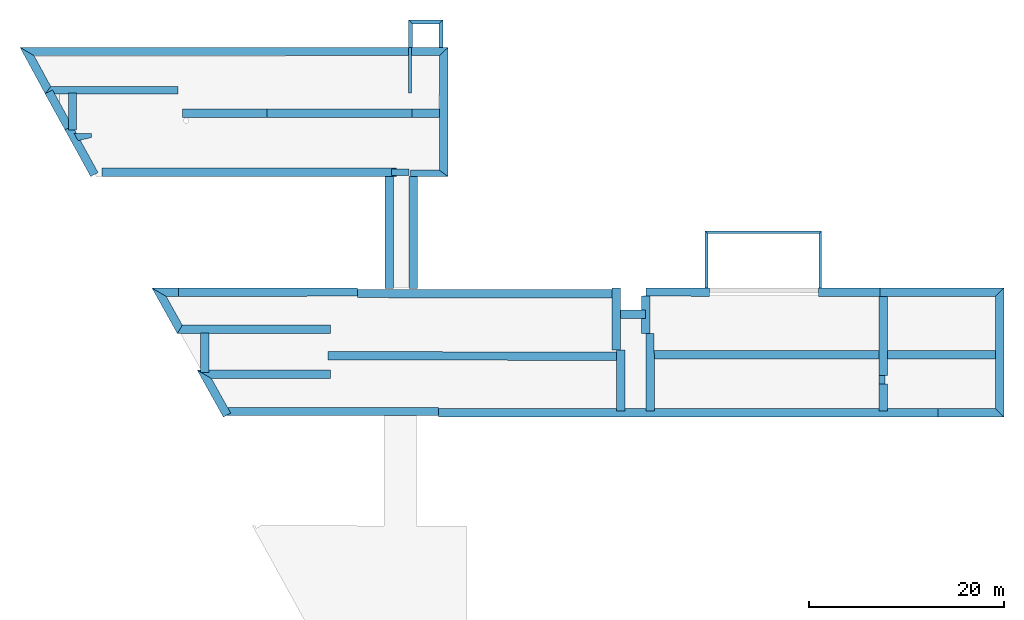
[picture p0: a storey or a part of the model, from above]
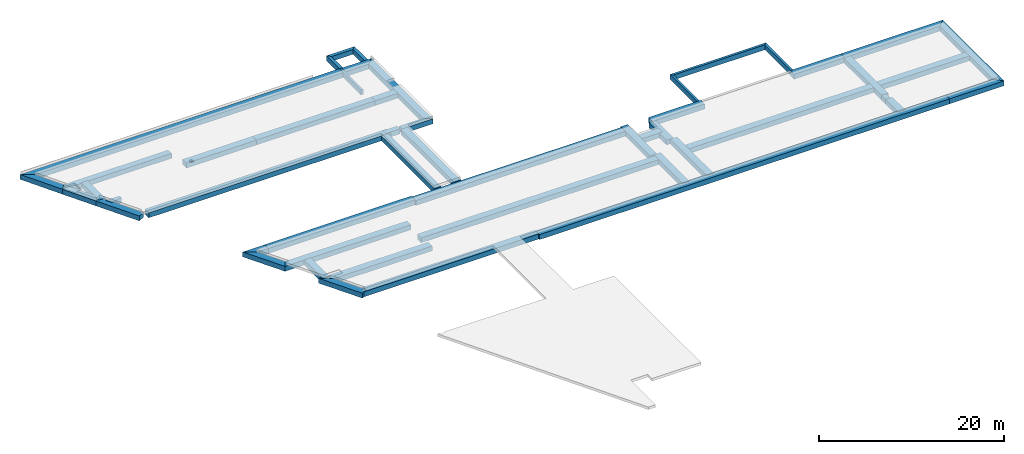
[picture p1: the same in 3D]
Properties of the parts of a building model (IFC2X3), part 1 of 14

# File
Description: ViewDefinition [CoordinationView_V2.0], Option [Drawing Scale: 100.000000], Option [Global Unique Identifiers (GUID): Keep existing], Option [Elements to export: Visible elements (on all stories)], Option [Partial Structure Display: Entire Model], Option [IFC Domain: All], Option [Structural Function: All Elements], Option [Convert Grid elements: On], Option [Convert IFC Annotations and ARCHICAD 2D elements: Off], Option [Convert 2D symbols of Doors and Windows: Off], Option [Explode Composite and Complex Profile elements into parts: On], Option [Export geometries that Participates in Collision Detection only: Off], Option [Elements in Solid Element Operations: Extruded/revolved], Option [Elements with junctions: Extruded/revolved without junctions], Option [Slabs with slanted edge(s): Extruded], Option [Use legacy geometric methods as in Coordination View 1.0: Off], Option [IFC Site Geometry: As boundary representation (BRep)], Option [IFC Site Location: At Project Origin], Option [Curtain Wall export mode: Container Element], Option [Railing export mode: Single Element], Option [Stair export mode: Container Element], Option [Properties To Export: All properties], Option [Space containment: Off], Option [Bounding Box: Off], Option [Geometry to type objects: Off], Option [Element Properties: Off], Option [Building Material Properties: Off], Option [Element Parameters: Off], Option [Component Parameters: Off], Option [IFC Base Quantities: Off], Option [Door Window Parameters: On], Option [IFC Space boundaries: Off], Option [ARCHICAD Zone Categories as IFC Space classification data: Off], Option [Element Classifications: Off]
File name: G:\Shared drives\Projektibüroo\Irina\Teaduse 2\Teaduse 2 Alice, Jane, Irina\EMAFAIL\ifc\AR_Teaduse2_PP_2020-01-23_AP.ifc
Time: 2020-01-24T13:08:55
Author: Architect
Organization: Building Designer Office
Written by: The EXPRESS Data Manager Version 5.02.0100.09 : 26 Sep 2013
Made in: IFC file generated by GRAPHISOFT ARCHICAD-64 22.0.0 INT FULL Windows version (IFC add-on version: 6021 INT FULL).
Authorization: The authorising person

# IfcSite, Site
RefLatitude: 47, 33, 34, 948800; RefLongitude: 19, 3, 17, 204400; RefElevation: 0 mm

# IfcBuildingStorey (4)
In: Building
Name | Elevation (mm)
VUNDAMENT | -1000
1 KORRUS | 0
2 KORRUS | 3000
KATUSEPLAAN | 6000 | Description: talveaia rõdu

# IfcSpace: TEHNOPIND (10)
Type - ElementType: Element type TEHNILINE RUUM
InteriorOrExteriorSpace: INTERNAL; Classification: 1.15 IfcSpace (ruum) (_RKAS BIM + ARCHICAD Classification)
Pset_SpaceCommon - Category: TEHNOPIND
RUUMID - 3 Kategooria: TEHNOPIND
AC_Pset_RenovationAndPhasing - Renovation Status: Existing
Name | In | LongName = 1 Nimetus | 2 Number | 4 Ruumi pindala | 5 Ruumi kõrgus
B 109 | 1 KORRUS | SOOJASÕLM | B 109 | 33,69 Kasulik pindala: 33,69 | 2 600
B 124 | 1 KORRUS | TEHNILINE RUUM | B 124 | 21,63 Kasulik pindala: 21,63 | 2 600
A 103 | 1 KORRUS | SERVERIRUUM | A 103 | 9,76 Kasulik pindala: 9,76 | 2 600
A 115 | 1 KORRUS | TEHNILINE RUUM | A 115 | 17,16 Kasulik pindala: 17,16 | 2 600
A 112 | 1 KORRUS | ELEKTRIKILBIRUUM | A 112 | 10,49 Kasulik pindala: 10,49 | 2 600
B 114 | 1 KORRUS | ELEKTRIKILBI RUUM | B 114 | 15,64 Kasulik pindala: 15,64 | 2 600
B 115 | 1 KORRUS | TEHNILINE RUUM | B 115 | 20,53 Kasulik pindala: 20,53 | 2 600
B 220B | 2 KORRUS | SERVERIRUUM | B 220B | 8,12 Kasulik pindala: 8,12 | 2 480
C 210 | 2 KORRUS | TEHNILINE RUUM | C 210 | 16,56 Kasulik pindala: 16,56 | 3 250
B 220A | 2 KORRUS | TEHNILINE RUUM | B 220A | 7,12 Kasulik pindala: 7,12 | 2 480

# IfcSpace: ÜLDKASUT.P, B 127
In: 1 KORRUS
Type - ElementType: Element type TEHNILINE RUUM
LongName: ABIRUUM; InteriorOrExteriorSpace: INTERNAL; Classification: 1.15 IfcSpace (ruum) (_RKAS BIM + ARCHICAD Classification)
Pset_SpaceCommon - Category: ÜLDKASUT.P
RUUMID - 1 Nimetus: ABIRUUM; 2 Number: B 127; 3 Kategooria: ÜLDKASUT.P; 4 Ruumi pindala: 7,08 Kasulik pindala: 7,08; 5 Ruumi kõrgus: 2 600
AC_Pset_RenovationAndPhasing - Renovation Status: Existing

# IfcSpace: ÜLDKASUT.P (17)
In: 1 KORRUS
Type - ElementType: Element type ÜLDKASUTATAV PIND
InteriorOrExteriorSpace: INTERNAL; Classification: 1.15 IfcSpace (ruum) (_RKAS BIM + ARCHICAD Classification)
Pset_SpaceCommon - Category: ÜLDKASUT.P
RUUMID - 3 Kategooria: ÜLDKASUT.P; 5 Ruumi kõrgus: 2 600
AC_Pset_RenovationAndPhasing - Renovation Status: Existing
Name | LongName = 1 Nimetus | 2 Number | 4 Ruumi pindala
B 134 | KONTOR | B 134 | 10,28 Kasulik pindala: 10,28
B 131 B | ABIRUUM | B 131 B | 8,30 Kasulik pindala: 8,30
B 130 | DOKUMENDI HOIDLA | B 130 | 20,70 Kasulik pindala: 20,70
B 131 | ABIRUUM | B 131 | 81,94 Kasulik pindala: 81,94
B 137 | KORIDOR | B 137 | 51,83 Kasulik pindala: 51,83
B 136 | KONTOR | B 136 | 31,18 Kasulik pindala: 31,16
B 125 A | HOIURUUM | B 125 A | 2,96 Kasulik pindala: 2,96
B 125 | ABIRUUM | B 125 | 17,33 Kasulik pindala: 17,33
B 128 | ABIRUUM | B 128 | 13,31 Kasulik pindala: 13,31
B 135 | TUULEKODA | B 135 | 17,22 Kasulik pindala: 17,22
B 129 | KORIDOR | B 129 | 7,62 Kasulik pindala: 7,62
B 132 | KONTOR | B 132 | 21,03 Kasulik pindala: 21,03
B 131 A | ABIRUUM | B 131 A | 7,00 Kasulik pindala: 7,00
B 126 A | WC | B 126 A | 2,78 Kasulik pindala: 2,05
B 126 B | PESURUUM | B 126 B | 1,95 Kasulik pindala: 1,54
B 126 | EESRUUM | B 126 | 5,29 Kasulik pindala: 5,29
B 133 | DOKUMENDI HOIDLA | B 133 | 16,16 Kasulik pindala: 16,16

# IfcSpace: ÜLDKASUT.P. PÕLLUMANDUSAMET (97)
Type - ElementType: Element type ÜLDKASUTATAV PIND
InteriorOrExteriorSpace: INTERNAL; Classification: 1.15 IfcSpace (ruum) (_RKAS BIM + ARCHICAD Classification)
Pset_SpaceCommon - Category: ÜLDKASUT.P. PÕLLUMANDUSAMET
RUUMID - 3 Kategooria: ÜLDKASUT.P. PÕLLUMANDUSAMET
AC_Pset_RenovationAndPhasing - Renovation Status: Existing
Name | In | LongName = 1 Nimetus | 2 Number | 4 Ruumi pindala | 5 Ruumi kõrgus
B 122 | 1 KORRUS | TREPIKODA | B 122 | 9,22 Kasulik pindala: 9,22 | 2 600
B 121 | 1 KORRUS | SÖÖGITUBA | B 121 | 30,12 Kasulik pindala: 30,12 | 2 600
A 111 | 1 KORRUS | DOKUMENDI HOIDLA | A 111 | 42,20 Kasulik pindala: 42,20 | 2 150
A 117 | 1 KORRUS | KORIDOR | A 117 | 10,09 Kasulik pindala: 10,09 | 2 150
A 116 | 1 KORRUS | DOKUMENDI HOIDLA | A 116 | 21,51 Kasulik pindala: 21,51 | 2 150
B 120 B | 1 KORRUS | ABIRUUM | B 120 B | 3,78 Kasulik pindala: 3,78 | 2 600
B 104 A | 1 KORRUS | WC | B 104 A | 1,36 Kasulik pindala: 1,36 | 2 600
B 106 | 1 KORRUS | DOKUMENDI HOIDLA | B 106 | 9,84 Kasulik pindala: 9,84 | 2 600
B 108 | 1 KORRUS | KABINET | B 108 | 21,66 Kasulik pindala: 21,66 | 2 600
B 103 | 1 KORRUS | ABIRUUM | B 103 | 15,57 Kasulik pindala: 15,57 | 2 600
B 107 A | 1 KORRUS | TUULEKODA | B 107 A | 5,19 Kasulik pindala: 5,19 | 2 600
B 105 | 1 KORRUS | WC | B 105 | 5,30 Kasulik pindala: 5,30 | 2 600
B 102 | 1 KORRUS | KABINET | B 102 | 9,67 Kasulik pindala: 9,67 | 2 600
B 113 | 1 KORRUS | DOKUMENDIHOIDLA | B 113 | 15,71 Kasulik pindala: 15,71 | 2 600
B 112 | 1 KORRUS | ABIRUUM | B 112 | 16,44 Kasulik pindala: 16,44 | 2 600
B 117 | 1 KORRUS | ABIRUUM | B 117 | 15,69 Kasulik pindala: 15,69 | 2 600
B 118 | 1 KORRUS | ABIRUUM | B 118 | 15,68 Kasulik pindala: 15,68 | 2 600
B 120 A | 1 KORRUS | DOKUMENDI HOIDLA | B 120 A | 9,08 Kasulik pindala: 9,08 | 2 600
B 120 C | 1 KORRUS | ABIRUUM | B 120 C | 4,97 Kasulik pindala: 4,97 | 2 600
B 116 | 1 KORRUS | DOKUMENDI HOIDLA | B 116 | 10,21 Kasulik pindala: 10,21 | 2 600
B 119 | 1 KORRUS | DOKUMENDI HOIDLA | B 119 | 10,04 Kasulik pindala: 10,04 | 2 600
B 123 | 1 KORRUS | DOKUMENDI HOIDLA | B 123 | 26,10 Kasulik pindala: 26,10 | 2 600
B 104 | 1 KORRUS | WC | B 104 | 4,18 Kasulik pindala: 3,46 | 2 600
B 120 | 1 KORRUS | DOKUMENDI HOIDLA | B 120 | 10,02 Kasulik pindala: 10,02 | 2 600
B 138 | 1 KORRUS | KORIDOR | B 138 | 18,87 Kasulik pindala: 18,87 | 2 150
B 108 | 1 KORRUS | KORIDOR | B 108 | 70,52 Kasulik pindala: 70,52 | 2 600
B 108 A | 1 KORRUS | DOKUMENDI HOIDLA | B 108 A | 19,27 Kasulik pindala: 19,27 | 2 600
B 202 | 2 KORRUS | KABINET | B 202 | 10,94 Kasulik pindala: 10,94 | 2 480
B 219 | 2 KORRUS | KABINET | B 219 | 10,00 Kasulik pindala: 10,00 | 2 480
B 216 | 2 KORRUS | KABINET | B 216 | 18,40 Kasulik pindala: 17,33 | 2 480
B 245 | 2 KORRUS | GARAAZ | B 245 | 67,66 Kasulik pindala: 67,66 | 3 250
B 240 | 2 KORRUS | KABINET | B 240 | 11,86 Kasulik pindala: 11,86 | 2 480
B 241 | 2 KORRUS | KABINET | B 241 | 10,72 Kasulik pindala: 10,72 | 2 480
B 235 | 2 KORRUS | KABINET | B 235 | 15,40 Kasulik pindala: 15,40 | 2 480
A 222 | 2 KORRUS | KABINET | A 222 | 18,00 Kasulik pindala: 18,00 | 2 500
C 206 | 2 KORRUS | SAAL | C 206 | 82,63 Kasulik pindala: 82,63 | 3 250
C 201 | 2 KORRUS | KABINET | C 201 | 10,82 Kasulik pindala: 10,82 | 3 250
C 202 | 2 KORRUS | KABINET | C 202 | 12,87 Kasulik pindala: 12,87 | 3 250
B 231 A | 2 KORRUS | EESRUUM | B 231 A | 5,70 Kasulik pindala: 5,70 | 2 200
B 231 C | 2 KORRUS | WC | B 231 C | 1,20 Kasulik pindala: 1,20 | 2 200
B 223 | 2 KORRUS | KABINET | B 223 | 14,83 Kasulik pindala: 14,83 | 2 480
B 222 | 2 KORRUS | KABINET | B 222 | 15,67 Kasulik pindala: 15,67 | 2 480
B 206 | 2 KORRUS | KABINET | B 206 | 22,80 Kasulik pindala: 22,80 | 2 480
B 207 | 2 KORRUS | KABINET | B 207 | 9,95 Kasulik pindala: 9,95 | 2 480
B 221 | 2 KORRUS | KABINET | B 221 | 20,30 Kasulik pindala: 20,30 | 2 480
B 201 | 2 KORRUS | KABINET | B 201 | 8,94 Kasulik pindala: 8,94 | 2 480
B 203 | 2 KORRUS | KABINET | B 203 | 9,68 Kasulik pindala: 9,68 | 2 480
B 208 | 2 KORRUS | KABINET | B 208 | 9,95 Kasulik pindala: 9,95 | 2 480
B 217 | 2 KORRUS | KABINET | B 217 | 17,99 Kasulik pindala: 17,99 | 2 480
B 211 | 2 KORRUS | KABINET | B 211 | 19,43 Kasulik pindala: 19,43 | 2 480
B 224 | 2 KORRUS | KABINET | B 224 | 14,60 Kasulik pindala: 14,60 | 2 480
B 215 | 2 KORRUS | KABINET | B 215 | 11,14 Kasulik pindala: 11,14 | 2 480
B 236 | 2 KORRUS | KABINET | B 236 | 15,41 Kasulik pindala: 15,41 | 2 480
A 207 | 2 KORRUS | KORIDOR | A 207 | 50,99 Kasulik pindala: 50,99 | 2 300
B 205 | 2 KORRUS | KABINET | B 205 | 9,96 Kasulik pindala: 9,96 | 2 480
A 211 | 2 KORRUS | KABINET | A 211 | 15,58 Kasulik pindala: 15,58 | 2 500
A 217 | 2 KORRUS | KABINET | A 217 | 15,59 Kasulik pindala: 15,59 | 2 500
A 215 | 2 KORRUS | KABINET | A 215 | 15,60 Kasulik pindala: 15,60 | 2 500
A 218 | 2 KORRUS | KABINET | A 218 | 10,34 Kasulik pindala: 10,34 | 2 480
C 208 | 2 KORRUS | INVA WC | C 208 | 7,31 Kasulik pindala: 7,31 | 2 400
A 221 | 2 KORRUS | KABINET | A 221 | 20,25 Kasulik pindala: 20,25 | 3 250
A 209 C | 2 KORRUS | KABINET | A 209 C | 16,92 Kasulik pindala: 16,92 | 2 500
A 209 A | 2 KORRUS | EESRUUM | A 209 A | 2,23 Kasulik pindala: 2,23 | 2 500
A 202 | 2 KORRUS | KABINET | A 202 | 9,72 Kasulik pindala: 9,72 | 2 480
A 209 B | 2 KORRUS | KABINET | A 209 B | 9,55 Kasulik pindala: 9,55 | 2 500
A 201 | 2 KORRUS | KABINET | A 201 | 8,98 Kasulik pindala: 8,98 | 2 480
B 212 | 2 KORRUS | KABINET | B 212 | 31,14 Kasulik pindala: 31,14 | 2 480
B 225 | 2 KORRUS | KABINET | B 225 | 10,45 Kasulik pindala: 10,45 | 2 480
B 231 B | 2 KORRUS | WC | B 231 B | 1,21 Kasulik pindala: 1,21 | 2 200
B 232 | 2 KORRUS | PESURUUM | B 232 | 6,54 Kasulik pindala: 6,54 | 2 200
B 204 | 2 KORRUS | KABINET | B 204 | 17,58 Kasulik pindala: 17,58 | 2 480
A 204 | 2 KORRUS | KABINET | A 204 | 27,06 Kasulik pindala: 27,06 | 2 480
A 219 | 2 KORRUS | KABINET | A 219 | 19,11 Kasulik pindala: 19,11 | 2 480
A 203 | 2 KORRUS | KABINET | A 203 | 23,26 Kasulik pindala: 23,26 | 2 480
A 223 | 2 KORRUS | TUULEKODA | A 223 | 3,76 Kasulik pindala: 3,76 | 3 250
A 213 | 2 KORRUS | KABINET | A 213 | 15,59 Kasulik pindala: 15,59 | 2 500
A 216 | 2 KORRUS | KABINET | A 216 | 10,35 Kasulik pindala: 10,35 | 2 480
A 214 | 2 KORRUS | KABINET | A 214 | 10,32 Kasulik pindala: 10,32 | 2 480
A 212 | 2 KORRUS | KABINET | A 212 | 10,33 Kasulik pindala: 10,33 | 2 480
A 210 | 2 KORRUS | KABINET | A 210 | 10,33 Kasulik pindala: 10,33 | 2 480
A 208 | 2 KORRUS | KABINET | A 208 | 10,34 Kasulik pindala: 10,34 | 2 480
A 206 | 2 KORRUS | KABINET | A 206 | 8,97 Kasulik pindala: 8,97 | 2 480
A 205 | 2 KORRUS | KABINET | A 205 | 27,67 Kasulik pindala: 19,98 | 2 480
C 203 | 2 KORRUS | KABINET | C 203 | 12,91 Kasulik pindala: 12,91 | 3 250
B 243 | 2 KORRUS | KABINET | B 243 | 11,86 Kasulik pindala: 11,86 | 2 480
C 204 | 2 KORRUS | KABINET | C 204 | 27,10 Kasulik pindala: 27,10 | 3 250
C 209 | 2 KORRUS | WC | C 209 | 4,99 Kasulik pindala: 4,99 | 2 400
B 218 | 2 KORRUS | NÕUPIDAMISTE RUUM | B 218 | 32,18 Kasulik pindala: 32,18 | 2 480
B 210 | 2 KORRUS | KABINET | B 210 | 15,46 Kasulik pindala: 15,46 | 2 480
A 220 | 2 KORRUS | KABINET | A 220 | 10,52 Kasulik pindala: 10,52 | 2 480
C 207 | 2 KORRUS | EESRUUM | C 207 | 12,78 Kasulik pindala: 12,78 | 2 600
B 246 | 2 KORRUS | ABIRUUM | B 246 | 32,62 Kasulik pindala: 32,62 | 3 250
B 230 | 2 KORRUS | KABINET | B 230 | 31,59 Kasulik pindala: 31,59 | 2 480
C 205 | 2 KORRUS | KABINET | C 205 | 12,18 Kasulik pindala: 12,18 | 3 250
C 200 | 2 KORRUS | KORIDOR | C 200 | 38,18 Kasulik pindala: 38,18 | 3 250
A 200 | 2 KORRUS | FUAJEE/ TREPIKODA | A 200 | 50,56 Kasulik pindala: 50,56 | 3 250
B 229 | 2 KORRUS | SUITSETAMISERUUM | B 229 | 17,80 Kasulik pindala: 17,70 | 4 300

# IfcSpace: ÜLDKASUT.P. PÕLLUMANDUSAMET JA PRIA (2)
In: 1 KORRUS
Type - ElementType: Element type TEHNILINE RUUM
InteriorOrExteriorSpace: INTERNAL; Classification: 1.15 IfcSpace (ruum) (_RKAS BIM + ARCHICAD Classification)
Pset_SpaceCommon - Category: ÜLDKASUT.P. PÕLLUMANDUSAMET JA PRIA
RUUMID - 3 Kategooria: ÜLDKASUT.P. PÕLLUMANDUSAMET JA PRIA; 5 Ruumi kõrgus: 2 600
AC_Pset_RenovationAndPhasing - Renovation Status: Existing
Name | LongName = 1 Nimetus | 2 Number | 4 Ruumi pindala
B 110 | KORISTAJARUUM | B 110 | 10,70 Kasulik pindala: 10,70
B 111 | ABIRUUM | B 111 | 5,56 Kasulik pindala: 5,56

# IfcSpace: ÜLDKASUT.P. PÕLLUMANDUSAMET JA PRIA (10)
In: 1 KORRUS
Type - ElementType: Element type ÜLDKASUTATAV PIND
InteriorOrExteriorSpace: INTERNAL; Classification: 1.15 IfcSpace (ruum) (_RKAS BIM + ARCHICAD Classification)
Pset_SpaceCommon - Category: ÜLDKASUT.P. PÕLLUMANDUSAMET JA PRIA
RUUMID - 3 Kategooria: ÜLDKASUT.P. PÕLLUMANDUSAMET JA PRIA
AC_Pset_RenovationAndPhasing - Renovation Status: Existing
Name | LongName = 1 Nimetus | 2 Number | 4 Ruumi pindala | 5 Ruumi kõrgus
A 104 | WC | A 104 | 5,45 Kasulik pindala: 5,45 | 2 300
A 118 | KORIDOR | A 118 | 38,91 Kasulik pindala: 38,91 | 2 550
A100 | TUULEKODA | A100 | 5,50 Kasulik pindala: 5,50 | 2 200
A 114 | KORIDOR | A 114 | 17,73 Kasulik pindala: 17,73 | 2 600
A 108 A | PESURUUM | A 108 A | 8,91 Kasulik pindala: 8,91 | 2 150
A 108 | PUHKERUUM | A 108 | 42,24 Kasulik pindala: 42,24 | 2 150
A 105 | WC | A 105 | 4,79 Kasulik pindala: 4,79 | 2 300
A 108 C | PESURUUM | A 108 C | 5,65 Kasulik pindala: 5,65 | 2 150
A 108 B | LEILIRUUM | A 108 B | 5,45 Kasulik pindala: 5,45 | 2 300
A 101 | AATRIUM/FUAJEE | A 101 | 40,64 Kasulik pindala: 40,64 | 2 550

# IfcSpace: ÜLDKASUT.P.PRIA (6)
In: 1 KORRUS
Type - ElementType: Element type ÜLDKASUTATAV PIND
InteriorOrExteriorSpace: INTERNAL; Classification: 1.15 IfcSpace (ruum) (_RKAS BIM + ARCHICAD Classification)
Pset_SpaceCommon - Category: ÜLDKASUT.P.PRIA
RUUMID - 3 Kategooria: ÜLDKASUT.P.PRIA
AC_Pset_RenovationAndPhasing - Renovation Status: Existing
Name | LongName = 1 Nimetus | 2 Number | 4 Ruumi pindala | 5 Ruumi kõrgus
A 110 | KABINET | A 110 | 10,36 Kasulik pindala: 10,36 | 2 150
A 109 | KABINET | A 109 | 21,30 Kasulik pindala: 21,30 | 2 150
A 113 | KABINET | A 113 | 14,13 Kasulik pindala: 14,13 | 2 150
A 106 | KABINET | A 106 | 9,29 Kasulik pindala: 9,29 | 2 300
A 102 | OOTERUUM | A 102 | 34,41 Kasulik pindala: 34,41 | 2 150
A 107 | PUHKERUUM | A 107 | 10,37 Kasulik pindala: 10,37 | 2 150

# IfcSpace: ÜLDKASUTATAV PIND (17)
Type - ElementType: Element type ÜLDKASUTATAV PIND
InteriorOrExteriorSpace: INTERNAL; Classification: 1.15 IfcSpace (ruum) (_RKAS BIM + ARCHICAD Classification)
Pset_SpaceCommon - Category: ÜLDKASUTATAV PIND
RUUMID - 3 Kategooria: ÜLDKASUTATAV PIND
AC_Pset_RenovationAndPhasing - Renovation Status: Existing
Name | In | LongName = 1 Nimetus | 2 Number | 4 Ruumi pindala | 5 Ruumi kõrgus
B 101 | 1 KORRUS | AATRIUM/FUAJEE | B 101 | 57,46 Kasulik pindala: 57,46 | 2 600
B 100 | 1 KORRUS | TUULEKODA | B 100 | 5,80 Kasulik pindala: 5,80 | 2 600
B 233 B | 2 KORRUS | WC | B 233 B | 1,38 Kasulik pindala: 1,38 | 2 200
B 244 | 2 KORRUS | KABINET | B 244 | 15,41 Kasulik pindala: 15,41 | 2 480
B 238 | 2 KORRUS | TREPIKODA | B 238 | 5,77 Kasulik pindala: 5,77 | 2 240
B 242 | 2 KORRUS | KORIDOR | B 242 | 3,10 Kasulik pindala: 3,10 | 2 600
B 234 | 2 KORRUS | PESURUUM | B 234 | 6,58 Kasulik pindala: 6,58 | 2 200
B 237 | 2 KORRUS | TALVEAED | B 237 | 67,64 Kasulik pindala: 67,64 | 4 300
B 209 | 2 KORRUS | KORIDOR | B 209 | 11,18 Kasulik pindala: 11,18 | 2 300
B 227 | 2 KORRUS | KORIDOR | B 227 | 13,24 Kasulik pindala: 13,24 | 3 250
B 200 | 2 KORRUS | FUAJEE/ TREPIKODA | B 200 | 54,93 Kasulik pindala: 54,93 | 3 250
B 214 | 2 KORRUS | KORIDOR | B 214 | 36,21 Kasulik pindala: 36,21 | 2 300
B 239 | 2 KORRUS | KORIDOR | B 239 | 6,10 Kasulik pindala: 6,10 | 2 600
B 213 | 2 KORRUS | KORIDOR | B 213 | 72,33 Kasulik pindala: 72,33 | 2 600
B 228 | 2 KORRUS | KORIDOR | B 228 | 34,03 Kasulik pindala: 34,03 | 2 300
B 226 | 2 KORRUS | TUULEKODA | B 226 | 3,29 Kasulik pindala: 3,29 | 3 250
B 233 A | 2 KORRUS | WC | B 233 A | 6,80 Kasulik pindala: 6,80 | 2 200

# IfcBeam: Betoon olemas olev tala (4)
In: 2 KORRUS
Type - ElementType: Element type Betoon olemas olev tala
Description: betoon tala; Classification: 1.1 IfcBeam (tala) (_RKAS BIM + ARCHICAD Classification); Material: Betoon (1)
Ehituskonstruktsioonid - 01 Nimetus: Betoon (1); 02 Materjal: Betoon (1); 03 Tähistus või ristlõige: Betoon olemas olev tala; 11 Ülemine kõrgusmärk: 6 250; 12 Alumine kõrgusmärk: 6 250 - Tala paksus 412
AC_Pset_RenovationAndPhasing - Renovation Status: Existing
Pset_BeamCommon - LoadBearing: yes; IsExternal: no; Reference: Betoon (1) 420 x 412
Name | 06 Maht (kubatuur)
2 x Betoon (1) | 1,39
Betoon (1) | 0,97
Betoon (1) | 0,93

# IfcBeam: IPE 120 (25)
In: KATUSEPLAAN
Type - ElementType: Element type IPE 120
Description: terastala; Classification: 41 Klaasfassaadid, vitriinid ja eriaknad (EHITUSKULUDE LIIGITAMINE EVS 885:2005); 1.1 IfcBeam (tala) (_RKAS BIM + ARCHICAD Classification); Material: Teras (1)
Ehituskonstruktsioonid - 01 Nimetus: I Joist - Steel; 02 Materjal: Teras (1); 03 Tähistus või ristlõige: IPE 120; 06 Maht (kubatuur): 0,01
Pset_BeamCommon - LoadBearing: yes; IsExternal: no; Reference: I Joist - Steel 64 x 120
Name | 11 Ülemine kõrgusmärk | 12 Alumine kõrgusmärk | Renovation Status
8 x I Joist - Steel | 6 712 | 6 712 - Tala paksus 120 | Existing
10 x I Joist - Steel | 6 712 | 6 712 - Tala paksus 120 | New
I Joist - Steel | 6 700 | 6 700 - Tala paksus 120 | Existing
4 x I Joist - Steel | 6 700 | 6 700 - Tala paksus 120 | New
2 x I Joist - Steel | 6 708 | 6 708 - Tala paksus 120 | New

# IfcBuildingElementPart (311)
Name | In | Material
9 x Alumiinium (1) | 1 KORRUS | Alumiinium (1)
9 x Klaas (1) | 1 KORRUS | Klaas (1)
9 x Teras - Roostevaba (1) | 1 KORRUS | Teras - Roostevaba (1)
19 x Kivi - Ol.Olev Konstruktsioon | 1 KORRUS | Kivi - Ol.Olev Konstruktsioon
19 x Soojustus - Plastik Kõva | 1 KORRUS | Soojustus - Plastik Kõva
6 x Kivi - Viimistlus | 1 KORRUS | Kivi - Viimistlus
13 x Krohv - Õhekrohv | 1 KORRUS | Krohv - Õhekrohv
TELLIS SOOJUSTUSEGA | 1 KORRUS | TELLIS SOOJUSTUSEGA
Betoon (1) | 1 KORRUS | Betoon (1)
TERAS, valge copy | 1 KORRUS | TERAS, valge copy
6 x Air Space | 1 KORRUS | Air Space
10 x Puitplaat | 1 KORRUS | Puitplaat
27 x Tellis - Konstuktsioon | 2 KORRUS | Tellis - Konstuktsioon
27 x Soojustus - Plastik Kõva | 2 KORRUS | Soojustus - Plastik Kõva
27 x Tellis - Viimistlus | 2 KORRUS | Tellis - Viimistlus
20 x Titaan - Tsink (1) | 2 KORRUS | Titaan - Tsink (1)
Alumiinium (1) | 2 KORRUS | Alumiinium (1)
Klaas (1) | 2 KORRUS | Klaas (1)
Teras - Roostevaba (1) | 2 KORRUS | Teras - Roostevaba (1)
3 x  | 2 KORRUS
45 x Soojustus - Plastik Kõva | KATUSEPLAAN | Soojustus - Plastik Kõva
2 x Soojustus - Mineraal Pehme | KATUSEPLAAN | Soojustus - Mineraal Pehme
20 x Kivi - Ol.Olev Konstruktsioon | KATUSEPLAAN | Kivi - Ol.Olev Konstruktsioon
23 x Tellis - Viimistlus | KATUSEPLAAN | Tellis - Viimistlus
3 x Tellis - Konstuktsioon | KATUSEPLAAN | Tellis - Konstuktsioon
4 x Alumiinium (1) | KATUSEPLAAN | Alumiinium (1)
4 x Klaas (1) | KATUSEPLAAN | Klaas (1)

# IfcBuildingElementProxy: BET.PORAND (2)
In: 1 KORRUS
Type - ElementType: Element type BET.PORAND
Classification: 1.2 IfcBuildingElementProxy (objekt) (_RKAS BIM + ARCHICAD Classification); Material: Betoon - Ol.Olev konstruktsioon
SEADMED - 02 Tähis: BET.PORAND
AC_Pset_RenovationAndPhasing - Renovation Status: Existing

# IfcBuildingElementProxy: BETOON TREPP (7)
Type - ElementType: Element type BETOON TREPP
Material: Betoon - Ol.Olev konstruktsioon
SEADMED - 02 Tähis: BETOON TREPP
Name (Betoon - Ol.Olev konstruktsioon; Objekti nimi:...) | In | Renovation Status
 | 1 KORRUS | New
4 x  | 1 KORRUS | Existing
2 x  | 2 KORRUS | Existing

# IfcBuildingElementProxy: CRE - 012, Betoon (1); Objekti nimi:
In: 1 KORRUS
Type - ElementType: Element type CRE - 012
SEADMED - 02 Tähis: CRE - 012
AC_Pset_RenovationAndPhasing - Renovation Status: Existing

# IfcBuildingElementProxy: FU - 005 (3)
In: 2 KORRUS
Type - ElementType: Element type FU - 005
Classification: 1.2 IfcBuildingElementProxy (objekt) (_RKAS BIM + ARCHICAD Classification)
SEADMED - 02 Tähis: FU - 005
AC_Pset_RenovationAndPhasing - Renovation Status: Existing

# IfcBuildingElementProxy: Frame-Bnd-111, Alumiinium (1); Objekti nimi: Built-in Frame
In: 1 KORRUS
Type - ElementType: Element type Frame-Bnd-111
Material: Alumiinium (1)
SEADMED - 02 Tähis: Frame-Bnd-111
AC_Pset_RenovationAndPhasing - Renovation Status: New

# IfcBuildingElementProxy: Frame-Bnd-112, Alumiinium (1); Objekti nimi: Built-in Frame
In: 1 KORRUS
Type - ElementType: Element type Frame-Bnd-112
Material: Alumiinium (1)
SEADMED - 02 Tähis: Frame-Bnd-112
AC_Pset_RenovationAndPhasing - Renovation Status: New

# IfcBuildingElementProxy: Frame-Bnd-113, Alumiinium (1); Objekti nimi: Built-in Frame
In: 1 KORRUS
Type - ElementType: Element type Frame-Bnd-113
Material: Alumiinium (1)
SEADMED - 02 Tähis: Frame-Bnd-113
AC_Pset_RenovationAndPhasing - Renovation Status: New

# IfcBuildingElementProxy: Frame-Bnd-115, Alumiinium (1); Objekti nimi: Built-in Frame
In: 1 KORRUS
Type - ElementType: Element type Frame-Bnd-115
Material: Alumiinium (1)
SEADMED - 02 Tähis: Frame-Bnd-115
AC_Pset_RenovationAndPhasing - Renovation Status: New

# IfcBuildingElementProxy: Frame-Bnd-116, Alumiinium (1); Objekti nimi: Built-in Frame
In: 1 KORRUS
Type - ElementType: Element type Frame-Bnd-116
Material: Alumiinium (1)
SEADMED - 02 Tähis: Frame-Bnd-116
AC_Pset_RenovationAndPhasing - Renovation Status: New

# IfcBuildingElementProxy: Frame-Bnd-117, Alumiinium (1); Objekti nimi: Built-in Frame
In: 1 KORRUS
Type - ElementType: Element type Frame-Bnd-117
Material: Alumiinium (1)
SEADMED - 02 Tähis: Frame-Bnd-117
AC_Pset_RenovationAndPhasing - Renovation Status: New

# IfcBuildingElementProxy: Frame-Bnd-126 (6)
In: 1 KORRUS
Type - ElementType: Element type Frame-Bnd-126
Material: Alumiinium (1)
SEADMED - 02 Tähis: Frame-Bnd-126
AC_Pset_RenovationAndPhasing - Renovation Status: New

# IfcBuildingElementProxy: Frame-Bnd-134 (6)
In: 1 KORRUS
Type - ElementType: Element type Frame-Bnd-134
Material: Alumiinium (1)
SEADMED - 02 Tähis: Frame-Bnd-134
AC_Pset_RenovationAndPhasing - Renovation Status: New

# IfcBuildingElementProxy: Frame-Bnd-142 (6)
In: 1 KORRUS
Type - ElementType: Element type Frame-Bnd-142
Material: Alumiinium (1)
SEADMED - 02 Tähis: Frame-Bnd-142
AC_Pset_RenovationAndPhasing - Renovation Status: New

# IfcBuildingElementProxy: Frame-Bnd-278, Alumiinium (1); Objekti nimi: Built-in Frame
In: 2 KORRUS
Type - ElementType: Element type Frame-Bnd-278
Material: Alumiinium (1)
SEADMED - 02 Tähis: Frame-Bnd-278
AC_Pset_RenovationAndPhasing - Renovation Status: New

# IfcBuildingElementProxy: Frame-Bnd-279, Alumiinium (1); Objekti nimi: Built-in Frame
In: 2 KORRUS
Type - ElementType: Element type Frame-Bnd-279
Material: Alumiinium (1)
SEADMED - 02 Tähis: Frame-Bnd-279
AC_Pset_RenovationAndPhasing - Renovation Status: New

# IfcBuildingElementProxy: Frame-Bnd-280, Alumiinium (1); Objekti nimi: Built-in Frame
In: 2 KORRUS
Type - ElementType: Element type Frame-Bnd-280
Material: Alumiinium (1)
SEADMED - 02 Tähis: Frame-Bnd-280
AC_Pset_RenovationAndPhasing - Renovation Status: New

# IfcBuildingElementProxy: Frame-Bnd-281, Alumiinium (1); Objekti nimi: Built-in Frame
In: 2 KORRUS
Type - ElementType: Element type Frame-Bnd-281
Material: Alumiinium (1)
SEADMED - 02 Tähis: Frame-Bnd-281
AC_Pset_RenovationAndPhasing - Renovation Status: New

# IfcBuildingElementProxy: Frame-Bnd-282, Alumiinium (1); Objekti nimi: Built-in Frame
In: 2 KORRUS
Type - ElementType: Element type Frame-Bnd-282
Material: Alumiinium (1)
SEADMED - 02 Tähis: Frame-Bnd-282
AC_Pset_RenovationAndPhasing - Renovation Status: New

# IfcBuildingElementProxy: Frame-Bnd-283, Alumiinium (1); Objekti nimi: Built-in Frame
In: 2 KORRUS
Type - ElementType: Element type Frame-Bnd-283
Material: Alumiinium (1)
SEADMED - 02 Tähis: Frame-Bnd-283
AC_Pset_RenovationAndPhasing - Renovation Status: New

# IfcBuildingElementProxy: Frame-Bnd-284, Alumiinium (1); Objekti nimi: Built-in Frame
In: 2 KORRUS
Type - ElementType: Element type Frame-Bnd-284
Material: Alumiinium (1)
SEADMED - 02 Tähis: Frame-Bnd-284
AC_Pset_RenovationAndPhasing - Renovation Status: New

# IfcBuildingElementProxy: Frame-Bnd-285, Alumiinium (1); Objekti nimi: Built-in Frame
In: 2 KORRUS
Type - ElementType: Element type Frame-Bnd-285
Material: Alumiinium (1)
SEADMED - 02 Tähis: Frame-Bnd-285
AC_Pset_RenovationAndPhasing - Renovation Status: New

# IfcBuildingElementProxy: Frame-Bnd-286, Alumiinium (1); Objekti nimi: Built-in Frame
In: 2 KORRUS
Type - ElementType: Element type Frame-Bnd-286
Material: Alumiinium (1)
SEADMED - 02 Tähis: Frame-Bnd-286
AC_Pset_RenovationAndPhasing - Renovation Status: New

# IfcBuildingElementProxy: Frame-Bnd-287, Alumiinium (1); Objekti nimi: Built-in Frame
In: 2 KORRUS
Type - ElementType: Element type Frame-Bnd-287
Material: Alumiinium (1)
SEADMED - 02 Tähis: Frame-Bnd-287
AC_Pset_RenovationAndPhasing - Renovation Status: New

# IfcBuildingElementProxy: Frame-Bnd-288, Alumiinium (1); Objekti nimi: Built-in Frame
In: 2 KORRUS
Type - ElementType: Element type Frame-Bnd-288
Material: Alumiinium (1)
SEADMED - 02 Tähis: Frame-Bnd-288
AC_Pset_RenovationAndPhasing - Renovation Status: New

# IfcBuildingElementProxy: Frame-Bnd-289, Alumiinium (1); Objekti nimi: Built-in Frame
In: 2 KORRUS
Type - ElementType: Element type Frame-Bnd-289
Material: Alumiinium (1)
SEADMED - 02 Tähis: Frame-Bnd-289
AC_Pset_RenovationAndPhasing - Renovation Status: New

# IfcBuildingElementProxy: Frame-Bnd-290, Alumiinium (1); Objekti nimi: Built-in Frame
In: 2 KORRUS
Type - ElementType: Element type Frame-Bnd-290
Material: Alumiinium (1)
SEADMED - 02 Tähis: Frame-Bnd-290
AC_Pset_RenovationAndPhasing - Renovation Status: New

# IfcBuildingElementProxy: Frame-Bnd-291, Alumiinium (1); Objekti nimi: Built-in Frame
In: 2 KORRUS
Type - ElementType: Element type Frame-Bnd-291
Material: Alumiinium (1)
SEADMED - 02 Tähis: Frame-Bnd-291
AC_Pset_RenovationAndPhasing - Renovation Status: New

# IfcBuildingElementProxy: Frame-Bnd-292, Alumiinium (1); Objekti nimi: Built-in Frame
In: 2 KORRUS
Type - ElementType: Element type Frame-Bnd-292
Material: Alumiinium (1)
SEADMED - 02 Tähis: Frame-Bnd-292
AC_Pset_RenovationAndPhasing - Renovation Status: New

# IfcBuildingElementProxy: Frame-Bnd-293, Alumiinium (1); Objekti nimi: Built-in Frame
In: 2 KORRUS
Type - ElementType: Element type Frame-Bnd-293
Material: Alumiinium (1)
SEADMED - 02 Tähis: Frame-Bnd-293
AC_Pset_RenovationAndPhasing - Renovation Status: New

# IfcBuildingElementProxy: Frame-Bnd-294, Alumiinium (1); Objekti nimi: Built-in Frame
In: 2 KORRUS
Type - ElementType: Element type Frame-Bnd-294
Material: Alumiinium (1)
SEADMED - 02 Tähis: Frame-Bnd-294
AC_Pset_RenovationAndPhasing - Renovation Status: New

# IfcBuildingElementProxy: Frame-Bnd-295, Alumiinium (1); Objekti nimi: Built-in Frame
In: 2 KORRUS
Type - ElementType: Element type Frame-Bnd-295
Material: Alumiinium (1)
SEADMED - 02 Tähis: Frame-Bnd-295
AC_Pset_RenovationAndPhasing - Renovation Status: New

# IfcBuildingElementProxy: Frame-Bnd-296, Alumiinium (1); Objekti nimi: Built-in Frame
In: 2 KORRUS
Type - ElementType: Element type Frame-Bnd-296
Material: Alumiinium (1)
SEADMED - 02 Tähis: Frame-Bnd-296
AC_Pset_RenovationAndPhasing - Renovation Status: New

# IfcBuildingElementProxy: Frame-Bnd-297, Alumiinium (1); Objekti nimi: Built-in Frame
In: 2 KORRUS
Type - ElementType: Element type Frame-Bnd-297
Material: Alumiinium (1)
SEADMED - 02 Tähis: Frame-Bnd-297
AC_Pset_RenovationAndPhasing - Renovation Status: New

# IfcBuildingElementProxy: Frame-Bnd-298, Alumiinium (1); Objekti nimi: Built-in Frame
In: 2 KORRUS
Type - ElementType: Element type Frame-Bnd-298
Material: Alumiinium (1)
SEADMED - 02 Tähis: Frame-Bnd-298
AC_Pset_RenovationAndPhasing - Renovation Status: New

# IfcBuildingElementProxy: Frame-Bnd-299, Alumiinium (1); Objekti nimi: Built-in Frame
In: 2 KORRUS
Type - ElementType: Element type Frame-Bnd-299
Material: Alumiinium (1)
SEADMED - 02 Tähis: Frame-Bnd-299
AC_Pset_RenovationAndPhasing - Renovation Status: New

# IfcBuildingElementProxy: Frame-Bnd-300, Alumiinium (1); Objekti nimi: Built-in Frame
In: 2 KORRUS
Type - ElementType: Element type Frame-Bnd-300
Material: Alumiinium (1)
SEADMED - 02 Tähis: Frame-Bnd-300
AC_Pset_RenovationAndPhasing - Renovation Status: New

# IfcBuildingElementProxy: Frame-Bnd-301, Alumiinium (1); Objekti nimi: Built-in Frame
In: 2 KORRUS
Type - ElementType: Element type Frame-Bnd-301
Material: Alumiinium (1)
SEADMED - 02 Tähis: Frame-Bnd-301
AC_Pset_RenovationAndPhasing - Renovation Status: New

# IfcBuildingElementProxy: Frame-Bnd-302, Alumiinium (1); Objekti nimi: Built-in Frame
In: 2 KORRUS
Type - ElementType: Element type Frame-Bnd-302
Material: Alumiinium (1)
SEADMED - 02 Tähis: Frame-Bnd-302
AC_Pset_RenovationAndPhasing - Renovation Status: New

# IfcBuildingElementProxy: Frame-Bnd-303, Alumiinium (1); Objekti nimi: Built-in Frame
In: 2 KORRUS
Type - ElementType: Element type Frame-Bnd-303
Material: Alumiinium (1)
SEADMED - 02 Tähis: Frame-Bnd-303
AC_Pset_RenovationAndPhasing - Renovation Status: New

# IfcBuildingElementProxy: Frame-Bnd-306, Alumiinium (1); Objekti nimi: Built-in Frame
In: 2 KORRUS
Type - ElementType: Element type Frame-Bnd-306
Material: Alumiinium (1)
SEADMED - 02 Tähis: Frame-Bnd-306
AC_Pset_RenovationAndPhasing - Renovation Status: New

# IfcBuildingElementProxy: Frame-Bnd-307, Alumiinium (1); Objekti nimi: Built-in Frame
In: 2 KORRUS
Type - ElementType: Element type Frame-Bnd-307
Material: Alumiinium (1)
SEADMED - 02 Tähis: Frame-Bnd-307
AC_Pset_RenovationAndPhasing - Renovation Status: New

# IfcBuildingElementProxy: Frame-Bnd-308, Alumiinium (1); Objekti nimi: Built-in Frame
In: 2 KORRUS
Type - ElementType: Element type Frame-Bnd-308
Material: Alumiinium (1)
SEADMED - 02 Tähis: Frame-Bnd-308
AC_Pset_RenovationAndPhasing - Renovation Status: New

# IfcBuildingElementProxy: Frame-Bnd-309, Alumiinium (1); Objekti nimi: Built-in Frame
In: 2 KORRUS
Type - ElementType: Element type Frame-Bnd-309
Material: Alumiinium (1)
SEADMED - 02 Tähis: Frame-Bnd-309
AC_Pset_RenovationAndPhasing - Renovation Status: New

# IfcBuildingElementProxy: Frame-Bnd-310, Alumiinium (1); Objekti nimi: Built-in Frame
In: 2 KORRUS
Type - ElementType: Element type Frame-Bnd-310
Material: Alumiinium (1)
SEADMED - 02 Tähis: Frame-Bnd-310
AC_Pset_RenovationAndPhasing - Renovation Status: New

# IfcBuildingElementProxy: Frame-Bnd-311, Alumiinium (1); Objekti nimi: Built-in Frame
In: 2 KORRUS
Type - ElementType: Element type Frame-Bnd-311
Material: Alumiinium (1)
SEADMED - 02 Tähis: Frame-Bnd-311
AC_Pset_RenovationAndPhasing - Renovation Status: New

# IfcBuildingElementProxy: Frame-Bnd-312, Alumiinium (1); Objekti nimi: Built-in Frame
In: 2 KORRUS
Type - ElementType: Element type Frame-Bnd-312
Material: Alumiinium (1)
SEADMED - 02 Tähis: Frame-Bnd-312
AC_Pset_RenovationAndPhasing - Renovation Status: New

# IfcBuildingElementProxy: Frame-Bnd-313, Alumiinium (1); Objekti nimi: Built-in Frame
In: 2 KORRUS
Type - ElementType: Element type Frame-Bnd-313
Material: Alumiinium (1)
SEADMED - 02 Tähis: Frame-Bnd-313
AC_Pset_RenovationAndPhasing - Renovation Status: New

# IfcBuildingElementProxy: Frame-Bnd-314, Alumiinium (1); Objekti nimi: Built-in Frame
In: 2 KORRUS
Type - ElementType: Element type Frame-Bnd-314
Material: Alumiinium (1)
SEADMED - 02 Tähis: Frame-Bnd-314
AC_Pset_RenovationAndPhasing - Renovation Status: New

# IfcBuildingElementProxy: Frame-Bnd-315, Alumiinium (1); Objekti nimi: Built-in Frame
In: 2 KORRUS
Type - ElementType: Element type Frame-Bnd-315
Material: Alumiinium (1)
SEADMED - 02 Tähis: Frame-Bnd-315
AC_Pset_RenovationAndPhasing - Renovation Status: New

# IfcBuildingElementProxy: Frame-Bnd-316, Alumiinium (1); Objekti nimi: Built-in Frame
In: 2 KORRUS
Type - ElementType: Element type Frame-Bnd-316
Material: Alumiinium (1)
SEADMED - 02 Tähis: Frame-Bnd-316
AC_Pset_RenovationAndPhasing - Renovation Status: New

# IfcBuildingElementProxy: Frame-Bnd-317, Alumiinium (1); Objekti nimi: Built-in Frame
In: 2 KORRUS
Type - ElementType: Element type Frame-Bnd-317
Material: Alumiinium (1)
SEADMED - 02 Tähis: Frame-Bnd-317
AC_Pset_RenovationAndPhasing - Renovation Status: New

# IfcBuildingElementProxy: Frame-Bnd-318, Alumiinium (1); Objekti nimi: Built-in Frame
In: 2 KORRUS
Type - ElementType: Element type Frame-Bnd-318
Material: Alumiinium (1)
SEADMED - 02 Tähis: Frame-Bnd-318
AC_Pset_RenovationAndPhasing - Renovation Status: New

# IfcBuildingElementProxy: Frame-Bnd-319, Alumiinium (1); Objekti nimi: Built-in Frame
In: 2 KORRUS
Type - ElementType: Element type Frame-Bnd-319
Material: Alumiinium (1)
SEADMED - 02 Tähis: Frame-Bnd-319
AC_Pset_RenovationAndPhasing - Renovation Status: New

# IfcBuildingElementProxy: Frame-Bnd-320, Alumiinium (1); Objekti nimi: Built-in Frame
In: 2 KORRUS
Type - ElementType: Element type Frame-Bnd-320
Material: Alumiinium (1)
SEADMED - 02 Tähis: Frame-Bnd-320
AC_Pset_RenovationAndPhasing - Renovation Status: New

# IfcBuildingElementProxy: Frame-Bnd-321, Alumiinium (1); Objekti nimi: Built-in Frame
In: 2 KORRUS
Type - ElementType: Element type Frame-Bnd-321
Material: Alumiinium (1)
SEADMED - 02 Tähis: Frame-Bnd-321
AC_Pset_RenovationAndPhasing - Renovation Status: New

# IfcBuildingElementProxy: Frame-Bnd-322, Alumiinium (1); Objekti nimi: Built-in Frame
In: 2 KORRUS
Type - ElementType: Element type Frame-Bnd-322
Material: Alumiinium (1)
SEADMED - 02 Tähis: Frame-Bnd-322
AC_Pset_RenovationAndPhasing - Renovation Status: New

# IfcBuildingElementProxy: Frame-Bnd-323, Alumiinium (1); Objekti nimi: Built-in Frame
In: 2 KORRUS
Type - ElementType: Element type Frame-Bnd-323
Material: Alumiinium (1)
SEADMED - 02 Tähis: Frame-Bnd-323
AC_Pset_RenovationAndPhasing - Renovation Status: New

# IfcBuildingElementProxy: Frame-Bnd-324, Alumiinium (1); Objekti nimi: Built-in Frame
In: 2 KORRUS
Type - ElementType: Element type Frame-Bnd-324
Material: Alumiinium (1)
SEADMED - 02 Tähis: Frame-Bnd-324
AC_Pset_RenovationAndPhasing - Renovation Status: New

# IfcBuildingElementProxy: Frame-Bnd-325, Alumiinium (1); Objekti nimi: Built-in Frame
In: 2 KORRUS
Type - ElementType: Element type Frame-Bnd-325
Material: Alumiinium (1)
SEADMED - 02 Tähis: Frame-Bnd-325
AC_Pset_RenovationAndPhasing - Renovation Status: New

# IfcBuildingElementProxy: Frame-Bnd-326, Alumiinium (1); Objekti nimi: Built-in Frame
In: 2 KORRUS
Type - ElementType: Element type Frame-Bnd-326
Material: Alumiinium (1)
SEADMED - 02 Tähis: Frame-Bnd-326
AC_Pset_RenovationAndPhasing - Renovation Status: New

# IfcBuildingElementProxy: Frame-Bnd-327, Alumiinium (1); Objekti nimi: Built-in Frame
In: 2 KORRUS
Type - ElementType: Element type Frame-Bnd-327
Material: Alumiinium (1)
SEADMED - 02 Tähis: Frame-Bnd-327
AC_Pset_RenovationAndPhasing - Renovation Status: New

# IfcBuildingElementProxy: Frame-Bnd-328, Alumiinium (1); Objekti nimi: Built-in Frame
In: 2 KORRUS
Type - ElementType: Element type Frame-Bnd-328
Material: Alumiinium (1)
SEADMED - 02 Tähis: Frame-Bnd-328
AC_Pset_RenovationAndPhasing - Renovation Status: New

# IfcBuildingElementProxy: Frame-Bnd-329, Alumiinium (1); Objekti nimi: Built-in Frame
In: 2 KORRUS
Type - ElementType: Element type Frame-Bnd-329
Material: Alumiinium (1)
SEADMED - 02 Tähis: Frame-Bnd-329
AC_Pset_RenovationAndPhasing - Renovation Status: New

# IfcBuildingElementProxy: Frame-Bnd-330, Alumiinium (1); Objekti nimi: Built-in Frame
In: 2 KORRUS
Type - ElementType: Element type Frame-Bnd-330
Material: Alumiinium (1)
SEADMED - 02 Tähis: Frame-Bnd-330
AC_Pset_RenovationAndPhasing - Renovation Status: New

# IfcBuildingElementProxy: Frame-Bnd-331, Alumiinium (1); Objekti nimi: Built-in Frame
In: 2 KORRUS
Type - ElementType: Element type Frame-Bnd-331
Material: Alumiinium (1)
SEADMED - 02 Tähis: Frame-Bnd-331
AC_Pset_RenovationAndPhasing - Renovation Status: New

# IfcBuildingElementProxy: Frame-Bnd-454, Alumiinium (1); Objekti nimi: Built-in Frame
In: 1 KORRUS
Type - ElementType: Element type Frame-Bnd-454
Material: Alumiinium (1)
SEADMED - 02 Tähis: Frame-Bnd-454
AC_Pset_RenovationAndPhasing - Renovation Status: New

# IfcBuildingElementProxy: Frame-Bnd-455, Alumiinium (1); Objekti nimi: Built-in Frame
In: 1 KORRUS
Type - ElementType: Element type Frame-Bnd-455
Material: Alumiinium (1)
SEADMED - 02 Tähis: Frame-Bnd-455
AC_Pset_RenovationAndPhasing - Renovation Status: New

# IfcBuildingElementProxy: Frame-Bnd-456, Alumiinium (1); Objekti nimi: Built-in Frame
In: 1 KORRUS
Type - ElementType: Element type Frame-Bnd-456
Material: Alumiinium (1)
SEADMED - 02 Tähis: Frame-Bnd-456
AC_Pset_RenovationAndPhasing - Renovation Status: New

# IfcBuildingElementProxy: Frame-Bnd-457, Alumiinium (1); Objekti nimi: Built-in Frame
In: 1 KORRUS
Type - ElementType: Element type Frame-Bnd-457
Material: Alumiinium (1)
SEADMED - 02 Tähis: Frame-Bnd-457
AC_Pset_RenovationAndPhasing - Renovation Status: New

# IfcBuildingElementProxy: Frame-Bnd-458, Alumiinium (1); Objekti nimi: Built-in Frame
In: 1 KORRUS
Type - ElementType: Element type Frame-Bnd-458
Material: Alumiinium (1)
SEADMED - 02 Tähis: Frame-Bnd-458
AC_Pset_RenovationAndPhasing - Renovation Status: New

# IfcBuildingElementProxy: Frame-Bnd-459, Alumiinium (1); Objekti nimi: Built-in Frame
In: 1 KORRUS
Type - ElementType: Element type Frame-Bnd-459
Material: Alumiinium (1)
SEADMED - 02 Tähis: Frame-Bnd-459
AC_Pset_RenovationAndPhasing - Renovation Status: New

# IfcBuildingElementProxy: Frame-Bnd-460, Alumiinium (1); Objekti nimi: Built-in Frame
In: 1 KORRUS
Type - ElementType: Element type Frame-Bnd-460
Material: Alumiinium (1)
SEADMED - 02 Tähis: Frame-Bnd-460
AC_Pset_RenovationAndPhasing - Renovation Status: New

# IfcBuildingElementProxy: Frame-Bnd-461, Alumiinium (1); Objekti nimi: Built-in Frame
In: 1 KORRUS
Type - ElementType: Element type Frame-Bnd-461
Material: Alumiinium (1)
SEADMED - 02 Tähis: Frame-Bnd-461
AC_Pset_RenovationAndPhasing - Renovation Status: New

# IfcBuildingElementProxy: Frame-Bnd-465, Alumiinium (1); Objekti nimi: Built-in Frame
In: 1 KORRUS
Type - ElementType: Element type Frame-Bnd-465
Material: Alumiinium (1)
SEADMED - 02 Tähis: Frame-Bnd-465
AC_Pset_RenovationAndPhasing - Renovation Status: New

# IfcBuildingElementProxy: Frame-Bnd-608, Alumiinium (1); Objekti nimi: Built-in Frame
In: KATUSEPLAAN
Type - ElementType: Element type Frame-Bnd-608
Material: Alumiinium (1)
SEADMED - 02 Tähis: Frame-Bnd-608
AC_Pset_RenovationAndPhasing - Renovation Status: New

# IfcBuildingElementProxy: Frame-Bnd-609, Alumiinium (1); Objekti nimi: Built-in Frame
In: KATUSEPLAAN
Type - ElementType: Element type Frame-Bnd-609
Material: Alumiinium (1)
SEADMED - 02 Tähis: Frame-Bnd-609
AC_Pset_RenovationAndPhasing - Renovation Status: New

# IfcBuildingElementProxy: Frame-Bnd-610, Alumiinium (1); Objekti nimi: Built-in Frame
In: KATUSEPLAAN
Type - ElementType: Element type Frame-Bnd-610
Material: Alumiinium (1)
SEADMED - 02 Tähis: Frame-Bnd-610
AC_Pset_RenovationAndPhasing - Renovation Status: New

# IfcBuildingElementProxy: Frame-Bnd-611, Alumiinium (1); Objekti nimi: Built-in Frame
In: KATUSEPLAAN
Type - ElementType: Element type Frame-Bnd-611
Material: Alumiinium (1)
SEADMED - 02 Tähis: Frame-Bnd-611
AC_Pset_RenovationAndPhasing - Renovation Status: New

# IfcBuildingElementProxy: Frame-Bnd-612, Alumiinium (1); Objekti nimi: Built-in Frame
In: KATUSEPLAAN
Type - ElementType: Element type Frame-Bnd-612
Material: Alumiinium (1)
SEADMED - 02 Tähis: Frame-Bnd-612
AC_Pset_RenovationAndPhasing - Renovation Status: New

# IfcBuildingElementProxy: Frame-Bnd-613, Alumiinium (1); Objekti nimi: Built-in Frame
In: KATUSEPLAAN
Type - ElementType: Element type Frame-Bnd-613
Material: Alumiinium (1)
SEADMED - 02 Tähis: Frame-Bnd-613
AC_Pset_RenovationAndPhasing - Renovation Status: New

# IfcBuildingElementProxy: Frame-Bnd-614, Alumiinium (1); Objekti nimi: Built-in Frame
In: KATUSEPLAAN
Type - ElementType: Element type Frame-Bnd-614
Material: Alumiinium (1)
SEADMED - 02 Tähis: Frame-Bnd-614
AC_Pset_RenovationAndPhasing - Renovation Status: New

# IfcBuildingElementProxy: Frame-Bnd-615, Alumiinium (1); Objekti nimi: Built-in Frame
In: KATUSEPLAAN
Type - ElementType: Element type Frame-Bnd-615
Material: Alumiinium (1)
SEADMED - 02 Tähis: Frame-Bnd-615
AC_Pset_RenovationAndPhasing - Renovation Status: New

# IfcBuildingElementProxy: Frame-Bnd-616, Alumiinium (1); Objekti nimi: Built-in Frame
In: KATUSEPLAAN
Type - ElementType: Element type Frame-Bnd-616
Material: Alumiinium (1)
SEADMED - 02 Tähis: Frame-Bnd-616
AC_Pset_RenovationAndPhasing - Renovation Status: New

# IfcBuildingElementProxy: Frame-Bnd-617, Alumiinium (1); Objekti nimi: Built-in Frame
In: KATUSEPLAAN
Type - ElementType: Element type Frame-Bnd-617
Material: Alumiinium (1)
SEADMED - 02 Tähis: Frame-Bnd-617
AC_Pset_RenovationAndPhasing - Renovation Status: New

# IfcBuildingElementProxy: Frame-Bnd-618, Alumiinium (1); Objekti nimi: Built-in Frame
In: KATUSEPLAAN
Type - ElementType: Element type Frame-Bnd-618
Material: Alumiinium (1)
SEADMED - 02 Tähis: Frame-Bnd-618
AC_Pset_RenovationAndPhasing - Renovation Status: New

# IfcBuildingElementProxy: Frame-Bnd-619, Alumiinium (1); Objekti nimi: Built-in Frame
In: KATUSEPLAAN
Type - ElementType: Element type Frame-Bnd-619
Material: Alumiinium (1)
SEADMED - 02 Tähis: Frame-Bnd-619
AC_Pset_RenovationAndPhasing - Renovation Status: New

# IfcBuildingElementProxy: Frame-Bnd-620, Alumiinium (1); Objekti nimi: Built-in Frame
In: KATUSEPLAAN
Type - ElementType: Element type Frame-Bnd-620
Material: Alumiinium (1)
SEADMED - 02 Tähis: Frame-Bnd-620
AC_Pset_RenovationAndPhasing - Renovation Status: New

# IfcBuildingElementProxy: Frame-Bnd-621, Alumiinium (1); Objekti nimi: Built-in Frame
In: KATUSEPLAAN
Type - ElementType: Element type Frame-Bnd-621
Material: Alumiinium (1)
SEADMED - 02 Tähis: Frame-Bnd-621
AC_Pset_RenovationAndPhasing - Renovation Status: New

# IfcBuildingElementProxy: Frame-Bnd-622, Alumiinium (1); Objekti nimi: Built-in Frame
In: KATUSEPLAAN
Type - ElementType: Element type Frame-Bnd-622
Material: Alumiinium (1)
SEADMED - 02 Tähis: Frame-Bnd-622
AC_Pset_RenovationAndPhasing - Renovation Status: New

# IfcBuildingElementProxy: Frame-Bnd-623, Alumiinium (1); Objekti nimi: Built-in Frame
In: KATUSEPLAAN
Type - ElementType: Element type Frame-Bnd-623
Material: Alumiinium (1)
SEADMED - 02 Tähis: Frame-Bnd-623
AC_Pset_RenovationAndPhasing - Renovation Status: New

# IfcBuildingElementProxy: Frame-Bnd-624, Alumiinium (1); Objekti nimi: Built-in Frame
In: KATUSEPLAAN
Type - ElementType: Element type Frame-Bnd-624
Material: Alumiinium (1)
SEADMED - 02 Tähis: Frame-Bnd-624
AC_Pset_RenovationAndPhasing - Renovation Status: New

# IfcBuildingElementProxy: Frame-Bnd-625, Alumiinium (1); Objekti nimi: Built-in Frame
In: KATUSEPLAAN
Type - ElementType: Element type Frame-Bnd-625
Material: Alumiinium (1)
SEADMED - 02 Tähis: Frame-Bnd-625
AC_Pset_RenovationAndPhasing - Renovation Status: New

# IfcBuildingElementProxy: Frame-Bnd-626, Alumiinium (1); Objekti nimi: Built-in Frame
In: KATUSEPLAAN
Type - ElementType: Element type Frame-Bnd-626
Material: Alumiinium (1)
SEADMED - 02 Tähis: Frame-Bnd-626
AC_Pset_RenovationAndPhasing - Renovation Status: New

# IfcBuildingElementProxy: Frame-Bnd-627, Alumiinium (1); Objekti nimi: Built-in Frame
In: KATUSEPLAAN
Type - ElementType: Element type Frame-Bnd-627
Material: Alumiinium (1)
SEADMED - 02 Tähis: Frame-Bnd-627
AC_Pset_RenovationAndPhasing - Renovation Status: New

# IfcBuildingElementProxy: Frame-Bnd-628, Alumiinium (1); Objekti nimi: Built-in Frame
In: KATUSEPLAAN
Type - ElementType: Element type Frame-Bnd-628
Material: Alumiinium (1)
SEADMED - 02 Tähis: Frame-Bnd-628
AC_Pset_RenovationAndPhasing - Renovation Status: New

# IfcBuildingElementProxy: Frame-Bnd-629, Alumiinium (1); Objekti nimi: Built-in Frame
In: KATUSEPLAAN
Type - ElementType: Element type Frame-Bnd-629
Material: Alumiinium (1)
SEADMED - 02 Tähis: Frame-Bnd-629
AC_Pset_RenovationAndPhasing - Renovation Status: New

# IfcBuildingElementProxy: Frame-Bnd-630, Alumiinium (1); Objekti nimi: Built-in Frame
In: KATUSEPLAAN
Type - ElementType: Element type Frame-Bnd-630
Material: Alumiinium (1)
SEADMED - 02 Tähis: Frame-Bnd-630
AC_Pset_RenovationAndPhasing - Renovation Status: New

# IfcBuildingElementProxy: Frame-Bnd-631, Alumiinium (1); Objekti nimi: Built-in Frame
In: KATUSEPLAAN
Type - ElementType: Element type Frame-Bnd-631
Material: Alumiinium (1)
SEADMED - 02 Tähis: Frame-Bnd-631
AC_Pset_RenovationAndPhasing - Renovation Status: New

# IfcBuildingElementProxy: Frame-Bnd-632, Alumiinium (1); Objekti nimi: Built-in Frame
In: KATUSEPLAAN
Type - ElementType: Element type Frame-Bnd-632
Material: Alumiinium (1)
SEADMED - 02 Tähis: Frame-Bnd-632
AC_Pset_RenovationAndPhasing - Renovation Status: New

# IfcBuildingElementProxy: Frame-Bnd-633, Alumiinium (1); Objekti nimi: Built-in Frame
In: KATUSEPLAAN
Type - ElementType: Element type Frame-Bnd-633
Material: Alumiinium (1)
SEADMED - 02 Tähis: Frame-Bnd-633
AC_Pset_RenovationAndPhasing - Renovation Status: New

# IfcBuildingElementProxy: Frame-Bnd-634, Alumiinium (1); Objekti nimi: Built-in Frame
In: KATUSEPLAAN
Type - ElementType: Element type Frame-Bnd-634
Material: Alumiinium (1)
SEADMED - 02 Tähis: Frame-Bnd-634
AC_Pset_RenovationAndPhasing - Renovation Status: New

# IfcBuildingElementProxy: Frame-Bnd-635, Alumiinium (1); Objekti nimi: Built-in Frame
In: KATUSEPLAAN
Type - ElementType: Element type Frame-Bnd-635
Material: Alumiinium (1)
SEADMED - 02 Tähis: Frame-Bnd-635
AC_Pset_RenovationAndPhasing - Renovation Status: New

# IfcBuildingElementProxy: Frame-Bnd-636, Alumiinium (1); Objekti nimi: Built-in Frame
In: KATUSEPLAAN
Type - ElementType: Element type Frame-Bnd-636
Material: Alumiinium (1)
SEADMED - 02 Tähis: Frame-Bnd-636
AC_Pset_RenovationAndPhasing - Renovation Status: New

# IfcBuildingElementProxy: Frame-Bnd-637, Alumiinium (1); Objekti nimi: Built-in Frame
In: KATUSEPLAAN
Type - ElementType: Element type Frame-Bnd-637
Material: Alumiinium (1)
SEADMED - 02 Tähis: Frame-Bnd-637
AC_Pset_RenovationAndPhasing - Renovation Status: New

# IfcBuildingElementProxy: Frame-Bnd-638, Alumiinium (1); Objekti nimi: Built-in Frame
In: KATUSEPLAAN
Type - ElementType: Element type Frame-Bnd-638
Material: Alumiinium (1)
SEADMED - 02 Tähis: Frame-Bnd-638
AC_Pset_RenovationAndPhasing - Renovation Status: New

# IfcBuildingElementProxy: Frame-Bnd-639, Alumiinium (1); Objekti nimi: Built-in Frame
In: KATUSEPLAAN
Type - ElementType: Element type Frame-Bnd-639
Material: Alumiinium (1)
SEADMED - 02 Tähis: Frame-Bnd-639
AC_Pset_RenovationAndPhasing - Renovation Status: New

# IfcBuildingElementProxy: Frame-Bnd-640, Alumiinium (1); Objekti nimi: Built-in Frame
In: KATUSEPLAAN
Type - ElementType: Element type Frame-Bnd-640
Material: Alumiinium (1)
SEADMED - 02 Tähis: Frame-Bnd-640
AC_Pset_RenovationAndPhasing - Renovation Status: New

# IfcBuildingElementProxy: Frame-Bnd-641, Alumiinium (1); Objekti nimi: Built-in Frame
In: KATUSEPLAAN
Type - ElementType: Element type Frame-Bnd-641
Material: Alumiinium (1)
SEADMED - 02 Tähis: Frame-Bnd-641
AC_Pset_RenovationAndPhasing - Renovation Status: New

# IfcBuildingElementProxy: Frame-Bnd-642, Alumiinium (1); Objekti nimi: Built-in Frame
In: KATUSEPLAAN
Type - ElementType: Element type Frame-Bnd-642
Material: Alumiinium (1)
SEADMED - 02 Tähis: Frame-Bnd-642
AC_Pset_RenovationAndPhasing - Renovation Status: New

# IfcBuildingElementProxy: Frame-Bnd-643, Alumiinium (1); Objekti nimi: Built-in Frame
In: KATUSEPLAAN
Type - ElementType: Element type Frame-Bnd-643
Material: Alumiinium (1)
SEADMED - 02 Tähis: Frame-Bnd-643
AC_Pset_RenovationAndPhasing - Renovation Status: New

# IfcBuildingElementProxy: Frame-Bnd-644, Alumiinium (1); Objekti nimi: Built-in Frame
In: KATUSEPLAAN
Type - ElementType: Element type Frame-Bnd-644
Material: Alumiinium (1)
SEADMED - 02 Tähis: Frame-Bnd-644
AC_Pset_RenovationAndPhasing - Renovation Status: New

# IfcBuildingElementProxy: Frame-Bnd-645, Alumiinium (1); Objekti nimi: Built-in Frame
In: KATUSEPLAAN
Type - ElementType: Element type Frame-Bnd-645
Material: Alumiinium (1)
SEADMED - 02 Tähis: Frame-Bnd-645
AC_Pset_RenovationAndPhasing - Renovation Status: New

# IfcBuildingElementProxy: Frame-Bnd-646, Alumiinium (1); Objekti nimi: Built-in Frame
In: KATUSEPLAAN
Type - ElementType: Element type Frame-Bnd-646
Material: Alumiinium (1)
SEADMED - 02 Tähis: Frame-Bnd-646
AC_Pset_RenovationAndPhasing - Renovation Status: New

# IfcBuildingElementProxy: Frame-Bnd-647, Alumiinium (1); Objekti nimi: Built-in Frame
In: KATUSEPLAAN
Type - ElementType: Element type Frame-Bnd-647
Material: Alumiinium (1)
SEADMED - 02 Tähis: Frame-Bnd-647
AC_Pset_RenovationAndPhasing - Renovation Status: New

# IfcBuildingElementProxy: Frame-Bnd-648, Alumiinium (1); Objekti nimi: Built-in Frame
In: KATUSEPLAAN
Type - ElementType: Element type Frame-Bnd-648
Material: Alumiinium (1)
SEADMED - 02 Tähis: Frame-Bnd-648
AC_Pset_RenovationAndPhasing - Renovation Status: New

# IfcBuildingElementProxy: Frame-Bnd-649, Alumiinium (1); Objekti nimi: Built-in Frame
In: KATUSEPLAAN
Type - ElementType: Element type Frame-Bnd-649
Material: Alumiinium (1)
SEADMED - 02 Tähis: Frame-Bnd-649
AC_Pset_RenovationAndPhasing - Renovation Status: New

# IfcBuildingElementProxy: Frame-Bnd-650, Alumiinium (1); Objekti nimi: Built-in Frame
In: KATUSEPLAAN
Type - ElementType: Element type Frame-Bnd-650
Material: Alumiinium (1)
SEADMED - 02 Tähis: Frame-Bnd-650
AC_Pset_RenovationAndPhasing - Renovation Status: New

# IfcBuildingElementProxy: Frame-Bnd-651, Alumiinium (1); Objekti nimi: Built-in Frame
In: KATUSEPLAAN
Type - ElementType: Element type Frame-Bnd-651
Material: Alumiinium (1)
SEADMED - 02 Tähis: Frame-Bnd-651
AC_Pset_RenovationAndPhasing - Renovation Status: New

# IfcBuildingElementProxy: Frame-Bnd-652, Alumiinium (1); Objekti nimi: Built-in Frame
In: KATUSEPLAAN
Type - ElementType: Element type Frame-Bnd-652
Material: Alumiinium (1)
SEADMED - 02 Tähis: Frame-Bnd-652
AC_Pset_RenovationAndPhasing - Renovation Status: New

# IfcBuildingElementProxy: Frame-Bnd-653, Alumiinium (1); Objekti nimi: Built-in Frame
In: KATUSEPLAAN
Type - ElementType: Element type Frame-Bnd-653
Material: Alumiinium (1)
SEADMED - 02 Tähis: Frame-Bnd-653
AC_Pset_RenovationAndPhasing - Renovation Status: New

# IfcBuildingElementProxy: Frame-Bnd-654, Alumiinium (1); Objekti nimi: Built-in Frame
In: KATUSEPLAAN
Type - ElementType: Element type Frame-Bnd-654
Material: Alumiinium (1)
SEADMED - 02 Tähis: Frame-Bnd-654
AC_Pset_RenovationAndPhasing - Renovation Status: New

# IfcBuildingElementProxy: Frame-Bnd-655, Alumiinium (1); Objekti nimi: Built-in Frame
In: KATUSEPLAAN
Type - ElementType: Element type Frame-Bnd-655
Material: Alumiinium (1)
SEADMED - 02 Tähis: Frame-Bnd-655
AC_Pset_RenovationAndPhasing - Renovation Status: New

# IfcBuildingElementProxy: Frame-Bnd-656, Alumiinium (1); Objekti nimi: Built-in Frame
In: KATUSEPLAAN
Type - ElementType: Element type Frame-Bnd-656
Material: Alumiinium (1)
SEADMED - 02 Tähis: Frame-Bnd-656
AC_Pset_RenovationAndPhasing - Renovation Status: New

# IfcBuildingElementProxy: Frame-Bnd-657, Alumiinium (1); Objekti nimi: Built-in Frame
In: KATUSEPLAAN
Type - ElementType: Element type Frame-Bnd-657
Material: Alumiinium (1)
SEADMED - 02 Tähis: Frame-Bnd-657
AC_Pset_RenovationAndPhasing - Renovation Status: New

# IfcBuildingElementProxy: Frame-Bnd-658, Alumiinium (1); Objekti nimi: Built-in Frame
In: KATUSEPLAAN
Type - ElementType: Element type Frame-Bnd-658
Material: Alumiinium (1)
SEADMED - 02 Tähis: Frame-Bnd-658
AC_Pset_RenovationAndPhasing - Renovation Status: New

# IfcBuildingElementProxy: Frame-Bnd-659, Alumiinium (1); Objekti nimi: Built-in Frame
In: KATUSEPLAAN
Type - ElementType: Element type Frame-Bnd-659
Material: Alumiinium (1)
SEADMED - 02 Tähis: Frame-Bnd-659
AC_Pset_RenovationAndPhasing - Renovation Status: New

# IfcBuildingElementProxy: Frame-Bnd-660, Alumiinium (1); Objekti nimi: Built-in Frame
In: KATUSEPLAAN
Type - ElementType: Element type Frame-Bnd-660
Material: Alumiinium (1)
SEADMED - 02 Tähis: Frame-Bnd-660
AC_Pset_RenovationAndPhasing - Renovation Status: New

# IfcBuildingElementProxy: Frame-Bnd-661, Alumiinium (1); Objekti nimi: Built-in Frame
In: KATUSEPLAAN
Type - ElementType: Element type Frame-Bnd-661
Material: Alumiinium (1)
SEADMED - 02 Tähis: Frame-Bnd-661
AC_Pset_RenovationAndPhasing - Renovation Status: New

# IfcBuildingElementProxy: Frame-Bnd-662, Alumiinium (1); Objekti nimi: Built-in Frame
In: KATUSEPLAAN
Type - ElementType: Element type Frame-Bnd-662
Material: Alumiinium (1)
SEADMED - 02 Tähis: Frame-Bnd-662
AC_Pset_RenovationAndPhasing - Renovation Status: New

# IfcBuildingElementProxy: Frame-Bnd-663, Alumiinium (1); Objekti nimi: Built-in Frame
In: KATUSEPLAAN
Type - ElementType: Element type Frame-Bnd-663
Material: Alumiinium (1)
SEADMED - 02 Tähis: Frame-Bnd-663
AC_Pset_RenovationAndPhasing - Renovation Status: New

# IfcBuildingElementProxy: Frame-Bnd-664, Alumiinium (1); Objekti nimi: Built-in Frame
In: KATUSEPLAAN
Type - ElementType: Element type Frame-Bnd-664
Material: Alumiinium (1)
SEADMED - 02 Tähis: Frame-Bnd-664
AC_Pset_RenovationAndPhasing - Renovation Status: New

# IfcBuildingElementProxy: Frame-Bnd-665, Alumiinium (1); Objekti nimi: Built-in Frame
In: KATUSEPLAAN
Type - ElementType: Element type Frame-Bnd-665
Material: Alumiinium (1)
SEADMED - 02 Tähis: Frame-Bnd-665
AC_Pset_RenovationAndPhasing - Renovation Status: New

# IfcBuildingElementProxy: Frame-Bnd-666, Alumiinium (1); Objekti nimi: Built-in Frame
In: KATUSEPLAAN
Type - ElementType: Element type Frame-Bnd-666
Material: Alumiinium (1)
SEADMED - 02 Tähis: Frame-Bnd-666
AC_Pset_RenovationAndPhasing - Renovation Status: New

# IfcBuildingElementProxy: Frame-Bnd-667, Alumiinium (1); Objekti nimi: Built-in Frame
In: KATUSEPLAAN
Type - ElementType: Element type Frame-Bnd-667
Material: Alumiinium (1)
SEADMED - 02 Tähis: Frame-Bnd-667
AC_Pset_RenovationAndPhasing - Renovation Status: New

# IfcBuildingElementProxy: Frame-Bnd-668, Alumiinium (1); Objekti nimi: Built-in Frame
In: KATUSEPLAAN
Type - ElementType: Element type Frame-Bnd-668
Material: Alumiinium (1)
SEADMED - 02 Tähis: Frame-Bnd-668
AC_Pset_RenovationAndPhasing - Renovation Status: New

# IfcBuildingElementProxy: Frame-Bnd-669, Alumiinium (1); Objekti nimi: Built-in Frame
In: KATUSEPLAAN
Type - ElementType: Element type Frame-Bnd-669
Material: Alumiinium (1)
SEADMED - 02 Tähis: Frame-Bnd-669
AC_Pset_RenovationAndPhasing - Renovation Status: New

# IfcBuildingElementProxy: Frame-Mll-000, Alumiinium (1); Objekti nimi: Frame 22
In: KATUSEPLAAN
Type - ElementType: Element type Frame-Mll-000
Material: Alumiinium (1) (2)
SEADMED - 02 Tähis: Frame-Mll-000
AC_Pset_RenovationAndPhasing - Renovation Status: New

# IfcBuildingElementProxy: Frame-Mll-001, Alumiinium (1); Objekti nimi: Frame 22
In: KATUSEPLAAN
Type - ElementType: Element type Frame-Mll-001
Material: Alumiinium (1) (2)
SEADMED - 02 Tähis: Frame-Mll-001
AC_Pset_RenovationAndPhasing - Renovation Status: New

# IfcBuildingElementProxy: Frame-Mll-002, Alumiinium (1); Objekti nimi: Frame 22
In: KATUSEPLAAN
Type - ElementType: Element type Frame-Mll-002
Material: Alumiinium (1) (2)
SEADMED - 02 Tähis: Frame-Mll-002
AC_Pset_RenovationAndPhasing - Renovation Status: New

# IfcBuildingElementProxy: Frame-Mll-003, Alumiinium (1); Objekti nimi: Frame 22
In: KATUSEPLAAN
Type - ElementType: Element type Frame-Mll-003
Material: Alumiinium (1) (2)
SEADMED - 02 Tähis: Frame-Mll-003
AC_Pset_RenovationAndPhasing - Renovation Status: New

# IfcBuildingElementProxy: Frame-Mll-004, Alumiinium (1); Objekti nimi: Frame 22
In: KATUSEPLAAN
Type - ElementType: Element type Frame-Mll-004
Material: Alumiinium (1) (2)
SEADMED - 02 Tähis: Frame-Mll-004
AC_Pset_RenovationAndPhasing - Renovation Status: New

# IfcBuildingElementProxy: Frame-Mll-005, Alumiinium (1); Objekti nimi: Frame 22
In: KATUSEPLAAN
Type - ElementType: Element type Frame-Mll-005
Material: Alumiinium (1) (2)
SEADMED - 02 Tähis: Frame-Mll-005
AC_Pset_RenovationAndPhasing - Renovation Status: New

# IfcBuildingElementProxy: Frame-Mll-006, Alumiinium (1); Objekti nimi: Frame 22
In: KATUSEPLAAN
Type - ElementType: Element type Frame-Mll-006
Material: Alumiinium (1) (2)
SEADMED - 02 Tähis: Frame-Mll-006
AC_Pset_RenovationAndPhasing - Renovation Status: New

# IfcBuildingElementProxy: Frame-Mll-007, Alumiinium (1); Objekti nimi: Frame 22
In: KATUSEPLAAN
Type - ElementType: Element type Frame-Mll-007
Material: Alumiinium (1) (2)
SEADMED - 02 Tähis: Frame-Mll-007
AC_Pset_RenovationAndPhasing - Renovation Status: New

# IfcBuildingElementProxy: Frame-Mll-008, Alumiinium (1); Objekti nimi: Frame 22
In: KATUSEPLAAN
Type - ElementType: Element type Frame-Mll-008
Material: Alumiinium (1) (2)
SEADMED - 02 Tähis: Frame-Mll-008
AC_Pset_RenovationAndPhasing - Renovation Status: New

# IfcBuildingElementProxy: Frame-Mll-009, Alumiinium (1); Objekti nimi: Frame 22
In: KATUSEPLAAN
Type - ElementType: Element type Frame-Mll-009
Material: Alumiinium (1) (2)
SEADMED - 02 Tähis: Frame-Mll-009
AC_Pset_RenovationAndPhasing - Renovation Status: New

# IfcBuildingElementProxy: Frame-Mll-010, Alumiinium (1); Objekti nimi: Frame 22
In: KATUSEPLAAN
Type - ElementType: Element type Frame-Mll-010
Material: Alumiinium (1) (2)
SEADMED - 02 Tähis: Frame-Mll-010
AC_Pset_RenovationAndPhasing - Renovation Status: New

# IfcBuildingElementProxy: Frame-Mll-014, Alumiinium (1); Objekti nimi: Frame 22
In: KATUSEPLAAN
Type - ElementType: Element type Frame-Mll-014
Material: Alumiinium (1) (2)
SEADMED - 02 Tähis: Frame-Mll-014
AC_Pset_RenovationAndPhasing - Renovation Status: New

# IfcBuildingElementProxy: Frame-Mll-015, Alumiinium (1); Objekti nimi: Frame 22
In: KATUSEPLAAN
Type - ElementType: Element type Frame-Mll-015
Material: Alumiinium (1) (2)
SEADMED - 02 Tähis: Frame-Mll-015
AC_Pset_RenovationAndPhasing - Renovation Status: New

# IfcBuildingElementProxy: Frame-Mll-040 (8)
In: 1 KORRUS
Type - ElementType: Element type Frame-Mll-040
Material: Alumiinium (1) (2)
SEADMED - 02 Tähis: Frame-Mll-040
AC_Pset_RenovationAndPhasing - Renovation Status: New

# IfcBuildingElementProxy: Frame-Mll-052, Alumiinium (1); Objekti nimi: Frame 22
In: KATUSEPLAAN
Type - ElementType: Element type Frame-Mll-052
Material: Alumiinium (1) (2)
SEADMED - 02 Tähis: Frame-Mll-052
AC_Pset_RenovationAndPhasing - Renovation Status: New

# IfcBuildingElementProxy: Frame-Mll-053, Alumiinium (1); Objekti nimi: Frame 22
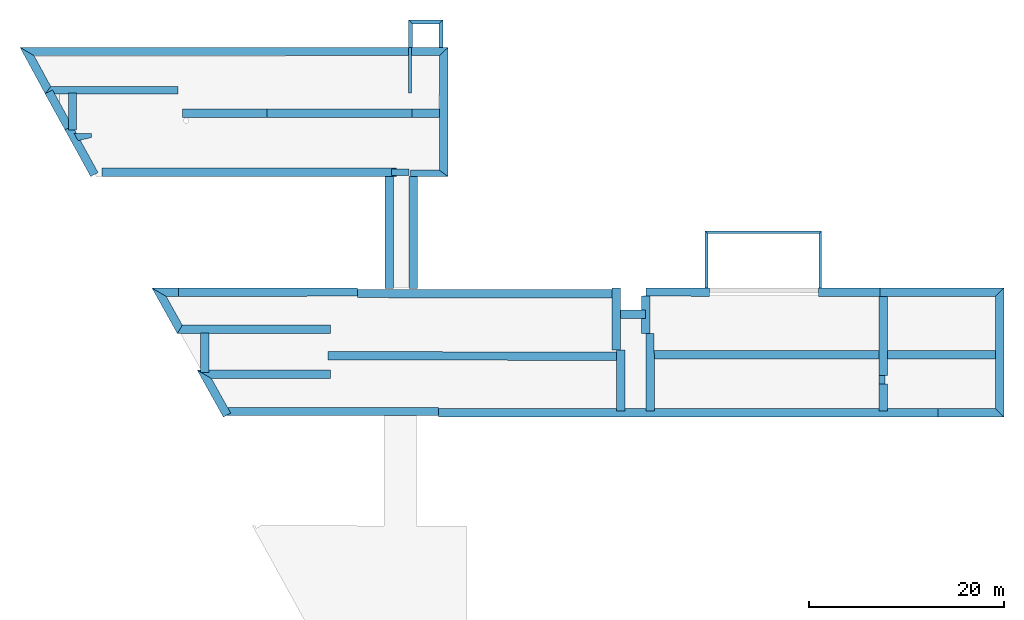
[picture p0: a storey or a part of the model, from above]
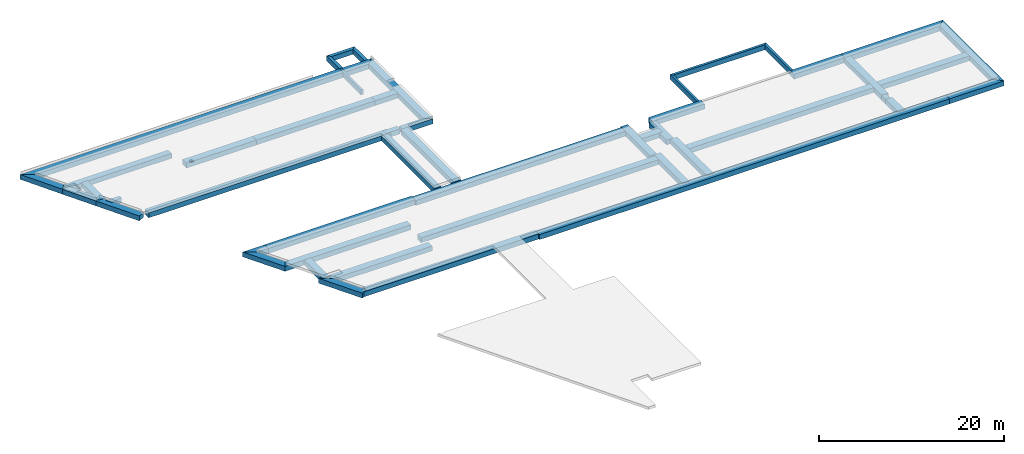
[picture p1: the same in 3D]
Properties of the parts of a building model (IFC2X3), part 2 of 14

# IfcBuildingElementProxy: Frame-Mll-053, Alumiinium (1); Objekti nimi: Frame 22
In: KATUSEPLAAN
Type - ElementType: Element type Frame-Mll-053
Material: Alumiinium (1) (2)
SEADMED - 02 Tähis: Frame-Mll-053
AC_Pset_RenovationAndPhasing - Renovation Status: New

# IfcBuildingElementProxy: Frame-Mll-054, Alumiinium (1); Objekti nimi: Frame 22
In: KATUSEPLAAN
Type - ElementType: Element type Frame-Mll-054
Material: Alumiinium (1) (2)
SEADMED - 02 Tähis: Frame-Mll-054
AC_Pset_RenovationAndPhasing - Renovation Status: New

# IfcBuildingElementProxy: Frame-Mll-055, Alumiinium (1); Objekti nimi: Frame 22
In: KATUSEPLAAN
Type - ElementType: Element type Frame-Mll-055
Material: Alumiinium (1) (2)
SEADMED - 02 Tähis: Frame-Mll-055
AC_Pset_RenovationAndPhasing - Renovation Status: New

# IfcBuildingElementProxy: Frame-Mll-056, Alumiinium (1); Objekti nimi: Frame 22
In: KATUSEPLAAN
Type - ElementType: Element type Frame-Mll-056
Material: Alumiinium (1) (2)
SEADMED - 02 Tähis: Frame-Mll-056
AC_Pset_RenovationAndPhasing - Renovation Status: New

# IfcBuildingElementProxy: Frame-Mll-057, Alumiinium (1); Objekti nimi: Frame 22
In: KATUSEPLAAN
Type - ElementType: Element type Frame-Mll-057
Material: Alumiinium (1) (2)
SEADMED - 02 Tähis: Frame-Mll-057
AC_Pset_RenovationAndPhasing - Renovation Status: New

# IfcBuildingElementProxy: Frame-Mll-058, Alumiinium (1); Objekti nimi: Frame 22
In: KATUSEPLAAN
Type - ElementType: Element type Frame-Mll-058
Material: Alumiinium (1) (2)
SEADMED - 02 Tähis: Frame-Mll-058
AC_Pset_RenovationAndPhasing - Renovation Status: New

# IfcBuildingElementProxy: Frame-Mll-059, Alumiinium (1); Objekti nimi: Frame 22
In: KATUSEPLAAN
Type - ElementType: Element type Frame-Mll-059
Material: Alumiinium (1) (2)
SEADMED - 02 Tähis: Frame-Mll-059
AC_Pset_RenovationAndPhasing - Renovation Status: New

# IfcBuildingElementProxy: Frame-Mll-060, Alumiinium (1); Objekti nimi: Frame 22
In: KATUSEPLAAN
Type - ElementType: Element type Frame-Mll-060
Material: Alumiinium (1) (2)
SEADMED - 02 Tähis: Frame-Mll-060
AC_Pset_RenovationAndPhasing - Renovation Status: New

# IfcBuildingElementProxy: Frame-Mll-061, Alumiinium (1); Objekti nimi: Frame 22
In: KATUSEPLAAN
Type - ElementType: Element type Frame-Mll-061
Material: Alumiinium (1) (2)
SEADMED - 02 Tähis: Frame-Mll-061
AC_Pset_RenovationAndPhasing - Renovation Status: New

# IfcBuildingElementProxy: Frame-Mll-062, Alumiinium (1); Objekti nimi: Frame 22
In: KATUSEPLAAN
Type - ElementType: Element type Frame-Mll-062
Material: Alumiinium (1) (2)
SEADMED - 02 Tähis: Frame-Mll-062
AC_Pset_RenovationAndPhasing - Renovation Status: New

# IfcBuildingElementProxy: Frame-Mll-063, Alumiinium (1); Objekti nimi: Frame 22
In: KATUSEPLAAN
Type - ElementType: Element type Frame-Mll-063
Material: Alumiinium (1) (2)
SEADMED - 02 Tähis: Frame-Mll-063
AC_Pset_RenovationAndPhasing - Renovation Status: New

# IfcBuildingElementProxy: Frame-Mll-064, Alumiinium (1); Objekti nimi: Frame 22
In: KATUSEPLAAN
Type - ElementType: Element type Frame-Mll-064
Material: Alumiinium (1) (2)
SEADMED - 02 Tähis: Frame-Mll-064
AC_Pset_RenovationAndPhasing - Renovation Status: New

# IfcBuildingElementProxy: Frame-Mll-065, Alumiinium (1); Objekti nimi: Frame 22
In: KATUSEPLAAN
Type - ElementType: Element type Frame-Mll-065
Material: Alumiinium (1) (2)
SEADMED - 02 Tähis: Frame-Mll-065
AC_Pset_RenovationAndPhasing - Renovation Status: New

# IfcBuildingElementProxy: Frame-Mll-066, Alumiinium (1); Objekti nimi: Frame 22
In: KATUSEPLAAN
Type - ElementType: Element type Frame-Mll-066
Material: Alumiinium (1) (2)
SEADMED - 02 Tähis: Frame-Mll-066
AC_Pset_RenovationAndPhasing - Renovation Status: New

# IfcBuildingElementProxy: Frame-Mll-067, Alumiinium (1); Objekti nimi: Frame 22
In: KATUSEPLAAN
Type - ElementType: Element type Frame-Mll-067
Material: Alumiinium (1) (2)
SEADMED - 02 Tähis: Frame-Mll-067
AC_Pset_RenovationAndPhasing - Renovation Status: New

# IfcBuildingElementProxy: Frame-Mll-068, Alumiinium (1); Objekti nimi: Frame 22
In: KATUSEPLAAN
Type - ElementType: Element type Frame-Mll-068
Material: Alumiinium (1) (2)
SEADMED - 02 Tähis: Frame-Mll-068
AC_Pset_RenovationAndPhasing - Renovation Status: New

# IfcBuildingElementProxy: Frame-Mll-069, Alumiinium (1); Objekti nimi: Frame 22
In: KATUSEPLAAN
Type - ElementType: Element type Frame-Mll-069
Material: Alumiinium (1) (2)
SEADMED - 02 Tähis: Frame-Mll-069
AC_Pset_RenovationAndPhasing - Renovation Status: New

# IfcBuildingElementProxy: Frame-Mll-070, Alumiinium (1); Objekti nimi: Frame 22
In: KATUSEPLAAN
Type - ElementType: Element type Frame-Mll-070
Material: Alumiinium (1) (2)
SEADMED - 02 Tähis: Frame-Mll-070
AC_Pset_RenovationAndPhasing - Renovation Status: New

# IfcBuildingElementProxy: Frame-Mll-071, Alumiinium (1); Objekti nimi: Frame 22
In: KATUSEPLAAN
Type - ElementType: Element type Frame-Mll-071
Material: Alumiinium (1) (2)
SEADMED - 02 Tähis: Frame-Mll-071
AC_Pset_RenovationAndPhasing - Renovation Status: New

# IfcBuildingElementProxy: Frame-Mll-072, Alumiinium (1); Objekti nimi: Frame 22
In: KATUSEPLAAN
Type - ElementType: Element type Frame-Mll-072
Material: Alumiinium (1) (2)
SEADMED - 02 Tähis: Frame-Mll-072
AC_Pset_RenovationAndPhasing - Renovation Status: New

# IfcBuildingElementProxy: Frame-Mll-073, Alumiinium (1); Objekti nimi: Frame 22
In: KATUSEPLAAN
Type - ElementType: Element type Frame-Mll-073
Material: Alumiinium (1) (2)
SEADMED - 02 Tähis: Frame-Mll-073
AC_Pset_RenovationAndPhasing - Renovation Status: New

# IfcBuildingElementProxy: Frame-Mll-074, Alumiinium (1); Objekti nimi: Frame 22
In: KATUSEPLAAN
Type - ElementType: Element type Frame-Mll-074
Material: Alumiinium (1) (2)
SEADMED - 02 Tähis: Frame-Mll-074
AC_Pset_RenovationAndPhasing - Renovation Status: New

# IfcBuildingElementProxy: Frame-Mll-110, Alumiinium (1); Objekti nimi: Frame 22
In: KATUSEPLAAN
Type - ElementType: Element type Frame-Mll-110
Material: Alumiinium (1) (2)
SEADMED - 02 Tähis: Frame-Mll-110
AC_Pset_RenovationAndPhasing - Renovation Status: New

# IfcBuildingElementProxy: Frame-Mll-111, Alumiinium (1); Objekti nimi: Frame 22
In: KATUSEPLAAN
Type - ElementType: Element type Frame-Mll-111
Material: Alumiinium (1) (2)
SEADMED - 02 Tähis: Frame-Mll-111
AC_Pset_RenovationAndPhasing - Renovation Status: New

# IfcBuildingElementProxy: Frame-Mll-112, Alumiinium (1); Objekti nimi: Frame 22
In: KATUSEPLAAN
Type - ElementType: Element type Frame-Mll-112
Material: Alumiinium (1) (2)
SEADMED - 02 Tähis: Frame-Mll-112
AC_Pset_RenovationAndPhasing - Renovation Status: New

# IfcBuildingElementProxy: Frame-Mll-194, Alumiinium (1); Objekti nimi: Frame 22
In: KATUSEPLAAN
Type - ElementType: Element type Frame-Mll-194
Material: Alumiinium (1) (2)
SEADMED - 02 Tähis: Frame-Mll-194
AC_Pset_RenovationAndPhasing - Renovation Status: New

# IfcBuildingElementProxy: Frame-Mll-195, Alumiinium (1); Objekti nimi: Frame 22
In: KATUSEPLAAN
Type - ElementType: Element type Frame-Mll-195
Material: Alumiinium (1) (2)
SEADMED - 02 Tähis: Frame-Mll-195
AC_Pset_RenovationAndPhasing - Renovation Status: New

# IfcBuildingElementProxy: Frame-Mll-196, Alumiinium (1); Objekti nimi: Frame 22
In: KATUSEPLAAN
Type - ElementType: Element type Frame-Mll-196
Material: Alumiinium (1) (2)
SEADMED - 02 Tähis: Frame-Mll-196
AC_Pset_RenovationAndPhasing - Renovation Status: New

# IfcBuildingElementProxy: Frame-Mll-197, Alumiinium (1); Objekti nimi: Frame 22
In: KATUSEPLAAN
Type - ElementType: Element type Frame-Mll-197
Material: Alumiinium (1) (2)
SEADMED - 02 Tähis: Frame-Mll-197
AC_Pset_RenovationAndPhasing - Renovation Status: New

# IfcBuildingElementProxy: Frame-Mll-198, Alumiinium (1); Objekti nimi: Frame 22
In: KATUSEPLAAN
Type - ElementType: Element type Frame-Mll-198
Material: Alumiinium (1) (2)
SEADMED - 02 Tähis: Frame-Mll-198
AC_Pset_RenovationAndPhasing - Renovation Status: New

# IfcBuildingElementProxy: Frame-Mll-199, Alumiinium (1); Objekti nimi: Frame 22
In: KATUSEPLAAN
Type - ElementType: Element type Frame-Mll-199
Material: Alumiinium (1) (2)
SEADMED - 02 Tähis: Frame-Mll-199
AC_Pset_RenovationAndPhasing - Renovation Status: New

# IfcBuildingElementProxy: Frame-Mll-200, Alumiinium (1); Objekti nimi: Frame 22
In: KATUSEPLAAN
Type - ElementType: Element type Frame-Mll-200
Material: Alumiinium (1) (2)
SEADMED - 02 Tähis: Frame-Mll-200
AC_Pset_RenovationAndPhasing - Renovation Status: New

# IfcBuildingElementProxy: Frame-Mll-201, Alumiinium (1); Objekti nimi: Frame 22
In: KATUSEPLAAN
Type - ElementType: Element type Frame-Mll-201
Material: Alumiinium (1) (2)
SEADMED - 02 Tähis: Frame-Mll-201
AC_Pset_RenovationAndPhasing - Renovation Status: New

# IfcBuildingElementProxy: Frame-Mll-202, Alumiinium (1); Objekti nimi: Frame 22
In: KATUSEPLAAN
Type - ElementType: Element type Frame-Mll-202
Material: Alumiinium (1) (2)
SEADMED - 02 Tähis: Frame-Mll-202
AC_Pset_RenovationAndPhasing - Renovation Status: New

# IfcBuildingElementProxy: Frame-Mll-203, Alumiinium (1); Objekti nimi: Frame 22
In: KATUSEPLAAN
Type - ElementType: Element type Frame-Mll-203
Material: Alumiinium (1) (2)
SEADMED - 02 Tähis: Frame-Mll-203
AC_Pset_RenovationAndPhasing - Renovation Status: New

# IfcBuildingElementProxy: Frame-Mll-204, Alumiinium (1); Objekti nimi: Frame 22
In: KATUSEPLAAN
Type - ElementType: Element type Frame-Mll-204
Material: Alumiinium (1) (2)
SEADMED - 02 Tähis: Frame-Mll-204
AC_Pset_RenovationAndPhasing - Renovation Status: New

# IfcBuildingElementProxy: Frame-Mll-205, Alumiinium (1); Objekti nimi: Frame 22
In: KATUSEPLAAN
Type - ElementType: Element type Frame-Mll-205
Material: Alumiinium (1) (2)
SEADMED - 02 Tähis: Frame-Mll-205
AC_Pset_RenovationAndPhasing - Renovation Status: New

# IfcBuildingElementProxy: Frame-Mll-207, Alumiinium (1); Objekti nimi: Frame 22
In: KATUSEPLAAN
Type - ElementType: Element type Frame-Mll-207
Material: Alumiinium (1) (2)
SEADMED - 02 Tähis: Frame-Mll-207
AC_Pset_RenovationAndPhasing - Renovation Status: New

# IfcBuildingElementProxy: Frame-Mll-209, Alumiinium (1); Objekti nimi: Frame 22
In: KATUSEPLAAN
Type - ElementType: Element type Frame-Mll-209
Material: Alumiinium (1) (2)
SEADMED - 02 Tähis: Frame-Mll-209
AC_Pset_RenovationAndPhasing - Renovation Status: New

# IfcBuildingElementProxy: Frame-Mll-211, Alumiinium (1); Objekti nimi: Frame 22
In: KATUSEPLAAN
Type - ElementType: Element type Frame-Mll-211
Material: Alumiinium (1) (2)
SEADMED - 02 Tähis: Frame-Mll-211
AC_Pset_RenovationAndPhasing - Renovation Status: New

# IfcBuildingElementProxy: Frame-Mll-213, Alumiinium (1); Objekti nimi: Frame 22
In: KATUSEPLAAN
Type - ElementType: Element type Frame-Mll-213
Material: Alumiinium (1) (2)
SEADMED - 02 Tähis: Frame-Mll-213
AC_Pset_RenovationAndPhasing - Renovation Status: New

# IfcBuildingElementProxy: Frame-Mll-217, Alumiinium (1); Objekti nimi: Frame 22
In: KATUSEPLAAN
Type - ElementType: Element type Frame-Mll-217
Material: Alumiinium (1) (2)
SEADMED - 02 Tähis: Frame-Mll-217
AC_Pset_RenovationAndPhasing - Renovation Status: New

# IfcBuildingElementProxy: Frame-Mll-218, Alumiinium (1); Objekti nimi: Frame 22
In: KATUSEPLAAN
Type - ElementType: Element type Frame-Mll-218
Material: Alumiinium (1) (2)
SEADMED - 02 Tähis: Frame-Mll-218
AC_Pset_RenovationAndPhasing - Renovation Status: New

# IfcBuildingElementProxy: Frame-Mll-219, Alumiinium (1); Objekti nimi: Frame 22
In: KATUSEPLAAN
Type - ElementType: Element type Frame-Mll-219
Material: Alumiinium (1) (2)
SEADMED - 02 Tähis: Frame-Mll-219
AC_Pset_RenovationAndPhasing - Renovation Status: New

# IfcBuildingElementProxy: Frame-Mll-220, Alumiinium (1); Objekti nimi: Frame 22
In: KATUSEPLAAN
Type - ElementType: Element type Frame-Mll-220
Material: Alumiinium (1) (2)
SEADMED - 02 Tähis: Frame-Mll-220
AC_Pset_RenovationAndPhasing - Renovation Status: New

# IfcBuildingElementProxy: Frame-Mll-221, Alumiinium (1); Objekti nimi: Frame 22
In: KATUSEPLAAN
Type - ElementType: Element type Frame-Mll-221
Material: Alumiinium (1) (2)
SEADMED - 02 Tähis: Frame-Mll-221
AC_Pset_RenovationAndPhasing - Renovation Status: New

# IfcBuildingElementProxy: Frame-Mll-222, Alumiinium (1); Objekti nimi: Frame 22
In: KATUSEPLAAN
Type - ElementType: Element type Frame-Mll-222
Material: Alumiinium (1) (2)
SEADMED - 02 Tähis: Frame-Mll-222
AC_Pset_RenovationAndPhasing - Renovation Status: New

# IfcBuildingElementProxy: Frame-Mll-223, Alumiinium (1); Objekti nimi: Frame 22
In: KATUSEPLAAN
Type - ElementType: Element type Frame-Mll-223
Material: Alumiinium (1) (2)
SEADMED - 02 Tähis: Frame-Mll-223
AC_Pset_RenovationAndPhasing - Renovation Status: New

# IfcBuildingElementProxy: Frame-Mll-224, Alumiinium (1); Objekti nimi: Frame 22
In: KATUSEPLAAN
Type - ElementType: Element type Frame-Mll-224
Material: Alumiinium (1) (2)
SEADMED - 02 Tähis: Frame-Mll-224
AC_Pset_RenovationAndPhasing - Renovation Status: New

# IfcBuildingElementProxy: Frame-Mll-225, Alumiinium (1); Objekti nimi: Frame 22
In: KATUSEPLAAN
Type - ElementType: Element type Frame-Mll-225
Material: Alumiinium (1) (2)
SEADMED - 02 Tähis: Frame-Mll-225
AC_Pset_RenovationAndPhasing - Renovation Status: New

# IfcBuildingElementProxy: Frame-Mll-226, Alumiinium (1); Objekti nimi: Frame 22
In: KATUSEPLAAN
Type - ElementType: Element type Frame-Mll-226
Material: Alumiinium (1) (2)
SEADMED - 02 Tähis: Frame-Mll-226
AC_Pset_RenovationAndPhasing - Renovation Status: New

# IfcBuildingElementProxy: Frame-Mll-227, Alumiinium (1); Objekti nimi: Frame 22
In: KATUSEPLAAN
Type - ElementType: Element type Frame-Mll-227
Material: Alumiinium (1) (2)
SEADMED - 02 Tähis: Frame-Mll-227
AC_Pset_RenovationAndPhasing - Renovation Status: New

# IfcBuildingElementProxy: Frame-Mll-228, Alumiinium (1); Objekti nimi: Frame 22
In: KATUSEPLAAN
Type - ElementType: Element type Frame-Mll-228
Material: Alumiinium (1) (2)
SEADMED - 02 Tähis: Frame-Mll-228
AC_Pset_RenovationAndPhasing - Renovation Status: New

# IfcBuildingElementProxy: Frame-Mll-229, Alumiinium (1); Objekti nimi: Frame 22
In: KATUSEPLAAN
Type - ElementType: Element type Frame-Mll-229
Material: Alumiinium (1) (2)
SEADMED - 02 Tähis: Frame-Mll-229
AC_Pset_RenovationAndPhasing - Renovation Status: New

# IfcBuildingElementProxy: Frame-Mll-230, Alumiinium (1); Objekti nimi: Frame 22
In: KATUSEPLAAN
Type - ElementType: Element type Frame-Mll-230
Material: Alumiinium (1) (2)
SEADMED - 02 Tähis: Frame-Mll-230
AC_Pset_RenovationAndPhasing - Renovation Status: New

# IfcBuildingElementProxy: Frame-Mll-231, Alumiinium (1); Objekti nimi: Frame 22
In: KATUSEPLAAN
Type - ElementType: Element type Frame-Mll-231
Material: Alumiinium (1) (2)
SEADMED - 02 Tähis: Frame-Mll-231
AC_Pset_RenovationAndPhasing - Renovation Status: New

# IfcBuildingElementProxy: Frame-Mll-232, Alumiinium (1); Objekti nimi: Frame 22
In: KATUSEPLAAN
Type - ElementType: Element type Frame-Mll-232
Material: Alumiinium (1) (2)
SEADMED - 02 Tähis: Frame-Mll-232
AC_Pset_RenovationAndPhasing - Renovation Status: New

# IfcBuildingElementProxy: Frame-Mll-233, Alumiinium (1); Objekti nimi: Frame 22
In: KATUSEPLAAN
Type - ElementType: Element type Frame-Mll-233
Material: Alumiinium (1) (2)
SEADMED - 02 Tähis: Frame-Mll-233
AC_Pset_RenovationAndPhasing - Renovation Status: New

# IfcBuildingElementProxy: Frame-Mll-234, Alumiinium (1); Objekti nimi: Frame 22
In: KATUSEPLAAN
Type - ElementType: Element type Frame-Mll-234
Material: Alumiinium (1) (2)
SEADMED - 02 Tähis: Frame-Mll-234
AC_Pset_RenovationAndPhasing - Renovation Status: New

# IfcBuildingElementProxy: Frame-Mll-235, Alumiinium (1); Objekti nimi: Frame 22
In: KATUSEPLAAN
Type - ElementType: Element type Frame-Mll-235
Material: Alumiinium (1) (2)
SEADMED - 02 Tähis: Frame-Mll-235
AC_Pset_RenovationAndPhasing - Renovation Status: New

# IfcBuildingElementProxy: Frame-Mll-236, Alumiinium (1); Objekti nimi: Frame 22
In: KATUSEPLAAN
Type - ElementType: Element type Frame-Mll-236
Material: Alumiinium (1) (2)
SEADMED - 02 Tähis: Frame-Mll-236
AC_Pset_RenovationAndPhasing - Renovation Status: New

# IfcBuildingElementProxy: Frame-Mll-237, Alumiinium (1); Objekti nimi: Frame 22
In: KATUSEPLAAN
Type - ElementType: Element type Frame-Mll-237
Material: Alumiinium (1) (2)
SEADMED - 02 Tähis: Frame-Mll-237
AC_Pset_RenovationAndPhasing - Renovation Status: New

# IfcBuildingElementProxy: Frame-Mll-238, Alumiinium (1); Objekti nimi: Frame 22
In: KATUSEPLAAN
Type - ElementType: Element type Frame-Mll-238
Material: Alumiinium (1) (2)
SEADMED - 02 Tähis: Frame-Mll-238
AC_Pset_RenovationAndPhasing - Renovation Status: New

# IfcBuildingElementProxy: Frame-Mll-239, Alumiinium (1); Objekti nimi: Frame 22
In: KATUSEPLAAN
Type - ElementType: Element type Frame-Mll-239
Material: Alumiinium (1) (2)
SEADMED - 02 Tähis: Frame-Mll-239
AC_Pset_RenovationAndPhasing - Renovation Status: New

# IfcBuildingElementProxy: Frame-Mll-240, Alumiinium (1); Objekti nimi: Frame 22
In: KATUSEPLAAN
Type - ElementType: Element type Frame-Mll-240
Material: Alumiinium (1) (2)
SEADMED - 02 Tähis: Frame-Mll-240
AC_Pset_RenovationAndPhasing - Renovation Status: New

# IfcBuildingElementProxy: Frame-Mll-241, Alumiinium (1); Objekti nimi: Frame 22
In: KATUSEPLAAN
Type - ElementType: Element type Frame-Mll-241
Material: Alumiinium (1) (2)
SEADMED - 02 Tähis: Frame-Mll-241
AC_Pset_RenovationAndPhasing - Renovation Status: New

# IfcBuildingElementProxy: Frame-Mll-242, Alumiinium (1); Objekti nimi: Frame 22
In: KATUSEPLAAN
Type - ElementType: Element type Frame-Mll-242
Material: Alumiinium (1) (2)
SEADMED - 02 Tähis: Frame-Mll-242
AC_Pset_RenovationAndPhasing - Renovation Status: New

# IfcBuildingElementProxy: Frame-Mll-243, Alumiinium (1); Objekti nimi: Frame 22
In: KATUSEPLAAN
Type - ElementType: Element type Frame-Mll-243
Material: Alumiinium (1) (2)
SEADMED - 02 Tähis: Frame-Mll-243
AC_Pset_RenovationAndPhasing - Renovation Status: New

# IfcBuildingElementProxy: Frame-Mll-244, Alumiinium (1); Objekti nimi: Frame 22
In: KATUSEPLAAN
Type - ElementType: Element type Frame-Mll-244
Material: Alumiinium (1) (2)
SEADMED - 02 Tähis: Frame-Mll-244
AC_Pset_RenovationAndPhasing - Renovation Status: New

# IfcBuildingElementProxy: Frame-Mll-245, Alumiinium (1); Objekti nimi: Frame 22
In: KATUSEPLAAN
Type - ElementType: Element type Frame-Mll-245
Material: Alumiinium (1) (2)
SEADMED - 02 Tähis: Frame-Mll-245
AC_Pset_RenovationAndPhasing - Renovation Status: New

# IfcBuildingElementProxy: Frame-Mll-246, Alumiinium (1); Objekti nimi: Frame 22
In: KATUSEPLAAN
Type - ElementType: Element type Frame-Mll-246
Material: Alumiinium (1) (2)
SEADMED - 02 Tähis: Frame-Mll-246
AC_Pset_RenovationAndPhasing - Renovation Status: New

# IfcBuildingElementProxy: Frame-Mll-247, Alumiinium (1); Objekti nimi: Frame 22
In: KATUSEPLAAN
Type - ElementType: Element type Frame-Mll-247
Material: Alumiinium (1) (2)
SEADMED - 02 Tähis: Frame-Mll-247
AC_Pset_RenovationAndPhasing - Renovation Status: New

# IfcBuildingElementProxy: Frame-Mll-248, Alumiinium (1); Objekti nimi: Frame 22
In: KATUSEPLAAN
Type - ElementType: Element type Frame-Mll-248
Material: Alumiinium (1) (2)
SEADMED - 02 Tähis: Frame-Mll-248
AC_Pset_RenovationAndPhasing - Renovation Status: New

# IfcBuildingElementProxy: Frame-Mll-249, Alumiinium (1); Objekti nimi: Frame 22
In: KATUSEPLAAN
Type - ElementType: Element type Frame-Mll-249
Material: Alumiinium (1) (2)
SEADMED - 02 Tähis: Frame-Mll-249
AC_Pset_RenovationAndPhasing - Renovation Status: New

# IfcBuildingElementProxy: Frame-Mll-250, Alumiinium (1); Objekti nimi: Frame 22
In: KATUSEPLAAN
Type - ElementType: Element type Frame-Mll-250
Material: Alumiinium (1) (2)
SEADMED - 02 Tähis: Frame-Mll-250
AC_Pset_RenovationAndPhasing - Renovation Status: New

# IfcBuildingElementProxy: Frame-Mll-251, Alumiinium (1); Objekti nimi: Frame 22
In: KATUSEPLAAN
Type - ElementType: Element type Frame-Mll-251
Material: Alumiinium (1) (2)
SEADMED - 02 Tähis: Frame-Mll-251
AC_Pset_RenovationAndPhasing - Renovation Status: New

# IfcBuildingElementProxy: Frame-Mll-252, Alumiinium (1); Objekti nimi: Frame 22
In: KATUSEPLAAN
Type - ElementType: Element type Frame-Mll-252
Material: Alumiinium (1) (2)
SEADMED - 02 Tähis: Frame-Mll-252
AC_Pset_RenovationAndPhasing - Renovation Status: New

# IfcBuildingElementProxy: Frame-Mll-253, Alumiinium (1); Objekti nimi: Frame 22
In: KATUSEPLAAN
Type - ElementType: Element type Frame-Mll-253
Material: Alumiinium (1) (2)
SEADMED - 02 Tähis: Frame-Mll-253
AC_Pset_RenovationAndPhasing - Renovation Status: New

# IfcBuildingElementProxy: Frame-Mll-254, Alumiinium (1); Objekti nimi: Frame 22
In: KATUSEPLAAN
Type - ElementType: Element type Frame-Mll-254
Material: Alumiinium (1) (2)
SEADMED - 02 Tähis: Frame-Mll-254
AC_Pset_RenovationAndPhasing - Renovation Status: New

# IfcBuildingElementProxy: Frame-Mll-255, Alumiinium (1); Objekti nimi: Frame 22
In: KATUSEPLAAN
Type - ElementType: Element type Frame-Mll-255
Material: Alumiinium (1) (2)
SEADMED - 02 Tähis: Frame-Mll-255
AC_Pset_RenovationAndPhasing - Renovation Status: New

# IfcBuildingElementProxy: Frame-Mll-256, Alumiinium (1); Objekti nimi: Frame 22
In: KATUSEPLAAN
Type - ElementType: Element type Frame-Mll-256
Material: Alumiinium (1) (2)
SEADMED - 02 Tähis: Frame-Mll-256
AC_Pset_RenovationAndPhasing - Renovation Status: New

# IfcBuildingElementProxy: Frame-Mll-257, Alumiinium (1); Objekti nimi: Frame 22
In: KATUSEPLAAN
Type - ElementType: Element type Frame-Mll-257
Material: Alumiinium (1) (2)
SEADMED - 02 Tähis: Frame-Mll-257
AC_Pset_RenovationAndPhasing - Renovation Status: New

# IfcBuildingElementProxy: Frame-Mll-258, Alumiinium (1); Objekti nimi: Frame 22
In: KATUSEPLAAN
Type - ElementType: Element type Frame-Mll-258
Material: Alumiinium (1) (2)
SEADMED - 02 Tähis: Frame-Mll-258
AC_Pset_RenovationAndPhasing - Renovation Status: New

# IfcBuildingElementProxy: Frame-Mll-259, Alumiinium (1); Objekti nimi: Frame 22
In: KATUSEPLAAN
Type - ElementType: Element type Frame-Mll-259
Material: Alumiinium (1) (2)
SEADMED - 02 Tähis: Frame-Mll-259
AC_Pset_RenovationAndPhasing - Renovation Status: New

# IfcBuildingElementProxy: Frame-Mll-260, Alumiinium (1); Objekti nimi: Frame 22
In: KATUSEPLAAN
Type - ElementType: Element type Frame-Mll-260
Material: Alumiinium (1) (2)
SEADMED - 02 Tähis: Frame-Mll-260
AC_Pset_RenovationAndPhasing - Renovation Status: New

# IfcBuildingElementProxy: Frame-Mll-261, Alumiinium (1); Objekti nimi: Frame 22
In: KATUSEPLAAN
Type - ElementType: Element type Frame-Mll-261
Material: Alumiinium (1) (2)
SEADMED - 02 Tähis: Frame-Mll-261
AC_Pset_RenovationAndPhasing - Renovation Status: New

# IfcBuildingElementProxy: Frame-Mll-262, Alumiinium (1); Objekti nimi: Frame 22
In: KATUSEPLAAN
Type - ElementType: Element type Frame-Mll-262
Material: Alumiinium (1) (2)
SEADMED - 02 Tähis: Frame-Mll-262
AC_Pset_RenovationAndPhasing - Renovation Status: New

# IfcBuildingElementProxy: Frame-Mll-552, Alumiinium (1); Objekti nimi: Frame 22
In: 2 KORRUS
Type - ElementType: Element type Frame-Mll-552
Material: Alumiinium (1) (2)
SEADMED - 02 Tähis: Frame-Mll-552
AC_Pset_RenovationAndPhasing - Renovation Status: New

# IfcBuildingElementProxy: Frame-Mll-553, Alumiinium (1); Objekti nimi: Frame 22
In: 2 KORRUS
Type - ElementType: Element type Frame-Mll-553
Material: Alumiinium (1) (2)
SEADMED - 02 Tähis: Frame-Mll-553
AC_Pset_RenovationAndPhasing - Renovation Status: New

# IfcBuildingElementProxy: Frame-Mll-554, Alumiinium (1); Objekti nimi: Frame 22
In: 2 KORRUS
Type - ElementType: Element type Frame-Mll-554
Material: Alumiinium (1) (2)
SEADMED - 02 Tähis: Frame-Mll-554
AC_Pset_RenovationAndPhasing - Renovation Status: New

# IfcBuildingElementProxy: Frame-Mll-555, Alumiinium (1); Objekti nimi: Frame 22
In: 2 KORRUS
Type - ElementType: Element type Frame-Mll-555
Material: Alumiinium (1) (2)
SEADMED - 02 Tähis: Frame-Mll-555
AC_Pset_RenovationAndPhasing - Renovation Status: New

# IfcBuildingElementProxy: Frame-Mll-556, Alumiinium (1); Objekti nimi: Frame 22
In: 2 KORRUS
Type - ElementType: Element type Frame-Mll-556
Material: Alumiinium (1) (2)
SEADMED - 02 Tähis: Frame-Mll-556
AC_Pset_RenovationAndPhasing - Renovation Status: New

# IfcBuildingElementProxy: Frame-Mll-557, Alumiinium (1); Objekti nimi: Frame 22
In: 2 KORRUS
Type - ElementType: Element type Frame-Mll-557
Material: Alumiinium (1) (2)
SEADMED - 02 Tähis: Frame-Mll-557
AC_Pset_RenovationAndPhasing - Renovation Status: New

# IfcBuildingElementProxy: Frame-Mll-558, Alumiinium (1); Objekti nimi: Frame 22
In: 2 KORRUS
Type - ElementType: Element type Frame-Mll-558
Material: Alumiinium (1) (2)
SEADMED - 02 Tähis: Frame-Mll-558
AC_Pset_RenovationAndPhasing - Renovation Status: New

# IfcBuildingElementProxy: Frame-Mll-559, Alumiinium (1); Objekti nimi: Frame 22
In: 2 KORRUS
Type - ElementType: Element type Frame-Mll-559
Material: Alumiinium (1) (2)
SEADMED - 02 Tähis: Frame-Mll-559
AC_Pset_RenovationAndPhasing - Renovation Status: New

# IfcBuildingElementProxy: Frame-Mll-560, Alumiinium (1); Objekti nimi: Frame 22
In: 2 KORRUS
Type - ElementType: Element type Frame-Mll-560
Material: Alumiinium (1) (2)
SEADMED - 02 Tähis: Frame-Mll-560
AC_Pset_RenovationAndPhasing - Renovation Status: New

# IfcBuildingElementProxy: Frame-Mll-561 (2)
Type - ElementType: Element type Frame-Mll-561
Material: Alumiinium (1) (2)
SEADMED - 02 Tähis: Frame-Mll-561
AC_Pset_RenovationAndPhasing - Renovation Status: New
Name (Alumiinium (1); Objekti nimi:...) | In
 Frame 22 | 2 KORRUS
 Frame 22 | KATUSEPLAAN

# IfcBuildingElementProxy: Frame-Mll-565, Alumiinium (1); Objekti nimi: Frame 22
In: KATUSEPLAAN
Type - ElementType: Element type Frame-Mll-565
Material: Alumiinium (1) (2)
SEADMED - 02 Tähis: Frame-Mll-565
AC_Pset_RenovationAndPhasing - Renovation Status: New

# IfcBuildingElementProxy: Frame-Mll-569, Alumiinium (1); Objekti nimi: Frame 22
In: KATUSEPLAAN
Type - ElementType: Element type Frame-Mll-569
Material: Alumiinium (1) (2)
SEADMED - 02 Tähis: Frame-Mll-569
AC_Pset_RenovationAndPhasing - Renovation Status: New

# IfcBuildingElementProxy: Frame-Mll-573, Alumiinium (1); Objekti nimi: Frame 22
In: KATUSEPLAAN
Type - ElementType: Element type Frame-Mll-573
Material: Alumiinium (1) (2)
SEADMED - 02 Tähis: Frame-Mll-573
AC_Pset_RenovationAndPhasing - Renovation Status: New

# IfcBuildingElementProxy: Frame-Mll-577, Alumiinium (1); Objekti nimi: Frame 22
In: KATUSEPLAAN
Type - ElementType: Element type Frame-Mll-577
Material: Alumiinium (1) (2)
SEADMED - 02 Tähis: Frame-Mll-577
AC_Pset_RenovationAndPhasing - Renovation Status: New

# IfcBuildingElementProxy: Frame-Mll-578, Alumiinium (1); Objekti nimi: Frame 22
In: 2 KORRUS
Type - ElementType: Element type Frame-Mll-578
Material: Alumiinium (1) (2)
SEADMED - 02 Tähis: Frame-Mll-578
AC_Pset_RenovationAndPhasing - Renovation Status: New

# IfcBuildingElementProxy: Frame-Mll-579, Alumiinium (1); Objekti nimi: Frame 22
In: KATUSEPLAAN
Type - ElementType: Element type Frame-Mll-579
Material: Alumiinium (1) (2)
SEADMED - 02 Tähis: Frame-Mll-579
AC_Pset_RenovationAndPhasing - Renovation Status: New

# IfcBuildingElementProxy: Frame-Mll-581, Alumiinium (1); Objekti nimi: Frame 22
In: KATUSEPLAAN
Type - ElementType: Element type Frame-Mll-581
Material: Alumiinium (1) (2)
SEADMED - 02 Tähis: Frame-Mll-581
AC_Pset_RenovationAndPhasing - Renovation Status: New

# IfcBuildingElementProxy: Frame-Mll-585, Alumiinium (1); Objekti nimi: Frame 22
In: KATUSEPLAAN
Type - ElementType: Element type Frame-Mll-585
Material: Alumiinium (1) (2)
SEADMED - 02 Tähis: Frame-Mll-585
AC_Pset_RenovationAndPhasing - Renovation Status: New

# IfcBuildingElementProxy: Frame-Mll-586, Alumiinium (1); Objekti nimi: Frame 22
In: KATUSEPLAAN
Type - ElementType: Element type Frame-Mll-586
Material: Alumiinium (1) (2)
SEADMED - 02 Tähis: Frame-Mll-586
AC_Pset_RenovationAndPhasing - Renovation Status: New

# IfcBuildingElementProxy: Frame-Mll-587, Alumiinium (1); Objekti nimi: Frame 22
In: KATUSEPLAAN
Type - ElementType: Element type Frame-Mll-587
Material: Alumiinium (1) (2)
SEADMED - 02 Tähis: Frame-Mll-587
AC_Pset_RenovationAndPhasing - Renovation Status: New

# IfcBuildingElementProxy: Frame-Mll-588 (12)
Type - ElementType: Element type Frame-Mll-588
Material: Alumiinium (1) (2)
SEADMED - 02 Tähis: Frame-Mll-588
AC_Pset_RenovationAndPhasing - Renovation Status: New
Name (Alumiinium (1); Objekti nimi:...) | In
11 x  Frame 22 | 2 KORRUS
 Frame 22 | KATUSEPLAAN

# IfcBuildingElementProxy: Frame-Mll-589, Alumiinium (1); Objekti nimi: Frame 22
In: KATUSEPLAAN
Type - ElementType: Element type Frame-Mll-589
Material: Alumiinium (1) (2)
SEADMED - 02 Tähis: Frame-Mll-589
AC_Pset_RenovationAndPhasing - Renovation Status: New

# IfcBuildingElementProxy: Frame-Mll-590, Alumiinium (1); Objekti nimi: Frame 22
In: KATUSEPLAAN
Type - ElementType: Element type Frame-Mll-590
Material: Alumiinium (1) (2)
SEADMED - 02 Tähis: Frame-Mll-590
AC_Pset_RenovationAndPhasing - Renovation Status: New

# IfcBuildingElementProxy: Frame-Mll-591, Alumiinium (1); Objekti nimi: Frame 22
In: KATUSEPLAAN
Type - ElementType: Element type Frame-Mll-591
Material: Alumiinium (1) (2)
SEADMED - 02 Tähis: Frame-Mll-591
AC_Pset_RenovationAndPhasing - Renovation Status: New

# IfcBuildingElementProxy: Frame-Mll-592, Alumiinium (1); Objekti nimi: Frame 22
In: KATUSEPLAAN
Type - ElementType: Element type Frame-Mll-592
Material: Alumiinium (1) (2)
SEADMED - 02 Tähis: Frame-Mll-592
AC_Pset_RenovationAndPhasing - Renovation Status: New

# IfcBuildingElementProxy: Frame-Mll-593, Alumiinium (1); Objekti nimi: Frame 22
In: KATUSEPLAAN
Type - ElementType: Element type Frame-Mll-593
Material: Alumiinium (1) (2)
SEADMED - 02 Tähis: Frame-Mll-593
AC_Pset_RenovationAndPhasing - Renovation Status: New

# IfcBuildingElementProxy: Frame-Mll-594, Alumiinium (1); Objekti nimi: Frame 22
In: KATUSEPLAAN
Type - ElementType: Element type Frame-Mll-594
Material: Alumiinium (1) (2)
SEADMED - 02 Tähis: Frame-Mll-594
AC_Pset_RenovationAndPhasing - Renovation Status: New

# IfcBuildingElementProxy: Frame-Mll-595 (2)
Type - ElementType: Element type Frame-Mll-595
SEADMED - 02 Tähis: Frame-Mll-595
AC_Pset_RenovationAndPhasing - Renovation Status: New
Name (Alumiinium (1); Objekti nimi:...) | In | Material
 Frame 22 | 1 KORRUS | Alumiinium (1)
 Frame 22 | KATUSEPLAAN | Alumiinium (1) (2)

# IfcBuildingElementProxy: Frame-Mll-596 (2)
Type - ElementType: Element type Frame-Mll-596
SEADMED - 02 Tähis: Frame-Mll-596
AC_Pset_RenovationAndPhasing - Renovation Status: New
Name (Alumiinium (1); Objekti nimi:...) | In | Material
 Frame 22 | 1 KORRUS | Alumiinium (1)
 Frame 22 | KATUSEPLAAN | Alumiinium (1) (2)

# IfcBuildingElementProxy: Frame-Mll-597, Alumiinium (1); Objekti nimi: Frame 22
In: KATUSEPLAAN
Type - ElementType: Element type Frame-Mll-597
Material: Alumiinium (1) (2)
SEADMED - 02 Tähis: Frame-Mll-597
AC_Pset_RenovationAndPhasing - Renovation Status: New

# IfcBuildingElementProxy: Frame-Mll-598, Alumiinium (1); Objekti nimi: Frame 22
In: KATUSEPLAAN
Type - ElementType: Element type Frame-Mll-598
Material: Alumiinium (1) (2)
SEADMED - 02 Tähis: Frame-Mll-598
AC_Pset_RenovationAndPhasing - Renovation Status: New

# IfcBuildingElementProxy: Frame-Mll-599, Alumiinium (1); Objekti nimi: Frame 22
In: KATUSEPLAAN
Type - ElementType: Element type Frame-Mll-599
Material: Alumiinium (1) (2)
SEADMED - 02 Tähis: Frame-Mll-599
AC_Pset_RenovationAndPhasing - Renovation Status: New

# IfcBuildingElementProxy: Frame-Mll-600, Alumiinium (1); Objekti nimi: Frame 22
In: KATUSEPLAAN
Type - ElementType: Element type Frame-Mll-600
Material: Alumiinium (1) (2)
SEADMED - 02 Tähis: Frame-Mll-600
AC_Pset_RenovationAndPhasing - Renovation Status: New

# IfcBuildingElementProxy: Frame-Mll-601, Alumiinium (1); Objekti nimi: Frame 22
In: KATUSEPLAAN
Type - ElementType: Element type Frame-Mll-601
Material: Alumiinium (1) (2)
SEADMED - 02 Tähis: Frame-Mll-601
AC_Pset_RenovationAndPhasing - Renovation Status: New

# IfcBuildingElementProxy: Frame-Mll-602, Alumiinium (1); Objekti nimi: Frame 22
In: KATUSEPLAAN
Type - ElementType: Element type Frame-Mll-602
Material: Alumiinium (1) (2)
SEADMED - 02 Tähis: Frame-Mll-602
AC_Pset_RenovationAndPhasing - Renovation Status: New

# IfcBuildingElementProxy: Frame-Mll-603 (2)
Type - ElementType: Element type Frame-Mll-603
SEADMED - 02 Tähis: Frame-Mll-603
AC_Pset_RenovationAndPhasing - Renovation Status: New
Name (Alumiinium (1); Objekti nimi:...) | In | Material
 Frame 22 | 1 KORRUS | Alumiinium (1)
 Frame 22 | KATUSEPLAAN | Alumiinium (1) (2)

# IfcBuildingElementProxy: Frame-Mll-604, Alumiinium (1); Objekti nimi: Frame 22
In: KATUSEPLAAN
Type - ElementType: Element type Frame-Mll-604
Material: Alumiinium (1) (2)
SEADMED - 02 Tähis: Frame-Mll-604
AC_Pset_RenovationAndPhasing - Renovation Status: New

# IfcBuildingElementProxy: Frame-Mll-605, Alumiinium (1); Objekti nimi: Frame 22
In: KATUSEPLAAN
Type - ElementType: Element type Frame-Mll-605
Material: Alumiinium (1) (2)
SEADMED - 02 Tähis: Frame-Mll-605
AC_Pset_RenovationAndPhasing - Renovation Status: New

# IfcBuildingElementProxy: Frame-Mll-606, Alumiinium (1); Objekti nimi: Frame 22
In: KATUSEPLAAN
Type - ElementType: Element type Frame-Mll-606
Material: Alumiinium (1) (2)
SEADMED - 02 Tähis: Frame-Mll-606
AC_Pset_RenovationAndPhasing - Renovation Status: New

# IfcBuildingElementProxy: Frame-Mll-607, Alumiinium (1); Objekti nimi: Frame 22
In: KATUSEPLAAN
Type - ElementType: Element type Frame-Mll-607
Material: Alumiinium (1) (2)
SEADMED - 02 Tähis: Frame-Mll-607
AC_Pset_RenovationAndPhasing - Renovation Status: New

# IfcBuildingElementProxy: Frame-Mll-631, Alumiinium (1); Objekti nimi: Frame 22
In: 1 KORRUS
Type - ElementType: Element type Frame-Mll-631
Material: Alumiinium (1)
SEADMED - 02 Tähis: Frame-Mll-631
AC_Pset_RenovationAndPhasing - Renovation Status: New

# IfcBuildingElementProxy: Frame-Mll-632, Alumiinium (1); Objekti nimi: Frame 22
In: 1 KORRUS
Type - ElementType: Element type Frame-Mll-632
Material: Alumiinium (1)
SEADMED - 02 Tähis: Frame-Mll-632
AC_Pset_RenovationAndPhasing - Renovation Status: New

# IfcBuildingElementProxy: Frame-Mll-633, Alumiinium (1); Objekti nimi: Frame 22
In: 1 KORRUS
Type - ElementType: Element type Frame-Mll-633
Material: Alumiinium (1)
SEADMED - 02 Tähis: Frame-Mll-633
AC_Pset_RenovationAndPhasing - Renovation Status: New

# IfcBuildingElementProxy: Frame-Mll-658, Alumiinium (1); Objekti nimi: Frame 22
In: 1 KORRUS
Type - ElementType: Element type Frame-Mll-658
Material: Alumiinium (1)
SEADMED - 02 Tähis: Frame-Mll-658
AC_Pset_RenovationAndPhasing - Renovation Status: New

# IfcBuildingElementProxy: Frame-Mll-659, Alumiinium (1); Objekti nimi: Frame 22
In: 1 KORRUS
Type - ElementType: Element type Frame-Mll-659
Material: Alumiinium (1)
SEADMED - 02 Tähis: Frame-Mll-659
AC_Pset_RenovationAndPhasing - Renovation Status: New

# IfcBuildingElementProxy: Frame-Mll-869, Alumiinium (1); Objekti nimi: Frame 22
In: KATUSEPLAAN
Type - ElementType: Element type Frame-Mll-869
Material: Alumiinium (1) (2)
SEADMED - 02 Tähis: Frame-Mll-869
AC_Pset_RenovationAndPhasing - Renovation Status: New

# IfcBuildingElementProxy: Frame-Mll-870, Alumiinium (1); Objekti nimi: Frame 22
In: KATUSEPLAAN
Type - ElementType: Element type Frame-Mll-870
Material: Alumiinium (1) (2)
SEADMED - 02 Tähis: Frame-Mll-870
AC_Pset_RenovationAndPhasing - Renovation Status: New

# IfcBuildingElementProxy: Frame-Mll-871, Alumiinium (1); Objekti nimi: Frame 22
In: KATUSEPLAAN
Type - ElementType: Element type Frame-Mll-871
Material: Alumiinium (1) (2)
SEADMED - 02 Tähis: Frame-Mll-871
AC_Pset_RenovationAndPhasing - Renovation Status: New

# IfcBuildingElementProxy: Frame-Mll-872, Alumiinium (1); Objekti nimi: Frame 22
In: KATUSEPLAAN
Type - ElementType: Element type Frame-Mll-872
Material: Alumiinium (1) (2)
SEADMED - 02 Tähis: Frame-Mll-872
AC_Pset_RenovationAndPhasing - Renovation Status: New

# IfcBuildingElementProxy: Frame-Mll-873, Alumiinium (1); Objekti nimi: Frame 22
In: KATUSEPLAAN
Type - ElementType: Element type Frame-Mll-873
Material: Alumiinium (1) (2)
SEADMED - 02 Tähis: Frame-Mll-873
AC_Pset_RenovationAndPhasing - Renovation Status: New

# IfcBuildingElementProxy: Frame-Mll-874, Alumiinium (1); Objekti nimi: Frame 22
In: KATUSEPLAAN
Type - ElementType: Element type Frame-Mll-874
Material: Alumiinium (1) (2)
SEADMED - 02 Tähis: Frame-Mll-874
AC_Pset_RenovationAndPhasing - Renovation Status: New

# IfcBuildingElementProxy: Frame-Mll-875, Alumiinium (1); Objekti nimi: Frame 22
In: KATUSEPLAAN
Type - ElementType: Element type Frame-Mll-875
Material: Alumiinium (1) (2)
SEADMED - 02 Tähis: Frame-Mll-875
AC_Pset_RenovationAndPhasing - Renovation Status: New

# IfcBuildingElementProxy: Frame-Mll-876, Alumiinium (1); Objekti nimi: Frame 22
In: KATUSEPLAAN
Type - ElementType: Element type Frame-Mll-876
Material: Alumiinium (1) (2)
SEADMED - 02 Tähis: Frame-Mll-876
AC_Pset_RenovationAndPhasing - Renovation Status: New

# IfcBuildingElementProxy: Frame-Mll-877, Alumiinium (1); Objekti nimi: Frame 22
In: KATUSEPLAAN
Type - ElementType: Element type Frame-Mll-877
Material: Alumiinium (1) (2)
SEADMED - 02 Tähis: Frame-Mll-877
AC_Pset_RenovationAndPhasing - Renovation Status: New

# IfcBuildingElementProxy: Frame-Mll-878, Alumiinium (1); Objekti nimi: Frame 22
In: KATUSEPLAAN
Type - ElementType: Element type Frame-Mll-878
Material: Alumiinium (1) (2)
SEADMED - 02 Tähis: Frame-Mll-878
AC_Pset_RenovationAndPhasing - Renovation Status: New

# IfcBuildingElementProxy: Frame-Mll-879, Alumiinium (1); Objekti nimi: Frame 22
In: KATUSEPLAAN
Type - ElementType: Element type Frame-Mll-879
Material: Alumiinium (1) (2)
SEADMED - 02 Tähis: Frame-Mll-879
AC_Pset_RenovationAndPhasing - Renovation Status: New

# IfcBuildingElementProxy: Frame-Mll-880, Alumiinium (1); Objekti nimi: Frame 22
In: KATUSEPLAAN
Type - ElementType: Element type Frame-Mll-880
Material: Alumiinium (1) (2)
SEADMED - 02 Tähis: Frame-Mll-880
AC_Pset_RenovationAndPhasing - Renovation Status: New

# IfcBuildingElementProxy: Frame-Mll-881, Alumiinium (1); Objekti nimi: Frame 22
In: KATUSEPLAAN
Type - ElementType: Element type Frame-Mll-881
Material: Alumiinium (1) (2)
SEADMED - 02 Tähis: Frame-Mll-881
AC_Pset_RenovationAndPhasing - Renovation Status: New

# IfcBuildingElementProxy: Frame-Mll-882, Alumiinium (1); Objekti nimi: Frame 22
In: KATUSEPLAAN
Type - ElementType: Element type Frame-Mll-882
Material: Alumiinium (1) (2)
SEADMED - 02 Tähis: Frame-Mll-882
AC_Pset_RenovationAndPhasing - Renovation Status: New

# IfcBuildingElementProxy: Frame-Mll-883, Alumiinium (1); Objekti nimi: Frame 22
In: KATUSEPLAAN
Type - ElementType: Element type Frame-Mll-883
Material: Alumiinium (1) (2)
SEADMED - 02 Tähis: Frame-Mll-883
AC_Pset_RenovationAndPhasing - Renovation Status: New

# IfcBuildingElementProxy: Frame-Mll-884, Alumiinium (1); Objekti nimi: Frame 22
In: KATUSEPLAAN
Type - ElementType: Element type Frame-Mll-884
Material: Alumiinium (1) (2)
SEADMED - 02 Tähis: Frame-Mll-884
AC_Pset_RenovationAndPhasing - Renovation Status: New

# IfcBuildingElementProxy: Frame-Mll-885, Alumiinium (1); Objekti nimi: Frame 22
In: KATUSEPLAAN
Type - ElementType: Element type Frame-Mll-885
Material: Alumiinium (1) (2)
SEADMED - 02 Tähis: Frame-Mll-885
AC_Pset_RenovationAndPhasing - Renovation Status: New

# IfcBuildingElementProxy: Frame-Mll-886, Alumiinium (1); Objekti nimi: Frame 22
In: KATUSEPLAAN
Type - ElementType: Element type Frame-Mll-886
Material: Alumiinium (1) (2)
SEADMED - 02 Tähis: Frame-Mll-886
AC_Pset_RenovationAndPhasing - Renovation Status: New

# IfcBuildingElementProxy: Frame-Mll-887, Alumiinium (1); Objekti nimi: Frame 22
In: KATUSEPLAAN
Type - ElementType: Element type Frame-Mll-887
Material: Alumiinium (1) (2)
SEADMED - 02 Tähis: Frame-Mll-887
AC_Pset_RenovationAndPhasing - Renovation Status: New

# IfcBuildingElementProxy: Frame-Mll-888, Alumiinium (1); Objekti nimi: Frame 22
In: KATUSEPLAAN
Type - ElementType: Element type Frame-Mll-888
Material: Alumiinium (1) (2)
SEADMED - 02 Tähis: Frame-Mll-888
AC_Pset_RenovationAndPhasing - Renovation Status: New

# IfcBuildingElementProxy: Frame-Mll-889, Alumiinium (1); Objekti nimi: Frame 22
In: KATUSEPLAAN
Type - ElementType: Element type Frame-Mll-889
Material: Alumiinium (1) (2)
SEADMED - 02 Tähis: Frame-Mll-889
AC_Pset_RenovationAndPhasing - Renovation Status: New

# IfcBuildingElementProxy: Frame-Mll-890, Alumiinium (1); Objekti nimi: Frame 22
In: KATUSEPLAAN
Type - ElementType: Element type Frame-Mll-890
Material: Alumiinium (1) (2)
SEADMED - 02 Tähis: Frame-Mll-890
AC_Pset_RenovationAndPhasing - Renovation Status: New

# IfcBuildingElementProxy: Frame-Mll-891, Alumiinium (1); Objekti nimi: Frame 22
In: KATUSEPLAAN
Type - ElementType: Element type Frame-Mll-891
Material: Alumiinium (1) (2)
SEADMED - 02 Tähis: Frame-Mll-891
AC_Pset_RenovationAndPhasing - Renovation Status: New

# IfcBuildingElementProxy: Frame-Mll-993, Alumiinium (1); Objekti nimi: Frame 22
In: KATUSEPLAAN
Type - ElementType: Element type Frame-Mll-993
Material: Alumiinium (1) (2)
SEADMED - 02 Tähis: Frame-Mll-993
AC_Pset_RenovationAndPhasing - Renovation Status: New

# IfcBuildingElementProxy: Frame-Mll-994, Alumiinium (1); Objekti nimi: Frame 22
In: KATUSEPLAAN
Type - ElementType: Element type Frame-Mll-994
Material: Alumiinium (1) (2)
SEADMED - 02 Tähis: Frame-Mll-994
AC_Pset_RenovationAndPhasing - Renovation Status: New

# IfcBuildingElementProxy: Frame-Mll-995, Alumiinium (1); Objekti nimi: Frame 22
In: KATUSEPLAAN
Type - ElementType: Element type Frame-Mll-995
Material: Alumiinium (1) (2)
SEADMED - 02 Tähis: Frame-Mll-995
AC_Pset_RenovationAndPhasing - Renovation Status: New

# IfcBuildingElementProxy: Frame-Mll-996, Alumiinium (1); Objekti nimi: Frame 22
In: KATUSEPLAAN
Type - ElementType: Element type Frame-Mll-996
Material: Alumiinium (1) (2)
SEADMED - 02 Tähis: Frame-Mll-996
AC_Pset_RenovationAndPhasing - Renovation Status: New

# IfcBuildingElementProxy: Frame-Mll-997, Alumiinium (1); Objekti nimi: Frame 22
In: KATUSEPLAAN
Type - ElementType: Element type Frame-Mll-997
Material: Alumiinium (1) (2)
SEADMED - 02 Tähis: Frame-Mll-997
AC_Pset_RenovationAndPhasing - Renovation Status: New

# IfcBuildingElementProxy: Frame-Mll-998, Alumiinium (1); Objekti nimi: Frame 22
In: KATUSEPLAAN
Type - ElementType: Element type Frame-Mll-998
Material: Alumiinium (1) (2)
SEADMED - 02 Tähis: Frame-Mll-998
AC_Pset_RenovationAndPhasing - Renovation Status: New

# IfcBuildingElementProxy: Frame-Mll-999, Alumiinium (1); Objekti nimi: Frame 22
In: KATUSEPLAAN
Type - ElementType: Element type Frame-Mll-999
Material: Alumiinium (1) (2)
SEADMED - 02 Tähis: Frame-Mll-999
AC_Pset_RenovationAndPhasing - Renovation Status: New

# IfcBuildingElementProxy: Frame-Trs-171, Alumiinium (1); Objekti nimi: Frame 22
In: KATUSEPLAAN
Type - ElementType: Element type Frame-Trs-171
Material: Alumiinium (1) (2)
SEADMED - 02 Tähis: Frame-Trs-171
AC_Pset_RenovationAndPhasing - Renovation Status: New

# IfcBuildingElementProxy: Frame-Trs-172, Alumiinium (1); Objekti nimi: Frame 22
In: KATUSEPLAAN
Type - ElementType: Element type Frame-Trs-172
Material: Alumiinium (1) (2)
SEADMED - 02 Tähis: Frame-Trs-172
AC_Pset_RenovationAndPhasing - Renovation Status: New

# IfcBuildingElementProxy: Frame-Trs-173, Alumiinium (1); Objekti nimi: Frame 22
In: KATUSEPLAAN
Type - ElementType: Element type Frame-Trs-173
Material: Alumiinium (1) (2)
SEADMED - 02 Tähis: Frame-Trs-173
AC_Pset_RenovationAndPhasing - Renovation Status: New

# IfcBuildingElementProxy: Frame-Trs-174, Alumiinium (1); Objekti nimi: Frame 22
In: KATUSEPLAAN
Type - ElementType: Element type Frame-Trs-174
Material: Alumiinium (1) (2)
SEADMED - 02 Tähis: Frame-Trs-174
AC_Pset_RenovationAndPhasing - Renovation Status: New

# IfcBuildingElementProxy: Frame-Trs-175, Alumiinium (1); Objekti nimi: Frame 22
In: KATUSEPLAAN
Type - ElementType: Element type Frame-Trs-175
Material: Alumiinium (1) (2)
SEADMED - 02 Tähis: Frame-Trs-175
AC_Pset_RenovationAndPhasing - Renovation Status: New

# IfcBuildingElementProxy: Frame-Trs-176, Alumiinium (1); Objekti nimi: Frame 22
In: KATUSEPLAAN
Type - ElementType: Element type Frame-Trs-176
Material: Alumiinium (1) (2)
SEADMED - 02 Tähis: Frame-Trs-176
AC_Pset_RenovationAndPhasing - Renovation Status: New

# IfcBuildingElementProxy: Frame-Trs-177, Alumiinium (1); Objekti nimi: Frame 22
In: KATUSEPLAAN
Type - ElementType: Element type Frame-Trs-177
Material: Alumiinium (1) (2)
SEADMED - 02 Tähis: Frame-Trs-177
AC_Pset_RenovationAndPhasing - Renovation Status: New

# IfcBuildingElementProxy: Frame-Trs-178, Alumiinium (1); Objekti nimi: Frame 22
In: KATUSEPLAAN
Type - ElementType: Element type Frame-Trs-178
Material: Alumiinium (1) (2)
SEADMED - 02 Tähis: Frame-Trs-178
AC_Pset_RenovationAndPhasing - Renovation Status: New

# IfcBuildingElementProxy: Frame-Trs-179, Alumiinium (1); Objekti nimi: Frame 22
In: KATUSEPLAAN
Type - ElementType: Element type Frame-Trs-179
Material: Alumiinium (1) (2)
SEADMED - 02 Tähis: Frame-Trs-179
AC_Pset_RenovationAndPhasing - Renovation Status: New

# IfcBuildingElementProxy: Frame-Trs-180, Alumiinium (1); Objekti nimi: Frame 22
In: KATUSEPLAAN
Type - ElementType: Element type Frame-Trs-180
Material: Alumiinium (1) (2)
SEADMED - 02 Tähis: Frame-Trs-180
AC_Pset_RenovationAndPhasing - Renovation Status: New

# IfcBuildingElementProxy: Frame-Trs-181, Alumiinium (1); Objekti nimi: Frame 22
In: KATUSEPLAAN
Type - ElementType: Element type Frame-Trs-181
Material: Alumiinium (1) (2)
SEADMED - 02 Tähis: Frame-Trs-181
AC_Pset_RenovationAndPhasing - Renovation Status: New

# IfcBuildingElementProxy: Frame-Trs-182, Alumiinium (1); Objekti nimi: Frame 22
In: KATUSEPLAAN
Type - ElementType: Element type Frame-Trs-182
Material: Alumiinium (1) (2)
SEADMED - 02 Tähis: Frame-Trs-182
AC_Pset_RenovationAndPhasing - Renovation Status: New

# IfcBuildingElementProxy: Frame-Trs-183, Alumiinium (1); Objekti nimi: Frame 22
In: KATUSEPLAAN
Type - ElementType: Element type Frame-Trs-183
Material: Alumiinium (1) (2)
SEADMED - 02 Tähis: Frame-Trs-183
AC_Pset_RenovationAndPhasing - Renovation Status: New

# IfcBuildingElementProxy: Frame-Trs-184, Alumiinium (1); Objekti nimi: Frame 22
In: KATUSEPLAAN
Type - ElementType: Element type Frame-Trs-184
Material: Alumiinium (1) (2)
SEADMED - 02 Tähis: Frame-Trs-184
AC_Pset_RenovationAndPhasing - Renovation Status: New

# IfcBuildingElementProxy: Frame-Trs-185, Alumiinium (1); Objekti nimi: Frame 22
In: KATUSEPLAAN
Type - ElementType: Element type Frame-Trs-185
Material: Alumiinium (1) (2)
SEADMED - 02 Tähis: Frame-Trs-185
AC_Pset_RenovationAndPhasing - Renovation Status: New

# IfcBuildingElementProxy: Frame-Trs-186, Alumiinium (1); Objekti nimi: Frame 22
In: KATUSEPLAAN
Type - ElementType: Element type Frame-Trs-186
Material: Alumiinium (1) (2)
SEADMED - 02 Tähis: Frame-Trs-186
AC_Pset_RenovationAndPhasing - Renovation Status: New

# IfcBuildingElementProxy: Frame-Trs-187, Alumiinium (1); Objekti nimi: Frame 22
In: KATUSEPLAAN
Type - ElementType: Element type Frame-Trs-187
Material: Alumiinium (1) (2)
SEADMED - 02 Tähis: Frame-Trs-187
AC_Pset_RenovationAndPhasing - Renovation Status: New

# IfcBuildingElementProxy: Frame-Trs-188, Alumiinium (1); Objekti nimi: Frame 22
In: KATUSEPLAAN
Type - ElementType: Element type Frame-Trs-188
Material: Alumiinium (1) (2)
SEADMED - 02 Tähis: Frame-Trs-188
AC_Pset_RenovationAndPhasing - Renovation Status: New

# IfcBuildingElementProxy: Frame-Trs-189, Alumiinium (1); Objekti nimi: Frame 22
In: KATUSEPLAAN
Type - ElementType: Element type Frame-Trs-189
Material: Alumiinium (1) (2)
SEADMED - 02 Tähis: Frame-Trs-189
AC_Pset_RenovationAndPhasing - Renovation Status: New

# IfcBuildingElementProxy: Frame-Trs-190, Alumiinium (1); Objekti nimi: Frame 22
In: KATUSEPLAAN
Type - ElementType: Element type Frame-Trs-190
Material: Alumiinium (1) (2)
SEADMED - 02 Tähis: Frame-Trs-190
AC_Pset_RenovationAndPhasing - Renovation Status: New

# IfcBuildingElementProxy: Frame-Trs-191, Alumiinium (1); Objekti nimi: Frame 22
In: KATUSEPLAAN
Type - ElementType: Element type Frame-Trs-191
Material: Alumiinium (1) (2)
SEADMED - 02 Tähis: Frame-Trs-191
AC_Pset_RenovationAndPhasing - Renovation Status: New

# IfcBuildingElementProxy: Frame-Trs-192, Alumiinium (1); Objekti nimi: Frame 22
In: KATUSEPLAAN
Type - ElementType: Element type Frame-Trs-192
Material: Alumiinium (1) (2)
SEADMED - 02 Tähis: Frame-Trs-192
AC_Pset_RenovationAndPhasing - Renovation Status: New

# IfcBuildingElementProxy: Frame-Trs-193, Alumiinium (1); Objekti nimi: Frame 22
In: KATUSEPLAAN
Type - ElementType: Element type Frame-Trs-193
Material: Alumiinium (1) (2)
SEADMED - 02 Tähis: Frame-Trs-193
AC_Pset_RenovationAndPhasing - Renovation Status: New

# IfcBuildingElementProxy: Frame-Trs-194, Alumiinium (1); Objekti nimi: Frame 22
In: KATUSEPLAAN
Type - ElementType: Element type Frame-Trs-194
Material: Alumiinium (1) (2)
SEADMED - 02 Tähis: Frame-Trs-194
AC_Pset_RenovationAndPhasing - Renovation Status: New

# IfcBuildingElementProxy: Frame-Trs-195, Alumiinium (1); Objekti nimi: Frame 22
In: KATUSEPLAAN
Type - ElementType: Element type Frame-Trs-195
Material: Alumiinium (1) (2)
SEADMED - 02 Tähis: Frame-Trs-195
AC_Pset_RenovationAndPhasing - Renovation Status: New

# IfcBuildingElementProxy: Frame-Trs-196, Alumiinium (1); Objekti nimi: Frame 22
In: KATUSEPLAAN
Type - ElementType: Element type Frame-Trs-196
Material: Alumiinium (1) (2)
SEADMED - 02 Tähis: Frame-Trs-196
AC_Pset_RenovationAndPhasing - Renovation Status: New

# IfcBuildingElementProxy: Frame-Trs-197, Alumiinium (1); Objekti nimi: Frame 22
In: KATUSEPLAAN
Type - ElementType: Element type Frame-Trs-197
Material: Alumiinium (1) (2)
SEADMED - 02 Tähis: Frame-Trs-197
AC_Pset_RenovationAndPhasing - Renovation Status: New

# IfcBuildingElementProxy: Frame-Trs-198, Alumiinium (1); Objekti nimi: Frame 22
In: KATUSEPLAAN
Type - ElementType: Element type Frame-Trs-198
Material: Alumiinium (1) (2)
SEADMED - 02 Tähis: Frame-Trs-198
AC_Pset_RenovationAndPhasing - Renovation Status: New

# IfcBuildingElementProxy: Frame-Trs-199, Alumiinium (1); Objekti nimi: Frame 22
In: KATUSEPLAAN
Type - ElementType: Element type Frame-Trs-199
Material: Alumiinium (1) (2)
SEADMED - 02 Tähis: Frame-Trs-199
AC_Pset_RenovationAndPhasing - Renovation Status: New

# IfcBuildingElementProxy: Frame-Trs-200, Alumiinium (1); Objekti nimi: Frame 22
In: KATUSEPLAAN
Type - ElementType: Element type Frame-Trs-200
Material: Alumiinium (1) (2)
SEADMED - 02 Tähis: Frame-Trs-200
AC_Pset_RenovationAndPhasing - Renovation Status: New

# IfcBuildingElementProxy: Frame-Trs-201, Alumiinium (1); Objekti nimi: Frame 22
In: KATUSEPLAAN
Type - ElementType: Element type Frame-Trs-201
Material: Alumiinium (1) (2)
SEADMED - 02 Tähis: Frame-Trs-201
AC_Pset_RenovationAndPhasing - Renovation Status: New

# IfcBuildingElementProxy: Frame-Trs-202, Alumiinium (1); Objekti nimi: Frame 22
In: KATUSEPLAAN
Type - ElementType: Element type Frame-Trs-202
Material: Alumiinium (1) (2)
SEADMED - 02 Tähis: Frame-Trs-202
AC_Pset_RenovationAndPhasing - Renovation Status: New

# IfcBuildingElementProxy: Frame-Trs-203, Alumiinium (1); Objekti nimi: Frame 22
In: KATUSEPLAAN
Type - ElementType: Element type Frame-Trs-203
Material: Alumiinium (1) (2)
SEADMED - 02 Tähis: Frame-Trs-203
AC_Pset_RenovationAndPhasing - Renovation Status: New

# IfcBuildingElementProxy: Frame-Trs-204, Alumiinium (1); Objekti nimi: Frame 22
In: KATUSEPLAAN
Type - ElementType: Element type Frame-Trs-204
Material: Alumiinium (1) (2)
SEADMED - 02 Tähis: Frame-Trs-204
AC_Pset_RenovationAndPhasing - Renovation Status: New

# IfcBuildingElementProxy: Frame-Trs-205, Alumiinium (1); Objekti nimi: Frame 22
In: KATUSEPLAAN
Type - ElementType: Element type Frame-Trs-205
Material: Alumiinium (1) (2)
SEADMED - 02 Tähis: Frame-Trs-205
AC_Pset_RenovationAndPhasing - Renovation Status: New

# IfcBuildingElementProxy: Frame-Trs-206, Alumiinium (1); Objekti nimi: Frame 22
In: KATUSEPLAAN
Type - ElementType: Element type Frame-Trs-206
Material: Alumiinium (1) (2)
SEADMED - 02 Tähis: Frame-Trs-206
AC_Pset_RenovationAndPhasing - Renovation Status: New

# IfcBuildingElementProxy: Frame-Trs-207, Alumiinium (1); Objekti nimi: Frame 22
In: KATUSEPLAAN
Type - ElementType: Element type Frame-Trs-207
Material: Alumiinium (1) (2)
SEADMED - 02 Tähis: Frame-Trs-207
AC_Pset_RenovationAndPhasing - Renovation Status: New

# IfcBuildingElementProxy: Frame-Trs-208, Alumiinium (1); Objekti nimi: Frame 22
In: KATUSEPLAAN
Type - ElementType: Element type Frame-Trs-208
Material: Alumiinium (1) (2)
SEADMED - 02 Tähis: Frame-Trs-208
AC_Pset_RenovationAndPhasing - Renovation Status: New

# IfcBuildingElementProxy: Frame-Trs-209, Alumiinium (1); Objekti nimi: Frame 22
In: KATUSEPLAAN
Type - ElementType: Element type Frame-Trs-209
Material: Alumiinium (1) (2)
SEADMED - 02 Tähis: Frame-Trs-209
AC_Pset_RenovationAndPhasing - Renovation Status: New

# IfcBuildingElementProxy: Frame-Trs-210, Alumiinium (1); Objekti nimi: Frame 22
In: KATUSEPLAAN
Type - ElementType: Element type Frame-Trs-210
Material: Alumiinium (1) (2)
SEADMED - 02 Tähis: Frame-Trs-210
AC_Pset_RenovationAndPhasing - Renovation Status: New

# IfcBuildingElementProxy: Frame-Trs-211, Alumiinium (1); Objekti nimi: Frame 22
In: KATUSEPLAAN
Type - ElementType: Element type Frame-Trs-211
Material: Alumiinium (1) (2)
SEADMED - 02 Tähis: Frame-Trs-211
AC_Pset_RenovationAndPhasing - Renovation Status: New

# IfcBuildingElementProxy: Frame-Trs-212, Alumiinium (1); Objekti nimi: Frame 22
In: KATUSEPLAAN
Type - ElementType: Element type Frame-Trs-212
Material: Alumiinium (1) (2)
SEADMED - 02 Tähis: Frame-Trs-212
AC_Pset_RenovationAndPhasing - Renovation Status: New

# IfcBuildingElementProxy: Frame-Trs-213, Alumiinium (1); Objekti nimi: Frame 22
In: KATUSEPLAAN
Type - ElementType: Element type Frame-Trs-213
Material: Alumiinium (1) (2)
SEADMED - 02 Tähis: Frame-Trs-213
AC_Pset_RenovationAndPhasing - Renovation Status: New

# IfcBuildingElementProxy: Frame-Trs-214, Alumiinium (1); Objekti nimi: Frame 22
In: KATUSEPLAAN
Type - ElementType: Element type Frame-Trs-214
Material: Alumiinium (1) (2)
SEADMED - 02 Tähis: Frame-Trs-214
AC_Pset_RenovationAndPhasing - Renovation Status: New

# IfcBuildingElementProxy: Frame-Trs-215, Alumiinium (1); Objekti nimi: Frame 22
In: KATUSEPLAAN
Type - ElementType: Element type Frame-Trs-215
Material: Alumiinium (1) (2)
SEADMED - 02 Tähis: Frame-Trs-215
AC_Pset_RenovationAndPhasing - Renovation Status: New

# IfcBuildingElementProxy: Frame-Trs-216, Alumiinium (1); Objekti nimi: Frame 22
In: KATUSEPLAAN
Type - ElementType: Element type Frame-Trs-216
Material: Alumiinium (1) (2)
SEADMED - 02 Tähis: Frame-Trs-216
AC_Pset_RenovationAndPhasing - Renovation Status: New

# IfcBuildingElementProxy: Frame-Trs-217, Alumiinium (1); Objekti nimi: Frame 22
In: KATUSEPLAAN
Type - ElementType: Element type Frame-Trs-217
Material: Alumiinium (1) (2)
SEADMED - 02 Tähis: Frame-Trs-217
AC_Pset_RenovationAndPhasing - Renovation Status: New

# IfcBuildingElementProxy: Frame-Trs-218, Alumiinium (1); Objekti nimi: Frame 22
In: KATUSEPLAAN
Type - ElementType: Element type Frame-Trs-218
Material: Alumiinium (1) (2)
SEADMED - 02 Tähis: Frame-Trs-218
AC_Pset_RenovationAndPhasing - Renovation Status: New

# IfcBuildingElementProxy: Frame-Trs-243, Alumiinium (1); Objekti nimi: Frame 22
In: KATUSEPLAAN
Type - ElementType: Element type Frame-Trs-243
Material: Alumiinium (1) (2)
SEADMED - 02 Tähis: Frame-Trs-243
AC_Pset_RenovationAndPhasing - Renovation Status: New

# IfcBuildingElementProxy: Frame-Trs-244, Alumiinium (1); Objekti nimi: Frame 22
In: KATUSEPLAAN
Type - ElementType: Element type Frame-Trs-244
Material: Alumiinium (1) (2)
SEADMED - 02 Tähis: Frame-Trs-244
AC_Pset_RenovationAndPhasing - Renovation Status: New

# IfcBuildingElementProxy: Frame-Trs-245, Alumiinium (1); Objekti nimi: Frame 22
In: KATUSEPLAAN
Type - ElementType: Element type Frame-Trs-245
Material: Alumiinium (1) (2)
SEADMED - 02 Tähis: Frame-Trs-245
AC_Pset_RenovationAndPhasing - Renovation Status: New

# IfcBuildingElementProxy: Frame-Trs-246, Alumiinium (1); Objekti nimi: Frame 22
In: KATUSEPLAAN
Type - ElementType: Element type Frame-Trs-246
Material: Alumiinium (1) (2)
SEADMED - 02 Tähis: Frame-Trs-246
AC_Pset_RenovationAndPhasing - Renovation Status: New

# IfcBuildingElementProxy: Frame-Trs-247, Alumiinium (1); Objekti nimi: Frame 22
In: KATUSEPLAAN
Type - ElementType: Element type Frame-Trs-247
Material: Alumiinium (1) (2)
SEADMED - 02 Tähis: Frame-Trs-247
AC_Pset_RenovationAndPhasing - Renovation Status: New

# IfcBuildingElementProxy: Frame-Trs-248, Alumiinium (1); Objekti nimi: Frame 22
In: KATUSEPLAAN
Type - ElementType: Element type Frame-Trs-248
Material: Alumiinium (1) (2)
SEADMED - 02 Tähis: Frame-Trs-248
AC_Pset_RenovationAndPhasing - Renovation Status: New

# IfcBuildingElementProxy: Frame-Trs-249, Alumiinium (1); Objekti nimi: Frame 22
In: KATUSEPLAAN
Type - ElementType: Element type Frame-Trs-249
Material: Alumiinium (1) (2)
SEADMED - 02 Tähis: Frame-Trs-249
AC_Pset_RenovationAndPhasing - Renovation Status: New

# IfcBuildingElementProxy: Frame-Trs-250, Alumiinium (1); Objekti nimi: Frame 22
In: KATUSEPLAAN
Type - ElementType: Element type Frame-Trs-250
Material: Alumiinium (1) (2)
SEADMED - 02 Tähis: Frame-Trs-250
AC_Pset_RenovationAndPhasing - Renovation Status: New

# IfcBuildingElementProxy: Frame-Trs-251, Alumiinium (1); Objekti nimi: Frame 22
In: KATUSEPLAAN
Type - ElementType: Element type Frame-Trs-251
Material: Alumiinium (1) (2)
SEADMED - 02 Tähis: Frame-Trs-251
AC_Pset_RenovationAndPhasing - Renovation Status: New

# IfcBuildingElementProxy: Frame-Trs-252, Alumiinium (1); Objekti nimi: Frame 22
In: KATUSEPLAAN
Type - ElementType: Element type Frame-Trs-252
Material: Alumiinium (1) (2)
SEADMED - 02 Tähis: Frame-Trs-252
AC_Pset_RenovationAndPhasing - Renovation Status: New

# IfcBuildingElementProxy: Frame-Trs-253, Alumiinium (1); Objekti nimi: Frame 22
In: KATUSEPLAAN
Type - ElementType: Element type Frame-Trs-253
Material: Alumiinium (1) (2)
SEADMED - 02 Tähis: Frame-Trs-253
AC_Pset_RenovationAndPhasing - Renovation Status: New

# IfcBuildingElementProxy: Frame-Trs-254, Alumiinium (1); Objekti nimi: Frame 22
In: KATUSEPLAAN
Type - ElementType: Element type Frame-Trs-254
Material: Alumiinium (1) (2)
SEADMED - 02 Tähis: Frame-Trs-254
AC_Pset_RenovationAndPhasing - Renovation Status: New

# IfcBuildingElementProxy: Frame-Trs-255, Alumiinium (1); Objekti nimi: Frame 22
In: KATUSEPLAAN
Type - ElementType: Element type Frame-Trs-255
Material: Alumiinium (1) (2)
SEADMED - 02 Tähis: Frame-Trs-255
AC_Pset_RenovationAndPhasing - Renovation Status: New

# IfcBuildingElementProxy: Frame-Trs-256, Alumiinium (1); Objekti nimi: Frame 22
In: KATUSEPLAAN
Type - ElementType: Element type Frame-Trs-256
Material: Alumiinium (1) (2)
SEADMED - 02 Tähis: Frame-Trs-256
AC_Pset_RenovationAndPhasing - Renovation Status: New

# IfcBuildingElementProxy: Frame-Trs-257, Alumiinium (1); Objekti nimi: Frame 22
In: KATUSEPLAAN
Type - ElementType: Element type Frame-Trs-257
Material: Alumiinium (1) (2)
SEADMED - 02 Tähis: Frame-Trs-257
AC_Pset_RenovationAndPhasing - Renovation Status: New

# IfcBuildingElementProxy: Frame-Trs-258, Alumiinium (1); Objekti nimi: Frame 22
In: KATUSEPLAAN
Type - ElementType: Element type Frame-Trs-258
Material: Alumiinium (1) (2)
SEADMED - 02 Tähis: Frame-Trs-258
AC_Pset_RenovationAndPhasing - Renovation Status: New

# IfcBuildingElementProxy: Frame-Trs-259, Alumiinium (1); Objekti nimi: Frame 22
In: KATUSEPLAAN
Type - ElementType: Element type Frame-Trs-259
Material: Alumiinium (1) (2)
SEADMED - 02 Tähis: Frame-Trs-259
AC_Pset_RenovationAndPhasing - Renovation Status: New

# IfcBuildingElementProxy: Frame-Trs-260, Alumiinium (1); Objekti nimi: Frame 22
In: KATUSEPLAAN
Type - ElementType: Element type Frame-Trs-260
Material: Alumiinium (1) (2)
SEADMED - 02 Tähis: Frame-Trs-260
AC_Pset_RenovationAndPhasing - Renovation Status: New
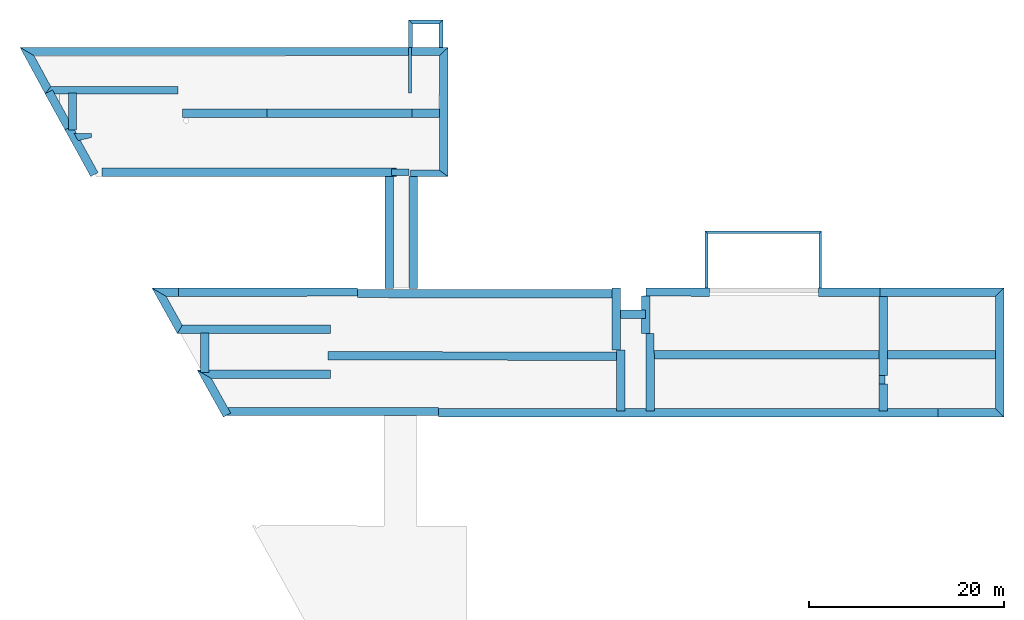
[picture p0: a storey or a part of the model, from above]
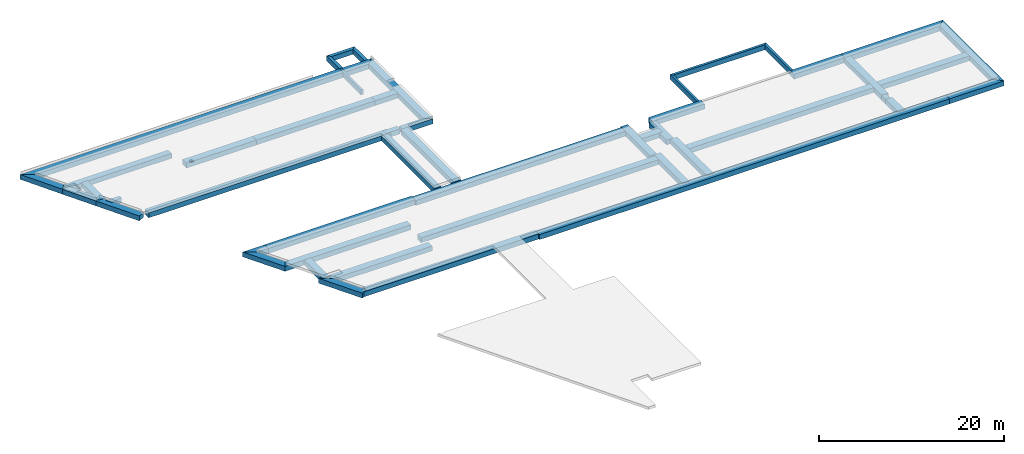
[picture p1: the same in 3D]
Properties of the parts of a building model (IFC2X3), part 3 of 14

# IfcBuildingElementProxy: Frame-Trs-261, Alumiinium (1); Objekti nimi: Frame 22
In: KATUSEPLAAN
Type - ElementType: Element type Frame-Trs-261
Material: Alumiinium (1) (2)
SEADMED - 02 Tähis: Frame-Trs-261
AC_Pset_RenovationAndPhasing - Renovation Status: New

# IfcBuildingElementProxy: Frame-Trs-262, Alumiinium (1); Objekti nimi: Frame 22
In: KATUSEPLAAN
Type - ElementType: Element type Frame-Trs-262
Material: Alumiinium (1) (2)
SEADMED - 02 Tähis: Frame-Trs-262
AC_Pset_RenovationAndPhasing - Renovation Status: New

# IfcBuildingElementProxy: Frame-Trs-263, Alumiinium (1); Objekti nimi: Frame 22
In: KATUSEPLAAN
Type - ElementType: Element type Frame-Trs-263
Material: Alumiinium (1) (2)
SEADMED - 02 Tähis: Frame-Trs-263
AC_Pset_RenovationAndPhasing - Renovation Status: New

# IfcBuildingElementProxy: Frame-Trs-264, Alumiinium (1); Objekti nimi: Frame 22
In: KATUSEPLAAN
Type - ElementType: Element type Frame-Trs-264
Material: Alumiinium (1) (2)
SEADMED - 02 Tähis: Frame-Trs-264
AC_Pset_RenovationAndPhasing - Renovation Status: New

# IfcBuildingElementProxy: Frame-Trs-265, Alumiinium (1); Objekti nimi: Frame 22
In: KATUSEPLAAN
Type - ElementType: Element type Frame-Trs-265
Material: Alumiinium (1) (2)
SEADMED - 02 Tähis: Frame-Trs-265
AC_Pset_RenovationAndPhasing - Renovation Status: New

# IfcBuildingElementProxy: Frame-Trs-266, Alumiinium (1); Objekti nimi: Frame 22
In: KATUSEPLAAN
Type - ElementType: Element type Frame-Trs-266
Material: Alumiinium (1) (2)
SEADMED - 02 Tähis: Frame-Trs-266
AC_Pset_RenovationAndPhasing - Renovation Status: New

# IfcBuildingElementProxy: Frame-Trs-515, Alumiinium (1); Objekti nimi: Frame 22
In: KATUSEPLAAN
Type - ElementType: Element type Frame-Trs-515
Material: Alumiinium (1) (2)
SEADMED - 02 Tähis: Frame-Trs-515
AC_Pset_RenovationAndPhasing - Renovation Status: New

# IfcBuildingElementProxy: Frame-Trs-516, Alumiinium (1); Objekti nimi: Frame 22
In: KATUSEPLAAN
Type - ElementType: Element type Frame-Trs-516
Material: Alumiinium (1) (2)
SEADMED - 02 Tähis: Frame-Trs-516
AC_Pset_RenovationAndPhasing - Renovation Status: New

# IfcBuildingElementProxy: Frame-Trs-517, Alumiinium (1); Objekti nimi: Frame 22
In: KATUSEPLAAN
Type - ElementType: Element type Frame-Trs-517
Material: Alumiinium (1) (2)
SEADMED - 02 Tähis: Frame-Trs-517
AC_Pset_RenovationAndPhasing - Renovation Status: New

# IfcBuildingElementProxy: Frame-Trs-518, Alumiinium (1); Objekti nimi: Frame 22
In: KATUSEPLAAN
Type - ElementType: Element type Frame-Trs-518
Material: Alumiinium (1) (2)
SEADMED - 02 Tähis: Frame-Trs-518
AC_Pset_RenovationAndPhasing - Renovation Status: New

# IfcBuildingElementProxy: Frame-Trs-519, Alumiinium (1); Objekti nimi: Frame 22
In: KATUSEPLAAN
Type - ElementType: Element type Frame-Trs-519
Material: Alumiinium (1) (2)
SEADMED - 02 Tähis: Frame-Trs-519
AC_Pset_RenovationAndPhasing - Renovation Status: New

# IfcBuildingElementProxy: Frame-Trs-520, Alumiinium (1); Objekti nimi: Frame 22
In: KATUSEPLAAN
Type - ElementType: Element type Frame-Trs-520
Material: Alumiinium (1) (2)
SEADMED - 02 Tähis: Frame-Trs-520
AC_Pset_RenovationAndPhasing - Renovation Status: New

# IfcBuildingElementProxy: Frame-Trs-521, Alumiinium (1); Objekti nimi: Frame 22
In: KATUSEPLAAN
Type - ElementType: Element type Frame-Trs-521
Material: Alumiinium (1) (2)
SEADMED - 02 Tähis: Frame-Trs-521
AC_Pset_RenovationAndPhasing - Renovation Status: New

# IfcBuildingElementProxy: Frame-Trs-522, Alumiinium (1); Objekti nimi: Frame 22
In: KATUSEPLAAN
Type - ElementType: Element type Frame-Trs-522
Material: Alumiinium (1) (2)
SEADMED - 02 Tähis: Frame-Trs-522
AC_Pset_RenovationAndPhasing - Renovation Status: New

# IfcBuildingElementProxy: Frame-Trs-523, Alumiinium (1); Objekti nimi: Frame 22
In: KATUSEPLAAN
Type - ElementType: Element type Frame-Trs-523
Material: Alumiinium (1) (2)
SEADMED - 02 Tähis: Frame-Trs-523
AC_Pset_RenovationAndPhasing - Renovation Status: New

# IfcBuildingElementProxy: Frame-Trs-524, Alumiinium (1); Objekti nimi: Frame 22
In: KATUSEPLAAN
Type - ElementType: Element type Frame-Trs-524
Material: Alumiinium (1) (2)
SEADMED - 02 Tähis: Frame-Trs-524
AC_Pset_RenovationAndPhasing - Renovation Status: New

# IfcBuildingElementProxy: Frame-Trs-525, Alumiinium (1); Objekti nimi: Frame 22
In: KATUSEPLAAN
Type - ElementType: Element type Frame-Trs-525
Material: Alumiinium (1) (2)
SEADMED - 02 Tähis: Frame-Trs-525
AC_Pset_RenovationAndPhasing - Renovation Status: New

# IfcBuildingElementProxy: Frame-Trs-526, Alumiinium (1); Objekti nimi: Frame 22
In: KATUSEPLAAN
Type - ElementType: Element type Frame-Trs-526
Material: Alumiinium (1) (2)
SEADMED - 02 Tähis: Frame-Trs-526
AC_Pset_RenovationAndPhasing - Renovation Status: New

# IfcBuildingElementProxy: Frame-Trs-527, Alumiinium (1); Objekti nimi: Frame 22
In: KATUSEPLAAN
Type - ElementType: Element type Frame-Trs-527
Material: Alumiinium (1) (2)
SEADMED - 02 Tähis: Frame-Trs-527
AC_Pset_RenovationAndPhasing - Renovation Status: New

# IfcBuildingElementProxy: Frame-Trs-528, Alumiinium (1); Objekti nimi: Frame 22
In: KATUSEPLAAN
Type - ElementType: Element type Frame-Trs-528
Material: Alumiinium (1) (2)
SEADMED - 02 Tähis: Frame-Trs-528
AC_Pset_RenovationAndPhasing - Renovation Status: New

# IfcBuildingElementProxy: Frame-Trs-529, Alumiinium (1); Objekti nimi: Frame 22
In: KATUSEPLAAN
Type - ElementType: Element type Frame-Trs-529
Material: Alumiinium (1) (2)
SEADMED - 02 Tähis: Frame-Trs-529
AC_Pset_RenovationAndPhasing - Renovation Status: New

# IfcBuildingElementProxy: Frame-Trs-530, Alumiinium (1); Objekti nimi: Frame 22
In: KATUSEPLAAN
Type - ElementType: Element type Frame-Trs-530
Material: Alumiinium (1) (2)
SEADMED - 02 Tähis: Frame-Trs-530
AC_Pset_RenovationAndPhasing - Renovation Status: New

# IfcBuildingElementProxy: Frame-Trs-531, Alumiinium (1); Objekti nimi: Frame 22
In: KATUSEPLAAN
Type - ElementType: Element type Frame-Trs-531
Material: Alumiinium (1) (2)
SEADMED - 02 Tähis: Frame-Trs-531
AC_Pset_RenovationAndPhasing - Renovation Status: New

# IfcBuildingElementProxy: Frame-Trs-532, Alumiinium (1); Objekti nimi: Frame 22
In: KATUSEPLAAN
Type - ElementType: Element type Frame-Trs-532
Material: Alumiinium (1) (2)
SEADMED - 02 Tähis: Frame-Trs-532
AC_Pset_RenovationAndPhasing - Renovation Status: New

# IfcBuildingElementProxy: Frame-Trs-533, Alumiinium (1); Objekti nimi: Frame 22
In: KATUSEPLAAN
Type - ElementType: Element type Frame-Trs-533
Material: Alumiinium (1) (2)
SEADMED - 02 Tähis: Frame-Trs-533
AC_Pset_RenovationAndPhasing - Renovation Status: New

# IfcBuildingElementProxy: Frame-Trs-534, Alumiinium (1); Objekti nimi: Frame 22
In: KATUSEPLAAN
Type - ElementType: Element type Frame-Trs-534
Material: Alumiinium (1) (2)
SEADMED - 02 Tähis: Frame-Trs-534
AC_Pset_RenovationAndPhasing - Renovation Status: New

# IfcBuildingElementProxy: Frame-Trs-535, Alumiinium (1); Objekti nimi: Frame 22
In: KATUSEPLAAN
Type - ElementType: Element type Frame-Trs-535
Material: Alumiinium (1) (2)
SEADMED - 02 Tähis: Frame-Trs-535
AC_Pset_RenovationAndPhasing - Renovation Status: New

# IfcBuildingElementProxy: Frame-Trs-536, Alumiinium (1); Objekti nimi: Frame 22
In: KATUSEPLAAN
Type - ElementType: Element type Frame-Trs-536
Material: Alumiinium (1) (2)
SEADMED - 02 Tähis: Frame-Trs-536
AC_Pset_RenovationAndPhasing - Renovation Status: New

# IfcBuildingElementProxy: Frame-Trs-537, Alumiinium (1); Objekti nimi: Frame 22
In: KATUSEPLAAN
Type - ElementType: Element type Frame-Trs-537
Material: Alumiinium (1) (2)
SEADMED - 02 Tähis: Frame-Trs-537
AC_Pset_RenovationAndPhasing - Renovation Status: New

# IfcBuildingElementProxy: Frame-Trs-538, Alumiinium (1); Objekti nimi: Frame 22
In: KATUSEPLAAN
Type - ElementType: Element type Frame-Trs-538
Material: Alumiinium (1) (2)
SEADMED - 02 Tähis: Frame-Trs-538
AC_Pset_RenovationAndPhasing - Renovation Status: New

# IfcBuildingElementProxy: Frame-Trs-747, Alumiinium (1); Objekti nimi: Frame 22
In: KATUSEPLAAN
Type - ElementType: Element type Frame-Trs-747
Material: Alumiinium (1) (2)
SEADMED - 02 Tähis: Frame-Trs-747
AC_Pset_RenovationAndPhasing - Renovation Status: New

# IfcBuildingElementProxy: Frame-Trs-748, Alumiinium (1); Objekti nimi: Frame 22
In: KATUSEPLAAN
Type - ElementType: Element type Frame-Trs-748
Material: Alumiinium (1) (2)
SEADMED - 02 Tähis: Frame-Trs-748
AC_Pset_RenovationAndPhasing - Renovation Status: New

# IfcBuildingElementProxy: Frame-Trs-749, Alumiinium (1); Objekti nimi: Frame 22
In: KATUSEPLAAN
Type - ElementType: Element type Frame-Trs-749
Material: Alumiinium (1) (2)
SEADMED - 02 Tähis: Frame-Trs-749
AC_Pset_RenovationAndPhasing - Renovation Status: New

# IfcBuildingElementProxy: Frame-Trs-750, Alumiinium (1); Objekti nimi: Frame 22
In: KATUSEPLAAN
Type - ElementType: Element type Frame-Trs-750
Material: Alumiinium (1) (2)
SEADMED - 02 Tähis: Frame-Trs-750
AC_Pset_RenovationAndPhasing - Renovation Status: New

# IfcBuildingElementProxy: Frame-Trs-751, Alumiinium (1); Objekti nimi: Frame 22
In: KATUSEPLAAN
Type - ElementType: Element type Frame-Trs-751
Material: Alumiinium (1) (2)
SEADMED - 02 Tähis: Frame-Trs-751
AC_Pset_RenovationAndPhasing - Renovation Status: New

# IfcBuildingElementProxy: Frame-Trs-752, Alumiinium (1); Objekti nimi: Frame 22
In: KATUSEPLAAN
Type - ElementType: Element type Frame-Trs-752
Material: Alumiinium (1) (2)
SEADMED - 02 Tähis: Frame-Trs-752
AC_Pset_RenovationAndPhasing - Renovation Status: New

# IfcBuildingElementProxy: Frame-Trs-753, Alumiinium (1); Objekti nimi: Frame 22
In: KATUSEPLAAN
Type - ElementType: Element type Frame-Trs-753
Material: Alumiinium (1) (2)
SEADMED - 02 Tähis: Frame-Trs-753
AC_Pset_RenovationAndPhasing - Renovation Status: New

# IfcBuildingElementProxy: Frame-Trs-754, Alumiinium (1); Objekti nimi: Frame 22
In: KATUSEPLAAN
Type - ElementType: Element type Frame-Trs-754
Material: Alumiinium (1) (2)
SEADMED - 02 Tähis: Frame-Trs-754
AC_Pset_RenovationAndPhasing - Renovation Status: New

# IfcBuildingElementProxy: Frame-Trs-755, Alumiinium (1); Objekti nimi: Frame 22
In: KATUSEPLAAN
Type - ElementType: Element type Frame-Trs-755
Material: Alumiinium (1) (2)
SEADMED - 02 Tähis: Frame-Trs-755
AC_Pset_RenovationAndPhasing - Renovation Status: New

# IfcBuildingElementProxy: Frame-Trs-756, Alumiinium (1); Objekti nimi: Frame 22
In: KATUSEPLAAN
Type - ElementType: Element type Frame-Trs-756
Material: Alumiinium (1) (2)
SEADMED - 02 Tähis: Frame-Trs-756
AC_Pset_RenovationAndPhasing - Renovation Status: New

# IfcBuildingElementProxy: Frame-Trs-757, Alumiinium (1); Objekti nimi: Frame 22
In: KATUSEPLAAN
Type - ElementType: Element type Frame-Trs-757
Material: Alumiinium (1) (2)
SEADMED - 02 Tähis: Frame-Trs-757
AC_Pset_RenovationAndPhasing - Renovation Status: New

# IfcBuildingElementProxy: Frame-Trs-758, Alumiinium (1); Objekti nimi: Frame 22
In: KATUSEPLAAN
Type - ElementType: Element type Frame-Trs-758
Material: Alumiinium (1) (2)
SEADMED - 02 Tähis: Frame-Trs-758
AC_Pset_RenovationAndPhasing - Renovation Status: New

# IfcBuildingElementProxy: Frame-Trs-759, Alumiinium (1); Objekti nimi: Frame 22
In: KATUSEPLAAN
Type - ElementType: Element type Frame-Trs-759
Material: Alumiinium (1) (2)
SEADMED - 02 Tähis: Frame-Trs-759
AC_Pset_RenovationAndPhasing - Renovation Status: New

# IfcBuildingElementProxy: Frame-Trs-760, Alumiinium (1); Objekti nimi: Frame 22
In: KATUSEPLAAN
Type - ElementType: Element type Frame-Trs-760
Material: Alumiinium (1) (2)
SEADMED - 02 Tähis: Frame-Trs-760
AC_Pset_RenovationAndPhasing - Renovation Status: New

# IfcBuildingElementProxy: Frame-Trs-761, Alumiinium (1); Objekti nimi: Frame 22
In: KATUSEPLAAN
Type - ElementType: Element type Frame-Trs-761
Material: Alumiinium (1) (2)
SEADMED - 02 Tähis: Frame-Trs-761
AC_Pset_RenovationAndPhasing - Renovation Status: New

# IfcBuildingElementProxy: Frame-Trs-762, Alumiinium (1); Objekti nimi: Frame 22
In: KATUSEPLAAN
Type - ElementType: Element type Frame-Trs-762
Material: Alumiinium (1) (2)
SEADMED - 02 Tähis: Frame-Trs-762
AC_Pset_RenovationAndPhasing - Renovation Status: New

# IfcBuildingElementProxy: Frame-Trs-763, Alumiinium (1); Objekti nimi: Frame 22
In: KATUSEPLAAN
Type - ElementType: Element type Frame-Trs-763
Material: Alumiinium (1) (2)
SEADMED - 02 Tähis: Frame-Trs-763
AC_Pset_RenovationAndPhasing - Renovation Status: New

# IfcBuildingElementProxy: Frame-Trs-764, Alumiinium (1); Objekti nimi: Frame 22
In: KATUSEPLAAN
Type - ElementType: Element type Frame-Trs-764
Material: Alumiinium (1) (2)
SEADMED - 02 Tähis: Frame-Trs-764
AC_Pset_RenovationAndPhasing - Renovation Status: New

# IfcBuildingElementProxy: Frame-Trs-765, Alumiinium (1); Objekti nimi: Frame 22
In: KATUSEPLAAN
Type - ElementType: Element type Frame-Trs-765
Material: Alumiinium (1) (2)
SEADMED - 02 Tähis: Frame-Trs-765
AC_Pset_RenovationAndPhasing - Renovation Status: New

# IfcBuildingElementProxy: Frame-Trs-766, Alumiinium (1); Objekti nimi: Frame 22
In: KATUSEPLAAN
Type - ElementType: Element type Frame-Trs-766
Material: Alumiinium (1) (2)
SEADMED - 02 Tähis: Frame-Trs-766
AC_Pset_RenovationAndPhasing - Renovation Status: New

# IfcBuildingElementProxy: Frame-Trs-767, Alumiinium (1); Objekti nimi: Frame 22
In: KATUSEPLAAN
Type - ElementType: Element type Frame-Trs-767
Material: Alumiinium (1) (2)
SEADMED - 02 Tähis: Frame-Trs-767
AC_Pset_RenovationAndPhasing - Renovation Status: New

# IfcBuildingElementProxy: Frame-Trs-768, Alumiinium (1); Objekti nimi: Frame 22
In: KATUSEPLAAN
Type - ElementType: Element type Frame-Trs-768
Material: Alumiinium (1) (2)
SEADMED - 02 Tähis: Frame-Trs-768
AC_Pset_RenovationAndPhasing - Renovation Status: New

# IfcBuildingElementProxy: Frame-Trs-769, Alumiinium (1); Objekti nimi: Frame 22
In: KATUSEPLAAN
Type - ElementType: Element type Frame-Trs-769
Material: Alumiinium (1) (2)
SEADMED - 02 Tähis: Frame-Trs-769
AC_Pset_RenovationAndPhasing - Renovation Status: New

# IfcBuildingElementProxy: Frame-Trs-770, Alumiinium (1); Objekti nimi: Frame 22
In: KATUSEPLAAN
Type - ElementType: Element type Frame-Trs-770
Material: Alumiinium (1) (2)
SEADMED - 02 Tähis: Frame-Trs-770
AC_Pset_RenovationAndPhasing - Renovation Status: New

# IfcBuildingElementProxy: Frame-Trs-807, Alumiinium (1); Objekti nimi: Built-in Butt-glazed Frame
In: 1 KORRUS
Type - ElementType: Element type Frame-Trs-807
Material: Alumiinium (1)
SEADMED - 02 Tähis: Frame-Trs-807
AC_Pset_RenovationAndPhasing - Renovation Status: New

# IfcBuildingElementProxy: Frame-Trs-809, Alumiinium (1); Objekti nimi: Built-in Butt-glazed Frame
In: 1 KORRUS
Type - ElementType: Element type Frame-Trs-809
Material: Alumiinium (1)
SEADMED - 02 Tähis: Frame-Trs-809
AC_Pset_RenovationAndPhasing - Renovation Status: New

# IfcBuildingElementProxy: Frame-Trs-825, Alumiinium (1); Objekti nimi: Built-in Butt-glazed Frame
In: 1 KORRUS
Type - ElementType: Element type Frame-Trs-825
Material: Alumiinium (1)
SEADMED - 02 Tähis: Frame-Trs-825
AC_Pset_RenovationAndPhasing - Renovation Status: New

# IfcBuildingElementProxy: Panel-Dist-144, Klaas; Objekti nimi: Built-in CW Panel
In: KATUSEPLAAN
Type - ElementType: Element type Panel-Dist-144
Material: Klaas
SEADMED - 02 Tähis: Panel-Dist-144
AC_Pset_RenovationAndPhasing - Renovation Status: New

# IfcBuildingElementProxy: Panel-Dist-146, Klaas; Objekti nimi: Built-in CW Panel
In: KATUSEPLAAN
Type - ElementType: Element type Panel-Dist-146
Material: Klaas
SEADMED - 02 Tähis: Panel-Dist-146
AC_Pset_RenovationAndPhasing - Renovation Status: New

# IfcBuildingElementProxy: Panel-Dist-147, Klaas; Objekti nimi: Built-in CW Panel
In: KATUSEPLAAN
Type - ElementType: Element type Panel-Dist-147
Material: Klaas
SEADMED - 02 Tähis: Panel-Dist-147
AC_Pset_RenovationAndPhasing - Renovation Status: New

# IfcBuildingElementProxy: Panel-Dist-148, Klaas; Objekti nimi: Built-in CW Panel
In: KATUSEPLAAN
Type - ElementType: Element type Panel-Dist-148
Material: Klaas
SEADMED - 02 Tähis: Panel-Dist-148
AC_Pset_RenovationAndPhasing - Renovation Status: New

# IfcBuildingElementProxy: Panel-Dist-149, Klaas; Objekti nimi: Built-in CW Panel
In: KATUSEPLAAN
Type - ElementType: Element type Panel-Dist-149
Material: Klaas
SEADMED - 02 Tähis: Panel-Dist-149
AC_Pset_RenovationAndPhasing - Renovation Status: New

# IfcBuildingElementProxy: Panel-Dist-150, Klaas; Objekti nimi: Built-in CW Panel
In: KATUSEPLAAN
Type - ElementType: Element type Panel-Dist-150
Material: Klaas
SEADMED - 02 Tähis: Panel-Dist-150
AC_Pset_RenovationAndPhasing - Renovation Status: New

# IfcBuildingElementProxy: Panel-Dist-151, Klaas; Objekti nimi: Built-in CW Panel
In: KATUSEPLAAN
Type - ElementType: Element type Panel-Dist-151
Material: Klaas
SEADMED - 02 Tähis: Panel-Dist-151
AC_Pset_RenovationAndPhasing - Renovation Status: New

# IfcBuildingElementProxy: Panel-Dist-152, Klaas; Objekti nimi: Built-in CW Panel
In: KATUSEPLAAN
Type - ElementType: Element type Panel-Dist-152
Material: Klaas
SEADMED - 02 Tähis: Panel-Dist-152
AC_Pset_RenovationAndPhasing - Renovation Status: New

# IfcBuildingElementProxy: Panel-Dist-153, Klaas; Objekti nimi: Built-in CW Panel
In: KATUSEPLAAN
Type - ElementType: Element type Panel-Dist-153
Material: Klaas
SEADMED - 02 Tähis: Panel-Dist-153
AC_Pset_RenovationAndPhasing - Renovation Status: New

# IfcBuildingElementProxy: Panel-Dist-154, Klaas; Objekti nimi: Built-in CW Panel
In: KATUSEPLAAN
Type - ElementType: Element type Panel-Dist-154
Material: Klaas
SEADMED - 02 Tähis: Panel-Dist-154
AC_Pset_RenovationAndPhasing - Renovation Status: New

# IfcBuildingElementProxy: Panel-Dist-155, Klaas; Objekti nimi: Built-in CW Panel
In: KATUSEPLAAN
Type - ElementType: Element type Panel-Dist-155
Material: Klaas
SEADMED - 02 Tähis: Panel-Dist-155
AC_Pset_RenovationAndPhasing - Renovation Status: New

# IfcBuildingElementProxy: Panel-Dist-156, Klaas; Objekti nimi: Built-in CW Panel
In: KATUSEPLAAN
Type - ElementType: Element type Panel-Dist-156
Material: Klaas
SEADMED - 02 Tähis: Panel-Dist-156
AC_Pset_RenovationAndPhasing - Renovation Status: New

# IfcBuildingElementProxy: Panel-Dist-157, Klaas; Objekti nimi: Built-in CW Panel
In: KATUSEPLAAN
Type - ElementType: Element type Panel-Dist-157
Material: Klaas
SEADMED - 02 Tähis: Panel-Dist-157
AC_Pset_RenovationAndPhasing - Renovation Status: New

# IfcBuildingElementProxy: Panel-Dist-158, Klaas; Objekti nimi: Built-in CW Panel
In: KATUSEPLAAN
Type - ElementType: Element type Panel-Dist-158
Material: Klaas
SEADMED - 02 Tähis: Panel-Dist-158
AC_Pset_RenovationAndPhasing - Renovation Status: New

# IfcBuildingElementProxy: Panel-Dist-159, Klaas; Objekti nimi: Built-in CW Panel
In: KATUSEPLAAN
Type - ElementType: Element type Panel-Dist-159
Material: Klaas
SEADMED - 02 Tähis: Panel-Dist-159
AC_Pset_RenovationAndPhasing - Renovation Status: New

# IfcBuildingElementProxy: Panel-Dist-160, Klaas; Objekti nimi: Built-in CW Panel
In: KATUSEPLAAN
Type - ElementType: Element type Panel-Dist-160
Material: Klaas
SEADMED - 02 Tähis: Panel-Dist-160
AC_Pset_RenovationAndPhasing - Renovation Status: New

# IfcBuildingElementProxy: Panel-Dist-161, Klaas; Objekti nimi: Built-in CW Panel
In: KATUSEPLAAN
Type - ElementType: Element type Panel-Dist-161
Material: Klaas
SEADMED - 02 Tähis: Panel-Dist-161
AC_Pset_RenovationAndPhasing - Renovation Status: New

# IfcBuildingElementProxy: Panel-Dist-162, Klaas; Objekti nimi: Built-in CW Panel
In: KATUSEPLAAN
Type - ElementType: Element type Panel-Dist-162
Material: Klaas
SEADMED - 02 Tähis: Panel-Dist-162
AC_Pset_RenovationAndPhasing - Renovation Status: New

# IfcBuildingElementProxy: Panel-Dist-163, Klaas; Objekti nimi: Built-in CW Panel
In: KATUSEPLAAN
Type - ElementType: Element type Panel-Dist-163
Material: Klaas
SEADMED - 02 Tähis: Panel-Dist-163
AC_Pset_RenovationAndPhasing - Renovation Status: New

# IfcBuildingElementProxy: Panel-Dist-164, Klaas; Objekti nimi: Built-in CW Panel
In: KATUSEPLAAN
Type - ElementType: Element type Panel-Dist-164
Material: Klaas
SEADMED - 02 Tähis: Panel-Dist-164
AC_Pset_RenovationAndPhasing - Renovation Status: New

# IfcBuildingElementProxy: Panel-Dist-165, Klaas; Objekti nimi: Built-in CW Panel
In: KATUSEPLAAN
Type - ElementType: Element type Panel-Dist-165
Material: Klaas
SEADMED - 02 Tähis: Panel-Dist-165
AC_Pset_RenovationAndPhasing - Renovation Status: New

# IfcBuildingElementProxy: Panel-Dist-168, Klaas; Objekti nimi: Built-in CW Panel
In: KATUSEPLAAN
Type - ElementType: Element type Panel-Dist-168
Material: Klaas
SEADMED - 02 Tähis: Panel-Dist-168
AC_Pset_RenovationAndPhasing - Renovation Status: New

# IfcBuildingElementProxy: Panel-Dist-169, Klaas; Objekti nimi: Built-in CW Panel
In: KATUSEPLAAN
Type - ElementType: Element type Panel-Dist-169
Material: Klaas
SEADMED - 02 Tähis: Panel-Dist-169
AC_Pset_RenovationAndPhasing - Renovation Status: New

# IfcBuildingElementProxy: Panel-Dist-170, Klaas; Objekti nimi: Built-in CW Panel
In: KATUSEPLAAN
Type - ElementType: Element type Panel-Dist-170
Material: Klaas
SEADMED - 02 Tähis: Panel-Dist-170
AC_Pset_RenovationAndPhasing - Renovation Status: New

# IfcBuildingElementProxy: Panel-Dist-171, Klaas; Objekti nimi: Built-in CW Panel
In: KATUSEPLAAN
Type - ElementType: Element type Panel-Dist-171
Material: Klaas
SEADMED - 02 Tähis: Panel-Dist-171
AC_Pset_RenovationAndPhasing - Renovation Status: New

# IfcBuildingElementProxy: Panel-Dist-172, Klaas; Objekti nimi: Built-in CW Panel
In: KATUSEPLAAN
Type - ElementType: Element type Panel-Dist-172
Material: Klaas
SEADMED - 02 Tähis: Panel-Dist-172
AC_Pset_RenovationAndPhasing - Renovation Status: New

# IfcBuildingElementProxy: Panel-Dist-173, Klaas; Objekti nimi: Built-in CW Panel
In: KATUSEPLAAN
Type - ElementType: Element type Panel-Dist-173
Material: Klaas
SEADMED - 02 Tähis: Panel-Dist-173
AC_Pset_RenovationAndPhasing - Renovation Status: New

# IfcBuildingElementProxy: Panel-Dist-174, Klaas; Objekti nimi: Built-in CW Panel
In: KATUSEPLAAN
Type - ElementType: Element type Panel-Dist-174
Material: Klaas
SEADMED - 02 Tähis: Panel-Dist-174
AC_Pset_RenovationAndPhasing - Renovation Status: New

# IfcBuildingElementProxy: Panel-Dist-175, Klaas; Objekti nimi: Built-in CW Panel
In: KATUSEPLAAN
Type - ElementType: Element type Panel-Dist-175
Material: Klaas
SEADMED - 02 Tähis: Panel-Dist-175
AC_Pset_RenovationAndPhasing - Renovation Status: New

# IfcBuildingElementProxy: Panel-Dist-176, Klaas; Objekti nimi: Built-in CW Panel
In: KATUSEPLAAN
Type - ElementType: Element type Panel-Dist-176
Material: Klaas
SEADMED - 02 Tähis: Panel-Dist-176
AC_Pset_RenovationAndPhasing - Renovation Status: New

# IfcBuildingElementProxy: Panel-Dist-177, Klaas; Objekti nimi: Built-in CW Panel
In: KATUSEPLAAN
Type - ElementType: Element type Panel-Dist-177
Material: Klaas
SEADMED - 02 Tähis: Panel-Dist-177
AC_Pset_RenovationAndPhasing - Renovation Status: New

# IfcBuildingElementProxy: Panel-Dist-179, Klaas; Objekti nimi: Built-in CW Panel
In: KATUSEPLAAN
Type - ElementType: Element type Panel-Dist-179
Material: Klaas
SEADMED - 02 Tähis: Panel-Dist-179
AC_Pset_RenovationAndPhasing - Renovation Status: New

# IfcBuildingElementProxy: Panel-Main-004 (4)
In: 1 KORRUS
Type - ElementType: Element type Panel-Main-004
Material: Klaas (1)
SEADMED - 02 Tähis: Panel-Main-004
AC_Pset_RenovationAndPhasing - Renovation Status: New

# IfcBuildingElementProxy: Panel-Main-069, Klaas; Objekti nimi: Built-in CW Panel
In: KATUSEPLAAN
Type - ElementType: Element type Panel-Main-069
Material: Klaas
SEADMED - 02 Tähis: Panel-Main-069
AC_Pset_RenovationAndPhasing - Renovation Status: New

# IfcBuildingElementProxy: Panel-Main-070, Klaas; Objekti nimi: Built-in CW Panel
In: KATUSEPLAAN
Type - ElementType: Element type Panel-Main-070
Material: Klaas
SEADMED - 02 Tähis: Panel-Main-070
AC_Pset_RenovationAndPhasing - Renovation Status: New

# IfcBuildingElementProxy: Panel-Main-071, Klaas; Objekti nimi: Built-in CW Panel
In: KATUSEPLAAN
Type - ElementType: Element type Panel-Main-071
Material: Klaas
SEADMED - 02 Tähis: Panel-Main-071
AC_Pset_RenovationAndPhasing - Renovation Status: New

# IfcBuildingElementProxy: Panel-Main-072, Klaas; Objekti nimi: Built-in CW Panel
In: KATUSEPLAAN
Type - ElementType: Element type Panel-Main-072
Material: Klaas
SEADMED - 02 Tähis: Panel-Main-072
AC_Pset_RenovationAndPhasing - Renovation Status: New

# IfcBuildingElementProxy: Panel-Main-073, Klaas; Objekti nimi: Built-in CW Panel
In: KATUSEPLAAN
Type - ElementType: Element type Panel-Main-073
Material: Klaas
SEADMED - 02 Tähis: Panel-Main-073
AC_Pset_RenovationAndPhasing - Renovation Status: New

# IfcBuildingElementProxy: Panel-Main-074, Klaas; Objekti nimi: Built-in CW Panel
In: KATUSEPLAAN
Type - ElementType: Element type Panel-Main-074
Material: Klaas
SEADMED - 02 Tähis: Panel-Main-074
AC_Pset_RenovationAndPhasing - Renovation Status: New

# IfcBuildingElementProxy: Panel-Main-075, Klaas; Objekti nimi: Built-in CW Panel
In: KATUSEPLAAN
Type - ElementType: Element type Panel-Main-075
Material: Klaas
SEADMED - 02 Tähis: Panel-Main-075
AC_Pset_RenovationAndPhasing - Renovation Status: New

# IfcBuildingElementProxy: Panel-Main-076, Klaas; Objekti nimi: Built-in CW Panel
In: KATUSEPLAAN
Type - ElementType: Element type Panel-Main-076
Material: Klaas
SEADMED - 02 Tähis: Panel-Main-076
AC_Pset_RenovationAndPhasing - Renovation Status: New

# IfcBuildingElementProxy: Panel-Main-077, Klaas; Objekti nimi: Built-in CW Panel
In: KATUSEPLAAN
Type - ElementType: Element type Panel-Main-077
Material: Klaas
SEADMED - 02 Tähis: Panel-Main-077
AC_Pset_RenovationAndPhasing - Renovation Status: New

# IfcBuildingElementProxy: Panel-Main-078, Klaas; Objekti nimi: Built-in CW Panel
In: KATUSEPLAAN
Type - ElementType: Element type Panel-Main-078
Material: Klaas
SEADMED - 02 Tähis: Panel-Main-078
AC_Pset_RenovationAndPhasing - Renovation Status: New

# IfcBuildingElementProxy: Panel-Main-079, Klaas; Objekti nimi: Built-in CW Panel
In: KATUSEPLAAN
Type - ElementType: Element type Panel-Main-079
Material: Klaas
SEADMED - 02 Tähis: Panel-Main-079
AC_Pset_RenovationAndPhasing - Renovation Status: New

# IfcBuildingElementProxy: Panel-Main-080, Klaas; Objekti nimi: Built-in CW Panel
In: KATUSEPLAAN
Type - ElementType: Element type Panel-Main-080
Material: Klaas
SEADMED - 02 Tähis: Panel-Main-080
AC_Pset_RenovationAndPhasing - Renovation Status: New

# IfcBuildingElementProxy: Panel-Main-081, Klaas; Objekti nimi: Built-in CW Panel
In: KATUSEPLAAN
Type - ElementType: Element type Panel-Main-081
Material: Klaas
SEADMED - 02 Tähis: Panel-Main-081
AC_Pset_RenovationAndPhasing - Renovation Status: New

# IfcBuildingElementProxy: Panel-Main-100, Klaas; Objekti nimi: Built-in CW Panel
In: KATUSEPLAAN
Type - ElementType: Element type Panel-Main-100
Material: Klaas
SEADMED - 02 Tähis: Panel-Main-100
AC_Pset_RenovationAndPhasing - Renovation Status: New

# IfcBuildingElementProxy: Panel-Main-104, Klaas; Objekti nimi: Built-in CW Panel
In: KATUSEPLAAN
Type - ElementType: Element type Panel-Main-104
Material: Klaas
SEADMED - 02 Tähis: Panel-Main-104
AC_Pset_RenovationAndPhasing - Renovation Status: New

# IfcBuildingElementProxy: Panel-Main-105, Klaas; Objekti nimi: Built-in CW Panel
In: KATUSEPLAAN
Type - ElementType: Element type Panel-Main-105
Material: Klaas
SEADMED - 02 Tähis: Panel-Main-105
AC_Pset_RenovationAndPhasing - Renovation Status: New

# IfcBuildingElementProxy: Panel-Main-107, Klaas; Objekti nimi: Built-in CW Panel
In: KATUSEPLAAN
Type - ElementType: Element type Panel-Main-107
Material: Klaas
SEADMED - 02 Tähis: Panel-Main-107
AC_Pset_RenovationAndPhasing - Renovation Status: New

# IfcBuildingElementProxy: Panel-Main-108, Klaas; Objekti nimi: Built-in CW Panel
In: KATUSEPLAAN
Type - ElementType: Element type Panel-Main-108
Material: Klaas
SEADMED - 02 Tähis: Panel-Main-108
AC_Pset_RenovationAndPhasing - Renovation Status: New

# IfcBuildingElementProxy: Panel-Main-110, Klaas; Objekti nimi: Built-in CW Panel
In: KATUSEPLAAN
Type - ElementType: Element type Panel-Main-110
Material: Klaas
SEADMED - 02 Tähis: Panel-Main-110
AC_Pset_RenovationAndPhasing - Renovation Status: New

# IfcBuildingElementProxy: Panel-Main-111, Klaas; Objekti nimi: Built-in CW Panel
In: KATUSEPLAAN
Type - ElementType: Element type Panel-Main-111
Material: Klaas
SEADMED - 02 Tähis: Panel-Main-111
AC_Pset_RenovationAndPhasing - Renovation Status: New

# IfcBuildingElementProxy: Panel-Main-113, Klaas; Objekti nimi: Built-in CW Panel
In: KATUSEPLAAN
Type - ElementType: Element type Panel-Main-113
Material: Klaas
SEADMED - 02 Tähis: Panel-Main-113
AC_Pset_RenovationAndPhasing - Renovation Status: New

# IfcBuildingElementProxy: Panel-Main-114, Klaas; Objekti nimi: Built-in CW Panel
In: KATUSEPLAAN
Type - ElementType: Element type Panel-Main-114
Material: Klaas
SEADMED - 02 Tähis: Panel-Main-114
AC_Pset_RenovationAndPhasing - Renovation Status: New

# IfcBuildingElementProxy: Panel-Main-115, Klaas; Objekti nimi: Built-in CW Panel
In: KATUSEPLAAN
Type - ElementType: Element type Panel-Main-115
Material: Klaas
SEADMED - 02 Tähis: Panel-Main-115
AC_Pset_RenovationAndPhasing - Renovation Status: New

# IfcBuildingElementProxy: Panel-Main-116, Klaas; Objekti nimi: Built-in CW Panel
In: KATUSEPLAAN
Type - ElementType: Element type Panel-Main-116
Material: Klaas
SEADMED - 02 Tähis: Panel-Main-116
AC_Pset_RenovationAndPhasing - Renovation Status: New

# IfcBuildingElementProxy: Panel-Main-117, Klaas; Objekti nimi: Built-in CW Panel
In: KATUSEPLAAN
Type - ElementType: Element type Panel-Main-117
Material: Klaas
SEADMED - 02 Tähis: Panel-Main-117
AC_Pset_RenovationAndPhasing - Renovation Status: New

# IfcBuildingElementProxy: Panel-Main-118, Klaas; Objekti nimi: Built-in CW Panel
In: KATUSEPLAAN
Type - ElementType: Element type Panel-Main-118
Material: Klaas
SEADMED - 02 Tähis: Panel-Main-118
AC_Pset_RenovationAndPhasing - Renovation Status: New

# IfcBuildingElementProxy: Panel-Main-119, Klaas; Objekti nimi: Built-in CW Panel
In: KATUSEPLAAN
Type - ElementType: Element type Panel-Main-119
Material: Klaas
SEADMED - 02 Tähis: Panel-Main-119
AC_Pset_RenovationAndPhasing - Renovation Status: New

# IfcBuildingElementProxy: Panel-Main-120, Klaas; Objekti nimi: Built-in CW Panel
In: KATUSEPLAAN
Type - ElementType: Element type Panel-Main-120
Material: Klaas
SEADMED - 02 Tähis: Panel-Main-120
AC_Pset_RenovationAndPhasing - Renovation Status: New

# IfcBuildingElementProxy: Panel-Main-121, Klaas; Objekti nimi: Built-in CW Panel
In: KATUSEPLAAN
Type - ElementType: Element type Panel-Main-121
Material: Klaas
SEADMED - 02 Tähis: Panel-Main-121
AC_Pset_RenovationAndPhasing - Renovation Status: New

# IfcBuildingElementProxy: Panel-Main-122, Klaas; Objekti nimi: Built-in CW Panel
In: KATUSEPLAAN
Type - ElementType: Element type Panel-Main-122
Material: Klaas
SEADMED - 02 Tähis: Panel-Main-122
AC_Pset_RenovationAndPhasing - Renovation Status: New

# IfcBuildingElementProxy: Panel-Main-123, Klaas; Objekti nimi: Built-in CW Panel
In: KATUSEPLAAN
Type - ElementType: Element type Panel-Main-123
Material: Klaas
SEADMED - 02 Tähis: Panel-Main-123
AC_Pset_RenovationAndPhasing - Renovation Status: New

# IfcBuildingElementProxy: Panel-Main-124, Klaas; Objekti nimi: Built-in CW Panel
In: KATUSEPLAAN
Type - ElementType: Element type Panel-Main-124
Material: Klaas
SEADMED - 02 Tähis: Panel-Main-124
AC_Pset_RenovationAndPhasing - Renovation Status: New

# IfcBuildingElementProxy: Panel-Main-125, Klaas; Objekti nimi: Built-in CW Panel
In: KATUSEPLAAN
Type - ElementType: Element type Panel-Main-125
Material: Klaas
SEADMED - 02 Tähis: Panel-Main-125
AC_Pset_RenovationAndPhasing - Renovation Status: New

# IfcBuildingElementProxy: Panel-Main-126, Klaas; Objekti nimi: Built-in CW Panel
In: KATUSEPLAAN
Type - ElementType: Element type Panel-Main-126
Material: Klaas
SEADMED - 02 Tähis: Panel-Main-126
AC_Pset_RenovationAndPhasing - Renovation Status: New

# IfcBuildingElementProxy: Panel-Main-127, Klaas; Objekti nimi: Built-in CW Panel
In: KATUSEPLAAN
Type - ElementType: Element type Panel-Main-127
Material: Klaas
SEADMED - 02 Tähis: Panel-Main-127
AC_Pset_RenovationAndPhasing - Renovation Status: New

# IfcBuildingElementProxy: Panel-Main-128, Klaas; Objekti nimi: Built-in CW Panel
In: KATUSEPLAAN
Type - ElementType: Element type Panel-Main-128
Material: Klaas
SEADMED - 02 Tähis: Panel-Main-128
AC_Pset_RenovationAndPhasing - Renovation Status: New

# IfcBuildingElementProxy: Panel-Main-129, Klaas; Objekti nimi: Built-in CW Panel
In: KATUSEPLAAN
Type - ElementType: Element type Panel-Main-129
Material: Klaas
SEADMED - 02 Tähis: Panel-Main-129
AC_Pset_RenovationAndPhasing - Renovation Status: New

# IfcBuildingElementProxy: Panel-Main-130, Klaas; Objekti nimi: Built-in CW Panel
In: KATUSEPLAAN
Type - ElementType: Element type Panel-Main-130
Material: Klaas
SEADMED - 02 Tähis: Panel-Main-130
AC_Pset_RenovationAndPhasing - Renovation Status: New

# IfcBuildingElementProxy: Panel-Main-131, Klaas; Objekti nimi: Built-in CW Panel
In: KATUSEPLAAN
Type - ElementType: Element type Panel-Main-131
Material: Klaas
SEADMED - 02 Tähis: Panel-Main-131
AC_Pset_RenovationAndPhasing - Renovation Status: New

# IfcBuildingElementProxy: Panel-Main-132, Klaas; Objekti nimi: Built-in CW Panel
In: KATUSEPLAAN
Type - ElementType: Element type Panel-Main-132
Material: Klaas
SEADMED - 02 Tähis: Panel-Main-132
AC_Pset_RenovationAndPhasing - Renovation Status: New

# IfcBuildingElementProxy: Panel-Main-133, Klaas; Objekti nimi: Built-in CW Panel
In: KATUSEPLAAN
Type - ElementType: Element type Panel-Main-133
Material: Klaas
SEADMED - 02 Tähis: Panel-Main-133
AC_Pset_RenovationAndPhasing - Renovation Status: New

# IfcBuildingElementProxy: Panel-Main-134, Klaas; Objekti nimi: Built-in CW Panel
In: KATUSEPLAAN
Type - ElementType: Element type Panel-Main-134
Material: Klaas
SEADMED - 02 Tähis: Panel-Main-134
AC_Pset_RenovationAndPhasing - Renovation Status: New

# IfcBuildingElementProxy: Panel-Main-135, Klaas; Objekti nimi: Built-in CW Panel
In: KATUSEPLAAN
Type - ElementType: Element type Panel-Main-135
Material: Klaas
SEADMED - 02 Tähis: Panel-Main-135
AC_Pset_RenovationAndPhasing - Renovation Status: New

# IfcBuildingElementProxy: Panel-Main-136, Klaas; Objekti nimi: Built-in CW Panel
In: KATUSEPLAAN
Type - ElementType: Element type Panel-Main-136
Material: Klaas
SEADMED - 02 Tähis: Panel-Main-136
AC_Pset_RenovationAndPhasing - Renovation Status: New

# IfcBuildingElementProxy: Panel-Main-137, Klaas; Objekti nimi: Built-in CW Panel
In: KATUSEPLAAN
Type - ElementType: Element type Panel-Main-137
Material: Klaas
SEADMED - 02 Tähis: Panel-Main-137
AC_Pset_RenovationAndPhasing - Renovation Status: New

# IfcBuildingElementProxy: Panel-Main-138, Klaas; Objekti nimi: Built-in CW Panel
In: KATUSEPLAAN
Type - ElementType: Element type Panel-Main-138
Material: Klaas
SEADMED - 02 Tähis: Panel-Main-138
AC_Pset_RenovationAndPhasing - Renovation Status: New

# IfcBuildingElementProxy: Panel-Main-139, Klaas; Objekti nimi: Built-in CW Panel
In: KATUSEPLAAN
Type - ElementType: Element type Panel-Main-139
Material: Klaas
SEADMED - 02 Tähis: Panel-Main-139
AC_Pset_RenovationAndPhasing - Renovation Status: New

# IfcBuildingElementProxy: Panel-Main-140, Klaas; Objekti nimi: Built-in CW Panel
In: KATUSEPLAAN
Type - ElementType: Element type Panel-Main-140
Material: Klaas
SEADMED - 02 Tähis: Panel-Main-140
AC_Pset_RenovationAndPhasing - Renovation Status: New

# IfcBuildingElementProxy: Panel-Main-141, Klaas; Objekti nimi: Built-in CW Panel
In: KATUSEPLAAN
Type - ElementType: Element type Panel-Main-141
Material: Klaas
SEADMED - 02 Tähis: Panel-Main-141
AC_Pset_RenovationAndPhasing - Renovation Status: New

# IfcBuildingElementProxy: Panel-Main-142, Klaas; Objekti nimi: Built-in CW Panel
In: KATUSEPLAAN
Type - ElementType: Element type Panel-Main-142
Material: Klaas
SEADMED - 02 Tähis: Panel-Main-142
AC_Pset_RenovationAndPhasing - Renovation Status: New

# IfcBuildingElementProxy: Panel-Main-143, Klaas; Objekti nimi: Built-in CW Panel
In: KATUSEPLAAN
Type - ElementType: Element type Panel-Main-143
Material: Klaas
SEADMED - 02 Tähis: Panel-Main-143
AC_Pset_RenovationAndPhasing - Renovation Status: New

# IfcBuildingElementProxy: Panel-Main-144, Klaas; Objekti nimi: Built-in CW Panel
In: KATUSEPLAAN
Type - ElementType: Element type Panel-Main-144
Material: Klaas
SEADMED - 02 Tähis: Panel-Main-144
AC_Pset_RenovationAndPhasing - Renovation Status: New

# IfcBuildingElementProxy: Panel-Main-145, Klaas; Objekti nimi: Built-in CW Panel
In: KATUSEPLAAN
Type - ElementType: Element type Panel-Main-145
Material: Klaas
SEADMED - 02 Tähis: Panel-Main-145
AC_Pset_RenovationAndPhasing - Renovation Status: New

# IfcBuildingElementProxy: Panel-Main-146, Klaas; Objekti nimi: Built-in CW Panel
In: KATUSEPLAAN
Type - ElementType: Element type Panel-Main-146
Material: Klaas
SEADMED - 02 Tähis: Panel-Main-146
AC_Pset_RenovationAndPhasing - Renovation Status: New

# IfcBuildingElementProxy: Panel-Main-147, Klaas; Objekti nimi: Built-in CW Panel
In: KATUSEPLAAN
Type - ElementType: Element type Panel-Main-147
Material: Klaas
SEADMED - 02 Tähis: Panel-Main-147
AC_Pset_RenovationAndPhasing - Renovation Status: New

# IfcBuildingElementProxy: Panel-Main-148, Klaas; Objekti nimi: Built-in CW Panel
In: KATUSEPLAAN
Type - ElementType: Element type Panel-Main-148
Material: Klaas
SEADMED - 02 Tähis: Panel-Main-148
AC_Pset_RenovationAndPhasing - Renovation Status: New

# IfcBuildingElementProxy: Panel-Main-149, Klaas; Objekti nimi: Built-in CW Panel
In: KATUSEPLAAN
Type - ElementType: Element type Panel-Main-149
Material: Klaas
SEADMED - 02 Tähis: Panel-Main-149
AC_Pset_RenovationAndPhasing - Renovation Status: New

# IfcBuildingElementProxy: Panel-Main-150, Klaas; Objekti nimi: Built-in CW Panel
In: KATUSEPLAAN
Type - ElementType: Element type Panel-Main-150
Material: Klaas
SEADMED - 02 Tähis: Panel-Main-150
AC_Pset_RenovationAndPhasing - Renovation Status: New

# IfcBuildingElementProxy: Panel-Main-151, Klaas; Objekti nimi: Built-in CW Panel
In: KATUSEPLAAN
Type - ElementType: Element type Panel-Main-151
Material: Klaas
SEADMED - 02 Tähis: Panel-Main-151
AC_Pset_RenovationAndPhasing - Renovation Status: New

# IfcBuildingElementProxy: Panel-Main-152, Klaas; Objekti nimi: Built-in CW Panel
In: KATUSEPLAAN
Type - ElementType: Element type Panel-Main-152
Material: Klaas
SEADMED - 02 Tähis: Panel-Main-152
AC_Pset_RenovationAndPhasing - Renovation Status: New

# IfcBuildingElementProxy: Panel-Main-153, Klaas; Objekti nimi: Built-in CW Panel
In: KATUSEPLAAN
Type - ElementType: Element type Panel-Main-153
Material: Klaas
SEADMED - 02 Tähis: Panel-Main-153
AC_Pset_RenovationAndPhasing - Renovation Status: New

# IfcBuildingElementProxy: Panel-Main-154, Klaas; Objekti nimi: Built-in CW Panel
In: KATUSEPLAAN
Type - ElementType: Element type Panel-Main-154
Material: Klaas
SEADMED - 02 Tähis: Panel-Main-154
AC_Pset_RenovationAndPhasing - Renovation Status: New

# IfcBuildingElementProxy: Panel-Main-155, Klaas; Objekti nimi: Built-in CW Panel
In: KATUSEPLAAN
Type - ElementType: Element type Panel-Main-155
Material: Klaas
SEADMED - 02 Tähis: Panel-Main-155
AC_Pset_RenovationAndPhasing - Renovation Status: New

# IfcBuildingElementProxy: Panel-Main-157, Klaas; Objekti nimi: Built-in CW Panel
In: KATUSEPLAAN
Type - ElementType: Element type Panel-Main-157
Material: Klaas
SEADMED - 02 Tähis: Panel-Main-157
AC_Pset_RenovationAndPhasing - Renovation Status: New

# IfcBuildingElementProxy: Panel-Main-158, Klaas; Objekti nimi: Built-in CW Panel
In: KATUSEPLAAN
Type - ElementType: Element type Panel-Main-158
Material: Klaas
SEADMED - 02 Tähis: Panel-Main-158
AC_Pset_RenovationAndPhasing - Renovation Status: New

# IfcBuildingElementProxy: Panel-Main-159, Klaas; Objekti nimi: Built-in CW Panel
In: KATUSEPLAAN
Type - ElementType: Element type Panel-Main-159
Material: Klaas
SEADMED - 02 Tähis: Panel-Main-159
AC_Pset_RenovationAndPhasing - Renovation Status: New

# IfcBuildingElementProxy: Panel-Main-160, Klaas; Objekti nimi: Built-in CW Panel
In: KATUSEPLAAN
Type - ElementType: Element type Panel-Main-160
Material: Klaas
SEADMED - 02 Tähis: Panel-Main-160
AC_Pset_RenovationAndPhasing - Renovation Status: New

# IfcBuildingElementProxy: Panel-Main-161, Klaas; Objekti nimi: Built-in CW Panel
In: KATUSEPLAAN
Type - ElementType: Element type Panel-Main-161
Material: Klaas
SEADMED - 02 Tähis: Panel-Main-161
AC_Pset_RenovationAndPhasing - Renovation Status: New

# IfcBuildingElementProxy: Panel-Main-163, Klaas; Objekti nimi: Built-in CW Panel
In: KATUSEPLAAN
Type - ElementType: Element type Panel-Main-163
Material: Klaas
SEADMED - 02 Tähis: Panel-Main-163
AC_Pset_RenovationAndPhasing - Renovation Status: New

# IfcBuildingElementProxy: Panel-Main-164, Klaas; Objekti nimi: Built-in CW Panel
In: KATUSEPLAAN
Type - ElementType: Element type Panel-Main-164
Material: Klaas
SEADMED - 02 Tähis: Panel-Main-164
AC_Pset_RenovationAndPhasing - Renovation Status: New

# IfcBuildingElementProxy: Panel-Main-165, Klaas; Objekti nimi: Built-in CW Panel
In: KATUSEPLAAN
Type - ElementType: Element type Panel-Main-165
Material: Klaas
SEADMED - 02 Tähis: Panel-Main-165
AC_Pset_RenovationAndPhasing - Renovation Status: New

# IfcBuildingElementProxy: Panel-Main-166, Klaas; Objekti nimi: Built-in CW Panel
In: KATUSEPLAAN
Type - ElementType: Element type Panel-Main-166
Material: Klaas
SEADMED - 02 Tähis: Panel-Main-166
AC_Pset_RenovationAndPhasing - Renovation Status: New

# IfcBuildingElementProxy: Panel-Main-167, Klaas; Objekti nimi: Built-in CW Panel
In: KATUSEPLAAN
Type - ElementType: Element type Panel-Main-167
Material: Klaas
SEADMED - 02 Tähis: Panel-Main-167
AC_Pset_RenovationAndPhasing - Renovation Status: New

# IfcBuildingElementProxy: Panel-Main-169, Klaas; Objekti nimi: Built-in CW Panel
In: KATUSEPLAAN
Type - ElementType: Element type Panel-Main-169
Material: Klaas
SEADMED - 02 Tähis: Panel-Main-169
AC_Pset_RenovationAndPhasing - Renovation Status: New

# IfcBuildingElementProxy: Panel-Main-170, Klaas; Objekti nimi: Built-in CW Panel
In: KATUSEPLAAN
Type - ElementType: Element type Panel-Main-170
Material: Klaas
SEADMED - 02 Tähis: Panel-Main-170
AC_Pset_RenovationAndPhasing - Renovation Status: New

# IfcBuildingElementProxy: Panel-Main-171, Klaas; Objekti nimi: Built-in CW Panel
In: KATUSEPLAAN
Type - ElementType: Element type Panel-Main-171
Material: Klaas
SEADMED - 02 Tähis: Panel-Main-171
AC_Pset_RenovationAndPhasing - Renovation Status: New

# IfcBuildingElementProxy: Panel-Main-172, Klaas; Objekti nimi: Built-in CW Panel
In: KATUSEPLAAN
Type - ElementType: Element type Panel-Main-172
Material: Klaas
SEADMED - 02 Tähis: Panel-Main-172
AC_Pset_RenovationAndPhasing - Renovation Status: New

# IfcBuildingElementProxy: Panel-Main-173, Klaas; Objekti nimi: Built-in CW Panel
In: KATUSEPLAAN
Type - ElementType: Element type Panel-Main-173
Material: Klaas
SEADMED - 02 Tähis: Panel-Main-173
AC_Pset_RenovationAndPhasing - Renovation Status: New

# IfcBuildingElementProxy: Panel-Main-175, Klaas; Objekti nimi: Built-in CW Panel
In: KATUSEPLAAN
Type - ElementType: Element type Panel-Main-175
Material: Klaas
SEADMED - 02 Tähis: Panel-Main-175
AC_Pset_RenovationAndPhasing - Renovation Status: New

# IfcBuildingElementProxy: Panel-Main-177, Klaas; Objekti nimi: Built-in CW Panel
In: KATUSEPLAAN
Type - ElementType: Element type Panel-Main-177
Material: Klaas
SEADMED - 02 Tähis: Panel-Main-177
AC_Pset_RenovationAndPhasing - Renovation Status: New

# IfcBuildingElementProxy: Panel-Main-179, Klaas; Objekti nimi: Built-in CW Panel
In: KATUSEPLAAN
Type - ElementType: Element type Panel-Main-179
Material: Klaas
SEADMED - 02 Tähis: Panel-Main-179
AC_Pset_RenovationAndPhasing - Renovation Status: New

# IfcBuildingElementProxy: Panel-Main-180, Klaas; Objekti nimi: Built-in CW Panel
In: KATUSEPLAAN
Type - ElementType: Element type Panel-Main-180
Material: Klaas
SEADMED - 02 Tähis: Panel-Main-180
AC_Pset_RenovationAndPhasing - Renovation Status: New

# IfcBuildingElementProxy: Panel-Main-181, Klaas; Objekti nimi: Built-in CW Panel
In: KATUSEPLAAN
Type - ElementType: Element type Panel-Main-181
Material: Klaas
SEADMED - 02 Tähis: Panel-Main-181
AC_Pset_RenovationAndPhasing - Renovation Status: New

# IfcBuildingElementProxy: Panel-Main-182, Klaas; Objekti nimi: Built-in CW Panel
In: KATUSEPLAAN
Type - ElementType: Element type Panel-Main-182
Material: Klaas
SEADMED - 02 Tähis: Panel-Main-182
AC_Pset_RenovationAndPhasing - Renovation Status: New

# IfcBuildingElementProxy: Panel-Main-207, Klaas; Objekti nimi: Built-in CW Panel
In: KATUSEPLAAN
Type - ElementType: Element type Panel-Main-207
Material: Klaas
SEADMED - 02 Tähis: Panel-Main-207
AC_Pset_RenovationAndPhasing - Renovation Status: New

# IfcBuildingElementProxy: Panel-Main-208, Klaas; Objekti nimi: Built-in CW Panel
In: KATUSEPLAAN
Type - ElementType: Element type Panel-Main-208
Material: Klaas
SEADMED - 02 Tähis: Panel-Main-208
AC_Pset_RenovationAndPhasing - Renovation Status: New

# IfcBuildingElementProxy: Panel-Main-209, Klaas; Objekti nimi: Built-in CW Panel
In: KATUSEPLAAN
Type - ElementType: Element type Panel-Main-209
Material: Klaas
SEADMED - 02 Tähis: Panel-Main-209
AC_Pset_RenovationAndPhasing - Renovation Status: New

# IfcBuildingElementProxy: Panel-Main-210, Klaas; Objekti nimi: Built-in CW Panel
In: KATUSEPLAAN
Type - ElementType: Element type Panel-Main-210
Material: Klaas
SEADMED - 02 Tähis: Panel-Main-210
AC_Pset_RenovationAndPhasing - Renovation Status: New

# IfcBuildingElementProxy: Panel-Main-211, Klaas; Objekti nimi: Built-in CW Panel
In: KATUSEPLAAN
Type - ElementType: Element type Panel-Main-211
Material: Klaas
SEADMED - 02 Tähis: Panel-Main-211
AC_Pset_RenovationAndPhasing - Renovation Status: New

# IfcBuildingElementProxy: Panel-Main-212, Klaas; Objekti nimi: Built-in CW Panel
In: KATUSEPLAAN
Type - ElementType: Element type Panel-Main-212
Material: Klaas
SEADMED - 02 Tähis: Panel-Main-212
AC_Pset_RenovationAndPhasing - Renovation Status: New

# IfcBuildingElementProxy: Panel-Main-213, Klaas; Objekti nimi: Built-in CW Panel
In: KATUSEPLAAN
Type - ElementType: Element type Panel-Main-213
Material: Klaas
SEADMED - 02 Tähis: Panel-Main-213
AC_Pset_RenovationAndPhasing - Renovation Status: New

# IfcBuildingElementProxy: Panel-Main-214, Klaas; Objekti nimi: Built-in CW Panel
In: KATUSEPLAAN
Type - ElementType: Element type Panel-Main-214
Material: Klaas
SEADMED - 02 Tähis: Panel-Main-214
AC_Pset_RenovationAndPhasing - Renovation Status: New

# IfcBuildingElementProxy: Panel-Main-215, Klaas; Objekti nimi: Built-in CW Panel
In: KATUSEPLAAN
Type - ElementType: Element type Panel-Main-215
Material: Klaas
SEADMED - 02 Tähis: Panel-Main-215
AC_Pset_RenovationAndPhasing - Renovation Status: New

# IfcBuildingElementProxy: Panel-Main-216, Klaas; Objekti nimi: Built-in CW Panel
In: KATUSEPLAAN
Type - ElementType: Element type Panel-Main-216
Material: Klaas
SEADMED - 02 Tähis: Panel-Main-216
AC_Pset_RenovationAndPhasing - Renovation Status: New

# IfcBuildingElementProxy: Panel-Main-217, Klaas; Objekti nimi: Built-in CW Panel
In: KATUSEPLAAN
Type - ElementType: Element type Panel-Main-217
Material: Klaas
SEADMED - 02 Tähis: Panel-Main-217
AC_Pset_RenovationAndPhasing - Renovation Status: New

# IfcBuildingElementProxy: Panel-Main-218, Klaas; Objekti nimi: Built-in CW Panel
In: KATUSEPLAAN
Type - ElementType: Element type Panel-Main-218
Material: Klaas
SEADMED - 02 Tähis: Panel-Main-218
AC_Pset_RenovationAndPhasing - Renovation Status: New

# IfcBuildingElementProxy: Panel-Main-219, Klaas; Objekti nimi: Built-in CW Panel
In: KATUSEPLAAN
Type - ElementType: Element type Panel-Main-219
Material: Klaas
SEADMED - 02 Tähis: Panel-Main-219
AC_Pset_RenovationAndPhasing - Renovation Status: New

# IfcBuildingElementProxy: Panel-Main-220, Klaas; Objekti nimi: Built-in CW Panel
In: KATUSEPLAAN
Type - ElementType: Element type Panel-Main-220
Material: Klaas
SEADMED - 02 Tähis: Panel-Main-220
AC_Pset_RenovationAndPhasing - Renovation Status: New

# IfcBuildingElementProxy: Panel-Main-221, Klaas; Objekti nimi: Built-in CW Panel
In: KATUSEPLAAN
Type - ElementType: Element type Panel-Main-221
Material: Klaas
SEADMED - 02 Tähis: Panel-Main-221
AC_Pset_RenovationAndPhasing - Renovation Status: New

# IfcBuildingElementProxy: Panel-Main-222, Klaas; Objekti nimi: Built-in CW Panel
In: KATUSEPLAAN
Type - ElementType: Element type Panel-Main-222
Material: Klaas
SEADMED - 02 Tähis: Panel-Main-222
AC_Pset_RenovationAndPhasing - Renovation Status: New

# IfcBuildingElementProxy: Panel-Main-223, Klaas; Objekti nimi: Built-in CW Panel
In: KATUSEPLAAN
Type - ElementType: Element type Panel-Main-223
Material: Klaas
SEADMED - 02 Tähis: Panel-Main-223
AC_Pset_RenovationAndPhasing - Renovation Status: New

# IfcBuildingElementProxy: Panel-Main-224, Klaas; Objekti nimi: Built-in CW Panel
In: KATUSEPLAAN
Type - ElementType: Element type Panel-Main-224
Material: Klaas
SEADMED - 02 Tähis: Panel-Main-224
AC_Pset_RenovationAndPhasing - Renovation Status: New

# IfcBuildingElementProxy: Panel-Main-225, Klaas; Objekti nimi: Built-in CW Panel
In: KATUSEPLAAN
Type - ElementType: Element type Panel-Main-225
Material: Klaas
SEADMED - 02 Tähis: Panel-Main-225
AC_Pset_RenovationAndPhasing - Renovation Status: New

# IfcBuildingElementProxy: Panel-Main-226, Klaas; Objekti nimi: Built-in CW Panel
In: KATUSEPLAAN
Type - ElementType: Element type Panel-Main-226
Material: Klaas
SEADMED - 02 Tähis: Panel-Main-226
AC_Pset_RenovationAndPhasing - Renovation Status: New

# IfcBuildingElementProxy: Panel-Main-227, Klaas; Objekti nimi: Built-in CW Panel
In: KATUSEPLAAN
Type - ElementType: Element type Panel-Main-227
Material: Klaas
SEADMED - 02 Tähis: Panel-Main-227
AC_Pset_RenovationAndPhasing - Renovation Status: New

# IfcBuildingElementProxy: Panel-Main-228, Klaas; Objekti nimi: Built-in CW Panel
In: KATUSEPLAAN
Type - ElementType: Element type Panel-Main-228
Material: Klaas
SEADMED - 02 Tähis: Panel-Main-228
AC_Pset_RenovationAndPhasing - Renovation Status: New

# IfcBuildingElementProxy: Panel-Main-229, Klaas; Objekti nimi: Built-in CW Panel
In: KATUSEPLAAN
Type - ElementType: Element type Panel-Main-229
Material: Klaas
SEADMED - 02 Tähis: Panel-Main-229
AC_Pset_RenovationAndPhasing - Renovation Status: New

# IfcBuildingElementProxy: Panel-Main-230, Klaas; Objekti nimi: Built-in CW Panel
In: KATUSEPLAAN
Type - ElementType: Element type Panel-Main-230
Material: Klaas
SEADMED - 02 Tähis: Panel-Main-230
AC_Pset_RenovationAndPhasing - Renovation Status: New

# IfcBuildingElementProxy: Panel-Main-399, Klaas (1); Objekti nimi: Built-in CW Panel
In: 2 KORRUS
Type - ElementType: Element type Panel-Main-399
Material: Klaas (1)
SEADMED - 02 Tähis: Panel-Main-399
AC_Pset_RenovationAndPhasing - Renovation Status: New

# IfcBuildingElementProxy: Panel-Main-400, Klaas (1); Objekti nimi: Built-in CW Panel
In: 2 KORRUS
Type - ElementType: Element type Panel-Main-400
Material: Klaas (1)
SEADMED - 02 Tähis: Panel-Main-400
AC_Pset_RenovationAndPhasing - Renovation Status: New

# IfcBuildingElementProxy: Panel-Main-401 (2)
In: 2 KORRUS
Type - ElementType: Element type Panel-Main-401
Material: Klaas (1)
SEADMED - 02 Tähis: Panel-Main-401
AC_Pset_RenovationAndPhasing - Renovation Status: New

# IfcBuildingElementProxy: Panel-Main-402 (2)
In: 2 KORRUS
Type - ElementType: Element type Panel-Main-402
Material: Klaas (1)
SEADMED - 02 Tähis: Panel-Main-402
AC_Pset_RenovationAndPhasing - Renovation Status: New

# IfcBuildingElementProxy: Panel-Main-403 (2)
In: 2 KORRUS
Type - ElementType: Element type Panel-Main-403
Material: Klaas (1)
SEADMED - 02 Tähis: Panel-Main-403
AC_Pset_RenovationAndPhasing - Renovation Status: New

# IfcBuildingElementProxy: Panel-Main-404 (2)
In: 2 KORRUS
Type - ElementType: Element type Panel-Main-404
Material: Klaas (1)
SEADMED - 02 Tähis: Panel-Main-404
AC_Pset_RenovationAndPhasing - Renovation Status: New

# IfcBuildingElementProxy: Panel-Main-405 (2)
In: 2 KORRUS
Type - ElementType: Element type Panel-Main-405
Material: Klaas (1)
SEADMED - 02 Tähis: Panel-Main-405
AC_Pset_RenovationAndPhasing - Renovation Status: New

# IfcBuildingElementProxy: Panel-Main-406 (2)
In: 2 KORRUS
Type - ElementType: Element type Panel-Main-406
Material: Klaas (1)
SEADMED - 02 Tähis: Panel-Main-406
AC_Pset_RenovationAndPhasing - Renovation Status: New

# IfcBuildingElementProxy: Panel-Main-407 (2)
In: 2 KORRUS
Type - ElementType: Element type Panel-Main-407
Material: Klaas (1)
SEADMED - 02 Tähis: Panel-Main-407
AC_Pset_RenovationAndPhasing - Renovation Status: New

# IfcBuildingElementProxy: Panel-Main-408 (2)
In: 2 KORRUS
Type - ElementType: Element type Panel-Main-408
Material: Klaas (1)
SEADMED - 02 Tähis: Panel-Main-408
AC_Pset_RenovationAndPhasing - Renovation Status: New

# IfcBuildingElementProxy: Panel-Main-409 (2)
In: 2 KORRUS
Type - ElementType: Element type Panel-Main-409
Material: Klaas (1)
SEADMED - 02 Tähis: Panel-Main-409
AC_Pset_RenovationAndPhasing - Renovation Status: New

# IfcBuildingElementProxy: Panel-Main-410, Klaas (1); Objekti nimi: Built-in CW Panel
In: 2 KORRUS
Type - ElementType: Element type Panel-Main-410
Material: Klaas (1)
SEADMED - 02 Tähis: Panel-Main-410
AC_Pset_RenovationAndPhasing - Renovation Status: New

# IfcBuildingElementProxy: Panel-Main-411, Klaas (1); Objekti nimi: Built-in CW Panel
In: 2 KORRUS
Type - ElementType: Element type Panel-Main-411
Material: Klaas (1)
SEADMED - 02 Tähis: Panel-Main-411
AC_Pset_RenovationAndPhasing - Renovation Status: New

# IfcBuildingElementProxy: Panel-Main-412, Klaas (1); Objekti nimi: Built-in CW Panel
In: 1 KORRUS
Type - ElementType: Element type Panel-Main-412
Material: Klaas (1)
SEADMED - 02 Tähis: Panel-Main-412
AC_Pset_RenovationAndPhasing - Renovation Status: New

# IfcBuildingElementProxy: Panel-Main-413, Klaas (1); Objekti nimi: Built-in CW Panel
In: 1 KORRUS
Type - ElementType: Element type Panel-Main-413
Material: Klaas (1)
SEADMED - 02 Tähis: Panel-Main-413
AC_Pset_RenovationAndPhasing - Renovation Status: New

# IfcBuildingElementProxy: Panel-Main-415, Klaas (1); Objekti nimi: Built-in CW Panel
In: 1 KORRUS
Type - ElementType: Element type Panel-Main-415
Material: Klaas (1)
SEADMED - 02 Tähis: Panel-Main-415
AC_Pset_RenovationAndPhasing - Renovation Status: New

# IfcBuildingElementProxy: Panel-Main-419, Klaas (1); Objekti nimi: Built-in CW Panel
In: 1 KORRUS
Type - ElementType: Element type Panel-Main-419
Material: Klaas (1)
SEADMED - 02 Tähis: Panel-Main-419
AC_Pset_RenovationAndPhasing - Renovation Status: New

# IfcBuildingElementProxy: Panel-Main-420, Klaas (1); Objekti nimi: Built-in CW Panel
In: 1 KORRUS
Type - ElementType: Element type Panel-Main-420
Material: Klaas (1)
SEADMED - 02 Tähis: Panel-Main-420
AC_Pset_RenovationAndPhasing - Renovation Status: New

# IfcBuildingElementProxy: Panel-Main-421, Klaas (1); Objekti nimi: Built-in CW Panel
In: 1 KORRUS
Type - ElementType: Element type Panel-Main-421
Material: Klaas (1)
SEADMED - 02 Tähis: Panel-Main-421
AC_Pset_RenovationAndPhasing - Renovation Status: New

# IfcBuildingElementProxy: Panel-Main-422, Klaas (1); Objekti nimi: Built-in CW Panel
In: 1 KORRUS
Type - ElementType: Element type Panel-Main-422
Material: Klaas (1)
SEADMED - 02 Tähis: Panel-Main-422
AC_Pset_RenovationAndPhasing - Renovation Status: New

# IfcBuildingElementProxy: Panel-Main-423, Klaas (1); Objekti nimi: Built-in CW Panel
In: 1 KORRUS
Type - ElementType: Element type Panel-Main-423
Material: Klaas (1)
SEADMED - 02 Tähis: Panel-Main-423
AC_Pset_RenovationAndPhasing - Renovation Status: New

# IfcBuildingElementProxy: Panel-Main-424, Klaas (1); Objekti nimi: Built-in CW Panel
In: 1 KORRUS
Type - ElementType: Element type Panel-Main-424
Material: Klaas (1)
SEADMED - 02 Tähis: Panel-Main-424
AC_Pset_RenovationAndPhasing - Renovation Status: New

# IfcBuildingElementProxy: SF RISER - 020 (49)
Type - ElementType: Element type SF RISER - 020
Material: Betoon - Ol.Olev konstruktsioon
SEADMED - 02 Tähis: SF RISER - 020
AC_Pset_RenovationAndPhasing - Renovation Status: Existing
Name (; Objekti nimi:...) | In
34 x  Riser 22 | 1 KORRUS
15 x  Riser 22 | 2 KORRUS

# IfcBuildingElementProxy: SF RISER - 025, ; Objekti nimi: Riser 22
In: 2 KORRUS
Type - ElementType: Element type SF RISER - 025
Material: Betoon - Ol.Olev konstruktsioon
SEADMED - 02 Tähis: SF RISER - 025
AC_Pset_RenovationAndPhasing - Renovation Status: Existing

# IfcBuildingElementProxy: SF RISER - 026, ; Objekti nimi: Riser 22
In: 2 KORRUS
Type - ElementType: Element type SF RISER - 026
Material: Betoon - Ol.Olev konstruktsioon
SEADMED - 02 Tähis: SF RISER - 026
AC_Pset_RenovationAndPhasing - Renovation Status: Existing

# IfcBuildingElementProxy: SF RISER - 027, ; Objekti nimi: Riser 22
In: 2 KORRUS
Type - ElementType: Element type SF RISER - 027
Material: Betoon - Ol.Olev konstruktsioon
SEADMED - 02 Tähis: SF RISER - 027
AC_Pset_RenovationAndPhasing - Renovation Status: Existing

# IfcBuildingElementProxy: SF RISER - 028, ; Objekti nimi: Riser 22
In: 2 KORRUS
Type - ElementType: Element type SF RISER - 028
Material: Betoon - Ol.Olev konstruktsioon
SEADMED - 02 Tähis: SF RISER - 028
AC_Pset_RenovationAndPhasing - Renovation Status: Existing

# IfcBuildingElementProxy: SF RISER - 051, ; Objekti nimi: Riser 22
In: 1 KORRUS
Type - ElementType: Element type SF RISER - 051
Material: Betoon - Ol.Olev konstruktsioon
SEADMED - 02 Tähis: SF RISER - 051
AC_Pset_RenovationAndPhasing - Renovation Status: Existing

# IfcBuildingElementProxy: SF RISER - 052, ; Objekti nimi: Riser 22
In: 1 KORRUS
Type - ElementType: Element type SF RISER - 052
Material: Betoon - Ol.Olev konstruktsioon
SEADMED - 02 Tähis: SF RISER - 052
AC_Pset_RenovationAndPhasing - Renovation Status: Existing

# IfcBuildingElementProxy: SF RISER - 053 (12)
In: 1 KORRUS
Type - ElementType: Element type SF RISER - 053
Material: Betoon - Ol.Olev konstruktsioon
SEADMED - 02 Tähis: SF RISER - 053
Name (; Objekti nimi:...) | Renovation Status
11 x  Riser 22 | New
 Riser 22 | Existing

# IfcBuildingElementProxy: SF RISER - 054 (2)
In: 1 KORRUS
Type - ElementType: Element type SF RISER - 054
Material: Betoon - Ol.Olev konstruktsioon
SEADMED - 02 Tähis: SF RISER - 054
Name (; Objekti nimi:...) | Renovation Status
 Riser 22 | New
 Riser 22 | Existing

# IfcBuildingElementProxy: SF RISER - 055 (2)
In: 1 KORRUS
Type - ElementType: Element type SF RISER - 055
Material: Betoon - Ol.Olev konstruktsioon
SEADMED - 02 Tähis: SF RISER - 055
Name (; Objekti nimi:...) | Renovation Status
 Riser 22 | New
 Riser 22 | Existing

# IfcBuildingElementProxy: SF RISER - 056, ; Objekti nimi: Riser 22
In: 1 KORRUS
Type - ElementType: Element type SF RISER - 056
Material: Betoon - Ol.Olev konstruktsioon
SEADMED - 02 Tähis: SF RISER - 056
AC_Pset_RenovationAndPhasing - Renovation Status: Existing

# IfcBuildingElementProxy: SF RISER - 057, ; Objekti nimi: Riser 22
In: 1 KORRUS
Type - ElementType: Element type SF RISER - 057
Material: Betoon - Ol.Olev konstruktsioon
SEADMED - 02 Tähis: SF RISER - 057
AC_Pset_RenovationAndPhasing - Renovation Status: Existing

# IfcBuildingElementProxy: SF RISER - 058, ; Objekti nimi: Riser 22
In: 1 KORRUS
Type - ElementType: Element type SF RISER - 058
Material: Betoon - Ol.Olev konstruktsioon
SEADMED - 02 Tähis: SF RISER - 058
AC_Pset_RenovationAndPhasing - Renovation Status: Existing

# IfcBuildingElementProxy: SF RISER - 059, ; Objekti nimi: Riser 22
In: 1 KORRUS
Type - ElementType: Element type SF RISER - 059
Material: Betoon - Ol.Olev konstruktsioon
SEADMED - 02 Tähis: SF RISER - 059
AC_Pset_RenovationAndPhasing - Renovation Status: Existing

# IfcBuildingElementProxy: SF RISER - 060, ; Objekti nimi: Riser 22
In: 1 KORRUS
Type - ElementType: Element type SF RISER - 060
Material: Betoon - Ol.Olev konstruktsioon
SEADMED - 02 Tähis: SF RISER - 060
AC_Pset_RenovationAndPhasing - Renovation Status: Existing

# IfcBuildingElementProxy: SF RISER - 061, ; Objekti nimi: Riser 22
In: 1 KORRUS
Type - ElementType: Element type SF RISER - 061
Material: Betoon - Ol.Olev konstruktsioon
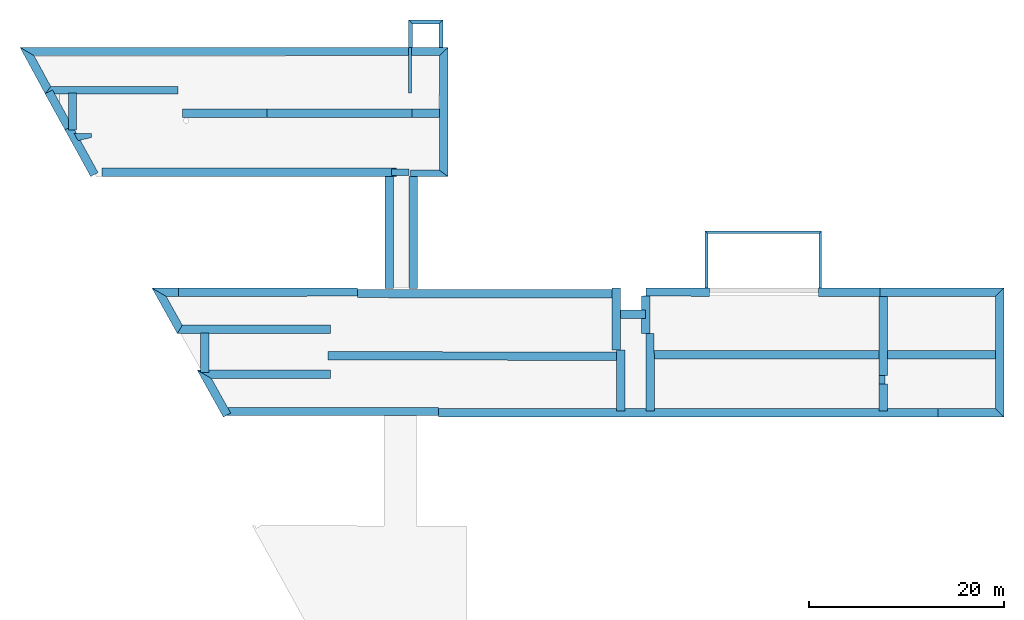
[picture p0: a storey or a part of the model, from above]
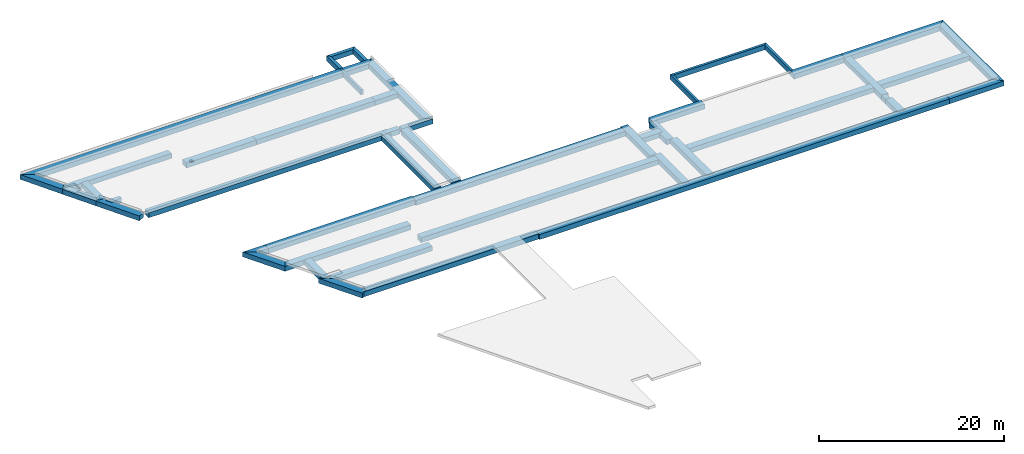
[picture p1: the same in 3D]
Properties of the parts of a building model (IFC2X3), part 4 of 14

# IfcBuildingElementProxy: SF RISER - 061, ; Objekti nimi: Riser 22
SEADMED - 02 Tähis: SF RISER - 061
AC_Pset_RenovationAndPhasing - Renovation Status: Existing

# IfcBuildingElementProxy: SF RISER - 062, ; Objekti nimi: Riser 22
In: 1 KORRUS
Type - ElementType: Element type SF RISER - 062
Material: Betoon - Ol.Olev konstruktsioon
SEADMED - 02 Tähis: SF RISER - 062
AC_Pset_RenovationAndPhasing - Renovation Status: Existing

# IfcBuildingElementProxy: SF RISER - 063, ; Objekti nimi: Riser 22
In: 1 KORRUS
Type - ElementType: Element type SF RISER - 063
Material: Betoon - Ol.Olev konstruktsioon
SEADMED - 02 Tähis: SF RISER - 063
AC_Pset_RenovationAndPhasing - Renovation Status: Existing

# IfcBuildingElementProxy: SF RISER - 064, ; Objekti nimi: Riser 22
In: 1 KORRUS
Type - ElementType: Element type SF RISER - 064
Material: Betoon - Ol.Olev konstruktsioon
SEADMED - 02 Tähis: SF RISER - 064
AC_Pset_RenovationAndPhasing - Renovation Status: Existing

# IfcBuildingElementProxy: SF RISER - 065, ; Objekti nimi: Riser 22
In: 1 KORRUS
Type - ElementType: Element type SF RISER - 065
Material: Betoon - Ol.Olev konstruktsioon
SEADMED - 02 Tähis: SF RISER - 065
AC_Pset_RenovationAndPhasing - Renovation Status: Existing

# IfcBuildingElementProxy: SF TREAD - 020 (48)
Type - ElementType: Element type SF TREAD - 020
Material: Betoon - Ol.Olev konstruktsioon
SEADMED - 02 Tähis: SF TREAD - 020
AC_Pset_RenovationAndPhasing - Renovation Status: Existing
Name (; Objekti nimi:...) | In
34 x  Tread 22 | 1 KORRUS
14 x  Tread 22 | 2 KORRUS

# IfcBuildingElementProxy: SF TREAD - 025, ; Objekti nimi: Tread 22
In: 2 KORRUS
Type - ElementType: Element type SF TREAD - 025
Material: Betoon - Ol.Olev konstruktsioon
SEADMED - 02 Tähis: SF TREAD - 025
AC_Pset_RenovationAndPhasing - Renovation Status: Existing

# IfcBuildingElementProxy: SF TREAD - 026, ; Objekti nimi: Tread 22
In: 2 KORRUS
Type - ElementType: Element type SF TREAD - 026
Material: Betoon - Ol.Olev konstruktsioon
SEADMED - 02 Tähis: SF TREAD - 026
AC_Pset_RenovationAndPhasing - Renovation Status: Existing

# IfcBuildingElementProxy: SF TREAD - 027, ; Objekti nimi: Tread 22
In: 2 KORRUS
Type - ElementType: Element type SF TREAD - 027
Material: Betoon - Ol.Olev konstruktsioon
SEADMED - 02 Tähis: SF TREAD - 027
AC_Pset_RenovationAndPhasing - Renovation Status: Existing

# IfcBuildingElementProxy: SF TREAD - 028, ; Objekti nimi: Tread 22
In: 2 KORRUS
Type - ElementType: Element type SF TREAD - 028
Material: Betoon - Ol.Olev konstruktsioon
SEADMED - 02 Tähis: SF TREAD - 028
AC_Pset_RenovationAndPhasing - Renovation Status: Existing

# IfcBuildingElementProxy: SF TREAD - 051, ; Objekti nimi: Tread 22
In: 1 KORRUS
Type - ElementType: Element type SF TREAD - 051
Material: Betoon - Ol.Olev konstruktsioon
SEADMED - 02 Tähis: SF TREAD - 051
AC_Pset_RenovationAndPhasing - Renovation Status: Existing

# IfcBuildingElementProxy: SF TREAD - 052, ; Objekti nimi: Tread 22
In: 1 KORRUS
Type - ElementType: Element type SF TREAD - 052
Material: Betoon - Ol.Olev konstruktsioon
SEADMED - 02 Tähis: SF TREAD - 052
AC_Pset_RenovationAndPhasing - Renovation Status: Existing

# IfcBuildingElementProxy: SF TREAD - 053 (12)
In: 1 KORRUS
Type - ElementType: Element type SF TREAD - 053
Material: Betoon - Ol.Olev konstruktsioon
SEADMED - 02 Tähis: SF TREAD - 053
Name (; Objekti nimi:...) | Renovation Status
11 x  Tread 22 | New
 Tread 22 | Existing

# IfcBuildingElementProxy: SF TREAD - 054 (2)
In: 1 KORRUS
Type - ElementType: Element type SF TREAD - 054
Material: Betoon - Ol.Olev konstruktsioon
SEADMED - 02 Tähis: SF TREAD - 054
Name (; Objekti nimi:...) | Renovation Status
 Tread 22 | New
 Tread 22 | Existing

# IfcBuildingElementProxy: SF TREAD - 055 (2)
In: 1 KORRUS
Type - ElementType: Element type SF TREAD - 055
Material: Betoon - Ol.Olev konstruktsioon
SEADMED - 02 Tähis: SF TREAD - 055
Name (; Objekti nimi:...) | Renovation Status
 Tread 22 | New
 Tread 22 | Existing

# IfcBuildingElementProxy: SF TREAD - 056, ; Objekti nimi: Tread 22
In: 1 KORRUS
Type - ElementType: Element type SF TREAD - 056
Material: Betoon - Ol.Olev konstruktsioon
SEADMED - 02 Tähis: SF TREAD - 056
AC_Pset_RenovationAndPhasing - Renovation Status: Existing

# IfcBuildingElementProxy: SF TREAD - 057, ; Objekti nimi: Tread 22
In: 1 KORRUS
Type - ElementType: Element type SF TREAD - 057
Material: Betoon - Ol.Olev konstruktsioon
SEADMED - 02 Tähis: SF TREAD - 057
AC_Pset_RenovationAndPhasing - Renovation Status: Existing

# IfcBuildingElementProxy: SF TREAD - 058, ; Objekti nimi: Tread 22
In: 1 KORRUS
Type - ElementType: Element type SF TREAD - 058
Material: Betoon - Ol.Olev konstruktsioon
SEADMED - 02 Tähis: SF TREAD - 058
AC_Pset_RenovationAndPhasing - Renovation Status: Existing

# IfcBuildingElementProxy: SF TREAD - 059, ; Objekti nimi: Tread 22
In: 1 KORRUS
Type - ElementType: Element type SF TREAD - 059
Material: Betoon - Ol.Olev konstruktsioon
SEADMED - 02 Tähis: SF TREAD - 059
AC_Pset_RenovationAndPhasing - Renovation Status: Existing

# IfcBuildingElementProxy: SF TREAD - 060, ; Objekti nimi: Tread 22
In: 1 KORRUS
Type - ElementType: Element type SF TREAD - 060
Material: Betoon - Ol.Olev konstruktsioon
SEADMED - 02 Tähis: SF TREAD - 060
AC_Pset_RenovationAndPhasing - Renovation Status: Existing

# IfcBuildingElementProxy: SF TREAD - 061, ; Objekti nimi: Tread 22
In: 1 KORRUS
Type - ElementType: Element type SF TREAD - 061
Material: Betoon - Ol.Olev konstruktsioon
SEADMED - 02 Tähis: SF TREAD - 061
AC_Pset_RenovationAndPhasing - Renovation Status: Existing

# IfcBuildingElementProxy: SF TREAD - 062, ; Objekti nimi: Tread 22
In: 1 KORRUS
Type - ElementType: Element type SF TREAD - 062
Material: Betoon - Ol.Olev konstruktsioon
SEADMED - 02 Tähis: SF TREAD - 062
AC_Pset_RenovationAndPhasing - Renovation Status: Existing

# IfcBuildingElementProxy: SF TREAD - 063, ; Objekti nimi: Tread 22
In: 1 KORRUS
Type - ElementType: Element type SF TREAD - 063
Material: Betoon - Ol.Olev konstruktsioon
SEADMED - 02 Tähis: SF TREAD - 063
AC_Pset_RenovationAndPhasing - Renovation Status: Existing

# IfcBuildingElementProxy: SF TREAD - 064, ; Objekti nimi: Tread 22
In: 1 KORRUS
Type - ElementType: Element type SF TREAD - 064
Material: Betoon - Ol.Olev konstruktsioon
SEADMED - 02 Tähis: SF TREAD - 064
AC_Pset_RenovationAndPhasing - Renovation Status: Existing

# IfcBuildingElementProxy: SF TREAD - 065, ; Objekti nimi: Tread 22
In: 1 KORRUS
Type - ElementType: Element type SF TREAD - 065
Material: Betoon - Ol.Olev konstruktsioon
SEADMED - 02 Tähis: SF TREAD - 065
AC_Pset_RenovationAndPhasing - Renovation Status: Existing

# IfcBuildingElementProxy: SL RISER - 004, ; Objekti nimi: Riser 22
In: 1 KORRUS
Type - ElementType: Element type SL RISER - 004
Material: Betoon - Ol.Olev konstruktsioon
SEADMED - 02 Tähis: SL RISER - 004
AC_Pset_RenovationAndPhasing - Renovation Status: Existing

# IfcBuildingElementProxy: SL STRUCTURE - 004, Betoon - Ol.Olev konstruktsioon; Objekti nimi:
In: 1 KORRUS
Type - ElementType: Element type SL STRUCTURE - 004
Material: Betoon - Ol.Olev konstruktsioon
SEADMED - 02 Tähis: SL STRUCTURE - 004
AC_Pset_RenovationAndPhasing - Renovation Status: Existing

# IfcBuildingElementProxy: SL TREAD - 004, ; Objekti nimi: Tread 22
In: 1 KORRUS
Type - ElementType: Element type SL TREAD - 004
Material: Betoon - Ol.Olev konstruktsioon
SEADMED - 02 Tähis: SL TREAD - 004
AC_Pset_RenovationAndPhasing - Renovation Status: Existing

# IfcBuildingElementProxy: SLA - 002, Betoon - Ol.Olev konstruktsioon; Objekti nimi:
In: 1 KORRUS
Type - ElementType: Element type SLA - 002
Classification: 1.2 IfcBuildingElementProxy (objekt) (_RKAS BIM + ARCHICAD Classification); Material: Betoon - Ol.Olev konstruktsioon
SEADMED - 02 Tähis: SLA - 002
AC_Pset_RenovationAndPhasing - Renovation Status: Existing

# IfcBuildingElementProxy: SLA - 003, MAA; Objekti nimi:
In: 1 KORRUS
Type - ElementType: Element type SLA - 003
Classification: 1.2 IfcBuildingElementProxy (objekt) (_RKAS BIM + ARCHICAD Classification); Material: MAA
SEADMED - 02 Tähis: SLA - 003
AC_Pset_RenovationAndPhasing - Renovation Status: Existing

# IfcBuildingElementProxy: SW - 001, PAEKIVISEIN; Objekti nimi:
In: VUNDAMENT
Type - ElementType: Element type SW - 001
Material: PAEKIVISEIN
SEADMED - 02 Tähis: SW - 001
AC_Pset_RenovationAndPhasing - Renovation Status: Existing

# IfcColumn: CRE - 003, Air Space
In: 1 KORRUS
Type - ElementType: Element type CRE - 003
Classification: 1.3 IfcColumn (post) (_RKAS BIM + ARCHICAD Classification)
Ehituskonstruktsioonid - 02 Materjal: Air Space; TERAS, valge copy; 01 Nimetus: Air Space; 03 Tähistus või ristlõige: CRE - 003; 06 Maht (kubatuur): 0,23; 11 Ülemine kõrgusmärk: 0 + Posti kõrgus: 2 600; 12 Alumine kõrgusmärk: 0
AC_Pset_RenovationAndPhasing - Renovation Status: Existing
Pset_ColumnCommon - Reference: Air Space D320

# IfcCovering: Kips, Kipsplaat
In: 1 KORRUS
Type - ElementType: Element type Kips
Description: šahti sein; Classification: 1.6 IfcCovering (pinnakatted) (_RKAS BIM + ARCHICAD Classification); 543 Lagede metall- ja plekk-katted, ripplaed (EHITUSKULUDE LIIGITAMINE EVS 885:2005); Material: Kipsplaat
Ripplagi - 04 Paksus: 13 mm; 01 Nimetus: Kipsplaat; 02 Materjal: Kipsplaat; 05 Pindala: 1,26
Pset_CoveringCommon - Material: Kipsplaat
Pinnakatted - 01 Nimetus: Undefined; 02 Materjal: Undefined; 03 Kategooria / tüüp: Kips Undefined; 04 Paksus: Mudelis: 13mm Käsitsi sisestatud väärtus: Undefined; 05 Pindala: 1,26; 06 Tootja: Undefined; 07 Mudel või toote tunnus: Undefined; 08 Tooteinfo: Undefined; 09 Kasutus- ja hooldusjuhend: Undefined
Siseviimistlus - 05 Pindala: 1,26
AC_Pset_RenovationAndPhasing - Renovation Status: New

# IfcCovering: Kips (45)
Type - ElementType: Element type Kips; PredefinedType: CEILING
Description: šahti sein; Classification: 1.4 IfcCovering (ripplagi) (_RKAS BIM + ARCHICAD Classification); 543 Lagede metall- ja plekk-katted, ripplaed (EHITUSKULUDE LIIGITAMINE EVS 885:2005); Material: Kipsplaat
Ripplagi - 01 Nimetus: Kipsplaat; 02 Materjal: Kipsplaat; 06 Niiskuskindlus: FALSE; 08 Tulekindlusklass: Undefined; 09 Viimistlus: Undefined; 10 Tootja: Undefined; 11 Mudel või toote tunnus: Undefined; 12 Tooteinfo: Undefined; 13 Kasutus- ja hooldusjuhend: Undefined
Pset_CoveringCommon - Material: Kipsplaat
Pinnakatted - sets with these values: 2
Name | In | 04 Paksus | 03 Kategooria / tüüp | Ripplagi, 05 Pindala = Pinnakatted, 05 Pindala | 07 Karkass | Renovation Status
3 x Kipsplaat | 1 KORRUS | 13 mm | Kips - | 0,21 | Connect T15 karkass valge | New
2 x Kipsplaat | 1 KORRUS | 13 mm | Kips - | 0,25 | Connect T15 karkass valge | New
4 x Kipsplaat | 1 KORRUS | 13 mm | Kips - | 0,46 | Connect T15 karkass valge | New
Kipsplaat | 1 KORRUS | 13 mm | Kips - | 1,20 | Connect T15 karkass valge | New
Kipsplaat | 1 KORRUS | 13 mm | Kips - | 1,16 | Connect T15 karkass valge | New
Kipsplaat | 1 KORRUS | 13 mm | Kips - | 0,58 | Connect T15 karkass valge | New
Kipsplaat | 1 KORRUS | 13 mm | Kips - | 2,64 | Connect T15 karkass valge | New
Kipsplaat | 1 KORRUS | 13 mm | Kips - | 0,16 | Connect T15 karkass valge | New
Kipsplaat | 1 KORRUS | 13 mm | Kips - | 0,24 | Connect T15 karkass valge | New
Kipsplaat | 1 KORRUS | 13 mm | Kips - | 0,47 | Connect T15 karkass valge | New
Kipsplaat | 1 KORRUS | 13 mm | Kips - | 0,78 | Connect T15 karkass valge | New
Kipsplaat | 1 KORRUS | 13 mm | Kips - | 1,44 | Connect T15 karkass valge | New
Kipsplaat | 1 KORRUS | 13 mm | Kips - | 0,14 | Connect T15 karkass valge | Existing
Kipsplaat | 1 KORRUS | 13 mm | Kips - | 1,15 | Connect T15 karkass valge | New
Kipsplaat | 2 KORRUS | 13 mm | Kips - | 0,27 | Connect T15 karkass valge | New
Kipsplaat | 2 KORRUS | Mudelis: 13mm Käsitsi sisestatud väärtus: Undefined | Kips Undefined | 0,72 | Undefined | New
Kipsplaat | 2 KORRUS | 13 mm | Kips - | 0,54 | Connect T15 karkass valge | New
Kipsplaat | 2 KORRUS | 13 mm | Kips - | 1,39 | Connect T15 karkass valge | New
Kipsplaat | 2 KORRUS | 13 mm | Kips - | 0,02 | Connect T15 karkass valge | New
Kipsplaat | 2 KORRUS | 13 mm | Kips - | 0,25 | Connect T15 karkass valge | Existing
Kipsplaat | 2 KORRUS | 13 mm | Kips - | 1,40 | Connect T15 karkass valge | New
Kipsplaat | 2 KORRUS | 13 mm | Kips - | 0,34 | Connect T15 karkass valge | New
Kipsplaat | 2 KORRUS | 13 mm | Kips - | 0,64 | Connect T15 karkass valge | New
Kipsplaat | 2 KORRUS | 13 mm | Kips - | 0,44 | Connect T15 karkass valge | New
Kipsplaat | 2 KORRUS | 13 mm | Kips - | 0,58 | Connect T15 karkass valge | New
Kipsplaat | 2 KORRUS | 13 mm | Kips - | 1,31 | Connect T15 karkass valge | New
Kipsplaat | 2 KORRUS | 13 mm | Kips - | 0,62 | Connect T15 karkass valge | New
6 x Kipsplaat | 2 KORRUS | 13 mm | Kips - | 1,37 | Connect T15 karkass valge | New
Kipsplaat | 2 KORRUS | 13 mm | Kips - | 0,10 | Connect T15 karkass valge | New
Kipsplaat | 2 KORRUS | 13 mm | Kips - | 0,09 | Connect T15 karkass valge | New
3 x Kipsplaat | 2 KORRUS | 13 mm | Kips - | 0,06 | Connect T15 karkass valge | New
Kipsplaat | 2 KORRUS | 13 mm | Kips - | 0,21 | Connect T15 karkass valge | New

# IfcCovering: L-1 (60)
Type - ElementType: Element type L-1; PredefinedType: CEILING
Classification: 1.4 IfcCovering (ripplagi) (_RKAS BIM + ARCHICAD Classification); 543 Lagede metall- ja plekk-katted, ripplaed (EHITUSKULUDE LIIGITAMINE EVS 885:2005); Material: Kipsplaat
Ripplagi - 04 Paksus: 20 mm; 02 Materjal: Kips; 01 Nimetus: Ripplagi. Akustine kipsplaat; 03 Kategooria / tüüp: Akustiline kipsplaat; 06 Niiskuskindlus: FALSE; 08 Tulekindlusklass: Undefined; 09 Viimistlus: valge; 10 Tootja: Undefined; 11 Mudel või toote tunnus: Undefined; 12 Tooteinfo: Undefined; 13 Kasutus- ja hooldusjuhend: Undefined
Pset_CoveringCommon - Material: Kipsplaat
Pinnakatted - sets with these values: 2
Name | In | Ripplagi, 05 Pindala = Pinnakatted, 05 Pindala | Renovation Status
Ripplagi. Akustine kipsplaat | 1 KORRUS | 10,12 | New
Ripplagi. Akustine kipsplaat | 1 KORRUS | 15,56 | Existing
Ripplagi. Akustine kipsplaat | 1 KORRUS | 27,33 | New
Ripplagi. Akustine kipsplaat | 1 KORRUS | 21,85 | New
Ripplagi. Akustine kipsplaat | 2 KORRUS | 21,72 | New
Ripplagi. Akustine kipsplaat | 2 KORRUS | 29,92 | New
Ripplagi. Akustine kipsplaat | 2 KORRUS | 9,69 | New
Ripplagi. Akustine kipsplaat | 2 KORRUS | 9,97 | New
Ripplagi. Akustine kipsplaat | 2 KORRUS | 11,21 | New
2 x Ripplagi. Akustine kipsplaat | 2 KORRUS | 11,36 | New
2 x Ripplagi. Akustine kipsplaat | 2 KORRUS | 11,37 | New
Ripplagi. Akustine kipsplaat | 2 KORRUS | 11,55 | New
Ripplagi. Akustine kipsplaat | 2 KORRUS | 21,17 | New
Ripplagi. Akustine kipsplaat | 2 KORRUS | 19,14 | New
Ripplagi. Akustine kipsplaat | 2 KORRUS | 23,85 | New
Ripplagi. Akustine kipsplaat | 2 KORRUS | 10,31 | New
Ripplagi. Akustine kipsplaat | 2 KORRUS | 9,57 | New
Ripplagi. Akustine kipsplaat | 2 KORRUS | 10,46 | New
Ripplagi. Akustine kipsplaat | 2 KORRUS | 2,18 | New
Ripplagi. Akustine kipsplaat | 2 KORRUS | 18,12 | New
Ripplagi. Akustine kipsplaat | 2 KORRUS | 16,61 | New
3 x Ripplagi. Akustine kipsplaat | 2 KORRUS | 16,63 | New
Ripplagi. Akustine kipsplaat | 2 KORRUS | 21,28 | New
Ripplagi. Akustine kipsplaat | 2 KORRUS | 24,84 | New
Ripplagi. Akustine kipsplaat | 2 KORRUS | 10,67 | New
2 x Ripplagi. Akustine kipsplaat | 2 KORRUS | 10,68 | New
Ripplagi. Akustine kipsplaat | 2 KORRUS | 32,86 | New
Ripplagi. Akustine kipsplaat | 2 KORRUS | 16,20 | New
Ripplagi. Akustine kipsplaat | 2 KORRUS | 10,42 | New
Ripplagi. Akustine kipsplaat | 2 KORRUS | 11,68 | New
Ripplagi. Akustine kipsplaat | 2 KORRUS | 9,68 | New
Ripplagi. Akustine kipsplaat | 2 KORRUS | 16,49 | New
Ripplagi. Akustine kipsplaat | 2 KORRUS | 20,46 | New
Ripplagi. Akustine kipsplaat | 2 KORRUS | 18,36 | New
Ripplagi. Akustine kipsplaat | 2 KORRUS | 34,24 | New
Ripplagi. Akustine kipsplaat | 2 KORRUS | 16,71 | New
Ripplagi. Akustine kipsplaat | 2 KORRUS | 15,84 | New
Ripplagi. Akustine kipsplaat | 2 KORRUS | 15,62 | New
Ripplagi. Akustine kipsplaat | 2 KORRUS | 12,12 | New
Ripplagi. Akustine kipsplaat | 2 KORRUS | 20,05 | New
Ripplagi. Akustine kipsplaat | 2 KORRUS | 11,04 | New
Ripplagi. Akustine kipsplaat | 2 KORRUS | 22,21 | New
Ripplagi. Akustine kipsplaat | 2 KORRUS | 11,63 | New
Ripplagi. Akustine kipsplaat | 2 KORRUS | 27,79 | New
Ripplagi. Akustine kipsplaat | 2 KORRUS | 23,73 | New
Ripplagi. Akustine kipsplaat | 2 KORRUS | 11,35 | New
2 x Ripplagi. Akustine kipsplaat | 2 KORRUS | 16,42 | New
Ripplagi. Akustine kipsplaat | 2 KORRUS | 16,43 | New
2 x Ripplagi. Akustine kipsplaat | 2 KORRUS | 12,88 | New
Ripplagi. Akustine kipsplaat | 2 KORRUS | 11,74 | New
Ripplagi. Akustine kipsplaat | 2 KORRUS | 8,68 | New
Ripplagi. Akustine kipsplaat | 2 KORRUS | 11,56 | New
Ripplagi. Akustine kipsplaat | 2 KORRUS | 11,59 | New

# IfcCovering: L-2 (21)
Type - ElementType: Element type L-2; PredefinedType: CEILING
Classification: 1.4 IfcCovering (ripplagi) (_RKAS BIM + ARCHICAD Classification); 543 Lagede metall- ja plekk-katted, ripplaed (EHITUSKULUDE LIIGITAMINE EVS 885:2005); Material: Kipsplaat
Ripplagi - 04 Paksus: 26 mm; 02 Materjal: Kips; 01 Nimetus: Kahekordne niiskuskindlast kipsplaadist ripplag; 03 Kategooria / tüüp: Niiskuskindel kipsplaat; 06 Niiskuskindlus: TRUE; 07 Karkass: Undefined; 08 Tulekindlusklass: Undefined; 09 Viimistlus: Kattevärv antibakteriaalsete ja hallitusvastaste lisanditega.; 10 Tootja: Undefined; 11 Mudel või toote tunnus: Undefined; 12 Tooteinfo: Undefined; 13 Kasutus- ja hooldusjuhend: Undefined
Pset_CoveringCommon - Material: Kipsplaat
Pinnakatted - sets with these values: 2
AC_Pset_RenovationAndPhasing - Renovation Status: New
Name | In | Ripplagi, 05 Pindala = Pinnakatted, 05 Pindala
Kahekordne niiskuskindlast kipsplaadist ripplag | 1 KORRUS | 2,05
Kahekordne niiskuskindlast kipsplaadist ripplag | 1 KORRUS | 1,54
Kahekordne niiskuskindlast kipsplaadist ripplag | 1 KORRUS | 3,43
2 x Kahekordne niiskuskindlast kipsplaadist ripplag | 1 KORRUS | 5,23
Kahekordne niiskuskindlast kipsplaadist ripplag | 1 KORRUS | 4,78
Kahekordne niiskuskindlast kipsplaadist ripplag | 1 KORRUS | 9,11
Kahekordne niiskuskindlast kipsplaadist ripplag | 1 KORRUS | 6,04
Kahekordne niiskuskindlast kipsplaadist ripplag | 1 KORRUS | 1,36
Kahekordne niiskuskindlast kipsplaadist ripplag | 1 KORRUS | 4,57
Kahekordne niiskuskindlast kipsplaadist ripplag | 1 KORRUS | 0,74
Kahekordne niiskuskindlast kipsplaadist ripplag | 2 KORRUS | 7,61
Kahekordne niiskuskindlast kipsplaadist ripplag | 2 KORRUS | 1,21
Kahekordne niiskuskindlast kipsplaadist ripplag | 2 KORRUS | 1,02
Kahekordne niiskuskindlast kipsplaadist ripplag | 2 KORRUS | 7,56
Kahekordne niiskuskindlast kipsplaadist ripplag | 2 KORRUS | 5,48
Kahekordne niiskuskindlast kipsplaadist ripplag | 2 KORRUS | 6,80
Kahekordne niiskuskindlast kipsplaadist ripplag | 2 KORRUS | 1,20
Kahekordne niiskuskindlast kipsplaadist ripplag | 2 KORRUS | 7,31
Kahekordne niiskuskindlast kipsplaadist ripplag | 2 KORRUS | 3,34
Kahekordne niiskuskindlast kipsplaadist ripplag | 2 KORRUS | 1,47

# IfcCovering: L-3 (4)
Type - ElementType: Element type L-3; PredefinedType: CEILING
Ripplagi - 06 Niiskuskindlus: FALSE; 09 Viimistlus: valge; 10 Tootja: Undefined; 11 Mudel või toote tunnus: Undefined; 12 Tooteinfo: Undefined; 13 Kasutus- ja hooldusjuhend: Undefined
AC_Pset_RenovationAndPhasing - Renovation Status: New
Name | In | Classification | Material = Pset_CoveringCommon, Material | Ripplagi, 04 Paksus | 02 Materjal | 01 Nimetus | 03 Kategooria / tüüp | Ripplagi, 05 Pindala = Pinnakatted, 05 Pindala | 08 Tulekindlusklass | Siseviimistlus, 04 Paksus | Siseviimistlus, 05 Pindala | 07 Karkass
Ripplagi. Akustine kipsplaat | 1 KORRUS | 1.4 IfcCovering (ripplagi) (_RKAS BIM + ARCHICAD Classification); 543 Lagede metall- ja plekk-katted, ripplaed (EHITUSKULUDE LIIGITAMINE EVS 885:2005) | Kipsplaat | 20 mm | Kips | Ripplagi. Akustine kipsplaat | Akustiline kipsplaat | 19,37 | Undefined | Pinnakatted - sets with these values: 2
Konstruktiivne lagi lauspahtel, värvitud | 2 KORRUS | 1.4 IfcCovering (ripplagi) (_RKAS BIM + ARCHICAD Classification); 511 Värvkatted (EHITUSKULUDE LIIGITAMINE EVS 885:2005) | Värv | Undefined | Värv | Konstruktiivne lagi lauspahtel, värvitud | L-3 Värv | 21,79 | - | Undefined | 21,79 | -
Konstruktiivne lagi lauspahtel, värvitud | 2 KORRUS | 1.4 IfcCovering (ripplagi) (_RKAS BIM + ARCHICAD Classification); 511 Värvkatted (EHITUSKULUDE LIIGITAMINE EVS 885:2005) | Värv | Undefined | Värv | Konstruktiivne lagi lauspahtel, värvitud | L-3 Värv | 21,70 | - | Undefined | 21,70 | -
Konstruktiivne lagi lauspahtel, värvitud | 2 KORRUS | 1.4 IfcCovering (ripplagi) (_RKAS BIM + ARCHICAD Classification); 511 Värvkatted (EHITUSKULUDE LIIGITAMINE EVS 885:2005) | Värv | Undefined | Värv | Konstruktiivne lagi lauspahtel, värvitud | L-3 Värv | 7,99 | - | Undefined | 7,99 | -

# IfcCovering: L-3 (26)
Type - ElementType: Element type L-3; PredefinedType: CLADDING
Classification: 1.5 IfcCovering (siseviimistlus) (_RKAS BIM + ARCHICAD Classification); 541 Värvkatted (EHITUSKULUDE LIIGITAMINE EVS 885:2005); Material: Värv
Siseviimistlus - 04 Paksus: Undefined; 06 Aluspind: Konstruktiivne lagi; 07 Tehnilised omadused: matt; 09 Tootja: Undefined; 10 Mudel või toote tunnus: Undefined; 11 Tooteinfo: Undefined; 12 Kasutus- ja hooldusjuhend: Undefined
Ripplagi - 02 Materjal: Värv
Pset_CoveringCommon - Material: Värv
Name | In | Siseviimistlus, 01 Nimetus = Ripplagi, 01 Nimetus | 02 Materjal | 03 Kategooria / tüüp | Siseviimistlus, 05 Pindala = Ripplagi, 05 Pindala = Pinnakatted, 05 Pindala | 08 Toon | Renovation Status
Konstruktiivne lagi lauspahtel, värvitud | 1 KORRUS | Konstruktiivne lagi lauspahtel, värvitud | värv | Lateksvärv | 26,23 | RAL 9003 | New
Konstruktiivne lagi lauspahtel, värvitud | 1 KORRUS | Konstruktiivne lagi lauspahtel, värvitud | värv | Lateksvärv | 21,51 | RAL 9002 | New
Konstruktiivne lagi kaetud tolmutõkkega ja värvitud | 1 KORRUS | Konstruktiivne lagi kaetud tolmutõkkega ja värvitud | Värv | Tolmutõkke ja värv | 7,59 | RAL 9003 | New
Konstruktiivne lagi lauspahtel, värvitud | 1 KORRUS | Konstruktiivne lagi lauspahtel, värvitud | värv | Lateksvärv | 15,56 | RAL 9003 | New
Konstruktiivne lagi lauspahtel, värvitud | 1 KORRUS | Konstruktiivne lagi lauspahtel, värvitud | värv | Lateksvärv | 11,76 | RAL 9003 | New
Konstruktiivne lagi kaetud tolmutõkkega ja värvitud | 1 KORRUS | Konstruktiivne lagi kaetud tolmutõkkega ja värvitud | Värv | Tolmutõkke ja värv | 50,73 | RAL 9003 | New
Konstruktiivne lagi lauspahtel, värvitud | 1 KORRUS | Konstruktiivne lagi lauspahtel, värvitud | värv | Lateksvärv | 13,72 | RAL 9003 | New
Konstruktiivne lagi lauspahtel, värvitud | 1 KORRUS | Konstruktiivne lagi lauspahtel, värvitud | värv | Lateksvärv | 34,95 | RAL 9003 | New
Konstruktiivne lagi lauspahtel, värvitud | 1 KORRUS | Konstruktiivne lagi lauspahtel, värvitud | värv | Lateksvärv | 10,59 | RAL 9003 | New
Konstruktiivne lagi lauspahtel, värvitud | 1 KORRUS | Konstruktiivne lagi lauspahtel, värvitud | värv | Lateksvärv | 21,73 | RAL 9003 | New
Konstruktiivne lagi lauspahtel, värvitud | 1 KORRUS | Konstruktiivne lagi lauspahtel, värvitud | värv | Lateksvärv | 10,60 | RAL 9003 | New
Konstruktiivne lagi lauspahtel, värvitud | 1 KORRUS | Konstruktiivne lagi lauspahtel, värvitud | värv | Lateksvärv | 9,29 | RAL 9003 | New
Konstruktiivne lagi lauspahtel, värvitud | 1 KORRUS | Konstruktiivne lagi lauspahtel, värvitud | värv | Lateksvärv | 14,52 | RAL 9003 | New
Konstruktiivne lagi lauspahtel, värvitud | 1 KORRUS | Konstruktiivne lagi lauspahtel, värvitud | värv | Lateksvärv | 81,66 | RAL 9003 | New
Konstruktiivne lagi lauspahtel, värvitud | 1 KORRUS | Konstruktiivne lagi lauspahtel, värvitud | värv | Lateksvärv | 32,63 | RAL 9003 | New
Konstruktiivne lagi lauspahtel, värvitud | 1 KORRUS | Konstruktiivne lagi lauspahtel, värvitud | värv | Lateksvärv | 10,62 | RAL 9003 | New
Konstruktiivne lagi lauspahtel, värvitud | 1 KORRUS | Konstruktiivne lagi lauspahtel, värvitud | värv | Lateksvärv | 21,70 | RAL 9003 | New
Konstruktiivne lagi lauspahtel, värvitud | 1 KORRUS | Konstruktiivne lagi lauspahtel, värvitud | värv | Lateksvärv | 21,92 | RAL 9003 | Existing
Konstruktiivne lagi lauspahtel, värvitud | 1 KORRUS | Konstruktiivne lagi lauspahtel, värvitud | värv | Lateksvärv | 15,33 | RAL 9003 | Existing
Konstruktiivne lagi lauspahtel, värvitud | 2 KORRUS | Konstruktiivne lagi lauspahtel, värvitud | värv | Lateksvärv | 16,04 | RAL 9003 | New
Konstruktiivne lagi lauspahtel, värvitud | 2 KORRUS | Konstruktiivne lagi lauspahtel, värvitud | värv | Lateksvärv | 3,29 | RAL 9003 | New
Konstruktiivne lagi lauspahtel, värvitud | 2 KORRUS | Konstruktiivne lagi lauspahtel, värvitud | värv | Lateksvärv | 3,09 | RAL 9003 | New
Konstruktiivne lagi lauspahtel, värvitud | 2 KORRUS | Konstruktiivne lagi lauspahtel, värvitud | värv | Lateksvärv | 6,08 | RAL 9003 | New
Konstruktiivne lagi lauspahtel, värvitud | 2 KORRUS | Konstruktiivne lagi lauspahtel, värvitud | värv | Lateksvärv | 54,12 | RAL 9003 | New
Konstruktiivne lagi lauspahtel, värvitud | 2 KORRUS | Konstruktiivne lagi lauspahtel, värvitud | värv | Lateksvärv | 59,05 | RAL 9003 | New
Konstruktiivne lagi lauspahtel, värvitud | 2 KORRUS | Konstruktiivne lagi lauspahtel, värvitud | värv | Lateksvärv | 30,04 | RAL 9003 | New

# IfcCovering: L-4 (22)
Type - ElementType: Element type L-4; PredefinedType: CEILING
Classification: 1.4 IfcCovering (ripplagi) (_RKAS BIM + ARCHICAD Classification); 543 Lagede metall- ja plekk-katted, ripplaed (EHITUSKULUDE LIIGITAMINE EVS 885:2005); Material: Kipsplaat
Ripplagi - 04 Paksus: 15 mm; 01 Nimetus: Ripplagi; 03 Kategooria / tüüp: Akustiline kipsplaat; 02 Materjal: Kipsplaat; 06 Niiskuskindlus: FALSE; 07 Karkass: Undefined; 08 Tulekindlusklass: Undefined; 09 Viimistlus: valge; 10 Tootja: Undefined; 11 Mudel või toote tunnus: Undefined; 12 Tooteinfo: Undefined; 13 Kasutus- ja hooldusjuhend: Undefined
Pset_CoveringCommon - Material: Kipsplaat
Pinnakatted - sets with these values: 2
AC_Pset_RenovationAndPhasing - Renovation Status: New
Name | In | Ripplagi, 05 Pindala = Pinnakatted, 05 Pindala
Ripplagi | 1 KORRUS | 60,27
Ripplagi | 1 KORRUS | 1,75
Ripplagi | 1 KORRUS | 2,22
Ripplagi | 1 KORRUS | 12,15
Ripplagi | 1 KORRUS | 12,95
Ripplagi | 1 KORRUS | 3,52
Ripplagi | 1 KORRUS | 6,83
Ripplagi | 1 KORRUS | 12,50
Ripplagi | 1 KORRUS | 17,63
Ripplagi | 1 KORRUS | 5,17
Ripplagi | 2 KORRUS | 24,09
Ripplagi | 2 KORRUS | 12,64
Ripplagi | 2 KORRUS | 4,47
Ripplagi | 2 KORRUS | 22,01
Ripplagi | 2 KORRUS | 3,76
Ripplagi | 2 KORRUS | 36,12
Ripplagi | 2 KORRUS | 11,22
Ripplagi | 2 KORRUS | 0,00
Ripplagi | 2 KORRUS | 2,92
Ripplagi | 2 KORRUS | 36,62
Ripplagi | 2 KORRUS | 10,43
Ripplagi | 2 KORRUS | 11,18

# IfcCovering: L-5 (40)
Type - ElementType: Element type L-5; PredefinedType: CLADDING
Classification: 1.5 IfcCovering (siseviimistlus) (_RKAS BIM + ARCHICAD Classification); 541 Värvkatted (EHITUSKULUDE LIIGITAMINE EVS 885:2005); Material: Värv
Siseviimistlus - 04 Paksus: Undefined; 01 Nimetus: Konstruktiivne lagi kaetud tolmutõkkega ja värvitud; 02 Materjal: Värv; 03 Kategooria / tüüp: Tolmutõkke ja värv; 06 Aluspind: Konstruktiivne lagi; 07 Tehnilised omadused: matt; 08 Toon: RAL 9003; 09 Tootja: Undefined; 10 Mudel või toote tunnus: Undefined; 11 Tooteinfo: Undefined; 12 Kasutus- ja hooldusjuhend: Undefined
Ripplagi - 01 Nimetus: Konstruktiivne lagi kaetud tolmutõkkega ja värvitud; 02 Materjal: Värv
Pset_CoveringCommon - Material: Värv
Name | In | Siseviimistlus, 05 Pindala = Ripplagi, 05 Pindala = Pinnakatted, 05 Pindala | Renovation Status
Konstruktiivne lagi kaetud tolmutõkkega ja värvitud | 1 KORRUS | 8,22 | New
Konstruktiivne lagi kaetud tolmutõkkega ja värvitud | 1 KORRUS | 10,23 | New
Konstruktiivne lagi kaetud tolmutõkkega ja värvitud | 1 KORRUS | 7,07 | New
Konstruktiivne lagi kaetud tolmutõkkega ja värvitud | 1 KORRUS | 21,15 | New
Konstruktiivne lagi kaetud tolmutõkkega ja värvitud | 1 KORRUS | 16,38 | New
Konstruktiivne lagi kaetud tolmutõkkega ja värvitud | 1 KORRUS | 20,91 | New
Konstruktiivne lagi kaetud tolmutõkkega ja värvitud | 1 KORRUS | 5,56 | New
Konstruktiivne lagi kaetud tolmutõkkega ja värvitud | 1 KORRUS | 33,69 | New
Konstruktiivne lagi kaetud tolmutõkkega ja värvitud | 1 KORRUS | 15,41 | New
Konstruktiivne lagi kaetud tolmutõkkega ja värvitud | 1 KORRUS | 17,14 | New
Konstruktiivne lagi kaetud tolmutõkkega ja värvitud | 1 KORRUS | 10,43 | New
Konstruktiivne lagi kaetud tolmutõkkega ja värvitud | 1 KORRUS | 9,96 | New
Konstruktiivne lagi kaetud tolmutõkkega ja värvitud | 1 KORRUS | 42,17 | New
Konstruktiivne lagi kaetud tolmutõkkega ja värvitud | 1 KORRUS | 21,87 | New
Konstruktiivne lagi kaetud tolmutõkkega ja värvitud | 1 KORRUS | 20,01 | New
Konstruktiivne lagi kaetud tolmutõkkega ja värvitud | 1 KORRUS | 9,84 | New
2 x Konstruktiivne lagi kaetud tolmutõkkega ja värvitud | 1 KORRUS | 16,43 | New
Konstruktiivne lagi kaetud tolmutõkkega ja värvitud | 1 KORRUS | 16,46 | New
Konstruktiivne lagi kaetud tolmutõkkega ja värvitud | 1 KORRUS | 16,45 | New
Konstruktiivne lagi kaetud tolmutõkkega ja värvitud | 1 KORRUS | 26,04 | New
Konstruktiivne lagi kaetud tolmutõkkega ja värvitud | 1 KORRUS | 7,00 | New
Konstruktiivne lagi kaetud tolmutõkkega ja värvitud | 1 KORRUS | 16,14 | New
Konstruktiivne lagi kaetud tolmutõkkega ja värvitud | 1 KORRUS | 20,70 | New
Konstruktiivne lagi kaetud tolmutõkkega ja värvitud | 1 KORRUS | 13,31 | New
Konstruktiivne lagi kaetud tolmutõkkega ja värvitud | 1 KORRUS | 17,32 | New
Konstruktiivne lagi kaetud tolmutõkkega ja värvitud | 1 KORRUS | 4,97 | New
Konstruktiivne lagi kaetud tolmutõkkega ja värvitud | 1 KORRUS | 3,78 | New
Konstruktiivne lagi kaetud tolmutõkkega ja värvitud | 1 KORRUS | 9,44 | New
Konstruktiivne lagi kaetud tolmutõkkega ja värvitud | 1 KORRUS | 10,40 | New
Konstruktiivne lagi kaetud tolmutõkkega ja värvitud | 1 KORRUS | 10,54 | New
Konstruktiivne lagi kaetud tolmutõkkega ja värvitud | 1 KORRUS | 2,95 | New
Konstruktiivne lagi kaetud tolmutõkkega ja värvitud | 1 KORRUS | 5,83 | Existing
Konstruktiivne lagi kaetud tolmutõkkega ja värvitud | 1 KORRUS | 5,38 | Existing
Konstruktiivne lagi kaetud tolmutõkkega ja värvitud | 1 KORRUS | 10,38 | New
Konstruktiivne lagi kaetud tolmutõkkega ja värvitud | 2 KORRUS | 35,01 | New
Konstruktiivne lagi kaetud tolmutõkkega ja värvitud | 2 KORRUS | 68,54 | New
Konstruktiivne lagi kaetud tolmutõkkega ja värvitud | 2 KORRUS | 9,15 | New
Konstruktiivne lagi kaetud tolmutõkkega ja värvitud | 2 KORRUS | 16,22 | New
Konstruktiivne lagi kaetud tolmutõkkega ja värvitud | 2 KORRUS | 7,12 | New

# IfcCovering: L-6 (21)
Type - ElementType: Element type L-6; PredefinedType: CEILING
Classification: 1.4 IfcCovering (ripplagi) (_RKAS BIM + ARCHICAD Classification); 543 Lagede metall- ja plekk-katted, ripplaed (EHITUSKULUDE LIIGITAMINE EVS 885:2005); Material: Kipsplaat
Ripplagi - 04 Paksus: 26 mm; 01 Nimetus: Kahekordne kipsplaadist ripplagi; 02 Materjal: Kipsplaat; 03 Kategooria / tüüp: L-6 Kahekordne kipsplaat; 06 Niiskuskindlus: FALSE; 07 Karkass: Undefined; 08 Tulekindlusklass: Undefined; 09 Viimistlus: valge; 10 Tootja: Undefined; 11 Mudel või toote tunnus: Undefined; 12 Tooteinfo: Undefined; 13 Kasutus- ja hooldusjuhend: Undefined
Pset_CoveringCommon - Material: Kipsplaat
Pinnakatted - sets with these values: 2
Name | In | Ripplagi, 05 Pindala = Pinnakatted, 05 Pindala | Renovation Status
Kahekordne kipsplaadist ripplagi | 1 KORRUS | 0,51 | Existing
Kahekordne kipsplaadist ripplagi | 1 KORRUS | 3,22 | New
Kahekordne kipsplaadist ripplagi | 1 KORRUS | 0,72 | New
Kahekordne kipsplaadist ripplagi | 1 KORRUS | 3,54 | New
Kahekordne kipsplaadist ripplagi | 1 KORRUS | 15,89 | New
Kahekordne kipsplaadist ripplagi | 1 KORRUS | 10,05 | New
Kahekordne kipsplaadist ripplagi | 1 KORRUS | 0,83 | New
Kahekordne kipsplaadist ripplagi | 1 KORRUS | 1,46 | New
Kahekordne kipsplaadist ripplagi | 1 KORRUS | 4,33 | New
Kahekordne kipsplaadist ripplagi | 1 KORRUS | 0,73 | New
Kahekordne kipsplaadist ripplagi | 2 KORRUS | 2,42 | New
Kahekordne kipsplaadist ripplagi | 2 KORRUS | 25,21 | New
Kahekordne kipsplaadist ripplagi | 2 KORRUS | 5,90 | New
Kahekordne kipsplaadist ripplagi | 2 KORRUS | 1,37 | New
Kahekordne kipsplaadist ripplagi | 2 KORRUS | 1,96 | Existing
Kahekordne kipsplaadist ripplagi | 2 KORRUS | 4,10 | Existing
Kahekordne kipsplaadist ripplagi | 2 KORRUS | 2,04 | Existing
Kahekordne kipsplaadist ripplagi | 2 KORRUS | 2,00 | Existing
Kahekordne kipsplaadist ripplagi | 2 KORRUS | 2,86 | Existing
Kahekordne kipsplaadist ripplagi | 2 KORRUS | 24,68 | New
Kahekordne kipsplaadist ripplagi | 2 KORRUS | 1,41 | New

# IfcCovering: L-7, Kahekordne niiskuskindlast kipsplaadist ripplag
In: 1 KORRUS
Type - ElementType: Element type L-7; PredefinedType: CEILING
Classification: 1.4 IfcCovering (ripplagi) (_RKAS BIM + ARCHICAD Classification); 543 Lagede metall- ja plekk-katted, ripplaed (EHITUSKULUDE LIIGITAMINE EVS 885:2005); Material: Puitplaat
Ripplagi - 01 Nimetus: Leiliruumi lisa laekiht; 02 Materjal: Saunalaudis; 03 Kategooria / tüüp: L-7; 04 Paksus: 87 mm; 09 Viimistlus: Saunalaudis; 05 Pindala: 4,79; 06 Niiskuskindlus: TRUE; 07 Karkass: Puitkarkass 50x50mm; 08 Tulekindlusklass: Undefined; 10 Tootja: Undefined; 11 Mudel või toote tunnus: Undefined; 12 Tooteinfo: Undefined; 13 Kasutus- ja hooldusjuhend: Undefined
Pset_CoveringCommon - Material: Puitplaat
Pinnakatted - 05 Pindala: 4,79; sets with these values: 2
AC_Pset_RenovationAndPhasing - Renovation Status: New

# IfcCovering: P-1 (23)
Type - ElementType: Element type P-1
Material: Betoon - Ol.Olev konstruktsioon
Ripplagi - 01 Nimetus: Betoon - Ol.Olev konstruktsioon; 02 Materjal: Betoon - Ol.Olev konstruktsioon
Pinnakatted - 01 Nimetus: Põrandakate; 09 Kasutus- ja hooldusjuhend: Undefined
Pset_CoveringCommon - Material: Betoon - Ol.Olev konstruktsioon
AC_Pset_RenovationAndPhasing - Renovation Status: New
Name | In | Classification | Ripplagi, 05 Pindala = Pinnakatted, 05 Pindala = Siseviimistlus, 05 Pindala | 04 Paksus | 08 Tooteinfo | 02 Materjal | 03 Kategooria / tüüp | 06 Tootja | 07 Mudel või toote tunnus
Põrandakate | 1 KORRUS | A Preliminaries/General conditions (CAWS); 1.6 IfcCovering (pinnakatted) (_RKAS BIM + ARCHICAD Classification); 56 Põrandad ja põrandakatted (EHITUSKULUDE LIIGITAMINE EVS 885:2005) | 59,10 | 2,5 mm | FLOORIN | LVT materjal | P-1 LVT e imitatsioonplaadid | Undefined | Moduleo 55 Tiles *Steel Rock
Põrandakate | 1 KORRUS | A Preliminaries/General conditions (CAWS); 1.6 IfcCovering (pinnakatted) (_RKAS BIM + ARCHICAD Classification); 56 Põrandad ja põrandakatted (EHITUSKULUDE LIIGITAMINE EVS 885:2005) | 74,13 | 2,5 mm | FLOORIN | LVT materjal | P-1 LVT e imitatsioonplaadid | Undefined | Moduleo 55 Tiles *Steel Rock
Põrandakate | 1 KORRUS | A Preliminaries/General conditions (CAWS); 1.6 IfcCovering (pinnakatted) (_RKAS BIM + ARCHICAD Classification); 56 Põrandad ja põrandakatted (EHITUSKULUDE LIIGITAMINE EVS 885:2005) | 17,64 | 2,5 mm | FLOORIN | LVT materjal | P-1 LVT e imitatsioonplaadid | Undefined | Moduleo 55 Tiles *Steel Rock
Põrandakate | 1 KORRUS | A Preliminaries/General conditions (CAWS); 1.6 IfcCovering (pinnakatted) (_RKAS BIM + ARCHICAD Classification); 56 Põrandad ja põrandakatted (EHITUSKULUDE LIIGITAMINE EVS 885:2005) | 10,09 | 2,5 mm | FLOORIN | LVT materjal | P-1 LVT e imitatsioonplaadid | Undefined | Moduleo 55 Tiles *Steel Rock
Betoon - Ol.Olev konstruktsioon | 1 KORRUS | A Preliminaries/General conditions (CAWS); 1.6 IfcCovering (pinnakatted) (_RKAS BIM + ARCHICAD Classification); 56 Põrandad ja põrandakatted (EHITUSKULUDE LIIGITAMINE EVS 885:2005) | 17,73 | 2,0 mm | Undefined | ESD katte | P-1 Antistaatiline ESD katte | FLOORIN | Polyflor SD Silver Grey
Põrandakate | 1 KORRUS | A Preliminaries/General conditions (CAWS); 1.6 IfcCovering (pinnakatted) (_RKAS BIM + ARCHICAD Classification); 56 Põrandad ja põrandakatted (EHITUSKULUDE LIIGITAMINE EVS 885:2005) | 38,91 | 2,5 mm | FLOORIN | LVT materjal | P-1 LVT e imitatsioonplaadid | Undefined | Moduleo 55 Tiles *Steel Rock
Põrandakate | 2 KORRUS | 1.6 IfcCovering (pinnakatted) (_RKAS BIM + ARCHICAD Classification); 56 Põrandad ja põrandakatted (EHITUSKULUDE LIIGITAMINE EVS 885:2005) | 8,10 | 2,5 mm | FLOORIN | LVT materjal | P-1 LVT e imitatsioonplaadid | Undefined | Moduleo 55 Tiles *Steel Rock
Põrandakate | 2 KORRUS | 1.6 IfcCovering (pinnakatted) (_RKAS BIM + ARCHICAD Classification); 56 Põrandad ja põrandakatted (EHITUSKULUDE LIIGITAMINE EVS 885:2005) | 36,21 | 2,5 mm | FLOORIN | LVT materjal | P-1 LVT e imitatsioonplaadid | Undefined | Moduleo 55 Tiles *Steel Rock
Põrandakate | 2 KORRUS | 1.6 IfcCovering (pinnakatted) (_RKAS BIM + ARCHICAD Classification); 56 Põrandad ja põrandakatted (EHITUSKULUDE LIIGITAMINE EVS 885:2005) | 11,18 | 2,5 mm | FLOORIN | LVT materjal | P-1 LVT e imitatsioonplaadid | Undefined | Moduleo 55 Tiles *Steel Rock
Põrandakate | 2 KORRUS | 1.6 IfcCovering (pinnakatted) (_RKAS BIM + ARCHICAD Classification); 56 Põrandad ja põrandakatted (EHITUSKULUDE LIIGITAMINE EVS 885:2005) | 22,69 | 2,5 mm | FLOORIN | LVT materjal | P-1 LVT e imitatsioonplaadid | Undefined | Moduleo 55 Tiles *Steel Rock
Põrandakate | 2 KORRUS | 1.6 IfcCovering (pinnakatted) (_RKAS BIM + ARCHICAD Classification); 56 Põrandad ja põrandakatted (EHITUSKULUDE LIIGITAMINE EVS 885:2005) | 18,92 | 2,5 mm | FLOORIN | LVT materjal | P-1 LVT e imitatsioonplaadid | Undefined | Moduleo 55 Tiles *Steel Rock
Põrandakate | 2 KORRUS | 1.6 IfcCovering (pinnakatted) (_RKAS BIM + ARCHICAD Classification); 56 Põrandad ja põrandakatted (EHITUSKULUDE LIIGITAMINE EVS 885:2005) | 49,88 | 2,5 mm | FLOORIN | LVT materjal | P-1 LVT e imitatsioonplaadid | Undefined | Moduleo 55 Tiles *Steel Rock
Põrandakate | 2 KORRUS | 1.6 IfcCovering (pinnakatted) (_RKAS BIM + ARCHICAD Classification); 56 Põrandad ja põrandakatted (EHITUSKULUDE LIIGITAMINE EVS 885:2005) | 81,95 | 2,5 mm | FLOORIN | LVT materjal | P-1 LVT e imitatsioonplaadid | Undefined | Moduleo 55 Tiles *Steel Rock
Põrandakate | 2 KORRUS | 1.6 IfcCovering (pinnakatted) (_RKAS BIM + ARCHICAD Classification); 56 Põrandad ja põrandakatted (EHITUSKULUDE LIIGITAMINE EVS 885:2005) | 101,11 | 2,5 mm | FLOORIN | LVT materjal | P-1 LVT e imitatsioonplaadid | Undefined | Moduleo 55 Tiles *Steel Rock
Põrandakate | 2 KORRUS | 1.6 IfcCovering (pinnakatted) (_RKAS BIM + ARCHICAD Classification); 56 Põrandad ja põrandakatted (EHITUSKULUDE LIIGITAMINE EVS 885:2005) | 9,14 | 2,5 mm | FLOORIN | LVT materjal | P-1 LVT e imitatsioonplaadid | Undefined | Moduleo 55 Tiles *Steel Rock
Põrandakate | 2 KORRUS | 1.6 IfcCovering (pinnakatted) (_RKAS BIM + ARCHICAD Classification); 56 Põrandad ja põrandakatted (EHITUSKULUDE LIIGITAMINE EVS 885:2005) | 3,10 | 2,5 mm | FLOORIN | LVT materjal | P-1 LVT e imitatsioonplaadid | Undefined | Moduleo 55 Tiles *Steel Rock
Põrandakate | 2 KORRUS | 1.6 IfcCovering (pinnakatted) (_RKAS BIM + ARCHICAD Classification); 56 Põrandad ja põrandakatted (EHITUSKULUDE LIIGITAMINE EVS 885:2005) | 17,61 | 2,5 mm | FLOORIN | LVT materjal | P-1 LVT e imitatsioonplaadid | Undefined | Moduleo 55 Tiles *Steel Rock
Põrandakate | 2 KORRUS | 1.6 IfcCovering (pinnakatted) (_RKAS BIM + ARCHICAD Classification); 56 Põrandad ja põrandakatted (EHITUSKULUDE LIIGITAMINE EVS 885:2005) | 34,51 | 2,5 mm | FLOORIN | LVT materjal | P-1 LVT e imitatsioonplaadid | Undefined | Moduleo 55 Tiles *Steel Rock
Põrandakate | 2 KORRUS | 1.6 IfcCovering (pinnakatted) (_RKAS BIM + ARCHICAD Classification); 56 Põrandad ja põrandakatted (EHITUSKULUDE LIIGITAMINE EVS 885:2005) | 53,23 | 2,5 mm | FLOORIN | LVT materjal | P-1 LVT e imitatsioonplaadid | Undefined | Moduleo 55 Tiles *Steel Rock
Põrandakate | 2 KORRUS | 1.6 IfcCovering (pinnakatted) (_RKAS BIM + ARCHICAD Classification); 56 Põrandad ja põrandakatted (EHITUSKULUDE LIIGITAMINE EVS 885:2005) | 17,05 | 2,5 mm | FLOORIN | LVT materjal | P-1 LVT e imitatsioonplaadid | Undefined | Moduleo 55 Tiles *Steel Rock
Põrandakate | 2 KORRUS | 1.6 IfcCovering (pinnakatted) (_RKAS BIM + ARCHICAD Classification); 56 Põrandad ja põrandakatted (EHITUSKULUDE LIIGITAMINE EVS 885:2005) | 50,37 | 2,5 mm | FLOORIN | LVT materjal | P-1 LVT e imitatsioonplaadid | Undefined | Moduleo 55 Tiles *Steel Rock
Põrandakate | 2 KORRUS | 1.6 IfcCovering (pinnakatted) (_RKAS BIM + ARCHICAD Classification); 56 Põrandad ja põrandakatted (EHITUSKULUDE LIIGITAMINE EVS 885:2005) | 48,33 | 2,5 mm | FLOORIN | LVT materjal | P-1 LVT e imitatsioonplaadid | Undefined | Moduleo 55 Tiles *Steel Rock
Põrandakate | 2 KORRUS | 1.6 IfcCovering (pinnakatted) (_RKAS BIM + ARCHICAD Classification); 56 Põrandad ja põrandakatted (EHITUSKULUDE LIIGITAMINE EVS 885:2005) | 0,00 | 2,5 mm | FLOORIN | LVT materjal | P-1 LVT e imitatsioonplaadid | Undefined | Moduleo 55 Tiles *Steel Rock

# IfcCovering: P-2 (69)
Type - ElementType: Element type P-2
Pinnakatted - 04 Paksus: 2,5 mm; 01 Nimetus: Põrandakate; 02 Materjal: LVT materjal; 03 Kategooria / tüüp: P-2 LVT e imitatsioonplaadid; 06 Tootja: FLOORIN; 07 Mudel või toote tunnus: Bevel Line Wood blond field ash; 08 Tooteinfo: Undefined; 09 Kasutus- ja hooldusjuhend: Undefined
Name | In | Classification | Material = 01 Nimetus = 02 Materjal = Pset_CoveringCommon, Material | Ripplagi, 05 Pindala = Pinnakatted, 05 Pindala = Siseviimistlus, 05 Pindala | Renovation Status
Betoon - Ol.Olev konstruktsioon | 1 KORRUS | A Preliminaries/General conditions (CAWS); 1.6 IfcCovering (pinnakatted) (_RKAS BIM + ARCHICAD Classification); 56 Põrandad ja põrandakatted (EHITUSKULUDE LIIGITAMINE EVS 885:2005) | Betoon - Ol.Olev konstruktsioon | 10,05 | New
Betoon - Ol.Olev konstruktsioon | 1 KORRUS | A Preliminaries/General conditions (CAWS); 1.6 IfcCovering (pinnakatted) (_RKAS BIM + ARCHICAD Classification); 56 Põrandad ja põrandakatted (EHITUSKULUDE LIIGITAMINE EVS 885:2005) | Betoon - Ol.Olev konstruktsioon | 43,52 | New
Betoon - Ol.Olev konstruktsioon | 1 KORRUS | A Preliminaries/General conditions (CAWS); 1.6 IfcCovering (pinnakatted) (_RKAS BIM + ARCHICAD Classification); 56 Põrandad ja põrandakatted (EHITUSKULUDE LIIGITAMINE EVS 885:2005) | Betoon - Ol.Olev konstruktsioon | 31,75 | New
Betoon - Ol.Olev konstruktsioon | 1 KORRUS | A Preliminaries/General conditions (CAWS); 1.6 IfcCovering (pinnakatted) (_RKAS BIM + ARCHICAD Classification); 56 Põrandad ja põrandakatted (EHITUSKULUDE LIIGITAMINE EVS 885:2005) | Betoon - Ol.Olev konstruktsioon | 10,62 | New
Betoon - Ol.Olev konstruktsioon | 1 KORRUS | A Preliminaries/General conditions (CAWS); 1.6 IfcCovering (pinnakatted) (_RKAS BIM + ARCHICAD Classification); 56 Põrandad ja põrandakatted (EHITUSKULUDE LIIGITAMINE EVS 885:2005) | Betoon - Ol.Olev konstruktsioon | 21,75 | New
Betoon - Ol.Olev konstruktsioon | 1 KORRUS | A Preliminaries/General conditions (CAWS); 1.6 IfcCovering (pinnakatted) (_RKAS BIM + ARCHICAD Classification); 56 Põrandad ja põrandakatted (EHITUSKULUDE LIIGITAMINE EVS 885:2005) | Betoon - Ol.Olev konstruktsioon | 32,72 | New
Betoon - Ol.Olev konstruktsioon | 1 KORRUS | A Preliminaries/General conditions (CAWS); 1.6 IfcCovering (pinnakatted) (_RKAS BIM + ARCHICAD Classification); 56 Põrandad ja põrandakatted (EHITUSKULUDE LIIGITAMINE EVS 885:2005) | Betoon - Ol.Olev konstruktsioon | 21,89 | New
Betoon - Ol.Olev konstruktsioon | 1 KORRUS | A Preliminaries/General conditions (CAWS); 1.6 IfcCovering (pinnakatted) (_RKAS BIM + ARCHICAD Classification); 56 Põrandad ja põrandakatted (EHITUSKULUDE LIIGITAMINE EVS 885:2005) | Betoon - Ol.Olev konstruktsioon | 10,11 | New
Betoon - Ol.Olev konstruktsioon | 1 KORRUS | A Preliminaries/General conditions (CAWS); 1.6 IfcCovering (pinnakatted) (_RKAS BIM + ARCHICAD Classification); 56 Põrandad ja põrandakatted (EHITUSKULUDE LIIGITAMINE EVS 885:2005) | Betoon - Ol.Olev konstruktsioon | 14,52 | New
Betoon - Ol.Olev konstruktsioon | 1 KORRUS | A Preliminaries/General conditions (CAWS); 1.6 IfcCovering (pinnakatted) (_RKAS BIM + ARCHICAD Classification); 56 Põrandad ja põrandakatted (EHITUSKULUDE LIIGITAMINE EVS 885:2005) | Betoon - Ol.Olev konstruktsioon | 10,60 | New
Betoon - Ol.Olev konstruktsioon | 1 KORRUS | A Preliminaries/General conditions (CAWS); 1.6 IfcCovering (pinnakatted) (_RKAS BIM + ARCHICAD Classification); 56 Põrandad ja põrandakatted (EHITUSKULUDE LIIGITAMINE EVS 885:2005) | Betoon - Ol.Olev konstruktsioon | 21,73 | New
Betoon - Ol.Olev konstruktsioon | 1 KORRUS | A Preliminaries/General conditions (CAWS); 1.6 IfcCovering (pinnakatted) (_RKAS BIM + ARCHICAD Classification); 56 Põrandad ja põrandakatted (EHITUSKULUDE LIIGITAMINE EVS 885:2005) | Betoon - Ol.Olev konstruktsioon | 10,61 | New
Betoon - Ol.Olev konstruktsioon | 1 KORRUS | A Preliminaries/General conditions (CAWS); 1.6 IfcCovering (pinnakatted) (_RKAS BIM + ARCHICAD Classification); 56 Põrandad ja põrandakatted (EHITUSKULUDE LIIGITAMINE EVS 885:2005) | Betoon - Ol.Olev konstruktsioon | 35,04 | New
Puit - Konstruktsioon (1) | 1 KORRUS | 1.6 IfcCovering (pinnakatted) (_RKAS BIM + ARCHICAD Classification); 56 Põrandad ja põrandakatted (EHITUSKULUDE LIIGITAMINE EVS 885:2005) | Puit - Konstruktsioon (1) | 1,04 | Existing
Betoon - Ol.Olev konstruktsioon | 2 KORRUS | 1.6 IfcCovering (pinnakatted) (_RKAS BIM + ARCHICAD Classification); 56 Põrandad ja põrandakatted (EHITUSKULUDE LIIGITAMINE EVS 885:2005) | Betoon - Ol.Olev konstruktsioon | 18,12 | New
Betoon - Ol.Olev konstruktsioon | 2 KORRUS | 1.6 IfcCovering (pinnakatted) (_RKAS BIM + ARCHICAD Classification); 56 Põrandad ja põrandakatted (EHITUSKULUDE LIIGITAMINE EVS 885:2005) | Betoon - Ol.Olev konstruktsioon | 2,19 | New
Betoon - Ol.Olev konstruktsioon | 2 KORRUS | 1.6 IfcCovering (pinnakatted) (_RKAS BIM + ARCHICAD Classification); 56 Põrandad ja põrandakatted (EHITUSKULUDE LIIGITAMINE EVS 885:2005) | Betoon - Ol.Olev konstruktsioon | 13,29 | New
Betoon - Ol.Olev konstruktsioon | 2 KORRUS | 1.6 IfcCovering (pinnakatted) (_RKAS BIM + ARCHICAD Classification); 56 Põrandad ja põrandakatted (EHITUSKULUDE LIIGITAMINE EVS 885:2005) | Betoon - Ol.Olev konstruktsioon | 28,10 | New
2 x Betoon - Ol.Olev konstruktsioon | 2 KORRUS | 1.6 IfcCovering (pinnakatted) (_RKAS BIM + ARCHICAD Classification); 56 Põrandad ja põrandakatted (EHITUSKULUDE LIIGITAMINE EVS 885:2005) | Betoon - Ol.Olev konstruktsioon | 13,70 | New
Betoon - Ol.Olev konstruktsioon | 2 KORRUS | 1.6 IfcCovering (pinnakatted) (_RKAS BIM + ARCHICAD Classification); 56 Põrandad ja põrandakatted (EHITUSKULUDE LIIGITAMINE EVS 885:2005) | Betoon - Ol.Olev konstruktsioon | 10,69 | New
2 x Betoon - Ol.Olev konstruktsioon | 2 KORRUS | 1.6 IfcCovering (pinnakatted) (_RKAS BIM + ARCHICAD Classification); 56 Põrandad ja põrandakatted (EHITUSKULUDE LIIGITAMINE EVS 885:2005) | Betoon - Ol.Olev konstruktsioon | 16,53 | New
Betoon - Ol.Olev konstruktsioon | 2 KORRUS | 1.6 IfcCovering (pinnakatted) (_RKAS BIM + ARCHICAD Classification); 56 Põrandad ja põrandakatted (EHITUSKULUDE LIIGITAMINE EVS 885:2005) | Betoon - Ol.Olev konstruktsioon | 12,98 | New
Betoon - Ol.Olev konstruktsioon | 2 KORRUS | 1.6 IfcCovering (pinnakatted) (_RKAS BIM + ARCHICAD Classification); 56 Põrandad ja põrandakatted (EHITUSKULUDE LIIGITAMINE EVS 885:2005) | Betoon - Ol.Olev konstruktsioon | 11,74 | New
Betoon - Ol.Olev konstruktsioon | 2 KORRUS | 1.6 IfcCovering (pinnakatted) (_RKAS BIM + ARCHICAD Classification); 56 Põrandad ja põrandakatted (EHITUSKULUDE LIIGITAMINE EVS 885:2005) | Betoon - Ol.Olev konstruktsioon | 12,99 | New
Betoon - Ol.Olev konstruktsioon | 2 KORRUS | 1.6 IfcCovering (pinnakatted) (_RKAS BIM + ARCHICAD Classification); 56 Põrandad ja põrandakatted (EHITUSKULUDE LIIGITAMINE EVS 885:2005) | Betoon - Ol.Olev konstruktsioon | 16,54 | New
Betoon - Ol.Olev konstruktsioon | 2 KORRUS | 1.6 IfcCovering (pinnakatted) (_RKAS BIM + ARCHICAD Classification); 56 Põrandad ja põrandakatted (EHITUSKULUDE LIIGITAMINE EVS 885:2005) | Betoon - Ol.Olev konstruktsioon | 33,91 | New
Betoon - Ol.Olev konstruktsioon | 2 KORRUS | 1.6 IfcCovering (pinnakatted) (_RKAS BIM + ARCHICAD Classification); 56 Põrandad ja põrandakatted (EHITUSKULUDE LIIGITAMINE EVS 885:2005) | Betoon - Ol.Olev konstruktsioon | 15,63 | New
Betoon - Ol.Olev konstruktsioon | 2 KORRUS | 1.6 IfcCovering (pinnakatted) (_RKAS BIM + ARCHICAD Classification); 56 Põrandad ja põrandakatted (EHITUSKULUDE LIIGITAMINE EVS 885:2005) | Betoon - Ol.Olev konstruktsioon | 15,86 | New
Betoon - Ol.Olev konstruktsioon | 2 KORRUS | 1.6 IfcCovering (pinnakatted) (_RKAS BIM + ARCHICAD Classification); 56 Põrandad ja põrandakatted (EHITUSKULUDE LIIGITAMINE EVS 885:2005) | Betoon - Ol.Olev konstruktsioon | 16,81 | New
Betoon - Ol.Olev konstruktsioon | 2 KORRUS | 1.6 IfcCovering (pinnakatted) (_RKAS BIM + ARCHICAD Classification); 56 Põrandad ja põrandakatted (EHITUSKULUDE LIIGITAMINE EVS 885:2005) | Betoon - Ol.Olev konstruktsioon | 18,58 | New
Betoon - Ol.Olev konstruktsioon | 2 KORRUS | 1.6 IfcCovering (pinnakatted) (_RKAS BIM + ARCHICAD Classification); 56 Põrandad ja põrandakatted (EHITUSKULUDE LIIGITAMINE EVS 885:2005) | Betoon - Ol.Olev konstruktsioon | 34,88 | New
Betoon - Ol.Olev konstruktsioon | 2 KORRUS | 1.6 IfcCovering (pinnakatted) (_RKAS BIM + ARCHICAD Classification); 56 Põrandad ja põrandakatted (EHITUSKULUDE LIIGITAMINE EVS 885:2005) | Betoon - Ol.Olev konstruktsioon | 11,15 | New
Betoon - Ol.Olev konstruktsioon | 2 KORRUS | 1.6 IfcCovering (pinnakatted) (_RKAS BIM + ARCHICAD Classification); 56 Põrandad ja põrandakatted (EHITUSKULUDE LIIGITAMINE EVS 885:2005) | Betoon - Ol.Olev konstruktsioon | 20,33 | New
Betoon - Ol.Olev konstruktsioon | 2 KORRUS | 1.6 IfcCovering (pinnakatted) (_RKAS BIM + ARCHICAD Classification); 56 Põrandad ja põrandakatted (EHITUSKULUDE LIIGITAMINE EVS 885:2005) | Betoon - Ol.Olev konstruktsioon | 12,35 | New
Betoon - Ol.Olev konstruktsioon | 2 KORRUS | 1.6 IfcCovering (pinnakatted) (_RKAS BIM + ARCHICAD Classification); 56 Põrandad ja põrandakatted (EHITUSKULUDE LIIGITAMINE EVS 885:2005) | Betoon - Ol.Olev konstruktsioon | 20,63 | New
Betoon - Ol.Olev konstruktsioon | 2 KORRUS | 1.6 IfcCovering (pinnakatted) (_RKAS BIM + ARCHICAD Classification); 56 Põrandad ja põrandakatted (EHITUSKULUDE LIIGITAMINE EVS 885:2005) | Betoon - Ol.Olev konstruktsioon | 16,60 | New
Betoon - Ol.Olev konstruktsioon | 2 KORRUS | 1.6 IfcCovering (pinnakatted) (_RKAS BIM + ARCHICAD Classification); 56 Põrandad ja põrandakatted (EHITUSKULUDE LIIGITAMINE EVS 885:2005) | Betoon - Ol.Olev konstruktsioon | 9,68 | New
Betoon - Ol.Olev konstruktsioon | 2 KORRUS | 1.6 IfcCovering (pinnakatted) (_RKAS BIM + ARCHICAD Classification); 56 Põrandad ja põrandakatted (EHITUSKULUDE LIIGITAMINE EVS 885:2005) | Betoon - Ol.Olev konstruktsioon | 11,90 | New
Betoon - Ol.Olev konstruktsioon | 2 KORRUS | 1.6 IfcCovering (pinnakatted) (_RKAS BIM + ARCHICAD Classification); 56 Põrandad ja põrandakatted (EHITUSKULUDE LIIGITAMINE EVS 885:2005) | Betoon - Ol.Olev konstruktsioon | 10,52 | New
Betoon - Ol.Olev konstruktsioon | 2 KORRUS | 1.6 IfcCovering (pinnakatted) (_RKAS BIM + ARCHICAD Classification); 56 Põrandad ja põrandakatted (EHITUSKULUDE LIIGITAMINE EVS 885:2005) | Betoon - Ol.Olev konstruktsioon | 18,78 | New
Betoon - Ol.Olev konstruktsioon | 2 KORRUS | 1.6 IfcCovering (pinnakatted) (_RKAS BIM + ARCHICAD Classification); 56 Põrandad ja põrandakatted (EHITUSKULUDE LIIGITAMINE EVS 885:2005) | Betoon - Ol.Olev konstruktsioon | 35,05 | New
2 x Betoon - Ol.Olev konstruktsioon | 2 KORRUS | 1.6 IfcCovering (pinnakatted) (_RKAS BIM + ARCHICAD Classification); 56 Põrandad ja põrandakatted (EHITUSKULUDE LIIGITAMINE EVS 885:2005) | Betoon - Ol.Olev konstruktsioon | 10,79 | New
Betoon - Ol.Olev konstruktsioon | 2 KORRUS | 1.6 IfcCovering (pinnakatted) (_RKAS BIM + ARCHICAD Classification); 56 Põrandad ja põrandakatted (EHITUSKULUDE LIIGITAMINE EVS 885:2005) | Betoon - Ol.Olev konstruktsioon | 10,29 | New
Betoon - Ol.Olev konstruktsioon | 2 KORRUS | 1.6 IfcCovering (pinnakatted) (_RKAS BIM + ARCHICAD Classification); 56 Põrandad ja põrandakatted (EHITUSKULUDE LIIGITAMINE EVS 885:2005) | Betoon - Ol.Olev konstruktsioon | 24,18 | New
Betoon - Ol.Olev konstruktsioon | 2 KORRUS | 1.6 IfcCovering (pinnakatted) (_RKAS BIM + ARCHICAD Classification); 56 Põrandad ja põrandakatted (EHITUSKULUDE LIIGITAMINE EVS 885:2005) | Betoon - Ol.Olev konstruktsioon | 19,44 | New
Betoon - Ol.Olev konstruktsioon | 2 KORRUS | 1.6 IfcCovering (pinnakatted) (_RKAS BIM + ARCHICAD Classification); 56 Põrandad ja põrandakatted (EHITUSKULUDE LIIGITAMINE EVS 885:2005) | Betoon - Ol.Olev konstruktsioon | 21,45 | New
2 x Betoon - Ol.Olev konstruktsioon | 2 KORRUS | 1.6 IfcCovering (pinnakatted) (_RKAS BIM + ARCHICAD Classification); 56 Põrandad ja põrandakatted (EHITUSKULUDE LIIGITAMINE EVS 885:2005) | Betoon - Ol.Olev konstruktsioon | 16,73 | New
Betoon - Ol.Olev konstruktsioon | 2 KORRUS | 1.6 IfcCovering (pinnakatted) (_RKAS BIM + ARCHICAD Classification); 56 Põrandad ja põrandakatted (EHITUSKULUDE LIIGITAMINE EVS 885:2005) | Betoon - Ol.Olev konstruktsioon | 16,74 | New
Betoon - Ol.Olev konstruktsioon | 2 KORRUS | 1.6 IfcCovering (pinnakatted) (_RKAS BIM + ARCHICAD Classification); 56 Põrandad ja põrandakatted (EHITUSKULUDE LIIGITAMINE EVS 885:2005) | Betoon - Ol.Olev konstruktsioon | 16,72 | New
Betoon - Ol.Olev konstruktsioon | 2 KORRUS | 1.6 IfcCovering (pinnakatted) (_RKAS BIM + ARCHICAD Classification); 56 Põrandad ja põrandakatted (EHITUSKULUDE LIIGITAMINE EVS 885:2005) | Betoon - Ol.Olev konstruktsioon | 0,00 | New
Betoon - Ol.Olev konstruktsioon | 2 KORRUS | 1.6 IfcCovering (pinnakatted) (_RKAS BIM + ARCHICAD Classification); 56 Põrandad ja põrandakatted (EHITUSKULUDE LIIGITAMINE EVS 885:2005) | Betoon - Ol.Olev konstruktsioon | 10,46 | New
Betoon - Ol.Olev konstruktsioon | 2 KORRUS | 1.6 IfcCovering (pinnakatted) (_RKAS BIM + ARCHICAD Classification); 56 Põrandad ja põrandakatted (EHITUSKULUDE LIIGITAMINE EVS 885:2005) | Betoon - Ol.Olev konstruktsioon | 9,57 | New
Betoon - Ol.Olev konstruktsioon | 2 KORRUS | 1.6 IfcCovering (pinnakatted) (_RKAS BIM + ARCHICAD Classification); 56 Põrandad ja põrandakatted (EHITUSKULUDE LIIGITAMINE EVS 885:2005) | Betoon - Ol.Olev konstruktsioon | 10,40 | New
Betoon - Ol.Olev konstruktsioon | 2 KORRUS | 1.6 IfcCovering (pinnakatted) (_RKAS BIM + ARCHICAD Classification); 56 Põrandad ja põrandakatted (EHITUSKULUDE LIIGITAMINE EVS 885:2005) | Betoon - Ol.Olev konstruktsioon | 20,97 | New
Betoon - Ol.Olev konstruktsioon | 2 KORRUS | 1.6 IfcCovering (pinnakatted) (_RKAS BIM + ARCHICAD Classification); 56 Põrandad ja põrandakatted (EHITUSKULUDE LIIGITAMINE EVS 885:2005) | Betoon - Ol.Olev konstruktsioon | 21,51 | New
Betoon - Ol.Olev konstruktsioon | 2 KORRUS | 1.6 IfcCovering (pinnakatted) (_RKAS BIM + ARCHICAD Classification); 56 Põrandad ja põrandakatted (EHITUSKULUDE LIIGITAMINE EVS 885:2005) | Betoon - Ol.Olev konstruktsioon | 11,68 | New
3 x Betoon - Ol.Olev konstruktsioon | 2 KORRUS | 1.6 IfcCovering (pinnakatted) (_RKAS BIM + ARCHICAD Classification); 56 Põrandad ja põrandakatted (EHITUSKULUDE LIIGITAMINE EVS 885:2005) | Betoon - Ol.Olev konstruktsioon | 11,48 | New
Betoon - Ol.Olev konstruktsioon | 2 KORRUS | 1.6 IfcCovering (pinnakatted) (_RKAS BIM + ARCHICAD Classification); 56 Põrandad ja põrandakatted (EHITUSKULUDE LIIGITAMINE EVS 885:2005) | Betoon - Ol.Olev konstruktsioon | 11,46 | New
2 x Betoon - Ol.Olev konstruktsioon | 2 KORRUS | 1.6 IfcCovering (pinnakatted) (_RKAS BIM + ARCHICAD Classification); 56 Põrandad ja põrandakatted (EHITUSKULUDE LIIGITAMINE EVS 885:2005) | Betoon - Ol.Olev konstruktsioon | 11,47 | New
Betoon - Ol.Olev konstruktsioon | 2 KORRUS | 1.6 IfcCovering (pinnakatted) (_RKAS BIM + ARCHICAD Classification); 56 Põrandad ja põrandakatted (EHITUSKULUDE LIIGITAMINE EVS 885:2005) | Betoon - Ol.Olev konstruktsioon | 9,69 | New
Betoon - Ol.Olev konstruktsioon | 2 KORRUS | 1.6 IfcCovering (pinnakatted) (_RKAS BIM + ARCHICAD Classification); 56 Põrandad ja põrandakatted (EHITUSKULUDE LIIGITAMINE EVS 885:2005) | Betoon - Ol.Olev konstruktsioon | 22,00 | New
Betoon - Ol.Olev konstruktsioon | 2 KORRUS | 1.6 IfcCovering (pinnakatted) (_RKAS BIM + ARCHICAD Classification); 56 Põrandad ja põrandakatted (EHITUSKULUDE LIIGITAMINE EVS 885:2005) | Betoon - Ol.Olev konstruktsioon | 29,14 | New

# IfcCovering: P-3 (29)
Type - ElementType: Element type P-3
Pinnakatted - 04 Paksus: 2,5 mm; 01 Nimetus: Põrandakate; 08 Tooteinfo: Undefined; 09 Kasutus- ja hooldusjuhend: Undefined
Name | In | Classification | Material = 01 Nimetus = Ripplagi, 02 Materjal = Pset_CoveringCommon, Material | Ripplagi, 05 Pindala = Pinnakatted, 05 Pindala = Siseviimistlus, 05 Pindala | Pinnakatted, 02 Materjal | 03 Kategooria / tüüp | 06 Tootja | 07 Mudel või toote tunnus | Renovation Status
Betoon - Ol.Olev konstruktsioon | 1 KORRUS | A Preliminaries/General conditions (CAWS); 1.6 IfcCovering (pinnakatted) (_RKAS BIM + ARCHICAD Classification); 56 Põrandad ja põrandakatted (EHITUSKULUDE LIIGITAMINE EVS 885:2005) | Betoon - Ol.Olev konstruktsioon | 2,95 | PVC rullmaterjal | P-3 Heterogeenne pvc-rullmaterjal | Undefined | Eternal Material warm textured concrete | New
Betoon - Ol.Olev konstruktsioon | 1 KORRUS | A Preliminaries/General conditions (CAWS); 1.6 IfcCovering (pinnakatted) (_RKAS BIM + ARCHICAD Classification); 56 Põrandad ja põrandakatted (EHITUSKULUDE LIIGITAMINE EVS 885:2005) | Betoon - Ol.Olev konstruktsioon | 3,77 | PVC rullmaterjal | P-3 Heterogeenne pvc-rullmaterjal | Undefined | Eternal Material warm textured concrete | New
Betoon - Ol.Olev konstruktsioon | 1 KORRUS | A Preliminaries/General conditions (CAWS); 1.6 IfcCovering (pinnakatted) (_RKAS BIM + ARCHICAD Classification); 56 Põrandad ja põrandakatted (EHITUSKULUDE LIIGITAMINE EVS 885:2005) | Betoon - Ol.Olev konstruktsioon | 4,97 | PVC rullmaterjal | P-3 Heterogeenne pvc-rullmaterjal | Undefined | Eternal Material warm textured concrete | New
Betoon - Ol.Olev konstruktsioon | 1 KORRUS | A Preliminaries/General conditions (CAWS); 1.6 IfcCovering (pinnakatted) (_RKAS BIM + ARCHICAD Classification); 56 Põrandad ja põrandakatted (EHITUSKULUDE LIIGITAMINE EVS 885:2005) | Betoon - Ol.Olev konstruktsioon | 7,00 | PVC rullmaterjal | P-3 Heterogeenne pvc-rullmaterjal | Undefined | Eternal Material warm textured concrete | New
Betoon - Ol.Olev konstruktsioon | 1 KORRUS | A Preliminaries/General conditions (CAWS); 1.6 IfcCovering (pinnakatted) (_RKAS BIM + ARCHICAD Classification); 56 Põrandad ja põrandakatted (EHITUSKULUDE LIIGITAMINE EVS 885:2005) | Betoon - Ol.Olev konstruktsioon | 8,29 | PVC rullmaterjal | P-3 Heterogeenne pvc-rullmaterjal | Undefined | Eternal Material warm textured concrete | New
Betoon - Ol.Olev konstruktsioon | 1 KORRUS | A Preliminaries/General conditions (CAWS); 1.6 IfcCovering (pinnakatted) (_RKAS BIM + ARCHICAD Classification); 56 Põrandad ja põrandakatted (EHITUSKULUDE LIIGITAMINE EVS 885:2005) | Betoon - Ol.Olev konstruktsioon | 21,89 | PVC rullmaterjal | P-3 Heterogeenne pvc-rullmaterjal | Undefined | Eternal Material warm textured concrete | New
Betoon - Ol.Olev konstruktsioon | 1 KORRUS | A Preliminaries/General conditions (CAWS); 1.6 IfcCovering (pinnakatted) (_RKAS BIM + ARCHICAD Classification); 56 Põrandad ja põrandakatted (EHITUSKULUDE LIIGITAMINE EVS 885:2005) | Betoon - Ol.Olev konstruktsioon | 42,17 | PVC rullmaterjal | P-3 Heterogeenne pvc-rullmaterjal | Undefined | Eternal Material warm textured concrete | New
Betoon - Ol.Olev konstruktsioon | 1 KORRUS | A Preliminaries/General conditions (CAWS); 1.6 IfcCovering (pinnakatted) (_RKAS BIM + ARCHICAD Classification); 56 Põrandad ja põrandakatted (EHITUSKULUDE LIIGITAMINE EVS 885:2005) | Betoon - Ol.Olev konstruktsioon | 20,01 | PVC rullmaterjal | P-3 Heterogeenne pvc-rullmaterjal | Undefined | Eternal Material warm textured concrete | New
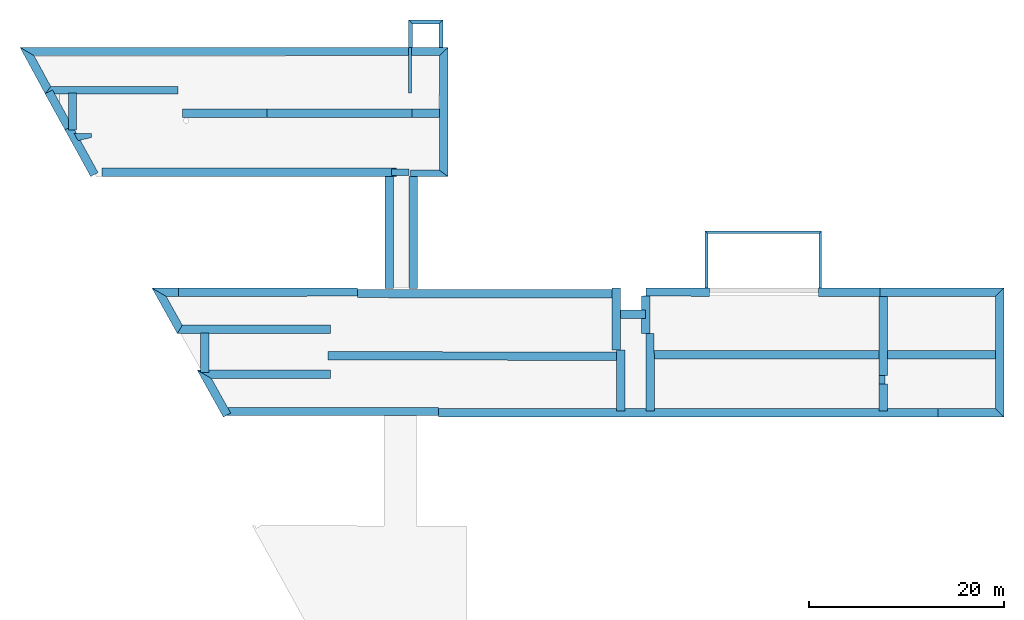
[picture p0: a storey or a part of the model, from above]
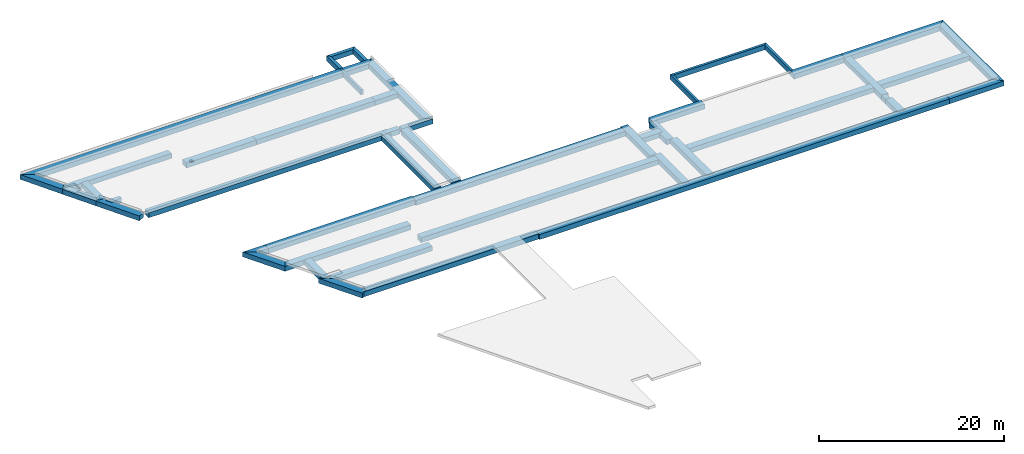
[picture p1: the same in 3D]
Properties of the parts of a building model (IFC2X3), part 5 of 14

# IfcCovering: P-3 (29)
Name | In | Classification | Material = 01 Nimetus = Ripplagi, 02 Materjal = Pset_CoveringCommon, Material | Ripplagi, 05 Pindala = Pinnakatted, 05 Pindala = Siseviimistlus, 05 Pindala | Pinnakatted, 02 Materjal | 03 Kategooria / tüüp | 06 Tootja | 07 Mudel või toote tunnus | Renovation Status
Betoon - Ol.Olev konstruktsioon | 1 KORRUS | A Preliminaries/General conditions (CAWS); 1.6 IfcCovering (pinnakatted) (_RKAS BIM + ARCHICAD Classification); 56 Põrandad ja põrandakatted (EHITUSKULUDE LIIGITAMINE EVS 885:2005) | Betoon - Ol.Olev konstruktsioon | 10,63 | PVC rullmaterjal | P-3 Heterogeenne pvc-rullmaterjal | Undefined | Eternal Material warm textured concrete | New
Betoon - Ol.Olev konstruktsioon | 1 KORRUS | A Preliminaries/General conditions (CAWS); 1.6 IfcCovering (pinnakatted) (_RKAS BIM + ARCHICAD Classification); 56 Põrandad ja põrandakatted (EHITUSKULUDE LIIGITAMINE EVS 885:2005) | Betoon - Ol.Olev konstruktsioon | 16,45 | PVC rullmaterjal | P-3 Heterogeenne pvc-rullmaterjal | Undefined | Eternal Material warm textured concrete | New
Betoon - Ol.Olev konstruktsioon | 1 KORRUS | A Preliminaries/General conditions (CAWS); 1.6 IfcCovering (pinnakatted) (_RKAS BIM + ARCHICAD Classification); 56 Põrandad ja põrandakatted (EHITUSKULUDE LIIGITAMINE EVS 885:2005) | Betoon - Ol.Olev konstruktsioon | 16,50 | PVC rullmaterjal | P-3 Heterogeenne pvc-rullmaterjal | Undefined | Eternal Material warm textured concrete | New
Betoon - Ol.Olev konstruktsioon | 1 KORRUS | A Preliminaries/General conditions (CAWS); 1.6 IfcCovering (pinnakatted) (_RKAS BIM + ARCHICAD Classification); 56 Põrandad ja põrandakatted (EHITUSKULUDE LIIGITAMINE EVS 885:2005) | Betoon - Ol.Olev konstruktsioon | 16,53 | PVC rullmaterjal | P-3 Heterogeenne pvc-rullmaterjal | Undefined | Eternal Material warm textured concrete | New
Betoon - Ol.Olev konstruktsioon | 1 KORRUS | A Preliminaries/General conditions (CAWS); 1.6 IfcCovering (pinnakatted) (_RKAS BIM + ARCHICAD Classification); 56 Põrandad ja põrandakatted (EHITUSKULUDE LIIGITAMINE EVS 885:2005) | Betoon - Ol.Olev konstruktsioon | 16,43 | PVC rullmaterjal | P-3 Heterogeenne pvc-rullmaterjal | Undefined | Eternal Material warm textured concrete | New
Betoon - Ol.Olev konstruktsioon | 1 KORRUS | A Preliminaries/General conditions (CAWS); 1.6 IfcCovering (pinnakatted) (_RKAS BIM + ARCHICAD Classification); 56 Põrandad ja põrandakatted (EHITUSKULUDE LIIGITAMINE EVS 885:2005) | Betoon - Ol.Olev konstruktsioon | 10,57 | PVC rullmaterjal | P-3 Heterogeenne pvc-rullmaterjal | Undefined | Eternal Material warm textured concrete | New
Betoon - Ol.Olev konstruktsioon | 1 KORRUS | A Preliminaries/General conditions (CAWS); 1.6 IfcCovering (pinnakatted) (_RKAS BIM + ARCHICAD Classification); 56 Põrandad ja põrandakatted (EHITUSKULUDE LIIGITAMINE EVS 885:2005) | Betoon - Ol.Olev konstruktsioon | 10,40 | PVC rullmaterjal | P-3 Heterogeenne pvc-rullmaterjal | Undefined | Eternal Material warm textured concrete | New
Betoon - Ol.Olev konstruktsioon | 1 KORRUS | A Preliminaries/General conditions (CAWS); 1.6 IfcCovering (pinnakatted) (_RKAS BIM + ARCHICAD Classification); 56 Põrandad ja põrandakatted (EHITUSKULUDE LIIGITAMINE EVS 885:2005) | Betoon - Ol.Olev konstruktsioon | 10,38 | PVC rullmaterjal | P-3 Heterogeenne pvc-rullmaterjal | Undefined | Eternal Material warm textured concrete | New
Betoon - Ol.Olev konstruktsioon | 1 KORRUS | A Preliminaries/General conditions (CAWS); 1.6 IfcCovering (pinnakatted) (_RKAS BIM + ARCHICAD Classification); 56 Põrandad ja põrandakatted (EHITUSKULUDE LIIGITAMINE EVS 885:2005) | Betoon - Ol.Olev konstruktsioon | 9,45 | PVC rullmaterjal | P-3 Heterogeenne pvc-rullmaterjal | Undefined | Eternal Material warm textured concrete | New
Betoon - Ol.Olev konstruktsioon | 1 KORRUS | A Preliminaries/General conditions (CAWS); 1.6 IfcCovering (pinnakatted) (_RKAS BIM + ARCHICAD Classification); 56 Põrandad ja põrandakatted (EHITUSKULUDE LIIGITAMINE EVS 885:2005) | Betoon - Ol.Olev konstruktsioon | 26,04 | PVC rullmaterjal | P-3 Heterogeenne pvc-rullmaterjal | Undefined | Eternal Material warm textured concrete | New
Betoon - Ol.Olev konstruktsioon | 1 KORRUS | A Preliminaries/General conditions (CAWS); 1.6 IfcCovering (pinnakatted) (_RKAS BIM + ARCHICAD Classification); 56 Põrandad ja põrandakatted (EHITUSKULUDE LIIGITAMINE EVS 885:2005) | Betoon - Ol.Olev konstruktsioon | 16,14 | PVC rullmaterjal | P-3 Heterogeenne pvc-rullmaterjal | Undefined | Eternal Material warm textured concrete | New
Betoon - Ol.Olev konstruktsioon | 1 KORRUS | A Preliminaries/General conditions (CAWS); 1.6 IfcCovering (pinnakatted) (_RKAS BIM + ARCHICAD Classification); 56 Põrandad ja põrandakatted (EHITUSKULUDE LIIGITAMINE EVS 885:2005) | Betoon - Ol.Olev konstruktsioon | 17,36 | PVC rullmaterjal | P-3 Heterogeenne pvc-rullmaterjal | Undefined | Eternal Material warm textured concrete | New
Betoon - Ol.Olev konstruktsioon | 1 KORRUS | A Preliminaries/General conditions (CAWS); 1.6 IfcCovering (pinnakatted) (_RKAS BIM + ARCHICAD Classification); 56 Põrandad ja põrandakatted (EHITUSKULUDE LIIGITAMINE EVS 885:2005) | Betoon - Ol.Olev konstruktsioon | 13,31 | PVC rullmaterjal | P-3 Heterogeenne pvc-rullmaterjal | Undefined | Eternal Material warm textured concrete | New
Betoon - Ol.Olev konstruktsioon | 1 KORRUS | A Preliminaries/General conditions (CAWS); 1.6 IfcCovering (pinnakatted) (_RKAS BIM + ARCHICAD Classification); 56 Põrandad ja põrandakatted (EHITUSKULUDE LIIGITAMINE EVS 885:2005) | Betoon - Ol.Olev konstruktsioon | 20,70 | PVC rullmaterjal | P-3 Heterogeenne pvc-rullmaterjal | Undefined | Eternal Material warm textured concrete | New
Betoon - Ol.Olev konstruktsioon | 1 KORRUS | A Preliminaries/General conditions (CAWS); 1.6 IfcCovering (pinnakatted) (_RKAS BIM + ARCHICAD Classification); 56 Põrandad ja põrandakatted (EHITUSKULUDE LIIGITAMINE EVS 885:2005) | Betoon - Ol.Olev konstruktsioon | 81,75 | PVC rullmaterjal | P-3 Heterogeenne pvc-rullmaterjal | Undefined | Eternal Material warm textured concrete | New
Puit - Konstruktsioon (1) | 1 KORRUS | 1.6 IfcCovering (pinnakatted) (_RKAS BIM + ARCHICAD Classification); 56 Põrandad ja põrandakatted (EHITUSKULUDE LIIGITAMINE EVS 885:2005) | Puit - Konstruktsioon (1) | 0,25 | LVT materjal | P-3 LVT e imitatsioonplaadid | FLOORIN | Bevel Line Wood blond field ash | Existing
Puit - Konstruktsioon (1) | 1 KORRUS | 1.6 IfcCovering (pinnakatted) (_RKAS BIM + ARCHICAD Classification); 56 Põrandad ja põrandakatted (EHITUSKULUDE LIIGITAMINE EVS 885:2005) | Puit - Konstruktsioon (1) | 0,91 | LVT materjal | P-3 LVT e imitatsioonplaadid | FLOORIN | Bevel Line Wood blond field ash | Existing
Puit - Konstruktsioon (1) | 1 KORRUS | 1.6 IfcCovering (pinnakatted) (_RKAS BIM + ARCHICAD Classification); 56 Põrandad ja põrandakatted (EHITUSKULUDE LIIGITAMINE EVS 885:2005) | Puit - Konstruktsioon (1) | 0,17 | LVT materjal | P-3 LVT e imitatsioonplaadid | FLOORIN | Bevel Line Wood blond field ash | Existing
Betoon - Ol.Olev konstruktsioon | 2 KORRUS | 1.6 IfcCovering (pinnakatted) (_RKAS BIM + ARCHICAD Classification); 56 Põrandad ja põrandakatted (EHITUSKULUDE LIIGITAMINE EVS 885:2005) | Betoon - Ol.Olev konstruktsioon | 9,26 | PVC rullmaterjal | P-3 Heterogeenne pvc-rullmaterjal | Undefined | Eternal Material warm textured concrete | New
Betoon - Ol.Olev konstruktsioon | 2 KORRUS | 1.6 IfcCovering (pinnakatted) (_RKAS BIM + ARCHICAD Classification); 56 Põrandad ja põrandakatted (EHITUSKULUDE LIIGITAMINE EVS 885:2005) | Betoon - Ol.Olev konstruktsioon | 0,01 | PVC rullmaterjal | P-3 Heterogeenne pvc-rullmaterjal | Undefined | Eternal Material warm textured concrete | New
Betoon - Ol.Olev konstruktsioon | 2 KORRUS | 1.6 IfcCovering (pinnakatted) (_RKAS BIM + ARCHICAD Classification); 56 Põrandad ja põrandakatted (EHITUSKULUDE LIIGITAMINE EVS 885:2005) | Betoon - Ol.Olev konstruktsioon | 7,13 | PVC rullmaterjal | P-3 Heterogeenne pvc-rullmaterjal | Undefined | Eternal Material warm textured concrete | New

# IfcCovering: P-4 (15)
Type - ElementType: Element type P-4
Pinnakatted - 01 Nimetus: Põrandakate; 06 Tootja: FLOORIN; 08 Tooteinfo: Undefined; 09 Kasutus- ja hooldusjuhend: Undefined
Name | In | Classification | Material = 01 Nimetus = Ripplagi, 02 Materjal = Pset_CoveringCommon, Material | Ripplagi, 05 Pindala = Pinnakatted, 05 Pindala = Siseviimistlus, 05 Pindala | 04 Paksus | Pinnakatted, 02 Materjal | 03 Kategooria / tüüp | 07 Mudel või toote tunnus | Renovation Status
Betoon - Ol.Olev konstruktsioon | 1 KORRUS | A Preliminaries/General conditions (CAWS); 1.6 IfcCovering (pinnakatted) (_RKAS BIM + ARCHICAD Classification); 56 Põrandad ja põrandakatted (EHITUSKULUDE LIIGITAMINE EVS 885:2005) | Betoon - Ol.Olev konstruktsioon | 10,32 | 2,0 mm | ESD katte | P-4 Antistaatiline ESD katte | Polyflor SD Silver Grey | New
Betoon - Ol.Olev konstruktsioon | 1 KORRUS | A Preliminaries/General conditions (CAWS); 1.6 IfcCovering (pinnakatted) (_RKAS BIM + ARCHICAD Classification); 56 Põrandad ja põrandakatted (EHITUSKULUDE LIIGITAMINE EVS 885:2005) | Betoon - Ol.Olev konstruktsioon | 17,22 | 2,0 mm | ESD katte | P-4 Antistaatiline ESD katte | Polyflor SD Silver Grey | New
Betoon - Ol.Olev konstruktsioon | 1 KORRUS | A Preliminaries/General conditions (CAWS); 1.6 IfcCovering (pinnakatted) (_RKAS BIM + ARCHICAD Classification); 56 Põrandad ja põrandakatted (EHITUSKULUDE LIIGITAMINE EVS 885:2005) | Betoon - Ol.Olev konstruktsioon | 21,43 | 2,0 mm | ESD katte | P-4 Antistaatiline ESD katte | Polyflor SD Silver Grey | New
Betoon - Ol.Olev konstruktsioon | 1 KORRUS | A Preliminaries/General conditions (CAWS); 1.6 IfcCovering (pinnakatted) (_RKAS BIM + ARCHICAD Classification); 56 Põrandad ja põrandakatted (EHITUSKULUDE LIIGITAMINE EVS 885:2005) | Betoon - Ol.Olev konstruktsioon | 33,89 | 2,0 mm | ESD katte | P-4 Antistaatiline ESD katte | Polyflor SD Silver Grey | New
Betoon - Ol.Olev konstruktsioon | 1 KORRUS | A Preliminaries/General conditions (CAWS); 1.6 IfcCovering (pinnakatted) (_RKAS BIM + ARCHICAD Classification); 56 Põrandad ja põrandakatted (EHITUSKULUDE LIIGITAMINE EVS 885:2005) | Betoon - Ol.Olev konstruktsioon | 5,56 | 2,0 mm | ESD katte | P-4 Antistaatiline ESD katte | Polyflor SD Silver Grey | New
Betoon - Ol.Olev konstruktsioon | 1 KORRUS | A Preliminaries/General conditions (CAWS); 1.6 IfcCovering (pinnakatted) (_RKAS BIM + ARCHICAD Classification); 56 Põrandad ja põrandakatted (EHITUSKULUDE LIIGITAMINE EVS 885:2005) | Betoon - Ol.Olev konstruktsioon | 10,65 | 2,0 mm | ESD katte | P-4 Antistaatiline ESD katte | Polyflor SD Silver Grey | New
Betoon - Ol.Olev konstruktsioon | 1 KORRUS | A Preliminaries/General conditions (CAWS); 1.6 IfcCovering (pinnakatted) (_RKAS BIM + ARCHICAD Classification); 56 Põrandad ja põrandakatted (EHITUSKULUDE LIIGITAMINE EVS 885:2005) | Betoon - Ol.Olev konstruktsioon | 16,45 | 2,0 mm | ESD katte | P-4 Antistaatiline ESD katte | Polyflor SD Silver Grey | New
Betoon - Ol.Olev konstruktsioon | 1 KORRUS | A Preliminaries/General conditions (CAWS); 1.6 IfcCovering (pinnakatted) (_RKAS BIM + ARCHICAD Classification); 56 Põrandad ja põrandakatted (EHITUSKULUDE LIIGITAMINE EVS 885:2005) | Betoon - Ol.Olev konstruktsioon | 21,64 | 2,0 mm | ESD katte | P-4 Antistaatiline ESD katte | Polyflor SD Silver Grey | New
Betoon - Ol.Olev konstruktsioon | 1 KORRUS | A Preliminaries/General conditions (CAWS); 1.6 IfcCovering (pinnakatted) (_RKAS BIM + ARCHICAD Classification); 56 Põrandad ja põrandakatted (EHITUSKULUDE LIIGITAMINE EVS 885:2005) | Betoon - Ol.Olev konstruktsioon | 7,08 | 2,0 mm | ESD katte | P-4 Antistaatiline ESD katte | Polyflor SD Silver Grey | New
Puit - Konstruktsioon (1) | 1 KORRUS | 1.6 IfcCovering (pinnakatted) (_RKAS BIM + ARCHICAD Classification); 56 Põrandad ja põrandakatted (EHITUSKULUDE LIIGITAMINE EVS 885:2005) | Puit - Konstruktsioon (1) | 0,62 | 2,5 mm | LVT materjal | P-4 LVT e imitatsioonplaadid | Bevel Line Wood blond field ash | Existing
Betoon - Ol.Olev konstruktsioon | 1 KORRUS | A Preliminaries/General conditions (CAWS); 1.6 IfcCovering (pinnakatted) (_RKAS BIM + ARCHICAD Classification); 56 Põrandad ja põrandakatted (EHITUSKULUDE LIIGITAMINE EVS 885:2005) | Betoon - Ol.Olev konstruktsioon | 10,49 | 2,0 mm | ESD katte | P-4 Antistaatiline ESD katte | Polyflor SD Silver Grey | New
Puit - Konstruktsioon (1) | 1 KORRUS | 1.6 IfcCovering (pinnakatted) (_RKAS BIM + ARCHICAD Classification); 56 Põrandad ja põrandakatted (EHITUSKULUDE LIIGITAMINE EVS 885:2005) | Puit - Konstruktsioon (1) | 0,18 | 2,5 mm | LVT materjal | P-4 LVT e imitatsioonplaadid | Bevel Line Wood blond field ash | Existing
Betoon - Ol.Olev konstruktsioon | 2 KORRUS | 1.6 IfcCovering (pinnakatted) (_RKAS BIM + ARCHICAD Classification); 56 Põrandad ja põrandakatted (EHITUSKULUDE LIIGITAMINE EVS 885:2005) | Betoon - Ol.Olev konstruktsioon | 16,22 | 2,0 mm | ESD katte | P-4 Antistaatiline ESD katte | Polyflor SD Silver Grey | New
Betoon - Ol.Olev konstruktsioon | 2 KORRUS | 1.6 IfcCovering (pinnakatted) (_RKAS BIM + ARCHICAD Classification); 56 Põrandad ja põrandakatted (EHITUSKULUDE LIIGITAMINE EVS 885:2005) | Betoon - Ol.Olev konstruktsioon | 70,74 | 2,0 mm | ESD katte | P-4 Antistaatiline ESD katte | Polyflor SD Silver Grey | New
Betoon - Ol.Olev konstruktsioon | 2 KORRUS | 1.6 IfcCovering (pinnakatted) (_RKAS BIM + ARCHICAD Classification); 56 Põrandad ja põrandakatted (EHITUSKULUDE LIIGITAMINE EVS 885:2005) | Betoon - Ol.Olev konstruktsioon | 35,01 | 2,0 mm | ESD katte | P-4 Antistaatiline ESD katte | Polyflor SD Silver Grey | New

# IfcCovering: P-5 (21)
Type - ElementType: Element type P-5
Material: Betoon - Ol.Olev konstruktsioon
Ripplagi - 01 Nimetus: Betoon - Ol.Olev konstruktsioon; 02 Materjal: Betoon - Ol.Olev konstruktsioon
Pinnakatted - 04 Paksus: 10 mm; 01 Nimetus: Põrandakate; 02 Materjal: Keraamiline plaat; 03 Kategooria / tüüp: P-5 Niiskuskindel keraamiline plaat; 06 Tootja: FLORIN; 07 Mudel või toote tunnus: Fioranese Liquida & SLABS herbalist; 08 Tooteinfo: Undefined; 09 Kasutus- ja hooldusjuhend: Undefined
Pset_CoveringCommon - Material: Betoon - Ol.Olev konstruktsioon
AC_Pset_RenovationAndPhasing - Renovation Status: New
Name | In | Classification | Ripplagi, 05 Pindala = Pinnakatted, 05 Pindala = Siseviimistlus, 05 Pindala
Betoon - Ol.Olev konstruktsioon | 1 KORRUS | A Preliminaries/General conditions (CAWS); 1.6 IfcCovering (pinnakatted) (_RKAS BIM + ARCHICAD Classification); 56 Põrandad ja põrandakatted (EHITUSKULUDE LIIGITAMINE EVS 885:2005) | 6,04
Betoon - Ol.Olev konstruktsioon | 1 KORRUS | A Preliminaries/General conditions (CAWS); 1.6 IfcCovering (pinnakatted) (_RKAS BIM + ARCHICAD Classification); 56 Põrandad ja põrandakatted (EHITUSKULUDE LIIGITAMINE EVS 885:2005) | 1,76
Betoon - Ol.Olev konstruktsioon | 1 KORRUS | A Preliminaries/General conditions (CAWS); 1.6 IfcCovering (pinnakatted) (_RKAS BIM + ARCHICAD Classification); 56 Põrandad ja põrandakatted (EHITUSKULUDE LIIGITAMINE EVS 885:2005) | 1,54
Betoon - Ol.Olev konstruktsioon | 1 KORRUS | A Preliminaries/General conditions (CAWS); 1.6 IfcCovering (pinnakatted) (_RKAS BIM + ARCHICAD Classification); 56 Põrandad ja põrandakatted (EHITUSKULUDE LIIGITAMINE EVS 885:2005) | 5,27
Betoon - Ol.Olev konstruktsioon | 1 KORRUS | A Preliminaries/General conditions (CAWS); 1.6 IfcCovering (pinnakatted) (_RKAS BIM + ARCHICAD Classification); 56 Põrandad ja põrandakatted (EHITUSKULUDE LIIGITAMINE EVS 885:2005) | 5,50
Betoon - Ol.Olev konstruktsioon | 1 KORRUS | A Preliminaries/General conditions (CAWS); 1.6 IfcCovering (pinnakatted) (_RKAS BIM + ARCHICAD Classification); 56 Põrandad ja põrandakatted (EHITUSKULUDE LIIGITAMINE EVS 885:2005) | 1,20
Betoon - Ol.Olev konstruktsioon | 1 KORRUS | A Preliminaries/General conditions (CAWS); 1.6 IfcCovering (pinnakatted) (_RKAS BIM + ARCHICAD Classification); 56 Põrandad ja põrandakatted (EHITUSKULUDE LIIGITAMINE EVS 885:2005) | 3,85
Betoon - Ol.Olev konstruktsioon | 1 KORRUS | A Preliminaries/General conditions (CAWS); 1.6 IfcCovering (pinnakatted) (_RKAS BIM + ARCHICAD Classification); 56 Põrandad ja põrandakatted (EHITUSKULUDE LIIGITAMINE EVS 885:2005) | 4,99
Betoon - Ol.Olev konstruktsioon | 1 KORRUS | A Preliminaries/General conditions (CAWS); 1.6 IfcCovering (pinnakatted) (_RKAS BIM + ARCHICAD Classification); 56 Põrandad ja põrandakatted (EHITUSKULUDE LIIGITAMINE EVS 885:2005) | 5,76
Betoon - Ol.Olev konstruktsioon | 1 KORRUS | A Preliminaries/General conditions (CAWS); 1.6 IfcCovering (pinnakatted) (_RKAS BIM + ARCHICAD Classification); 56 Põrandad ja põrandakatted (EHITUSKULUDE LIIGITAMINE EVS 885:2005) | 5,20
Betoon - Ol.Olev konstruktsioon | 1 KORRUS | A Preliminaries/General conditions (CAWS); 1.6 IfcCovering (pinnakatted) (_RKAS BIM + ARCHICAD Classification); 56 Põrandad ja põrandakatted (EHITUSKULUDE LIIGITAMINE EVS 885:2005) | 9,29
Betoon - Ol.Olev konstruktsioon | 2 KORRUS | 1.6 IfcCovering (pinnakatted) (_RKAS BIM + ARCHICAD Classification); 56 Põrandad ja põrandakatted (EHITUSKULUDE LIIGITAMINE EVS 885:2005) | 7,31
Betoon - Ol.Olev konstruktsioon | 2 KORRUS | 1.6 IfcCovering (pinnakatted) (_RKAS BIM + ARCHICAD Classification); 56 Põrandad ja põrandakatted (EHITUSKULUDE LIIGITAMINE EVS 885:2005) | 3,34
Betoon - Ol.Olev konstruktsioon | 2 KORRUS | 1.6 IfcCovering (pinnakatted) (_RKAS BIM + ARCHICAD Classification); 56 Põrandad ja põrandakatted (EHITUSKULUDE LIIGITAMINE EVS 885:2005) | 1,33
Betoon - Ol.Olev konstruktsioon | 2 KORRUS | 1.6 IfcCovering (pinnakatted) (_RKAS BIM + ARCHICAD Classification); 56 Põrandad ja põrandakatted (EHITUSKULUDE LIIGITAMINE EVS 885:2005) | 7,72
Betoon - Ol.Olev konstruktsioon | 2 KORRUS | 1.6 IfcCovering (pinnakatted) (_RKAS BIM + ARCHICAD Classification); 56 Põrandad ja põrandakatted (EHITUSKULUDE LIIGITAMINE EVS 885:2005) | 6,94
Betoon - Ol.Olev konstruktsioon | 2 KORRUS | 1.6 IfcCovering (pinnakatted) (_RKAS BIM + ARCHICAD Classification); 56 Põrandad ja põrandakatted (EHITUSKULUDE LIIGITAMINE EVS 885:2005) | 1,03
Betoon - Ol.Olev konstruktsioon | 2 KORRUS | 1.6 IfcCovering (pinnakatted) (_RKAS BIM + ARCHICAD Classification); 56 Põrandad ja põrandakatted (EHITUSKULUDE LIIGITAMINE EVS 885:2005) | 0,88
Betoon - Ol.Olev konstruktsioon | 2 KORRUS | 1.6 IfcCovering (pinnakatted) (_RKAS BIM + ARCHICAD Classification); 56 Põrandad ja põrandakatted (EHITUSKULUDE LIIGITAMINE EVS 885:2005) | 1,04
Betoon - Ol.Olev konstruktsioon | 2 KORRUS | 1.6 IfcCovering (pinnakatted) (_RKAS BIM + ARCHICAD Classification); 56 Põrandad ja põrandakatted (EHITUSKULUDE LIIGITAMINE EVS 885:2005) | 5,48
Betoon - Ol.Olev konstruktsioon | 2 KORRUS | 1.6 IfcCovering (pinnakatted) (_RKAS BIM + ARCHICAD Classification); 56 Põrandad ja põrandakatted (EHITUSKULUDE LIIGITAMINE EVS 885:2005) | 7,67

# IfcCovering: P-6 (11)
Type - ElementType: Element type P-6
Material: Betoon - Ol.Olev konstruktsioon
Ripplagi - 01 Nimetus: Betoon - Ol.Olev konstruktsioon; 02 Materjal: Betoon - Ol.Olev konstruktsioon
Pinnakatted - 04 Paksus: 10 mm; 01 Nimetus: Põrandakate; 02 Materjal: Keraamiline plaat; 03 Kategooria / tüüp: P-6 Niiskuskindel keraamiline plaat; 06 Tootja: FLOORIN; 07 Mudel või toote tunnus: SA Oxidart copper; 08 Tooteinfo: Undefined; 09 Kasutus- ja hooldusjuhend: Undefined
Pset_CoveringCommon - Material: Betoon - Ol.Olev konstruktsioon
AC_Pset_RenovationAndPhasing - Renovation Status: New
Name | In | Classification | Ripplagi, 05 Pindala = Pinnakatted, 05 Pindala = Siseviimistlus, 05 Pindala
Betoon - Ol.Olev konstruktsioon | 1 KORRUS | A Preliminaries/General conditions (CAWS); 1.6 IfcCovering (pinnakatted) (_RKAS BIM + ARCHICAD Classification); 56 Põrandad ja põrandakatted (EHITUSKULUDE LIIGITAMINE EVS 885:2005) | 0,00
Betoon - Ol.Olev konstruktsioon | 1 KORRUS | A Preliminaries/General conditions (CAWS); 1.6 IfcCovering (pinnakatted) (_RKAS BIM + ARCHICAD Classification); 56 Põrandad ja põrandakatted (EHITUSKULUDE LIIGITAMINE EVS 885:2005) | 16,12
Betoon - Ol.Olev konstruktsioon | 1 KORRUS | A Preliminaries/General conditions (CAWS); 1.6 IfcCovering (pinnakatted) (_RKAS BIM + ARCHICAD Classification); 56 Põrandad ja põrandakatted (EHITUSKULUDE LIIGITAMINE EVS 885:2005) | 5,42
Betoon - Ol.Olev konstruktsioon | 1 KORRUS | A Preliminaries/General conditions (CAWS); 1.6 IfcCovering (pinnakatted) (_RKAS BIM + ARCHICAD Classification); 56 Põrandad ja põrandakatted (EHITUSKULUDE LIIGITAMINE EVS 885:2005) | 5,70
Betoon - Ol.Olev konstruktsioon | 1 KORRUS | A Preliminaries/General conditions (CAWS); 1.6 IfcCovering (pinnakatted) (_RKAS BIM + ARCHICAD Classification); 56 Põrandad ja põrandakatted (EHITUSKULUDE LIIGITAMINE EVS 885:2005) | 15,54
Betoon - Ol.Olev konstruktsioon | 1 KORRUS | A Preliminaries/General conditions (CAWS); 1.6 IfcCovering (pinnakatted) (_RKAS BIM + ARCHICAD Classification); 56 Põrandad ja põrandakatted (EHITUSKULUDE LIIGITAMINE EVS 885:2005) | 5,19
Betoon - Ol.Olev konstruktsioon | 1 KORRUS | A Preliminaries/General conditions (CAWS); 1.6 IfcCovering (pinnakatted) (_RKAS BIM + ARCHICAD Classification); 56 Põrandad ja põrandakatted (EHITUSKULUDE LIIGITAMINE EVS 885:2005) | 56,79
Betoon - Ol.Olev konstruktsioon | 1 KORRUS | A Preliminaries/General conditions (CAWS); 1.6 IfcCovering (pinnakatted) (_RKAS BIM + ARCHICAD Classification); 56 Põrandad ja põrandakatted (EHITUSKULUDE LIIGITAMINE EVS 885:2005) | 39,05
2 x Betoon - Ol.Olev konstruktsioon | 2 KORRUS | 1.6 IfcCovering (pinnakatted) (_RKAS BIM + ARCHICAD Classification); 56 Põrandad ja põrandakatted (EHITUSKULUDE LIIGITAMINE EVS 885:2005) | 3,92
Betoon - Ol.Olev konstruktsioon | 2 KORRUS | 1.6 IfcCovering (pinnakatted) (_RKAS BIM + ARCHICAD Classification); 56 Põrandad ja põrandakatted (EHITUSKULUDE LIIGITAMINE EVS 885:2005) | 3,29

# IfcCovering: loputuskasti raam (6)
Type - ElementType: Element type loputuskasti raam
Classification: 325 Seinte elemendid (EHITUSKULUDE LIIGITAMINE EVS 885:2005); A Preliminaries/General conditions (CAWS); 1.6 IfcCovering (pinnakatted) (_RKAS BIM + ARCHICAD Classification); Material: Betoon - Ol.Olev konstruktsioon
Ripplagi - 01 Nimetus: Betoon - Ol.Olev konstruktsioon; 02 Materjal: Betoon - Ol.Olev konstruktsioon
Pinnakatted - 04 Paksus: 2,0 mm; 01 Nimetus: loputuskasti raam; 02 Materjal: kips; 03 Kategooria / tüüp: loputuskasti raam -; 08 Tooteinfo: Undefined; 09 Kasutus- ja hooldusjuhend: Undefined
Pset_CoveringCommon - Material: Betoon - Ol.Olev konstruktsioon
AC_Pset_RenovationAndPhasing - Renovation Status: New
Name | In | Ripplagi, 05 Pindala = Pinnakatted, 05 Pindala = Siseviimistlus, 05 Pindala
Betoon - Ol.Olev konstruktsioon | 1 KORRUS | 0,16
2 x Betoon - Ol.Olev konstruktsioon | 1 KORRUS | 0,17
Betoon - Ol.Olev konstruktsioon | 2 KORRUS | 0,13
Betoon - Ol.Olev konstruktsioon | 2 KORRUS | 0,16
Betoon - Ol.Olev konstruktsioon | 2 KORRUS | 0,14

# IfcCurtainWall: KK-2, Talveaja klaaskatus
In: KATUSEPLAAN
Type - ElementType: Element type KK-2
Description: Klaas, alumiinium; Classification: 1.7 IfcCurtainWall (rippfassaad) (_RKAS BIM + ARCHICAD Classification); 41 Klaasfassaadid, vitriinid ja eriaknad (EHITUSKULUDE LIIGITAMINE EVS 885:2005)
Pset_CurtainWallCommon - ThermalTransmittance: 0.95; IsExternal: yes
Rippfassaad - 01 Nimetus: Talveaja klaaskatus Materjalid: Alumiinium (1); Klaas; 02 Materjal: Alumiinium (1); Klaas; 03 Kategooria / tüüp: KK-2; 04 Pindala: Pinna pindala: 156,26; Pinna pindala ka. Äärte ala159,30 Täpsustus: Undefined; 05 Helipidavus: 45dB; 06 Klaaspakett: kolmekordne klaaspakett, taustvärvitud klaas; 07 Soojusläbivus: 0,95 W/m2K; 08 Päikesekiirgus tegur (g-väärtus): 0,3; 09 Tulekindlus: nõudeid ei esitata; 10 Raamistiku jaotus: 96; 14 Mudel või toote tunnus: Undefined; 15 Tooteinfo: Undefined; 16 Kasutus- ja hooldusjuhend: Undefined
AC_Pset_RenovationAndPhasing - Renovation Status: New

# IfcCurtainWall: KS-1, KS
In: 2 KORRUS
Type - ElementType: Element type KS-1
Description: Klaas, alumiinium; Classification: 1.7 IfcCurtainWall (rippfassaad) (_RKAS BIM + ARCHICAD Classification); 41 Klaasfassaadid, vitriinid ja eriaknad (EHITUSKULUDE LIIGITAMINE EVS 885:2005)
Pset_CurtainWallCommon - ThermalTransmittance: 0.95; IsExternal: yes
Rippfassaad - 01 Nimetus: KS Materjalid: Alumiinium (1); Klaas (1); 02 Materjal: Alumiinium (1); Klaas (1); 03 Kategooria / tüüp: KS-1; 04 Pindala: Pinna pindala: 27,88; Pinna pindala ka. Äärte ala30,65 Täpsustus: Undefined; 05 Helipidavus: 45; 06 Klaaspakett: kolmekordne klaaspakett; 07 Soojusläbivus: 0,95W/m2K; 08 Päikesekiirgus tegur (g-väärtus): 0,3; 09 Tulekindlus: nõudeid ei esitata; 10 Raamistiku jaotus: 11; 11 Paneelide materjal: klass; 12 Karkassi materjal: alumiinium; 13 Tootja: Undefined; 14 Mudel või toote tunnus: Undefined; 15 Tooteinfo: Undefined; 16 Kasutus- ja hooldusjuhend: Undefined
AC_Pset_RenovationAndPhasing - Renovation Status: New

# IfcCurtainWall: KS-2, KS
In: 2 KORRUS
Type - ElementType: Element type KS-2
Description: Klaas, alumiinium; Classification: 1.7 IfcCurtainWall (rippfassaad) (_RKAS BIM + ARCHICAD Classification); 41 Klaasfassaadid, vitriinid ja eriaknad (EHITUSKULUDE LIIGITAMINE EVS 885:2005)
Pset_CurtainWallCommon - ThermalTransmittance: 0.95; IsExternal: yes
Rippfassaad - 01 Nimetus: KS Materjalid: Alumiinium (1); Klaas (1); 02 Materjal: Alumiinium (1); Klaas (1); 03 Kategooria / tüüp: KS-2; 04 Pindala: Pinna pindala: 27,88; Pinna pindala ka. Äärte ala30,65 Täpsustus: Undefined; 05 Helipidavus: 45; 06 Klaaspakett: kolmekordne klaaspakett; 07 Soojusläbivus: 0,95W/m2K; 08 Päikesekiirgus tegur (g-väärtus): 0,3; 09 Tulekindlus: nõudeid ei esitata; 10 Raamistiku jaotus: 11; 11 Paneelide materjal: klass; 12 Karkassi materjal: alumiinium; 13 Tootja: Undefined; 14 Mudel või toote tunnus: Undefined; 15 Tooteinfo: Undefined; 16 Kasutus- ja hooldusjuhend: Undefined
AC_Pset_RenovationAndPhasing - Renovation Status: New

# IfcCurtainWall: SKS-1, Talveaja klaassein
In: 2 KORRUS
Type - ElementType: Element type SKS-1
Classification: 1.7 IfcCurtainWall (rippfassaad) (_RKAS BIM + ARCHICAD Classification); 41 Klaasfassaadid, vitriinid ja eriaknad (EHITUSKULUDE LIIGITAMINE EVS 885:2005)
Pset_CurtainWallCommon - ThermalTransmittance: 0; IsExternal: no
Rippfassaad - 03 Kategooria / tüüp: SKS-1; 06 Klaaspakett: 6mm, 55.2 lamineeritud; 08 Päikesekiirgus tegur (g-väärtus): -; 10 Raamistiku jaotus: 19; 11 Paneelide materjal: Undefined; 12 Karkassi materjal: Undefined; 14 Mudel või toote tunnus: Undefined; 15 Tooteinfo: Undefined; 16 Kasutus- ja hooldusjuhend: Undefined
AC_Pset_RenovationAndPhasing - Renovation Status: New

# IfcCurtainWall: SKS-2, Klaassein
In: 1 KORRUS
Type - ElementType: Element type SKS-2
Description: Klaas, alumiinium; Classification: 1.7 IfcCurtainWall (rippfassaad) (_RKAS BIM + ARCHICAD Classification); 41 Klaasfassaadid, vitriinid ja eriaknad (EHITUSKULUDE LIIGITAMINE EVS 885:2005)
Pset_CurtainWallCommon - ThermalTransmittance: 0.95; IsExternal: no
Rippfassaad - 01 Nimetus: Klaassein Materjalid: Alumiinium (1); Klaas (1); 02 Materjal: Alumiinium (1); Klaas (1); 03 Kategooria / tüüp: SKS-2; 04 Pindala: Pinna pindala: 11,03; Pinna pindala ka. Äärte ala11,74 Täpsustus: Undefined; 05 Helipidavus: 38dB; 06 Klaaspakett: 6mm, 55.2 lamineeritud, ülemine rida taustvärvitud klaas; 07 Soojusläbivus: -; 08 Päikesekiirgus tegur (g-väärtus): -; 09 Tulekindlus: nõudeid ei esitata; 10 Raamistiku jaotus: 6; 11 Paneelide materjal: Undefined; 12 Karkassi materjal: Undefined; 13 Tootja: Undefined; 14 Mudel või toote tunnus: Undefined; 15 Tooteinfo: Undefined; 16 Kasutus- ja hooldusjuhend: Undefined
AC_Pset_RenovationAndPhasing - Renovation Status: New

# IfcCurtainWall: SU-1, Siseuks
In: 1 KORRUS
Type - ElementType: Element type SU-1
Description: Klaas, alumiinium; Classification: 1.7 IfcCurtainWall (rippfassaad) (_RKAS BIM + ARCHICAD Classification); 43 Välisuksed ja väravad (EHITUSKULUDE LIIGITAMINE EVS 885:2005)
Pset_CurtainWallCommon - IsExternal: yes; ThermalTransmittance: 0.95
Rippfassaad - 01 Nimetus: Siseuks Materjalid: Alumiinium (1); Klaas (1); 02 Materjal: Alumiinium (1); Klaas (1); 03 Kategooria / tüüp: SU-1; 04 Pindala: Pinna pindala: 7,93; Pinna pindala ka. Äärte ala8,11 Täpsustus: Undefined; 05 Helipidavus: -; 06 Klaaspakett: Karastatud ja lamineeritud kirgas klaas; 07 Soojusläbivus: 0,95; 08 Päikesekiirgus tegur (g-väärtus): -; 09 Tulekindlus: nõudeid ei esitata; 10 Raamistiku jaotus: 3; 11 Paneelide materjal: Karastatud ja lamineeritud kirgas klaas; 12 Karkassi materjal: Alumiiniumprofiil; 13 Tootja: Undefined; 14 Mudel või toote tunnus: Undefined; 15 Tooteinfo: Undefined; 16 Kasutus- ja hooldusjuhend: Undefined
AC_Pset_RenovationAndPhasing - Renovation Status: New

# IfcCurtainWall: SU-2, Siseuks
In: 1 KORRUS
Type - ElementType: Element type SU-2
Description: Klaas, alumiinium; Classification: 1.7 IfcCurtainWall (rippfassaad) (_RKAS BIM + ARCHICAD Classification); 43 Välisuksed ja väravad (EHITUSKULUDE LIIGITAMINE EVS 885:2005)
Pset_CurtainWallCommon - IsExternal: yes; ThermalTransmittance: 0.95
Rippfassaad - 01 Nimetus: Siseuks Materjalid: Alumiinium (1); Klaas (1); 02 Materjal: Alumiinium (1); Klaas (1); 03 Kategooria / tüüp: SU-2; 04 Pindala: Pinna pindala: 8,31; Pinna pindala ka. Äärte ala8,50 Täpsustus: Undefined; 05 Helipidavus: -; 06 Klaaspakett: Karastatud ja lamineeritud kirgas klaas; 07 Soojusläbivus: 0,95; 08 Päikesekiirgus tegur (g-väärtus): -; 09 Tulekindlus: nõudeid ei esitata; 10 Raamistiku jaotus: 3; 11 Paneelide materjal: Karastatud ja lamineeritud kirgas klaas; 12 Karkassi materjal: Alumiiniumprofiil; 13 Tootja: Undefined; 14 Mudel või toote tunnus: Undefined; 15 Tooteinfo: Undefined; 16 Kasutus- ja hooldusjuhend: Undefined
AC_Pset_RenovationAndPhasing - Renovation Status: New

# IfcCurtainWall: VU-1, Välisuks
In: 1 KORRUS
Type - ElementType: Element type VU-1
Description: Klaas, alumiinium; Classification: 1.7 IfcCurtainWall (rippfassaad) (_RKAS BIM + ARCHICAD Classification); 43 Välisuksed ja väravad (EHITUSKULUDE LIIGITAMINE EVS 885:2005)
Pset_CurtainWallCommon - IsExternal: yes; ThermalTransmittance: 0.95
Rippfassaad - 01 Nimetus: Välisuks Materjalid: Alumiinium (1); Klaas (1); 02 Materjal: Alumiinium (1); Klaas (1); 03 Kategooria / tüüp: VU-1; 04 Pindala: Pinna pindala: 7,93; Pinna pindala ka. Äärte ala8,11 Täpsustus: Undefined; 05 Helipidavus: -; 06 Klaaspakett: Karastatud ja lamineeritud kirgas klaas; 07 Soojusläbivus: 0,95; 08 Päikesekiirgus tegur (g-väärtus): -; 09 Tulekindlus: nõudeid ei esitata; 10 Raamistiku jaotus: 3; 11 Paneelide materjal: Karastatud ja lamineeritud kirgas klaas; 12 Karkassi materjal: Alumiiniumprofiil; 13 Tootja: Undefined; 14 Mudel või toote tunnus: Undefined; 15 Tooteinfo: Undefined; 16 Kasutus- ja hooldusjuhend: Undefined
AC_Pset_RenovationAndPhasing - Renovation Status: New

# IfcCurtainWall: VU-2, Välisuks
In: 1 KORRUS
Type - ElementType: Element type VU-2
Description: Klaas, alumiinium; Classification: 1.7 IfcCurtainWall (rippfassaad) (_RKAS BIM + ARCHICAD Classification); 43 Välisuksed ja väravad (EHITUSKULUDE LIIGITAMINE EVS 885:2005)
Pset_CurtainWallCommon - IsExternal: yes; ThermalTransmittance: 0.95
Rippfassaad - 01 Nimetus: Välisuks Materjalid: Alumiinium (1); Klaas (1); 02 Materjal: Alumiinium (1); Klaas (1); 03 Kategooria / tüüp: VU-2; 04 Pindala: Pinna pindala: 8,31; Pinna pindala ka. Äärte ala8,50 Täpsustus: Undefined; 05 Helipidavus: -; 06 Klaaspakett: Karastatud ja lamineeritud kirgas klaas; 07 Soojusläbivus: 0,95; 08 Päikesekiirgus tegur (g-väärtus): -; 09 Tulekindlus: nõudeid ei esitata; 10 Raamistiku jaotus: 3; 11 Paneelide materjal: Karastatud ja lamineeritud kirgas klaas; 12 Karkassi materjal: Alumiiniumprofiil; 13 Tootja: Undefined; 14 Mudel või toote tunnus: Undefined; 15 Tooteinfo: Undefined; 16 Kasutus- ja hooldusjuhend: Undefined
AC_Pset_RenovationAndPhasing - Renovation Status: New

# IfcDiscreteAccessory: Cube 22 (4)
Type - ElementType: Element type Sild
Classification: 1.8 IfcDiscreteAccessory (tarvik) (_RKAS BIM + ARCHICAD Classification); 61 Sisustus ja mööbel (EHITUSKULUDE LIIGITAMINE EVS 885:2005)
AC_Pset_RenovationAndPhasing - Renovation Status: New
Name | In
2 x FU - 001 | 1 KORRUS
2 x FU - 001 | 2 KORRUS

# IfcDiscreteAccessory: Cube 22 (5)
In: 2 KORRUS
Type - ElementType: Element type Teenindusluuk
Classification: 1.8 IfcDiscreteAccessory (tarvik) (_RKAS BIM + ARCHICAD Classification); 61 Sisustus ja mööbel (EHITUSKULUDE LIIGITAMINE EVS 885:2005)
AC_Pset_RenovationAndPhasing - Renovation Status: New

# IfcDiscreteAccessory: Peegel 5 (13)
Type - ElementType: Element type Peegel
Description: šahti sein; Classification: 1.8 IfcDiscreteAccessory (tarvik) (_RKAS BIM + ARCHICAD Classification); 61 Sisustus ja mööbel (EHITUSKULUDE LIIGITAMINE EVS 885:2005); Material: Peegel
AC_Pset_RenovationAndPhasing - Renovation Status: New
Name | In
7 x Peegel | 1 KORRUS
6 x Peegel | 2 KORRUS

# IfcDiscreteAccessory: Vertical Gable Louver 22 (2)
Type - ElementType: Element type Turvakardin
Description: Turvakardin; Classification: 2.4 IfcDiscreteAccessory (tarvik) (_RKAS BIM + ARCHICAD Classification); 754 Turvasüsteemid (EHITUSKULUDE LIIGITAMINE EVS 885:2005)
AC_Pset_RenovationAndPhasing - Renovation Status: New
Name | In
Turvakardin | 1 KORRUS
Turvakardin | 2 KORRUS

# IfcDoor: 1150 x 5 x 20 (7)
In: 1 KORRUS
Type - ParameterTakesPrecedence: no; Sizeable: no
Avatäited - 02 Materjal: Klaasiga-sile metalluks; 04 Avamõõdu geomeetria: 1 140x2 100; 06 Soojusläbivus: 0,95; 09 Õhuläbilaskvus: klass 1; 10 Tulekindlus: nõudeid ei esitata; 11 Vastupanu tulekoormusele: C1; 12 Klaaspakett: Karastatud ja lamineeritud kirgas klaas; 13 Klaasingu erisused: -; 14 Päikesekiirgus tegur (g-väärtus): -; 18 Viimistlus: RAL 9003; 19 Mudel või toote tunnus: Undefined; 20 Tootja: Undefined; 21 Tooteinfo: Undefined; 22 Kasutus- ja hooldusjuhend: Undefined
Pset_ManufacturerOccurrence - SerialNumber: Off
AC_Pset_RenovationAndPhasing - Renovation Status: New
Name | Classification | 01 Nimetus | 03 Tähistus | 07 Helipidavus | 08 Veepidavus | 15 Avanemine | 16 Liigendatus | 17 Sulused, lukustus
Välisuks * CW Door 22 | 43 Välisuksed ja väravad (EHITUSKULUDE LIIGITAMINE EVS 885:2005); 1.9 IfcDoor (uks) (_RKAS BIM + ARCHICAD Classification) | Välisuks | VU-1 1 140x2 100 | - | 2a | Avanemine: "L{Abbreviation of Left}" (L - vasak; R - parem) | madal, kuni 25mm, roostevaba | Väändenupp/liblikas, sulgur, roostevaba terasest käepide, toru läbimõõt 25 mm, pikkus 600 mm
Välisuks * CW Door 22 | 43 Välisuksed ja väravad (EHITUSKULUDE LIIGITAMINE EVS 885:2005); 1.9 IfcDoor (uks) (_RKAS BIM + ARCHICAD Classification) | Välisuks | VU-1 1 140x2 100 | - | 2a | Avanemine: "R{Abbreviation of Right}" (L - vasak; R - parem) | madal, kuni 25mm, roostevaba | Väändenupp/liblikas, sulgur, roostevaba terasest käepide, toru läbimõõt 25 mm, pikkus 600 mm
Siseuks * CW Door 22 | 1.9 IfcDoor (uks) (_RKAS BIM + ARCHICAD Classification); 52 Siseuksed (EHITUSKULUDE LIIGITAMINE EVS 885:2005) | Siseuks | SU-2 1 140x2 100 | 30dB | 2a | Avanemine: "R{Abbreviation of Right}" (L - vasak; R - parem) | Lävepakk madal, kuni 25mm, Roostevabateras | Vändenupp/liblikas, sulgur, kiirriiv, roostevaba terasest käepide, toru läbimõõt 25 mm, pikkus 600 mm
Siseuks * CW Door 22 | 43 Välisuksed ja väravad (EHITUSKULUDE LIIGITAMINE EVS 885:2005); 1.9 IfcDoor (uks) (_RKAS BIM + ARCHICAD Classification) | Siseuks | SU-1 1 140x2 100 | 30dB | - | Avanemine: "R{Abbreviation of Right}" (L - vasak; R - parem) | Lävepakk madal, kuni 25mm, Roostevabateras | Vändenupp/liblikas, sulgur, kiirriiv, roostevaba terasest käepide, toru läbimõõt 25 mm, pikkus 600 mm
Siseuks * CW Door 22 | 1.9 IfcDoor (uks) (_RKAS BIM + ARCHICAD Classification); 52 Siseuksed (EHITUSKULUDE LIIGITAMINE EVS 885:2005) | Siseuks | SU-1 1 140x2 100 | 30dB | - | Avanemine: "L{Abbreviation of Left}" (L - vasak; R - parem) | Lävepakk madal, kuni 25mm, Roostevabateras | Vändenupp/liblikas, sulgur, kiirriiv, roostevaba terasest käepide, toru läbimõõt 25 mm, pikkus 600 mm
Välisuks * CW Door 22 | 43 Välisuksed ja väravad (EHITUSKULUDE LIIGITAMINE EVS 885:2005); 1.9 IfcDoor (uks) (_RKAS BIM + ARCHICAD Classification) | Välisuks | VU-1 1 140x2 100 | - | 2a | Avanemine: "R{Abbreviation of Right}" (L - vasak; R - parem) | Lävepakk madal max 25mm, roostevaba | Väändenupp/liblikas, sulgur, roostevaba terasest käepide, toru läbimõõt 25 mm, pikkus 600 mm
Välisuks * CW Door 22 | 43 Välisuksed ja väravad (EHITUSKULUDE LIIGITAMINE EVS 885:2005); 1.9 IfcDoor (uks) (_RKAS BIM + ARCHICAD Classification) | Välisuks | VU-1 1 140x2 100 | - | 2a | Avanemine: "L{Abbreviation of Left}" (L - vasak; R - parem) | Lävepakk madal max 25mm, roostevaba | Väändenupp/liblikas, sulgur, roostevaba terasest käepide, toru läbimõõt 25 mm, pikkus 600 mm

# IfcDoor: Distinct Panel 1150 x 5 x 20, Välisuks * CW Door 22
In: 1 KORRUS
Type - ParameterTakesPrecedence: no; Sizeable: no
Classification: 43 Välisuksed ja väravad (EHITUSKULUDE LIIGITAMINE EVS 885:2005); 1.9 IfcDoor (uks) (_RKAS BIM + ARCHICAD Classification)
Avatäited - 01 Nimetus: Välisuks; 02 Materjal: Klaasiga-sile metalluks; 03 Tähistus: VU-1 1 140x2 100; 04 Avamõõdu geomeetria: 1 140x2 100; 06 Soojusläbivus: 0,95; 07 Helipidavus: 40 dB; 08 Veepidavus: 2a; 09 Õhuläbilaskvus: klass 1; 10 Tulekindlus: nõudeid ei esitata; 11 Vastupanu tulekoormusele: C1; 12 Klaaspakett: Karastatud ja lamineeritud kirgas klaas; 13 Klaasingu erisused: Undefined; 14 Päikesekiirgus tegur (g-väärtus): Undefined; 15 Avanemine: Avanemine: "L{Abbreviation of Left}" (L - vasak; R - parem); 16 Liigendatus: madal, kuni 25mm, roostevaba; 17 Sulused, lukustus: Väändenupp/liblikas, sulgur, roostevaba terasest käepide, toru läbimõõt 25 mm, pikkus 600 mm; 18 Viimistlus: RAL 9003; 19 Mudel või toote tunnus: Undefined; 20 Tootja: Undefined; 21 Tooteinfo: Undefined; 22 Kasutus- ja hooldusjuhend: Undefined
Pset_ManufacturerOccurrence - SerialNumber: Off
AC_Pset_RenovationAndPhasing - Renovation Status: New

# IfcDoor: Distinct Panel 5 x 5 x 20, Siseklaasseina uks * CW Door 22
In: 1 KORRUS
Type - ParameterTakesPrecedence: no; Sizeable: no
Classification: 1.9 IfcDoor (uks) (_RKAS BIM + ARCHICAD Classification)
Avatäited - 01 Nimetus: Siseklaasseina uks; 02 Materjal: Alumiiniumprofiil klaassein; 03 Tähistus: SKS-2 850x2 170; 04 Avamõõdu geomeetria: 850x2 170; 06 Soojusläbivus: -; 07 Helipidavus: 38dB; 08 Veepidavus: -; 09 Õhuläbilaskvus: -; 10 Tulekindlus: nõudeid ei esitata; 11 Vastupanu tulekoormusele: Undefined; 12 Klaaspakett: Klaas 6mm 55.2 lamineeritud; 13 Klaasingu erisused: -; 14 Päikesekiirgus tegur (g-väärtus): -; 15 Avanemine: Avanemine: "R{Abbreviation of Right}" (L - vasak; R - parem); 17 Sulused, lukustus: vt lukustuse spetsifikatsioon; 18 Viimistlus: Undefined; 19 Mudel või toote tunnus: Undefined; 20 Tootja: Undefined; 21 Tooteinfo: Undefined; 22 Kasutus- ja hooldusjuhend: Undefined
Pset_ManufacturerOccurrence - SerialNumber: Off
AC_Pset_RenovationAndPhasing - Renovation Status: New

# IfcDoor: Distinct Panel 900 x 30 x 20 (2)
In: 2 KORRUS
Type - ParameterTakesPrecedence: no; Sizeable: no
Classification: 1.9 IfcDoor (uks) (_RKAS BIM + ARCHICAD Classification)
Avatäited - 01 Nimetus: Välisuks; 02 Materjal: Klaasiga-sile metalluks; 04 Avamõõdu geomeetria: 850x2 500; 06 Soojusläbivus: 0,95; 07 Helipidavus: -; 08 Veepidavus: 2a; 09 Õhuläbilaskvus: klass 1; 10 Tulekindlus: nõudeid ei esitata; 11 Vastupanu tulekoormusele: C1; 12 Klaaspakett: Karastatud ja lamineeritud kirgas klaas; 13 Klaasingu erisused: -; 14 Päikesekiirgus tegur (g-väärtus): -; 15 Avanemine: Avanemine: "L{Abbreviation of Left}" (L - vasak; R - parem); 16 Liigendatus: Lävepakk madal, kuni 25mm, Roostevabateras; 17 Sulused, lukustus: Vändenupp/liblikas, sulgur, kiirriiv, roostevaba terasest käepide, toru läbimõõt 25 mm, pikkus 600 mm; 18 Viimistlus: RAL 9003; 19 Mudel või toote tunnus: Undefined; 20 Tootja: Undefined; 21 Tooteinfo: Undefined; 22 Kasutus- ja hooldusjuhend: Undefined
Pset_ManufacturerOccurrence - SerialNumber: Off
AC_Pset_RenovationAndPhasing - Renovation Status: New
Name | 03 Tähistus
Välisuks * CW Door 22 | KS-2 850x2 500
Välisuks * CW Door 22 | KS-1 850x2 500

# IfcDoor: SU-A101 900×2 000, Siseuks * Door 22
In: 1 KORRUS
Type - OperationType: SINGLE_SWING_RIGHT; ParameterTakesPrecedence: no; Sizeable: no
Type - Door Lining Properties - LiningDepth: 115 mm; LiningThickness: 40 mm; LiningOffset: 0 mm; CasingThickness: 50 mm; CasingDepth: 19 mm
Type - Door Panel Properties - Panel 1 - PanelDepth: 40 mm; PanelOperation: SWINGING; PanelWidth: 1; PanelPosition: MIDDLE
OverallHeight: 2000 mm; OverallWidth: 900 mm; Classification: 1.9 IfcDoor (uks) (_RKAS BIM + ARCHICAD Classification); 52 Siseuksed (EHITUSKULUDE LIIGITAMINE EVS 885:2005)
Pset_DoorCommon - FireRating: EI30; ThermalTransmittance: 0; GlazingAreaFraction: 0; IsExternal: no
Avatäited - 18 Viimistlus: RAL 9003; 01 Nimetus: Siseuks; 02 Materjal: Sile uks; 03 Tähistus: SU-A101 900×2 000; 04 Avamõõdu geomeetria: 900×2 000; 05 Asukoha info: Interior; 06 Soojusläbivus: -; 07 Helipidavus: 30 dB; 08 Veepidavus: -; 09 Õhuläbilaskvus: -; 10 Tulekindlus: EI 30; 11 Vastupanu tulekoormusele: -; 12 Klaaspakett: -; 13 Klaasingu erisused: -; 14 Päikesekiirgus tegur (g-väärtus): -; 15 Avanemine: Avanemine: "L" (L - vasak; R - parem); 16 Liigendatus: Lävepakk madal max 25mm, roostevaba; 17 Sulused, lukustus: lukustuse spetsifikatsioon; 19 Mudel või toote tunnus: Undefined; 20 Tootja: Undefined; 21 Tooteinfo: Undefined; 22 Kasutus- ja hooldusjuhend: Undefined
AC_Pset_RenovationAndPhasing - Renovation Status: New

# IfcDoor: SU-A102 1 000×2 000, Siseuks * Door 22
In: 1 KORRUS
Type - OperationType: SINGLE_SWING_LEFT; ParameterTakesPrecedence: no; Sizeable: no
Type - Door Lining Properties - LiningDepth: 115 mm; LiningThickness: 40 mm; LiningOffset: 420 mm; CasingThickness: 50 mm; CasingDepth: 19 mm
Type - Door Panel Properties - Panel 1 - PanelDepth: 40 mm; PanelOperation: SWINGING; PanelWidth: 1; PanelPosition: MIDDLE
OverallHeight: 2000 mm; OverallWidth: 1000 mm; Classification: 1.9 IfcDoor (uks) (_RKAS BIM + ARCHICAD Classification); 52 Siseuksed (EHITUSKULUDE LIIGITAMINE EVS 885:2005)
Avatäited - 18 Viimistlus: RAL 9003; 01 Nimetus: Siseuks; 02 Materjal: Sile uks; 03 Tähistus: SU-A102 1 000×2 000; 04 Avamõõdu geomeetria: 1 000×2 000; 05 Asukoha info: Interior; 06 Soojusläbivus: -; 07 Helipidavus: 30 dB; 08 Veepidavus: -; 09 Õhuläbilaskvus: -; 10 Tulekindlus: nõudeid ei esitata; 11 Vastupanu tulekoormusele: -; 12 Klaaspakett: -; 13 Klaasingu erisused: -; 14 Päikesekiirgus tegur (g-väärtus): -; 15 Avanemine: Avanemine: "R" (L - vasak; R - parem); 16 Liigendatus: Lävepakk madal max 25mm, roostevaba; 17 Sulused, lukustus: lukustuse spetsifikatsioon; 19 Mudel või toote tunnus: Undefined; 20 Tootja: Undefined; 21 Tooteinfo: Undefined; 22 Kasutus- ja hooldusjuhend: Undefined
Pset_DoorCommon - ThermalTransmittance: 0; GlazingAreaFraction: 0; IsExternal: no
AC_Pset_RenovationAndPhasing - Renovation Status: New

# IfcDoor: SU-A103 800×2 100, Siseuks * Door 22
In: 1 KORRUS
Type - OperationType: SINGLE_SWING_LEFT; ParameterTakesPrecedence: no; Sizeable: no
Type - Door Lining Properties - LiningDepth: 115 mm; LiningThickness: 40 mm; LiningOffset: 115 mm; CasingThickness: 50 mm; CasingDepth: 19 mm
Type - Door Panel Properties - Panel 1 - PanelDepth: 40 mm; PanelOperation: SWINGING; PanelWidth: 1; PanelPosition: MIDDLE
Description: Teras; OverallHeight: 2100 mm; OverallWidth: 800 mm; Classification: 1.9 IfcDoor (uks) (_RKAS BIM + ARCHICAD Classification); 52 Siseuksed (EHITUSKULUDE LIIGITAMINE EVS 885:2005)
Pset_DoorCommon - FireRating: EI30; ThermalTransmittance: 0; GlazingAreaFraction: 0; IsExternal: no
Avatäited - 18 Viimistlus: RAL 9003; 01 Nimetus: Siseuks; 02 Materjal: Sile uks; 03 Tähistus: SU-A103 800×2 100; 04 Avamõõdu geomeetria: 800×2 100; 05 Asukoha info: Interior; 06 Soojusläbivus: -; 07 Helipidavus: 30 dB; 08 Veepidavus: -; 09 Õhuläbilaskvus: -; 10 Tulekindlus: EI 30; 11 Vastupanu tulekoormusele: -; 12 Klaaspakett: -; 13 Klaasingu erisused: -; 14 Päikesekiirgus tegur (g-väärtus): -; 15 Avanemine: Avanemine: "R" (L - vasak; R - parem); 16 Liigendatus: Lävepakk madal max 25mm, roostevaba; 17 Sulused, lukustus: lukustuse spetsifikatsioon; 19 Mudel või toote tunnus: Undefined; 20 Tootja: Undefined; 21 Tooteinfo: Undefined; 22 Kasutus- ja hooldusjuhend: Undefined
AC_Pset_RenovationAndPhasing - Renovation Status: New

# IfcDoor: SU-A104 700×2 000, Siseuks * Door 22
In: 1 KORRUS
Type - OperationType: SINGLE_SWING_LEFT; ParameterTakesPrecedence: no; Sizeable: no
Type - Door Lining Properties - LiningDepth: 115 mm; LiningThickness: 40 mm; LiningOffset: 420 mm; CasingThickness: 50 mm; CasingDepth: 19 mm
Type - Door Panel Properties - Panel 1 - PanelDepth: 40 mm; PanelOperation: SWINGING; PanelWidth: 1; PanelPosition: MIDDLE
OverallHeight: 2000 mm; OverallWidth: 700 mm; Classification: 1.9 IfcDoor (uks) (_RKAS BIM + ARCHICAD Classification); 52 Siseuksed (EHITUSKULUDE LIIGITAMINE EVS 885:2005)
Avatäited - 18 Viimistlus: RAL 9003; 01 Nimetus: Siseuks; 02 Materjal: Sile uks; 03 Tähistus: SU-A104 700×2 000; 04 Avamõõdu geomeetria: 700×2 000; 05 Asukoha info: Interior; 06 Soojusläbivus: -; 07 Helipidavus: 30 dB; 08 Veepidavus: -; 09 Õhuläbilaskvus: -; 10 Tulekindlus: nõudeid ei esitata; 11 Vastupanu tulekoormusele: -; 12 Klaaspakett: -; 13 Klaasingu erisused: -; 14 Päikesekiirgus tegur (g-väärtus): -; 15 Avanemine: Avanemine: "R" (L - vasak; R - parem); 16 Liigendatus: Tuulutatav lävepakk; 17 Sulused, lukustus: lukustuse spetsifikatsioon; 19 Mudel või toote tunnus: Undefined; 20 Tootja: Undefined; 21 Tooteinfo: Undefined; 22 Kasutus- ja hooldusjuhend: Undefined
Pset_DoorCommon - ThermalTransmittance: 0; GlazingAreaFraction: 0; IsExternal: no
AC_Pset_RenovationAndPhasing - Renovation Status: New

# IfcDoor: SU-A104A 700×2 100, Siseuks * Door 22
In: 1 KORRUS
Type - OperationType: SINGLE_SWING_LEFT; ParameterTakesPrecedence: no; Sizeable: no
Type - Door Lining Properties - LiningDepth: 115 mm; LiningThickness: 40 mm; LiningOffset: 100 mm; CasingThickness: 50 mm; CasingDepth: 19 mm
Type - Door Panel Properties - Panel 1 - PanelDepth: 40 mm; PanelOperation: SWINGING; PanelWidth: 1; PanelPosition: MIDDLE
OverallHeight: 2100 mm; OverallWidth: 700 mm; Classification: 1.9 IfcDoor (uks) (_RKAS BIM + ARCHICAD Classification); 52 Siseuksed (EHITUSKULUDE LIIGITAMINE EVS 885:2005)
Avatäited - 18 Viimistlus: RAL 9003; 01 Nimetus: Siseuks; 02 Materjal: Sile uks; 03 Tähistus: SU-A104A 700×2 100; 04 Avamõõdu geomeetria: 700×2 100; 05 Asukoha info: Interior; 06 Soojusläbivus: -; 07 Helipidavus: 30 dB; 08 Veepidavus: -; 09 Õhuläbilaskvus: -; 10 Tulekindlus: nõudeid ei esitata; 11 Vastupanu tulekoormusele: -; 12 Klaaspakett: -; 13 Klaasingu erisused: -; 14 Päikesekiirgus tegur (g-väärtus): -; 15 Avanemine: Avanemine: "R" (L - vasak; R - parem); 16 Liigendatus: Tuulutatav lävepakk; 17 Sulused, lukustus: lukustuse spetsifikatsioon; 19 Mudel või toote tunnus: Undefined; 20 Tootja: Undefined; 21 Tooteinfo: Undefined; 22 Kasutus- ja hooldusjuhend: Undefined
Pset_DoorCommon - ThermalTransmittance: 0; GlazingAreaFraction: 0; IsExternal: no
AC_Pset_RenovationAndPhasing - Renovation Status: New

# IfcDoor: SU-A105 1 000×2 000, Siseuks * Door 22
In: 1 KORRUS
Type - OperationType: SINGLE_SWING_RIGHT; ParameterTakesPrecedence: no; Sizeable: no
Type - Door Lining Properties - LiningDepth: 115 mm; LiningThickness: 40 mm; LiningOffset: 420 mm; CasingThickness: 50 mm; CasingDepth: 19 mm
Type - Door Panel Properties - Panel 1 - PanelDepth: 40 mm; PanelOperation: SWINGING; PanelWidth: 1; PanelPosition: MIDDLE
OverallHeight: 2000 mm; OverallWidth: 1000 mm; Classification: 1.9 IfcDoor (uks) (_RKAS BIM + ARCHICAD Classification); 52 Siseuksed (EHITUSKULUDE LIIGITAMINE EVS 885:2005)
Avatäited - 18 Viimistlus: RAL 9003; 01 Nimetus: Siseuks; 02 Materjal: Sile uks; 03 Tähistus: SU-A105 1 000×2 000; 04 Avamõõdu geomeetria: 1 000×2 000; 05 Asukoha info: Interior; 06 Soojusläbivus: -; 07 Helipidavus: 30 dB; 08 Veepidavus: -; 09 Õhuläbilaskvus: -; 10 Tulekindlus: nõudeid ei esitata; 11 Vastupanu tulekoormusele: -; 12 Klaaspakett: -; 13 Klaasingu erisused: -; 14 Päikesekiirgus tegur (g-väärtus): -; 15 Avanemine: Avanemine: "L" (L - vasak; R - parem); 16 Liigendatus: Tuulutatav lävepakk; 17 Sulused, lukustus: lukustuse spetsifikatsioon; 19 Mudel või toote tunnus: Undefined; 20 Tootja: Undefined; 21 Tooteinfo: Undefined; 22 Kasutus- ja hooldusjuhend: Undefined
Pset_DoorCommon - ThermalTransmittance: 0; GlazingAreaFraction: 0; IsExternal: no
AC_Pset_RenovationAndPhasing - Renovation Status: New

# IfcDoor: SU-A106 900×2 000, Siseuks * Door 22
In: 1 KORRUS
Type - OperationType: SINGLE_SWING_RIGHT; ParameterTakesPrecedence: no; Sizeable: no
Type - Door Lining Properties - LiningDepth: 115 mm; LiningThickness: 40 mm; LiningOffset: 420 mm; CasingThickness: 50 mm; CasingDepth: 19 mm
Type - Door Panel Properties - Panel 1 - PanelDepth: 40 mm; PanelOperation: SWINGING; PanelWidth: 1; PanelPosition: MIDDLE
OverallHeight: 2000 mm; OverallWidth: 900 mm; Classification: 1.9 IfcDoor (uks) (_RKAS BIM + ARCHICAD Classification); 52 Siseuksed (EHITUSKULUDE LIIGITAMINE EVS 885:2005)
Avatäited - 18 Viimistlus: RAL 9003; 01 Nimetus: Siseuks; 02 Materjal: Sile uks; 03 Tähistus: SU-A106 900×2 000; 04 Avamõõdu geomeetria: 900×2 000; 05 Asukoha info: Interior; 06 Soojusläbivus: -; 07 Helipidavus: 30 dB; 08 Veepidavus: -; 09 Õhuläbilaskvus: -; 10 Tulekindlus: nõudeid ei esitata; 11 Vastupanu tulekoormusele: -; 12 Klaaspakett: -; 13 Klaasingu erisused: -; 14 Päikesekiirgus tegur (g-väärtus): -; 15 Avanemine: Avanemine: "L" (L - vasak; R - parem); 16 Liigendatus: Lävepakk madal max 25mm, roostevaba; 17 Sulused, lukustus: lukustuse spetsifikatsioon; 19 Mudel või toote tunnus: Undefined; 20 Tootja: Undefined; 21 Tooteinfo: Undefined; 22 Kasutus- ja hooldusjuhend: Undefined
Pset_DoorCommon - ThermalTransmittance: 0; GlazingAreaFraction: 0; IsExternal: no
AC_Pset_RenovationAndPhasing - Renovation Status: New

# IfcDoor: SU-A107 900×2 000, Siseuks * Door 22
In: 1 KORRUS
Type - OperationType: SINGLE_SWING_LEFT; ParameterTakesPrecedence: no; Sizeable: no
Type - Door Lining Properties - LiningDepth: 115 mm; LiningThickness: 40 mm; LiningOffset: 150 mm; CasingThickness: 50 mm; CasingDepth: 19 mm
Type - Door Panel Properties - Panel 1 - PanelDepth: 40 mm; PanelOperation: SWINGING; PanelWidth: 1; PanelPosition: MIDDLE
OverallHeight: 2000 mm; OverallWidth: 900 mm; Classification: 1.9 IfcDoor (uks) (_RKAS BIM + ARCHICAD Classification); 52 Siseuksed (EHITUSKULUDE LIIGITAMINE EVS 885:2005)
Avatäited - 18 Viimistlus: RAL 9003; 01 Nimetus: Siseuks; 02 Materjal: Sile uks; 03 Tähistus: SU-A107 900×2 000; 04 Avamõõdu geomeetria: 900×2 000; 05 Asukoha info: Interior; 06 Soojusläbivus: -; 07 Helipidavus: 30 dB; 08 Veepidavus: -; 09 Õhuläbilaskvus: -; 10 Tulekindlus: nõudeid ei esitata; 11 Vastupanu tulekoormusele: -; 12 Klaaspakett: -; 13 Klaasingu erisused: -; 14 Päikesekiirgus tegur (g-väärtus): -; 15 Avanemine: Avanemine: "R" (L - vasak; R - parem); 16 Liigendatus: Lävepakk madal max 25mm, roostevaba; 17 Sulused, lukustus: lukustuse spetsifikatsioon; 19 Mudel või toote tunnus: Undefined; 20 Tootja: Undefined; 21 Tooteinfo: Undefined; 22 Kasutus- ja hooldusjuhend: Undefined
Pset_DoorCommon - ThermalTransmittance: 0; GlazingAreaFraction: 0; IsExternal: no
AC_Pset_RenovationAndPhasing - Renovation Status: New

# IfcDoor: SU-A108 900×2 000, Siseuks * Door 22
In: 1 KORRUS
Type - OperationType: SINGLE_SWING_LEFT; ParameterTakesPrecedence: no; Sizeable: no
Type - Door Lining Properties - LiningDepth: 115 mm; LiningThickness: 40 mm; LiningOffset: 420 mm; CasingThickness: 50 mm; CasingDepth: 19 mm
Type - Door Panel Properties - Panel 1 - PanelDepth: 40 mm; PanelOperation: SWINGING; PanelWidth: 1; PanelPosition: MIDDLE
OverallHeight: 2000 mm; OverallWidth: 900 mm; Classification: 1.9 IfcDoor (uks) (_RKAS BIM + ARCHICAD Classification); 52 Siseuksed (EHITUSKULUDE LIIGITAMINE EVS 885:2005)
Avatäited - 18 Viimistlus: RAL 9003; 01 Nimetus: Siseuks; 02 Materjal: Sile uks; 03 Tähistus: SU-A108 900×2 000; 04 Avamõõdu geomeetria: 900×2 000; 05 Asukoha info: Interior; 06 Soojusläbivus: -; 07 Helipidavus: 30 dB; 08 Veepidavus: -; 09 Õhuläbilaskvus: -; 10 Tulekindlus: nõudeid ei esitata; 11 Vastupanu tulekoormusele: -; 12 Klaaspakett: -; 13 Klaasingu erisused: -; 14 Päikesekiirgus tegur (g-väärtus): -; 15 Avanemine: Avanemine: "R" (L - vasak; R - parem); 16 Liigendatus: Tuulutatav lävepakk; 17 Sulused, lukustus: lukustuse spetsifikatsioon; 19 Mudel või toote tunnus: Undefined; 20 Tootja: Undefined; 21 Tooteinfo: Undefined; 22 Kasutus- ja hooldusjuhend: Undefined
Pset_DoorCommon - ThermalTransmittance: 0; GlazingAreaFraction: 0; IsExternal: no
AC_Pset_RenovationAndPhasing - Renovation Status: New

# IfcDoor: SU-A108A 900×2 000, Siseuks * Door 22
In: 1 KORRUS
Type - OperationType: SINGLE_SWING_LEFT; ParameterTakesPrecedence: no; Sizeable: no
Type - Door Lining Properties - LiningDepth: 115 mm; LiningThickness: 40 mm; LiningOffset: -135 mm; CasingThickness: 50 mm; CasingDepth: 19 mm
Type - Door Panel Properties - Panel 1 - PanelDepth: 40 mm; PanelOperation: SWINGING; PanelWidth: 1; PanelPosition: MIDDLE
Description: Teras; OverallHeight: 2000 mm; OverallWidth: 900 mm; Classification: 1.9 IfcDoor (uks) (_RKAS BIM + ARCHICAD Classification); 52 Siseuksed (EHITUSKULUDE LIIGITAMINE EVS 885:2005)
Pset_DoorCommon - FireRating: EI30; ThermalTransmittance: 0; GlazingAreaFraction: 0; IsExternal: no
Avatäited - 18 Viimistlus: RAL 9003; 01 Nimetus: Siseuks; 02 Materjal: Sile uks; 03 Tähistus: SU-A108A 900×2 000; 04 Avamõõdu geomeetria: 900×2 000; 05 Asukoha info: Interior; 06 Soojusläbivus: -; 07 Helipidavus: 30 dB; 08 Veepidavus: niiskuskindel uks; 09 Õhuläbilaskvus: -; 10 Tulekindlus: EI 30; 11 Vastupanu tulekoormusele: -; 12 Klaaspakett: -; 13 Klaasingu erisused: -; 14 Päikesekiirgus tegur (g-väärtus): -; 15 Avanemine: Avanemine: "R" (L - vasak; R - parem); 16 Liigendatus: Tuulutatav lävepakk; 17 Sulused, lukustus: lukustuse spetsifikatsioon; 19 Mudel või toote tunnus: Undefined; 20 Tootja: Undefined; 21 Tooteinfo: Undefined; 22 Kasutus- ja hooldusjuhend: Undefined
AC_Pset_RenovationAndPhasing - Renovation Status: New

# IfcDoor: SU-A108B 800×2 000, Sauna uks * Door 22
In: 1 KORRUS
Type - OperationType: SINGLE_SWING_RIGHT; ParameterTakesPrecedence: no; Sizeable: no
Type - Door Lining Properties - LiningDepth: 115 mm; LiningThickness: 40 mm; LiningOffset: 250 mm; CasingThickness: 50 mm; CasingDepth: 19 mm
Type - Door Panel Properties - Panel 1 - PanelDepth: 40 mm; PanelOperation: SWINGING; PanelWidth: 1; PanelPosition: MIDDLE
OverallHeight: 2000 mm; OverallWidth: 800 mm; Classification: 1.9 IfcDoor (uks) (_RKAS BIM + ARCHICAD Classification); 52 Siseuksed (EHITUSKULUDE LIIGITAMINE EVS 885:2005)
Avatäited - 18 Viimistlus: RAL 9003; 01 Nimetus: Sauna uks; 02 Materjal: Liimpuit ja 8mm karastatud klaas; 03 Tähistus: SU-A108B 800×2 000; 04 Avamõõdu geomeetria: 800×2 000; 05 Asukoha info: Interior; 06 Soojusläbivus: -; 07 Helipidavus: 30 dB; 08 Veepidavus: -; 09 Õhuläbilaskvus: -; 10 Tulekindlus: nõudeid ei esitata; 11 Vastupanu tulekoormusele: -; 12 Klaaspakett: 8mm karastatud klaas; 13 Klaasingu erisused: -; 14 Päikesekiirgus tegur (g-väärtus): -; 15 Avanemine: Avanemine: "L" (L - vasak; R - parem); 16 Liigendatus: Tuulutatav lävepakk, vahe 10-110 mm; 17 Sulused, lukustus: lukustuse spetsifikatsioon; 19 Mudel või toote tunnus: Undefined; 20 Tootja: Undefined; 21 Tooteinfo: Undefined; 22 Kasutus- ja hooldusjuhend: Undefined
Pset_DoorCommon - ThermalTransmittance: 0; GlazingAreaFraction: 0; IsExternal: no
AC_Pset_RenovationAndPhasing - Renovation Status: New

# IfcDoor: SU-A109 900×2 000, Siseuks * Door 22
In: 1 KORRUS
Type - OperationType: SINGLE_SWING_LEFT; ParameterTakesPrecedence: no; Sizeable: no
Type - Door Lining Properties - LiningDepth: 115 mm; LiningThickness: 40 mm; LiningOffset: 150 mm; CasingThickness: 50 mm; CasingDepth: 19 mm
Type - Door Panel Properties - Panel 1 - PanelDepth: 40 mm; PanelOperation: SWINGING; PanelWidth: 1; PanelPosition: MIDDLE
OverallHeight: 2000 mm; OverallWidth: 900 mm; Classification: 1.9 IfcDoor (uks) (_RKAS BIM + ARCHICAD Classification); 52 Siseuksed (EHITUSKULUDE LIIGITAMINE EVS 885:2005)
Avatäited - 18 Viimistlus: RAL 9003; 01 Nimetus: Siseuks; 02 Materjal: Sile uks; 03 Tähistus: SU-A109 900×2 000; 04 Avamõõdu geomeetria: 900×2 000; 05 Asukoha info: Interior; 06 Soojusläbivus: -; 07 Helipidavus: 30 dB; 08 Veepidavus: -; 09 Õhuläbilaskvus: -; 10 Tulekindlus: nõudeid ei esitata; 11 Vastupanu tulekoormusele: -; 12 Klaaspakett: -; 13 Klaasingu erisused: -; 14 Päikesekiirgus tegur (g-väärtus): -; 15 Avanemine: Avanemine: "R" (L - vasak; R - parem); 16 Liigendatus: Lävepakk madal max 25mm, roostevaba; 17 Sulused, lukustus: lukustuse spetsifikatsioon; 19 Mudel või toote tunnus: Undefined; 20 Tootja: Undefined; 21 Tooteinfo: Undefined; 22 Kasutus- ja hooldusjuhend: Undefined
Pset_DoorCommon - ThermalTransmittance: 0; GlazingAreaFraction: 0; IsExternal: no
AC_Pset_RenovationAndPhasing - Renovation Status: New

# IfcDoor: SU-A110 900×2 000, Siseuks * Door 22
In: 1 KORRUS
Type - OperationType: SINGLE_SWING_LEFT; ParameterTakesPrecedence: no; Sizeable: no
Type - Door Lining Properties - LiningDepth: 115 mm; LiningThickness: 40 mm; LiningOffset: 150 mm; CasingThickness: 50 mm; CasingDepth: 19 mm
Type - Door Panel Properties - Panel 1 - PanelDepth: 40 mm; PanelOperation: SWINGING; PanelWidth: 1; PanelPosition: MIDDLE
OverallHeight: 2000 mm; OverallWidth: 900 mm; Classification: 1.9 IfcDoor (uks) (_RKAS BIM + ARCHICAD Classification); 52 Siseuksed (EHITUSKULUDE LIIGITAMINE EVS 885:2005)
Avatäited - 18 Viimistlus: RAL 9003; 01 Nimetus: Siseuks; 02 Materjal: Sile uks; 03 Tähistus: SU-A110 900×2 000; 04 Avamõõdu geomeetria: 900×2 000; 05 Asukoha info: Interior; 06 Soojusläbivus: -; 07 Helipidavus: 30 dB; 08 Veepidavus: -; 09 Õhuläbilaskvus: -; 10 Tulekindlus: nõudeid ei esitata; 11 Vastupanu tulekoormusele: -; 12 Klaaspakett: -; 13 Klaasingu erisused: -; 14 Päikesekiirgus tegur (g-väärtus): -; 15 Avanemine: Avanemine: "R" (L - vasak; R - parem); 16 Liigendatus: Lävepakk madal max 25mm, roostevaba; 17 Sulused, lukustus: lukustuse spetsifikatsioon; 19 Mudel või toote tunnus: Undefined; 20 Tootja: Undefined; 21 Tooteinfo: Undefined; 22 Kasutus- ja hooldusjuhend: Undefined
Pset_DoorCommon - ThermalTransmittance: 0; GlazingAreaFraction: 0; IsExternal: no
AC_Pset_RenovationAndPhasing - Renovation Status: New

# IfcDoor: SU-A111 900×2 000, Siseuks * Door 22
In: 1 KORRUS
Type - OperationType: SINGLE_SWING_LEFT; ParameterTakesPrecedence: no; Sizeable: no
Type - Door Lining Properties - LiningDepth: 115 mm; LiningThickness: 40 mm; LiningOffset: 150 mm; CasingThickness: 50 mm; CasingDepth: 19 mm
Type - Door Panel Properties - Panel 1 - PanelDepth: 40 mm; PanelOperation: SWINGING; PanelWidth: 1; PanelPosition: MIDDLE
Description: Teras; OverallHeight: 2000 mm; OverallWidth: 900 mm; Classification: 1.9 IfcDoor (uks) (_RKAS BIM + ARCHICAD Classification); 52 Siseuksed (EHITUSKULUDE LIIGITAMINE EVS 885:2005)
Pset_DoorCommon - FireRating: EI30; ThermalTransmittance: 0; GlazingAreaFraction: 0; IsExternal: no
Avatäited - 18 Viimistlus: RAL 9003; 01 Nimetus: Siseuks; 02 Materjal: Sile uks; 03 Tähistus: SU-A111 900×2 000; 04 Avamõõdu geomeetria: 900×2 000; 05 Asukoha info: Interior; 06 Soojusläbivus: -; 07 Helipidavus: 30 dB; 08 Veepidavus: -; 09 Õhuläbilaskvus: -; 10 Tulekindlus: EI 30; 11 Vastupanu tulekoormusele: -; 12 Klaaspakett: -; 13 Klaasingu erisused: -; 14 Päikesekiirgus tegur (g-väärtus): -; 15 Avanemine: Avanemine: "R" (L - vasak; R - parem); 16 Liigendatus: Lävepakk madal max 25mm, roostevaba; 17 Sulused, lukustus: lukustuse spetsifikatsioon; 19 Mudel või toote tunnus: Undefined; 20 Tootja: Undefined; 21 Tooteinfo: Undefined; 22 Kasutus- ja hooldusjuhend: Undefined
AC_Pset_RenovationAndPhasing - Renovation Status: New

# IfcDoor: SU-A112 900×2 000, Siseuks * Door 22
In: 1 KORRUS
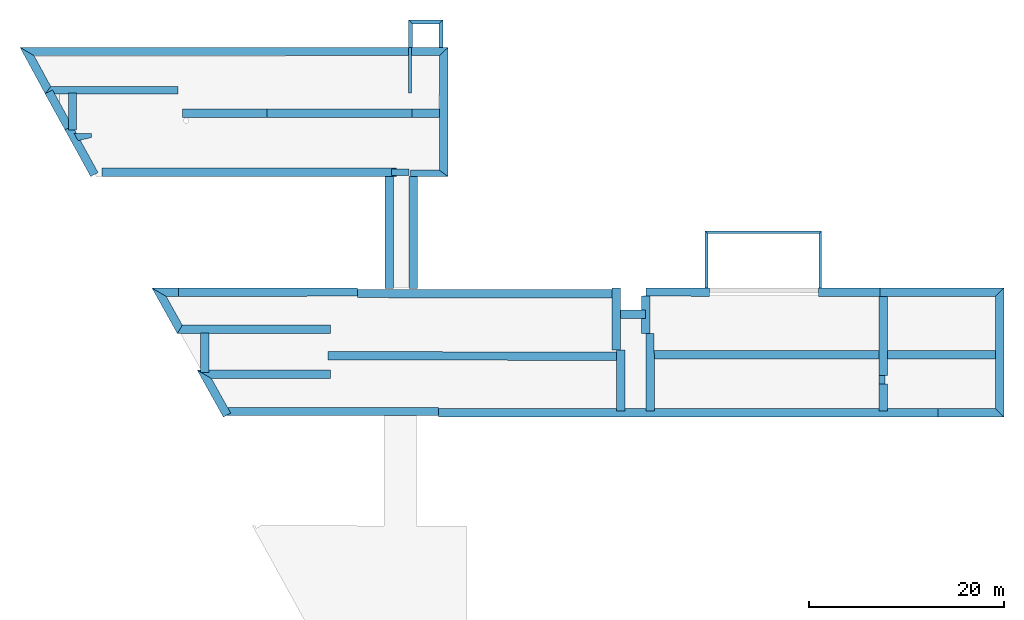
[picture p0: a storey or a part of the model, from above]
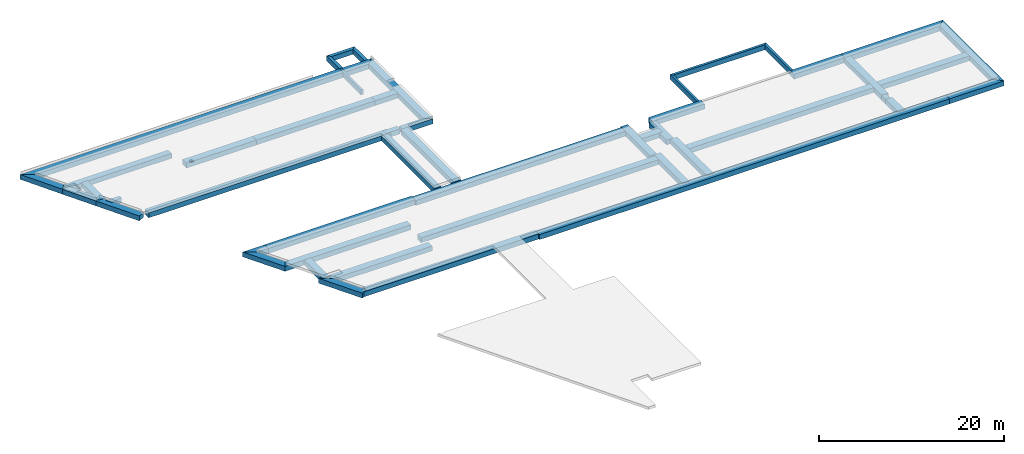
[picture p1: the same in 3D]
Properties of the parts of a building model (IFC2X3), part 6 of 14

# IfcDoor: SU-A112 900×2 000, Siseuks * Door 22
Type - OperationType: SINGLE_SWING_LEFT; ParameterTakesPrecedence: no; Sizeable: no
Type - Door Lining Properties - LiningDepth: 115 mm; LiningThickness: 40 mm; LiningOffset: 420 mm; CasingThickness: 50 mm; CasingDepth: 19 mm
Type - Door Panel Properties - Panel 1 - PanelDepth: 40 mm; PanelOperation: SWINGING; PanelWidth: 1; PanelPosition: MIDDLE
Description: Teras; OverallHeight: 2000 mm; OverallWidth: 900 mm; Classification: 1.9 IfcDoor (uks) (_RKAS BIM + ARCHICAD Classification); 52 Siseuksed (EHITUSKULUDE LIIGITAMINE EVS 885:2005)
Pset_DoorCommon - FireRating: EI30; ThermalTransmittance: 0; GlazingAreaFraction: 0; IsExternal: no
Avatäited - 18 Viimistlus: RAL 9003; 01 Nimetus: Siseuks; 02 Materjal: Sile uks; 03 Tähistus: SU-A112 900×2 000; 04 Avamõõdu geomeetria: 900×2 000; 05 Asukoha info: Interior; 06 Soojusläbivus: -; 07 Helipidavus: 30 dB; 08 Veepidavus: -; 09 Õhuläbilaskvus: -; 10 Tulekindlus: EI 30; 11 Vastupanu tulekoormusele: -; 12 Klaaspakett: -; 13 Klaasingu erisused: -; 14 Päikesekiirgus tegur (g-väärtus): -; 15 Avanemine: Avanemine: "R" (L - vasak; R - parem); 16 Liigendatus: Lävepakk madal max 25mm, roostevaba; 17 Sulused, lukustus: lukustuse spetsifikatsioon; 19 Mudel või toote tunnus: Undefined; 20 Tootja: Undefined; 21 Tooteinfo: Undefined; 22 Kasutus- ja hooldusjuhend: Undefined
AC_Pset_RenovationAndPhasing - Renovation Status: New

# IfcDoor: SU-A113 900×2 000, Siseuks * Door 22
In: 1 KORRUS
Type - OperationType: SINGLE_SWING_LEFT; ParameterTakesPrecedence: no; Sizeable: no
Type - Door Lining Properties - LiningDepth: 115 mm; LiningThickness: 40 mm; LiningOffset: 420 mm; CasingThickness: 50 mm; CasingDepth: 19 mm
Type - Door Panel Properties - Panel 1 - PanelDepth: 40 mm; PanelOperation: SWINGING; PanelWidth: 1; PanelPosition: MIDDLE
OverallHeight: 2000 mm; OverallWidth: 900 mm; Classification: 1.9 IfcDoor (uks) (_RKAS BIM + ARCHICAD Classification); 52 Siseuksed (EHITUSKULUDE LIIGITAMINE EVS 885:2005)
Avatäited - 18 Viimistlus: RAL 9003; 01 Nimetus: Siseuks; 02 Materjal: Sile uks; 03 Tähistus: SU-A113 900×2 000; 04 Avamõõdu geomeetria: 900×2 000; 05 Asukoha info: Interior; 06 Soojusläbivus: -; 07 Helipidavus: 30 dB; 08 Veepidavus: -; 09 Õhuläbilaskvus: -; 10 Tulekindlus: nõudeid ei esitata; 11 Vastupanu tulekoormusele: -; 12 Klaaspakett: -; 13 Klaasingu erisused: -; 14 Päikesekiirgus tegur (g-väärtus): -; 15 Avanemine: Avanemine: "R" (L - vasak; R - parem); 16 Liigendatus: Lävepakk madal max 25mm, roostevaba; 17 Sulused, lukustus: lukustuse spetsifikatsioon; 19 Mudel või toote tunnus: Undefined; 20 Tootja: Undefined; 21 Tooteinfo: Undefined; 22 Kasutus- ja hooldusjuhend: Undefined
Pset_DoorCommon - ThermalTransmittance: 0; GlazingAreaFraction: 0; IsExternal: no
AC_Pset_RenovationAndPhasing - Renovation Status: New

# IfcDoor: SU-A115 900×2 000, Siseuks * Door 22
In: 1 KORRUS
Type - OperationType: SINGLE_SWING_RIGHT; ParameterTakesPrecedence: no; Sizeable: no
Type - Door Lining Properties - LiningDepth: 115 mm; LiningThickness: 40 mm; LiningOffset: 395 mm; CasingThickness: 50 mm; CasingDepth: 19 mm
Type - Door Panel Properties - Panel 1 - PanelDepth: 40 mm; PanelOperation: SWINGING; PanelWidth: 1; PanelPosition: MIDDLE
Description: Teras; OverallHeight: 2000 mm; OverallWidth: 900 mm; Classification: 1.9 IfcDoor (uks) (_RKAS BIM + ARCHICAD Classification); 52 Siseuksed (EHITUSKULUDE LIIGITAMINE EVS 885:2005)
Pset_DoorCommon - FireRating: EI30; ThermalTransmittance: 0; GlazingAreaFraction: 0; IsExternal: no
Avatäited - 18 Viimistlus: RAL 9003; 01 Nimetus: Siseuks; 02 Materjal: Sile uks; 03 Tähistus: SU-A115 900×2 000; 04 Avamõõdu geomeetria: 900×2 000; 05 Asukoha info: Interior; 06 Soojusläbivus: -; 07 Helipidavus: 30 dB; 08 Veepidavus: -; 09 Õhuläbilaskvus: -; 10 Tulekindlus: EI 30; 11 Vastupanu tulekoormusele: -; 12 Klaaspakett: -; 13 Klaasingu erisused: -; 14 Päikesekiirgus tegur (g-väärtus): -; 15 Avanemine: Avanemine: "L" (L - vasak; R - parem); 16 Liigendatus: Lävepakk madal max 25mm, roostevaba; 17 Sulused, lukustus: lukustuse spetsifikatsioon; 19 Mudel või toote tunnus: Undefined; 20 Tootja: Undefined; 21 Tooteinfo: Undefined; 22 Kasutus- ja hooldusjuhend: Undefined
AC_Pset_RenovationAndPhasing - Renovation Status: New

# IfcDoor: SU-A116 900×2 100, Siseuks * Door 22
In: 1 KORRUS
Type - OperationType: SINGLE_SWING_LEFT; ParameterTakesPrecedence: no; Sizeable: no
Type - Door Lining Properties - LiningDepth: 115 mm; LiningThickness: 40 mm; LiningOffset: 0 mm; CasingThickness: 50 mm; CasingDepth: 19 mm
Type - Door Panel Properties - Panel 1 - PanelDepth: 40 mm; PanelOperation: SWINGING; PanelWidth: 1; PanelPosition: MIDDLE
Description: Teras; OverallHeight: 2100 mm; OverallWidth: 900 mm; Classification: 1.9 IfcDoor (uks) (_RKAS BIM + ARCHICAD Classification); 52 Siseuksed (EHITUSKULUDE LIIGITAMINE EVS 885:2005)
Pset_DoorCommon - FireRating: EI30; ThermalTransmittance: 0; GlazingAreaFraction: 0; IsExternal: no
Avatäited - 18 Viimistlus: RAL 9003; 01 Nimetus: Siseuks; 02 Materjal: Sile uks; 03 Tähistus: SU-A116 900×2 100; 04 Avamõõdu geomeetria: 900×2 100; 05 Asukoha info: Interior; 06 Soojusläbivus: -; 07 Helipidavus: 30 dB; 08 Veepidavus: -; 09 Õhuläbilaskvus: -; 10 Tulekindlus: EI 30; 11 Vastupanu tulekoormusele: -; 12 Klaaspakett: -; 13 Klaasingu erisused: -; 14 Päikesekiirgus tegur (g-väärtus): -; 15 Avanemine: Avanemine: "R" (L - vasak; R - parem); 16 Liigendatus: Lävepakk madal max 25mm, roostevaba; 17 Sulused, lukustus: lukustuse spetsifikatsioon; 19 Mudel või toote tunnus: Undefined; 20 Tootja: Undefined; 21 Tooteinfo: Undefined; 22 Kasutus- ja hooldusjuhend: Undefined
AC_Pset_RenovationAndPhasing - Renovation Status: New

# IfcDoor: SU-A118 1 500×2 000, Siseuks * Double Door 22
In: 1 KORRUS
Type - OperationType: DOUBLE_DOOR_SINGLE_SWING; ParameterTakesPrecedence: no; Sizeable: no
Type - Door Lining Properties - LiningDepth: 115 mm; LiningThickness: 40 mm; LiningOffset: 150 mm; CasingThickness: 50 mm; CasingDepth: 19 mm
Type - Door Panel Properties - Panel 1 - PanelDepth: 40 mm; PanelOperation: SWINGING; PanelWidth: 0.508451; PanelPosition: LEFT
Type - Door Panel Properties - Panel 2 - PanelDepth: 40 mm; PanelOperation: SWINGING; PanelWidth: 0.508451; PanelPosition: RIGHT
OverallHeight: 2000 mm; OverallWidth: 1500 mm; Classification: 1.9 IfcDoor (uks) (_RKAS BIM + ARCHICAD Classification); 52 Siseuksed (EHITUSKULUDE LIIGITAMINE EVS 885:2005)
Avatäited - 18 Viimistlus: RAL 9003; 01 Nimetus: Siseuks; 02 Materjal: Sile uks; 03 Tähistus: SU-A118 1 500×2 000; 04 Avamõõdu geomeetria: 1 500×2 000; 05 Asukoha info: Interior; 06 Soojusläbivus: -; 07 Helipidavus: 30 dB; 08 Veepidavus: -; 09 Õhuläbilaskvus: -; 10 Tulekindlus: nõudeid ei esitata; 11 Vastupanu tulekoormusele: -; 12 Klaaspakett: -; 13 Klaasingu erisused: -; 14 Päikesekiirgus tegur (g-väärtus): -; 15 Avanemine: Avanemine: "L" (L - vasak; R - parem); 16 Liigendatus: Lävepakk madal max 25mm, roostevaba; 17 Sulused, lukustus: lukustuse spetsifikatsioon; 19 Mudel või toote tunnus: Undefined; 20 Tootja: Undefined; 21 Tooteinfo: Undefined; 22 Kasutus- ja hooldusjuhend: Undefined
Pset_DoorCommon - ThermalTransmittance: 0; GlazingAreaFraction: 0; IsExternal: no
AC_Pset_RenovationAndPhasing - Renovation Status: New

# IfcDoor: SU-A200 950×2 300, Siseuks * Door 22
In: 2 KORRUS
Type - OperationType: SINGLE_SWING_LEFT; ParameterTakesPrecedence: no; Sizeable: no
Type - Door Lining Properties - LiningDepth: 115 mm; LiningThickness: 40 mm; LiningOffset: 0 mm; CasingThickness: 50 mm; CasingDepth: 19 mm
Type - Door Panel Properties - Panel 1 - PanelDepth: 40 mm; PanelOperation: SWINGING; PanelWidth: 1; PanelPosition: MIDDLE
OverallHeight: 2300 mm; OverallWidth: 950 mm; Classification: 1.9 IfcDoor (uks) (_RKAS BIM + ARCHICAD Classification); 52 Siseuksed (EHITUSKULUDE LIIGITAMINE EVS 885:2005)
Avatäited - 18 Viimistlus: RAL 9003; 01 Nimetus: Siseuks; 02 Materjal: Sile uks; 03 Tähistus: SU-A200 950×2 300; 04 Avamõõdu geomeetria: 950×2 300; 05 Asukoha info: Interior; 06 Soojusläbivus: -; 07 Helipidavus: 30 dB; 08 Veepidavus: -; 09 Õhuläbilaskvus: -; 10 Tulekindlus: nõudeid ei esitata; 11 Vastupanu tulekoormusele: -; 12 Klaaspakett: -; 13 Klaasingu erisused: -; 14 Päikesekiirgus tegur (g-väärtus): -; 15 Avanemine: Avanemine: "R" (L - vasak; R - parem); 16 Liigendatus: Lävepakk madal max 25mm, roostevaba; 17 Sulused, lukustus: vt lukustuse spetsifikatsioon; 19 Mudel või toote tunnus: Undefined; 20 Tootja: Undefined; 21 Tooteinfo: Undefined; 22 Kasutus- ja hooldusjuhend: Undefined
Pset_DoorCommon - ThermalTransmittance: 0; GlazingAreaFraction: 0; IsExternal: no
AC_Pset_RenovationAndPhasing - Renovation Status: New

# IfcDoor: SU-A201 1 000×2 100, Siseuks * Door 22
In: 2 KORRUS
Type - OperationType: SINGLE_SWING_LEFT; ParameterTakesPrecedence: no; Sizeable: no
Type - Door Lining Properties - LiningDepth: 115 mm; LiningThickness: 40 mm; LiningOffset: 560 mm; CasingThickness: 50 mm; CasingDepth: 19 mm
Type - Door Panel Properties - Panel 1 - PanelDepth: 40 mm; PanelOperation: SWINGING; PanelWidth: 1; PanelPosition: MIDDLE
OverallHeight: 2100 mm; OverallWidth: 1000 mm; Classification: 1.9 IfcDoor (uks) (_RKAS BIM + ARCHICAD Classification); 52 Siseuksed (EHITUSKULUDE LIIGITAMINE EVS 885:2005)
Avatäited - 18 Viimistlus: RAL 9003; 01 Nimetus: Siseuks; 02 Materjal: Sile uks; 03 Tähistus: SU-A201 1 000×2 100; 04 Avamõõdu geomeetria: 1 000×2 100; 05 Asukoha info: Interior; 06 Soojusläbivus: -; 07 Helipidavus: 30 dB; 08 Veepidavus: -; 09 Õhuläbilaskvus: -; 10 Tulekindlus: nõudeid ei esitata; 11 Vastupanu tulekoormusele: -; 12 Klaaspakett: -; 13 Klaasingu erisused: -; 14 Päikesekiirgus tegur (g-väärtus): -; 15 Avanemine: Avanemine: "R" (L - vasak; R - parem); 16 Liigendatus: Lävepakk madal max 25mm, roostevaba; 17 Sulused, lukustus: vt lukustuse spetsifikatsioon; 19 Mudel või toote tunnus: Undefined; 20 Tootja: Undefined; 21 Tooteinfo: Undefined; 22 Kasutus- ja hooldusjuhend: Undefined
Pset_DoorCommon - ThermalTransmittance: 0; GlazingAreaFraction: 0; IsExternal: no
AC_Pset_RenovationAndPhasing - Renovation Status: New

# IfcDoor: SU-A202 1 000×2 100, Siseuks * Door 22
In: 2 KORRUS
Type - OperationType: SINGLE_SWING_LEFT; ParameterTakesPrecedence: no; Sizeable: no
Type - Door Lining Properties - LiningDepth: 115 mm; LiningThickness: 40 mm; LiningOffset: 560 mm; CasingThickness: 50 mm; CasingDepth: 19 mm
Type - Door Panel Properties - Panel 1 - PanelDepth: 40 mm; PanelOperation: SWINGING; PanelWidth: 1; PanelPosition: MIDDLE
OverallHeight: 2100 mm; OverallWidth: 1000 mm; Classification: 1.9 IfcDoor (uks) (_RKAS BIM + ARCHICAD Classification); 52 Siseuksed (EHITUSKULUDE LIIGITAMINE EVS 885:2005)
Avatäited - 18 Viimistlus: RAL 9003; 01 Nimetus: Siseuks; 02 Materjal: Sile uks; 03 Tähistus: SU-A202 1 000×2 100; 04 Avamõõdu geomeetria: 1 000×2 100; 05 Asukoha info: Interior; 06 Soojusläbivus: -; 07 Helipidavus: 30 dB; 08 Veepidavus: -; 09 Õhuläbilaskvus: -; 10 Tulekindlus: nõudeid ei esitata; 11 Vastupanu tulekoormusele: -; 12 Klaaspakett: -; 13 Klaasingu erisused: -; 14 Päikesekiirgus tegur (g-väärtus): -; 15 Avanemine: Avanemine: "R" (L - vasak; R - parem); 16 Liigendatus: Lävepakk madal max 25mm, roostevaba; 17 Sulused, lukustus: vt lukustuse spetsifikatsioon; 19 Mudel või toote tunnus: Undefined; 20 Tootja: Undefined; 21 Tooteinfo: Undefined; 22 Kasutus- ja hooldusjuhend: Undefined
Pset_DoorCommon - ThermalTransmittance: 0; GlazingAreaFraction: 0; IsExternal: no
AC_Pset_RenovationAndPhasing - Renovation Status: New

# IfcDoor: SU-A203 1 000×2 100, Siseuks * Door 22
In: 2 KORRUS
Type - OperationType: SINGLE_SWING_LEFT; ParameterTakesPrecedence: no; Sizeable: no
Type - Door Lining Properties - LiningDepth: 115 mm; LiningThickness: 40 mm; LiningOffset: 560 mm; CasingThickness: 50 mm; CasingDepth: 19 mm
Type - Door Panel Properties - Panel 1 - PanelDepth: 40 mm; PanelOperation: SWINGING; PanelWidth: 1; PanelPosition: MIDDLE
OverallHeight: 2100 mm; OverallWidth: 1000 mm; Classification: 1.9 IfcDoor (uks) (_RKAS BIM + ARCHICAD Classification); 52 Siseuksed (EHITUSKULUDE LIIGITAMINE EVS 885:2005)
Avatäited - 18 Viimistlus: RAL 9003; 01 Nimetus: Siseuks; 02 Materjal: Sile uks; 03 Tähistus: SU-A203 1 000×2 100; 04 Avamõõdu geomeetria: 1 000×2 100; 05 Asukoha info: Interior; 06 Soojusläbivus: -; 07 Helipidavus: 30 dB; 08 Veepidavus: -; 09 Õhuläbilaskvus: -; 10 Tulekindlus: nõudeid ei esitata; 11 Vastupanu tulekoormusele: -; 12 Klaaspakett: -; 13 Klaasingu erisused: -; 14 Päikesekiirgus tegur (g-väärtus): -; 15 Avanemine: Avanemine: "R" (L - vasak; R - parem); 16 Liigendatus: Lävepakk madal max 25mm, roostevaba; 17 Sulused, lukustus: vt lukustuse spetsifikatsioon; 19 Mudel või toote tunnus: Undefined; 20 Tootja: Undefined; 21 Tooteinfo: Undefined; 22 Kasutus- ja hooldusjuhend: Undefined
Pset_DoorCommon - ThermalTransmittance: 0; GlazingAreaFraction: 0; IsExternal: no
AC_Pset_RenovationAndPhasing - Renovation Status: New

# IfcDoor: SU-A204 1 000×2 100, Siseuks * Door 22
In: 2 KORRUS
Type - OperationType: SINGLE_SWING_LEFT; ParameterTakesPrecedence: no; Sizeable: no
Type - Door Lining Properties - LiningDepth: 115 mm; LiningThickness: 40 mm; LiningOffset: 420 mm; CasingThickness: 50 mm; CasingDepth: 19 mm
Type - Door Panel Properties - Panel 1 - PanelDepth: 40 mm; PanelOperation: SWINGING; PanelWidth: 1; PanelPosition: MIDDLE
OverallHeight: 2100 mm; OverallWidth: 1000 mm; Classification: 1.9 IfcDoor (uks) (_RKAS BIM + ARCHICAD Classification); 52 Siseuksed (EHITUSKULUDE LIIGITAMINE EVS 885:2005)
Avatäited - 18 Viimistlus: RAL 9003; 01 Nimetus: Siseuks; 02 Materjal: Sile uks; 03 Tähistus: SU-A204 1 000×2 100; 04 Avamõõdu geomeetria: 1 000×2 100; 05 Asukoha info: Interior; 06 Soojusläbivus: -; 07 Helipidavus: 30 dB; 08 Veepidavus: -; 09 Õhuläbilaskvus: -; 10 Tulekindlus: nõudeid ei esitata; 11 Vastupanu tulekoormusele: -; 12 Klaaspakett: -; 13 Klaasingu erisused: -; 14 Päikesekiirgus tegur (g-väärtus): -; 15 Avanemine: Avanemine: "R" (L - vasak; R - parem); 16 Liigendatus: Lävepakk madal max 25mm, roostevaba; 17 Sulused, lukustus: vt lukustuse spetsifikatsioon; 19 Mudel või toote tunnus: Undefined; 20 Tootja: Undefined; 21 Tooteinfo: Undefined; 22 Kasutus- ja hooldusjuhend: Undefined
Pset_DoorCommon - ThermalTransmittance: 0; GlazingAreaFraction: 0; IsExternal: no
AC_Pset_RenovationAndPhasing - Renovation Status: New

# IfcDoor: SU-A205 1 000×2 100, Siseuks * Door 22
In: 2 KORRUS
Type - OperationType: SINGLE_SWING_LEFT; ParameterTakesPrecedence: no; Sizeable: no
Type - Door Lining Properties - LiningDepth: 115 mm; LiningThickness: 40 mm; LiningOffset: 420 mm; CasingThickness: 50 mm; CasingDepth: 19 mm
Type - Door Panel Properties - Panel 1 - PanelDepth: 40 mm; PanelOperation: SWINGING; PanelWidth: 1; PanelPosition: MIDDLE
OverallHeight: 2100 mm; OverallWidth: 1000 mm; Classification: 1.9 IfcDoor (uks) (_RKAS BIM + ARCHICAD Classification); 52 Siseuksed (EHITUSKULUDE LIIGITAMINE EVS 885:2005)
Avatäited - 18 Viimistlus: RAL 9003; 01 Nimetus: Siseuks; 02 Materjal: Sile uks; 03 Tähistus: SU-A205 1 000×2 100; 04 Avamõõdu geomeetria: 1 000×2 100; 05 Asukoha info: Interior; 06 Soojusläbivus: -; 07 Helipidavus: 30 dB; 08 Veepidavus: -; 09 Õhuläbilaskvus: -; 10 Tulekindlus: nõudeid ei esitata; 11 Vastupanu tulekoormusele: -; 12 Klaaspakett: -; 13 Klaasingu erisused: -; 14 Päikesekiirgus tegur (g-väärtus): -; 15 Avanemine: Avanemine: "R" (L - vasak; R - parem); 16 Liigendatus: Lävepakk madal max 25mm, roostevaba; 17 Sulused, lukustus: vt lukustuse spetsifikatsioon; 19 Mudel või toote tunnus: Undefined; 20 Tootja: Undefined; 21 Tooteinfo: Undefined; 22 Kasutus- ja hooldusjuhend: Undefined
Pset_DoorCommon - ThermalTransmittance: 0; GlazingAreaFraction: 0; IsExternal: no
AC_Pset_RenovationAndPhasing - Renovation Status: New

# IfcDoor: SU-A206 1 000×2 100, Siseuks * Door 22
In: 2 KORRUS
Type - OperationType: SINGLE_SWING_LEFT; ParameterTakesPrecedence: no; Sizeable: no
Type - Door Lining Properties - LiningDepth: 115 mm; LiningThickness: 40 mm; LiningOffset: 420 mm; CasingThickness: 50 mm; CasingDepth: 19 mm
Type - Door Panel Properties - Panel 1 - PanelDepth: 40 mm; PanelOperation: SWINGING; PanelWidth: 1; PanelPosition: MIDDLE
OverallHeight: 2100 mm; OverallWidth: 1000 mm; Classification: 1.9 IfcDoor (uks) (_RKAS BIM + ARCHICAD Classification); 52 Siseuksed (EHITUSKULUDE LIIGITAMINE EVS 885:2005)
Avatäited - 18 Viimistlus: RAL 9003; 01 Nimetus: Siseuks; 02 Materjal: Sile uks; 03 Tähistus: SU-A206 1 000×2 100; 04 Avamõõdu geomeetria: 1 000×2 100; 05 Asukoha info: Interior; 06 Soojusläbivus: -; 07 Helipidavus: 30 dB; 08 Veepidavus: -; 09 Õhuläbilaskvus: -; 10 Tulekindlus: nõudeid ei esitata; 11 Vastupanu tulekoormusele: -; 12 Klaaspakett: -; 13 Klaasingu erisused: -; 14 Päikesekiirgus tegur (g-väärtus): -; 15 Avanemine: Avanemine: "R" (L - vasak; R - parem); 16 Liigendatus: Lävepakk madal max 25mm, roostevaba; 17 Sulused, lukustus: vt lukustuse spetsifikatsioon; 19 Mudel või toote tunnus: Undefined; 20 Tootja: Undefined; 21 Tooteinfo: Undefined; 22 Kasutus- ja hooldusjuhend: Undefined
Pset_DoorCommon - ThermalTransmittance: 0; GlazingAreaFraction: 0; IsExternal: no
AC_Pset_RenovationAndPhasing - Renovation Status: New

# IfcDoor: SU-A207 1 729×2 300, Siseuks * Double Door 22
In: 2 KORRUS
Type - OperationType: DOUBLE_DOOR_SINGLE_SWING; ParameterTakesPrecedence: no; Sizeable: no
Type - Door Lining Properties - LiningDepth: 115 mm; LiningThickness: 40 mm; LiningOffset: 220 mm; CasingThickness: 50 mm; CasingDepth: 19 mm
Type - Door Panel Properties - Panel 1 - PanelDepth: 40 mm; PanelOperation: SWINGING; PanelWidth: 0.507279; PanelPosition: LEFT
Type - Door Panel Properties - Panel 2 - PanelDepth: 40 mm; PanelOperation: SWINGING; PanelWidth: 0.507279; PanelPosition: RIGHT
OverallHeight: 2300 mm; OverallWidth: 1728.6 mm; Classification: 1.9 IfcDoor (uks) (_RKAS BIM + ARCHICAD Classification); 52 Siseuksed (EHITUSKULUDE LIIGITAMINE EVS 885:2005)
Avatäited - 18 Viimistlus: RAL 9003; 01 Nimetus: Siseuks; 02 Materjal: Alumiiniumprofiil pulbervärvitud; 03 Tähistus: SU-A207 1 729×2 300; 04 Avamõõdu geomeetria: 1 729×2 300; 05 Asukoha info: Interior; 06 Soojusläbivus: -; 07 Helipidavus: 30 dB; 08 Veepidavus: -; 09 Õhuläbilaskvus: -; 10 Tulekindlus: nõudeid ei esitata; 11 Vastupanu tulekoormusele: -; 12 Klaaspakett: -; 13 Klaasingu erisused: -; 14 Päikesekiirgus tegur (g-väärtus): -; 15 Avanemine: Avanemine: "L" (L - vasak; R - parem); 16 Liigendatus: Tuulutatav lävepakk; 17 Sulused, lukustus: vt lukustuse spetsifikatsioon; 19 Mudel või toote tunnus: Undefined; 20 Tootja: Undefined; 21 Tooteinfo: Undefined; 22 Kasutus- ja hooldusjuhend: Undefined
Pset_DoorCommon - ThermalTransmittance: 0; GlazingAreaFraction: 2.1278; IsExternal: no
AC_Pset_RenovationAndPhasing - Renovation Status: New

# IfcDoor: SU-A208 950×2 300, Siseuks * Door 22
In: 2 KORRUS
Type - OperationType: SINGLE_SWING_LEFT; ParameterTakesPrecedence: no; Sizeable: no
Type - Door Lining Properties - LiningDepth: 115 mm; LiningThickness: 40 mm; LiningOffset: 150 mm; CasingThickness: 50 mm; CasingDepth: 19 mm
Type - Door Panel Properties - Panel 1 - PanelDepth: 40 mm; PanelOperation: SWINGING; PanelWidth: 1; PanelPosition: MIDDLE
OverallHeight: 2300 mm; OverallWidth: 950 mm; Classification: 1.9 IfcDoor (uks) (_RKAS BIM + ARCHICAD Classification); 52 Siseuksed (EHITUSKULUDE LIIGITAMINE EVS 885:2005)
Avatäited - 18 Viimistlus: RAL 9003; 01 Nimetus: Siseuks; 02 Materjal: Sile uks; 03 Tähistus: SU-A208 950×2 300; 04 Avamõõdu geomeetria: 950×2 300; 05 Asukoha info: Interior; 06 Soojusläbivus: -; 07 Helipidavus: 30 dB; 08 Veepidavus: -; 09 Õhuläbilaskvus: -; 10 Tulekindlus: nõudeid ei esitata; 11 Vastupanu tulekoormusele: -; 12 Klaaspakett: -; 13 Klaasingu erisused: -; 14 Päikesekiirgus tegur (g-väärtus): -; 15 Avanemine: Avanemine: "R" (L - vasak; R - parem); 16 Liigendatus: Lävepakk madal max 25mm, roostevaba; 17 Sulused, lukustus: vt lukustuse spetsifikatsioon; 19 Mudel või toote tunnus: Undefined; 20 Tootja: Undefined; 21 Tooteinfo: Undefined; 22 Kasutus- ja hooldusjuhend: Undefined
Pset_DoorCommon - ThermalTransmittance: 0; GlazingAreaFraction: 0; IsExternal: no
AC_Pset_RenovationAndPhasing - Renovation Status: New

# IfcDoor: SU-A209 B 950×2 300, Siseuks * Door 22
In: 2 KORRUS
Type - OperationType: SINGLE_SWING_LEFT; ParameterTakesPrecedence: no; Sizeable: no
Type - Door Lining Properties - LiningDepth: 115 mm; LiningThickness: 40 mm; LiningOffset: 150 mm; CasingThickness: 50 mm; CasingDepth: 19 mm
Type - Door Panel Properties - Panel 1 - PanelDepth: 40 mm; PanelOperation: SWINGING; PanelWidth: 1; PanelPosition: MIDDLE
OverallHeight: 2300 mm; OverallWidth: 950 mm; Classification: 1.9 IfcDoor (uks) (_RKAS BIM + ARCHICAD Classification); 52 Siseuksed (EHITUSKULUDE LIIGITAMINE EVS 885:2005)
Avatäited - 18 Viimistlus: RAL 9003; 01 Nimetus: Siseuks; 02 Materjal: Sile uks; 03 Tähistus: SU-A209 B 950×2 300; 04 Avamõõdu geomeetria: 950×2 300; 05 Asukoha info: Interior; 06 Soojusläbivus: -; 07 Helipidavus: 30 dB; 08 Veepidavus: -; 09 Õhuläbilaskvus: -; 10 Tulekindlus: nõudeid ei esitata; 11 Vastupanu tulekoormusele: -; 12 Klaaspakett: -; 13 Klaasingu erisused: -; 14 Päikesekiirgus tegur (g-väärtus): -; 15 Avanemine: Avanemine: "R" (L - vasak; R - parem); 16 Liigendatus: Lävepakk madal max 25mm, roostevaba; 17 Sulused, lukustus: vt lukustuse spetsifikatsioon; 19 Mudel või toote tunnus: Undefined; 20 Tootja: Undefined; 21 Tooteinfo: Undefined; 22 Kasutus- ja hooldusjuhend: Undefined
Pset_DoorCommon - ThermalTransmittance: 0; GlazingAreaFraction: 0; IsExternal: no
AC_Pset_RenovationAndPhasing - Renovation Status: New

# IfcDoor: SU-A209 C 950×2 300, Siseuks * Door 22
In: 2 KORRUS
Type - OperationType: SINGLE_SWING_LEFT; ParameterTakesPrecedence: no; Sizeable: no
Type - Door Lining Properties - LiningDepth: 115 mm; LiningThickness: 40 mm; LiningOffset: 150 mm; CasingThickness: 50 mm; CasingDepth: 19 mm
Type - Door Panel Properties - Panel 1 - PanelDepth: 40 mm; PanelOperation: SWINGING; PanelWidth: 1; PanelPosition: MIDDLE
OverallHeight: 2300 mm; OverallWidth: 950 mm; Classification: 1.9 IfcDoor (uks) (_RKAS BIM + ARCHICAD Classification); 52 Siseuksed (EHITUSKULUDE LIIGITAMINE EVS 885:2005)
Avatäited - 18 Viimistlus: RAL 9003; 01 Nimetus: Siseuks; 02 Materjal: Sile uks; 03 Tähistus: SU-A209 C 950×2 300; 04 Avamõõdu geomeetria: 950×2 300; 05 Asukoha info: Interior; 06 Soojusläbivus: -; 07 Helipidavus: 30 dB; 08 Veepidavus: -; 09 Õhuläbilaskvus: -; 10 Tulekindlus: nõudeid ei esitata; 11 Vastupanu tulekoormusele: -; 12 Klaaspakett: -; 13 Klaasingu erisused: -; 14 Päikesekiirgus tegur (g-väärtus): -; 15 Avanemine: Avanemine: "R" (L - vasak; R - parem); 16 Liigendatus: Lävepakk madal max 25mm, roostevaba; 17 Sulused, lukustus: vt lukustuse spetsifikatsioon; 19 Mudel või toote tunnus: Undefined; 20 Tootja: Undefined; 21 Tooteinfo: Undefined; 22 Kasutus- ja hooldusjuhend: Undefined
Pset_DoorCommon - ThermalTransmittance: 0; GlazingAreaFraction: 0; IsExternal: no
AC_Pset_RenovationAndPhasing - Renovation Status: New

# IfcDoor: SU-A209A 950×2 300, Siseuks * Door 22
In: 2 KORRUS
Type - OperationType: SINGLE_SWING_LEFT; ParameterTakesPrecedence: no; Sizeable: no
Type - Door Lining Properties - LiningDepth: 115 mm; LiningThickness: 40 mm; LiningOffset: -105 mm; CasingThickness: 50 mm; CasingDepth: 19 mm
Type - Door Panel Properties - Panel 1 - PanelDepth: 40 mm; PanelOperation: SWINGING; PanelWidth: 1; PanelPosition: MIDDLE
OverallHeight: 2300 mm; OverallWidth: 950 mm; Classification: 1.9 IfcDoor (uks) (_RKAS BIM + ARCHICAD Classification); 52 Siseuksed (EHITUSKULUDE LIIGITAMINE EVS 885:2005)
Avatäited - 18 Viimistlus: RAL 9003; 01 Nimetus: Siseuks; 02 Materjal: Sile uks; 03 Tähistus: SU-A209A 950×2 300; 04 Avamõõdu geomeetria: 950×2 300; 05 Asukoha info: Interior; 06 Soojusläbivus: -; 07 Helipidavus: 30 dB; 08 Veepidavus: -; 09 Õhuläbilaskvus: -; 10 Tulekindlus: nõudeid ei esitata; 11 Vastupanu tulekoormusele: -; 12 Klaaspakett: -; 13 Klaasingu erisused: -; 14 Päikesekiirgus tegur (g-väärtus): -; 15 Avanemine: Avanemine: "R" (L - vasak; R - parem); 16 Liigendatus: Lävepakk madal max 25mm, roostevaba; 17 Sulused, lukustus: vt lukustuse spetsifikatsioon; 19 Mudel või toote tunnus: Undefined; 20 Tootja: Undefined; 21 Tooteinfo: Undefined; 22 Kasutus- ja hooldusjuhend: Undefined
Pset_DoorCommon - ThermalTransmittance: 0; GlazingAreaFraction: 0; IsExternal: no
AC_Pset_RenovationAndPhasing - Renovation Status: New

# IfcDoor: SU-A210 950×2 300, Siseuks * Door 22
In: 2 KORRUS
Type - OperationType: SINGLE_SWING_LEFT; ParameterTakesPrecedence: no; Sizeable: no
Type - Door Lining Properties - LiningDepth: 115 mm; LiningThickness: 40 mm; LiningOffset: 150 mm; CasingThickness: 50 mm; CasingDepth: 19 mm
Type - Door Panel Properties - Panel 1 - PanelDepth: 40 mm; PanelOperation: SWINGING; PanelWidth: 1; PanelPosition: MIDDLE
OverallHeight: 2300 mm; OverallWidth: 950 mm; Classification: 1.9 IfcDoor (uks) (_RKAS BIM + ARCHICAD Classification); 52 Siseuksed (EHITUSKULUDE LIIGITAMINE EVS 885:2005)
Avatäited - 18 Viimistlus: RAL 9003; 01 Nimetus: Siseuks; 02 Materjal: Sile uks; 03 Tähistus: SU-A210 950×2 300; 04 Avamõõdu geomeetria: 950×2 300; 05 Asukoha info: Interior; 06 Soojusläbivus: -; 07 Helipidavus: 30 dB; 08 Veepidavus: -; 09 Õhuläbilaskvus: -; 10 Tulekindlus: nõudeid ei esitata; 11 Vastupanu tulekoormusele: -; 12 Klaaspakett: -; 13 Klaasingu erisused: -; 14 Päikesekiirgus tegur (g-väärtus): -; 15 Avanemine: Avanemine: "R" (L - vasak; R - parem); 16 Liigendatus: Lävepakk madal max 25mm, roostevaba; 17 Sulused, lukustus: vt lukustuse spetsifikatsioon; 19 Mudel või toote tunnus: Undefined; 20 Tootja: Undefined; 21 Tooteinfo: Undefined; 22 Kasutus- ja hooldusjuhend: Undefined
Pset_DoorCommon - ThermalTransmittance: 0; GlazingAreaFraction: 0; IsExternal: no
AC_Pset_RenovationAndPhasing - Renovation Status: New

# IfcDoor: SU-A211 950×2 300, Siseuks * Door 22
In: 2 KORRUS
Type - OperationType: SINGLE_SWING_LEFT; ParameterTakesPrecedence: no; Sizeable: no
Type - Door Lining Properties - LiningDepth: 115 mm; LiningThickness: 40 mm; LiningOffset: 0 mm; CasingThickness: 50 mm; CasingDepth: 19 mm
Type - Door Panel Properties - Panel 1 - PanelDepth: 40 mm; PanelOperation: SWINGING; PanelWidth: 1; PanelPosition: MIDDLE
OverallHeight: 2300 mm; OverallWidth: 950 mm; Classification: 1.9 IfcDoor (uks) (_RKAS BIM + ARCHICAD Classification); 52 Siseuksed (EHITUSKULUDE LIIGITAMINE EVS 885:2005)
Avatäited - 18 Viimistlus: RAL 9003; 01 Nimetus: Siseuks; 02 Materjal: Sile uks; 03 Tähistus: SU-A211 950×2 300; 04 Avamõõdu geomeetria: 950×2 300; 05 Asukoha info: Interior; 06 Soojusläbivus: -; 07 Helipidavus: 30 dB; 08 Veepidavus: -; 09 Õhuläbilaskvus: -; 10 Tulekindlus: nõudeid ei esitata; 11 Vastupanu tulekoormusele: -; 12 Klaaspakett: -; 13 Klaasingu erisused: -; 14 Päikesekiirgus tegur (g-väärtus): -; 15 Avanemine: Avanemine: "R" (L - vasak; R - parem); 16 Liigendatus: Lävepakk madal max 25mm, roostevaba; 17 Sulused, lukustus: vt lukustuse spetsifikatsioon; 19 Mudel või toote tunnus: Undefined; 20 Tootja: Undefined; 21 Tooteinfo: Undefined; 22 Kasutus- ja hooldusjuhend: Undefined
Pset_DoorCommon - ThermalTransmittance: 0; GlazingAreaFraction: 0; IsExternal: no
AC_Pset_RenovationAndPhasing - Renovation Status: New

# IfcDoor: SU-A212 950×2 300, Siseuks * Door 22
In: 2 KORRUS
Type - OperationType: SINGLE_SWING_LEFT; ParameterTakesPrecedence: no; Sizeable: no
Type - Door Lining Properties - LiningDepth: 115 mm; LiningThickness: 40 mm; LiningOffset: 150 mm; CasingThickness: 50 mm; CasingDepth: 19 mm
Type - Door Panel Properties - Panel 1 - PanelDepth: 40 mm; PanelOperation: SWINGING; PanelWidth: 1; PanelPosition: MIDDLE
OverallHeight: 2300 mm; OverallWidth: 950 mm; Classification: 1.9 IfcDoor (uks) (_RKAS BIM + ARCHICAD Classification); 52 Siseuksed (EHITUSKULUDE LIIGITAMINE EVS 885:2005)
Avatäited - 18 Viimistlus: RAL 9003; 01 Nimetus: Siseuks; 02 Materjal: Sile uks; 03 Tähistus: SU-A212 950×2 300; 04 Avamõõdu geomeetria: 950×2 300; 05 Asukoha info: Interior; 06 Soojusläbivus: -; 07 Helipidavus: 30 dB; 08 Veepidavus: -; 09 Õhuläbilaskvus: -; 10 Tulekindlus: nõudeid ei esitata; 11 Vastupanu tulekoormusele: -; 12 Klaaspakett: -; 13 Klaasingu erisused: -; 14 Päikesekiirgus tegur (g-väärtus): -; 15 Avanemine: Avanemine: "R" (L - vasak; R - parem); 16 Liigendatus: Lävepakk madal max 25mm, roostevaba; 17 Sulused, lukustus: vt lukustuse spetsifikatsioon; 19 Mudel või toote tunnus: Undefined; 20 Tootja: Undefined; 21 Tooteinfo: Undefined; 22 Kasutus- ja hooldusjuhend: Undefined
Pset_DoorCommon - ThermalTransmittance: 0; GlazingAreaFraction: 0; IsExternal: no
AC_Pset_RenovationAndPhasing - Renovation Status: New

# IfcDoor: SU-A213 950×2 300, Siseuks * Door 22
In: 2 KORRUS
Type - OperationType: SINGLE_SWING_LEFT; ParameterTakesPrecedence: no; Sizeable: no
Type - Door Lining Properties - LiningDepth: 115 mm; LiningThickness: 40 mm; LiningOffset: 0 mm; CasingThickness: 50 mm; CasingDepth: 19 mm
Type - Door Panel Properties - Panel 1 - PanelDepth: 40 mm; PanelOperation: SWINGING; PanelWidth: 1; PanelPosition: MIDDLE
OverallHeight: 2300 mm; OverallWidth: 950 mm; Classification: 1.9 IfcDoor (uks) (_RKAS BIM + ARCHICAD Classification); 52 Siseuksed (EHITUSKULUDE LIIGITAMINE EVS 885:2005)
Avatäited - 18 Viimistlus: RAL 9003; 01 Nimetus: Siseuks; 02 Materjal: Sile uks; 03 Tähistus: SU-A213 950×2 300; 04 Avamõõdu geomeetria: 950×2 300; 05 Asukoha info: Interior; 06 Soojusläbivus: -; 07 Helipidavus: 30 dB; 08 Veepidavus: -; 09 Õhuläbilaskvus: -; 10 Tulekindlus: nõudeid ei esitata; 11 Vastupanu tulekoormusele: -; 12 Klaaspakett: -; 13 Klaasingu erisused: -; 14 Päikesekiirgus tegur (g-väärtus): -; 15 Avanemine: Avanemine: "R" (L - vasak; R - parem); 16 Liigendatus: Lävepakk madal max 25mm, roostevaba; 17 Sulused, lukustus: vt lukustuse spetsifikatsioon; 19 Mudel või toote tunnus: Undefined; 20 Tootja: Undefined; 21 Tooteinfo: Undefined; 22 Kasutus- ja hooldusjuhend: Undefined
Pset_DoorCommon - ThermalTransmittance: 0; GlazingAreaFraction: 0; IsExternal: no
AC_Pset_RenovationAndPhasing - Renovation Status: New

# IfcDoor: SU-A214 950×2 300, Siseuks * Door 22
In: 2 KORRUS
Type - OperationType: SINGLE_SWING_LEFT; ParameterTakesPrecedence: no; Sizeable: no
Type - Door Lining Properties - LiningDepth: 115 mm; LiningThickness: 40 mm; LiningOffset: 150 mm; CasingThickness: 50 mm; CasingDepth: 19 mm
Type - Door Panel Properties - Panel 1 - PanelDepth: 40 mm; PanelOperation: SWINGING; PanelWidth: 1; PanelPosition: MIDDLE
OverallHeight: 2300 mm; OverallWidth: 950 mm; Classification: 1.9 IfcDoor (uks) (_RKAS BIM + ARCHICAD Classification); 52 Siseuksed (EHITUSKULUDE LIIGITAMINE EVS 885:2005)
Avatäited - 18 Viimistlus: RAL 9003; 01 Nimetus: Siseuks; 02 Materjal: Sile uks; 03 Tähistus: SU-A214 950×2 300; 04 Avamõõdu geomeetria: 950×2 300; 05 Asukoha info: Interior; 06 Soojusläbivus: -; 07 Helipidavus: 30 dB; 08 Veepidavus: -; 09 Õhuläbilaskvus: -; 10 Tulekindlus: nõudeid ei esitata; 11 Vastupanu tulekoormusele: -; 12 Klaaspakett: -; 13 Klaasingu erisused: -; 14 Päikesekiirgus tegur (g-väärtus): -; 15 Avanemine: Avanemine: "R" (L - vasak; R - parem); 16 Liigendatus: Lävepakk madal max 25mm, roostevaba; 17 Sulused, lukustus: vt lukustuse spetsifikatsioon; 19 Mudel või toote tunnus: Undefined; 20 Tootja: Undefined; 21 Tooteinfo: Undefined; 22 Kasutus- ja hooldusjuhend: Undefined
Pset_DoorCommon - ThermalTransmittance: 0; GlazingAreaFraction: 0; IsExternal: no
AC_Pset_RenovationAndPhasing - Renovation Status: New

# IfcDoor: SU-A215 950×2 300, Siseuks * Door 22
In: 2 KORRUS
Type - OperationType: SINGLE_SWING_LEFT; ParameterTakesPrecedence: no; Sizeable: no
Type - Door Lining Properties - LiningDepth: 115 mm; LiningThickness: 40 mm; LiningOffset: 0 mm; CasingThickness: 50 mm; CasingDepth: 19 mm
Type - Door Panel Properties - Panel 1 - PanelDepth: 40 mm; PanelOperation: SWINGING; PanelWidth: 1; PanelPosition: MIDDLE
OverallHeight: 2300 mm; OverallWidth: 950 mm; Classification: 1.9 IfcDoor (uks) (_RKAS BIM + ARCHICAD Classification); 52 Siseuksed (EHITUSKULUDE LIIGITAMINE EVS 885:2005)
Avatäited - 18 Viimistlus: RAL 9003; 01 Nimetus: Siseuks; 02 Materjal: Sile uks; 03 Tähistus: SU-A215 950×2 300; 04 Avamõõdu geomeetria: 950×2 300; 05 Asukoha info: Interior; 06 Soojusläbivus: -; 07 Helipidavus: 30 dB; 08 Veepidavus: -; 09 Õhuläbilaskvus: -; 10 Tulekindlus: nõudeid ei esitata; 11 Vastupanu tulekoormusele: -; 12 Klaaspakett: -; 13 Klaasingu erisused: -; 14 Päikesekiirgus tegur (g-väärtus): -; 15 Avanemine: Avanemine: "R" (L - vasak; R - parem); 16 Liigendatus: Lävepakk madal max 25mm, roostevaba; 17 Sulused, lukustus: vt lukustuse spetsifikatsioon; 19 Mudel või toote tunnus: Undefined; 20 Tootja: Undefined; 21 Tooteinfo: Undefined; 22 Kasutus- ja hooldusjuhend: Undefined
Pset_DoorCommon - ThermalTransmittance: 0; GlazingAreaFraction: 0; IsExternal: no
AC_Pset_RenovationAndPhasing - Renovation Status: New

# IfcDoor: SU-A216 950×2 300, Siseuks * Door 22
In: 2 KORRUS
Type - OperationType: SINGLE_SWING_LEFT; ParameterTakesPrecedence: no; Sizeable: no
Type - Door Lining Properties - LiningDepth: 115 mm; LiningThickness: 40 mm; LiningOffset: 150 mm; CasingThickness: 50 mm; CasingDepth: 19 mm
Type - Door Panel Properties - Panel 1 - PanelDepth: 40 mm; PanelOperation: SWINGING; PanelWidth: 1; PanelPosition: MIDDLE
OverallHeight: 2300 mm; OverallWidth: 950 mm; Classification: 1.9 IfcDoor (uks) (_RKAS BIM + ARCHICAD Classification); 52 Siseuksed (EHITUSKULUDE LIIGITAMINE EVS 885:2005)
Avatäited - 18 Viimistlus: RAL 9003; 01 Nimetus: Siseuks; 02 Materjal: Sile uks; 03 Tähistus: SU-A216 950×2 300; 04 Avamõõdu geomeetria: 950×2 300; 05 Asukoha info: Interior; 06 Soojusläbivus: -; 07 Helipidavus: 30 dB; 08 Veepidavus: -; 09 Õhuläbilaskvus: -; 10 Tulekindlus: nõudeid ei esitata; 11 Vastupanu tulekoormusele: -; 12 Klaaspakett: -; 13 Klaasingu erisused: -; 14 Päikesekiirgus tegur (g-väärtus): -; 15 Avanemine: Avanemine: "R" (L - vasak; R - parem); 16 Liigendatus: Lävepakk madal max 25mm, roostevaba; 17 Sulused, lukustus: vt lukustuse spetsifikatsioon; 19 Mudel või toote tunnus: Undefined; 20 Tootja: Undefined; 21 Tooteinfo: Undefined; 22 Kasutus- ja hooldusjuhend: Undefined
Pset_DoorCommon - ThermalTransmittance: 0; GlazingAreaFraction: 0; IsExternal: no
AC_Pset_RenovationAndPhasing - Renovation Status: New

# IfcDoor: SU-A217 950×2 300, Siseuks * Door 22
In: 2 KORRUS
Type - OperationType: SINGLE_SWING_LEFT; ParameterTakesPrecedence: no; Sizeable: no
Type - Door Lining Properties - LiningDepth: 115 mm; LiningThickness: 40 mm; LiningOffset: 0 mm; CasingThickness: 50 mm; CasingDepth: 19 mm
Type - Door Panel Properties - Panel 1 - PanelDepth: 40 mm; PanelOperation: SWINGING; PanelWidth: 1; PanelPosition: MIDDLE
OverallHeight: 2300 mm; OverallWidth: 950 mm; Classification: 1.9 IfcDoor (uks) (_RKAS BIM + ARCHICAD Classification); 52 Siseuksed (EHITUSKULUDE LIIGITAMINE EVS 885:2005)
Avatäited - 18 Viimistlus: RAL 9003; 01 Nimetus: Siseuks; 02 Materjal: Sile uks; 03 Tähistus: SU-A217 950×2 300; 04 Avamõõdu geomeetria: 950×2 300; 05 Asukoha info: Interior; 06 Soojusläbivus: -; 07 Helipidavus: 30 dB; 08 Veepidavus: -; 09 Õhuläbilaskvus: -; 10 Tulekindlus: nõudeid ei esitata; 11 Vastupanu tulekoormusele: -; 12 Klaaspakett: -; 13 Klaasingu erisused: -; 14 Päikesekiirgus tegur (g-väärtus): -; 15 Avanemine: Avanemine: "R" (L - vasak; R - parem); 16 Liigendatus: Lävepakk madal max 25mm, roostevaba; 17 Sulused, lukustus: vt lukustuse spetsifikatsioon; 19 Mudel või toote tunnus: Undefined; 20 Tootja: Undefined; 21 Tooteinfo: Undefined; 22 Kasutus- ja hooldusjuhend: Undefined
Pset_DoorCommon - ThermalTransmittance: 0; GlazingAreaFraction: 0; IsExternal: no
AC_Pset_RenovationAndPhasing - Renovation Status: New

# IfcDoor: SU-A218 950×2 300, Siseuks * Door 22
In: 2 KORRUS
Type - OperationType: SINGLE_SWING_LEFT; ParameterTakesPrecedence: no; Sizeable: no
Type - Door Lining Properties - LiningDepth: 115 mm; LiningThickness: 40 mm; LiningOffset: 150 mm; CasingThickness: 50 mm; CasingDepth: 19 mm
Type - Door Panel Properties - Panel 1 - PanelDepth: 40 mm; PanelOperation: SWINGING; PanelWidth: 1; PanelPosition: MIDDLE
OverallHeight: 2300 mm; OverallWidth: 950 mm; Classification: 1.9 IfcDoor (uks) (_RKAS BIM + ARCHICAD Classification); 52 Siseuksed (EHITUSKULUDE LIIGITAMINE EVS 885:2005)
Avatäited - 18 Viimistlus: RAL 9003; 01 Nimetus: Siseuks; 02 Materjal: Sile uks; 03 Tähistus: SU-A218 950×2 300; 04 Avamõõdu geomeetria: 950×2 300; 05 Asukoha info: Interior; 06 Soojusläbivus: -; 07 Helipidavus: 30 dB; 08 Veepidavus: -; 09 Õhuläbilaskvus: -; 10 Tulekindlus: nõudeid ei esitata; 11 Vastupanu tulekoormusele: -; 12 Klaaspakett: -; 13 Klaasingu erisused: -; 14 Päikesekiirgus tegur (g-väärtus): -; 15 Avanemine: Avanemine: "R" (L - vasak; R - parem); 16 Liigendatus: Lävepakk madal max 25mm, roostevaba; 17 Sulused, lukustus: vt lukustuse spetsifikatsioon; 19 Mudel või toote tunnus: Undefined; 20 Tootja: Undefined; 21 Tooteinfo: Undefined; 22 Kasutus- ja hooldusjuhend: Undefined
Pset_DoorCommon - ThermalTransmittance: 0; GlazingAreaFraction: 0; IsExternal: no
AC_Pset_RenovationAndPhasing - Renovation Status: New

# IfcDoor: SU-A219 950×2 300, Siseuks * Door 22
In: 2 KORRUS
Type - OperationType: SINGLE_SWING_LEFT; ParameterTakesPrecedence: no; Sizeable: no
Type - Door Lining Properties - LiningDepth: 115 mm; LiningThickness: 40 mm; LiningOffset: 150 mm; CasingThickness: 50 mm; CasingDepth: 19 mm
Type - Door Panel Properties - Panel 1 - PanelDepth: 40 mm; PanelOperation: SWINGING; PanelWidth: 1; PanelPosition: MIDDLE
OverallHeight: 2300 mm; OverallWidth: 950 mm; Classification: 1.9 IfcDoor (uks) (_RKAS BIM + ARCHICAD Classification); 52 Siseuksed (EHITUSKULUDE LIIGITAMINE EVS 885:2005)
Avatäited - 18 Viimistlus: RAL 9003; 01 Nimetus: Siseuks; 02 Materjal: Sile uks; 03 Tähistus: SU-A219 950×2 300; 04 Avamõõdu geomeetria: 950×2 300; 05 Asukoha info: Interior; 06 Soojusläbivus: -; 07 Helipidavus: 30 dB; 08 Veepidavus: -; 09 Õhuläbilaskvus: -; 10 Tulekindlus: nõudeid ei esitata; 11 Vastupanu tulekoormusele: -; 12 Klaaspakett: -; 13 Klaasingu erisused: -; 14 Päikesekiirgus tegur (g-väärtus): -; 15 Avanemine: Avanemine: "R" (L - vasak; R - parem); 16 Liigendatus: Lävepakk madal max 25mm, roostevaba; 17 Sulused, lukustus: vt lukustuse spetsifikatsioon; 19 Mudel või toote tunnus: Undefined; 20 Tootja: Undefined; 21 Tooteinfo: Undefined; 22 Kasutus- ja hooldusjuhend: Undefined
Pset_DoorCommon - ThermalTransmittance: 0; GlazingAreaFraction: 0; IsExternal: no
AC_Pset_RenovationAndPhasing - Renovation Status: New

# IfcDoor: SU-A220 950×2 300, Siseuks * Door 22
In: 2 KORRUS
Type - OperationType: SINGLE_SWING_LEFT; ParameterTakesPrecedence: no; Sizeable: no
Type - Door Lining Properties - LiningDepth: 115 mm; LiningThickness: 40 mm; LiningOffset: 100 mm; CasingThickness: 50 mm; CasingDepth: 19 mm
Type - Door Panel Properties - Panel 1 - PanelDepth: 40 mm; PanelOperation: SWINGING; PanelWidth: 1; PanelPosition: MIDDLE
OverallHeight: 2300 mm; OverallWidth: 950 mm; Classification: 1.9 IfcDoor (uks) (_RKAS BIM + ARCHICAD Classification); 52 Siseuksed (EHITUSKULUDE LIIGITAMINE EVS 885:2005)
Avatäited - 18 Viimistlus: RAL 9003; 01 Nimetus: Siseuks; 02 Materjal: Sile uks; 03 Tähistus: SU-A220 950×2 300; 04 Avamõõdu geomeetria: 950×2 300; 05 Asukoha info: Interior; 06 Soojusläbivus: -; 07 Helipidavus: 30 dB; 08 Veepidavus: -; 09 Õhuläbilaskvus: -; 10 Tulekindlus: nõudeid ei esitata; 11 Vastupanu tulekoormusele: -; 12 Klaaspakett: -; 13 Klaasingu erisused: -; 14 Päikesekiirgus tegur (g-väärtus): -; 15 Avanemine: Avanemine: "R" (L - vasak; R - parem); 16 Liigendatus: Lävepakk madal max 25mm, roostevaba; 17 Sulused, lukustus: vt lukustuse spetsifikatsioon; 19 Mudel või toote tunnus: Undefined; 20 Tootja: Undefined; 21 Tooteinfo: Undefined; 22 Kasutus- ja hooldusjuhend: Undefined
Pset_DoorCommon - ThermalTransmittance: 0; GlazingAreaFraction: 0; IsExternal: no
AC_Pset_RenovationAndPhasing - Renovation Status: New

# IfcDoor: SU-A221 950×2 300, Siseuks * Door 22
In: 2 KORRUS
Type - OperationType: SINGLE_SWING_LEFT; ParameterTakesPrecedence: no; Sizeable: no
Type - Door Lining Properties - LiningDepth: 115 mm; LiningThickness: 40 mm; LiningOffset: 150 mm; CasingThickness: 50 mm; CasingDepth: 19 mm
Type - Door Panel Properties - Panel 1 - PanelDepth: 40 mm; PanelOperation: SWINGING; PanelWidth: 1; PanelPosition: MIDDLE
OverallHeight: 2300 mm; OverallWidth: 950 mm; Classification: 1.9 IfcDoor (uks) (_RKAS BIM + ARCHICAD Classification); 52 Siseuksed (EHITUSKULUDE LIIGITAMINE EVS 885:2005)
Avatäited - 18 Viimistlus: RAL 9003; 01 Nimetus: Siseuks; 02 Materjal: Sile uks; 03 Tähistus: SU-A221 950×2 300; 04 Avamõõdu geomeetria: 950×2 300; 05 Asukoha info: Interior; 06 Soojusläbivus: -; 07 Helipidavus: 30 dB; 08 Veepidavus: -; 09 Õhuläbilaskvus: -; 10 Tulekindlus: nõudeid ei esitata; 11 Vastupanu tulekoormusele: -; 12 Klaaspakett: -; 13 Klaasingu erisused: -; 14 Päikesekiirgus tegur (g-väärtus): -; 15 Avanemine: Avanemine: "R" (L - vasak; R - parem); 16 Liigendatus: Lävepakk madal max 25mm, roostevaba; 17 Sulused, lukustus: vt lukustuse spetsifikatsioon; 19 Mudel või toote tunnus: Undefined; 20 Tootja: Undefined; 21 Tooteinfo: Undefined; 22 Kasutus- ja hooldusjuhend: Undefined
Pset_DoorCommon - ThermalTransmittance: 0; GlazingAreaFraction: 0; IsExternal: no
AC_Pset_RenovationAndPhasing - Renovation Status: New

# IfcDoor: SU-A221A 900×2 300, Siseuks * Door 22
In: 2 KORRUS
Type - OperationType: SINGLE_SWING_LEFT; ParameterTakesPrecedence: no; Sizeable: no
Type - Door Lining Properties - LiningDepth: 115 mm; LiningThickness: 40 mm; LiningOffset: 0 mm; CasingThickness: 50 mm; CasingDepth: 19 mm
Type - Door Panel Properties - Panel 1 - PanelDepth: 40 mm; PanelOperation: SWINGING; PanelWidth: 1; PanelPosition: MIDDLE
OverallHeight: 2300 mm; OverallWidth: 900 mm; Classification: 1.9 IfcDoor (uks) (_RKAS BIM + ARCHICAD Classification); 52 Siseuksed (EHITUSKULUDE LIIGITAMINE EVS 885:2005)
Avatäited - 18 Viimistlus: RAL 9003; 01 Nimetus: Siseuks; 02 Materjal: Sile uks; 03 Tähistus: SU-A221A 900×2 300; 04 Avamõõdu geomeetria: 900×2 300; 05 Asukoha info: Interior; 06 Soojusläbivus: -; 07 Helipidavus: 30 dB; 08 Veepidavus: -; 09 Õhuläbilaskvus: -; 10 Tulekindlus: nõudeid ei esitata; 11 Vastupanu tulekoormusele: -; 12 Klaaspakett: -; 13 Klaasingu erisused: -; 14 Päikesekiirgus tegur (g-väärtus): -; 15 Avanemine: Avanemine: "R" (L - vasak; R - parem); 16 Liigendatus: Lävepakk madal max 25mm, roostevaba; 17 Sulused, lukustus: vt lukustuse spetsifikatsioon; 19 Mudel või toote tunnus: Undefined; 20 Tootja: Undefined; 21 Tooteinfo: Undefined; 22 Kasutus- ja hooldusjuhend: Undefined
Pset_DoorCommon - ThermalTransmittance: 0; GlazingAreaFraction: 0; IsExternal: no
AC_Pset_RenovationAndPhasing - Renovation Status: New

# IfcDoor: SU-A222 950×2 300, Siseuks * Door 22
In: 2 KORRUS
Type - OperationType: SINGLE_SWING_LEFT; ParameterTakesPrecedence: no; Sizeable: no
Type - Door Lining Properties - LiningDepth: 115 mm; LiningThickness: 40 mm; LiningOffset: 0 mm; CasingThickness: 50 mm; CasingDepth: 19 mm
Type - Door Panel Properties - Panel 1 - PanelDepth: 40 mm; PanelOperation: SWINGING; PanelWidth: 1; PanelPosition: MIDDLE
OverallHeight: 2300 mm; OverallWidth: 950 mm; Classification: 1.9 IfcDoor (uks) (_RKAS BIM + ARCHICAD Classification); 52 Siseuksed (EHITUSKULUDE LIIGITAMINE EVS 885:2005)
Avatäited - 18 Viimistlus: RAL 9003; 01 Nimetus: Siseuks; 02 Materjal: Sile uks; 03 Tähistus: SU-A222 950×2 300; 04 Avamõõdu geomeetria: 950×2 300; 05 Asukoha info: Interior; 06 Soojusläbivus: -; 07 Helipidavus: 30 dB; 08 Veepidavus: -; 09 Õhuläbilaskvus: -; 10 Tulekindlus: nõudeid ei esitata; 11 Vastupanu tulekoormusele: -; 12 Klaaspakett: -; 13 Klaasingu erisused: -; 14 Päikesekiirgus tegur (g-väärtus): -; 15 Avanemine: Avanemine: "R" (L - vasak; R - parem); 16 Liigendatus: Lävepakk madal max 25mm, roostevaba; 17 Sulused, lukustus: vt lukustuse spetsifikatsioon; 19 Mudel või toote tunnus: Undefined; 20 Tootja: Undefined; 21 Tooteinfo: Undefined; 22 Kasutus- ja hooldusjuhend: Undefined
Pset_DoorCommon - ThermalTransmittance: 0; GlazingAreaFraction: 0; IsExternal: no
AC_Pset_RenovationAndPhasing - Renovation Status: New

# IfcDoor: SU-A223 1 600×2 200, Siseuks * Double Door 22
In: 2 KORRUS
Type - OperationType: DOUBLE_DOOR_SINGLE_SWING; ParameterTakesPrecedence: no; Sizeable: no
Type - Door Lining Properties - LiningDepth: 115 mm; LiningThickness: 40 mm; LiningOffset: 115 mm; CasingThickness: 50 mm; CasingDepth: 19 mm
Type - Door Panel Properties - Panel 1 - PanelDepth: 40 mm; PanelOperation: SWINGING; PanelWidth: 0.507895; PanelPosition: RIGHT
Type - Door Panel Properties - Panel 2 - PanelDepth: 40 mm; PanelOperation: SWINGING; PanelWidth: 0.507895; PanelPosition: LEFT
OverallHeight: 2200 mm; OverallWidth: 1600 mm; Classification: 1.9 IfcDoor (uks) (_RKAS BIM + ARCHICAD Classification); 52 Siseuksed (EHITUSKULUDE LIIGITAMINE EVS 885:2005)
Avatäited - 18 Viimistlus: RAL 9003; 01 Nimetus: Siseuks; 02 Materjal: Alumiiniumprofiil pulbervärvitud; 03 Tähistus: SU-A223 1 600×2 200; 04 Avamõõdu geomeetria: 1 600×2 200; 05 Asukoha info: Interior; 06 Soojusläbivus: -; 07 Helipidavus: 30 dB; 08 Veepidavus: -; 09 Õhuläbilaskvus: -; 10 Tulekindlus: nõudeid ei esitata; 11 Vastupanu tulekoormusele: -; 12 Klaaspakett: Karastatud ja lamineeritud kirgas klaas; 13 Klaasingu erisused: -; 14 Päikesekiirgus tegur (g-väärtus): -; 15 Avanemine: Avanemine: "R" (L - vasak; R - parem); 16 Liigendatus: Lävepakk madal max 25mm, roostevaba; 17 Sulused, lukustus: vt lukustuse spetsifikatsioon; 19 Mudel või toote tunnus: Undefined; 20 Tootja: Undefined; 21 Tooteinfo: Undefined; 22 Kasutus- ja hooldusjuhend: Undefined
Pset_DoorCommon - ThermalTransmittance: 0; GlazingAreaFraction: 2.14157; IsExternal: no
AC_Pset_RenovationAndPhasing - Renovation Status: New

# IfcDoor: SU-B101 900×2 000, Siseuks * Door 22
In: 1 KORRUS
Type - OperationType: SINGLE_SWING_RIGHT; ParameterTakesPrecedence: no; Sizeable: no
Type - Door Lining Properties - LiningDepth: 115 mm; LiningThickness: 40 mm; LiningOffset: -25 mm; CasingThickness: 50 mm; CasingDepth: 19 mm
Type - Door Panel Properties - Panel 1 - PanelDepth: 40 mm; PanelOperation: SWINGING; PanelWidth: 1; PanelPosition: MIDDLE
Description: Alumiinium, klaas; OverallHeight: 2000 mm; OverallWidth: 900 mm; Classification: 1.9 IfcDoor (uks) (_RKAS BIM + ARCHICAD Classification); 52 Siseuksed (EHITUSKULUDE LIIGITAMINE EVS 885:2005)
Pset_DoorCommon - FireRating: EI30; ThermalTransmittance: 0; GlazingAreaFraction: 0; IsExternal: no
Avatäited - 18 Viimistlus: RAL 9003; 01 Nimetus: Siseuks; 02 Materjal: Sile uks; 03 Tähistus: SU-B101 900×2 000; 04 Avamõõdu geomeetria: 900×2 000; 05 Asukoha info: Interior; 06 Soojusläbivus: -; 07 Helipidavus: 30 dB; 08 Veepidavus: -; 09 Õhuläbilaskvus: -; 10 Tulekindlus: EI 30; 11 Vastupanu tulekoormusele: -; 12 Klaaspakett: -; 13 Klaasingu erisused: -; 14 Päikesekiirgus tegur (g-väärtus): -; 15 Avanemine: Avanemine: "L" (L - vasak; R - parem); 16 Liigendatus: Lävepakk madal max 25mm, roostevaba; 17 Sulused, lukustus: lukustuse spetsifikatsioon; 19 Mudel või toote tunnus: Undefined; 20 Tootja: Undefined; 21 Tooteinfo: Undefined; 22 Kasutus- ja hooldusjuhend: Undefined
AC_Pset_RenovationAndPhasing - Renovation Status: New

# IfcDoor: SU-B102 900×2 100, Siseuks * Door 22
In: 1 KORRUS
Type - OperationType: SINGLE_SWING_LEFT; ParameterTakesPrecedence: no; Sizeable: no
Type - Door Lining Properties - LiningDepth: 115 mm; LiningThickness: 40 mm; LiningOffset: 150 mm; CasingThickness: 50 mm; CasingDepth: 19 mm
Type - Door Panel Properties - Panel 1 - PanelDepth: 40 mm; PanelOperation: SWINGING; PanelWidth: 1; PanelPosition: MIDDLE
OverallHeight: 2100 mm; OverallWidth: 900 mm; Classification: 1.9 IfcDoor (uks) (_RKAS BIM + ARCHICAD Classification); 52 Siseuksed (EHITUSKULUDE LIIGITAMINE EVS 885:2005)
Avatäited - 18 Viimistlus: RAL 9003; 01 Nimetus: Siseuks; 02 Materjal: Sile uks; 03 Tähistus: SU-B102 900×2 100; 04 Avamõõdu geomeetria: 900×2 100; 05 Asukoha info: Interior; 06 Soojusläbivus: -; 07 Helipidavus: 30 dB; 08 Veepidavus: -; 09 Õhuläbilaskvus: -; 10 Tulekindlus: nõudeid ei esitata; 11 Vastupanu tulekoormusele: -; 12 Klaaspakett: -; 13 Klaasingu erisused: -; 14 Päikesekiirgus tegur (g-väärtus): -; 15 Avanemine: Avanemine: "R" (L - vasak; R - parem); 16 Liigendatus: Lävepakk madal max 25mm, roostevaba; 17 Sulused, lukustus: lukustuse spetsifikatsioon; 19 Mudel või toote tunnus: Undefined; 20 Tootja: Undefined; 21 Tooteinfo: Undefined; 22 Kasutus- ja hooldusjuhend: Undefined
Pset_DoorCommon - ThermalTransmittance: 0; GlazingAreaFraction: 0; IsExternal: no
AC_Pset_RenovationAndPhasing - Renovation Status: New

# IfcDoor: SU-B104 800×2 000, Siseuks * Door 22
In: 1 KORRUS
Type - OperationType: SINGLE_SWING_RIGHT; ParameterTakesPrecedence: no; Sizeable: no
Type - Door Lining Properties - LiningDepth: 115 mm; LiningThickness: 40 mm; LiningOffset: 0 mm; CasingThickness: 50 mm; CasingDepth: 19 mm
Type - Door Panel Properties - Panel 1 - PanelDepth: 40 mm; PanelOperation: SWINGING; PanelWidth: 1; PanelPosition: MIDDLE
OverallHeight: 2000 mm; OverallWidth: 800 mm; Classification: 1.9 IfcDoor (uks) (_RKAS BIM + ARCHICAD Classification); 52 Siseuksed (EHITUSKULUDE LIIGITAMINE EVS 885:2005)
Avatäited - 18 Viimistlus: RAL 9003; 01 Nimetus: Siseuks; 02 Materjal: Sile uks; 03 Tähistus: SU-B104 800×2 000; 04 Avamõõdu geomeetria: 800×2 000; 05 Asukoha info: Interior; 06 Soojusläbivus: -; 07 Helipidavus: 30 dB; 08 Veepidavus: -; 09 Õhuläbilaskvus: -; 10 Tulekindlus: nõudeid ei esitata; 11 Vastupanu tulekoormusele: -; 12 Klaaspakett: -; 13 Klaasingu erisused: -; 14 Päikesekiirgus tegur (g-väärtus): -; 15 Avanemine: Avanemine: "L" (L - vasak; R - parem); 16 Liigendatus: Tuulutatav lävepakk; 17 Sulused, lukustus: lukustuse spetsifikatsioon; 19 Mudel või toote tunnus: Undefined; 20 Tootja: Undefined; 21 Tooteinfo: Undefined; 22 Kasutus- ja hooldusjuhend: Undefined
Pset_DoorCommon - ThermalTransmittance: 0; GlazingAreaFraction: 0; IsExternal: no
AC_Pset_RenovationAndPhasing - Renovation Status: New

# IfcDoor: SU-B104A 700×1 900, Siseuks * Door 22
In: 1 KORRUS
Type - OperationType: SINGLE_SWING_LEFT; ParameterTakesPrecedence: no; Sizeable: no
Type - Door Lining Properties - LiningDepth: 115 mm; LiningThickness: 40 mm; LiningOffset: 200 mm; CasingThickness: 50 mm; CasingDepth: 19 mm
Type - Door Panel Properties - Panel 1 - PanelDepth: 40 mm; PanelOperation: SWINGING; PanelWidth: 1; PanelPosition: MIDDLE
OverallHeight: 1900 mm; OverallWidth: 700 mm; Classification: 1.9 IfcDoor (uks) (_RKAS BIM + ARCHICAD Classification); 52 Siseuksed (EHITUSKULUDE LIIGITAMINE EVS 885:2005)
Avatäited - 18 Viimistlus: RAL 9003; 01 Nimetus: Siseuks; 02 Materjal: Sile uks; 03 Tähistus: SU-B104A 700×1 900; 04 Avamõõdu geomeetria: 700×1 900; 05 Asukoha info: Interior; 06 Soojusläbivus: -; 07 Helipidavus: 30 dB; 08 Veepidavus: -; 09 Õhuläbilaskvus: -; 10 Tulekindlus: nõudeid ei esitata; 11 Vastupanu tulekoormusele: -; 12 Klaaspakett: -; 13 Klaasingu erisused: -; 14 Päikesekiirgus tegur (g-väärtus): -; 15 Avanemine: Avanemine: "R" (L - vasak; R - parem); 16 Liigendatus: Tuulutatav lävepakk; 17 Sulused, lukustus: lukustuse spetsifikatsioon; 19 Mudel või toote tunnus: Undefined; 20 Tootja: Undefined; 21 Tooteinfo: Undefined; 22 Kasutus- ja hooldusjuhend: Undefined
Pset_DoorCommon - ThermalTransmittance: 0; GlazingAreaFraction: 0; IsExternal: no
AC_Pset_RenovationAndPhasing - Renovation Status: New

# IfcDoor: SU-B105 800×2 000, Siseuks * Door 22
In: 1 KORRUS
Type - OperationType: SINGLE_SWING_LEFT; ParameterTakesPrecedence: no; Sizeable: no
Type - Door Lining Properties - LiningDepth: 115 mm; LiningThickness: 40 mm; LiningOffset: 0 mm; CasingThickness: 50 mm; CasingDepth: 19 mm
Type - Door Panel Properties - Panel 1 - PanelDepth: 40 mm; PanelOperation: SWINGING; PanelWidth: 1; PanelPosition: MIDDLE
OverallHeight: 2000 mm; OverallWidth: 800 mm; Classification: 1.9 IfcDoor (uks) (_RKAS BIM + ARCHICAD Classification); 52 Siseuksed (EHITUSKULUDE LIIGITAMINE EVS 885:2005)
Avatäited - 18 Viimistlus: RAL 9003; 01 Nimetus: Siseuks; 02 Materjal: Sile uks; 03 Tähistus: SU-B105 800×2 000; 04 Avamõõdu geomeetria: 800×2 000; 05 Asukoha info: Interior; 06 Soojusläbivus: -; 07 Helipidavus: 30 dB; 08 Veepidavus: -; 09 Õhuläbilaskvus: -; 10 Tulekindlus: nõudeid ei esitata; 11 Vastupanu tulekoormusele: -; 12 Klaaspakett: -; 13 Klaasingu erisused: -; 14 Päikesekiirgus tegur (g-väärtus): -; 15 Avanemine: Avanemine: "R" (L - vasak; R - parem); 16 Liigendatus: Tuulutatav lävepakk; 17 Sulused, lukustus: lukustuse spetsifikatsioon; 19 Mudel või toote tunnus: Undefined; 20 Tootja: Undefined; 21 Tooteinfo: Undefined; 22 Kasutus- ja hooldusjuhend: Undefined
Pset_DoorCommon - ThermalTransmittance: 0; GlazingAreaFraction: 0; IsExternal: no
AC_Pset_RenovationAndPhasing - Renovation Status: New

# IfcDoor: SU-B106 900×2 000, Siseuks * Door 22
In: 1 KORRUS
Type - OperationType: SINGLE_SWING_LEFT; ParameterTakesPrecedence: no; Sizeable: no
Type - Door Lining Properties - LiningDepth: 115 mm; LiningThickness: 40 mm; LiningOffset: 0 mm; CasingThickness: 50 mm; CasingDepth: 19 mm
Type - Door Panel Properties - Panel 1 - PanelDepth: 40 mm; PanelOperation: SWINGING; PanelWidth: 1; PanelPosition: MIDDLE
Description: Teras; OverallHeight: 2000 mm; OverallWidth: 900 mm; Classification: 1.9 IfcDoor (uks) (_RKAS BIM + ARCHICAD Classification); 52 Siseuksed (EHITUSKULUDE LIIGITAMINE EVS 885:2005)
Pset_DoorCommon - FireRating: EI30; ThermalTransmittance: 0; GlazingAreaFraction: 0; IsExternal: no
Avatäited - 18 Viimistlus: RAL 9003; 01 Nimetus: Siseuks; 02 Materjal: Sile uks; 03 Tähistus: SU-B106 900×2 000; 04 Avamõõdu geomeetria: 900×2 000; 05 Asukoha info: Interior; 06 Soojusläbivus: -; 07 Helipidavus: 30 dB; 08 Veepidavus: -; 09 Õhuläbilaskvus: -; 10 Tulekindlus: EI 30; 11 Vastupanu tulekoormusele: -; 12 Klaaspakett: -; 13 Klaasingu erisused: -; 14 Päikesekiirgus tegur (g-väärtus): -; 15 Avanemine: Avanemine: "R" (L - vasak; R - parem); 16 Liigendatus: Lävepakk madal max 25mm, roostevaba; 17 Sulused, lukustus: lukustuse spetsifikatsioon; 19 Mudel või toote tunnus: Undefined; 20 Tootja: Undefined; 21 Tooteinfo: Undefined; 22 Kasutus- ja hooldusjuhend: Undefined
AC_Pset_RenovationAndPhasing - Renovation Status: New

# IfcDoor: SU-B107 2 500×2 100, Siseuks * Double Door 22
In: 1 KORRUS
Type - OperationType: DOUBLE_DOOR_SINGLE_SWING; ParameterTakesPrecedence: no; Sizeable: no
Type - Door Lining Properties - LiningDepth: 115 mm; LiningThickness: 40 mm; LiningOffset: 420 mm; CasingThickness: 50 mm; CasingDepth: 19 mm
Type - Door Panel Properties - Panel 1 - PanelDepth: 40 mm; PanelOperation: SWINGING; PanelWidth: 0.504959; PanelPosition: RIGHT
Type - Door Panel Properties - Panel 2 - PanelDepth: 40 mm; PanelOperation: SWINGING; PanelWidth: 0.504959; PanelPosition: LEFT
OverallHeight: 2100 mm; OverallWidth: 2500 mm; Classification: 1.9 IfcDoor (uks) (_RKAS BIM + ARCHICAD Classification); 52 Siseuksed (EHITUSKULUDE LIIGITAMINE EVS 885:2005)
Avatäited - 18 Viimistlus: RAL 9003; 01 Nimetus: Siseuks; 02 Materjal: Sile uks; 03 Tähistus: SU-B107 2 500×2 100; 04 Avamõõdu geomeetria: 2 500×2 100; 05 Asukoha info: Interior; 06 Soojusläbivus: -; 07 Helipidavus: 30 dB; 08 Veepidavus: -; 09 Õhuläbilaskvus: -; 10 Tulekindlus: nõudeid ei esitata; 11 Vastupanu tulekoormusele: -; 12 Klaaspakett: -; 13 Klaasingu erisused: -; 14 Päikesekiirgus tegur (g-väärtus): -; 15 Avanemine: Avanemine: "R" (L - vasak; R - parem); 16 Liigendatus: Lävepakk madal max 25mm, roostevaba; 17 Sulused, lukustus: lukustuse spetsifikatsioon; 19 Mudel või toote tunnus: Undefined; 20 Tootja: Undefined; 21 Tooteinfo: Undefined; 22 Kasutus- ja hooldusjuhend: Undefined
Pset_DoorCommon - ThermalTransmittance: 0; GlazingAreaFraction: 0; IsExternal: no
AC_Pset_RenovationAndPhasing - Renovation Status: New

# IfcDoor: SU-B108 950×2 100, Siseuks * Door 22
In: 1 KORRUS
Type - OperationType: SINGLE_SWING_LEFT; ParameterTakesPrecedence: no; Sizeable: no
Type - Door Lining Properties - LiningDepth: 115 mm; LiningThickness: 40 mm; LiningOffset: 0 mm; CasingThickness: 50 mm; CasingDepth: 19 mm
Type - Door Panel Properties - Panel 1 - PanelDepth: 40 mm; PanelOperation: SWINGING; PanelWidth: 1; PanelPosition: MIDDLE
OverallHeight: 2100 mm; OverallWidth: 950 mm; Classification: 1.9 IfcDoor (uks) (_RKAS BIM + ARCHICAD Classification); 52 Siseuksed (EHITUSKULUDE LIIGITAMINE EVS 885:2005)
Avatäited - 18 Viimistlus: RAL 9003; 01 Nimetus: Siseuks; 02 Materjal: Sile uks; 03 Tähistus: SU-B108 950×2 100; 04 Avamõõdu geomeetria: 950×2 100; 05 Asukoha info: Interior; 06 Soojusläbivus: -; 07 Helipidavus: 30 dB; 08 Veepidavus: -; 09 Õhuläbilaskvus: -; 10 Tulekindlus: nõudeid ei esitata; 11 Vastupanu tulekoormusele: -; 12 Klaaspakett: -; 13 Klaasingu erisused: -; 14 Päikesekiirgus tegur (g-väärtus): -; 15 Avanemine: Avanemine: "R" (L - vasak; R - parem); 16 Liigendatus: Lävepakk madal max 25mm, roostevaba; 17 Sulused, lukustus: lukustuse spetsifikatsioon; 19 Mudel või toote tunnus: Undefined; 20 Tootja: Undefined; 21 Tooteinfo: Undefined; 22 Kasutus- ja hooldusjuhend: Undefined
Pset_DoorCommon - ThermalTransmittance: 0; GlazingAreaFraction: 0; IsExternal: no
AC_Pset_RenovationAndPhasing - Renovation Status: New

# IfcDoor: SU-B108A 900×2 000, Siseuks * Door 22
In: 1 KORRUS
Type - OperationType: SINGLE_SWING_LEFT; ParameterTakesPrecedence: no; Sizeable: no
Type - Door Lining Properties - LiningDepth: 115 mm; LiningThickness: 40 mm; LiningOffset: 395 mm; CasingThickness: 50 mm; CasingDepth: 19 mm
Type - Door Panel Properties - Panel 1 - PanelDepth: 40 mm; PanelOperation: SWINGING; PanelWidth: 1; PanelPosition: MIDDLE
Description: Teras; OverallHeight: 2000 mm; OverallWidth: 900 mm; Classification: 1.9 IfcDoor (uks) (_RKAS BIM + ARCHICAD Classification); 52 Siseuksed (EHITUSKULUDE LIIGITAMINE EVS 885:2005)
Pset_DoorCommon - FireRating: EI30; ThermalTransmittance: 0; GlazingAreaFraction: 0; IsExternal: no
Avatäited - 18 Viimistlus: RAL 9003; 01 Nimetus: Siseuks; 02 Materjal: Sile uks; 03 Tähistus: SU-B108A 900×2 000; 04 Avamõõdu geomeetria: 900×2 000; 05 Asukoha info: Interior; 06 Soojusläbivus: -; 07 Helipidavus: 30 dB; 08 Veepidavus: -; 09 Õhuläbilaskvus: -; 10 Tulekindlus: EI 30; 11 Vastupanu tulekoormusele: -; 12 Klaaspakett: -; 13 Klaasingu erisused: -; 14 Päikesekiirgus tegur (g-väärtus): -; 15 Avanemine: Avanemine: "R" (L - vasak; R - parem); 16 Liigendatus: Lävepakk madal max 25mm, roostevaba; 17 Sulused, lukustus: lukustuse spetsifikatsioon; 19 Mudel või toote tunnus: Undefined; 20 Tootja: Undefined; 21 Tooteinfo: Undefined; 22 Kasutus- ja hooldusjuhend: Undefined
AC_Pset_RenovationAndPhasing - Renovation Status: New

# IfcDoor: SU-B109 1 000×2 000, Siseuks * Door 22
In: 1 KORRUS
Type - OperationType: SINGLE_SWING_LEFT; ParameterTakesPrecedence: no; Sizeable: no
Type - Door Lining Properties - LiningDepth: 115 mm; LiningThickness: 40 mm; LiningOffset: 420 mm; CasingThickness: 50 mm; CasingDepth: 19 mm
Type - Door Panel Properties - Panel 1 - PanelDepth: 40 mm; PanelOperation: SWINGING; PanelWidth: 1; PanelPosition: MIDDLE
Description: Teras; OverallHeight: 2000 mm; OverallWidth: 1000 mm; Classification: 1.9 IfcDoor (uks) (_RKAS BIM + ARCHICAD Classification); 52 Siseuksed (EHITUSKULUDE LIIGITAMINE EVS 885:2005)
Pset_FireRatingProperties - FireResistanceRating: EI30
Pset_DoorCommon - FireRating: EI30; ThermalTransmittance: 0; GlazingAreaFraction: 0; IsExternal: no
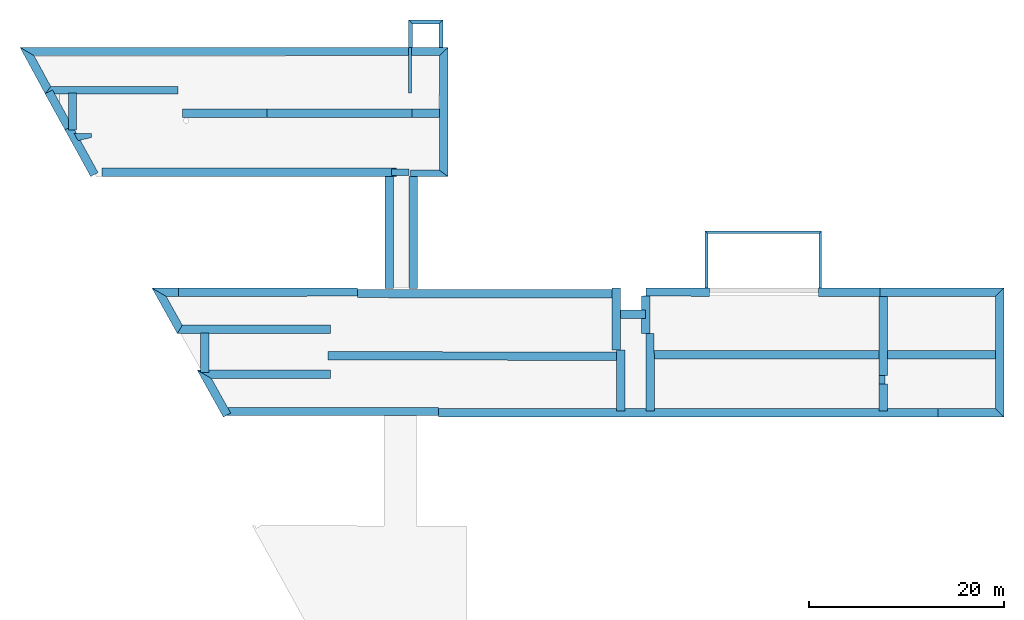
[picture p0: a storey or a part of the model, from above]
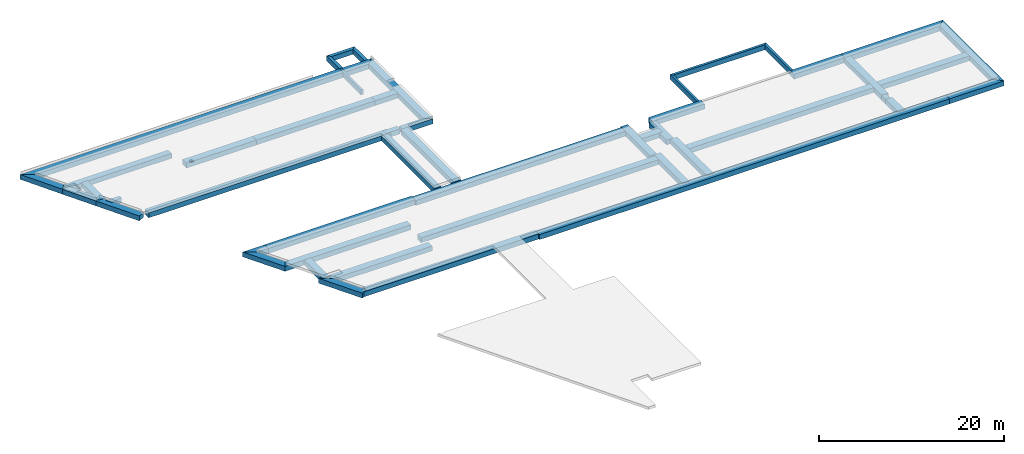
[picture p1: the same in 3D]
Properties of the parts of a building model (IFC2X3), part 7 of 14

# IfcDoor: SU-B109 1 000×2 000, Siseuks * Door 22
Avatäited - 18 Viimistlus: RAL 9003; 01 Nimetus: Siseuks; 02 Materjal: Sile uks; 03 Tähistus: SU-B109 1 000×2 000; 04 Avamõõdu geomeetria: 1 000×2 000; 05 Asukoha info: Interior; 06 Soojusläbivus: -; 07 Helipidavus: 30 dB; 08 Veepidavus: -; 09 Õhuläbilaskvus: -; 10 Tulekindlus: EI 30; 11 Vastupanu tulekoormusele: -; 12 Klaaspakett: -; 13 Klaasingu erisused: -; 14 Päikesekiirgus tegur (g-väärtus): -; 15 Avanemine: Avanemine: "R" (L - vasak; R - parem); 16 Liigendatus: Lävepakk madal max 25mm, roostevaba; 17 Sulused, lukustus: lukustuse spetsifikatsioon; 19 Mudel või toote tunnus: Undefined; 20 Tootja: Undefined; 21 Tooteinfo: Undefined; 22 Kasutus- ja hooldusjuhend: Undefined
AC_Pset_RenovationAndPhasing - Renovation Status: New

# IfcDoor: SU-B110 900×2 000, Siseuks * Door 22
In: 1 KORRUS
Type - OperationType: SINGLE_SWING_LEFT; ParameterTakesPrecedence: no; Sizeable: no
Type - Door Lining Properties - LiningDepth: 115 mm; LiningThickness: 40 mm; LiningOffset: 420 mm; CasingThickness: 50 mm; CasingDepth: 19 mm
Type - Door Panel Properties - Panel 1 - PanelDepth: 40 mm; PanelOperation: SWINGING; PanelWidth: 1; PanelPosition: MIDDLE
OverallHeight: 2000 mm; OverallWidth: 900 mm; Classification: 1.9 IfcDoor (uks) (_RKAS BIM + ARCHICAD Classification); 52 Siseuksed (EHITUSKULUDE LIIGITAMINE EVS 885:2005)
Avatäited - 18 Viimistlus: RAL 9003; 01 Nimetus: Siseuks; 02 Materjal: Sile uks; 03 Tähistus: SU-B110 900×2 000; 04 Avamõõdu geomeetria: 900×2 000; 05 Asukoha info: Interior; 06 Soojusläbivus: -; 07 Helipidavus: 30 dB; 08 Veepidavus: -; 09 Õhuläbilaskvus: -; 10 Tulekindlus: nõudeid ei esitata; 11 Vastupanu tulekoormusele: -; 12 Klaaspakett: -; 13 Klaasingu erisused: -; 14 Päikesekiirgus tegur (g-väärtus): -; 15 Avanemine: Avanemine: "R" (L - vasak; R - parem); 16 Liigendatus: Tuulutatav lävepakk; 17 Sulused, lukustus: lukustuse spetsifikatsioon; 19 Mudel või toote tunnus: Undefined; 20 Tootja: Undefined; 21 Tooteinfo: Undefined; 22 Kasutus- ja hooldusjuhend: Undefined
Pset_DoorCommon - ThermalTransmittance: 0; GlazingAreaFraction: 0; IsExternal: no
AC_Pset_RenovationAndPhasing - Renovation Status: New

# IfcDoor: SU-B111 700×2 000, Siseuks * Door 22
In: 1 KORRUS
Type - OperationType: SINGLE_SWING_LEFT; ParameterTakesPrecedence: no; Sizeable: no
Type - Door Lining Properties - LiningDepth: 115 mm; LiningThickness: 40 mm; LiningOffset: 100 mm; CasingThickness: 50 mm; CasingDepth: 19 mm
Type - Door Panel Properties - Panel 1 - PanelDepth: 40 mm; PanelOperation: SWINGING; PanelWidth: 1; PanelPosition: MIDDLE
OverallHeight: 2000 mm; OverallWidth: 700 mm; Classification: 1.9 IfcDoor (uks) (_RKAS BIM + ARCHICAD Classification); 52 Siseuksed (EHITUSKULUDE LIIGITAMINE EVS 885:2005)
Avatäited - 18 Viimistlus: RAL 9003; 01 Nimetus: Siseuks; 02 Materjal: Sile uks; 03 Tähistus: SU-B111 700×2 000; 04 Avamõõdu geomeetria: 700×2 000; 05 Asukoha info: Interior; 06 Soojusläbivus: -; 07 Helipidavus: 30 dB; 08 Veepidavus: -; 09 Õhuläbilaskvus: -; 10 Tulekindlus: nõudeid ei esitata; 11 Vastupanu tulekoormusele: -; 12 Klaaspakett: -; 13 Klaasingu erisused: -; 14 Päikesekiirgus tegur (g-väärtus): -; 15 Avanemine: Avanemine: "R" (L - vasak; R - parem); 16 Liigendatus: Lävepakk madal max 25mm, roostevaba; 17 Sulused, lukustus: lukustuse spetsifikatsioon; 19 Mudel või toote tunnus: Undefined; 20 Tootja: Undefined; 21 Tooteinfo: Undefined; 22 Kasutus- ja hooldusjuhend: Undefined
Pset_DoorCommon - ThermalTransmittance: 0; GlazingAreaFraction: 0; IsExternal: no
AC_Pset_RenovationAndPhasing - Renovation Status: New

# IfcDoor: SU-B112 900×2 000, Siseuks * Door 22
In: 1 KORRUS
Type - OperationType: SINGLE_SWING_LEFT; ParameterTakesPrecedence: no; Sizeable: no
Type - Door Lining Properties - LiningDepth: 115 mm; LiningThickness: 40 mm; LiningOffset: 420 mm; CasingThickness: 50 mm; CasingDepth: 19 mm
Type - Door Panel Properties - Panel 1 - PanelDepth: 40 mm; PanelOperation: SWINGING; PanelWidth: 1; PanelPosition: MIDDLE
OverallHeight: 2000 mm; OverallWidth: 900 mm; Classification: 1.9 IfcDoor (uks) (_RKAS BIM + ARCHICAD Classification); 52 Siseuksed (EHITUSKULUDE LIIGITAMINE EVS 885:2005)
Avatäited - 18 Viimistlus: RAL 9003; 01 Nimetus: Siseuks; 02 Materjal: Sile uks; 03 Tähistus: SU-B112 900×2 000; 04 Avamõõdu geomeetria: 900×2 000; 05 Asukoha info: Interior; 06 Soojusläbivus: -; 07 Helipidavus: 30 dB; 08 Veepidavus: -; 09 Õhuläbilaskvus: -; 10 Tulekindlus: nõudeid ei esitata; 11 Vastupanu tulekoormusele: -; 12 Klaaspakett: -; 13 Klaasingu erisused: -; 14 Päikesekiirgus tegur (g-väärtus): -; 15 Avanemine: Avanemine: "R" (L - vasak; R - parem); 16 Liigendatus: Lävepakk madal max 25mm, roostevaba; 17 Sulused, lukustus: lukustuse spetsifikatsioon; 19 Mudel või toote tunnus: Undefined; 20 Tootja: Undefined; 21 Tooteinfo: Undefined; 22 Kasutus- ja hooldusjuhend: Undefined
Pset_DoorCommon - ThermalTransmittance: 0; GlazingAreaFraction: 0; IsExternal: no
AC_Pset_RenovationAndPhasing - Renovation Status: New

# IfcDoor: SU-B113 900×2 000, Siseuks * Door 22
In: 1 KORRUS
Type - OperationType: SINGLE_SWING_LEFT; ParameterTakesPrecedence: no; Sizeable: no
Type - Door Lining Properties - LiningDepth: 115 mm; LiningThickness: 40 mm; LiningOffset: 420 mm; CasingThickness: 50 mm; CasingDepth: 19 mm
Type - Door Panel Properties - Panel 1 - PanelDepth: 40 mm; PanelOperation: SWINGING; PanelWidth: 1; PanelPosition: MIDDLE
Description: Teras; OverallHeight: 2000 mm; OverallWidth: 900 mm; Classification: 1.9 IfcDoor (uks) (_RKAS BIM + ARCHICAD Classification); 52 Siseuksed (EHITUSKULUDE LIIGITAMINE EVS 885:2005)
Pset_FireRatingProperties - FireResistanceRating: EI30
Pset_DoorCommon - FireRating: EI30; ThermalTransmittance: 0; GlazingAreaFraction: 0; IsExternal: no
Avatäited - 18 Viimistlus: RAL 9003; 01 Nimetus: Siseuks; 02 Materjal: Sile uks; 03 Tähistus: SU-B113 900×2 000; 04 Avamõõdu geomeetria: 900×2 000; 05 Asukoha info: Interior; 06 Soojusläbivus: -; 07 Helipidavus: 30 dB; 08 Veepidavus: -; 09 Õhuläbilaskvus: -; 10 Tulekindlus: EI 30; 11 Vastupanu tulekoormusele: -; 12 Klaaspakett: -; 13 Klaasingu erisused: -; 14 Päikesekiirgus tegur (g-väärtus): -; 15 Avanemine: Avanemine: "R" (L - vasak; R - parem); 16 Liigendatus: Lävepakk madal max 25mm, roostevaba; 17 Sulused, lukustus: lukustuse spetsifikatsioon; 19 Mudel või toote tunnus: Undefined; 20 Tootja: Undefined; 21 Tooteinfo: Undefined; 22 Kasutus- ja hooldusjuhend: Undefined
AC_Pset_RenovationAndPhasing - Renovation Status: New

# IfcDoor: SU-B114 900×2 000, Siseuks * Door 22
In: 1 KORRUS
Type - OperationType: SINGLE_SWING_RIGHT; ParameterTakesPrecedence: no; Sizeable: no
Type - Door Lining Properties - LiningDepth: 115 mm; LiningThickness: 40 mm; LiningOffset: 420 mm; CasingThickness: 50 mm; CasingDepth: 19 mm
Type - Door Panel Properties - Panel 1 - PanelDepth: 40 mm; PanelOperation: SWINGING; PanelWidth: 1; PanelPosition: MIDDLE
Description: Teras; OverallHeight: 2000 mm; OverallWidth: 900 mm; Classification: 1.9 IfcDoor (uks) (_RKAS BIM + ARCHICAD Classification); 52 Siseuksed (EHITUSKULUDE LIIGITAMINE EVS 885:2005)
Pset_DoorCommon - FireRating: EI30; ThermalTransmittance: 0; GlazingAreaFraction: 0; IsExternal: no
Avatäited - 18 Viimistlus: RAL 9003; 01 Nimetus: Siseuks; 02 Materjal: Sile uks; 03 Tähistus: SU-B114 900×2 000; 04 Avamõõdu geomeetria: 900×2 000; 05 Asukoha info: Interior; 06 Soojusläbivus: -; 07 Helipidavus: 30 dB; 08 Veepidavus: -; 09 Õhuläbilaskvus: -; 10 Tulekindlus: EI 30; 11 Vastupanu tulekoormusele: -; 12 Klaaspakett: -; 13 Klaasingu erisused: -; 14 Päikesekiirgus tegur (g-väärtus): -; 15 Avanemine: Avanemine: "L" (L - vasak; R - parem); 16 Liigendatus: Lävepakk madal max 25mm, roostevaba; 17 Sulused, lukustus: lukustuse spetsifikatsioon; 19 Mudel või toote tunnus: Undefined; 20 Tootja: Undefined; 21 Tooteinfo: Undefined; 22 Kasutus- ja hooldusjuhend: Undefined
AC_Pset_RenovationAndPhasing - Renovation Status: New

# IfcDoor: SU-B115 1 300×2 100, Siseuks * Metal Double Door 22
In: 1 KORRUS
Type - OperationType: DOUBLE_DOOR_SINGLE_SWING; ParameterTakesPrecedence: no; Sizeable: no
Type - Door Lining Properties - LiningDepth: 100 mm; LiningThickness: 32 mm; LiningOffset: 150 mm; CasingThickness: 50 mm; CasingDepth: 19 mm
Type - Door Panel Properties - Panel 1 - PanelDepth: 40 mm; PanelOperation: SWINGING; PanelWidth: 0.776699; PanelPosition: LEFT
Type - Door Panel Properties - Panel 2 - PanelDepth: 40 mm; PanelOperation: SWINGING; PanelWidth: 0.242718; PanelPosition: RIGHT
Description: Teras; OverallHeight: 2100 mm; OverallWidth: 1300 mm; Classification: 1.9 IfcDoor (uks) (_RKAS BIM + ARCHICAD Classification); 52 Siseuksed (EHITUSKULUDE LIIGITAMINE EVS 885:2005)
Pset_DoorCommon - FireRating: EI30; ThermalTransmittance: 0; GlazingAreaFraction: 0; IsExternal: no
Avatäited - 18 Viimistlus: RAL 9003; 01 Nimetus: Siseuks; 02 Materjal: Sile uks; 03 Tähistus: SU-B115 1 300×2 100; 04 Avamõõdu geomeetria: 1 300×2 100; 05 Asukoha info: Interior; 06 Soojusläbivus: -; 07 Helipidavus: 30 dB; 08 Veepidavus: -; 09 Õhuläbilaskvus: -; 10 Tulekindlus: EI 30; 11 Vastupanu tulekoormusele: -; 12 Klaaspakett: -; 13 Klaasingu erisused: -; 14 Päikesekiirgus tegur (g-väärtus): -; 15 Avanemine: Avanemine: "L" (L - vasak; R - parem); 16 Liigendatus: Lävepakk madal max 25mm, roostevaba; 17 Sulused, lukustus: lukustuse spetsifikatsioon; 19 Mudel või toote tunnus: Undefined; 20 Tootja: Undefined; 21 Tooteinfo: Undefined; 22 Kasutus- ja hooldusjuhend: Undefined
AC_Pset_RenovationAndPhasing - Renovation Status: New

# IfcDoor: SU-B116 900×2 000, Siseuks * Door 22
In: 1 KORRUS
Type - OperationType: SINGLE_SWING_LEFT; ParameterTakesPrecedence: no; Sizeable: no
Type - Door Lining Properties - LiningDepth: 115 mm; LiningThickness: 40 mm; LiningOffset: 150 mm; CasingThickness: 50 mm; CasingDepth: 19 mm
Type - Door Panel Properties - Panel 1 - PanelDepth: 40 mm; PanelOperation: SWINGING; PanelWidth: 1; PanelPosition: MIDDLE
OverallHeight: 2000 mm; OverallWidth: 900 mm; Classification: 1.9 IfcDoor (uks) (_RKAS BIM + ARCHICAD Classification); 52 Siseuksed (EHITUSKULUDE LIIGITAMINE EVS 885:2005)
Pset_DoorCommon - FireRating: EI30; ThermalTransmittance: 0; GlazingAreaFraction: 0; IsExternal: no
Avatäited - 18 Viimistlus: RAL 9003; 01 Nimetus: Siseuks; 02 Materjal: Sile uks; 03 Tähistus: SU-B116 900×2 000; 04 Avamõõdu geomeetria: 900×2 000; 05 Asukoha info: Interior; 06 Soojusläbivus: -; 07 Helipidavus: 30 dB; 08 Veepidavus: -; 09 Õhuläbilaskvus: -; 10 Tulekindlus: EI 30; 11 Vastupanu tulekoormusele: -; 12 Klaaspakett: -; 13 Klaasingu erisused: -; 14 Päikesekiirgus tegur (g-väärtus): -; 15 Avanemine: Avanemine: "R" (L - vasak; R - parem); 16 Liigendatus: Lävepakk madal max 25mm, roostevaba; 17 Sulused, lukustus: lukustuse spetsifikatsioon; 19 Mudel või toote tunnus: Undefined; 20 Tootja: Undefined; 21 Tooteinfo: Undefined; 22 Kasutus- ja hooldusjuhend: Undefined
AC_Pset_RenovationAndPhasing - Renovation Status: New

# IfcDoor: SU-B117 900×2 000, Siseuks * Door 22
In: 1 KORRUS
Type - OperationType: SINGLE_SWING_LEFT; ParameterTakesPrecedence: no; Sizeable: no
Type - Door Lining Properties - LiningDepth: 115 mm; LiningThickness: 40 mm; LiningOffset: 420 mm; CasingThickness: 50 mm; CasingDepth: 19 mm
Type - Door Panel Properties - Panel 1 - PanelDepth: 40 mm; PanelOperation: SWINGING; PanelWidth: 1; PanelPosition: MIDDLE
OverallHeight: 2000 mm; OverallWidth: 900 mm; Classification: 1.9 IfcDoor (uks) (_RKAS BIM + ARCHICAD Classification); 52 Siseuksed (EHITUSKULUDE LIIGITAMINE EVS 885:2005)
Pset_DoorCommon - ThermalTransmittance: 0; GlazingAreaFraction: 0; IsExternal: no
Avatäited - 18 Viimistlus: RAL 9003; 01 Nimetus: Siseuks; 02 Materjal: Sile uks; 03 Tähistus: SU-B117 900×2 000; 04 Avamõõdu geomeetria: 900×2 000; 05 Asukoha info: Interior; 06 Soojusläbivus: -; 07 Helipidavus: 30 dB; 08 Veepidavus: -; 09 Õhuläbilaskvus: -; 10 Tulekindlus: nõudeid ei esitata; 11 Vastupanu tulekoormusele: -; 12 Klaaspakett: -; 13 Klaasingu erisused: -; 14 Päikesekiirgus tegur (g-väärtus): -; 15 Avanemine: Avanemine: "R" (L - vasak; R - parem); 16 Liigendatus: Lävepakk madal max 25mm, roostevaba; 17 Sulused, lukustus: lukustuse spetsifikatsioon; 19 Mudel või toote tunnus: Undefined; 20 Tootja: Undefined; 21 Tooteinfo: Undefined; 22 Kasutus- ja hooldusjuhend: Undefined
AC_Pset_RenovationAndPhasing - Renovation Status: New

# IfcDoor: SU-B118 900×2 000, Siseuks * Door 22
In: 1 KORRUS
Type - OperationType: SINGLE_SWING_LEFT; ParameterTakesPrecedence: no; Sizeable: no
Type - Door Lining Properties - LiningDepth: 115 mm; LiningThickness: 40 mm; LiningOffset: 420 mm; CasingThickness: 50 mm; CasingDepth: 19 mm
Type - Door Panel Properties - Panel 1 - PanelDepth: 40 mm; PanelOperation: SWINGING; PanelWidth: 1; PanelPosition: MIDDLE
OverallHeight: 2000 mm; OverallWidth: 900 mm; Classification: 1.9 IfcDoor (uks) (_RKAS BIM + ARCHICAD Classification); 52 Siseuksed (EHITUSKULUDE LIIGITAMINE EVS 885:2005)
Avatäited - 18 Viimistlus: RAL 9003; 01 Nimetus: Siseuks; 02 Materjal: Sile uks; 03 Tähistus: SU-B118 900×2 000; 04 Avamõõdu geomeetria: 900×2 000; 05 Asukoha info: Interior; 06 Soojusläbivus: -; 07 Helipidavus: 30 dB; 08 Veepidavus: -; 09 Õhuläbilaskvus: -; 10 Tulekindlus: nõudeid ei esitata; 11 Vastupanu tulekoormusele: -; 12 Klaaspakett: -; 13 Klaasingu erisused: -; 14 Päikesekiirgus tegur (g-väärtus): -; 15 Avanemine: Avanemine: "R" (L - vasak; R - parem); 16 Liigendatus: Lävepakk madal max 25mm, roostevaba; 17 Sulused, lukustus: lukustuse spetsifikatsioon; 19 Mudel või toote tunnus: Undefined; 20 Tootja: Undefined; 21 Tooteinfo: Undefined; 22 Kasutus- ja hooldusjuhend: Undefined
Pset_DoorCommon - ThermalTransmittance: 0; GlazingAreaFraction: 0; IsExternal: no
AC_Pset_RenovationAndPhasing - Renovation Status: New

# IfcDoor: SU-B120 900×2 100, Siseuks * Door 22
In: 1 KORRUS
Type - OperationType: SINGLE_SWING_LEFT; ParameterTakesPrecedence: no; Sizeable: no
Type - Door Lining Properties - LiningDepth: 115 mm; LiningThickness: 40 mm; LiningOffset: 150 mm; CasingThickness: 50 mm; CasingDepth: 19 mm
Type - Door Panel Properties - Panel 1 - PanelDepth: 40 mm; PanelOperation: SWINGING; PanelWidth: 1; PanelPosition: MIDDLE
OverallHeight: 2100 mm; OverallWidth: 900 mm; Classification: 1.9 IfcDoor (uks) (_RKAS BIM + ARCHICAD Classification); 52 Siseuksed (EHITUSKULUDE LIIGITAMINE EVS 885:2005)
Pset_DoorCommon - FireRating: EI30; ThermalTransmittance: 0; GlazingAreaFraction: 0; IsExternal: no
Avatäited - 18 Viimistlus: RAL 9003; 01 Nimetus: Siseuks; 02 Materjal: Sile uks; 03 Tähistus: SU-B120 900×2 100; 04 Avamõõdu geomeetria: 900×2 100; 05 Asukoha info: Interior; 06 Soojusläbivus: -; 07 Helipidavus: 30 dB; 08 Veepidavus: -; 09 Õhuläbilaskvus: -; 10 Tulekindlus: EI 30; 11 Vastupanu tulekoormusele: -; 12 Klaaspakett: -; 13 Klaasingu erisused: -; 14 Päikesekiirgus tegur (g-väärtus): -; 15 Avanemine: Avanemine: "R" (L - vasak; R - parem); 16 Liigendatus: Lävepakk madal max 25mm, roostevaba; 17 Sulused, lukustus: lukustuse spetsifikatsioon; 19 Mudel või toote tunnus: Undefined; 20 Tootja: Undefined; 21 Tooteinfo: Undefined; 22 Kasutus- ja hooldusjuhend: Undefined
AC_Pset_RenovationAndPhasing - Renovation Status: New

# IfcDoor: SU-B120A 800×2 000, Siseuks * Door 22
In: 1 KORRUS
Type - OperationType: SINGLE_SWING_LEFT; ParameterTakesPrecedence: no; Sizeable: no
Type - Door Lining Properties - LiningDepth: 115 mm; LiningThickness: 40 mm; LiningOffset: 115 mm; CasingThickness: 50 mm; CasingDepth: 19 mm
Type - Door Panel Properties - Panel 1 - PanelDepth: 40 mm; PanelOperation: SWINGING; PanelWidth: 1; PanelPosition: MIDDLE
OverallHeight: 2000 mm; OverallWidth: 800 mm; Classification: 1.9 IfcDoor (uks) (_RKAS BIM + ARCHICAD Classification); 52 Siseuksed (EHITUSKULUDE LIIGITAMINE EVS 885:2005)
Avatäited - 18 Viimistlus: RAL 9003; 01 Nimetus: Siseuks; 02 Materjal: Sile uks; 03 Tähistus: SU-B120A 800×2 000; 04 Avamõõdu geomeetria: 800×2 000; 05 Asukoha info: Interior; 06 Soojusläbivus: -; 07 Helipidavus: 30 dB; 08 Veepidavus: -; 09 Õhuläbilaskvus: -; 10 Tulekindlus: nõudeid ei esitata; 11 Vastupanu tulekoormusele: -; 12 Klaaspakett: -; 13 Klaasingu erisused: -; 14 Päikesekiirgus tegur (g-väärtus): -; 15 Avanemine: Avanemine: "R" (L - vasak; R - parem); 16 Liigendatus: Lävepakk madal max 25mm, roostevaba; 17 Sulused, lukustus: lukustuse spetsifikatsioon; 19 Mudel või toote tunnus: Undefined; 20 Tootja: Undefined; 21 Tooteinfo: Undefined; 22 Kasutus- ja hooldusjuhend: Undefined
Pset_DoorCommon - ThermalTransmittance: 0; GlazingAreaFraction: 0; IsExternal: no
AC_Pset_RenovationAndPhasing - Renovation Status: New

# IfcDoor: SU-B120B 700×2 000, Siseuks * Door 22
In: 1 KORRUS
Type - OperationType: SINGLE_SWING_LEFT; ParameterTakesPrecedence: no; Sizeable: no
Type - Door Lining Properties - LiningDepth: 115 mm; LiningThickness: 40 mm; LiningOffset: 395 mm; CasingThickness: 50 mm; CasingDepth: 19 mm
Type - Door Panel Properties - Panel 1 - PanelDepth: 40 mm; PanelOperation: SWINGING; PanelWidth: 1; PanelPosition: MIDDLE
OverallHeight: 2000 mm; OverallWidth: 700 mm; Classification: 1.9 IfcDoor (uks) (_RKAS BIM + ARCHICAD Classification); 52 Siseuksed (EHITUSKULUDE LIIGITAMINE EVS 885:2005)
Avatäited - 18 Viimistlus: RAL 9003; 01 Nimetus: Siseuks; 02 Materjal: Sile uks; 03 Tähistus: SU-B120B 700×2 000; 04 Avamõõdu geomeetria: 700×2 000; 05 Asukoha info: Interior; 06 Soojusläbivus: -; 07 Helipidavus: 30 dB; 08 Veepidavus: -; 09 Õhuläbilaskvus: -; 10 Tulekindlus: nõudeid ei esitata; 11 Vastupanu tulekoormusele: -; 12 Klaaspakett: -; 13 Klaasingu erisused: -; 14 Päikesekiirgus tegur (g-väärtus): -; 15 Avanemine: Avanemine: "R" (L - vasak; R - parem); 16 Liigendatus: Lävepakk madal max 25mm, roostevaba; 17 Sulused, lukustus: lukustuse spetsifikatsioon; 19 Mudel või toote tunnus: Undefined; 20 Tootja: Undefined; 21 Tooteinfo: Undefined; 22 Kasutus- ja hooldusjuhend: Undefined
Pset_DoorCommon - ThermalTransmittance: 0; GlazingAreaFraction: 0; IsExternal: no
AC_Pset_RenovationAndPhasing - Renovation Status: New

# IfcDoor: SU-B120C 750×2 000, Siseuks * Door 22
In: 1 KORRUS
Type - OperationType: SINGLE_SWING_LEFT; ParameterTakesPrecedence: no; Sizeable: no
Type - Door Lining Properties - LiningDepth: 115 mm; LiningThickness: 40 mm; LiningOffset: 420 mm; CasingThickness: 50 mm; CasingDepth: 19 mm
Type - Door Panel Properties - Panel 1 - PanelDepth: 40 mm; PanelOperation: SWINGING; PanelWidth: 1; PanelPosition: MIDDLE
OverallHeight: 2000 mm; OverallWidth: 750 mm; Classification: 1.9 IfcDoor (uks) (_RKAS BIM + ARCHICAD Classification); 52 Siseuksed (EHITUSKULUDE LIIGITAMINE EVS 885:2005)
Avatäited - 18 Viimistlus: RAL 9003; 01 Nimetus: Siseuks; 02 Materjal: Sile uks; 03 Tähistus: SU-B120C 750×2 000; 04 Avamõõdu geomeetria: 750×2 000; 05 Asukoha info: Interior; 06 Soojusläbivus: -; 07 Helipidavus: 30 dB; 08 Veepidavus: -; 09 Õhuläbilaskvus: -; 10 Tulekindlus: nõudeid ei esitata; 11 Vastupanu tulekoormusele: -; 12 Klaaspakett: -; 13 Klaasingu erisused: -; 14 Päikesekiirgus tegur (g-väärtus): -; 15 Avanemine: Avanemine: "R" (L - vasak; R - parem); 16 Liigendatus: Lävepakk madal max 25mm, roostevaba; 17 Sulused, lukustus: lukustuse spetsifikatsioon; 19 Mudel või toote tunnus: Undefined; 20 Tootja: Undefined; 21 Tooteinfo: Undefined; 22 Kasutus- ja hooldusjuhend: Undefined
Pset_DoorCommon - ThermalTransmittance: 0; GlazingAreaFraction: 0; IsExternal: no
AC_Pset_RenovationAndPhasing - Renovation Status: New

# IfcDoor: SU-B121 900×2 000, Siseuks * Door 22
In: 1 KORRUS
Type - OperationType: SINGLE_SWING_LEFT; ParameterTakesPrecedence: no; Sizeable: no
Type - Door Lining Properties - LiningDepth: 115 mm; LiningThickness: 40 mm; LiningOffset: 420 mm; CasingThickness: 50 mm; CasingDepth: 19 mm
Type - Door Panel Properties - Panel 1 - PanelDepth: 40 mm; PanelOperation: SWINGING; PanelWidth: 1; PanelPosition: MIDDLE
OverallHeight: 2000 mm; OverallWidth: 900 mm; Classification: 1.9 IfcDoor (uks) (_RKAS BIM + ARCHICAD Classification); 52 Siseuksed (EHITUSKULUDE LIIGITAMINE EVS 885:2005)
Avatäited - 18 Viimistlus: RAL 9003; 01 Nimetus: Siseuks; 02 Materjal: Sile uks; 03 Tähistus: SU-B121 900×2 000; 04 Avamõõdu geomeetria: 900×2 000; 05 Asukoha info: Interior; 06 Soojusläbivus: -; 07 Helipidavus: 30 dB; 08 Veepidavus: -; 09 Õhuläbilaskvus: -; 10 Tulekindlus: nõudeid ei esitata; 11 Vastupanu tulekoormusele: -; 12 Klaaspakett: -; 13 Klaasingu erisused: -; 14 Päikesekiirgus tegur (g-väärtus): -; 15 Avanemine: Avanemine: "R" (L - vasak; R - parem); 16 Liigendatus: Lävepakk madal max 25mm, roostevaba; 17 Sulused, lukustus: lukustuse spetsifikatsioon; 19 Mudel või toote tunnus: Undefined; 20 Tootja: Undefined; 21 Tooteinfo: Undefined; 22 Kasutus- ja hooldusjuhend: Undefined
Pset_DoorCommon - ThermalTransmittance: 0; GlazingAreaFraction: 0; IsExternal: no
AC_Pset_RenovationAndPhasing - Renovation Status: New

# IfcDoor: SU-B122 1 600×2 000, Siseuks * Double Door 22
In: 1 KORRUS
Type - OperationType: DOUBLE_DOOR_SINGLE_SWING; ParameterTakesPrecedence: no; Sizeable: no
Type - Door Lining Properties - LiningDepth: 115 mm; LiningThickness: 40 mm; LiningOffset: 150 mm; CasingThickness: 50 mm; CasingDepth: 19 mm
Type - Door Panel Properties - Panel 1 - PanelDepth: 40 mm; PanelOperation: SWINGING; PanelWidth: 0.423684; PanelPosition: RIGHT
Type - Door Panel Properties - Panel 2 - PanelDepth: 40 mm; PanelOperation: SWINGING; PanelWidth: 0.592105; PanelPosition: LEFT
Description: Alumiinium, klaas; OverallHeight: 2000 mm; OverallWidth: 1600 mm; Classification: 1.9 IfcDoor (uks) (_RKAS BIM + ARCHICAD Classification); 52 Siseuksed (EHITUSKULUDE LIIGITAMINE EVS 885:2005)
Pset_DoorCommon - FireRating: EI30; ThermalTransmittance: 0; GlazingAreaFraction: 1.91277; IsExternal: no
Avatäited - 18 Viimistlus: RAL 9003; 01 Nimetus: Siseuks; 02 Materjal: Alumiiniumprofiil pulbervärvitud; 03 Tähistus: SU-B122 1 600×2 000; 04 Avamõõdu geomeetria: 1 600×2 000; 05 Asukoha info: Interior; 06 Soojusläbivus: -; 07 Helipidavus: 30 dB; 08 Veepidavus: -; 09 Õhuläbilaskvus: -; 10 Tulekindlus: EI 30; 11 Vastupanu tulekoormusele: -; 12 Klaaspakett: Karastatud ja lamineeritud kirgas klaas; 13 Klaasingu erisused: -; 14 Päikesekiirgus tegur (g-väärtus): -; 15 Avanemine: Avanemine: "R" (L - vasak; R - parem); 16 Liigendatus: Lävepakk madal max 25mm, roostevaba; 17 Sulused, lukustus: lukustuse spetsifikatsioon; 19 Mudel või toote tunnus: Undefined; 20 Tootja: Undefined; 21 Tooteinfo: Undefined; 22 Kasutus- ja hooldusjuhend: Undefined
AC_Pset_RenovationAndPhasing - Renovation Status: New

# IfcDoor: SU-B123 900×2 000, Siseuks * Door 22
In: 1 KORRUS
Type - OperationType: SINGLE_SWING_RIGHT; ParameterTakesPrecedence: no; Sizeable: no
Type - Door Lining Properties - LiningDepth: 115 mm; LiningThickness: 40 mm; LiningOffset: 395 mm; CasingThickness: 50 mm; CasingDepth: 19 mm
Type - Door Panel Properties - Panel 1 - PanelDepth: 40 mm; PanelOperation: SWINGING; PanelWidth: 1; PanelPosition: MIDDLE
Description: Teras; OverallHeight: 2000 mm; OverallWidth: 900 mm; Classification: 1.9 IfcDoor (uks) (_RKAS BIM + ARCHICAD Classification); 52 Siseuksed (EHITUSKULUDE LIIGITAMINE EVS 885:2005)
Pset_DoorCommon - FireRating: EI30; ThermalTransmittance: 0; GlazingAreaFraction: 0; IsExternal: no
Avatäited - 18 Viimistlus: RAL 9003; 01 Nimetus: Siseuks; 02 Materjal: Sile uks; 03 Tähistus: SU-B123 900×2 000; 04 Avamõõdu geomeetria: 900×2 000; 05 Asukoha info: Interior; 06 Soojusläbivus: -; 07 Helipidavus: 30 dB; 08 Veepidavus: -; 09 Õhuläbilaskvus: -; 10 Tulekindlus: EI 30; 11 Vastupanu tulekoormusele: -; 12 Klaaspakett: -; 13 Klaasingu erisused: -; 14 Päikesekiirgus tegur (g-väärtus): -; 15 Avanemine: Avanemine: "L" (L - vasak; R - parem); 16 Liigendatus: Lävepakk madal max 25mm, roostevaba; 17 Sulused, lukustus: lukustuse spetsifikatsioon; 19 Mudel või toote tunnus: Undefined; 20 Tootja: Undefined; 21 Tooteinfo: Undefined; 22 Kasutus- ja hooldusjuhend: Undefined
AC_Pset_RenovationAndPhasing - Renovation Status: New

# IfcDoor: SU-B124 1 300×2 000, Siseuks * Metal Double Door 22
In: 1 KORRUS
Type - OperationType: DOUBLE_DOOR_SINGLE_SWING; ParameterTakesPrecedence: no; Sizeable: no
Type - Door Lining Properties - LiningDepth: 100 mm; LiningThickness: 32 mm; LiningOffset: 0 mm; CasingThickness: 50 mm; CasingDepth: 19 mm
Type - Door Panel Properties - Panel 1 - PanelDepth: 40 mm; PanelOperation: SWINGING; PanelWidth: 0.291262; PanelPosition: LEFT
Type - Door Panel Properties - Panel 2 - PanelDepth: 40 mm; PanelOperation: SWINGING; PanelWidth: 0.728155; PanelPosition: RIGHT
Description: Teras; OverallHeight: 2000 mm; OverallWidth: 1300 mm; Classification: 1.9 IfcDoor (uks) (_RKAS BIM + ARCHICAD Classification); 52 Siseuksed (EHITUSKULUDE LIIGITAMINE EVS 885:2005)
Pset_DoorCommon - FireRating: EI30; ThermalTransmittance: 0; GlazingAreaFraction: 0; IsExternal: no
Avatäited - 18 Viimistlus: RAL 9003; 01 Nimetus: Siseuks; 02 Materjal: Sile uks; 03 Tähistus: SU-B124 1 300×2 000; 04 Avamõõdu geomeetria: 1 300×2 000; 05 Asukoha info: Interior; 06 Soojusläbivus: -; 07 Helipidavus: 30 dB; 08 Veepidavus: -; 09 Õhuläbilaskvus: -; 10 Tulekindlus: EI 30; 11 Vastupanu tulekoormusele: -; 12 Klaaspakett: -; 13 Klaasingu erisused: -; 14 Päikesekiirgus tegur (g-väärtus): -; 15 Avanemine: Avanemine: "L" (L - vasak; R - parem); 16 Liigendatus: Lävepakk madal max 25mm, roostevaba; 17 Sulused, lukustus: lukustuse spetsifikatsioon; 19 Mudel või toote tunnus: Undefined; 20 Tootja: Undefined; 21 Tooteinfo: Undefined; 22 Kasutus- ja hooldusjuhend: Undefined
AC_Pset_RenovationAndPhasing - Renovation Status: New

# IfcDoor: SU-B125 1 000×2 100, Siseuks * Door 22
In: 1 KORRUS
Type - OperationType: SINGLE_SWING_LEFT; ParameterTakesPrecedence: no; Sizeable: no
Type - Door Lining Properties - LiningDepth: 115 mm; LiningThickness: 40 mm; LiningOffset: 200 mm; CasingThickness: 50 mm; CasingDepth: 19 mm
Type - Door Panel Properties - Panel 1 - PanelDepth: 40 mm; PanelOperation: SWINGING; PanelWidth: 1; PanelPosition: MIDDLE
OverallHeight: 2100 mm; OverallWidth: 1000 mm; Classification: 1.9 IfcDoor (uks) (_RKAS BIM + ARCHICAD Classification); 52 Siseuksed (EHITUSKULUDE LIIGITAMINE EVS 885:2005)
Pset_DoorCommon - ThermalTransmittance: 0; GlazingAreaFraction: 0; IsExternal: no
Avatäited - 18 Viimistlus: RAL 9003; 01 Nimetus: Siseuks; 02 Materjal: Sile uks; 03 Tähistus: SU-B125 1 000×2 100; 04 Avamõõdu geomeetria: 1 000×2 100; 05 Asukoha info: Interior; 06 Soojusläbivus: -; 07 Helipidavus: 30 dB; 08 Veepidavus: -; 09 Õhuläbilaskvus: -; 10 Tulekindlus: nõudeid ei esitata; 11 Vastupanu tulekoormusele: -; 12 Klaaspakett: -; 13 Klaasingu erisused: -; 14 Päikesekiirgus tegur (g-väärtus): -; 15 Avanemine: Avanemine: "R" (L - vasak; R - parem); 16 Liigendatus: Lävepakk madal max 25mm, roostevaba; 17 Sulused, lukustus: lukustuse spetsifikatsioon; 19 Mudel või toote tunnus: Undefined; 20 Tootja: Undefined; 21 Tooteinfo: Undefined; 22 Kasutus- ja hooldusjuhend: Undefined
AC_Pset_RenovationAndPhasing - Renovation Status: New

# IfcDoor: SU-B125A 900×2 000, Siseuks * Door 22
In: 1 KORRUS
Type - OperationType: SINGLE_SWING_LEFT; ParameterTakesPrecedence: no; Sizeable: no
Type - Door Lining Properties - LiningDepth: 115 mm; LiningThickness: 40 mm; LiningOffset: 200 mm; CasingThickness: 50 mm; CasingDepth: 19 mm
Type - Door Panel Properties - Panel 1 - PanelDepth: 40 mm; PanelOperation: SWINGING; PanelWidth: 1; PanelPosition: MIDDLE
OverallHeight: 2000 mm; OverallWidth: 900 mm; Classification: 1.9 IfcDoor (uks) (_RKAS BIM + ARCHICAD Classification); 52 Siseuksed (EHITUSKULUDE LIIGITAMINE EVS 885:2005)
Avatäited - 18 Viimistlus: RAL 9003; 01 Nimetus: Siseuks; 02 Materjal: Sile uks; 03 Tähistus: SU-B125A 900×2 000; 04 Avamõõdu geomeetria: 900×2 000; 05 Asukoha info: Interior; 06 Soojusläbivus: -; 07 Helipidavus: 30 dB; 08 Veepidavus: -; 09 Õhuläbilaskvus: -; 10 Tulekindlus: nõudeid ei esitata; 11 Vastupanu tulekoormusele: -; 12 Klaaspakett: -; 13 Klaasingu erisused: -; 14 Päikesekiirgus tegur (g-väärtus): -; 15 Avanemine: Avanemine: "R" (L - vasak; R - parem); 16 Liigendatus: Lävepakk madal max 25mm, roostevaba; 17 Sulused, lukustus: lukustuse spetsifikatsioon; 19 Mudel või toote tunnus: Undefined; 20 Tootja: Undefined; 21 Tooteinfo: Undefined; 22 Kasutus- ja hooldusjuhend: Undefined
Pset_DoorCommon - ThermalTransmittance: 0; GlazingAreaFraction: 0; IsExternal: no
AC_Pset_RenovationAndPhasing - Renovation Status: New

# IfcDoor: SU-B126 900×2 000, Siseuks * Door 22
In: 1 KORRUS
Type - OperationType: SINGLE_SWING_RIGHT; ParameterTakesPrecedence: no; Sizeable: no
Type - Door Lining Properties - LiningDepth: 115 mm; LiningThickness: 40 mm; LiningOffset: -25 mm; CasingThickness: 50 mm; CasingDepth: 19 mm
Type - Door Panel Properties - Panel 1 - PanelDepth: 40 mm; PanelOperation: SWINGING; PanelWidth: 1; PanelPosition: MIDDLE
OverallHeight: 2000 mm; OverallWidth: 900 mm; Classification: 1.9 IfcDoor (uks) (_RKAS BIM + ARCHICAD Classification); 52 Siseuksed (EHITUSKULUDE LIIGITAMINE EVS 885:2005)
Avatäited - 18 Viimistlus: RAL 9003; 01 Nimetus: Siseuks; 02 Materjal: Sile uks; 03 Tähistus: SU-B126 900×2 000; 04 Avamõõdu geomeetria: 900×2 000; 05 Asukoha info: Interior; 06 Soojusläbivus: -; 07 Helipidavus: 30 dB; 08 Veepidavus: -; 09 Õhuläbilaskvus: -; 10 Tulekindlus: nõudeid ei esitata; 11 Vastupanu tulekoormusele: -; 12 Klaaspakett: -; 13 Klaasingu erisused: -; 14 Päikesekiirgus tegur (g-väärtus): -; 15 Avanemine: Avanemine: "L" (L - vasak; R - parem); 16 Liigendatus: Tuulutatav lävepakk; 17 Sulused, lukustus: lukustuse spetsifikatsioon; 19 Mudel või toote tunnus: Undefined; 20 Tootja: Undefined; 21 Tooteinfo: Undefined; 22 Kasutus- ja hooldusjuhend: Undefined
Pset_DoorCommon - ThermalTransmittance: 0; GlazingAreaFraction: 0; IsExternal: no
AC_Pset_RenovationAndPhasing - Renovation Status: New

# IfcDoor: SU-B126A 700×2 000, Siseuks * Door 22
In: 1 KORRUS
Type - OperationType: SINGLE_SWING_LEFT; ParameterTakesPrecedence: no; Sizeable: no
Type - Door Lining Properties - LiningDepth: 115 mm; LiningThickness: 40 mm; LiningOffset: 115 mm; CasingThickness: 50 mm; CasingDepth: 19 mm
Type - Door Panel Properties - Panel 1 - PanelDepth: 40 mm; PanelOperation: SWINGING; PanelWidth: 1; PanelPosition: MIDDLE
OverallHeight: 2000 mm; OverallWidth: 700 mm; Classification: 1.9 IfcDoor (uks) (_RKAS BIM + ARCHICAD Classification); 52 Siseuksed (EHITUSKULUDE LIIGITAMINE EVS 885:2005)
Avatäited - 18 Viimistlus: RAL 9003; 01 Nimetus: Siseuks; 02 Materjal: Sile uks; 03 Tähistus: SU-B126A 700×2 000; 04 Avamõõdu geomeetria: 700×2 000; 05 Asukoha info: Interior; 06 Soojusläbivus: -; 07 Helipidavus: 30 dB; 08 Veepidavus: -; 09 Õhuläbilaskvus: -; 10 Tulekindlus: nõudeid ei esitata; 11 Vastupanu tulekoormusele: -; 12 Klaaspakett: -; 13 Klaasingu erisused: -; 14 Päikesekiirgus tegur (g-väärtus): -; 15 Avanemine: Avanemine: "R" (L - vasak; R - parem); 16 Liigendatus: Tuulutatav lävepakk; 17 Sulused, lukustus: lukustuse spetsifikatsioon; 19 Mudel või toote tunnus: Undefined; 20 Tootja: Undefined; 21 Tooteinfo: Undefined; 22 Kasutus- ja hooldusjuhend: Undefined
Pset_DoorCommon - ThermalTransmittance: 0; GlazingAreaFraction: 0; IsExternal: no
AC_Pset_RenovationAndPhasing - Renovation Status: New

# IfcDoor: SU-B126B 700×2 000, Siseuks * Door 22
In: 1 KORRUS
Type - OperationType: SINGLE_SWING_RIGHT; ParameterTakesPrecedence: no; Sizeable: no
Type - Door Lining Properties - LiningDepth: 115 mm; LiningThickness: 40 mm; LiningOffset: 100 mm; CasingThickness: 50 mm; CasingDepth: 19 mm
Type - Door Panel Properties - Panel 1 - PanelDepth: 40 mm; PanelOperation: SWINGING; PanelWidth: 1; PanelPosition: MIDDLE
OverallHeight: 2000 mm; OverallWidth: 700 mm; Classification: 1.9 IfcDoor (uks) (_RKAS BIM + ARCHICAD Classification); 52 Siseuksed (EHITUSKULUDE LIIGITAMINE EVS 885:2005)
Avatäited - 18 Viimistlus: RAL 9003; 01 Nimetus: Siseuks; 02 Materjal: Sile uks; 03 Tähistus: SU-B126B 700×2 000; 04 Avamõõdu geomeetria: 700×2 000; 05 Asukoha info: Interior; 06 Soojusläbivus: -; 07 Helipidavus: 30 dB; 08 Veepidavus: niiskuskindel uks; 09 Õhuläbilaskvus: -; 10 Tulekindlus: nõudeid ei esitata; 11 Vastupanu tulekoormusele: -; 12 Klaaspakett: -; 13 Klaasingu erisused: -; 14 Päikesekiirgus tegur (g-väärtus): -; 15 Avanemine: Avanemine: "L" (L - vasak; R - parem); 16 Liigendatus: Lävepakk madal max 25mm, roostevaba; 17 Sulused, lukustus: lukustuse spetsifikatsioon; 19 Mudel või toote tunnus: Undefined; 20 Tootja: Undefined; 21 Tooteinfo: Undefined; 22 Kasutus- ja hooldusjuhend: Undefined
Pset_DoorCommon - ThermalTransmittance: 0; GlazingAreaFraction: 0; IsExternal: no
AC_Pset_RenovationAndPhasing - Renovation Status: New

# IfcDoor: SU-B126C 900×2 000, Siseuks * Door 22
In: 1 KORRUS
Type - OperationType: SINGLE_SWING_LEFT; ParameterTakesPrecedence: no; Sizeable: no
Type - Door Lining Properties - LiningDepth: 115 mm; LiningThickness: 40 mm; LiningOffset: 150 mm; CasingThickness: 50 mm; CasingDepth: 19 mm
Type - Door Panel Properties - Panel 1 - PanelDepth: 40 mm; PanelOperation: SWINGING; PanelWidth: 1; PanelPosition: MIDDLE
OverallHeight: 2000 mm; OverallWidth: 900 mm; Classification: 1.9 IfcDoor (uks) (_RKAS BIM + ARCHICAD Classification); 52 Siseuksed (EHITUSKULUDE LIIGITAMINE EVS 885:2005)
Avatäited - 18 Viimistlus: RAL 9003; 01 Nimetus: Siseuks; 02 Materjal: Sile uks; 03 Tähistus: SU-B126C 900×2 000; 04 Avamõõdu geomeetria: 900×2 000; 05 Asukoha info: Interior; 06 Soojusläbivus: -; 07 Helipidavus: 30 dB; 08 Veepidavus: -; 09 Õhuläbilaskvus: -; 10 Tulekindlus: nõudeid ei esitata; 11 Vastupanu tulekoormusele: -; 12 Klaaspakett: -; 13 Klaasingu erisused: -; 14 Päikesekiirgus tegur (g-väärtus): -; 15 Avanemine: Avanemine: "R" (L - vasak; R - parem); 16 Liigendatus: Lävepakk madal max 25mm, roostevaba; 17 Sulused, lukustus: lukustuse spetsifikatsioon; 19 Mudel või toote tunnus: Undefined; 20 Tootja: Undefined; 21 Tooteinfo: Undefined; 22 Kasutus- ja hooldusjuhend: Undefined
Pset_DoorCommon - ThermalTransmittance: 0; GlazingAreaFraction: 0; IsExternal: no
AC_Pset_RenovationAndPhasing - Renovation Status: New

# IfcDoor: SU-B127 800×2 000, Siseuks * Door 22
In: 1 KORRUS
Type - OperationType: SINGLE_SWING_LEFT; ParameterTakesPrecedence: no; Sizeable: no
Type - Door Lining Properties - LiningDepth: 115 mm; LiningThickness: 40 mm; LiningOffset: 150 mm; CasingThickness: 50 mm; CasingDepth: 19 mm
Type - Door Panel Properties - Panel 1 - PanelDepth: 40 mm; PanelOperation: SWINGING; PanelWidth: 1; PanelPosition: MIDDLE
OverallHeight: 2000 mm; OverallWidth: 800 mm; Classification: 1.9 IfcDoor (uks) (_RKAS BIM + ARCHICAD Classification); 52 Siseuksed (EHITUSKULUDE LIIGITAMINE EVS 885:2005)
Avatäited - 18 Viimistlus: RAL 9003; 01 Nimetus: Siseuks; 02 Materjal: Sile uks; 03 Tähistus: SU-B127 800×2 000; 04 Avamõõdu geomeetria: 800×2 000; 05 Asukoha info: Interior; 06 Soojusläbivus: -; 07 Helipidavus: 30 dB; 08 Veepidavus: -; 09 Õhuläbilaskvus: -; 10 Tulekindlus: nõudeid ei esitata; 11 Vastupanu tulekoormusele: -; 12 Klaaspakett: -; 13 Klaasingu erisused: -; 14 Päikesekiirgus tegur (g-väärtus): -; 15 Avanemine: Avanemine: "R" (L - vasak; R - parem); 16 Liigendatus: Lävepakk madal max 25mm, roostevaba; 17 Sulused, lukustus: lukustuse spetsifikatsioon; 19 Mudel või toote tunnus: Undefined; 20 Tootja: Undefined; 21 Tooteinfo: Undefined; 22 Kasutus- ja hooldusjuhend: Undefined
Pset_DoorCommon - ThermalTransmittance: 0; GlazingAreaFraction: 0; IsExternal: no
AC_Pset_RenovationAndPhasing - Renovation Status: New

# IfcDoor: SU-B128 900×2 000, Siseuks * Door 22
In: 1 KORRUS
Type - OperationType: SINGLE_SWING_LEFT; ParameterTakesPrecedence: no; Sizeable: no
Type - Door Lining Properties - LiningDepth: 115 mm; LiningThickness: 40 mm; LiningOffset: 0 mm; CasingThickness: 50 mm; CasingDepth: 19 mm
Type - Door Panel Properties - Panel 1 - PanelDepth: 40 mm; PanelOperation: SWINGING; PanelWidth: 1; PanelPosition: MIDDLE
OverallHeight: 2000 mm; OverallWidth: 900 mm; Classification: 1.9 IfcDoor (uks) (_RKAS BIM + ARCHICAD Classification); 52 Siseuksed (EHITUSKULUDE LIIGITAMINE EVS 885:2005)
Avatäited - 18 Viimistlus: RAL 9003; 01 Nimetus: Siseuks; 02 Materjal: Sile uks; 03 Tähistus: SU-B128 900×2 000; 04 Avamõõdu geomeetria: 900×2 000; 05 Asukoha info: Interior; 06 Soojusläbivus: -; 07 Helipidavus: 30 dB; 08 Veepidavus: -; 09 Õhuläbilaskvus: -; 10 Tulekindlus: nõudeid ei esitata; 11 Vastupanu tulekoormusele: -; 12 Klaaspakett: -; 13 Klaasingu erisused: -; 14 Päikesekiirgus tegur (g-väärtus): -; 15 Avanemine: Avanemine: "R" (L - vasak; R - parem); 16 Liigendatus: Lävepakk madal max 25mm, roostevaba; 17 Sulused, lukustus: lukustuse spetsifikatsioon; 19 Mudel või toote tunnus: Undefined; 20 Tootja: Undefined; 21 Tooteinfo: Undefined; 22 Kasutus- ja hooldusjuhend: Undefined
Pset_DoorCommon - ThermalTransmittance: 0; GlazingAreaFraction: 0; IsExternal: no
AC_Pset_RenovationAndPhasing - Renovation Status: New

# IfcDoor: SU-B130 900×2 000, Siseuks * Door 22
In: 1 KORRUS
Type - OperationType: SINGLE_SWING_LEFT; ParameterTakesPrecedence: no; Sizeable: no
Type - Door Lining Properties - LiningDepth: 115 mm; LiningThickness: 40 mm; LiningOffset: 300 mm; CasingThickness: 50 mm; CasingDepth: 19 mm
Type - Door Panel Properties - Panel 1 - PanelDepth: 40 mm; PanelOperation: SWINGING; PanelWidth: 1; PanelPosition: MIDDLE
OverallHeight: 2000 mm; OverallWidth: 900 mm; Classification: 1.9 IfcDoor (uks) (_RKAS BIM + ARCHICAD Classification); 52 Siseuksed (EHITUSKULUDE LIIGITAMINE EVS 885:2005)
Pset_FireRatingProperties - FireResistanceRating: EI30
Avatäited - 18 Viimistlus: RAL 9003; 01 Nimetus: Siseuks; 02 Materjal: Sile uks; 03 Tähistus: SU-B130 900×2 000; 04 Avamõõdu geomeetria: 900×2 000; 05 Asukoha info: Interior; 06 Soojusläbivus: -; 07 Helipidavus: 30 dB; 08 Veepidavus: -; 09 Õhuläbilaskvus: -; 10 Tulekindlus: EI 30; 11 Vastupanu tulekoormusele: -; 12 Klaaspakett: -; 13 Klaasingu erisused: -; 14 Päikesekiirgus tegur (g-väärtus): -; 15 Avanemine: Avanemine: "R" (L - vasak; R - parem); 16 Liigendatus: Lävepakk madal max 25mm, roostevaba; 17 Sulused, lukustus: lukustuse spetsifikatsioon; 19 Mudel või toote tunnus: Undefined; 20 Tootja: Undefined; 21 Tooteinfo: Undefined; 22 Kasutus- ja hooldusjuhend: Undefined
Pset_DoorCommon - ThermalTransmittance: 0; GlazingAreaFraction: 0; IsExternal: no
AC_Pset_RenovationAndPhasing - Renovation Status: New

# IfcDoor: SU-B131 900×2 000, Siseuks * Door 22
In: 1 KORRUS
Type - OperationType: SINGLE_SWING_RIGHT; ParameterTakesPrecedence: no; Sizeable: no
Type - Door Lining Properties - LiningDepth: 115 mm; LiningThickness: 40 mm; LiningOffset: -25 mm; CasingThickness: 50 mm; CasingDepth: 19 mm
Type - Door Panel Properties - Panel 1 - PanelDepth: 40 mm; PanelOperation: SWINGING; PanelWidth: 1; PanelPosition: MIDDLE
OverallHeight: 2000 mm; OverallWidth: 900 mm; Classification: 1.9 IfcDoor (uks) (_RKAS BIM + ARCHICAD Classification); 52 Siseuksed (EHITUSKULUDE LIIGITAMINE EVS 885:2005)
Avatäited - 18 Viimistlus: RAL 9003; 01 Nimetus: Siseuks; 02 Materjal: Sile uks; 03 Tähistus: SU-B131 900×2 000; 04 Avamõõdu geomeetria: 900×2 000; 05 Asukoha info: Interior; 06 Soojusläbivus: -; 07 Helipidavus: 30 dB; 08 Veepidavus: -; 09 Õhuläbilaskvus: -; 10 Tulekindlus: nõudeid ei esitata; 11 Vastupanu tulekoormusele: -; 12 Klaaspakett: -; 13 Klaasingu erisused: -; 14 Päikesekiirgus tegur (g-väärtus): -; 15 Avanemine: Avanemine: "L" (L - vasak; R - parem); 16 Liigendatus: Lävepakk madal max 25mm, roostevaba; 17 Sulused, lukustus: lukustuse spetsifikatsioon; 19 Mudel või toote tunnus: Undefined; 20 Tootja: Undefined; 21 Tooteinfo: Undefined; 22 Kasutus- ja hooldusjuhend: Undefined
Pset_DoorCommon - ThermalTransmittance: 0; GlazingAreaFraction: 0; IsExternal: no
AC_Pset_RenovationAndPhasing - Renovation Status: New

# IfcDoor: SU-B131A 900×2 100, Siseuks * Door 22
In: 1 KORRUS
Type - OperationType: SINGLE_SWING_LEFT; ParameterTakesPrecedence: no; Sizeable: no
Type - Door Lining Properties - LiningDepth: 115 mm; LiningThickness: 40 mm; LiningOffset: 0 mm; CasingThickness: 50 mm; CasingDepth: 19 mm
Type - Door Panel Properties - Panel 1 - PanelDepth: 40 mm; PanelOperation: SWINGING; PanelWidth: 1; PanelPosition: MIDDLE
OverallHeight: 2100 mm; OverallWidth: 900 mm; Classification: 1.9 IfcDoor (uks) (_RKAS BIM + ARCHICAD Classification); 52 Siseuksed (EHITUSKULUDE LIIGITAMINE EVS 885:2005)
Avatäited - 18 Viimistlus: RAL 9003; 01 Nimetus: Siseuks; 02 Materjal: Sile uks; 03 Tähistus: SU-B131A 900×2 100; 04 Avamõõdu geomeetria: 900×2 100; 05 Asukoha info: Interior; 06 Soojusläbivus: -; 07 Helipidavus: 30 dB; 08 Veepidavus: -; 09 Õhuläbilaskvus: -; 10 Tulekindlus: nõudeid ei esitata; 11 Vastupanu tulekoormusele: -; 12 Klaaspakett: -; 13 Klaasingu erisused: -; 14 Päikesekiirgus tegur (g-väärtus): -; 15 Avanemine: Avanemine: "R" (L - vasak; R - parem); 16 Liigendatus: Lävepakk madal max 25mm, roostevaba; 17 Sulused, lukustus: lukustuse spetsifikatsioon; 19 Mudel või toote tunnus: Undefined; 20 Tootja: Undefined; 21 Tooteinfo: Undefined; 22 Kasutus- ja hooldusjuhend: Undefined
Pset_DoorCommon - ThermalTransmittance: 0; GlazingAreaFraction: 0; IsExternal: no
AC_Pset_RenovationAndPhasing - Renovation Status: New

# IfcDoor: SU-B131B 900×2 100, Siseuks * Door 22
In: 1 KORRUS
Type - OperationType: SINGLE_SWING_LEFT; ParameterTakesPrecedence: no; Sizeable: no
Type - Door Lining Properties - LiningDepth: 115 mm; LiningThickness: 40 mm; LiningOffset: 0 mm; CasingThickness: 50 mm; CasingDepth: 19 mm
Type - Door Panel Properties - Panel 1 - PanelDepth: 40 mm; PanelOperation: SWINGING; PanelWidth: 1; PanelPosition: MIDDLE
OverallHeight: 2100 mm; OverallWidth: 900 mm; Classification: 1.9 IfcDoor (uks) (_RKAS BIM + ARCHICAD Classification); 52 Siseuksed (EHITUSKULUDE LIIGITAMINE EVS 885:2005)
Avatäited - 18 Viimistlus: RAL 9003; 01 Nimetus: Siseuks; 02 Materjal: Sile uks; 03 Tähistus: SU-B131B 900×2 100; 04 Avamõõdu geomeetria: 900×2 100; 05 Asukoha info: Interior; 06 Soojusläbivus: -; 07 Helipidavus: 30 dB; 08 Veepidavus: -; 09 Õhuläbilaskvus: -; 10 Tulekindlus: nõudeid ei esitata; 11 Vastupanu tulekoormusele: -; 12 Klaaspakett: -; 13 Klaasingu erisused: -; 14 Päikesekiirgus tegur (g-väärtus): -; 15 Avanemine: Avanemine: "R" (L - vasak; R - parem); 16 Liigendatus: Lävepakk madal max 25mm, roostevaba; 17 Sulused, lukustus: lukustuse spetsifikatsioon; 19 Mudel või toote tunnus: Undefined; 20 Tootja: Undefined; 21 Tooteinfo: Undefined; 22 Kasutus- ja hooldusjuhend: Undefined
Pset_DoorCommon - ThermalTransmittance: 0; GlazingAreaFraction: 0; IsExternal: no
AC_Pset_RenovationAndPhasing - Renovation Status: New

# IfcDoor: SU-B132 900×2 000, Siseuks * Door 22
In: 1 KORRUS
Type - OperationType: SINGLE_SWING_LEFT; ParameterTakesPrecedence: no; Sizeable: no
Type - Door Lining Properties - LiningDepth: 115 mm; LiningThickness: 40 mm; LiningOffset: 0 mm; CasingThickness: 50 mm; CasingDepth: 19 mm
Type - Door Panel Properties - Panel 1 - PanelDepth: 40 mm; PanelOperation: SWINGING; PanelWidth: 1; PanelPosition: MIDDLE
OverallHeight: 2000 mm; OverallWidth: 900 mm; Classification: 1.9 IfcDoor (uks) (_RKAS BIM + ARCHICAD Classification); 52 Siseuksed (EHITUSKULUDE LIIGITAMINE EVS 885:2005)
Avatäited - 18 Viimistlus: RAL 9003; 01 Nimetus: Siseuks; 02 Materjal: Sile uks; 03 Tähistus: SU-B132 900×2 000; 04 Avamõõdu geomeetria: 900×2 000; 05 Asukoha info: Interior; 06 Soojusläbivus: -; 07 Helipidavus: 30 dB; 08 Veepidavus: -; 09 Õhuläbilaskvus: -; 10 Tulekindlus: nõudeid ei esitata; 11 Vastupanu tulekoormusele: -; 12 Klaaspakett: -; 13 Klaasingu erisused: -; 14 Päikesekiirgus tegur (g-väärtus): -; 15 Avanemine: Avanemine: "R" (L - vasak; R - parem); 16 Liigendatus: Lävepakk madal max 25mm, roostevaba; 17 Sulused, lukustus: lukustuse spetsifikatsioon; 19 Mudel või toote tunnus: Undefined; 20 Tootja: Undefined; 21 Tooteinfo: Undefined; 22 Kasutus- ja hooldusjuhend: Undefined
Pset_DoorCommon - ThermalTransmittance: 0; GlazingAreaFraction: 0; IsExternal: no
AC_Pset_RenovationAndPhasing - Renovation Status: New

# IfcDoor: SU-B133 950×2 000, Siseuks * Door 22
In: 1 KORRUS
Type - OperationType: SINGLE_SWING_RIGHT; ParameterTakesPrecedence: no; Sizeable: no
Type - Door Lining Properties - LiningDepth: 115 mm; LiningThickness: 40 mm; LiningOffset: -25 mm; CasingThickness: 50 mm; CasingDepth: 19 mm
Type - Door Panel Properties - Panel 1 - PanelDepth: 40 mm; PanelOperation: SWINGING; PanelWidth: 1; PanelPosition: MIDDLE
OverallHeight: 2000 mm; OverallWidth: 950 mm; Classification: 1.9 IfcDoor (uks) (_RKAS BIM + ARCHICAD Classification); 52 Siseuksed (EHITUSKULUDE LIIGITAMINE EVS 885:2005)
Pset_DoorCommon - FireRating: EI30; ThermalTransmittance: 0; GlazingAreaFraction: 0; IsExternal: no
Avatäited - 18 Viimistlus: RAL 9003; 01 Nimetus: Siseuks; 02 Materjal: Sile uks; 03 Tähistus: SU-B133 950×2 000; 04 Avamõõdu geomeetria: 950×2 000; 05 Asukoha info: Interior; 06 Soojusläbivus: -; 07 Helipidavus: 30 dB; 08 Veepidavus: -; 09 Õhuläbilaskvus: -; 10 Tulekindlus: EI 30; 11 Vastupanu tulekoormusele: -; 12 Klaaspakett: -; 13 Klaasingu erisused: -; 14 Päikesekiirgus tegur (g-väärtus): -; 15 Avanemine: Avanemine: "L" (L - vasak; R - parem); 16 Liigendatus: Lävepakk madal max 25mm, roostevaba; 17 Sulused, lukustus: lukustuse spetsifikatsioon; 19 Mudel või toote tunnus: Undefined; 20 Tootja: Undefined; 21 Tooteinfo: Undefined; 22 Kasutus- ja hooldusjuhend: Undefined
AC_Pset_RenovationAndPhasing - Renovation Status: New

# IfcDoor: SU-B134 900×2 000, Siseuks * Door 22
In: 1 KORRUS
Type - OperationType: SINGLE_SWING_LEFT; ParameterTakesPrecedence: no; Sizeable: no
Type - Door Lining Properties - LiningDepth: 115 mm; LiningThickness: 40 mm; LiningOffset: 0 mm; CasingThickness: 50 mm; CasingDepth: 19 mm
Type - Door Panel Properties - Panel 1 - PanelDepth: 40 mm; PanelOperation: SWINGING; PanelWidth: 1; PanelPosition: MIDDLE
OverallHeight: 2000 mm; OverallWidth: 900 mm; Classification: 1.9 IfcDoor (uks) (_RKAS BIM + ARCHICAD Classification); 52 Siseuksed (EHITUSKULUDE LIIGITAMINE EVS 885:2005)
Avatäited - 18 Viimistlus: RAL 9003; 01 Nimetus: Siseuks; 02 Materjal: Sile uks; 03 Tähistus: SU-B134 900×2 000; 04 Avamõõdu geomeetria: 900×2 000; 05 Asukoha info: Interior; 06 Soojusläbivus: -; 07 Helipidavus: 30 dB; 08 Veepidavus: -; 09 Õhuläbilaskvus: -; 10 Tulekindlus: nõudeid ei esitata; 11 Vastupanu tulekoormusele: -; 12 Klaaspakett: -; 13 Klaasingu erisused: -; 14 Päikesekiirgus tegur (g-väärtus): -; 15 Avanemine: Avanemine: "R" (L - vasak; R - parem); 16 Liigendatus: Lävepakk madal max 25mm, roostevaba; 17 Sulused, lukustus: lukustuse spetsifikatsioon; 19 Mudel või toote tunnus: Undefined; 20 Tootja: Undefined; 21 Tooteinfo: Undefined; 22 Kasutus- ja hooldusjuhend: Undefined
Pset_DoorCommon - ThermalTransmittance: 0; GlazingAreaFraction: 0; IsExternal: no
AC_Pset_RenovationAndPhasing - Renovation Status: New

# IfcDoor: SU-B135 1 750×2 000, Siseuks * Double Door 22
In: 1 KORRUS
Type - OperationType: DOUBLE_DOOR_SINGLE_SWING; ParameterTakesPrecedence: no; Sizeable: no
Type - Door Lining Properties - LiningDepth: 115 mm; LiningThickness: 40 mm; LiningOffset: 0 mm; CasingThickness: 50 mm; CasingDepth: 19 mm
Type - Door Panel Properties - Panel 1 - PanelDepth: 40 mm; PanelOperation: SWINGING; PanelWidth: 0.507186; PanelPosition: LEFT
Type - Door Panel Properties - Panel 2 - PanelDepth: 40 mm; PanelOperation: SWINGING; PanelWidth: 0.507186; PanelPosition: RIGHT
OverallHeight: 2000 mm; OverallWidth: 1750 mm; Classification: 1.9 IfcDoor (uks) (_RKAS BIM + ARCHICAD Classification); 52 Siseuksed (EHITUSKULUDE LIIGITAMINE EVS 885:2005)
Avatäited - 18 Viimistlus: RAL 9003; 01 Nimetus: Siseuks; 02 Materjal: Alumiiniumprofiil pulbervärvitud; 03 Tähistus: SU-B135 1 750×2 000; 04 Avamõõdu geomeetria: 1 750×2 000; 05 Asukoha info: Interior; 06 Soojusläbivus: -; 07 Helipidavus: 30 dB; 08 Veepidavus: -; 09 Õhuläbilaskvus: -; 10 Tulekindlus: nõudeid ei esitata; 11 Vastupanu tulekoormusele: -; 12 Klaaspakett: Karastatud ja lamineeritud kirgas klaas; 13 Klaasingu erisused: -; 14 Päikesekiirgus tegur (g-väärtus): -; 15 Avanemine: Avanemine: "L" (L - vasak; R - parem); 16 Liigendatus: Lävepakk madal max 25mm, roostevaba; 17 Sulused, lukustus: lukustuse spetsifikatsioon; 19 Mudel või toote tunnus: Undefined; 20 Tootja: Undefined; 21 Tooteinfo: Undefined; 22 Kasutus- ja hooldusjuhend: Undefined
Pset_DoorCommon - ThermalTransmittance: 0; GlazingAreaFraction: 2.16357; IsExternal: no
AC_Pset_RenovationAndPhasing - Renovation Status: New

# IfcDoor: SU-B136 1 600×2 000, Siseuks * Double Door 22
In: 1 KORRUS
Type - OperationType: DOUBLE_DOOR_SINGLE_SWING; ParameterTakesPrecedence: no; Sizeable: no
Type - Door Lining Properties - LiningDepth: 115 mm; LiningThickness: 40 mm; LiningOffset: 0 mm; CasingThickness: 50 mm; CasingDepth: 19 mm
Type - Door Panel Properties - Panel 1 - PanelDepth: 40 mm; PanelOperation: SWINGING; PanelWidth: 0.507895; PanelPosition: RIGHT
Type - Door Panel Properties - Panel 2 - PanelDepth: 40 mm; PanelOperation: SWINGING; PanelWidth: 0.507895; PanelPosition: LEFT
OverallHeight: 2000 mm; OverallWidth: 1600 mm; Classification: 1.9 IfcDoor (uks) (_RKAS BIM + ARCHICAD Classification); 52 Siseuksed (EHITUSKULUDE LIIGITAMINE EVS 885:2005)
Avatäited - 18 Viimistlus: RAL 9003; 01 Nimetus: Siseuks; 02 Materjal: Alumiiniumprofiil pulbervärvitud; 03 Tähistus: SU-B136 1 600×2 000; 04 Avamõõdu geomeetria: 1 600×2 000; 05 Asukoha info: Interior; 06 Soojusläbivus: -; 07 Helipidavus: 30 dB; 08 Veepidavus: -; 09 Õhuläbilaskvus: -; 10 Tulekindlus: nõudeid ei esitata; 11 Vastupanu tulekoormusele: -; 12 Klaaspakett: Karastatud ja lamineeritud kirgas klaas; 13 Klaasingu erisused: -; 14 Päikesekiirgus tegur (g-väärtus): -; 15 Avanemine: Avanemine: "R" (L - vasak; R - parem); 16 Liigendatus: Lävepakk madal max 25mm, roostevaba; 17 Sulused, lukustus: lukustuse spetsifikatsioon; 19 Mudel või toote tunnus: Undefined; 20 Tootja: Undefined; 21 Tooteinfo: Undefined; 22 Kasutus- ja hooldusjuhend: Undefined
Pset_DoorCommon - ThermalTransmittance: 0; GlazingAreaFraction: 1.91277; IsExternal: no
AC_Pset_RenovationAndPhasing - Renovation Status: New

# IfcDoor: SU-B137 1 600×2 100, Siseuks * Double Door 22
In: 1 KORRUS
Type - OperationType: DOUBLE_DOOR_SINGLE_SWING; ParameterTakesPrecedence: no; Sizeable: no
Type - Door Lining Properties - LiningDepth: 115 mm; LiningThickness: 40 mm; LiningOffset: 0 mm; CasingThickness: 50 mm; CasingDepth: 19 mm
Type - Door Panel Properties - Panel 1 - PanelDepth: 40 mm; PanelOperation: SWINGING; PanelWidth: 0.423684; PanelPosition: LEFT
Type - Door Panel Properties - Panel 2 - PanelDepth: 40 mm; PanelOperation: SWINGING; PanelWidth: 0.592105; PanelPosition: RIGHT
Description: Teras; OverallHeight: 2100 mm; OverallWidth: 1600 mm; Classification: 1.9 IfcDoor (uks) (_RKAS BIM + ARCHICAD Classification); 52 Siseuksed (EHITUSKULUDE LIIGITAMINE EVS 885:2005)
Pset_DoorCommon - FireRating: EI30; ThermalTransmittance: 0; GlazingAreaFraction: 0; IsExternal: no
Avatäited - 18 Viimistlus: RAL 9003; 01 Nimetus: Siseuks; 02 Materjal: Sile uks; 03 Tähistus: SU-B137 1 600×2 100; 04 Avamõõdu geomeetria: 1 600×2 100; 05 Asukoha info: Interior; 06 Soojusläbivus: -; 07 Helipidavus: 30 dB; 08 Veepidavus: -; 09 Õhuläbilaskvus: -; 10 Tulekindlus: EI 30; 11 Vastupanu tulekoormusele: -; 12 Klaaspakett: -; 13 Klaasingu erisused: -; 14 Päikesekiirgus tegur (g-väärtus): -; 15 Avanemine: Avanemine: "L" (L - vasak; R - parem); 16 Liigendatus: Lävepakk madal max 25mm, roostevaba; 17 Sulused, lukustus: lukustuse spetsifikatsioon; 19 Mudel või toote tunnus: Undefined; 20 Tootja: Undefined; 21 Tooteinfo: Undefined; 22 Kasutus- ja hooldusjuhend: Undefined
AC_Pset_RenovationAndPhasing - Renovation Status: New

# IfcDoor: SU-B138 1 000×2 100, Siseuks * Door 22
In: 1 KORRUS
Type - OperationType: SINGLE_SWING_LEFT; ParameterTakesPrecedence: no; Sizeable: no
Type - Door Lining Properties - LiningDepth: 115 mm; LiningThickness: 40 mm; LiningOffset: -150 mm; CasingThickness: 50 mm; CasingDepth: 19 mm
Type - Door Panel Properties - Panel 1 - PanelDepth: 40 mm; PanelOperation: SWINGING; PanelWidth: 1; PanelPosition: MIDDLE
OverallHeight: 2100 mm; OverallWidth: 1000 mm; Classification: 1.9 IfcDoor (uks) (_RKAS BIM + ARCHICAD Classification); 52 Siseuksed (EHITUSKULUDE LIIGITAMINE EVS 885:2005)
Avatäited - 18 Viimistlus: RAL 9003; 01 Nimetus: Siseuks; 02 Materjal: Sile uks; 03 Tähistus: SU-B138 1 000×2 100; 04 Avamõõdu geomeetria: 1 000×2 100; 05 Asukoha info: Interior; 06 Soojusläbivus: -; 07 Helipidavus: 30 dB; 08 Veepidavus: -; 09 Õhuläbilaskvus: -; 10 Tulekindlus: nõudeid ei esitata; 11 Vastupanu tulekoormusele: -; 12 Klaaspakett: -; 13 Klaasingu erisused: -; 14 Päikesekiirgus tegur (g-väärtus): -; 15 Avanemine: Avanemine: "R" (L - vasak; R - parem); 16 Liigendatus: Tuulutatav lävepakk; 17 Sulused, lukustus: lukustuse spetsifikatsioon; 19 Mudel või toote tunnus: Undefined; 20 Tootja: Undefined; 21 Tooteinfo: Undefined; 22 Kasutus- ja hooldusjuhend: Undefined
Pset_DoorCommon - ThermalTransmittance: 0; GlazingAreaFraction: 0; IsExternal: no
AC_Pset_RenovationAndPhasing - Renovation Status: New

# IfcDoor: SU-B201 970×2 300, Siseuks * Door 22
In: 2 KORRUS
Type - OperationType: SINGLE_SWING_LEFT; ParameterTakesPrecedence: no; Sizeable: no
Type - Door Lining Properties - LiningDepth: 115 mm; LiningThickness: 40 mm; LiningOffset: 420 mm; CasingThickness: 50 mm; CasingDepth: 19 mm
Type - Door Panel Properties - Panel 1 - PanelDepth: 40 mm; PanelOperation: SWINGING; PanelWidth: 1; PanelPosition: MIDDLE
OverallHeight: 2300 mm; OverallWidth: 970 mm; Classification: 1.9 IfcDoor (uks) (_RKAS BIM + ARCHICAD Classification); 52 Siseuksed (EHITUSKULUDE LIIGITAMINE EVS 885:2005)
Avatäited - 18 Viimistlus: RAL 9003; 01 Nimetus: Siseuks; 02 Materjal: Sile uks; 03 Tähistus: SU-B201 970×2 300; 04 Avamõõdu geomeetria: 970×2 300; 05 Asukoha info: Interior; 06 Soojusläbivus: -; 07 Helipidavus: 30 dB; 08 Veepidavus: -; 09 Õhuläbilaskvus: -; 10 Tulekindlus: nõudeid ei esitata; 11 Vastupanu tulekoormusele: -; 12 Klaaspakett: -; 13 Klaasingu erisused: -; 14 Päikesekiirgus tegur (g-väärtus): -; 15 Avanemine: Avanemine: "R" (L - vasak; R - parem); 16 Liigendatus: Lävepakk madal max 25mm, roostevaba; 17 Sulused, lukustus: vt lukustuse spetsifikatsioon; 19 Mudel või toote tunnus: Undefined; 20 Tootja: Undefined; 21 Tooteinfo: Undefined; 22 Kasutus- ja hooldusjuhend: Undefined
Pset_DoorCommon - ThermalTransmittance: 0; GlazingAreaFraction: 0; IsExternal: no
AC_Pset_RenovationAndPhasing - Renovation Status: New

# IfcDoor: SU-B202 970×2 300, Siseuks * Door 22
In: 2 KORRUS
Type - OperationType: SINGLE_SWING_LEFT; ParameterTakesPrecedence: no; Sizeable: no
Type - Door Lining Properties - LiningDepth: 115 mm; LiningThickness: 40 mm; LiningOffset: 420 mm; CasingThickness: 50 mm; CasingDepth: 19 mm
Type - Door Panel Properties - Panel 1 - PanelDepth: 40 mm; PanelOperation: SWINGING; PanelWidth: 1; PanelPosition: MIDDLE
OverallHeight: 2300 mm; OverallWidth: 970 mm; Classification: 1.9 IfcDoor (uks) (_RKAS BIM + ARCHICAD Classification); 52 Siseuksed (EHITUSKULUDE LIIGITAMINE EVS 885:2005)
Avatäited - 18 Viimistlus: RAL 9003; 01 Nimetus: Siseuks; 02 Materjal: Sile uks; 03 Tähistus: SU-B202 970×2 300; 04 Avamõõdu geomeetria: 970×2 300; 05 Asukoha info: Interior; 06 Soojusläbivus: -; 07 Helipidavus: 30 dB; 08 Veepidavus: -; 09 Õhuläbilaskvus: -; 10 Tulekindlus: nõudeid ei esitata; 11 Vastupanu tulekoormusele: -; 12 Klaaspakett: -; 13 Klaasingu erisused: -; 14 Päikesekiirgus tegur (g-väärtus): -; 15 Avanemine: Avanemine: "R" (L - vasak; R - parem); 16 Liigendatus: Lävepakk madal max 25mm, roostevaba; 17 Sulused, lukustus: vt lukustuse spetsifikatsioon; 19 Mudel või toote tunnus: Undefined; 20 Tootja: Undefined; 21 Tooteinfo: Undefined; 22 Kasutus- ja hooldusjuhend: Undefined
Pset_DoorCommon - ThermalTransmittance: 0; GlazingAreaFraction: 0; IsExternal: no
AC_Pset_RenovationAndPhasing - Renovation Status: New

# IfcDoor: SU-B203 970×2 300, Siseuks * Door 22
In: 2 KORRUS
Type - OperationType: SINGLE_SWING_LEFT; ParameterTakesPrecedence: no; Sizeable: no
Type - Door Lining Properties - LiningDepth: 115 mm; LiningThickness: 40 mm; LiningOffset: 420 mm; CasingThickness: 50 mm; CasingDepth: 19 mm
Type - Door Panel Properties - Panel 1 - PanelDepth: 40 mm; PanelOperation: SWINGING; PanelWidth: 1; PanelPosition: MIDDLE
OverallHeight: 2300 mm; OverallWidth: 970 mm; Classification: 1.9 IfcDoor (uks) (_RKAS BIM + ARCHICAD Classification); 52 Siseuksed (EHITUSKULUDE LIIGITAMINE EVS 885:2005)
Avatäited - 18 Viimistlus: RAL 9003; 01 Nimetus: Siseuks; 02 Materjal: Sile uks; 03 Tähistus: SU-B203 970×2 300; 04 Avamõõdu geomeetria: 970×2 300; 05 Asukoha info: Interior; 06 Soojusläbivus: -; 07 Helipidavus: 30 dB; 08 Veepidavus: -; 09 Õhuläbilaskvus: -; 10 Tulekindlus: nõudeid ei esitata; 11 Vastupanu tulekoormusele: -; 12 Klaaspakett: -; 13 Klaasingu erisused: -; 14 Päikesekiirgus tegur (g-väärtus): -; 15 Avanemine: Avanemine: "R" (L - vasak; R - parem); 16 Liigendatus: Lävepakk madal max 25mm, roostevaba; 17 Sulused, lukustus: vt lukustuse spetsifikatsioon; 19 Mudel või toote tunnus: Undefined; 20 Tootja: Undefined; 21 Tooteinfo: Undefined; 22 Kasutus- ja hooldusjuhend: Undefined
Pset_DoorCommon - ThermalTransmittance: 0; GlazingAreaFraction: 0; IsExternal: no
AC_Pset_RenovationAndPhasing - Renovation Status: New

# IfcDoor: SU-B204 870×2 000, Siseuks * Door 22
In: 2 KORRUS
Type - OperationType: SINGLE_SWING_RIGHT; ParameterTakesPrecedence: no; Sizeable: no
Type - Door Lining Properties - LiningDepth: 115 mm; LiningThickness: 40 mm; LiningOffset: -35 mm; CasingThickness: 50 mm; CasingDepth: 19 mm
Type - Door Panel Properties - Panel 1 - PanelDepth: 40 mm; PanelOperation: SWINGING; PanelWidth: 1; PanelPosition: MIDDLE
OverallHeight: 2000 mm; OverallWidth: 870 mm; Classification: 1.9 IfcDoor (uks) (_RKAS BIM + ARCHICAD Classification); 52 Siseuksed (EHITUSKULUDE LIIGITAMINE EVS 885:2005)
Avatäited - 18 Viimistlus: RAL 9003; 01 Nimetus: Siseuks; 02 Materjal: Sile uks; 03 Tähistus: SU-B204 870×2 000; 04 Avamõõdu geomeetria: 870×2 000; 05 Asukoha info: Interior; 06 Soojusläbivus: -; 07 Helipidavus: 30 dB; 08 Veepidavus: -; 09 Õhuläbilaskvus: -; 10 Tulekindlus: nõudeid ei esitata; 11 Vastupanu tulekoormusele: -; 12 Klaaspakett: -; 13 Klaasingu erisused: -; 14 Päikesekiirgus tegur (g-väärtus): -; 15 Avanemine: Avanemine: "L" (L - vasak; R - parem); 16 Liigendatus: Lävepakk madal max 25mm, roostevaba; 17 Sulused, lukustus: vt lukustuse spetsifikatsioon; 19 Mudel või toote tunnus: Undefined; 20 Tootja: Undefined; 21 Tooteinfo: Undefined; 22 Kasutus- ja hooldusjuhend: Undefined
Pset_DoorCommon - ThermalTransmittance: 0; GlazingAreaFraction: 0; IsExternal: no
AC_Pset_RenovationAndPhasing - Renovation Status: New

# IfcDoor: SU-B205 970×2 300, Siseuks * Door 22
In: 2 KORRUS
Type - OperationType: SINGLE_SWING_LEFT; ParameterTakesPrecedence: no; Sizeable: no
Type - Door Lining Properties - LiningDepth: 115 mm; LiningThickness: 40 mm; LiningOffset: 0 mm; CasingThickness: 50 mm; CasingDepth: 19 mm
Type - Door Panel Properties - Panel 1 - PanelDepth: 40 mm; PanelOperation: SWINGING; PanelWidth: 1; PanelPosition: MIDDLE
OverallHeight: 2300 mm; OverallWidth: 970 mm; Classification: 1.9 IfcDoor (uks) (_RKAS BIM + ARCHICAD Classification); 52 Siseuksed (EHITUSKULUDE LIIGITAMINE EVS 885:2005)
Avatäited - 18 Viimistlus: RAL 9003; 01 Nimetus: Siseuks; 02 Materjal: Sile uks; 03 Tähistus: SU-B205 970×2 300; 04 Avamõõdu geomeetria: 970×2 300; 05 Asukoha info: Interior; 06 Soojusläbivus: -; 07 Helipidavus: 30 dB; 08 Veepidavus: -; 09 Õhuläbilaskvus: -; 10 Tulekindlus: nõudeid ei esitata; 11 Vastupanu tulekoormusele: -; 12 Klaaspakett: -; 13 Klaasingu erisused: -; 14 Päikesekiirgus tegur (g-väärtus): -; 15 Avanemine: Avanemine: "R" (L - vasak; R - parem); 16 Liigendatus: Lävepakk madal max 25mm, roostevaba; 17 Sulused, lukustus: vt lukustuse spetsifikatsioon; 19 Mudel või toote tunnus: Undefined; 20 Tootja: Undefined; 21 Tooteinfo: Undefined; 22 Kasutus- ja hooldusjuhend: Undefined
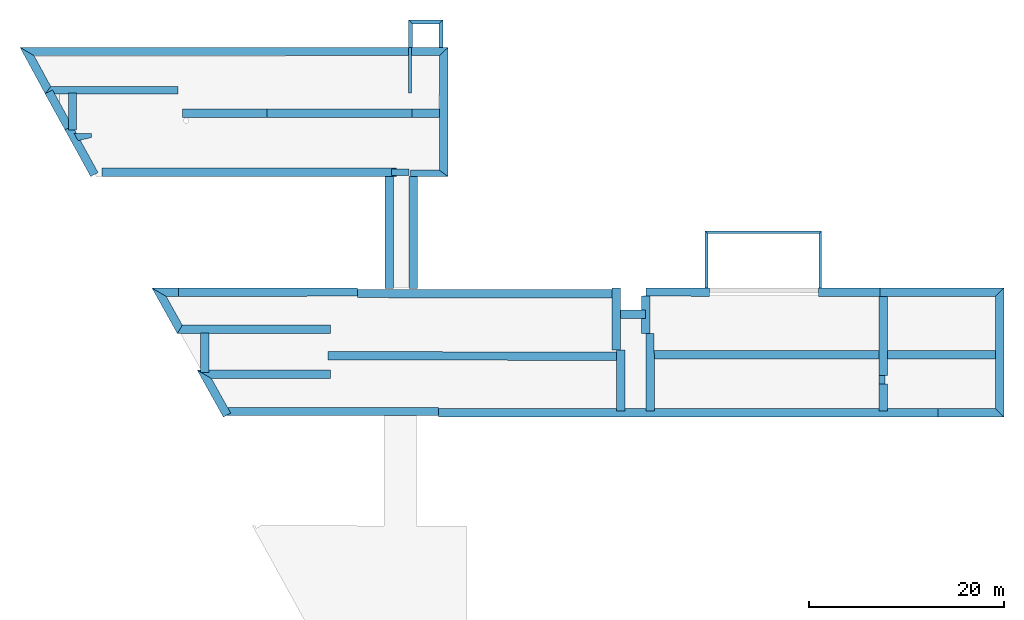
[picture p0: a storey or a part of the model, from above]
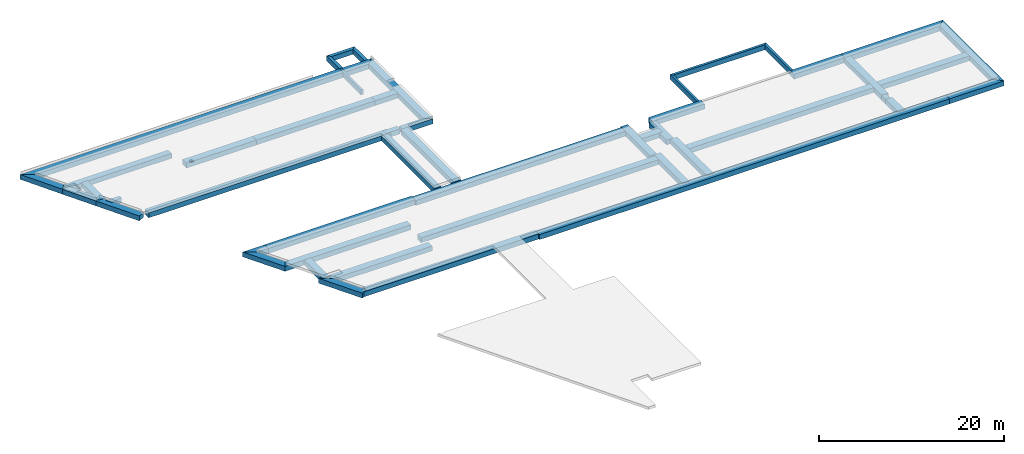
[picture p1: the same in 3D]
Properties of the parts of a building model (IFC2X3), part 8 of 14

# IfcDoor: SU-B205 970×2 300, Siseuks * Door 22
Pset_DoorCommon - ThermalTransmittance: 0; GlazingAreaFraction: 0; IsExternal: no
AC_Pset_RenovationAndPhasing - Renovation Status: New

# IfcDoor: SU-B206 970×2 100, Siseuks * Door 22
In: 2 KORRUS
Type - OperationType: SINGLE_SWING_LEFT; ParameterTakesPrecedence: no; Sizeable: no
Type - Door Lining Properties - LiningDepth: 115 mm; LiningThickness: 40 mm; LiningOffset: 0 mm; CasingThickness: 50 mm; CasingDepth: 19 mm
Type - Door Panel Properties - Panel 1 - PanelDepth: 40 mm; PanelOperation: SWINGING; PanelWidth: 1; PanelPosition: MIDDLE
OverallHeight: 2100 mm; OverallWidth: 970 mm; Classification: 1.9 IfcDoor (uks) (_RKAS BIM + ARCHICAD Classification); 52 Siseuksed (EHITUSKULUDE LIIGITAMINE EVS 885:2005)
Avatäited - 18 Viimistlus: RAL 9003; 01 Nimetus: Siseuks; 02 Materjal: Sile uks; 03 Tähistus: SU-B206 970×2 100; 04 Avamõõdu geomeetria: 970×2 100; 05 Asukoha info: Interior; 06 Soojusläbivus: -; 07 Helipidavus: 30 dB; 08 Veepidavus: -; 09 Õhuläbilaskvus: -; 10 Tulekindlus: nõudeid ei esitata; 11 Vastupanu tulekoormusele: -; 12 Klaaspakett: -; 13 Klaasingu erisused: -; 14 Päikesekiirgus tegur (g-väärtus): -; 15 Avanemine: Avanemine: "R" (L - vasak; R - parem); 16 Liigendatus: Lävepakk madal max 25mm, roostevaba; 17 Sulused, lukustus: vt lukustuse spetsifikatsioon; 19 Mudel või toote tunnus: Undefined; 20 Tootja: Undefined; 21 Tooteinfo: Undefined; 22 Kasutus- ja hooldusjuhend: Undefined
Pset_DoorCommon - ThermalTransmittance: 0; GlazingAreaFraction: 0; IsExternal: no
AC_Pset_RenovationAndPhasing - Renovation Status: New

# IfcDoor: SU-B207 970×2 300, Siseuks * Door 22
In: 2 KORRUS
Type - OperationType: SINGLE_SWING_LEFT; ParameterTakesPrecedence: no; Sizeable: no
Type - Door Lining Properties - LiningDepth: 115 mm; LiningThickness: 40 mm; LiningOffset: 0 mm; CasingThickness: 50 mm; CasingDepth: 19 mm
Type - Door Panel Properties - Panel 1 - PanelDepth: 40 mm; PanelOperation: SWINGING; PanelWidth: 1; PanelPosition: MIDDLE
OverallHeight: 2300 mm; OverallWidth: 970 mm; Classification: 1.9 IfcDoor (uks) (_RKAS BIM + ARCHICAD Classification); 52 Siseuksed (EHITUSKULUDE LIIGITAMINE EVS 885:2005)
Avatäited - 18 Viimistlus: RAL 9003; 01 Nimetus: Siseuks; 02 Materjal: Sile uks; 03 Tähistus: SU-B207 970×2 300; 04 Avamõõdu geomeetria: 970×2 300; 05 Asukoha info: Interior; 06 Soojusläbivus: -; 07 Helipidavus: 30 dB; 08 Veepidavus: -; 09 Õhuläbilaskvus: -; 10 Tulekindlus: nõudeid ei esitata; 11 Vastupanu tulekoormusele: -; 12 Klaaspakett: -; 13 Klaasingu erisused: -; 14 Päikesekiirgus tegur (g-väärtus): -; 15 Avanemine: Avanemine: "R" (L - vasak; R - parem); 16 Liigendatus: Lävepakk madal max 25mm, roostevaba; 17 Sulused, lukustus: vt lukustuse spetsifikatsioon; 19 Mudel või toote tunnus: Undefined; 20 Tootja: Undefined; 21 Tooteinfo: Undefined; 22 Kasutus- ja hooldusjuhend: Undefined
Pset_DoorCommon - ThermalTransmittance: 0; GlazingAreaFraction: 0; IsExternal: no
AC_Pset_RenovationAndPhasing - Renovation Status: New

# IfcDoor: SU-B207A 1 000×2 300, Siseuks * Door 22
In: 2 KORRUS
Type - OperationType: SINGLE_SWING_LEFT; ParameterTakesPrecedence: no; Sizeable: no
Type - Door Lining Properties - LiningDepth: 115 mm; LiningThickness: 40 mm; LiningOffset: -35 mm; CasingThickness: 50 mm; CasingDepth: 19 mm
Type - Door Panel Properties - Panel 1 - PanelDepth: 40 mm; PanelOperation: SWINGING; PanelWidth: 1; PanelPosition: MIDDLE
OverallHeight: 2300 mm; OverallWidth: 1000 mm; Classification: 1.9 IfcDoor (uks) (_RKAS BIM + ARCHICAD Classification); 52 Siseuksed (EHITUSKULUDE LIIGITAMINE EVS 885:2005)
Avatäited - 18 Viimistlus: RAL 9003; 01 Nimetus: Siseuks; 02 Materjal: Sile uks; 03 Tähistus: SU-B207A 1 000×2 300; 04 Avamõõdu geomeetria: 1 000×2 300; 05 Asukoha info: Interior; 06 Soojusläbivus: -; 07 Helipidavus: 30 dB; 08 Veepidavus: -; 09 Õhuläbilaskvus: -; 10 Tulekindlus: nõudeid ei esitata; 11 Vastupanu tulekoormusele: -; 12 Klaaspakett: -; 13 Klaasingu erisused: -; 14 Päikesekiirgus tegur (g-väärtus): -; 15 Avanemine: Avanemine: "R" (L - vasak; R - parem); 16 Liigendatus: Lävepakk madal max 25mm, roostevaba; 17 Sulused, lukustus: vt lukustuse spetsifikatsioon; 19 Mudel või toote tunnus: Undefined; 20 Tootja: Undefined; 21 Tooteinfo: Undefined; 22 Kasutus- ja hooldusjuhend: Undefined
Pset_DoorCommon - ThermalTransmittance: 0; GlazingAreaFraction: 0; IsExternal: no
AC_Pset_RenovationAndPhasing - Renovation Status: New

# IfcDoor: SU-B208 970×2 300, Siseuks * Door 22
In: 2 KORRUS
Type - OperationType: SINGLE_SWING_LEFT; ParameterTakesPrecedence: no; Sizeable: no
Type - Door Lining Properties - LiningDepth: 115 mm; LiningThickness: 40 mm; LiningOffset: 0 mm; CasingThickness: 50 mm; CasingDepth: 19 mm
Type - Door Panel Properties - Panel 1 - PanelDepth: 40 mm; PanelOperation: SWINGING; PanelWidth: 1; PanelPosition: MIDDLE
OverallHeight: 2300 mm; OverallWidth: 970 mm; Classification: 1.9 IfcDoor (uks) (_RKAS BIM + ARCHICAD Classification); 52 Siseuksed (EHITUSKULUDE LIIGITAMINE EVS 885:2005)
Avatäited - 18 Viimistlus: RAL 9003; 01 Nimetus: Siseuks; 02 Materjal: Sile uks; 03 Tähistus: SU-B208 970×2 300; 04 Avamõõdu geomeetria: 970×2 300; 05 Asukoha info: Interior; 06 Soojusläbivus: -; 07 Helipidavus: 30 dB; 08 Veepidavus: -; 09 Õhuläbilaskvus: -; 10 Tulekindlus: nõudeid ei esitata; 11 Vastupanu tulekoormusele: -; 12 Klaaspakett: -; 13 Klaasingu erisused: -; 14 Päikesekiirgus tegur (g-väärtus): -; 15 Avanemine: Avanemine: "R" (L - vasak; R - parem); 16 Liigendatus: Lävepakk madal max 25mm, roostevaba; 17 Sulused, lukustus: vt lukustuse spetsifikatsioon; 19 Mudel või toote tunnus: Undefined; 20 Tootja: Undefined; 21 Tooteinfo: Undefined; 22 Kasutus- ja hooldusjuhend: Undefined
Pset_DoorCommon - ThermalTransmittance: 0; GlazingAreaFraction: 0; IsExternal: no
AC_Pset_RenovationAndPhasing - Renovation Status: New

# IfcDoor: SU-B209 1 680×2 300, Siseuks * Double Door 22
In: 2 KORRUS
Type - OperationType: DOUBLE_DOOR_SINGLE_SWING; ParameterTakesPrecedence: no; Sizeable: no
Type - Door Lining Properties - LiningDepth: 115 mm; LiningThickness: 40 mm; LiningOffset: 115 mm; CasingThickness: 50 mm; CasingDepth: 19 mm
Type - Door Panel Properties - Panel 1 - PanelDepth: 40 mm; PanelOperation: SWINGING; PanelWidth: 0.5075; PanelPosition: LEFT
Type - Door Panel Properties - Panel 2 - PanelDepth: 40 mm; PanelOperation: SWINGING; PanelWidth: 0.5075; PanelPosition: RIGHT
OverallHeight: 2300 mm; OverallWidth: 1680 mm; Classification: 1.9 IfcDoor (uks) (_RKAS BIM + ARCHICAD Classification); 52 Siseuksed (EHITUSKULUDE LIIGITAMINE EVS 885:2005)
Avatäited - 18 Viimistlus: RAL 9003; 01 Nimetus: Siseuks; 02 Materjal: Alumiiniumprofiil pulbervärvitud; 03 Tähistus: SU-B209 1 680×2 300; 04 Avamõõdu geomeetria: 1 680×2 300; 05 Asukoha info: Interior; 06 Soojusläbivus: -; 07 Helipidavus: 30 dB; 08 Veepidavus: -; 09 Õhuläbilaskvus: -; 10 Tulekindlus: nõudeid ei esitata; 11 Vastupanu tulekoormusele: -; 12 Klaaspakett: Karastatud ja lamineeritud kirgas klaas; 13 Klaasingu erisused: -; 14 Päikesekiirgus tegur (g-väärtus): -; 15 Avanemine: Avanemine: "L" (L - vasak; R - parem); 16 Liigendatus: Lävepakk madal max 25mm, roostevaba; 17 Sulused, lukustus: vt lukustuse spetsifikatsioon; 19 Mudel või toote tunnus: Undefined; 20 Tootja: Undefined; 21 Tooteinfo: Undefined; 22 Kasutus- ja hooldusjuhend: Undefined
Pset_DoorCommon - ThermalTransmittance: 0; GlazingAreaFraction: 2.41373; IsExternal: no
AC_Pset_RenovationAndPhasing - Renovation Status: New

# IfcDoor: SU-B210 950×2 300, Siseuks * Door 22
In: 2 KORRUS
Type - OperationType: SINGLE_SWING_LEFT; ParameterTakesPrecedence: no; Sizeable: no
Type - Door Lining Properties - LiningDepth: 115 mm; LiningThickness: 40 mm; LiningOffset: 0 mm; CasingThickness: 50 mm; CasingDepth: 19 mm
Type - Door Panel Properties - Panel 1 - PanelDepth: 40 mm; PanelOperation: SWINGING; PanelWidth: 1; PanelPosition: MIDDLE
OverallHeight: 2300 mm; OverallWidth: 950 mm; Classification: 1.9 IfcDoor (uks) (_RKAS BIM + ARCHICAD Classification); 52 Siseuksed (EHITUSKULUDE LIIGITAMINE EVS 885:2005)
Avatäited - 18 Viimistlus: RAL 9003; 01 Nimetus: Siseuks; 02 Materjal: Sile uks; 03 Tähistus: SU-B210 950×2 300; 04 Avamõõdu geomeetria: 950×2 300; 05 Asukoha info: Interior; 06 Soojusläbivus: -; 07 Helipidavus: 30 dB; 08 Veepidavus: -; 09 Õhuläbilaskvus: -; 10 Tulekindlus: nõudeid ei esitata; 11 Vastupanu tulekoormusele: -; 12 Klaaspakett: -; 13 Klaasingu erisused: -; 14 Päikesekiirgus tegur (g-väärtus): -; 15 Avanemine: Avanemine: "R" (L - vasak; R - parem); 16 Liigendatus: Lävepakk madal max 25mm, roostevaba; 17 Sulused, lukustus: vt lukustuse spetsifikatsioon; 19 Mudel või toote tunnus: Undefined; 20 Tootja: Undefined; 21 Tooteinfo: Undefined; 22 Kasutus- ja hooldusjuhend: Undefined
Pset_DoorCommon - ThermalTransmittance: 0; GlazingAreaFraction: 0; IsExternal: no
AC_Pset_RenovationAndPhasing - Renovation Status: New

# IfcDoor: SU-B211 950×2 300, Siseuks * Door 22
In: 2 KORRUS
Type - OperationType: SINGLE_SWING_LEFT; ParameterTakesPrecedence: no; Sizeable: no
Type - Door Lining Properties - LiningDepth: 115 mm; LiningThickness: 40 mm; LiningOffset: 0 mm; CasingThickness: 50 mm; CasingDepth: 19 mm
Type - Door Panel Properties - Panel 1 - PanelDepth: 40 mm; PanelOperation: SWINGING; PanelWidth: 1; PanelPosition: MIDDLE
OverallHeight: 2300 mm; OverallWidth: 950 mm; Classification: 1.9 IfcDoor (uks) (_RKAS BIM + ARCHICAD Classification); 52 Siseuksed (EHITUSKULUDE LIIGITAMINE EVS 885:2005)
Avatäited - 18 Viimistlus: RAL 9003; 01 Nimetus: Siseuks; 02 Materjal: Sile uks; 03 Tähistus: SU-B211 950×2 300; 04 Avamõõdu geomeetria: 950×2 300; 05 Asukoha info: Interior; 06 Soojusläbivus: -; 07 Helipidavus: 30 dB; 08 Veepidavus: -; 09 Õhuläbilaskvus: -; 10 Tulekindlus: nõudeid ei esitata; 11 Vastupanu tulekoormusele: -; 12 Klaaspakett: -; 13 Klaasingu erisused: -; 14 Päikesekiirgus tegur (g-väärtus): -; 15 Avanemine: Avanemine: "R" (L - vasak; R - parem); 16 Liigendatus: Lävepakk madal max 25mm, roostevaba; 17 Sulused, lukustus: vt lukustuse spetsifikatsioon; 19 Mudel või toote tunnus: Undefined; 20 Tootja: Undefined; 21 Tooteinfo: Undefined; 22 Kasutus- ja hooldusjuhend: Undefined
Pset_DoorCommon - ThermalTransmittance: 0; GlazingAreaFraction: 0; IsExternal: no
AC_Pset_RenovationAndPhasing - Renovation Status: New

# IfcDoor: SU-B212 950×2 300, Siseuks * Door 22
In: 2 KORRUS
Type - OperationType: SINGLE_SWING_LEFT; ParameterTakesPrecedence: no; Sizeable: no
Type - Door Lining Properties - LiningDepth: 115 mm; LiningThickness: 40 mm; LiningOffset: 150 mm; CasingThickness: 50 mm; CasingDepth: 19 mm
Type - Door Panel Properties - Panel 1 - PanelDepth: 40 mm; PanelOperation: SWINGING; PanelWidth: 1; PanelPosition: MIDDLE
OverallHeight: 2300 mm; OverallWidth: 950 mm; Classification: 1.9 IfcDoor (uks) (_RKAS BIM + ARCHICAD Classification); 52 Siseuksed (EHITUSKULUDE LIIGITAMINE EVS 885:2005)
Avatäited - 18 Viimistlus: RAL 9003; 01 Nimetus: Siseuks; 02 Materjal: Sile uks; 03 Tähistus: SU-B212 950×2 300; 04 Avamõõdu geomeetria: 950×2 300; 05 Asukoha info: Interior; 06 Soojusläbivus: -; 07 Helipidavus: 30 dB; 08 Veepidavus: -; 09 Õhuläbilaskvus: -; 10 Tulekindlus: nõudeid ei esitata; 11 Vastupanu tulekoormusele: -; 12 Klaaspakett: -; 13 Klaasingu erisused: -; 14 Päikesekiirgus tegur (g-väärtus): -; 15 Avanemine: Avanemine: "R" (L - vasak; R - parem); 16 Liigendatus: Lävepakk madal max 25mm, roostevaba; 17 Sulused, lukustus: vt lukustuse spetsifikatsioon; 19 Mudel või toote tunnus: Undefined; 20 Tootja: Undefined; 21 Tooteinfo: Undefined; 22 Kasutus- ja hooldusjuhend: Undefined
Pset_DoorCommon - ThermalTransmittance: 0; GlazingAreaFraction: 0; IsExternal: no
AC_Pset_RenovationAndPhasing - Renovation Status: New

# IfcDoor: SU-B212A 1 000×2 100, Siseuks * Door 22
In: 2 KORRUS
Type - OperationType: SINGLE_SWING_RIGHT; ParameterTakesPrecedence: no; Sizeable: no
Type - Door Lining Properties - LiningDepth: 115 mm; LiningThickness: 40 mm; LiningOffset: 150 mm; CasingThickness: 50 mm; CasingDepth: 19 mm
Type - Door Panel Properties - Panel 1 - PanelDepth: 40 mm; PanelOperation: SWINGING; PanelWidth: 1; PanelPosition: MIDDLE
OverallHeight: 2100 mm; OverallWidth: 1000 mm; Classification: 1.9 IfcDoor (uks) (_RKAS BIM + ARCHICAD Classification); 52 Siseuksed (EHITUSKULUDE LIIGITAMINE EVS 885:2005)
Avatäited - 18 Viimistlus: RAL 9003; 01 Nimetus: Siseuks; 02 Materjal: Sile uks; 03 Tähistus: SU-B212A 1 000×2 100; 04 Avamõõdu geomeetria: 1 000×2 100; 05 Asukoha info: Interior; 06 Soojusläbivus: -; 07 Helipidavus: 30 dB; 08 Veepidavus: -; 09 Õhuläbilaskvus: -; 10 Tulekindlus: nõudeid ei esitata; 11 Vastupanu tulekoormusele: -; 12 Klaaspakett: -; 13 Klaasingu erisused: -; 14 Päikesekiirgus tegur (g-väärtus): -; 15 Avanemine: Avanemine: "L" (L - vasak; R - parem); 16 Liigendatus: Lävepakk madal max 25mm, roostevaba; 17 Sulused, lukustus: vt lukustuse spetsifikatsioon; 19 Mudel või toote tunnus: Undefined; 20 Tootja: Undefined; 21 Tooteinfo: Undefined; 22 Kasutus- ja hooldusjuhend: Undefined
Pset_DoorCommon - ThermalTransmittance: 0; GlazingAreaFraction: 0; IsExternal: no
AC_Pset_RenovationAndPhasing - Renovation Status: New

# IfcDoor: SU-B214 1 680×2 300, Siseuks * Double Door 22
In: 2 KORRUS
Type - OperationType: DOUBLE_DOOR_SINGLE_SWING; ParameterTakesPrecedence: no; Sizeable: no
Type - Door Lining Properties - LiningDepth: 115 mm; LiningThickness: 40 mm; LiningOffset: 115 mm; CasingThickness: 50 mm; CasingDepth: 19 mm
Type - Door Panel Properties - Panel 1 - PanelDepth: 40 mm; PanelOperation: SWINGING; PanelWidth: 0.5075; PanelPosition: RIGHT
Type - Door Panel Properties - Panel 2 - PanelDepth: 40 mm; PanelOperation: SWINGING; PanelWidth: 0.5075; PanelPosition: LEFT
OverallHeight: 2300 mm; OverallWidth: 1680 mm; Classification: 1.9 IfcDoor (uks) (_RKAS BIM + ARCHICAD Classification); 52 Siseuksed (EHITUSKULUDE LIIGITAMINE EVS 885:2005)
Avatäited - 18 Viimistlus: RAL 9003; 01 Nimetus: Siseuks; 02 Materjal: Alumiiniumprofiil pulbervärvitud; 03 Tähistus: SU-B214 1 680×2 300; 04 Avamõõdu geomeetria: 1 680×2 300; 05 Asukoha info: Interior; 06 Soojusläbivus: -; 07 Helipidavus: 30 dB; 08 Veepidavus: -; 09 Õhuläbilaskvus: -; 10 Tulekindlus: nõudeid ei esitata; 11 Vastupanu tulekoormusele: -; 12 Klaaspakett: Karastatud ja lamineeritud kirgas klaas; 13 Klaasingu erisused: -; 14 Päikesekiirgus tegur (g-väärtus): -; 15 Avanemine: Avanemine: "R" (L - vasak; R - parem); 16 Liigendatus: Lävepakk madal max 25mm, roostevaba; 17 Sulused, lukustus: vt lukustuse spetsifikatsioon; 19 Mudel või toote tunnus: Undefined; 20 Tootja: Undefined; 21 Tooteinfo: Undefined; 22 Kasutus- ja hooldusjuhend: Undefined
Pset_DoorCommon - ThermalTransmittance: 0; GlazingAreaFraction: 2.41373; IsExternal: no
AC_Pset_RenovationAndPhasing - Renovation Status: New

# IfcDoor: SU-B215 950×2 370, Siseuks * Door 22
In: 2 KORRUS
Type - OperationType: SINGLE_SWING_LEFT; ParameterTakesPrecedence: no; Sizeable: no
Type - Door Lining Properties - LiningDepth: 115 mm; LiningThickness: 40 mm; LiningOffset: 150 mm; CasingThickness: 50 mm; CasingDepth: 19 mm
Type - Door Panel Properties - Panel 1 - PanelDepth: 40 mm; PanelOperation: SWINGING; PanelWidth: 1; PanelPosition: MIDDLE
OverallHeight: 2370 mm; OverallWidth: 950 mm; Classification: 1.9 IfcDoor (uks) (_RKAS BIM + ARCHICAD Classification); 52 Siseuksed (EHITUSKULUDE LIIGITAMINE EVS 885:2005)
Avatäited - 18 Viimistlus: RAL 9003; 01 Nimetus: Siseuks; 02 Materjal: Sile uks; 03 Tähistus: SU-B215 950×2 370; 04 Avamõõdu geomeetria: 950×2 370; 05 Asukoha info: Interior; 06 Soojusläbivus: -; 07 Helipidavus: 30 dB; 08 Veepidavus: -; 09 Õhuläbilaskvus: -; 10 Tulekindlus: nõudeid ei esitata; 11 Vastupanu tulekoormusele: -; 12 Klaaspakett: -; 13 Klaasingu erisused: -; 14 Päikesekiirgus tegur (g-väärtus): -; 15 Avanemine: Avanemine: "R" (L - vasak; R - parem); 16 Liigendatus: Lävepakk madal max 25mm, roostevaba; 17 Sulused, lukustus: vt lukustuse spetsifikatsioon; 19 Mudel või toote tunnus: Undefined; 20 Tootja: Undefined; 21 Tooteinfo: Undefined; 22 Kasutus- ja hooldusjuhend: Undefined
Pset_DoorCommon - ThermalTransmittance: 0; GlazingAreaFraction: 0; IsExternal: no
AC_Pset_RenovationAndPhasing - Renovation Status: New

# IfcDoor: SU-B216 950×2 370, Siseuks * Door 22
In: 2 KORRUS
Type - OperationType: SINGLE_SWING_LEFT; ParameterTakesPrecedence: no; Sizeable: no
Type - Door Lining Properties - LiningDepth: 115 mm; LiningThickness: 40 mm; LiningOffset: 0 mm; CasingThickness: 50 mm; CasingDepth: 19 mm
Type - Door Panel Properties - Panel 1 - PanelDepth: 40 mm; PanelOperation: SWINGING; PanelWidth: 1; PanelPosition: MIDDLE
OverallHeight: 2370 mm; OverallWidth: 950 mm; Classification: 1.9 IfcDoor (uks) (_RKAS BIM + ARCHICAD Classification); 52 Siseuksed (EHITUSKULUDE LIIGITAMINE EVS 885:2005)
Avatäited - 18 Viimistlus: RAL 9003; 01 Nimetus: Siseuks; 02 Materjal: Sile uks; 03 Tähistus: SU-B216 950×2 370; 04 Avamõõdu geomeetria: 950×2 370; 05 Asukoha info: Interior; 06 Soojusläbivus: -; 07 Helipidavus: 30 dB; 08 Veepidavus: -; 09 Õhuläbilaskvus: -; 10 Tulekindlus: nõudeid ei esitata; 11 Vastupanu tulekoormusele: -; 12 Klaaspakett: -; 13 Klaasingu erisused: -; 14 Päikesekiirgus tegur (g-väärtus): -; 15 Avanemine: Avanemine: "R" (L - vasak; R - parem); 16 Liigendatus: Lävepakk madal max 25mm, roostevaba; 17 Sulused, lukustus: vt lukustuse spetsifikatsioon; 19 Mudel või toote tunnus: Undefined; 20 Tootja: Undefined; 21 Tooteinfo: Undefined; 22 Kasutus- ja hooldusjuhend: Undefined
Pset_DoorCommon - ThermalTransmittance: 0; GlazingAreaFraction: 0; IsExternal: no
AC_Pset_RenovationAndPhasing - Renovation Status: New

# IfcDoor: SU-B217 950×2 370, Siseuks * Door 22
In: 2 KORRUS
Type - OperationType: SINGLE_SWING_LEFT; ParameterTakesPrecedence: no; Sizeable: no
Type - Door Lining Properties - LiningDepth: 115 mm; LiningThickness: 40 mm; LiningOffset: 150 mm; CasingThickness: 50 mm; CasingDepth: 19 mm
Type - Door Panel Properties - Panel 1 - PanelDepth: 40 mm; PanelOperation: SWINGING; PanelWidth: 1; PanelPosition: MIDDLE
OverallHeight: 2370 mm; OverallWidth: 950 mm; Classification: 1.9 IfcDoor (uks) (_RKAS BIM + ARCHICAD Classification); 52 Siseuksed (EHITUSKULUDE LIIGITAMINE EVS 885:2005)
Avatäited - 18 Viimistlus: RAL 9003; 01 Nimetus: Siseuks; 02 Materjal: Sile uks; 03 Tähistus: SU-B217 950×2 370; 04 Avamõõdu geomeetria: 950×2 370; 05 Asukoha info: Interior; 06 Soojusläbivus: -; 07 Helipidavus: 30 dB; 08 Veepidavus: -; 09 Õhuläbilaskvus: -; 10 Tulekindlus: nõudeid ei esitata; 11 Vastupanu tulekoormusele: -; 12 Klaaspakett: -; 13 Klaasingu erisused: -; 14 Päikesekiirgus tegur (g-väärtus): -; 15 Avanemine: Avanemine: "R" (L - vasak; R - parem); 16 Liigendatus: Lävepakk madal max 25mm, roostevaba; 17 Sulused, lukustus: vt lukustuse spetsifikatsioon; 19 Mudel või toote tunnus: Undefined; 20 Tootja: Undefined; 21 Tooteinfo: Undefined; 22 Kasutus- ja hooldusjuhend: Undefined
Pset_DoorCommon - ThermalTransmittance: 0; GlazingAreaFraction: 0; IsExternal: no
AC_Pset_RenovationAndPhasing - Renovation Status: New

# IfcDoor: SU-B217A 900×2 100, Siseuks * Door 22
In: 2 KORRUS
Type - OperationType: SINGLE_SWING_LEFT; ParameterTakesPrecedence: no; Sizeable: no
Type - Door Lining Properties - LiningDepth: 115 mm; LiningThickness: 40 mm; LiningOffset: -35 mm; CasingThickness: 50 mm; CasingDepth: 19 mm
Type - Door Panel Properties - Panel 1 - PanelDepth: 40 mm; PanelOperation: SWINGING; PanelWidth: 1; PanelPosition: MIDDLE
OverallHeight: 2100 mm; OverallWidth: 900 mm; Classification: 1.9 IfcDoor (uks) (_RKAS BIM + ARCHICAD Classification); 52 Siseuksed (EHITUSKULUDE LIIGITAMINE EVS 885:2005)
Avatäited - 18 Viimistlus: RAL 9003; 01 Nimetus: Siseuks; 02 Materjal: Sile uks; 03 Tähistus: SU-B217A 900×2 100; 04 Avamõõdu geomeetria: 900×2 100; 05 Asukoha info: Interior; 06 Soojusläbivus: -; 07 Helipidavus: 30 dB; 08 Veepidavus: -; 09 Õhuläbilaskvus: -; 10 Tulekindlus: nõudeid ei esitata; 11 Vastupanu tulekoormusele: -; 12 Klaaspakett: -; 13 Klaasingu erisused: -; 14 Päikesekiirgus tegur (g-väärtus): -; 15 Avanemine: Avanemine: "R" (L - vasak; R - parem); 16 Liigendatus: Lävepakk madal max 25mm, roostevaba; 17 Sulused, lukustus: vt lukustuse spetsifikatsioon; 19 Mudel või toote tunnus: Undefined; 20 Tootja: Undefined; 21 Tooteinfo: Undefined; 22 Kasutus- ja hooldusjuhend: Undefined
Pset_DoorCommon - ThermalTransmittance: 0; GlazingAreaFraction: 0; IsExternal: no
AC_Pset_RenovationAndPhasing - Renovation Status: New

# IfcDoor: SU-B218 950×2 370, Siseuks * Door 22
In: 2 KORRUS
Type - OperationType: SINGLE_SWING_LEFT; ParameterTakesPrecedence: no; Sizeable: no
Type - Door Lining Properties - LiningDepth: 115 mm; LiningThickness: 40 mm; LiningOffset: -305 mm; CasingThickness: 50 mm; CasingDepth: 19 mm
Type - Door Panel Properties - Panel 1 - PanelDepth: 40 mm; PanelOperation: SWINGING; PanelWidth: 1; PanelPosition: MIDDLE
OverallHeight: 2370 mm; OverallWidth: 950 mm; Classification: 1.9 IfcDoor (uks) (_RKAS BIM + ARCHICAD Classification); 52 Siseuksed (EHITUSKULUDE LIIGITAMINE EVS 885:2005)
Avatäited - 18 Viimistlus: RAL 9003; 01 Nimetus: Siseuks; 02 Materjal: Sile uks; 03 Tähistus: SU-B218 950×2 370; 04 Avamõõdu geomeetria: 950×2 370; 05 Asukoha info: Interior; 06 Soojusläbivus: -; 07 Helipidavus: 30 dB; 08 Veepidavus: -; 09 Õhuläbilaskvus: -; 10 Tulekindlus: nõudeid ei esitata; 11 Vastupanu tulekoormusele: -; 12 Klaaspakett: -; 13 Klaasingu erisused: -; 14 Päikesekiirgus tegur (g-väärtus): -; 15 Avanemine: Avanemine: "R" (L - vasak; R - parem); 16 Liigendatus: Lävepakk madal max 25mm, roostevaba; 17 Sulused, lukustus: vt lukustuse spetsifikatsioon; 19 Mudel või toote tunnus: Undefined; 20 Tootja: Undefined; 21 Tooteinfo: Undefined; 22 Kasutus- ja hooldusjuhend: Undefined
Pset_DoorCommon - ThermalTransmittance: 0; GlazingAreaFraction: 0; IsExternal: no
AC_Pset_RenovationAndPhasing - Renovation Status: New

# IfcDoor: SU-B219 950×2 370, Siseuks * Door 22
In: 2 KORRUS
Type - OperationType: SINGLE_SWING_LEFT; ParameterTakesPrecedence: no; Sizeable: no
Type - Door Lining Properties - LiningDepth: 115 mm; LiningThickness: 40 mm; LiningOffset: 150 mm; CasingThickness: 50 mm; CasingDepth: 19 mm
Type - Door Panel Properties - Panel 1 - PanelDepth: 40 mm; PanelOperation: SWINGING; PanelWidth: 1; PanelPosition: MIDDLE
OverallHeight: 2370 mm; OverallWidth: 950 mm; Classification: 1.9 IfcDoor (uks) (_RKAS BIM + ARCHICAD Classification); 52 Siseuksed (EHITUSKULUDE LIIGITAMINE EVS 885:2005)
Avatäited - 18 Viimistlus: RAL 9003; 01 Nimetus: Siseuks; 02 Materjal: Sile uks; 03 Tähistus: SU-B219 950×2 370; 04 Avamõõdu geomeetria: 950×2 370; 05 Asukoha info: Interior; 06 Soojusläbivus: -; 07 Helipidavus: 30 dB; 08 Veepidavus: -; 09 Õhuläbilaskvus: -; 10 Tulekindlus: nõudeid ei esitata; 11 Vastupanu tulekoormusele: -; 12 Klaaspakett: -; 13 Klaasingu erisused: -; 14 Päikesekiirgus tegur (g-väärtus): -; 15 Avanemine: Avanemine: "R" (L - vasak; R - parem); 16 Liigendatus: Lävepakk madal max 25mm, roostevaba; 17 Sulused, lukustus: vt lukustuse spetsifikatsioon; 19 Mudel või toote tunnus: Undefined; 20 Tootja: Undefined; 21 Tooteinfo: Undefined; 22 Kasutus- ja hooldusjuhend: Undefined
Pset_DoorCommon - ThermalTransmittance: 0; GlazingAreaFraction: 0; IsExternal: no
AC_Pset_RenovationAndPhasing - Renovation Status: New

# IfcDoor: SU-B220A 950×2 370, Siseuks * Door 22
In: 2 KORRUS
Type - OperationType: SINGLE_SWING_RIGHT; ParameterTakesPrecedence: no; Sizeable: no
Type - Door Lining Properties - LiningDepth: 115 mm; LiningThickness: 40 mm; LiningOffset: 420 mm; CasingThickness: 50 mm; CasingDepth: 19 mm
Type - Door Panel Properties - Panel 1 - PanelDepth: 40 mm; PanelOperation: SWINGING; PanelWidth: 1; PanelPosition: MIDDLE
Description: Teras; OverallHeight: 2370 mm; OverallWidth: 950 mm; Classification: 1.9 IfcDoor (uks) (_RKAS BIM + ARCHICAD Classification); 52 Siseuksed (EHITUSKULUDE LIIGITAMINE EVS 885:2005)
Pset_DoorCommon - FireRating: EI30; ThermalTransmittance: 0; GlazingAreaFraction: 0; IsExternal: no
Avatäited - 18 Viimistlus: RAL 9003; 01 Nimetus: Siseuks; 02 Materjal: Sile uks; 03 Tähistus: SU-B220A 950×2 370; 04 Avamõõdu geomeetria: 950×2 370; 05 Asukoha info: Interior; 06 Soojusläbivus: -; 07 Helipidavus: 30 dB; 08 Veepidavus: -; 09 Õhuläbilaskvus: -; 10 Tulekindlus: EI 30; 11 Vastupanu tulekoormusele: -; 12 Klaaspakett: -; 13 Klaasingu erisused: -; 14 Päikesekiirgus tegur (g-väärtus): -; 15 Avanemine: Avanemine: "L" (L - vasak; R - parem); 16 Liigendatus: Lävepakk madal max 25mm, roostevaba; 17 Sulused, lukustus: vt lukustuse spetsifikatsioon; 19 Mudel või toote tunnus: Undefined; 20 Tootja: Undefined; 21 Tooteinfo: Undefined; 22 Kasutus- ja hooldusjuhend: Undefined
AC_Pset_RenovationAndPhasing - Renovation Status: New

# IfcDoor: SU-B220B 950×2 370, Siseuks * Door 22
In: 2 KORRUS
Type - OperationType: SINGLE_SWING_RIGHT; ParameterTakesPrecedence: no; Sizeable: no
Type - Door Lining Properties - LiningDepth: 115 mm; LiningThickness: 40 mm; LiningOffset: 0 mm; CasingThickness: 50 mm; CasingDepth: 19 mm
Type - Door Panel Properties - Panel 1 - PanelDepth: 40 mm; PanelOperation: SWINGING; PanelWidth: 1; PanelPosition: MIDDLE
OverallHeight: 2370 mm; OverallWidth: 950 mm; Classification: 1.9 IfcDoor (uks) (_RKAS BIM + ARCHICAD Classification); 52 Siseuksed (EHITUSKULUDE LIIGITAMINE EVS 885:2005)
Pset_DoorCommon - ThermalTransmittance: 0; GlazingAreaFraction: 0; IsExternal: no
Avatäited - 01 Nimetus: Siseuks; 02 Materjal: Sile uks; 03 Tähistus: SU-B220B 950×2 370; 04 Avamõõdu geomeetria: 950×2 370; 05 Asukoha info: Interior; 06 Soojusläbivus: -; 07 Helipidavus: 30 dB; 08 Veepidavus: -; 09 Õhuläbilaskvus: -; 10 Tulekindlus: EI 30; 11 Vastupanu tulekoormusele: -; 12 Klaaspakett: -; 13 Klaasingu erisused: -; 14 Päikesekiirgus tegur (g-väärtus): -; 15 Avanemine: Avanemine: "L" (L - vasak; R - parem); 16 Liigendatus: Lävepakk madal max 25mm, roostevaba; 17 Sulused, lukustus: vt lukustuse spetsifikatsioon; 18 Viimistlus: Leng väljast: Paint - Glossy White; Leng seest: Paint - Glossy White; Ukseleht väljast: Paint - Glossy White; Ukseleht seest: Paint - Glossy White; Täpsustus: RAL 9003; 19 Mudel või toote tunnus: Undefined; 20 Tootja: Undefined; 21 Tooteinfo: Undefined; 22 Kasutus- ja hooldusjuhend: Undefined
AC_Pset_RenovationAndPhasing - Renovation Status: New

# IfcDoor: SU-B221 950×2 370, Siseuks * Door 22
In: 2 KORRUS
Type - OperationType: SINGLE_SWING_LEFT; ParameterTakesPrecedence: no; Sizeable: no
Type - Door Lining Properties - LiningDepth: 115 mm; LiningThickness: 40 mm; LiningOffset: 150 mm; CasingThickness: 50 mm; CasingDepth: 19 mm
Type - Door Panel Properties - Panel 1 - PanelDepth: 40 mm; PanelOperation: SWINGING; PanelWidth: 1; PanelPosition: MIDDLE
OverallHeight: 2370 mm; OverallWidth: 950 mm; Classification: 1.9 IfcDoor (uks) (_RKAS BIM + ARCHICAD Classification); 52 Siseuksed (EHITUSKULUDE LIIGITAMINE EVS 885:2005)
Avatäited - 18 Viimistlus: RAL 9003; 01 Nimetus: Siseuks; 02 Materjal: Sile uks; 03 Tähistus: SU-B221 950×2 370; 04 Avamõõdu geomeetria: 950×2 370; 05 Asukoha info: Interior; 06 Soojusläbivus: -; 07 Helipidavus: 30 dB; 08 Veepidavus: -; 09 Õhuläbilaskvus: -; 10 Tulekindlus: nõudeid ei esitata; 11 Vastupanu tulekoormusele: -; 12 Klaaspakett: -; 13 Klaasingu erisused: -; 14 Päikesekiirgus tegur (g-väärtus): -; 15 Avanemine: Avanemine: "R" (L - vasak; R - parem); 16 Liigendatus: Lävepakk madal max 25mm, roostevaba; 17 Sulused, lukustus: vt lukustuse spetsifikatsioon; 19 Mudel või toote tunnus: Undefined; 20 Tootja: Undefined; 21 Tooteinfo: Undefined; 22 Kasutus- ja hooldusjuhend: Undefined
Pset_DoorCommon - ThermalTransmittance: 0; GlazingAreaFraction: 0; IsExternal: no
AC_Pset_RenovationAndPhasing - Renovation Status: New

# IfcDoor: SU-B222 950×2 370, Siseuks * Door 22
In: 2 KORRUS
Type - OperationType: SINGLE_SWING_LEFT; ParameterTakesPrecedence: no; Sizeable: no
Type - Door Lining Properties - LiningDepth: 115 mm; LiningThickness: 40 mm; LiningOffset: -305 mm; CasingThickness: 50 mm; CasingDepth: 19 mm
Type - Door Panel Properties - Panel 1 - PanelDepth: 40 mm; PanelOperation: SWINGING; PanelWidth: 1; PanelPosition: MIDDLE
OverallHeight: 2370 mm; OverallWidth: 950 mm; Classification: 1.9 IfcDoor (uks) (_RKAS BIM + ARCHICAD Classification); 52 Siseuksed (EHITUSKULUDE LIIGITAMINE EVS 885:2005)
Avatäited - 18 Viimistlus: RAL 9003; 01 Nimetus: Siseuks; 02 Materjal: Sile uks; 03 Tähistus: SU-B222 950×2 370; 04 Avamõõdu geomeetria: 950×2 370; 05 Asukoha info: Interior; 06 Soojusläbivus: -; 07 Helipidavus: 30 dB; 08 Veepidavus: -; 09 Õhuläbilaskvus: -; 10 Tulekindlus: nõudeid ei esitata; 11 Vastupanu tulekoormusele: -; 12 Klaaspakett: -; 13 Klaasingu erisused: -; 14 Päikesekiirgus tegur (g-väärtus): -; 15 Avanemine: Avanemine: "R" (L - vasak; R - parem); 16 Liigendatus: Lävepakk madal max 25mm, roostevaba; 17 Sulused, lukustus: vt lukustuse spetsifikatsioon; 19 Mudel või toote tunnus: Undefined; 20 Tootja: Undefined; 21 Tooteinfo: Undefined; 22 Kasutus- ja hooldusjuhend: Undefined
Pset_DoorCommon - ThermalTransmittance: 0; GlazingAreaFraction: 0; IsExternal: no
AC_Pset_RenovationAndPhasing - Renovation Status: New

# IfcDoor: SU-B223 950×2 370, Siseuks * Door 22
In: 2 KORRUS
Type - OperationType: SINGLE_SWING_LEFT; ParameterTakesPrecedence: no; Sizeable: no
Type - Door Lining Properties - LiningDepth: 115 mm; LiningThickness: 40 mm; LiningOffset: -305 mm; CasingThickness: 50 mm; CasingDepth: 19 mm
Type - Door Panel Properties - Panel 1 - PanelDepth: 40 mm; PanelOperation: SWINGING; PanelWidth: 1; PanelPosition: MIDDLE
OverallHeight: 2370 mm; OverallWidth: 950 mm; Classification: 1.9 IfcDoor (uks) (_RKAS BIM + ARCHICAD Classification); 52 Siseuksed (EHITUSKULUDE LIIGITAMINE EVS 885:2005)
Avatäited - 18 Viimistlus: RAL 9003; 01 Nimetus: Siseuks; 02 Materjal: Sile uks; 03 Tähistus: SU-B223 950×2 370; 04 Avamõõdu geomeetria: 950×2 370; 05 Asukoha info: Interior; 06 Soojusläbivus: -; 07 Helipidavus: 30 dB; 08 Veepidavus: -; 09 Õhuläbilaskvus: -; 10 Tulekindlus: nõudeid ei esitata; 11 Vastupanu tulekoormusele: -; 12 Klaaspakett: -; 13 Klaasingu erisused: -; 14 Päikesekiirgus tegur (g-väärtus): -; 15 Avanemine: Avanemine: "R" (L - vasak; R - parem); 16 Liigendatus: Lävepakk madal max 25mm, roostevaba; 17 Sulused, lukustus: vt lukustuse spetsifikatsioon; 19 Mudel või toote tunnus: Undefined; 20 Tootja: Undefined; 21 Tooteinfo: Undefined; 22 Kasutus- ja hooldusjuhend: Undefined
Pset_DoorCommon - ThermalTransmittance: 0; GlazingAreaFraction: 0; IsExternal: no
AC_Pset_RenovationAndPhasing - Renovation Status: New

# IfcDoor: SU-B224 970×2 100, Siseuks * Door 22
In: 2 KORRUS
Type - OperationType: SINGLE_SWING_RIGHT; ParameterTakesPrecedence: no; Sizeable: no
Type - Door Lining Properties - LiningDepth: 115 mm; LiningThickness: 40 mm; LiningOffset: -35 mm; CasingThickness: 50 mm; CasingDepth: 19 mm
Type - Door Panel Properties - Panel 1 - PanelDepth: 40 mm; PanelOperation: SWINGING; PanelWidth: 1; PanelPosition: MIDDLE
OverallHeight: 2100 mm; OverallWidth: 970 mm; Classification: 1.9 IfcDoor (uks) (_RKAS BIM + ARCHICAD Classification); 52 Siseuksed (EHITUSKULUDE LIIGITAMINE EVS 885:2005)
Avatäited - 18 Viimistlus: RAL 9003; 01 Nimetus: Siseuks; 02 Materjal: Sile uks; 03 Tähistus: SU-B224 970×2 100; 04 Avamõõdu geomeetria: 970×2 100; 05 Asukoha info: Interior; 06 Soojusläbivus: -; 07 Helipidavus: 30 dB; 08 Veepidavus: -; 09 Õhuläbilaskvus: -; 10 Tulekindlus: nõudeid ei esitata; 11 Vastupanu tulekoormusele: -; 12 Klaaspakett: -; 13 Klaasingu erisused: -; 14 Päikesekiirgus tegur (g-väärtus): -; 15 Avanemine: Avanemine: "L" (L - vasak; R - parem); 16 Liigendatus: Lävepakk madal max 25mm, roostevaba; 17 Sulused, lukustus: vt lukustuse spetsifikatsioon; 19 Mudel või toote tunnus: Undefined; 20 Tootja: Undefined; 21 Tooteinfo: Undefined; 22 Kasutus- ja hooldusjuhend: Undefined
Pset_DoorCommon - ThermalTransmittance: 0; GlazingAreaFraction: 0; IsExternal: no
AC_Pset_RenovationAndPhasing - Renovation Status: New

# IfcDoor: SU-B225 1 000×2 370, Siseuks * Door 22
In: 2 KORRUS
Type - OperationType: SINGLE_SWING_LEFT; ParameterTakesPrecedence: no; Sizeable: no
Type - Door Lining Properties - LiningDepth: 115 mm; LiningThickness: 40 mm; LiningOffset: 150 mm; CasingThickness: 50 mm; CasingDepth: 19 mm
Type - Door Panel Properties - Panel 1 - PanelDepth: 40 mm; PanelOperation: SWINGING; PanelWidth: 1; PanelPosition: MIDDLE
OverallHeight: 2370 mm; OverallWidth: 1000 mm; Classification: 1.9 IfcDoor (uks) (_RKAS BIM + ARCHICAD Classification); 52 Siseuksed (EHITUSKULUDE LIIGITAMINE EVS 885:2005)
Avatäited - 18 Viimistlus: RAL 9003; 01 Nimetus: Siseuks; 02 Materjal: Sile uks; 03 Tähistus: SU-B225 1 000×2 370; 04 Avamõõdu geomeetria: 1 000×2 370; 05 Asukoha info: Interior; 06 Soojusläbivus: -; 07 Helipidavus: 30 dB; 08 Veepidavus: -; 09 Õhuläbilaskvus: -; 10 Tulekindlus: nõudeid ei esitata; 11 Vastupanu tulekoormusele: -; 12 Klaaspakett: -; 13 Klaasingu erisused: -; 14 Päikesekiirgus tegur (g-väärtus): -; 15 Avanemine: Avanemine: "R" (L - vasak; R - parem); 16 Liigendatus: Lävepakk madal max 25mm, roostevaba; 17 Sulused, lukustus: vt lukustuse spetsifikatsioon; 19 Mudel või toote tunnus: Undefined; 20 Tootja: Undefined; 21 Tooteinfo: Undefined; 22 Kasutus- ja hooldusjuhend: Undefined
Pset_DoorCommon - ThermalTransmittance: 0; GlazingAreaFraction: 0; IsExternal: no
AC_Pset_RenovationAndPhasing - Renovation Status: New

# IfcDoor: SU-B225 A 950×2 370, Siseuks * Door 22
In: 2 KORRUS
Type - OperationType: SINGLE_SWING_LEFT; ParameterTakesPrecedence: no; Sizeable: no
Type - Door Lining Properties - LiningDepth: 115 mm; LiningThickness: 40 mm; LiningOffset: 150 mm; CasingThickness: 50 mm; CasingDepth: 19 mm
Type - Door Panel Properties - Panel 1 - PanelDepth: 40 mm; PanelOperation: SWINGING; PanelWidth: 1; PanelPosition: MIDDLE
OverallHeight: 2370 mm; OverallWidth: 950 mm; Classification: 1.9 IfcDoor (uks) (_RKAS BIM + ARCHICAD Classification); 52 Siseuksed (EHITUSKULUDE LIIGITAMINE EVS 885:2005)
Avatäited - 18 Viimistlus: RAL 9003; 01 Nimetus: Siseuks; 02 Materjal: Sile uks; 03 Tähistus: SU-B225 A 950×2 370; 04 Avamõõdu geomeetria: 950×2 370; 05 Asukoha info: Interior; 06 Soojusläbivus: -; 07 Helipidavus: 30 dB; 08 Veepidavus: -; 09 Õhuläbilaskvus: -; 10 Tulekindlus: nõudeid ei esitata; 11 Vastupanu tulekoormusele: -; 12 Klaaspakett: -; 13 Klaasingu erisused: -; 14 Päikesekiirgus tegur (g-väärtus): -; 15 Avanemine: Avanemine: "R" (L - vasak; R - parem); 16 Liigendatus: Lävepakk madal max 25mm, roostevaba; 17 Sulused, lukustus: vt lukustuse spetsifikatsioon; 19 Mudel või toote tunnus: Undefined; 20 Tootja: Undefined; 21 Tooteinfo: Undefined; 22 Kasutus- ja hooldusjuhend: Undefined
Pset_DoorCommon - ThermalTransmittance: 0; GlazingAreaFraction: 0; IsExternal: no
AC_Pset_RenovationAndPhasing - Renovation Status: New

# IfcDoor: SU-B226 1 900×2 870, Siseuks * Double Door with Transom 22
In: 2 KORRUS
Type - OperationType: DOUBLE_DOOR_SINGLE_SWING; ParameterTakesPrecedence: no; Sizeable: no
Type - Door Lining Properties - LiningDepth: 115 mm; LiningThickness: 40 mm; TransomThickness: 40 mm; TransomOffset: 2100 mm; LiningOffset: 0 mm; CasingThickness: 50 mm; CasingDepth: 19 mm
Type - Door Panel Properties - Panel 1 - PanelDepth: 40 mm; PanelOperation: SWINGING; PanelWidth: 0.506593; PanelPosition: LEFT
Type - Door Panel Properties - Panel 2 - PanelDepth: 40 mm; PanelOperation: SWINGING; PanelWidth: 0.506593; PanelPosition: RIGHT
OverallHeight: 2870 mm; OverallWidth: 1900 mm; Classification: 1.9 IfcDoor (uks) (_RKAS BIM + ARCHICAD Classification); 52 Siseuksed (EHITUSKULUDE LIIGITAMINE EVS 885:2005)
Avatäited - 18 Viimistlus: RAL 9003; 01 Nimetus: Siseuks; 02 Materjal: Alumiiniumprofiil pulbervärvitud; 03 Tähistus: SU-B226 1 900×2 870; 04 Avamõõdu geomeetria: 1 900×2 870; 05 Asukoha info: Interior; 06 Soojusläbivus: -; 07 Helipidavus: 30 dB; 08 Veepidavus: -; 09 Õhuläbilaskvus: -; 10 Tulekindlus: nõudeid ei esitata; 11 Vastupanu tulekoormusele: -; 12 Klaaspakett: Karastatud ja lamineeritud kirgas klaas; 13 Klaasingu erisused: -; 14 Päikesekiirgus tegur (g-väärtus): -; 15 Avanemine: Avanemine: "L" (L - vasak; R - parem); 16 Liigendatus: Lävepakk madal max 25mm, roostevaba; 17 Sulused, lukustus: vt lukustuse spetsifikatsioon; 19 Mudel või toote tunnus: Undefined; 20 Tootja: Undefined; 21 Tooteinfo: Undefined; 22 Kasutus- ja hooldusjuhend: Undefined
Pset_DoorCommon - ThermalTransmittance: 0; GlazingAreaFraction: 3.87233; IsExternal: no
AC_Pset_RenovationAndPhasing - Renovation Status: New

# IfcDoor: SU-B227A 1 600×2 000, Siseuks * Double Door 22
In: 2 KORRUS
Type - OperationType: DOUBLE_DOOR_SINGLE_SWING; ParameterTakesPrecedence: no; Sizeable: no
Type - Door Lining Properties - LiningDepth: 115 mm; LiningThickness: 40 mm; LiningOffset: 150 mm; CasingThickness: 50 mm; CasingDepth: 19 mm
Type - Door Panel Properties - Panel 1 - PanelDepth: 40 mm; PanelOperation: SWINGING; PanelWidth: 0.507895; PanelPosition: RIGHT
Type - Door Panel Properties - Panel 2 - PanelDepth: 40 mm; PanelOperation: SWINGING; PanelWidth: 0.507895; PanelPosition: LEFT
Description: Alumiinium, klaas; OverallHeight: 2000 mm; OverallWidth: 1600 mm; Classification: 1.9 IfcDoor (uks) (_RKAS BIM + ARCHICAD Classification); 52 Siseuksed (EHITUSKULUDE LIIGITAMINE EVS 885:2005)
Pset_DoorCommon - FireRating: EI30; ThermalTransmittance: 0; GlazingAreaFraction: 1.91277; IsExternal: no
Avatäited - 18 Viimistlus: RAL 9003; 01 Nimetus: Siseuks; 02 Materjal: Alumiiniumprofiil pulbervärvitud; 03 Tähistus: SU-B227A 1 600×2 000; 04 Avamõõdu geomeetria: 1 600×2 000; 05 Asukoha info: Interior; 06 Soojusläbivus: -; 07 Helipidavus: 30 dB; 08 Veepidavus: -; 09 Õhuläbilaskvus: -; 10 Tulekindlus: EI 30; 11 Vastupanu tulekoormusele: -; 12 Klaaspakett: Karastatud ja lamineeritud kirgas klaas; 13 Klaasingu erisused: -; 14 Päikesekiirgus tegur (g-väärtus): -; 15 Avanemine: Avanemine: "R" (L - vasak; R - parem); 16 Liigendatus: Lävepakk madal max 25mm, roostevaba; 17 Sulused, lukustus: vt lukustuse spetsifikatsioon; 19 Mudel või toote tunnus: Undefined; 20 Tootja: Undefined; 21 Tooteinfo: Undefined; 22 Kasutus- ja hooldusjuhend: Undefined
AC_Pset_RenovationAndPhasing - Renovation Status: New

# IfcDoor: SU-B227B 1 600×2 240, Siseuks * Double Door 22
In: 2 KORRUS
Type - OperationType: DOUBLE_DOOR_SINGLE_SWING; ParameterTakesPrecedence: no; Sizeable: no
Type - Door Lining Properties - LiningDepth: 115 mm; LiningThickness: 40 mm; LiningOffset: 150 mm; CasingThickness: 50 mm; CasingDepth: 19 mm
Type - Door Panel Properties - Panel 1 - PanelDepth: 40 mm; PanelOperation: SWINGING; PanelWidth: 0.507895; PanelPosition: RIGHT
Type - Door Panel Properties - Panel 2 - PanelDepth: 40 mm; PanelOperation: SWINGING; PanelWidth: 0.507895; PanelPosition: LEFT
Description: Alumiinium, klaas; OverallHeight: 2240 mm; OverallWidth: 1600 mm; Classification: 1.9 IfcDoor (uks) (_RKAS BIM + ARCHICAD Classification); 52 Siseuksed (EHITUSKULUDE LIIGITAMINE EVS 885:2005)
Pset_DoorCommon - FireRating: EI30; ThermalTransmittance: 0; GlazingAreaFraction: 2.18733; IsExternal: no
Avatäited - 18 Viimistlus: RAL 9003; 01 Nimetus: Siseuks; 02 Materjal: Alumiiniumprofiil pulbervärvitud; 03 Tähistus: SU-B227B 1 600×2 240; 04 Avamõõdu geomeetria: 1 600×2 240; 05 Asukoha info: Interior; 06 Soojusläbivus: -; 07 Helipidavus: 30 dB; 08 Veepidavus: -; 09 Õhuläbilaskvus: -; 10 Tulekindlus: EI 30; 11 Vastupanu tulekoormusele: -; 12 Klaaspakett: Karastatud ja lamineeritud kirgas klaas; 13 Klaasingu erisused: -; 14 Päikesekiirgus tegur (g-väärtus): -; 15 Avanemine: Avanemine: "R" (L - vasak; R - parem); 16 Liigendatus: Lävepakk madal max 25mm, roostevaba; 17 Sulused, lukustus: vt lukustuse spetsifikatsioon; 19 Mudel või toote tunnus: Undefined; 20 Tootja: Undefined; 21 Tooteinfo: Undefined; 22 Kasutus- ja hooldusjuhend: Undefined
AC_Pset_RenovationAndPhasing - Renovation Status: New

# IfcDoor: SU-B229 1 000×2 000, Siseuks * Door 22
In: 2 KORRUS
Type - OperationType: SINGLE_SWING_RIGHT; ParameterTakesPrecedence: no; Sizeable: no
Type - Door Lining Properties - LiningDepth: 115 mm; LiningThickness: 40 mm; LiningOffset: 300 mm; CasingThickness: 50 mm; CasingDepth: 19 mm
Type - Door Panel Properties - Panel 1 - PanelDepth: 40 mm; PanelOperation: SWINGING; PanelWidth: 1; PanelPosition: MIDDLE
OverallHeight: 2000 mm; OverallWidth: 1000 mm; Classification: 1.9 IfcDoor (uks) (_RKAS BIM + ARCHICAD Classification); 52 Siseuksed (EHITUSKULUDE LIIGITAMINE EVS 885:2005)
Avatäited - 18 Viimistlus: RAL 9003; 01 Nimetus: Siseuks; 02 Materjal: Sile uks; 03 Tähistus: SU-B229 1 000×2 000; 04 Avamõõdu geomeetria: 1 000×2 000; 05 Asukoha info: Interior; 06 Soojusläbivus: -; 07 Helipidavus: 30 dB; 08 Veepidavus: -; 09 Õhuläbilaskvus: -; 10 Tulekindlus: nõudeid ei esitata; 11 Vastupanu tulekoormusele: -; 12 Klaaspakett: -; 13 Klaasingu erisused: -; 14 Päikesekiirgus tegur (g-väärtus): -; 15 Avanemine: Avanemine: "L" (L - vasak; R - parem); 16 Liigendatus: Lävepakk madal max 25mm, roostevaba; 17 Sulused, lukustus: vt lukustuse spetsifikatsioon; 19 Mudel või toote tunnus: Undefined; 20 Tootja: Undefined; 21 Tooteinfo: Undefined; 22 Kasutus- ja hooldusjuhend: Undefined
Pset_DoorCommon - ThermalTransmittance: 0; GlazingAreaFraction: 0; IsExternal: no
AC_Pset_RenovationAndPhasing - Renovation Status: New

# IfcDoor: SU-B230 950×2 000, Siseuks * Door 22
In: 2 KORRUS
Type - OperationType: SINGLE_SWING_LEFT; ParameterTakesPrecedence: no; Sizeable: no
Type - Door Lining Properties - LiningDepth: 115 mm; LiningThickness: 40 mm; LiningOffset: -305 mm; CasingThickness: 50 mm; CasingDepth: 19 mm
Type - Door Panel Properties - Panel 1 - PanelDepth: 40 mm; PanelOperation: SWINGING; PanelWidth: 1; PanelPosition: MIDDLE
OverallHeight: 2000 mm; OverallWidth: 950 mm; Classification: 1.9 IfcDoor (uks) (_RKAS BIM + ARCHICAD Classification); 52 Siseuksed (EHITUSKULUDE LIIGITAMINE EVS 885:2005)
Avatäited - 18 Viimistlus: RAL 9003; 01 Nimetus: Siseuks; 02 Materjal: Sile uks; 03 Tähistus: SU-B230 950×2 000; 04 Avamõõdu geomeetria: 950×2 000; 05 Asukoha info: Interior; 06 Soojusläbivus: -; 07 Helipidavus: 30 dB; 08 Veepidavus: -; 09 Õhuläbilaskvus: -; 10 Tulekindlus: nõudeid ei esitata; 11 Vastupanu tulekoormusele: -; 12 Klaaspakett: -; 13 Klaasingu erisused: -; 14 Päikesekiirgus tegur (g-väärtus): -; 15 Avanemine: Avanemine: "R" (L - vasak; R - parem); 16 Liigendatus: Lävepakk madal max 25mm, roostevaba; 17 Sulused, lukustus: vt lukustuse spetsifikatsioon; 19 Mudel või toote tunnus: Undefined; 20 Tootja: Undefined; 21 Tooteinfo: Undefined; 22 Kasutus- ja hooldusjuhend: Undefined
Pset_DoorCommon - ThermalTransmittance: 0; GlazingAreaFraction: 0; IsExternal: no
AC_Pset_RenovationAndPhasing - Renovation Status: New

# IfcDoor: SU-B231A 750×2 000, Siseuks * Door 22
In: 2 KORRUS
Type - OperationType: SINGLE_SWING_LEFT; ParameterTakesPrecedence: no; Sizeable: no
Type - Door Lining Properties - LiningDepth: 115 mm; LiningThickness: 40 mm; LiningOffset: 420 mm; CasingThickness: 50 mm; CasingDepth: 19 mm
Type - Door Panel Properties - Panel 1 - PanelDepth: 40 mm; PanelOperation: SWINGING; PanelWidth: 1; PanelPosition: MIDDLE
OverallHeight: 2000 mm; OverallWidth: 750 mm; Classification: 1.9 IfcDoor (uks) (_RKAS BIM + ARCHICAD Classification); 52 Siseuksed (EHITUSKULUDE LIIGITAMINE EVS 885:2005)
Avatäited - 18 Viimistlus: RAL 9003; 01 Nimetus: Siseuks; 02 Materjal: Sile uks; 03 Tähistus: SU-B231A 750×2 000; 04 Avamõõdu geomeetria: 750×2 000; 05 Asukoha info: Interior; 06 Soojusläbivus: -; 07 Helipidavus: 30 dB; 08 Veepidavus: -; 09 Õhuläbilaskvus: -; 10 Tulekindlus: nõudeid ei esitata; 11 Vastupanu tulekoormusele: -; 12 Klaaspakett: -; 13 Klaasingu erisused: -; 14 Päikesekiirgus tegur (g-väärtus): -; 15 Avanemine: Avanemine: "R" (L - vasak; R - parem); 16 Liigendatus: Tuulututav lävepakk; 17 Sulused, lukustus: vt lukustuse spetsifikatsioon; 19 Mudel või toote tunnus: Undefined; 20 Tootja: Undefined; 21 Tooteinfo: Undefined; 22 Kasutus- ja hooldusjuhend: Undefined
Pset_DoorCommon - ThermalTransmittance: 0; GlazingAreaFraction: 0; IsExternal: no
AC_Pset_RenovationAndPhasing - Renovation Status: New

# IfcDoor: SU-B231B 700×2 100, Siseuks * Door 22
In: 2 KORRUS
Type - OperationType: SINGLE_SWING_LEFT; ParameterTakesPrecedence: no; Sizeable: no
Type - Door Lining Properties - LiningDepth: 115 mm; LiningThickness: 40 mm; LiningOffset: 100 mm; CasingThickness: 50 mm; CasingDepth: 19 mm
Type - Door Panel Properties - Panel 1 - PanelDepth: 40 mm; PanelOperation: SWINGING; PanelWidth: 1; PanelPosition: MIDDLE
OverallHeight: 2100 mm; OverallWidth: 700 mm; Classification: 1.9 IfcDoor (uks) (_RKAS BIM + ARCHICAD Classification); 52 Siseuksed (EHITUSKULUDE LIIGITAMINE EVS 885:2005)
Avatäited - 18 Viimistlus: RAL 9003; 01 Nimetus: Siseuks; 02 Materjal: Sile uks; 03 Tähistus: SU-B231B 700×2 100; 04 Avamõõdu geomeetria: 700×2 100; 05 Asukoha info: Interior; 06 Soojusläbivus: -; 07 Helipidavus: 30 dB; 08 Veepidavus: -; 09 Õhuläbilaskvus: -; 10 Tulekindlus: nõudeid ei esitata; 11 Vastupanu tulekoormusele: -; 12 Klaaspakett: -; 13 Klaasingu erisused: -; 14 Päikesekiirgus tegur (g-väärtus): -; 15 Avanemine: Avanemine: "R" (L - vasak; R - parem); 16 Liigendatus: Tuulututav lävepakk; 17 Sulused, lukustus: vt lukustuse spetsifikatsioon; 19 Mudel või toote tunnus: Undefined; 20 Tootja: Undefined; 21 Tooteinfo: Undefined; 22 Kasutus- ja hooldusjuhend: Undefined
Pset_DoorCommon - ThermalTransmittance: 0; GlazingAreaFraction: 0; IsExternal: no
AC_Pset_RenovationAndPhasing - Renovation Status: New

# IfcDoor: SU-B231C 700×2 100, Siseuks * Door 22
In: 2 KORRUS
Type - OperationType: SINGLE_SWING_RIGHT; ParameterTakesPrecedence: no; Sizeable: no
Type - Door Lining Properties - LiningDepth: 115 mm; LiningThickness: 40 mm; LiningOffset: 100 mm; CasingThickness: 50 mm; CasingDepth: 19 mm
Type - Door Panel Properties - Panel 1 - PanelDepth: 40 mm; PanelOperation: SWINGING; PanelWidth: 1; PanelPosition: MIDDLE
OverallHeight: 2100 mm; OverallWidth: 700 mm; Classification: 1.9 IfcDoor (uks) (_RKAS BIM + ARCHICAD Classification); 52 Siseuksed (EHITUSKULUDE LIIGITAMINE EVS 885:2005)
Avatäited - 18 Viimistlus: RAL 9003; 01 Nimetus: Siseuks; 02 Materjal: Sile uks; 03 Tähistus: SU-B231C 700×2 100; 04 Avamõõdu geomeetria: 700×2 100; 05 Asukoha info: Interior; 06 Soojusläbivus: -; 07 Helipidavus: 30 dB; 08 Veepidavus: -; 09 Õhuläbilaskvus: -; 10 Tulekindlus: nõudeid ei esitata; 11 Vastupanu tulekoormusele: -; 12 Klaaspakett: -; 13 Klaasingu erisused: -; 14 Päikesekiirgus tegur (g-väärtus): -; 15 Avanemine: Avanemine: "L" (L - vasak; R - parem); 16 Liigendatus: Tuulututab lävepakk; 17 Sulused, lukustus: vt lukustuse spetsifikatsioon; 19 Mudel või toote tunnus: Undefined; 20 Tootja: Undefined; 21 Tooteinfo: Undefined; 22 Kasutus- ja hooldusjuhend: Undefined
Pset_DoorCommon - ThermalTransmittance: 0; GlazingAreaFraction: 0; IsExternal: no
AC_Pset_RenovationAndPhasing - Renovation Status: New

# IfcDoor: SU-B232 800×2 100, Siseuks * Door 22
In: 2 KORRUS
Type - OperationType: SINGLE_SWING_RIGHT; ParameterTakesPrecedence: no; Sizeable: no
Type - Door Lining Properties - LiningDepth: 115 mm; LiningThickness: 40 mm; LiningOffset: 100 mm; CasingThickness: 50 mm; CasingDepth: 19 mm
Type - Door Panel Properties - Panel 1 - PanelDepth: 40 mm; PanelOperation: SWINGING; PanelWidth: 1; PanelPosition: MIDDLE
OverallHeight: 2100 mm; OverallWidth: 800 mm; Classification: 1.9 IfcDoor (uks) (_RKAS BIM + ARCHICAD Classification); 52 Siseuksed (EHITUSKULUDE LIIGITAMINE EVS 885:2005)
Avatäited - 18 Viimistlus: RAL 9003; 01 Nimetus: Siseuks; 02 Materjal: Sile uks; 03 Tähistus: SU-B232 800×2 100; 04 Avamõõdu geomeetria: 800×2 100; 05 Asukoha info: Interior; 06 Soojusläbivus: -; 07 Helipidavus: 30 dB; 08 Veepidavus: niiskuskindel uks; 09 Õhuläbilaskvus: -; 10 Tulekindlus: nõudeid ei esitata; 11 Vastupanu tulekoormusele: -; 12 Klaaspakett: -; 13 Klaasingu erisused: -; 14 Päikesekiirgus tegur (g-väärtus): -; 15 Avanemine: Avanemine: "L" (L - vasak; R - parem); 16 Liigendatus: Lävepakk madal max 25mm, roostevaba; 17 Sulused, lukustus: vt lukustuse spetsifikatsioon; 19 Mudel või toote tunnus: Undefined; 20 Tootja: Undefined; 21 Tooteinfo: Undefined; 22 Kasutus- ja hooldusjuhend: Undefined
Pset_DoorCommon - ThermalTransmittance: 0; GlazingAreaFraction: 0; IsExternal: no
AC_Pset_RenovationAndPhasing - Renovation Status: New

# IfcDoor: SU-B233A 800×2 100, Siseuks * Door 22
In: 2 KORRUS
Type - OperationType: SINGLE_SWING_LEFT; ParameterTakesPrecedence: no; Sizeable: no
Type - Door Lining Properties - LiningDepth: 115 mm; LiningThickness: 40 mm; LiningOffset: 420 mm; CasingThickness: 50 mm; CasingDepth: 19 mm
Type - Door Panel Properties - Panel 1 - PanelDepth: 40 mm; PanelOperation: SWINGING; PanelWidth: 1; PanelPosition: MIDDLE
OverallHeight: 2100 mm; OverallWidth: 800 mm; Classification: 1.9 IfcDoor (uks) (_RKAS BIM + ARCHICAD Classification); 52 Siseuksed (EHITUSKULUDE LIIGITAMINE EVS 885:2005)
Avatäited - 18 Viimistlus: RAL 9003; 01 Nimetus: Siseuks; 02 Materjal: Sile uks; 03 Tähistus: SU-B233A 800×2 100; 04 Avamõõdu geomeetria: 800×2 100; 05 Asukoha info: Interior; 06 Soojusläbivus: -; 07 Helipidavus: 30 dB; 08 Veepidavus: -; 09 Õhuläbilaskvus: -; 10 Tulekindlus: nõudeid ei esitata; 11 Vastupanu tulekoormusele: -; 12 Klaaspakett: -; 13 Klaasingu erisused: -; 14 Päikesekiirgus tegur (g-väärtus): -; 15 Avanemine: Avanemine: "R" (L - vasak; R - parem); 16 Liigendatus: Tuulututav lävepakk; 17 Sulused, lukustus: vt lukustuse spetsifikatsioon; 19 Mudel või toote tunnus: Undefined; 20 Tootja: Undefined; 21 Tooteinfo: Undefined; 22 Kasutus- ja hooldusjuhend: Undefined
Pset_DoorCommon - ThermalTransmittance: 0; GlazingAreaFraction: 0; IsExternal: no
AC_Pset_RenovationAndPhasing - Renovation Status: New

# IfcDoor: SU-B233B 700×2 100, Siseuks * Door 22
In: 2 KORRUS
Type - OperationType: SINGLE_SWING_RIGHT; ParameterTakesPrecedence: no; Sizeable: no
Type - Door Lining Properties - LiningDepth: 115 mm; LiningThickness: 40 mm; LiningOffset: 100 mm; CasingThickness: 50 mm; CasingDepth: 19 mm
Type - Door Panel Properties - Panel 1 - PanelDepth: 40 mm; PanelOperation: SWINGING; PanelWidth: 1; PanelPosition: MIDDLE
OverallHeight: 2100 mm; OverallWidth: 700 mm; Classification: 1.9 IfcDoor (uks) (_RKAS BIM + ARCHICAD Classification); 52 Siseuksed (EHITUSKULUDE LIIGITAMINE EVS 885:2005)
Avatäited - 18 Viimistlus: RAL 9003; 01 Nimetus: Siseuks; 02 Materjal: Sile uks; 03 Tähistus: SU-B233B 700×2 100; 04 Avamõõdu geomeetria: 700×2 100; 05 Asukoha info: Interior; 06 Soojusläbivus: -; 07 Helipidavus: 30 dB; 08 Veepidavus: -; 09 Õhuläbilaskvus: -; 10 Tulekindlus: nõudeid ei esitata; 11 Vastupanu tulekoormusele: -; 12 Klaaspakett: -; 13 Klaasingu erisused: -; 14 Päikesekiirgus tegur (g-väärtus): -; 15 Avanemine: Avanemine: "L" (L - vasak; R - parem); 16 Liigendatus: Tuulututav lävepakk; 17 Sulused, lukustus: vt lukustuse spetsifikatsioon; 19 Mudel või toote tunnus: Undefined; 20 Tootja: Undefined; 21 Tooteinfo: Undefined; 22 Kasutus- ja hooldusjuhend: Undefined
Pset_DoorCommon - ThermalTransmittance: 0; GlazingAreaFraction: 0; IsExternal: no
AC_Pset_RenovationAndPhasing - Renovation Status: New

# IfcDoor: SU-B234 800×2 100, Siseuks * Door 22
In: 2 KORRUS
Type - OperationType: SINGLE_SWING_LEFT; ParameterTakesPrecedence: no; Sizeable: no
Type - Door Lining Properties - LiningDepth: 115 mm; LiningThickness: 40 mm; LiningOffset: 100 mm; CasingThickness: 50 mm; CasingDepth: 19 mm
Type - Door Panel Properties - Panel 1 - PanelDepth: 40 mm; PanelOperation: SWINGING; PanelWidth: 1; PanelPosition: MIDDLE
OverallHeight: 2100 mm; OverallWidth: 800 mm; Classification: 1.9 IfcDoor (uks) (_RKAS BIM + ARCHICAD Classification); 52 Siseuksed (EHITUSKULUDE LIIGITAMINE EVS 885:2005)
Avatäited - 18 Viimistlus: RAL 9003; 01 Nimetus: Siseuks; 02 Materjal: Sile uks; 03 Tähistus: SU-B234 800×2 100; 04 Avamõõdu geomeetria: 800×2 100; 05 Asukoha info: Interior; 06 Soojusläbivus: -; 07 Helipidavus: 30 dB; 08 Veepidavus: niiskuskindel uks; 09 Õhuläbilaskvus: -; 10 Tulekindlus: nõudeid ei esitata; 11 Vastupanu tulekoormusele: -; 12 Klaaspakett: -; 13 Klaasingu erisused: -; 14 Päikesekiirgus tegur (g-väärtus): -; 15 Avanemine: Avanemine: "R" (L - vasak; R - parem); 16 Liigendatus: Lävepakk madal max 25mm, roostevaba; 17 Sulused, lukustus: vt lukustuse spetsifikatsioon; 19 Mudel või toote tunnus: Undefined; 20 Tootja: Undefined; 21 Tooteinfo: Undefined; 22 Kasutus- ja hooldusjuhend: Undefined
Pset_DoorCommon - ThermalTransmittance: 0; GlazingAreaFraction: 0; IsExternal: no
AC_Pset_RenovationAndPhasing - Renovation Status: New

# IfcDoor: SU-B235 780×2 100, Siseuks * Door 22
In: 2 KORRUS
Type - OperationType: SINGLE_SWING_LEFT; ParameterTakesPrecedence: no; Sizeable: no
Type - Door Lining Properties - LiningDepth: 115 mm; LiningThickness: 40 mm; LiningOffset: 420 mm; CasingThickness: 50 mm; CasingDepth: 19 mm
Type - Door Panel Properties - Panel 1 - PanelDepth: 40 mm; PanelOperation: SWINGING; PanelWidth: 1; PanelPosition: MIDDLE
OverallHeight: 2100 mm; OverallWidth: 780 mm; Classification: 1.9 IfcDoor (uks) (_RKAS BIM + ARCHICAD Classification); 52 Siseuksed (EHITUSKULUDE LIIGITAMINE EVS 885:2005)
Avatäited - 18 Viimistlus: RAL 9003; 01 Nimetus: Siseuks; 02 Materjal: Sile uks; 03 Tähistus: SU-B235 780×2 100; 04 Avamõõdu geomeetria: 780×2 100; 05 Asukoha info: Interior; 06 Soojusläbivus: -; 07 Helipidavus: 30 dB; 08 Veepidavus: -; 09 Õhuläbilaskvus: -; 10 Tulekindlus: nõudeid ei esitata; 11 Vastupanu tulekoormusele: -; 12 Klaaspakett: -; 13 Klaasingu erisused: -; 14 Päikesekiirgus tegur (g-väärtus): -; 15 Avanemine: Avanemine: "R" (L - vasak; R - parem); 16 Liigendatus: Lävepakk madal max 25mm, roostevaba; 17 Sulused, lukustus: vt lukustuse spetsifikatsioon; 19 Mudel või toote tunnus: Undefined; 20 Tootja: Undefined; 21 Tooteinfo: Undefined; 22 Kasutus- ja hooldusjuhend: Undefined
Pset_DoorCommon - ThermalTransmittance: 0; GlazingAreaFraction: 0; IsExternal: no
AC_Pset_RenovationAndPhasing - Renovation Status: New

# IfcDoor: SU-B236 780×2 100, Siseuks * Door 22
In: 2 KORRUS
Type - OperationType: SINGLE_SWING_LEFT; ParameterTakesPrecedence: no; Sizeable: no
Type - Door Lining Properties - LiningDepth: 115 mm; LiningThickness: 40 mm; LiningOffset: 420 mm; CasingThickness: 50 mm; CasingDepth: 19 mm
Type - Door Panel Properties - Panel 1 - PanelDepth: 40 mm; PanelOperation: SWINGING; PanelWidth: 1; PanelPosition: MIDDLE
OverallHeight: 2100 mm; OverallWidth: 780 mm; Classification: 1.9 IfcDoor (uks) (_RKAS BIM + ARCHICAD Classification); 52 Siseuksed (EHITUSKULUDE LIIGITAMINE EVS 885:2005)
Avatäited - 18 Viimistlus: RAL 9003; 01 Nimetus: Siseuks; 02 Materjal: Sile uks; 03 Tähistus: SU-B236 780×2 100; 04 Avamõõdu geomeetria: 780×2 100; 05 Asukoha info: Interior; 06 Soojusläbivus: -; 07 Helipidavus: 30 dB; 08 Veepidavus: -; 09 Õhuläbilaskvus: -; 10 Tulekindlus: nõudeid ei esitata; 11 Vastupanu tulekoormusele: -; 12 Klaaspakett: -; 13 Klaasingu erisused: -; 14 Päikesekiirgus tegur (g-väärtus): -; 15 Avanemine: Avanemine: "R" (L - vasak; R - parem); 16 Liigendatus: Lävepakk madal max 25mm, roostevaba; 17 Sulused, lukustus: vt lukustuse spetsifikatsioon; 19 Mudel või toote tunnus: Undefined; 20 Tootja: Undefined; 21 Tooteinfo: Undefined; 22 Kasutus- ja hooldusjuhend: Undefined
Pset_DoorCommon - ThermalTransmittance: 0; GlazingAreaFraction: 0; IsExternal: no
AC_Pset_RenovationAndPhasing - Renovation Status: New

# IfcDoor: SU-B238 780×2 100, Siseuks * Door 22
In: 2 KORRUS
Type - OperationType: SINGLE_SWING_RIGHT; ParameterTakesPrecedence: no; Sizeable: no
Type - Door Lining Properties - LiningDepth: 115 mm; LiningThickness: 40 mm; LiningOffset: 0 mm; CasingThickness: 50 mm; CasingDepth: 19 mm
Type - Door Panel Properties - Panel 1 - PanelDepth: 40 mm; PanelOperation: SWINGING; PanelWidth: 1; PanelPosition: MIDDLE
OverallHeight: 2100 mm; OverallWidth: 780 mm; Classification: 1.9 IfcDoor (uks) (_RKAS BIM + ARCHICAD Classification); 52 Siseuksed (EHITUSKULUDE LIIGITAMINE EVS 885:2005)
Avatäited - 18 Viimistlus: RAL 9003; 01 Nimetus: Siseuks; 02 Materjal: Sile uks; 03 Tähistus: SU-B238 780×2 100; 04 Avamõõdu geomeetria: 780×2 100; 05 Asukoha info: Interior; 06 Soojusläbivus: -; 07 Helipidavus: 30 dB; 08 Veepidavus: -; 09 Õhuläbilaskvus: -; 10 Tulekindlus: nõudeid ei esitata; 11 Vastupanu tulekoormusele: -; 12 Klaaspakett: -; 13 Klaasingu erisused: -; 14 Päikesekiirgus tegur (g-väärtus): -; 15 Avanemine: Avanemine: "L" (L - vasak; R - parem); 16 Liigendatus: Lävepakk madal max 25mm, roostevaba; 17 Sulused, lukustus: vt lukustuse spetsifikatsioon; 19 Mudel või toote tunnus: Undefined; 20 Tootja: Undefined; 21 Tooteinfo: Undefined; 22 Kasutus- ja hooldusjuhend: Undefined
Pset_DoorCommon - ThermalTransmittance: 0; GlazingAreaFraction: 0; IsExternal: no
AC_Pset_RenovationAndPhasing - Renovation Status: New

# IfcDoor: SU-B240 860×2 000, Siseuks * Door 22
In: 2 KORRUS
Type - OperationType: SINGLE_SWING_RIGHT; ParameterTakesPrecedence: no; Sizeable: no
Type - Door Lining Properties - LiningDepth: 115 mm; LiningThickness: 40 mm; LiningOffset: -35 mm; CasingThickness: 50 mm; CasingDepth: 19 mm
Type - Door Panel Properties - Panel 1 - PanelDepth: 40 mm; PanelOperation: SWINGING; PanelWidth: 1; PanelPosition: MIDDLE
OverallHeight: 2000 mm; OverallWidth: 860 mm; Classification: 1.9 IfcDoor (uks) (_RKAS BIM + ARCHICAD Classification); 52 Siseuksed (EHITUSKULUDE LIIGITAMINE EVS 885:2005)
Avatäited - 18 Viimistlus: RAL 9003; 01 Nimetus: Siseuks; 02 Materjal: Sile uks; 03 Tähistus: SU-B240 860×2 000; 04 Avamõõdu geomeetria: 860×2 000; 05 Asukoha info: Interior; 06 Soojusläbivus: -; 07 Helipidavus: 30 dB; 08 Veepidavus: -; 09 Õhuläbilaskvus: -; 10 Tulekindlus: nõudeid ei esitata; 11 Vastupanu tulekoormusele: -; 12 Klaaspakett: -; 13 Klaasingu erisused: -; 14 Päikesekiirgus tegur (g-väärtus): -; 15 Avanemine: Avanemine: "L" (L - vasak; R - parem); 16 Liigendatus: Lävepakk madal max 25mm, roostevaba; 17 Sulused, lukustus: vt lukustuse spetsifikatsioon; 19 Mudel või toote tunnus: Undefined; 20 Tootja: Undefined; 21 Tooteinfo: Undefined; 22 Kasutus- ja hooldusjuhend: Undefined
Pset_DoorCommon - ThermalTransmittance: 0; GlazingAreaFraction: 0; IsExternal: no
AC_Pset_RenovationAndPhasing - Renovation Status: New

# IfcDoor: SU-B241 880×2 000, Siseuks * Door 22
In: 2 KORRUS
Type - OperationType: SINGLE_SWING_RIGHT; ParameterTakesPrecedence: no; Sizeable: no
Type - Door Lining Properties - LiningDepth: 115 mm; LiningThickness: 40 mm; LiningOffset: 0 mm; CasingThickness: 50 mm; CasingDepth: 19 mm
Type - Door Panel Properties - Panel 1 - PanelDepth: 40 mm; PanelOperation: SWINGING; PanelWidth: 1; PanelPosition: MIDDLE
OverallHeight: 2000 mm; OverallWidth: 880 mm; Classification: 1.9 IfcDoor (uks) (_RKAS BIM + ARCHICAD Classification); 52 Siseuksed (EHITUSKULUDE LIIGITAMINE EVS 885:2005)
Avatäited - 18 Viimistlus: RAL 9003; 01 Nimetus: Siseuks; 02 Materjal: Sile uks; 03 Tähistus: SU-B241 880×2 000; 04 Avamõõdu geomeetria: 880×2 000; 05 Asukoha info: Interior; 06 Soojusläbivus: -; 07 Helipidavus: 30 dB; 08 Veepidavus: -; 09 Õhuläbilaskvus: -; 10 Tulekindlus: nõudeid ei esitata; 11 Vastupanu tulekoormusele: -; 12 Klaaspakett: -; 13 Klaasingu erisused: -; 14 Päikesekiirgus tegur (g-väärtus): -; 15 Avanemine: Avanemine: "L" (L - vasak; R - parem); 16 Liigendatus: Lävepakk madal max 25mm, roostevaba; 17 Sulused, lukustus: vt lukustuse spetsifikatsioon; 19 Mudel või toote tunnus: Undefined; 20 Tootja: Undefined; 21 Tooteinfo: Undefined; 22 Kasutus- ja hooldusjuhend: Undefined
Pset_DoorCommon - ThermalTransmittance: 0; GlazingAreaFraction: 0; IsExternal: no
AC_Pset_RenovationAndPhasing - Renovation Status: New

# IfcDoor: SU-B243 800×2 100, Siseuks * Door 22
In: 2 KORRUS
Type - OperationType: SINGLE_SWING_RIGHT; ParameterTakesPrecedence: no; Sizeable: no
Type - Door Lining Properties - LiningDepth: 115 mm; LiningThickness: 40 mm; LiningOffset: 150 mm; CasingThickness: 50 mm; CasingDepth: 19 mm
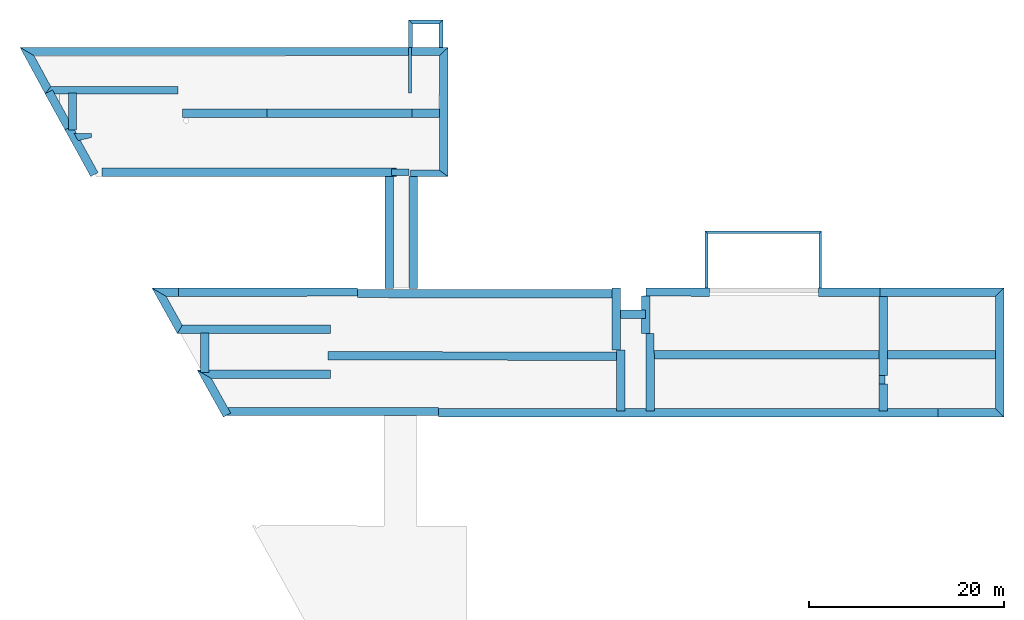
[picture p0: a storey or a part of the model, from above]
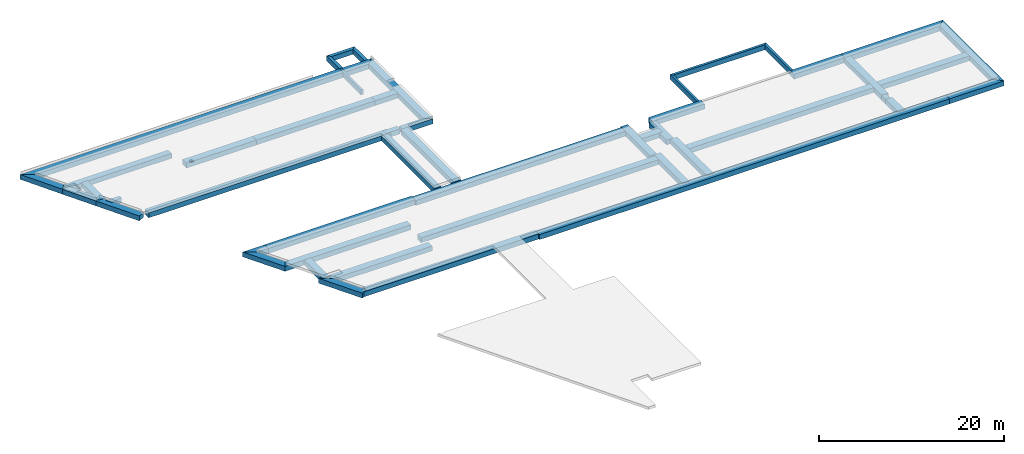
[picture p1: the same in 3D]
Properties of the parts of a building model (IFC2X3), part 9 of 14

# IfcDoor: SU-B243 800×2 100, Siseuks * Door 22
Type - Door Panel Properties - Panel 1 - PanelDepth: 40 mm; PanelOperation: SWINGING; PanelWidth: 1; PanelPosition: MIDDLE
OverallHeight: 2100 mm; OverallWidth: 800 mm; Classification: 1.9 IfcDoor (uks) (_RKAS BIM + ARCHICAD Classification); 52 Siseuksed (EHITUSKULUDE LIIGITAMINE EVS 885:2005)
Avatäited - 18 Viimistlus: RAL 9003; 01 Nimetus: Siseuks; 02 Materjal: Sile uks; 03 Tähistus: SU-B243 800×2 100; 04 Avamõõdu geomeetria: 800×2 100; 05 Asukoha info: Interior; 06 Soojusläbivus: -; 07 Helipidavus: 30 dB; 08 Veepidavus: -; 09 Õhuläbilaskvus: -; 10 Tulekindlus: nõudeid ei esitata; 11 Vastupanu tulekoormusele: -; 12 Klaaspakett: -; 13 Klaasingu erisused: -; 14 Päikesekiirgus tegur (g-väärtus): -; 15 Avanemine: Avanemine: "L" (L - vasak; R - parem); 16 Liigendatus: Lävepakk madal max 25mm, roostevaba; 17 Sulused, lukustus: vt lukustuse spetsifikatsioon; 19 Mudel või toote tunnus: Undefined; 20 Tootja: Undefined; 21 Tooteinfo: Undefined; 22 Kasutus- ja hooldusjuhend: Undefined
Pset_DoorCommon - ThermalTransmittance: 0; GlazingAreaFraction: 0; IsExternal: no
AC_Pset_RenovationAndPhasing - Renovation Status: New

# IfcDoor: SU-B244 800×2 100, Siseuks * Door 22
In: 2 KORRUS
Type - OperationType: SINGLE_SWING_LEFT; ParameterTakesPrecedence: no; Sizeable: no
Type - Door Lining Properties - LiningDepth: 115 mm; LiningThickness: 40 mm; LiningOffset: 0 mm; CasingThickness: 50 mm; CasingDepth: 19 mm
Type - Door Panel Properties - Panel 1 - PanelDepth: 40 mm; PanelOperation: SWINGING; PanelWidth: 1; PanelPosition: MIDDLE
OverallHeight: 2100 mm; OverallWidth: 800 mm; Classification: 1.9 IfcDoor (uks) (_RKAS BIM + ARCHICAD Classification); 52 Siseuksed (EHITUSKULUDE LIIGITAMINE EVS 885:2005)
Avatäited - 18 Viimistlus: RAL 9003; 01 Nimetus: Siseuks; 02 Materjal: Sile uks; 03 Tähistus: SU-B244 800×2 100; 04 Avamõõdu geomeetria: 800×2 100; 05 Asukoha info: Interior; 06 Soojusläbivus: -; 07 Helipidavus: 30 dB; 08 Veepidavus: -; 09 Õhuläbilaskvus: -; 10 Tulekindlus: nõudeid ei esitata; 11 Vastupanu tulekoormusele: -; 12 Klaaspakett: -; 13 Klaasingu erisused: -; 14 Päikesekiirgus tegur (g-väärtus): -; 15 Avanemine: Avanemine: "R" (L - vasak; R - parem); 16 Liigendatus: Lävepakk madal max 25mm, roostevaba; 17 Sulused, lukustus: vt lukustuse spetsifikatsioon; 19 Mudel või toote tunnus: Undefined; 20 Tootja: Undefined; 21 Tooteinfo: Undefined; 22 Kasutus- ja hooldusjuhend: Undefined
Pset_DoorCommon - ThermalTransmittance: 0; GlazingAreaFraction: 0; IsExternal: no
AC_Pset_RenovationAndPhasing - Renovation Status: New

# IfcDoor: SU-B245 1 600×2 000, Siseuks * Double Door 22
In: 2 KORRUS
Type - OperationType: DOUBLE_DOOR_SINGLE_SWING; ParameterTakesPrecedence: no; Sizeable: no
Type - Door Lining Properties - LiningDepth: 115 mm; LiningThickness: 40 mm; LiningOffset: 0 mm; CasingThickness: 50 mm; CasingDepth: 19 mm
Type - Door Panel Properties - Panel 1 - PanelDepth: 40 mm; PanelOperation: SWINGING; PanelWidth: 0.507895; PanelPosition: RIGHT
Type - Door Panel Properties - Panel 2 - PanelDepth: 40 mm; PanelOperation: SWINGING; PanelWidth: 0.507895; PanelPosition: LEFT
Description: Teras; OverallHeight: 2000 mm; OverallWidth: 1600 mm; Classification: 1.9 IfcDoor (uks) (_RKAS BIM + ARCHICAD Classification); 52 Siseuksed (EHITUSKULUDE LIIGITAMINE EVS 885:2005)
Pset_DoorCommon - FireRating: EI30; ThermalTransmittance: 0; GlazingAreaFraction: 0; IsExternal: no
Avatäited - 18 Viimistlus: RAL 9003; 01 Nimetus: Siseuks; 02 Materjal: Sile uks; 03 Tähistus: SU-B245 1 600×2 000; 04 Avamõõdu geomeetria: 1 600×2 000; 05 Asukoha info: Interior; 06 Soojusläbivus: -; 07 Helipidavus: 30 dB; 08 Veepidavus: -; 09 Õhuläbilaskvus: -; 10 Tulekindlus: EI 30; 11 Vastupanu tulekoormusele: -; 12 Klaaspakett: -; 13 Klaasingu erisused: -; 14 Päikesekiirgus tegur (g-väärtus): -; 15 Avanemine: Avanemine: "R" (L - vasak; R - parem); 16 Liigendatus: Lävepakk madal max 25mm, roostevaba; 17 Sulused, lukustus: vt lukustuse spetsifikatsioon; 19 Mudel või toote tunnus: Undefined; 20 Tootja: Undefined; 21 Tooteinfo: Undefined; 22 Kasutus- ja hooldusjuhend: Undefined
AC_Pset_RenovationAndPhasing - Renovation Status: New

# IfcDoor: SU-B246 900×2 100, Siseuks * Door 22
In: 2 KORRUS
Type - OperationType: SINGLE_SWING_LEFT; ParameterTakesPrecedence: no; Sizeable: no
Type - Door Lining Properties - LiningDepth: 115 mm; LiningThickness: 40 mm; LiningOffset: 0 mm; CasingThickness: 50 mm; CasingDepth: 19 mm
Type - Door Panel Properties - Panel 1 - PanelDepth: 40 mm; PanelOperation: SWINGING; PanelWidth: 1; PanelPosition: MIDDLE
OverallHeight: 2100 mm; OverallWidth: 900 mm; Classification: 1.9 IfcDoor (uks) (_RKAS BIM + ARCHICAD Classification); 52 Siseuksed (EHITUSKULUDE LIIGITAMINE EVS 885:2005)
Avatäited - 18 Viimistlus: RAL 9003; 01 Nimetus: Siseuks; 02 Materjal: Sile uks; 03 Tähistus: SU-B246 900×2 100; 04 Avamõõdu geomeetria: 900×2 100; 05 Asukoha info: Interior; 06 Soojusläbivus: -; 07 Helipidavus: 30 dB; 08 Veepidavus: -; 09 Õhuläbilaskvus: -; 10 Tulekindlus: nõudeid ei esitata; 11 Vastupanu tulekoormusele: -; 12 Klaaspakett: -; 13 Klaasingu erisused: -; 14 Päikesekiirgus tegur (g-väärtus): -; 15 Avanemine: Avanemine: "R" (L - vasak; R - parem); 16 Liigendatus: Lävepakk madal max 25mm, roostevaba; 17 Sulused, lukustus: vt lukustuse spetsifikatsioon; 19 Mudel või toote tunnus: Undefined; 20 Tootja: Undefined; 21 Tooteinfo: Undefined; 22 Kasutus- ja hooldusjuhend: Undefined
Pset_DoorCommon - ThermalTransmittance: 0; GlazingAreaFraction: 0; IsExternal: no
AC_Pset_RenovationAndPhasing - Renovation Status: New

# IfcDoor: SU-C200 1 700×2 300, Siseuks * Double Door 22
In: 2 KORRUS
Type - OperationType: DOUBLE_DOOR_SINGLE_SWING; ParameterTakesPrecedence: no; Sizeable: no
Type - Door Lining Properties - LiningDepth: 115 mm; LiningThickness: 40 mm; LiningOffset: -200 mm; CasingThickness: 50 mm; CasingDepth: 19 mm
Type - Door Panel Properties - Panel 1 - PanelDepth: 40 mm; PanelOperation: SWINGING; PanelWidth: 0.507407; PanelPosition: LEFT
Type - Door Panel Properties - Panel 2 - PanelDepth: 40 mm; PanelOperation: SWINGING; PanelWidth: 0.507407; PanelPosition: RIGHT
OverallHeight: 2300 mm; OverallWidth: 1700 mm; Classification: 1.9 IfcDoor (uks) (_RKAS BIM + ARCHICAD Classification); 52 Siseuksed (EHITUSKULUDE LIIGITAMINE EVS 885:2005)
Avatäited - 18 Viimistlus: RAL 9003; 01 Nimetus: Siseuks; 02 Materjal: Alumiiniumprofiil pulbervärvitud; 03 Tähistus: SU-C200 1 700×2 300; 04 Avamõõdu geomeetria: 1 700×2 300; 05 Asukoha info: Interior; 06 Soojusläbivus: -; 07 Helipidavus: 30 dB; 08 Veepidavus: -; 09 Õhuläbilaskvus: -; 10 Tulekindlus: nõudeid ei esitata; 11 Vastupanu tulekoormusele: -; 12 Klaaspakett: Karastatud ja lamineeritud kirgas klaas; 13 Klaasingu erisused: -; 14 Päikesekiirgus tegur (g-väärtus): -; 15 Avanemine: Avanemine: "L" (L - vasak; R - parem); 16 Liigendatus: Tuulutatav lävepakk; 17 Sulused, lukustus: vt lukustuse spetsifikatsioon; 19 Mudel või toote tunnus: Undefined; 20 Tootja: Undefined; 21 Tooteinfo: Undefined; 22 Kasutus- ja hooldusjuhend: Undefined
Pset_DoorCommon - ThermalTransmittance: 0; GlazingAreaFraction: 2.07997; IsExternal: no
AC_Pset_RenovationAndPhasing - Renovation Status: New

# IfcDoor: SU-C201 1 000×2 300, Siseuks * Door 22
In: 2 KORRUS
Type - OperationType: SINGLE_SWING_LEFT; ParameterTakesPrecedence: no; Sizeable: no
Type - Door Lining Properties - LiningDepth: 115 mm; LiningThickness: 40 mm; LiningOffset: 0 mm; CasingThickness: 50 mm; CasingDepth: 19 mm
Type - Door Panel Properties - Panel 1 - PanelDepth: 40 mm; PanelOperation: SWINGING; PanelWidth: 1; PanelPosition: MIDDLE
OverallHeight: 2300 mm; OverallWidth: 1000 mm; Classification: 1.9 IfcDoor (uks) (_RKAS BIM + ARCHICAD Classification); 52 Siseuksed (EHITUSKULUDE LIIGITAMINE EVS 885:2005)
Avatäited - 18 Viimistlus: RAL 9003; 01 Nimetus: Siseuks; 02 Materjal: Sile uks; 03 Tähistus: SU-C201 1 000×2 300; 04 Avamõõdu geomeetria: 1 000×2 300; 05 Asukoha info: Interior; 06 Soojusläbivus: -; 07 Helipidavus: 30 dB; 08 Veepidavus: -; 09 Õhuläbilaskvus: -; 10 Tulekindlus: nõudeid ei esitata; 11 Vastupanu tulekoormusele: -; 12 Klaaspakett: -; 13 Klaasingu erisused: -; 14 Päikesekiirgus tegur (g-väärtus): -; 15 Avanemine: Avanemine: "R" (L - vasak; R - parem); 16 Liigendatus: Lävepakk madal max 25mm, roostevaba; 17 Sulused, lukustus: vt lukustuse spetsifikatsioon; 19 Mudel või toote tunnus: Undefined; 20 Tootja: Undefined; 21 Tooteinfo: Undefined; 22 Kasutus- ja hooldusjuhend: Undefined
Pset_DoorCommon - ThermalTransmittance: 0; GlazingAreaFraction: 0; IsExternal: no
AC_Pset_RenovationAndPhasing - Renovation Status: New

# IfcDoor: SU-C202 1 000×2 300, Siseuks * Door 22
In: 2 KORRUS
Type - OperationType: SINGLE_SWING_LEFT; ParameterTakesPrecedence: no; Sizeable: no
Type - Door Lining Properties - LiningDepth: 115 mm; LiningThickness: 40 mm; LiningOffset: 0 mm; CasingThickness: 50 mm; CasingDepth: 19 mm
Type - Door Panel Properties - Panel 1 - PanelDepth: 40 mm; PanelOperation: SWINGING; PanelWidth: 1; PanelPosition: MIDDLE
OverallHeight: 2300 mm; OverallWidth: 1000 mm; Classification: 1.9 IfcDoor (uks) (_RKAS BIM + ARCHICAD Classification); 52 Siseuksed (EHITUSKULUDE LIIGITAMINE EVS 885:2005)
Avatäited - 18 Viimistlus: RAL 9003; 01 Nimetus: Siseuks; 02 Materjal: Sile uks; 03 Tähistus: SU-C202 1 000×2 300; 04 Avamõõdu geomeetria: 1 000×2 300; 05 Asukoha info: Interior; 06 Soojusläbivus: -; 07 Helipidavus: 30 dB; 08 Veepidavus: -; 09 Õhuläbilaskvus: -; 10 Tulekindlus: nõudeid ei esitata; 11 Vastupanu tulekoormusele: -; 12 Klaaspakett: -; 13 Klaasingu erisused: -; 14 Päikesekiirgus tegur (g-väärtus): -; 15 Avanemine: Avanemine: "R" (L - vasak; R - parem); 16 Liigendatus: Lävepakk madal max 25mm, roostevaba; 17 Sulused, lukustus: vt lukustuse spetsifikatsioon; 19 Mudel või toote tunnus: Undefined; 20 Tootja: Undefined; 21 Tooteinfo: Undefined; 22 Kasutus- ja hooldusjuhend: Undefined
Pset_DoorCommon - ThermalTransmittance: 0; GlazingAreaFraction: 0; IsExternal: no
AC_Pset_RenovationAndPhasing - Renovation Status: New

# IfcDoor: SU-C203 1 000×2 300, Siseuks * Door 22
In: 2 KORRUS
Type - OperationType: SINGLE_SWING_LEFT; ParameterTakesPrecedence: no; Sizeable: no
Type - Door Lining Properties - LiningDepth: 115 mm; LiningThickness: 40 mm; LiningOffset: 0 mm; CasingThickness: 50 mm; CasingDepth: 19 mm
Type - Door Panel Properties - Panel 1 - PanelDepth: 40 mm; PanelOperation: SWINGING; PanelWidth: 1; PanelPosition: MIDDLE
OverallHeight: 2300 mm; OverallWidth: 1000 mm; Classification: 1.9 IfcDoor (uks) (_RKAS BIM + ARCHICAD Classification); 52 Siseuksed (EHITUSKULUDE LIIGITAMINE EVS 885:2005)
Avatäited - 18 Viimistlus: RAL 9003; 01 Nimetus: Siseuks; 02 Materjal: Sile uks; 03 Tähistus: SU-C203 1 000×2 300; 04 Avamõõdu geomeetria: 1 000×2 300; 05 Asukoha info: Interior; 06 Soojusläbivus: -; 07 Helipidavus: 30 dB; 08 Veepidavus: -; 09 Õhuläbilaskvus: -; 10 Tulekindlus: nõudeid ei esitata; 11 Vastupanu tulekoormusele: -; 12 Klaaspakett: -; 13 Klaasingu erisused: -; 14 Päikesekiirgus tegur (g-väärtus): -; 15 Avanemine: Avanemine: "R" (L - vasak; R - parem); 16 Liigendatus: Lävepakk madal max 25mm, roostevaba; 17 Sulused, lukustus: vt lukustuse spetsifikatsioon; 19 Mudel või toote tunnus: Undefined; 20 Tootja: Undefined; 21 Tooteinfo: Undefined; 22 Kasutus- ja hooldusjuhend: Undefined
Pset_DoorCommon - ThermalTransmittance: 0; GlazingAreaFraction: 0; IsExternal: no
AC_Pset_RenovationAndPhasing - Renovation Status: New

# IfcDoor: SU-C204 1 000×2 300, Siseuks * Door 22
In: 2 KORRUS
Type - OperationType: SINGLE_SWING_LEFT; ParameterTakesPrecedence: no; Sizeable: no
Type - Door Lining Properties - LiningDepth: 115 mm; LiningThickness: 40 mm; LiningOffset: 0 mm; CasingThickness: 50 mm; CasingDepth: 19 mm
Type - Door Panel Properties - Panel 1 - PanelDepth: 40 mm; PanelOperation: SWINGING; PanelWidth: 1; PanelPosition: MIDDLE
OverallHeight: 2300 mm; OverallWidth: 1000 mm; Classification: 1.9 IfcDoor (uks) (_RKAS BIM + ARCHICAD Classification); 52 Siseuksed (EHITUSKULUDE LIIGITAMINE EVS 885:2005)
Avatäited - 18 Viimistlus: RAL 9003; 01 Nimetus: Siseuks; 02 Materjal: Sile uks; 03 Tähistus: SU-C204 1 000×2 300; 04 Avamõõdu geomeetria: 1 000×2 300; 05 Asukoha info: Interior; 06 Soojusläbivus: -; 07 Helipidavus: 30 dB; 08 Veepidavus: -; 09 Õhuläbilaskvus: -; 10 Tulekindlus: nõudeid ei esitata; 11 Vastupanu tulekoormusele: -; 12 Klaaspakett: -; 13 Klaasingu erisused: -; 14 Päikesekiirgus tegur (g-väärtus): -; 15 Avanemine: Avanemine: "R" (L - vasak; R - parem); 16 Liigendatus: Lävepakk madal max 25mm, roostevaba; 17 Sulused, lukustus: vt lukustuse spetsifikatsioon; 19 Mudel või toote tunnus: Undefined; 20 Tootja: Undefined; 21 Tooteinfo: Undefined; 22 Kasutus- ja hooldusjuhend: Undefined
Pset_DoorCommon - ThermalTransmittance: 0; GlazingAreaFraction: 0; IsExternal: no
AC_Pset_RenovationAndPhasing - Renovation Status: New

# IfcDoor: SU-C205 1 000×2 100, Siseuks * Door 22
In: 2 KORRUS
Type - OperationType: SINGLE_SWING_LEFT; ParameterTakesPrecedence: no; Sizeable: no
Type - Door Lining Properties - LiningDepth: 115 mm; LiningThickness: 40 mm; LiningOffset: 150 mm; CasingThickness: 50 mm; CasingDepth: 19 mm
Type - Door Panel Properties - Panel 1 - PanelDepth: 40 mm; PanelOperation: SWINGING; PanelWidth: 1; PanelPosition: MIDDLE
OverallHeight: 2100 mm; OverallWidth: 1000 mm; Classification: 1.9 IfcDoor (uks) (_RKAS BIM + ARCHICAD Classification); 52 Siseuksed (EHITUSKULUDE LIIGITAMINE EVS 885:2005)
Avatäited - 18 Viimistlus: RAL 9003; 01 Nimetus: Siseuks; 02 Materjal: Sile uks; 03 Tähistus: SU-C205 1 000×2 100; 04 Avamõõdu geomeetria: 1 000×2 100; 05 Asukoha info: Interior; 06 Soojusläbivus: -; 07 Helipidavus: 30 dB; 08 Veepidavus: -; 09 Õhuläbilaskvus: -; 10 Tulekindlus: nõudeid ei esitata; 11 Vastupanu tulekoormusele: -; 12 Klaaspakett: -; 13 Klaasingu erisused: -; 14 Päikesekiirgus tegur (g-väärtus): -; 15 Avanemine: Avanemine: "R" (L - vasak; R - parem); 16 Liigendatus: Lävepakk madal max 25mm, roostevaba; 17 Sulused, lukustus: vt lukustuse spetsifikatsioon; 19 Mudel või toote tunnus: Undefined; 20 Tootja: Undefined; 21 Tooteinfo: Undefined; 22 Kasutus- ja hooldusjuhend: Undefined
Pset_DoorCommon - ThermalTransmittance: 0; GlazingAreaFraction: 0; IsExternal: no
AC_Pset_RenovationAndPhasing - Renovation Status: New

# IfcDoor: SU-C206 1 400×2 300, Saali uks * Double Door 22
In: 2 KORRUS
Type - OperationType: DOUBLE_DOOR_SINGLE_SWING; ParameterTakesPrecedence: no; Sizeable: no
Type - Door Lining Properties - LiningDepth: 115 mm; LiningThickness: 40 mm; LiningOffset: 0 mm; CasingThickness: 50 mm; CasingDepth: 19 mm
Type - Door Panel Properties - Panel 1 - PanelDepth: 40 mm; PanelOperation: SWINGING; PanelWidth: 0.563636; PanelPosition: LEFT
Type - Door Panel Properties - Panel 2 - PanelDepth: 40 mm; PanelOperation: SWINGING; PanelWidth: 0.454545; PanelPosition: RIGHT
OverallHeight: 2300 mm; OverallWidth: 1400 mm; Classification: 1.9 IfcDoor (uks) (_RKAS BIM + ARCHICAD Classification); 52 Siseuksed (EHITUSKULUDE LIIGITAMINE EVS 885:2005)
Avatäited - 18 Viimistlus: RAL 9003; 01 Nimetus: Saali uks; 02 Materjal: Sile uks; 03 Tähistus: SU-C206 1 400×2 300; 04 Avamõõdu geomeetria: 1 400×2 300; 05 Asukoha info: Interior; 06 Soojusläbivus: -; 07 Helipidavus: -; 08 Veepidavus: -; 09 Õhuläbilaskvus: -; 10 Tulekindlus: nõudeid ei esitata; 11 Vastupanu tulekoormusele: -; 12 Klaaspakett: -; 13 Klaasingu erisused: -; 14 Päikesekiirgus tegur (g-väärtus): -; 15 Avanemine: Avanemine: "L" (L - vasak; R - parem); 16 Liigendatus: Lävepakk madal max 25mm, roostevaba; 17 Sulused, lukustus: vt lukustuse spetsifikatsioon; 19 Mudel või toote tunnus: Undefined; 20 Tootja: Undefined; 21 Tooteinfo: Undefined; 22 Kasutus- ja hooldusjuhend: Undefined
Pset_DoorCommon - ThermalTransmittance: 0; GlazingAreaFraction: 0; IsExternal: no
AC_Pset_RenovationAndPhasing - Renovation Status: Existing

# IfcDoor: SU-C208 1 000×2 000, Siseuks * Door 22
In: 2 KORRUS
Type - OperationType: SINGLE_SWING_LEFT; ParameterTakesPrecedence: no; Sizeable: no
Type - Door Lining Properties - LiningDepth: 115 mm; LiningThickness: 40 mm; LiningOffset: 300 mm; CasingThickness: 50 mm; CasingDepth: 19 mm
Type - Door Panel Properties - Panel 1 - PanelDepth: 40 mm; PanelOperation: SWINGING; PanelWidth: 1; PanelPosition: MIDDLE
Description: Puit; OverallHeight: 2000 mm; OverallWidth: 1000 mm; Classification: 1.9 IfcDoor (uks) (_RKAS BIM + ARCHICAD Classification); 52 Siseuksed (EHITUSKULUDE LIIGITAMINE EVS 885:2005)
Avatäited - 18 Viimistlus: RAL 9003; 01 Nimetus: Siseuks; 02 Materjal: Sile uks; 03 Tähistus: SU-C208 1 000×2 000; 04 Avamõõdu geomeetria: 1 000×2 000; 05 Asukoha info: Interior; 06 Soojusläbivus: -; 07 Helipidavus: 30 dB; 08 Veepidavus: -; 09 Õhuläbilaskvus: -; 10 Tulekindlus: nõudeid ei esitata; 11 Vastupanu tulekoormusele: -; 12 Klaaspakett: -; 13 Klaasingu erisused: -; 14 Päikesekiirgus tegur (g-väärtus): -; 15 Avanemine: Avanemine: "R" (L - vasak; R - parem); 16 Liigendatus: Tuulututab lävepakk; 17 Sulused, lukustus: vt lukustuse spetsifikatsioon; 19 Mudel või toote tunnus: Undefined; 20 Tootja: Undefined; 21 Tooteinfo: Undefined; 22 Kasutus- ja hooldusjuhend: Undefined
Pset_DoorCommon - ThermalTransmittance: 0; GlazingAreaFraction: 0; IsExternal: no
AC_Pset_RenovationAndPhasing - Renovation Status: New

# IfcDoor: SU-C209 800×2 000, Siseuks * Door 22
In: 2 KORRUS
Type - OperationType: SINGLE_SWING_LEFT; ParameterTakesPrecedence: no; Sizeable: no
Type - Door Lining Properties - LiningDepth: 115 mm; LiningThickness: 40 mm; LiningOffset: 300 mm; CasingThickness: 50 mm; CasingDepth: 19 mm
Type - Door Panel Properties - Panel 1 - PanelDepth: 40 mm; PanelOperation: SWINGING; PanelWidth: 1; PanelPosition: MIDDLE
OverallHeight: 2000 mm; OverallWidth: 800 mm; Classification: 1.9 IfcDoor (uks) (_RKAS BIM + ARCHICAD Classification); 52 Siseuksed (EHITUSKULUDE LIIGITAMINE EVS 885:2005)
Avatäited - 18 Viimistlus: RAL 9003; 01 Nimetus: Siseuks; 02 Materjal: Sile uks; 03 Tähistus: SU-C209 800×2 000; 04 Avamõõdu geomeetria: 800×2 000; 05 Asukoha info: Interior; 06 Soojusläbivus: -; 07 Helipidavus: 30 dB; 08 Veepidavus: -; 09 Õhuläbilaskvus: -; 10 Tulekindlus: nõudeid ei esitata; 11 Vastupanu tulekoormusele: -; 12 Klaaspakett: -; 13 Klaasingu erisused: -; 14 Päikesekiirgus tegur (g-väärtus): -; 15 Avanemine: Avanemine: "R" (L - vasak; R - parem); 16 Liigendatus: Tuulututab lävepakk; 17 Sulused, lukustus: vt lukustuse spetsifikatsioon; 19 Mudel või toote tunnus: Undefined; 20 Tootja: Undefined; 21 Tooteinfo: Undefined; 22 Kasutus- ja hooldusjuhend: Undefined
Pset_DoorCommon - ThermalTransmittance: 0; GlazingAreaFraction: 0; IsExternal: no
AC_Pset_RenovationAndPhasing - Renovation Status: New

# IfcDoor: SU-C209A 700×2 000, Siseuks * Door 22
In: 2 KORRUS
Type - OperationType: SINGLE_SWING_LEFT; ParameterTakesPrecedence: no; Sizeable: no
Type - Door Lining Properties - LiningDepth: 115 mm; LiningThickness: 40 mm; LiningOffset: 0 mm; CasingThickness: 50 mm; CasingDepth: 19 mm
Type - Door Panel Properties - Panel 1 - PanelDepth: 40 mm; PanelOperation: SWINGING; PanelWidth: 1; PanelPosition: MIDDLE
OverallHeight: 2000 mm; OverallWidth: 700 mm; Classification: 1.9 IfcDoor (uks) (_RKAS BIM + ARCHICAD Classification); 52 Siseuksed (EHITUSKULUDE LIIGITAMINE EVS 885:2005)
Avatäited - 18 Viimistlus: RAL 9003; 01 Nimetus: Siseuks; 02 Materjal: Sile uks; 03 Tähistus: SU-C209A 700×2 000; 04 Avamõõdu geomeetria: 700×2 000; 05 Asukoha info: Interior; 06 Soojusläbivus: -; 07 Helipidavus: 30 dB; 08 Veepidavus: -; 09 Õhuläbilaskvus: -; 10 Tulekindlus: nõudeid ei esitata; 11 Vastupanu tulekoormusele: -; 12 Klaaspakett: -; 13 Klaasingu erisused: -; 14 Päikesekiirgus tegur (g-väärtus): -; 15 Avanemine: Avanemine: "R" (L - vasak; R - parem); 16 Liigendatus: Tuulututab lävepakk; 17 Sulused, lukustus: vt lukustuse spetsifikatsioon; 19 Mudel või toote tunnus: Undefined; 20 Tootja: Undefined; 21 Tooteinfo: Undefined; 22 Kasutus- ja hooldusjuhend: Undefined
Pset_DoorCommon - ThermalTransmittance: 0; GlazingAreaFraction: 0; IsExternal: no
AC_Pset_RenovationAndPhasing - Renovation Status: New

# IfcDoor: SU-C210 1 000×2 300, Siseuks * Door 22
In: 2 KORRUS
Type - OperationType: SINGLE_SWING_LEFT; ParameterTakesPrecedence: no; Sizeable: no
Type - Door Lining Properties - LiningDepth: 115 mm; LiningThickness: 40 mm; LiningOffset: 0 mm; CasingThickness: 50 mm; CasingDepth: 19 mm
Type - Door Panel Properties - Panel 1 - PanelDepth: 40 mm; PanelOperation: SWINGING; PanelWidth: 1; PanelPosition: MIDDLE
OverallHeight: 2300 mm; OverallWidth: 1000 mm; Classification: 1.9 IfcDoor (uks) (_RKAS BIM + ARCHICAD Classification); 52 Siseuksed (EHITUSKULUDE LIIGITAMINE EVS 885:2005)
Pset_FireRatingProperties - FireResistanceRating: EI30
Avatäited - 18 Viimistlus: RAL 9003; 01 Nimetus: Siseuks; 02 Materjal: Sile uks; 03 Tähistus: SU-C210 1 000×2 300; 04 Avamõõdu geomeetria: 1 000×2 300; 05 Asukoha info: Interior; 06 Soojusläbivus: -; 07 Helipidavus: 30 dB; 08 Veepidavus: -; 09 Õhuläbilaskvus: -; 10 Tulekindlus: EI 30; 11 Vastupanu tulekoormusele: -; 12 Klaaspakett: -; 13 Klaasingu erisused: -; 14 Päikesekiirgus tegur (g-väärtus): -; 15 Avanemine: Avanemine: "R" (L - vasak; R - parem); 16 Liigendatus: Lävepakk madal max 25mm, roostevaba; 17 Sulused, lukustus: vt lukustuse spetsifikatsioon; 19 Mudel või toote tunnus: Undefined; 20 Tootja: Undefined; 21 Tooteinfo: Undefined; 22 Kasutus- ja hooldusjuhend: Undefined
Pset_DoorCommon - ThermalTransmittance: 0; GlazingAreaFraction: 0; IsExternal: no
AC_Pset_RenovationAndPhasing - Renovation Status: New

# IfcDoor: VENT UKS 1 700×1 800, Teenindus luuk * Door 22
In: 1 KORRUS
Type - OperationType: SINGLE_SWING_RIGHT; ParameterTakesPrecedence: no; Sizeable: no
Type - Door Lining Properties - LiningDepth: 115 mm; LiningThickness: 40 mm; LiningOffset: 0 mm; CasingThickness: 50 mm; CasingDepth: 19 mm
Type - Door Panel Properties - Panel 1 - PanelDepth: 40 mm; PanelOperation: SWINGING; PanelWidth: 1; PanelPosition: MIDDLE
OverallHeight: 1800 mm; OverallWidth: 700 mm; Classification: 1.9 IfcDoor (uks) (_RKAS BIM + ARCHICAD Classification); 52 Siseuksed (EHITUSKULUDE LIIGITAMINE EVS 885:2005)
Pset_DoorCommon - ThermalTransmittance: 0; GlazingAreaFraction: 0; IsExternal: no
Avatäited - 01 Nimetus: Teenindus luuk; 02 Materjal: Alumiiniumprofiil pulbervärvitud; 03 Tähistus: VENT UKS 1 700×1 800; 04 Avamõõdu geomeetria: 700×1 800; 05 Asukoha info: Interior; 06 Soojusläbivus: -; 07 Helipidavus: 30 dB; 08 Veepidavus: -; 09 Õhuläbilaskvus: -; 10 Tulekindlus: nõudeid ei esitata; 11 Vastupanu tulekoormusele: -; 12 Klaaspakett: -; 13 Klaasingu erisused: -; 14 Päikesekiirgus tegur (g-väärtus): -; 15 Avanemine: Avanemine: "L" (L - vasak; R - parem); 16 Liigendatus: Lävepakk madal max 25mm, roostevaba; 17 Sulused, lukustus: vt lukustuse spetsifikatsioon; 18 Viimistlus: Leng väljast: Paint - Glossy White; Leng seest: Paint - Glossy White; Ukseleht väljast: Paint - Glossy White; Ukseleht seest: Paint - Glossy White; Täpsustus: RAL 9003; 19 Mudel või toote tunnus: Undefined; 20 Tootja: Undefined; 21 Tooteinfo: Undefined; 22 Kasutus- ja hooldusjuhend: Undefined
AC_Pset_RenovationAndPhasing - Renovation Status: New

# IfcDoor: VENT UKS 2 700×1 800, Teenindus luuk * Door 22
In: KATUSEPLAAN
Type - OperationType: SINGLE_SWING_LEFT; ParameterTakesPrecedence: no; Sizeable: no
Type - Door Lining Properties - LiningDepth: 115 mm; LiningThickness: 40 mm; LiningOffset: 0 mm; CasingThickness: 50 mm; CasingDepth: 19 mm
Type - Door Panel Properties - Panel 1 - PanelDepth: 40 mm; PanelOperation: SWINGING; PanelWidth: 1; PanelPosition: MIDDLE
OverallHeight: 1800 mm; OverallWidth: 700 mm; Classification: 1.9 IfcDoor (uks) (_RKAS BIM + ARCHICAD Classification); 52 Siseuksed (EHITUSKULUDE LIIGITAMINE EVS 885:2005)
Pset_DoorCommon - ThermalTransmittance: 0; GlazingAreaFraction: 0; IsExternal: no
Avatäited - 01 Nimetus: Teenindus luuk; 02 Materjal: Alumiiniumprofiil pulbervärvitud; 03 Tähistus: VENT UKS 2 700×1 800; 04 Avamõõdu geomeetria: 700×1 800; 05 Asukoha info: Interior; 06 Soojusläbivus: -; 07 Helipidavus: 30 dB; 08 Veepidavus: -; 09 Õhuläbilaskvus: -; 10 Tulekindlus: nõudeid ei esitata; 11 Vastupanu tulekoormusele: -; 12 Klaaspakett: -; 13 Klaasingu erisused: -; 14 Päikesekiirgus tegur (g-väärtus): -; 15 Avanemine: Avanemine: "R" (L - vasak; R - parem); 16 Liigendatus: Lävepakk madal max 25mm, roostevaba; 17 Sulused, lukustus: vt lukustuse spetsifikatsioon; 18 Viimistlus: Leng väljast: Paint - Glossy White; Leng seest: Paint - Glossy White; Ukseleht väljast: Paint - Glossy White; Ukseleht seest: Paint - Glossy White; Täpsustus: RAL 9003; 19 Mudel või toote tunnus: Undefined; 20 Tootja: Undefined; 21 Tooteinfo: Undefined; 22 Kasutus- ja hooldusjuhend: Undefined
AC_Pset_RenovationAndPhasing - Renovation Status: New

# IfcDoor: VU-10 1 000×2 100, Välisuks * Door 22
In: 2 KORRUS
Type - OperationType: SINGLE_SWING_RIGHT; ParameterTakesPrecedence: no; Sizeable: no
Type - Door Lining Properties - LiningDepth: 115 mm; LiningThickness: 40 mm; LiningOffset: -85 mm; CasingThickness: 50 mm; CasingDepth: 19 mm
Type - Door Panel Properties - Panel 1 - PanelDepth: 40 mm; PanelOperation: SWINGING; PanelWidth: 1; PanelPosition: MIDDLE
Description: Teras; OverallHeight: 2100 mm; OverallWidth: 1000 mm; Classification: 1.9 IfcDoor (uks) (_RKAS BIM + ARCHICAD Classification); 52 Siseuksed (EHITUSKULUDE LIIGITAMINE EVS 885:2005)
Pset_DoorCommon - ThermalTransmittance: 0.95; GlazingAreaFraction: 0; IsExternal: yes
Avatäited - 01 Nimetus: Välisuks; 02 Materjal: Sile metalluks; 03 Tähistus: VU-10 1 000×2 100; 04 Avamõõdu geomeetria: 1 000×2 100; 05 Asukoha info: Exterior; 06 Soojusläbivus: 0,95; 07 Helipidavus: Undefined; 08 Veepidavus: 2a; 09 Õhuläbilaskvus: klass 1; 10 Tulekindlus: nõudeid ei esitata; 11 Vastupanu tulekoormusele: C1; 12 Klaaspakett: -; 13 Klaasingu erisused: Undefined; 14 Päikesekiirgus tegur (g-väärtus): -; 15 Avanemine: Avanemine: "L" (L - vasak; R - parem); 16 Liigendatus: Lävepakk madal, kuni 25mm, Roostevabateras; 17 Sulused, lukustus: Vändenupp/liblikas, sulgur; 18 Viimistlus: Leng väljast: Paint - Light Gray; Leng seest: Paint - Light Gray; Ukseleht väljast: Paint - Light Gray; Ukseleht seest: Paint - Light Gray; Täpsustus: Pulbervärvitud tooniga RAL 7040; 19 Mudel või toote tunnus: Undefined; 20 Tootja: Undefined; 21 Tooteinfo: Undefined; 22 Kasutus- ja hooldusjuhend: Undefined
AC_Pset_RenovationAndPhasing - Renovation Status: New

# IfcDoor: VU-3 2 500×2 100, Välisuks * Double Door 22
In: 1 KORRUS
Type - OperationType: DOUBLE_DOOR_SINGLE_SWING; ParameterTakesPrecedence: no; Sizeable: no
Type - Door Lining Properties - LiningDepth: 115 mm; LiningThickness: 40 mm; LiningOffset: 100 mm; CasingThickness: 50 mm; CasingDepth: 19 mm
Type - Door Panel Properties - Panel 1 - PanelDepth: 40 mm; PanelOperation: SWINGING; PanelWidth: 0.504959; PanelPosition: RIGHT
Type - Door Panel Properties - Panel 2 - PanelDepth: 40 mm; PanelOperation: SWINGING; PanelWidth: 0.504959; PanelPosition: LEFT
OverallHeight: 2100 mm; OverallWidth: 2500 mm; Classification: 1.9 IfcDoor (uks) (_RKAS BIM + ARCHICAD Classification); 52 Siseuksed (EHITUSKULUDE LIIGITAMINE EVS 885:2005)
Pset_DoorCommon - ThermalTransmittance: 0; GlazingAreaFraction: 0; IsExternal: yes
Avatäited - 01 Nimetus: Välisuks; 02 Materjal: Sile metalluks; 03 Tähistus: VU-3 2 500×2 100; 04 Avamõõdu geomeetria: 2 500×2 100; 05 Asukoha info: Exterior; 06 Soojusläbivus: 0,95; 07 Helipidavus: Undefined; 08 Veepidavus: 2a; 09 Õhuläbilaskvus: klass 1; 10 Tulekindlus: nõudeid ei esitata; 11 Vastupanu tulekoormusele: C1; 12 Klaaspakett: -; 13 Klaasingu erisused: Undefined; 14 Päikesekiirgus tegur (g-väärtus): -; 15 Avanemine: Avanemine: "R" (L - vasak; R - parem); 16 Liigendatus: Lävepakk madal, kuni 25mm, Roostevabateras; 17 Sulused, lukustus: Vändenupp/liblikas, sulgur, kiirriiv,; 18 Viimistlus: Leng väljast: Paint - Light Gray; Leng seest: Paint - Light Gray; Ukseleht väljast: Paint - Light Gray; Ukseleht seest: Paint - Light Gray; Täpsustus: Pulbervärvitud tooniga RAL 7040; 19 Mudel või toote tunnus: Undefined; 20 Tootja: Undefined; 21 Tooteinfo: Undefined; 22 Kasutus- ja hooldusjuhend: Undefined
AC_Pset_RenovationAndPhasing - Renovation Status: Existing

# IfcDoor: VU-4 2 300×2 100, Välisuks * Double Door 22
In: 1 KORRUS
Type - OperationType: DOUBLE_DOOR_SINGLE_SWING; ParameterTakesPrecedence: no; Sizeable: no
Type - Door Lining Properties - LiningDepth: 115 mm; LiningThickness: 40 mm; LiningOffset: 0 mm; CasingThickness: 50 mm; CasingDepth: 19 mm
Type - Door Panel Properties - Panel 1 - PanelDepth: 40 mm; PanelOperation: SWINGING; PanelWidth: 0.505405; PanelPosition: RIGHT
Type - Door Panel Properties - Panel 2 - PanelDepth: 40 mm; PanelOperation: SWINGING; PanelWidth: 0.505405; PanelPosition: LEFT
Description: Teras; OverallHeight: 2100 mm; OverallWidth: 2300 mm; Classification: 43 Välisuksed ja väravad (EHITUSKULUDE LIIGITAMINE EVS 885:2005); 1.9 IfcDoor (uks) (_RKAS BIM + ARCHICAD Classification)
Pset_DoorCommon - ThermalTransmittance: 0.95; GlazingAreaFraction: 0; IsExternal: yes
Avatäited - 01 Nimetus: Välisuks; 02 Materjal: Sile metalluks; 03 Tähistus: VU-4 2 300×2 100; 04 Avamõõdu geomeetria: 2 300×2 100; 05 Asukoha info: Exterior; 06 Soojusläbivus: 0,95; 07 Helipidavus: Undefined; 08 Veepidavus: 2a; 09 Õhuläbilaskvus: klass 1; 10 Tulekindlus: nõudeid ei esitata; 11 Vastupanu tulekoormusele: C1; 12 Klaaspakett: -; 13 Klaasingu erisused: Undefined; 14 Päikesekiirgus tegur (g-väärtus): -; 15 Avanemine: Avanemine: "R" (L - vasak; R - parem); 16 Liigendatus: Lävepakk madal, kuni 25mm, Roostevabateras; 17 Sulused, lukustus: Vändenupp/liblikas, sulgur, kiirriiv; 18 Viimistlus: Leng väljast: Paint - Light Gray; Leng seest: Paint - Light Gray; Ukseleht väljast: Paint - Light Gray; Ukseleht seest: Paint - Light Gray; Täpsustus: Pulbervärvitud tooniga RAL 7040; 19 Mudel või toote tunnus: Undefined; 20 Tootja: Undefined; 21 Tooteinfo: Undefined; 22 Kasutus- ja hooldusjuhend: Undefined
AC_Pset_RenovationAndPhasing - Renovation Status: Existing

# IfcDoor: VU-5 2 450×2 100, Välisuks * Double Door 22
In: 1 KORRUS
Type - OperationType: DOUBLE_DOOR_SINGLE_SWING; ParameterTakesPrecedence: no; Sizeable: no
Type - Door Lining Properties - LiningDepth: 115 mm; LiningThickness: 40 mm; LiningOffset: 0 mm; CasingThickness: 50 mm; CasingDepth: 19 mm
Type - Door Panel Properties - Panel 1 - PanelDepth: 40 mm; PanelOperation: SWINGING; PanelWidth: 0.505063; PanelPosition: LEFT
Type - Door Panel Properties - Panel 2 - PanelDepth: 40 mm; PanelOperation: SWINGING; PanelWidth: 0.505063; PanelPosition: RIGHT
OverallHeight: 2100 mm; OverallWidth: 2450 mm; Classification: 43 Välisuksed ja väravad (EHITUSKULUDE LIIGITAMINE EVS 885:2005); 1.9 IfcDoor (uks) (_RKAS BIM + ARCHICAD Classification)
Pset_DoorCommon - ThermalTransmittance: 0; GlazingAreaFraction: 3.53337; IsExternal: yes
Avatäited - 01 Nimetus: Välisuks; 02 Materjal: Klaasiga-sile metalluks; 03 Tähistus: VU-5 2 450×2 100; 04 Avamõõdu geomeetria: 2 450×2 100; 05 Asukoha info: Exterior; 06 Soojusläbivus: 0,95; 07 Helipidavus: Undefined; 08 Veepidavus: 2a; 09 Õhuläbilaskvus: klass 1; 10 Tulekindlus: nõudeid ei esitata; 11 Vastupanu tulekoormusele: C1; 12 Klaaspakett: Karastatud ja lamineeritud kirgas klaas; 13 Klaasingu erisused: Undefined; 14 Päikesekiirgus tegur (g-väärtus): 0,3; 15 Avanemine: Avanemine: "L" (L - vasak; R - parem); 16 Liigendatus: Lävepakk madal, kuni 25mm, Roostevabateras; 17 Sulused, lukustus: Vändenupp/liblikas, sulgur, kiirriiv; 18 Viimistlus: Leng väljast: Paint - Glossy White; Leng seest: Paint - Glossy White; Ukseleht väljast: Paint - Glossy White; Ukseleht seest: Paint - Glossy White; Täpsustus: Pulbervärvitud tooniga RAL 9003; 19 Mudel või toote tunnus: Undefined; 20 Tootja: Undefined; 21 Tooteinfo: Undefined; 22 Kasutus- ja hooldusjuhend: Undefined
AC_Pset_RenovationAndPhasing - Renovation Status: Existing

# IfcDoor: VU-6 1 600×3 200, Välisuks * Double Door with Transom 22
In: 2 KORRUS
Type - OperationType: DOUBLE_DOOR_SINGLE_SWING; ParameterTakesPrecedence: no; Sizeable: no
Type - Door Lining Properties - LiningDepth: 115 mm; LiningThickness: 40 mm; TransomThickness: 40 mm; TransomOffset: 2487.88 mm; LiningOffset: -200 mm; CasingThickness: 50 mm; CasingDepth: 19 mm
Type - Door Panel Properties - Panel 1 - PanelDepth: 40 mm; PanelOperation: SWINGING; PanelWidth: 0.507895; PanelPosition: RIGHT
Type - Door Panel Properties - Panel 2 - PanelDepth: 40 mm; PanelOperation: SWINGING; PanelWidth: 0.507895; PanelPosition: LEFT
Description: Alumiinium; OverallHeight: 3200 mm; OverallWidth: 1600 mm; Classification: 1.9 IfcDoor (uks) (_RKAS BIM + ARCHICAD Classification); 52 Siseuksed (EHITUSKULUDE LIIGITAMINE EVS 885:2005)
Pset_DoorCommon - ThermalTransmittance: 0.95; GlazingAreaFraction: 3.47749; IsExternal: yes
Avatäited - 01 Nimetus: Välisuks; 02 Materjal: Klaasiga-sile metalluks; 03 Tähistus: VU-6 1 600×3 200; 04 Avamõõdu geomeetria: 1 600×3 200; 05 Asukoha info: Exterior; 06 Soojusläbivus: 0,95; 07 Helipidavus: 30 dB; 08 Veepidavus: 2a; 09 Õhuläbilaskvus: klass 1; 10 Tulekindlus: nõudeid ei esitata; 11 Vastupanu tulekoormusele: C1; 12 Klaaspakett: Karastatud ja lamineeritud kirgas klaas; 13 Klaasingu erisused: Undefined; 14 Päikesekiirgus tegur (g-väärtus): Undefined; 15 Avanemine: Avanemine: "R" (L - vasak; R - parem); 16 Liigendatus: Lävepakk madal, kuni 25mm, Roostevabateras; 17 Sulused, lukustus: Vändenupp/liblikas, sulgur, kiirriiv, roostevaba terasest käepide, toru läbimõõt 25 mm, pikkus 600 mm; 18 Viimistlus: Leng väljast: plast. valge; Leng seest: plast. valge; Ukseleht väljast: Paint - Glossy White; Ukseleht seest: Paint - Glossy White; Täpsustus: Pulbervärvitud tooniga RAL 9003; 19 Mudel või toote tunnus: Undefined; 20 Tootja: Undefined; 21 Tooteinfo: Undefined; 22 Kasutus- ja hooldusjuhend: Undefined
AC_Pset_RenovationAndPhasing - Renovation Status: New

# IfcDoor: VU-8 1 700×2 850, Välisuks * Double Door with Transom 22
In: 2 KORRUS
Type - OperationType: DOUBLE_DOOR_SINGLE_SWING; ParameterTakesPrecedence: no; Sizeable: no
Type - Door Lining Properties - LiningDepth: 115 mm; LiningThickness: 40 mm; TransomThickness: 40 mm; TransomOffset: 2100 mm; LiningOffset: 0 mm; CasingThickness: 50 mm; CasingDepth: 19 mm
Type - Door Panel Properties - Panel 1 - PanelDepth: 40 mm; PanelOperation: SWINGING; PanelWidth: 0.507407; PanelPosition: LEFT
Type - Door Panel Properties - Panel 2 - PanelDepth: 40 mm; PanelOperation: SWINGING; PanelWidth: 0.507407; PanelPosition: RIGHT
Description: Alumiinium, turvaklaas; OverallHeight: 2850 mm; OverallWidth: 1700 mm; Classification: 43 Välisuksed ja väravad (EHITUSKULUDE LIIGITAMINE EVS 885:2005); 1.9 IfcDoor (uks) (_RKAS BIM + ARCHICAD Classification)
Pset_DoorCommon - ThermalTransmittance: 0.95; GlazingAreaFraction: 3.33953; IsExternal: yes
Avatäited - 01 Nimetus: Välisuks; 02 Materjal: Klaasiga-sile metalluks; 03 Tähistus: VU-8 1 700×2 850; 04 Avamõõdu geomeetria: 1 700×2 850; 05 Asukoha info: Exterior; 06 Soojusläbivus: 0,95; 07 Helipidavus: Undefined; 08 Veepidavus: 2a; 09 Õhuläbilaskvus: klass 1; 10 Tulekindlus: nõudeid ei esitata; 11 Vastupanu tulekoormusele: C1; 12 Klaaspakett: Karastatud ja lamineeritud kirgas klaas; 13 Klaasingu erisused: Undefined; 14 Päikesekiirgus tegur (g-väärtus): Undefined; 15 Avanemine: Avanemine: "L" (L - vasak; R - parem); 16 Liigendatus: Lävepakk madal, kuni 25mm, Roostevabateras; 17 Sulused, lukustus: Vändenupp/liblikas, sulgur, kiirriiv, roostevaba terasest käepide, toru läbimõõt 25 mm, pikkus 600 mm,; 18 Viimistlus: Leng väljast: teras, valge; Leng seest: teras, valge; Ukseleht väljast: Paint - Glossy White; Ukseleht seest: Paint - Glossy White; Täpsustus: Pulbervärvitud tooniga RAL 9003; 19 Mudel või toote tunnus: Undefined; 20 Tootja: Undefined; 21 Tooteinfo: Undefined; 22 Kasutus- ja hooldusjuhend: Undefined
AC_Pset_RenovationAndPhasing - Renovation Status: Existing

# IfcDoor: VU-9A 3 100×2 800, Ol.Olev garaazi uks * Vertical Sliding Garage Door 22
In: 2 KORRUS
Type - OperationType: ROLLINGUP; ParameterTakesPrecedence: no; Sizeable: no
Type - Door Lining Properties - LiningDepth: 100 mm; LiningThickness: 50 mm; LiningOffset: 0 mm
Type - Door Panel Properties - Panel 1 - PanelDepth: 40 mm; PanelOperation: ROLLINGUP; PanelWidth: 1; PanelPosition: MIDDLE
OverallHeight: 2800 mm; OverallWidth: 3100 mm; Classification: 1.9 IfcDoor (uks) (_RKAS BIM + ARCHICAD Classification); 52 Siseuksed (EHITUSKULUDE LIIGITAMINE EVS 885:2005)
Pset_DoorCommon - ThermalTransmittance: 0; GlazingAreaFraction: 0; IsExternal: yes
Avatäited - 01 Nimetus: Ol.Olev garaazi uks; 02 Materjal: Sile metalluks; 03 Tähistus: VU-9A 3 100×2 800; 04 Avamõõdu geomeetria: 3 100×2 800; 05 Asukoha info: Exterior; 06 Soojusläbivus: Undefined; 07 Helipidavus: Undefined; 08 Veepidavus: Undefined; 09 Õhuläbilaskvus: Undefined; 10 Tulekindlus: nõudeid ei esitata; 11 Vastupanu tulekoormusele: Undefined; 12 Klaaspakett: Undefined; 13 Klaasingu erisused: Undefined; 14 Päikesekiirgus tegur (g-väärtus): Undefined; 15 Avanemine: Avanemine: "L" (L - vasak; R - parem); 16 Liigendatus: Undefined; 17 Sulused, lukustus: Undefined; 18 Viimistlus: Leng väljast: teras; Leng seest: teras; Ukseleht väljast: teras; Ukseleht seest: teras; Täpsustus: Undefined; 19 Mudel või toote tunnus: Undefined; 20 Tootja: Undefined; 21 Tooteinfo: Undefined; 22 Kasutus- ja hooldusjuhend: Undefined
AC_Pset_RenovationAndPhasing - Renovation Status: Existing

# IfcDoor: VU-9B 1 000×2 100, Ol.olev garaazi uks * Door 22
In: 2 KORRUS
Type - OperationType: SINGLE_SWING_RIGHT; ParameterTakesPrecedence: no; Sizeable: no
Type - Door Lining Properties - LiningDepth: 115 mm; LiningThickness: 40 mm; LiningOffset: -85 mm; CasingThickness: 50 mm; CasingDepth: 19 mm
Type - Door Panel Properties - Panel 1 - PanelDepth: 40 mm; PanelOperation: SWINGING; PanelWidth: 1; PanelPosition: MIDDLE
OverallHeight: 2100 mm; OverallWidth: 1000 mm; Classification: 1.9 IfcDoor (uks) (_RKAS BIM + ARCHICAD Classification); 52 Siseuksed (EHITUSKULUDE LIIGITAMINE EVS 885:2005)
Pset_DoorCommon - ThermalTransmittance: 0.95; GlazingAreaFraction: 0; IsExternal: yes
Avatäited - 01 Nimetus: Ol.olev garaazi uks; 02 Materjal: Sile metalluks; 03 Tähistus: VU-9B 1 000×2 100; 04 Avamõõdu geomeetria: 1 000×2 100; 05 Asukoha info: Exterior; 06 Soojusläbivus: Undefined; 07 Helipidavus: Undefined; 08 Veepidavus: Undefined; 09 Õhuläbilaskvus: klass 1; 10 Tulekindlus: nõudeid ei esitata; 11 Vastupanu tulekoormusele: Undefined; 12 Klaaspakett: -; 13 Klaasingu erisused: Undefined; 14 Päikesekiirgus tegur (g-väärtus): Undefined; 15 Avanemine: Avanemine: "L" (L - vasak; R - parem); 16 Liigendatus: Undefined; 17 Sulused, lukustus: Vändenupp/liblikas, sulgur; 18 Viimistlus: Leng väljast: teras; Leng seest: teras; Ukseleht väljast: teras; Ukseleht seest: teras; Täpsustus: Undefined; 19 Mudel või toote tunnus: Undefined; 20 Tootja: Undefined; 21 Tooteinfo: Undefined; 22 Kasutus- ja hooldusjuhend: Undefined
AC_Pset_RenovationAndPhasing - Renovation Status: Existing

# IfcFlowTerminal: Basin 22 (3)
In: 2 KORRUS
Type - ElementType: Element type FU - 001
Type - SEADMED - 01 Nimetus: Basin 22; Täpsustus: Undefined; 02 Tähis: FU - 001; 03 Osasüsteem: Undefined; 04 Tehniline karakteristika: Undefined; 05 Tootja: Undefined; 06 Mudel või toote tunnus: Undefined; 07 Tooteinfo: Undefined; 08 Kasutus- ja hooldusjuhend: Undefined
Classification: 4.10 IfcSanitaryTerminalType (sanitaartehnika) (_RKAS BIM + ARCHICAD Classification); 713 Sanitaartehnika seadmed (EHITUSKULUDE LIIGITAMINE EVS 885:2005)
SEADMED - 01 Nimetus: Undefined
AC_Pset_RenovationAndPhasing - Renovation Status: Existing

# IfcFlowTerminal: Basin 22, Valamu
In: 2 KORRUS
Type - ElementType: Element type FU - 013
Type - SEADMED - 01 Nimetus: Basin 22; Täpsustus: Undefined; 02 Tähis: FU - 013; 03 Osasüsteem: Undefined; 04 Tehniline karakteristika: Undefined; 05 Tootja: Undefined; 06 Mudel või toote tunnus: Undefined; 07 Tooteinfo: Undefined; 08 Kasutus- ja hooldusjuhend: Undefined
Description: Valamu; Classification: 4.10 IfcSanitaryTerminalType (sanitaartehnika) (_RKAS BIM + ARCHICAD Classification); 713 Sanitaartehnika seadmed (EHITUSKULUDE LIIGITAMINE EVS 885:2005)
SEADMED - 01 Nimetus: Undefined
AC_Pset_RenovationAndPhasing - Renovation Status: New

# IfcFlowTerminal: Basin 22 (10)
Type - ElementType: Element type Valamu 1
Type - SEADMED - 01 Nimetus: Basin 22; Täpsustus: VALAMU ARTIC; 02 Tähis: Valamu 1; 03 Osasüsteem: Sanitaartehnika; 04 Tehniline karakteristika: Kandurkinnituseks 55 cm; 05 Tootja: Villeroy & Boch Gustavsberg; 06 Mudel või toote tunnus: 4550; 07 Tooteinfo: Undefined; 08 Kasutus- ja hooldusjuhend: Undefined
Description: Valamu; Classification: 4.10 IfcSanitaryTerminalType (sanitaartehnika) (_RKAS BIM + ARCHICAD Classification); 713 Sanitaartehnika seadmed (EHITUSKULUDE LIIGITAMINE EVS 885:2005)
SEADMED - 07 Tooteinfo: GB1145500101; 01 Nimetus: VALAMU ARTIC
AC_Pset_RenovationAndPhasing - Renovation Status: New
Name | In
5 x Valamu | 1 KORRUS
5 x Valamu | 2 KORRUS

# IfcFlowTerminal: Basin 22, Valamu
In: 2 KORRUS
Type - ElementType: Element type inva Valamu
Type - SEADMED - 01 Nimetus: Basin 22; Täpsustus: VALAMU 740; 02 Tähis: inva Valamu; 03 Osasüsteem: Sanitaartehnika; 04 Tehniline karakteristika: Poltkinnituseks laius 60 cm; 05 Tootja: Villeroy & Boch Gustavsberg; 06 Mudel või toote tunnus: 4550; 07 Tooteinfo: Undefined; 08 Kasutus- ja hooldusjuhend: Undefined
Description: Valamu; Classification: 4.10 IfcSanitaryTerminalType (sanitaartehnika) (_RKAS BIM + ARCHICAD Classification); 713 Sanitaartehnika seadmed (EHITUSKULUDE LIIGITAMINE EVS 885:2005)
SEADMED - 07 Tooteinfo: GB1145500101; 01 Nimetus: VALAMU 740
AC_Pset_RenovationAndPhasing - Renovation Status: New

# IfcFlowTerminal: Basin 22, Valamu
In: 1 KORRUS
Type - ElementType: Element type inva Valamu
Type - SEADMED - 01 Nimetus: Basin 22; Täpsustus: VALAMU ARTIC; 02 Tähis: inva Valamu; 03 Osasüsteem: Sanitaartehnika; 04 Tehniline karakteristika: Kandurkinnituseks 55 cm; 05 Tootja: Villeroy & Boch Gustavsberg; 06 Mudel või toote tunnus: 4550; 07 Tooteinfo: Undefined; 08 Kasutus- ja hooldusjuhend: Undefined
Description: Valamu; Classification: 4.10 IfcSanitaryTerminalType (sanitaartehnika) (_RKAS BIM + ARCHICAD Classification); 713 Sanitaartehnika seadmed (EHITUSKULUDE LIIGITAMINE EVS 885:2005)
SEADMED - 07 Tooteinfo: GB1145500101; 01 Nimetus: VALAMU ARTIC
AC_Pset_RenovationAndPhasing - Renovation Status: New

# IfcFlowTerminal: CHS Cold-Formed Beam 22 (2)
In: 2 KORRUS
Type - ElementType: Element type VALGUSTI
Type - SEADMED - 01 Nimetus: Undefined; 02 Tähis: VALGUSTI; 03 Osasüsteem: Undefined; 04 Tehniline karakteristika: Undefined; 05 Tootja: Undefined; 06 Mudel või toote tunnus: Undefined; 07 Tooteinfo: Undefined; 08 Kasutus- ja hooldusjuhend: Undefined
Description: Dekoratiivne välisvalgusti; Classification: 5.9 IfcLightFixtureType (valgusti) (_RKAS BIM + ARCHICAD Classification); Material: Teras (1)
AC_Pset_RenovationAndPhasing - Renovation Status: New

# IfcFlowTerminal: Downspout 22 (4)
In: KATUSEPLAAN
Type - ElementType: Element type Vihmaveerennid
Type - SEADMED - 01 Nimetus: Downspout 22; Täpsustus: vihmaveerennid; 02 Tähis: Vihmaveerennid; 03 Osasüsteem: Undefined; 04 Tehniline karakteristika: Undefined; 05 Tootja: Undefined; 06 Mudel või toote tunnus: Undefined; 07 Tooteinfo: Undefined; 08 Kasutus- ja hooldusjuhend: Undefined
Classification: 4.13 IfcWasteTerminalType (äravool) (_RKAS BIM + ARCHICAD Classification); 71 Veevarustus ja kanalisatsioon (EHITUSKULUDE LIIGITAMINE EVS 885:2005)
SEADMED - 01 Nimetus: vihmaveerennid
AC_Pset_RenovationAndPhasing - Renovation Status: New

# IfcFlowTerminal: Downspout Elbow 22 (4)
In: KATUSEPLAAN
Type - ElementType: Element type Vihmaveerennid
Type - SEADMED - 01 Nimetus: Downspout Elbow 22; Täpsustus: Undefined; 02 Tähis: Vihmaveerennid; 03 Osasüsteem: Undefined; 04 Tehniline karakteristika: Undefined; 05 Tootja: Undefined; 06 Mudel või toote tunnus: Undefined; 07 Tooteinfo: Undefined; 08 Kasutus- ja hooldusjuhend: Undefined
Classification: 4.13 IfcWasteTerminalType (äravool) (_RKAS BIM + ARCHICAD Classification); 71 Veevarustus ja kanalisatsioon (EHITUSKULUDE LIIGITAMINE EVS 885:2005)
SEADMED - 01 Nimetus: Undefined
AC_Pset_RenovationAndPhasing - Renovation Status: New

# IfcFlowTerminal: Gutter 22 (7)
Type - ElementType: Element type Vihmaveerennid
Type - SEADMED - 01 Nimetus: Gutter 22; Täpsustus: Undefined; 02 Tähis: Vihmaveerennid; 03 Osasüsteem: Undefined; 04 Tehniline karakteristika: Undefined; 05 Tootja: Undefined; 06 Mudel või toote tunnus: Undefined; 07 Tooteinfo: Undefined; 08 Kasutus- ja hooldusjuhend: Undefined
Classification: 4.13 IfcWasteTerminalType (äravool) (_RKAS BIM + ARCHICAD Classification); 71 Veevarustus ja kanalisatsioon (EHITUSKULUDE LIIGITAMINE EVS 885:2005)
SEADMED - 01 Nimetus: Undefined
Name | In | Renovation Status
3 x Renn | 1 KORRUS | Existing
4 x Renn | KATUSEPLAAN | New

# IfcFlowTerminal: Shower Kit 22 (4)
Type - ElementType: Element type Dušš 1
Type - SEADMED - 01 Nimetus: Shower Kit 22; Täpsustus: Dušš; 02 Tähis: Dušš 1; 03 Osasüsteem: Sanitaartehnika; 04 Tehniline karakteristika: 1jet EcoSmart 9 l/min with; 05 Tootja: Hansgrohe; 06 Mudel või toote tunnus: 280; 07 Tooteinfo: Undefined; 08 Kasutus- ja hooldusjuhend: Undefined
Classification: 4.10 IfcSanitaryTerminalType (sanitaartehnika) (_RKAS BIM + ARCHICAD Classification); 713 Sanitaartehnika seadmed (EHITUSKULUDE LIIGITAMINE EVS 885:2005)
SEADMED - 01 Nimetus: Dušš
AC_Pset_RenovationAndPhasing - Renovation Status: New
Name | In
2 x Dušš 1 | 1 KORRUS
2 x Dušš 1 | 2 KORRUS

# IfcFlowTerminal: Shower Kit 22, Segisti
In: 1 KORRUS
Type - ElementType: Element type Segisti
Type - SEADMED - 01 Nimetus: Shower Kit 22; Täpsustus: Dušš; 02 Tähis: Segisti; 03 Osasüsteem: Sanitaartehnika; 04 Tehniline karakteristika: 1jet EcoSmart 9 l/min with; 05 Tootja: Hansgrohe; 06 Mudel või toote tunnus: 280; 07 Tooteinfo: Undefined; 08 Kasutus- ja hooldusjuhend: Undefined
Classification: 4.10 IfcSanitaryTerminalType (sanitaartehnika) (_RKAS BIM + ARCHICAD Classification); 713 Sanitaartehnika seadmed (EHITUSKULUDE LIIGITAMINE EVS 885:2005)
SEADMED - 01 Nimetus: Dušš
AC_Pset_RenovationAndPhasing - Renovation Status: New

# IfcFlowTerminal: Sink Belfast 22 (2)
Type - ElementType: Element type Valamu
Type - SEADMED - 01 Nimetus: Sink Belfast 22; Täpsustus: TEHNILINE VALAMU; 02 Tähis: Valamu; 03 Osasüsteem: Sanitaartehnika; 04 Tehniline karakteristika: EFX 620-78 Roostevabast terasest; 05 Tootja: Franke; 06 Mudel või toote tunnus: Undefined; 07 Tooteinfo: Undefined; 08 Kasutus- ja hooldusjuhend: Undefined
Description: Valamu; Classification: 4.10 IfcSanitaryTerminalType (sanitaartehnika) (_RKAS BIM + ARCHICAD Classification); 713 Sanitaartehnika seadmed (EHITUSKULUDE LIIGITAMINE EVS 885:2005)
SEADMED - 01 Nimetus: TEHNILINE VALAMU
AC_Pset_RenovationAndPhasing - Renovation Status: New
Name | In
Valamu | 1 KORRUS
Valamu | 2 KORRUS

# IfcFlowTerminal: Sink Belfast 22 (5)
Type - ElementType: Element type Valamu
Type - SEADMED - 01 Nimetus: Sink Belfast 22; Täpsustus: TEHNILINE VALAMU; 02 Tähis: Valamu; 03 Osasüsteem: Sanitaartehnika; 04 Tehniline karakteristika: Quadrant QAX 210; 05 Tootja: Franke; 06 Mudel või toote tunnus: Undefined; 07 Tooteinfo: Undefined; 08 Kasutus- ja hooldusjuhend: Undefined
Description: Valamu; Classification: 4.10 IfcSanitaryTerminalType (sanitaartehnika) (_RKAS BIM + ARCHICAD Classification); 713 Sanitaartehnika seadmed (EHITUSKULUDE LIIGITAMINE EVS 885:2005)
SEADMED - 01 Nimetus: TEHNILINE VALAMU
Name | In | Renovation Status
4 x Valamu | 1 KORRUS | New
Valamu | 2 KORRUS | Existing

# IfcFlowTerminal: Tap 22 (5)
Type - ElementType: Element type Segisti
Type - SEADMED - 01 Nimetus: Tap 22; Täpsustus: Segisti Novara Plus; 02 Tähis: Segisti; 03 Osasüsteem: Sanitaartehnika; 04 Tehniline karakteristika: Kroom, d 50mm, pööratav jooksutoru; 05 Tootja: Franke; 06 Mudel või toote tunnus: 115.0486.992; 07 Tooteinfo: Undefined; 08 Kasutus- ja hooldusjuhend: Undefined
Description: Valamu; Classification: 4.10 IfcSanitaryTerminalType (sanitaartehnika) (_RKAS BIM + ARCHICAD Classification); 713 Sanitaartehnika seadmed (EHITUSKULUDE LIIGITAMINE EVS 885:2005)
SEADMED - 01 Nimetus: Segisti Novara Plus
AC_Pset_RenovationAndPhasing - Renovation Status: New
Name | In
4 x Valamu | 1 KORRUS
Valamu | 2 KORRUS

# IfcFlowTerminal: Tap 22 (2)
Type - ElementType: Element type Segisti
Type - SEADMED - 01 Nimetus: Tap 22; Täpsustus: Segisti Semi-Pro; 02 Tähis: Segisti; 03 Osasüsteem: Sanitaartehnika; 04 Tehniline karakteristika: Kroom, d 35mm, kõrgrõhk; 05 Tootja: Flexus; 06 Mudel või toote tunnus: 115.0486.992; 07 Tooteinfo: Undefined; 08 Kasutus- ja hooldusjuhend: Undefined
Description: Valamu; Classification: 4.10 IfcSanitaryTerminalType (sanitaartehnika) (_RKAS BIM + ARCHICAD Classification); 713 Sanitaartehnika seadmed (EHITUSKULUDE LIIGITAMINE EVS 885:2005)
SEADMED - 01 Nimetus: Segisti Semi-Pro
AC_Pset_RenovationAndPhasing - Renovation Status: New
Name | In
Valamu | 1 KORRUS
Valamu | 2 KORRUS

# IfcFlowTerminal: Tap 22 (10)
Type - ElementType: Element type Segisti 1
Type - SEADMED - 01 Nimetus: Tap 22; Täpsustus: Segisti Talis S; 02 Tähis: Segisti 1; 03 Osasüsteem: Sanitaartehnika; 04 Tehniline karakteristika: Ühe hoovaga kraanisegisti bidettega käsidušši ja dušivoolikuga 160 cm; 05 Tootja: Hansgrohe; 06 Mudel või toote tunnus: Undefined; 07 Tooteinfo: Undefined; 08 Kasutus- ja hooldusjuhend: Undefined
Description: Valamu; Classification: 4.10 IfcSanitaryTerminalType (sanitaartehnika) (_RKAS BIM + ARCHICAD Classification); 713 Sanitaartehnika seadmed (EHITUSKULUDE LIIGITAMINE EVS 885:2005)
SEADMED - 01 Nimetus: Segisti Talis S
Name | In | Renovation Status
Valamu | 1 KORRUS | Existing
4 x Valamu | 1 KORRUS | New
5 x Valamu | 2 KORRUS | New

# IfcFlowTerminal: Tap 22 (2)
Type - ElementType: Element type Segisti 1
Type - SEADMED - 01 Nimetus: Tap 22; Täpsustus: VALAMUSEGISTI NAUTIC; 02 Tähis: Segisti 1; 03 Osasüsteem: Sanitaartehnika; 04 Tehniline karakteristika: 160 MM KÄEPIDE; 05 Tootja: Villeroy & Boch Gustavsberg; 06 Mudel või toote tunnus: GB41214047 64; 07 Tooteinfo: Undefined; 08 Kasutus- ja hooldusjuhend: Undefined
Description: Valamu; Classification: 4.10 IfcSanitaryTerminalType (sanitaartehnika) (_RKAS BIM + ARCHICAD Classification); 713 Sanitaartehnika seadmed (EHITUSKULUDE LIIGITAMINE EVS 885:2005)
SEADMED - 07 Tooteinfo: GB1145500101; 01 Nimetus: VALAMUSEGISTI NAUTIC
AC_Pset_RenovationAndPhasing - Renovation Status: New
Name | In
Valamu | 1 KORRUS
Valamu | 2 KORRUS

# IfcFlowTerminal: Tap 22, Valamu
In: 2 KORRUS
Type - ElementType: Element type Segisti 2
Type - SEADMED - 01 Nimetus: Tap 22; Täpsustus: Segisti Metris S; 02 Tähis: Segisti 2; 03 Osasüsteem: Sanitaartehnika; 04 Tehniline karakteristika: flow rate at 3 bar: 5 l/min; 05 Tootja: Hansgrohe; 06 Mudel või toote tunnus: 31159000; 07 Tooteinfo: Undefined; 08 Kasutus- ja hooldusjuhend: Undefined
Description: Valamu; Classification: 4.10 IfcSanitaryTerminalType (sanitaartehnika) (_RKAS BIM + ARCHICAD Classification); 713 Sanitaartehnika seadmed (EHITUSKULUDE LIIGITAMINE EVS 885:2005)
SEADMED - 01 Nimetus: Segisti Metris S
AC_Pset_RenovationAndPhasing - Renovation Status: New

# IfcFlowTerminal: Titaan - Tsink (1) D200 (6)
In: 2 KORRUS
Type - ElementType: Element type Välisvalgusti
Type - SEADMED - 01 Nimetus: Undefined; 02 Tähis: Välisvalgusti; 03 Osasüsteem: Undefined; 04 Tehniline karakteristika: Undefined; 05 Tootja: Undefined; 06 Mudel või toote tunnus: Undefined; 07 Tooteinfo: Undefined; 08 Kasutus- ja hooldusjuhend: Undefined
Description: Dekoratiivne välisvalgusti; Classification: 5.9 IfcLightFixtureType (valgusti) (_RKAS BIM + ARCHICAD Classification)
AC_Pset_RenovationAndPhasing - Renovation Status: Existing

# IfcFlowTerminal: Titaan - Tsink (1) D50 (4)
In: 2 KORRUS
Type - ElementType: Element type Välisvalgusti
Type - SEADMED - 01 Nimetus: Undefined; 02 Tähis: Välisvalgusti; 03 Osasüsteem: Undefined; 04 Tehniline karakteristika: Undefined; 05 Tootja: Undefined; 06 Mudel või toote tunnus: Undefined; 07 Tooteinfo: Undefined; 08 Kasutus- ja hooldusjuhend: Undefined
Description: Dekoratiivne välisvalgusti; Classification: 5.9 IfcLightFixtureType (valgusti) (_RKAS BIM + ARCHICAD Classification)
AC_Pset_RenovationAndPhasing - Renovation Status: Existing

# IfcFlowTerminal: Urinal 22 (4)
Type - ElementType: Element type Pisuaar
Type - SEADMED - 01 Nimetus: Urinal 22; Täpsustus: Pissuaar; 02 Tähis: Pisuaar; 03 Osasüsteem: Sanitaartehnika; 04 Tehniline karakteristika: 320x550x340mm; 05 Tootja: Villeroy & Boch Gustavsberg; 06 Mudel või toote tunnus: 7G50; 07 Tooteinfo: Undefined; 08 Kasutus- ja hooldusjuhend: Undefined
Description: Pisuaar; Classification: 4.10 IfcSanitaryTerminalType (sanitaartehnika) (_RKAS BIM + ARCHICAD Classification); 713 Sanitaartehnika seadmed (EHITUSKULUDE LIIGITAMINE EVS 885:2005)
SEADMED - 07 Tooteinfo: 7G500001; 01 Nimetus: Pissuaar
AC_Pset_RenovationAndPhasing - Renovation Status: New
Name | In
2 x Pisuaar | 1 KORRUS
2 x Pisuaar | 2 KORRUS

# IfcFlowTerminal: WC 22 (4)
In: 2 KORRUS
Type - ElementType: Element type WC
Type - SEADMED - 01 Nimetus: WC 22; Täpsustus: WC-pott; 02 Tähis: WC; 03 Osasüsteem: Sanitaartehnika; 04 Tehniline karakteristika: PRILL-LAUD SOFT CLOSE/QUICK RELEASE; 05 Tootja: Villeroy & Boch Gustavsberg; 06 Mudel või toote tunnus: 5G84HR01; 07 Tooteinfo: Undefined; 08 Kasutus- ja hooldusjuhend: Undefined
Description: WC pott; Classification: 4.10 IfcSanitaryTerminalType (sanitaartehnika) (_RKAS BIM + ARCHICAD Classification); 713 Sanitaartehnika seadmed (EHITUSKULUDE LIIGITAMINE EVS 885:2005)
SEADMED - 04 Tehniline karakteristika: L: 460,00 x W: 400,00 x H: 550,00 mm.; 01 Nimetus: WC-pott
AC_Pset_RenovationAndPhasing - Renovation Status: New

# IfcFlowTerminal: WC 22 (4)
In: 1 KORRUS
Type - ElementType: Element type WC-pott
Type - SEADMED - 01 Nimetus: WC 22; Täpsustus: WC-pott; 02 Tähis: WC-pott; 03 Osasüsteem: Sanitaartehnika; 04 Tehniline karakteristika: PRILL-LAUD SOFT CLOSE/QUICK RELEASE; 05 Tootja: Villeroy & Boch Gustavsberg; 06 Mudel või toote tunnus: 5G84HR01; 07 Tooteinfo: Undefined; 08 Kasutus- ja hooldusjuhend: Undefined
Description: WC pott; Classification: 4.10 IfcSanitaryTerminalType (sanitaartehnika) (_RKAS BIM + ARCHICAD Classification); 713 Sanitaartehnika seadmed (EHITUSKULUDE LIIGITAMINE EVS 885:2005)
SEADMED - 04 Tehniline karakteristika: L: 460,00 x W: 400,00 x H: 550,00 mm.; 01 Nimetus: WC-pott
AC_Pset_RenovationAndPhasing - Renovation Status: New

# IfcFlowTerminal: WC Disabled 17 (2)
Type - ElementType: Element type inva WC
Type - SEADMED - 01 Nimetus: WC Disabled 17; Täpsustus: inva WC; 02 Tähis: inva WC; 03 Osasüsteem: Sanitaartehnika; 04 Tehniline karakteristika: KAHESÜSTEEMNE LOPUTUS 2/4 L; 05 Tootja: Villeroy & Boch Gustavsberg; 07 Tooteinfo: Undefined; 08 Kasutus- ja hooldusjuhend: Undefined
Description: Valamu; Classification: 4.10 IfcSanitaryTerminalType (sanitaartehnika) (_RKAS BIM + ARCHICAD Classification); 713 Sanitaartehnika seadmed (EHITUSKULUDE LIIGITAMINE EVS 885:2005)
SEADMED - 07 Tooteinfo: GB1145500101; 01 Nimetus: inva WC
AC_Pset_RenovationAndPhasing - Renovation Status: New
Name | In
Valamu | 1 KORRUS
Valamu | 2 KORRUS

# IfcFurnishingElement: Copier 22 (4)
Type - ElementType: Element type KOOPIAMASIN
Classification: 1.10 IfcFurnitureType (mööbel) (_RKAS BIM + ARCHICAD Classification)
AC_Pset_RenovationAndPhasing - Renovation Status: Existing
Name | In
2 x FU - 011 | 1 KORRUS
2 x FU - 011 | 2 KORRUS

# IfcFurnishingElement: Cupboard 22, FU - 002
In: 2 KORRUS
Type - ElementType: Element type PUIT
Classification: 1.10 IfcFurnitureType (mööbel) (_RKAS BIM + ARCHICAD Classification)
AC_Pset_RenovationAndPhasing - Renovation Status: Existing

# IfcFurnishingElement: Dining Table Rectangle 22, FU - 017
In: 1 KORRUS
Type - ElementType: Element type FU - 017
Classification: 1.10 IfcFurnitureType (mööbel) (_RKAS BIM + ARCHICAD Classification)
AC_Pset_RenovationAndPhasing - Renovation Status: Existing

# IfcFurnishingElement: Flat Panel TV 22 (3)
Type - ElementType: Element type LCD ekraan
Classification: 1.10 IfcFurnitureType (mööbel) (_RKAS BIM + ARCHICAD Classification)
Name | In | Renovation Status
FU - 002 | 1 KORRUS | Existing
2 x FU - 002 | 2 KORRUS | New

# IfcFurnishingElement: Model Element 1, FU - 007
In: 2 KORRUS
Type - ElementType: Element type FU - 007
Classification: 1.10 IfcFurnitureType (mööbel) (_RKAS BIM + ARCHICAD Classification)
AC_Pset_RenovationAndPhasing - Renovation Status: Existing

# IfcFurnishingElement: Model Element 1, FU - 022
In: 1 KORRUS
Type - ElementType: Element type FU - 022
Classification: 1.10 IfcFurnitureType (mööbel) (_RKAS BIM + ARCHICAD Classification)
AC_Pset_RenovationAndPhasing - Renovation Status: Existing

# IfcFurnishingElement: Model Element 10, FU - 001
In: 2 KORRUS
Type - ElementType: Element type FU - 001
Classification: 1.10 IfcFurnitureType (mööbel) (_RKAS BIM + ARCHICAD Classification)
AC_Pset_RenovationAndPhasing - Renovation Status: Existing

# IfcFurnishingElement: Model Element 10, FU - 008
In: 1 KORRUS
Type - ElementType: Element type FU - 008
Classification: 1.10 IfcFurnitureType (mööbel) (_RKAS BIM + ARCHICAD Classification)
AC_Pset_RenovationAndPhasing - Renovation Status: Existing

# IfcFurnishingElement: Model Element 100, FU - 002
In: 2 KORRUS
Type - ElementType: Element type FU - 002
Classification: 1.10 IfcFurnitureType (mööbel) (_RKAS BIM + ARCHICAD Classification)
AC_Pset_RenovationAndPhasing - Renovation Status: Existing

# IfcFurnishingElement: Model Element 101, FU - 007
In: 2 KORRUS
Type - ElementType: Element type FU - 007
Classification: 1.10 IfcFurnitureType (mööbel) (_RKAS BIM + ARCHICAD Classification)
AC_Pset_RenovationAndPhasing - Renovation Status: Existing

# IfcFurnishingElement: Model Element 102, FU - 001
In: 2 KORRUS
Type - ElementType: Element type FU - 001
Classification: 1.10 IfcFurnitureType (mööbel) (_RKAS BIM + ARCHICAD Classification)
AC_Pset_RenovationAndPhasing - Renovation Status: Existing

# IfcFurnishingElement: Model Element 103, FU - 001
In: 2 KORRUS
Type - ElementType: Element type FU - 001
Classification: 1.10 IfcFurnitureType (mööbel) (_RKAS BIM + ARCHICAD Classification)
AC_Pset_RenovationAndPhasing - Renovation Status: Existing

# IfcFurnishingElement: Model Element 104, FU - 001
In: 2 KORRUS
Type - ElementType: Element type FU - 001
Classification: 1.10 IfcFurnitureType (mööbel) (_RKAS BIM + ARCHICAD Classification)
AC_Pset_RenovationAndPhasing - Renovation Status: Existing

# IfcFurnishingElement: Model Element 105 (2)
In: 2 KORRUS
Type - ElementType: Element type FU - 001
Classification: 1.10 IfcFurnitureType (mööbel) (_RKAS BIM + ARCHICAD Classification)
AC_Pset_RenovationAndPhasing - Renovation Status: Existing

# IfcFurnishingElement: Model Element 106, FU - 002
In: 2 KORRUS
Type - ElementType: Element type FU - 002
Classification: 1.10 IfcFurnitureType (mööbel) (_RKAS BIM + ARCHICAD Classification)
AC_Pset_RenovationAndPhasing - Renovation Status: Existing

# IfcFurnishingElement: Model Element 107, FU - 002
In: 2 KORRUS
Type - ElementType: Element type FU - 002
Classification: 1.10 IfcFurnitureType (mööbel) (_RKAS BIM + ARCHICAD Classification)
AC_Pset_RenovationAndPhasing - Renovation Status: Existing

# IfcFurnishingElement: Model Element 108, FU - 001
In: 2 KORRUS
Type - ElementType: Element type FU - 001
Classification: 1.10 IfcFurnitureType (mööbel) (_RKAS BIM + ARCHICAD Classification)
AC_Pset_RenovationAndPhasing - Renovation Status: Existing

# IfcFurnishingElement: Model Element 109, FU - 002
In: 2 KORRUS
Type - ElementType: Element type FU - 002
Classification: 1.10 IfcFurnitureType (mööbel) (_RKAS BIM + ARCHICAD Classification)
AC_Pset_RenovationAndPhasing - Renovation Status: Existing

# IfcFurnishingElement: Model Element 11, FU - 001
In: 2 KORRUS
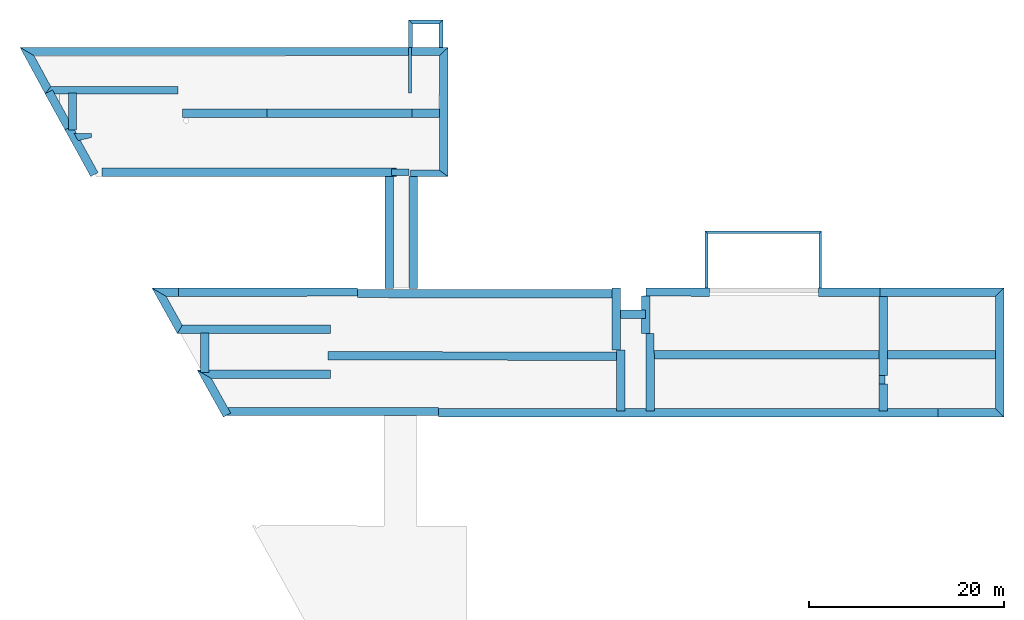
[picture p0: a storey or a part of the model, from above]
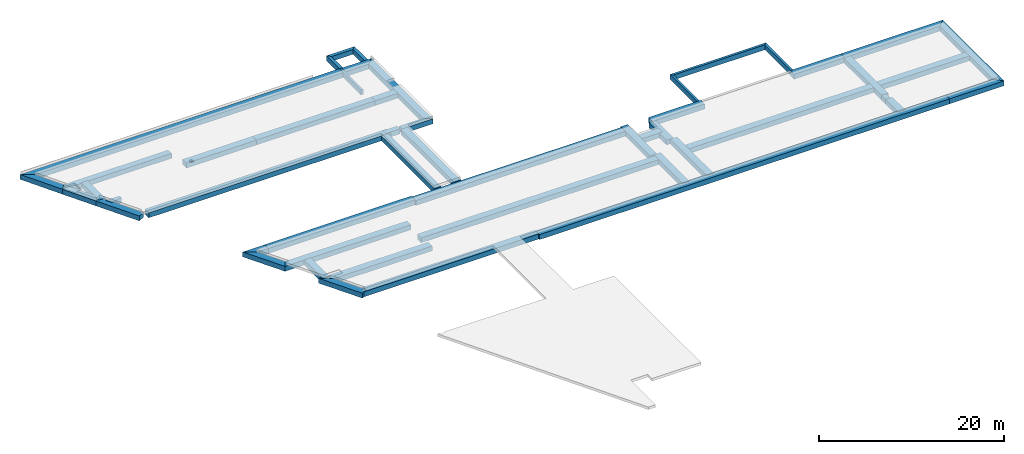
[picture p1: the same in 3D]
Properties of the parts of a building model (IFC2X3), part 10 of 14

# IfcFurnishingElement: Model Element 11, FU - 001
Type - ElementType: Element type FU - 001
Classification: 1.10 IfcFurnitureType (mööbel) (_RKAS BIM + ARCHICAD Classification)
AC_Pset_RenovationAndPhasing - Renovation Status: Existing

# IfcFurnishingElement: Model Element 11, FU - 008
In: 1 KORRUS
Type - ElementType: Element type FU - 008
Classification: 1.10 IfcFurnitureType (mööbel) (_RKAS BIM + ARCHICAD Classification)
AC_Pset_RenovationAndPhasing - Renovation Status: Existing

# IfcFurnishingElement: Model Element 110, FU - 002
In: 2 KORRUS
Type - ElementType: Element type FU - 002
Classification: 1.10 IfcFurnitureType (mööbel) (_RKAS BIM + ARCHICAD Classification)
AC_Pset_RenovationAndPhasing - Renovation Status: Existing

# IfcFurnishingElement: Model Element 111, FU - 007
In: 2 KORRUS
Type - ElementType: Element type FU - 007
Classification: 1.10 IfcFurnitureType (mööbel) (_RKAS BIM + ARCHICAD Classification)
AC_Pset_RenovationAndPhasing - Renovation Status: Existing

# IfcFurnishingElement: Model Element 112, FU - 002
In: 2 KORRUS
Type - ElementType: Element type FU - 002
Classification: 1.10 IfcFurnitureType (mööbel) (_RKAS BIM + ARCHICAD Classification)
AC_Pset_RenovationAndPhasing - Renovation Status: Existing

# IfcFurnishingElement: Model Element 113 (2)
In: 2 KORRUS
Type - ElementType: Element type FU - 001
Classification: 1.10 IfcFurnitureType (mööbel) (_RKAS BIM + ARCHICAD Classification)
AC_Pset_RenovationAndPhasing - Renovation Status: Existing

# IfcFurnishingElement: Model Element 114, FU - 007
In: 2 KORRUS
Type - ElementType: Element type FU - 007
Classification: 1.10 IfcFurnitureType (mööbel) (_RKAS BIM + ARCHICAD Classification)
AC_Pset_RenovationAndPhasing - Renovation Status: Existing

# IfcFurnishingElement: Model Element 115, FU - 002
In: 2 KORRUS
Type - ElementType: Element type FU - 002
Classification: 1.10 IfcFurnitureType (mööbel) (_RKAS BIM + ARCHICAD Classification)
AC_Pset_RenovationAndPhasing - Renovation Status: Existing

# IfcFurnishingElement: Model Element 116, FU - 007
In: 2 KORRUS
Type - ElementType: Element type FU - 007
Classification: 1.10 IfcFurnitureType (mööbel) (_RKAS BIM + ARCHICAD Classification)
AC_Pset_RenovationAndPhasing - Renovation Status: Existing

# IfcFurnishingElement: Model Element 117, FU - 001
In: 2 KORRUS
Type - ElementType: Element type FU - 001
Classification: 1.10 IfcFurnitureType (mööbel) (_RKAS BIM + ARCHICAD Classification)
AC_Pset_RenovationAndPhasing - Renovation Status: Existing

# IfcFurnishingElement: Model Element 118, FU - 001
In: 2 KORRUS
Type - ElementType: Element type FU - 001
Classification: 1.10 IfcFurnitureType (mööbel) (_RKAS BIM + ARCHICAD Classification)
AC_Pset_RenovationAndPhasing - Renovation Status: Existing

# IfcFurnishingElement: Model Element 119, FU - 002
In: 2 KORRUS
Type - ElementType: Element type FU - 002
Classification: 1.10 IfcFurnitureType (mööbel) (_RKAS BIM + ARCHICAD Classification)
AC_Pset_RenovationAndPhasing - Renovation Status: Existing

# IfcFurnishingElement: Model Element 12, FU - 002
In: 2 KORRUS
Type - ElementType: Element type FU - 002
Classification: 1.10 IfcFurnitureType (mööbel) (_RKAS BIM + ARCHICAD Classification)
AC_Pset_RenovationAndPhasing - Renovation Status: Existing

# IfcFurnishingElement: Model Element 12, FU - 009
In: 1 KORRUS
Type - ElementType: Element type FU - 009
Classification: 1.10 IfcFurnitureType (mööbel) (_RKAS BIM + ARCHICAD Classification)
AC_Pset_RenovationAndPhasing - Renovation Status: Existing

# IfcFurnishingElement: Model Element 120, FU - 007
In: 2 KORRUS
Type - ElementType: Element type FU - 007
Classification: 1.10 IfcFurnitureType (mööbel) (_RKAS BIM + ARCHICAD Classification)
AC_Pset_RenovationAndPhasing - Renovation Status: Existing

# IfcFurnishingElement: Model Element 121, FU - 001
In: 2 KORRUS
Type - ElementType: Element type FU - 001
Classification: 1.10 IfcFurnitureType (mööbel) (_RKAS BIM + ARCHICAD Classification)
AC_Pset_RenovationAndPhasing - Renovation Status: Existing

# IfcFurnishingElement: Model Element 122, FU - 001
In: 2 KORRUS
Type - ElementType: Element type FU - 001
Classification: 1.10 IfcFurnitureType (mööbel) (_RKAS BIM + ARCHICAD Classification)
AC_Pset_RenovationAndPhasing - Renovation Status: Existing

# IfcFurnishingElement: Model Element 123, FU - 002
In: 2 KORRUS
Type - ElementType: Element type FU - 002
Classification: 1.10 IfcFurnitureType (mööbel) (_RKAS BIM + ARCHICAD Classification)
AC_Pset_RenovationAndPhasing - Renovation Status: Existing

# IfcFurnishingElement: Model Element 124, FU - 007
In: 2 KORRUS
Type - ElementType: Element type FU - 007
Classification: 1.10 IfcFurnitureType (mööbel) (_RKAS BIM + ARCHICAD Classification)
AC_Pset_RenovationAndPhasing - Renovation Status: Existing

# IfcFurnishingElement: Model Element 125, FU - 021
In: 2 KORRUS
Type - ElementType: Element type FU - 021
Classification: 1.10 IfcFurnitureType (mööbel) (_RKAS BIM + ARCHICAD Classification)
AC_Pset_RenovationAndPhasing - Renovation Status: Existing

# IfcFurnishingElement: Model Element 126 (3)
In: 2 KORRUS
Type - ElementType: Element type FU - 011
Classification: 1.10 IfcFurnitureType (mööbel) (_RKAS BIM + ARCHICAD Classification)
AC_Pset_RenovationAndPhasing - Renovation Status: Existing

# IfcFurnishingElement: Model Element 127 (2)
In: 2 KORRUS
Type - ElementType: Element type FU - 002
Classification: 1.10 IfcFurnitureType (mööbel) (_RKAS BIM + ARCHICAD Classification)
AC_Pset_RenovationAndPhasing - Renovation Status: Existing

# IfcFurnishingElement: Model Element 128, FU - 007
In: 2 KORRUS
Type - ElementType: Element type FU - 007
Classification: 1.10 IfcFurnitureType (mööbel) (_RKAS BIM + ARCHICAD Classification)
AC_Pset_RenovationAndPhasing - Renovation Status: Existing

# IfcFurnishingElement: Model Element 129 (4)
In: 2 KORRUS
Type - ElementType: Element type FU - 001
Classification: 1.10 IfcFurnitureType (mööbel) (_RKAS BIM + ARCHICAD Classification)
AC_Pset_RenovationAndPhasing - Renovation Status: Existing

# IfcFurnishingElement: Model Element 13 (2)
In: 2 KORRUS
Type - ElementType: Element type FU - 001
Classification: 1.10 IfcFurnitureType (mööbel) (_RKAS BIM + ARCHICAD Classification)
AC_Pset_RenovationAndPhasing - Renovation Status: Existing

# IfcFurnishingElement: Model Element 13 (2)
In: 1 KORRUS
Type - ElementType: Element type FU - 010
Classification: 1.10 IfcFurnitureType (mööbel) (_RKAS BIM + ARCHICAD Classification)
AC_Pset_RenovationAndPhasing - Renovation Status: Existing

# IfcFurnishingElement: Model Element 131, FU - 007
In: 2 KORRUS
Type - ElementType: Element type FU - 007
Classification: 1.10 IfcFurnitureType (mööbel) (_RKAS BIM + ARCHICAD Classification)
AC_Pset_RenovationAndPhasing - Renovation Status: Existing

# IfcFurnishingElement: Model Element 133, FU - 001
In: 2 KORRUS
Type - ElementType: Element type FU - 001
Classification: 1.10 IfcFurnitureType (mööbel) (_RKAS BIM + ARCHICAD Classification)
AC_Pset_RenovationAndPhasing - Renovation Status: Existing

# IfcFurnishingElement: Model Element 134, FU - 001
In: 2 KORRUS
Type - ElementType: Element type FU - 001
Classification: 1.10 IfcFurnitureType (mööbel) (_RKAS BIM + ARCHICAD Classification)
AC_Pset_RenovationAndPhasing - Renovation Status: Existing

# IfcFurnishingElement: Model Element 136, FU - 007
In: 2 KORRUS
Type - ElementType: Element type FU - 007
Classification: 1.10 IfcFurnitureType (mööbel) (_RKAS BIM + ARCHICAD Classification)
AC_Pset_RenovationAndPhasing - Renovation Status: Existing

# IfcFurnishingElement: Model Element 137, FU - 001
In: 2 KORRUS
Type - ElementType: Element type FU - 001
Classification: 1.10 IfcFurnitureType (mööbel) (_RKAS BIM + ARCHICAD Classification)
AC_Pset_RenovationAndPhasing - Renovation Status: Existing

# IfcFurnishingElement: Model Element 138, FU - 002
In: 2 KORRUS
Type - ElementType: Element type FU - 002
Classification: 1.10 IfcFurnitureType (mööbel) (_RKAS BIM + ARCHICAD Classification)
AC_Pset_RenovationAndPhasing - Renovation Status: Existing

# IfcFurnishingElement: Model Element 139, FU - 002
In: 2 KORRUS
Type - ElementType: Element type FU - 002
Classification: 1.10 IfcFurnitureType (mööbel) (_RKAS BIM + ARCHICAD Classification)
AC_Pset_RenovationAndPhasing - Renovation Status: Existing

# IfcFurnishingElement: Model Element 14, FU - 002
In: 2 KORRUS
Type - ElementType: Element type FU - 002
Classification: 1.10 IfcFurnitureType (mööbel) (_RKAS BIM + ARCHICAD Classification)
AC_Pset_RenovationAndPhasing - Renovation Status: Existing

# IfcFurnishingElement: Model Element 14, FU - 007
In: 1 KORRUS
Type - ElementType: Element type FU - 007
Classification: 1.10 IfcFurnitureType (mööbel) (_RKAS BIM + ARCHICAD Classification)
AC_Pset_RenovationAndPhasing - Renovation Status: Existing

# IfcFurnishingElement: Model Element 140, FU - 019
In: 2 KORRUS
Type - ElementType: Element type FU - 019
Classification: 1.10 IfcFurnitureType (mööbel) (_RKAS BIM + ARCHICAD Classification)
AC_Pset_RenovationAndPhasing - Renovation Status: Existing

# IfcFurnishingElement: Model Element 141 (3)
In: 2 KORRUS
Type - ElementType: Element type FU - 002
Classification: 1.10 IfcFurnitureType (mööbel) (_RKAS BIM + ARCHICAD Classification)
AC_Pset_RenovationAndPhasing - Renovation Status: Existing

# IfcFurnishingElement: Model Element 142, FU - 001
In: 2 KORRUS
Type - ElementType: Element type FU - 001
Classification: 1.10 IfcFurnitureType (mööbel) (_RKAS BIM + ARCHICAD Classification)
AC_Pset_RenovationAndPhasing - Renovation Status: Existing

# IfcFurnishingElement: Model Element 143, FU - 002
In: 2 KORRUS
Type - ElementType: Element type FU - 002
Classification: 1.10 IfcFurnitureType (mööbel) (_RKAS BIM + ARCHICAD Classification)
AC_Pset_RenovationAndPhasing - Renovation Status: Existing

# IfcFurnishingElement: Model Element 144, FU - 018
In: 2 KORRUS
Type - ElementType: Element type FU - 018
Classification: 1.10 IfcFurnitureType (mööbel) (_RKAS BIM + ARCHICAD Classification)
AC_Pset_RenovationAndPhasing - Renovation Status: Existing

# IfcFurnishingElement: Model Element 145, FU - 019
In: 2 KORRUS
Type - ElementType: Element type FU - 019
Classification: 1.10 IfcFurnitureType (mööbel) (_RKAS BIM + ARCHICAD Classification)
AC_Pset_RenovationAndPhasing - Renovation Status: Existing

# IfcFurnishingElement: Model Element 146, FU - 002
In: 2 KORRUS
Type - ElementType: Element type FU - 002
Classification: 1.10 IfcFurnitureType (mööbel) (_RKAS BIM + ARCHICAD Classification)
AC_Pset_RenovationAndPhasing - Renovation Status: Existing

# IfcFurnishingElement: Model Element 147, FU - 002
In: 2 KORRUS
Type - ElementType: Element type FU - 002
Classification: 1.10 IfcFurnitureType (mööbel) (_RKAS BIM + ARCHICAD Classification)
AC_Pset_RenovationAndPhasing - Renovation Status: Existing

# IfcFurnishingElement: Model Element 148, FU - 001
In: 2 KORRUS
Type - ElementType: Element type FU - 001
Classification: 1.10 IfcFurnitureType (mööbel) (_RKAS BIM + ARCHICAD Classification)
AC_Pset_RenovationAndPhasing - Renovation Status: Existing

# IfcFurnishingElement: Model Element 149, FU - 001
In: 2 KORRUS
Type - ElementType: Element type FU - 001
Classification: 1.10 IfcFurnitureType (mööbel) (_RKAS BIM + ARCHICAD Classification)
AC_Pset_RenovationAndPhasing - Renovation Status: Existing

# IfcFurnishingElement: Model Element 15, FU - 001
In: 2 KORRUS
Type - ElementType: Element type FU - 001
Classification: 1.10 IfcFurnitureType (mööbel) (_RKAS BIM + ARCHICAD Classification)
AC_Pset_RenovationAndPhasing - Renovation Status: Existing

# IfcFurnishingElement: Model Element 150 (3)
In: 2 KORRUS
Type - ElementType: Element type FU - 001
Classification: 1.10 IfcFurnitureType (mööbel) (_RKAS BIM + ARCHICAD Classification)
AC_Pset_RenovationAndPhasing - Renovation Status: Existing

# IfcFurnishingElement: Model Element 151, FU - 001
In: 2 KORRUS
Type - ElementType: Element type FU - 001
Classification: 1.10 IfcFurnitureType (mööbel) (_RKAS BIM + ARCHICAD Classification)
AC_Pset_RenovationAndPhasing - Renovation Status: Existing

# IfcFurnishingElement: Model Element 152, FU - 002
In: 2 KORRUS
Type - ElementType: Element type FU - 002
Classification: 1.10 IfcFurnitureType (mööbel) (_RKAS BIM + ARCHICAD Classification)
AC_Pset_RenovationAndPhasing - Renovation Status: Existing

# IfcFurnishingElement: Model Element 153, FU - 002
In: 2 KORRUS
Type - ElementType: Element type FU - 002
Classification: 1.10 IfcFurnitureType (mööbel) (_RKAS BIM + ARCHICAD Classification)
AC_Pset_RenovationAndPhasing - Renovation Status: Existing

# IfcFurnishingElement: Model Element 154, FU - 001
In: 2 KORRUS
Type - ElementType: Element type FU - 001
Classification: 1.10 IfcFurnitureType (mööbel) (_RKAS BIM + ARCHICAD Classification)
AC_Pset_RenovationAndPhasing - Renovation Status: Existing

# IfcFurnishingElement: Model Element 155, FU - 002
In: 2 KORRUS
Type - ElementType: Element type FU - 002
Classification: 1.10 IfcFurnitureType (mööbel) (_RKAS BIM + ARCHICAD Classification)
AC_Pset_RenovationAndPhasing - Renovation Status: Existing

# IfcFurnishingElement: Model Element 156 (2)
In: 2 KORRUS
Type - ElementType: Element type FU - 001
Classification: 1.10 IfcFurnitureType (mööbel) (_RKAS BIM + ARCHICAD Classification)
AC_Pset_RenovationAndPhasing - Renovation Status: Existing

# IfcFurnishingElement: Model Element 157, FU - 001
In: 2 KORRUS
Type - ElementType: Element type FU - 001
Classification: 1.10 IfcFurnitureType (mööbel) (_RKAS BIM + ARCHICAD Classification)
AC_Pset_RenovationAndPhasing - Renovation Status: Existing

# IfcFurnishingElement: Model Element 158, FU - 002
In: 2 KORRUS
Type - ElementType: Element type FU - 002
Classification: 1.10 IfcFurnitureType (mööbel) (_RKAS BIM + ARCHICAD Classification)
AC_Pset_RenovationAndPhasing - Renovation Status: Existing

# IfcFurnishingElement: Model Element 159, FU - 002
In: 2 KORRUS
Type - ElementType: Element type FU - 002
Classification: 1.10 IfcFurnitureType (mööbel) (_RKAS BIM + ARCHICAD Classification)
AC_Pset_RenovationAndPhasing - Renovation Status: Existing

# IfcFurnishingElement: Model Element 16 (3)
In: 2 KORRUS
Type - ElementType: Element type FU - 001
Classification: 1.10 IfcFurnitureType (mööbel) (_RKAS BIM + ARCHICAD Classification)
AC_Pset_RenovationAndPhasing - Renovation Status: Existing

# IfcFurnishingElement: Model Element 160, FU - 007
In: 2 KORRUS
Type - ElementType: Element type FU - 007
Classification: 1.10 IfcFurnitureType (mööbel) (_RKAS BIM + ARCHICAD Classification)
AC_Pset_RenovationAndPhasing - Renovation Status: Existing

# IfcFurnishingElement: Model Element 161, FU - 002
In: 2 KORRUS
Type - ElementType: Element type FU - 002
Classification: 1.10 IfcFurnitureType (mööbel) (_RKAS BIM + ARCHICAD Classification)
AC_Pset_RenovationAndPhasing - Renovation Status: Existing

# IfcFurnishingElement: Model Element 162, FU - 002
In: 2 KORRUS
Type - ElementType: Element type FU - 002
Classification: 1.10 IfcFurnitureType (mööbel) (_RKAS BIM + ARCHICAD Classification)
AC_Pset_RenovationAndPhasing - Renovation Status: Existing

# IfcFurnishingElement: Model Element 163, FU - 002
In: 2 KORRUS
Type - ElementType: Element type FU - 002
Classification: 1.10 IfcFurnitureType (mööbel) (_RKAS BIM + ARCHICAD Classification)
AC_Pset_RenovationAndPhasing - Renovation Status: Existing

# IfcFurnishingElement: Model Element 164, FU - 001
In: 2 KORRUS
Type - ElementType: Element type FU - 001
Classification: 1.10 IfcFurnitureType (mööbel) (_RKAS BIM + ARCHICAD Classification)
AC_Pset_RenovationAndPhasing - Renovation Status: Existing

# IfcFurnishingElement: Model Element 165, FU - 001
In: 2 KORRUS
Type - ElementType: Element type FU - 001
Classification: 1.10 IfcFurnitureType (mööbel) (_RKAS BIM + ARCHICAD Classification)
AC_Pset_RenovationAndPhasing - Renovation Status: Existing

# IfcFurnishingElement: Model Element 166, FU - 001
In: 2 KORRUS
Type - ElementType: Element type FU - 001
Classification: 1.10 IfcFurnitureType (mööbel) (_RKAS BIM + ARCHICAD Classification)
AC_Pset_RenovationAndPhasing - Renovation Status: Existing

# IfcFurnishingElement: Model Element 167, FU - 002
In: 2 KORRUS
Type - ElementType: Element type FU - 002
Classification: 1.10 IfcFurnitureType (mööbel) (_RKAS BIM + ARCHICAD Classification)
AC_Pset_RenovationAndPhasing - Renovation Status: Existing

# IfcFurnishingElement: Model Element 168, FU - 007
In: 2 KORRUS
Type - ElementType: Element type FU - 007
Classification: 1.10 IfcFurnitureType (mööbel) (_RKAS BIM + ARCHICAD Classification)
AC_Pset_RenovationAndPhasing - Renovation Status: Existing

# IfcFurnishingElement: Model Element 169, FU - 002
In: 2 KORRUS
Type - ElementType: Element type FU - 002
Classification: 1.10 IfcFurnitureType (mööbel) (_RKAS BIM + ARCHICAD Classification)
AC_Pset_RenovationAndPhasing - Renovation Status: Existing

# IfcFurnishingElement: Model Element 17, FU - 002
In: 2 KORRUS
Type - ElementType: Element type FU - 002
Classification: 1.10 IfcFurnitureType (mööbel) (_RKAS BIM + ARCHICAD Classification)
AC_Pset_RenovationAndPhasing - Renovation Status: Existing

# IfcFurnishingElement: Model Element 17, FU - 014
In: 1 KORRUS
Type - ElementType: Element type FU - 014
Classification: 1.10 IfcFurnitureType (mööbel) (_RKAS BIM + ARCHICAD Classification)
AC_Pset_RenovationAndPhasing - Renovation Status: Existing

# IfcFurnishingElement: Model Element 170, FU - 002
In: 2 KORRUS
Type - ElementType: Element type FU - 002
Classification: 1.10 IfcFurnitureType (mööbel) (_RKAS BIM + ARCHICAD Classification)
AC_Pset_RenovationAndPhasing - Renovation Status: Existing

# IfcFurnishingElement: Model Element 171, FU - 001
In: 2 KORRUS
Type - ElementType: Element type FU - 001
Classification: 1.10 IfcFurnitureType (mööbel) (_RKAS BIM + ARCHICAD Classification)
AC_Pset_RenovationAndPhasing - Renovation Status: Existing

# IfcFurnishingElement: Model Element 172, FU - 002
In: 2 KORRUS
Type - ElementType: Element type FU - 002
Classification: 1.10 IfcFurnitureType (mööbel) (_RKAS BIM + ARCHICAD Classification)
AC_Pset_RenovationAndPhasing - Renovation Status: Existing

# IfcFurnishingElement: Model Element 173, FU - 001
In: 2 KORRUS
Type - ElementType: Element type FU - 001
Classification: 1.10 IfcFurnitureType (mööbel) (_RKAS BIM + ARCHICAD Classification)
AC_Pset_RenovationAndPhasing - Renovation Status: Existing

# IfcFurnishingElement: Model Element 18, FU - 002
In: 2 KORRUS
Type - ElementType: Element type FU - 002
Classification: 1.10 IfcFurnitureType (mööbel) (_RKAS BIM + ARCHICAD Classification)
AC_Pset_RenovationAndPhasing - Renovation Status: Existing

# IfcFurnishingElement: Model Element 18, FU - 016
In: 1 KORRUS
Type - ElementType: Element type FU - 016
Classification: 1.10 IfcFurnitureType (mööbel) (_RKAS BIM + ARCHICAD Classification)
AC_Pset_RenovationAndPhasing - Renovation Status: Existing

# IfcFurnishingElement: Model Element 19, FU - 001
In: 2 KORRUS
Type - ElementType: Element type FU - 001
Classification: 1.10 IfcFurnitureType (mööbel) (_RKAS BIM + ARCHICAD Classification)
AC_Pset_RenovationAndPhasing - Renovation Status: Existing

# IfcFurnishingElement: Model Element 19 (2)
In: 1 KORRUS
Type - ElementType: Element type FU - 017
Classification: 1.10 IfcFurnitureType (mööbel) (_RKAS BIM + ARCHICAD Classification)
AC_Pset_RenovationAndPhasing - Renovation Status: Existing

# IfcFurnishingElement: Model Element 2 (3)
In: 1 KORRUS
Type - ElementType: Element type FU - 003
Classification: 1.10 IfcFurnitureType (mööbel) (_RKAS BIM + ARCHICAD Classification)
AC_Pset_RenovationAndPhasing - Renovation Status: Existing

# IfcFurnishingElement: Model Element 2, FU - 010
In: 2 KORRUS
Type - ElementType: Element type FU - 010
Classification: 1.10 IfcFurnitureType (mööbel) (_RKAS BIM + ARCHICAD Classification)
AC_Pset_RenovationAndPhasing - Renovation Status: Existing

# IfcFurnishingElement: Model Element 2 (5)
In: 2 KORRUS
Type - ElementType: Element type FU - 011
Classification: 1.10 IfcFurnitureType (mööbel) (_RKAS BIM + ARCHICAD Classification)
AC_Pset_RenovationAndPhasing - Renovation Status: Existing

# IfcFurnishingElement: Model Element 2 (3)
In: 2 KORRUS
Type - ElementType: Element type FU - 012
Classification: 1.10 IfcFurnitureType (mööbel) (_RKAS BIM + ARCHICAD Classification)
AC_Pset_RenovationAndPhasing - Renovation Status: Existing

# IfcFurnishingElement: Model Element 21, FU - 002
In: 2 KORRUS
Type - ElementType: Element type FU - 002
Classification: 1.10 IfcFurnitureType (mööbel) (_RKAS BIM + ARCHICAD Classification)
AC_Pset_RenovationAndPhasing - Renovation Status: Existing

# IfcFurnishingElement: Model Element 22 (2)
In: 2 KORRUS
Type - ElementType: Element type FU - 005
Classification: 1.10 IfcFurnitureType (mööbel) (_RKAS BIM + ARCHICAD Classification)
AC_Pset_RenovationAndPhasing - Renovation Status: Existing
Name
FU - 005 | Material: GENEERILINE - KEKKKOND (1)
FU - 005

# IfcFurnishingElement: Model Element 22, FU - 013
In: 1 KORRUS
Type - ElementType: Element type FU - 013
Classification: 1.10 IfcFurnitureType (mööbel) (_RKAS BIM + ARCHICAD Classification)
AC_Pset_RenovationAndPhasing - Renovation Status: Existing

# IfcFurnishingElement: Model Element 23 (2)
In: 2 KORRUS
Type - ElementType: Element type FU - 001
Classification: 1.10 IfcFurnitureType (mööbel) (_RKAS BIM + ARCHICAD Classification)
AC_Pset_RenovationAndPhasing - Renovation Status: Existing

# IfcFurnishingElement: Model Element 23 (2)
In: 1 KORRUS
Type - ElementType: Element type FU - 005
Classification: 713 Sanitaartehnika seadmed (EHITUSKULUDE LIIGITAMINE EVS 885:2005); 1.10 IfcFurnitureType (mööbel) (_RKAS BIM + ARCHICAD Classification)
AC_Pset_RenovationAndPhasing - Renovation Status: Existing

# IfcFurnishingElement: Model Element 24, FU - 002
In: 2 KORRUS
Type - ElementType: Element type FU - 002
Classification: 1.10 IfcFurnitureType (mööbel) (_RKAS BIM + ARCHICAD Classification)
AC_Pset_RenovationAndPhasing - Renovation Status: Existing

# IfcFurnishingElement: Model Element 24 (3)
In: 1 KORRUS
Type - ElementType: Element type FU - 003
Classification: 1.10 IfcFurnitureType (mööbel) (_RKAS BIM + ARCHICAD Classification)
AC_Pset_RenovationAndPhasing - Renovation Status: Existing

# IfcFurnishingElement: Model Element 25, FU - 001
In: 2 KORRUS
Type - ElementType: Element type FU - 001
Classification: 1.10 IfcFurnitureType (mööbel) (_RKAS BIM + ARCHICAD Classification)
AC_Pset_RenovationAndPhasing - Renovation Status: Existing

# IfcFurnishingElement: Model Element 26, FU - 001
In: 2 KORRUS
Type - ElementType: Element type FU - 001
Classification: 1.10 IfcFurnitureType (mööbel) (_RKAS BIM + ARCHICAD Classification)
AC_Pset_RenovationAndPhasing - Renovation Status: Existing

# IfcFurnishingElement: Model Element 26, FU - 003
In: 1 KORRUS
Type - ElementType: Element type FU - 003
Classification: 1.10 IfcFurnitureType (mööbel) (_RKAS BIM + ARCHICAD Classification)
AC_Pset_RenovationAndPhasing - Renovation Status: Existing

# IfcFurnishingElement: Model Element 27, FU - 002
In: 2 KORRUS
Type - ElementType: Element type FU - 002
Classification: 1.10 IfcFurnitureType (mööbel) (_RKAS BIM + ARCHICAD Classification)
AC_Pset_RenovationAndPhasing - Renovation Status: Existing

# IfcFurnishingElement: Model Element 27 (3)
In: 1 KORRUS
Type - ElementType: Element type FU - 006
Classification: 1.10 IfcFurnitureType (mööbel) (_RKAS BIM + ARCHICAD Classification)
AC_Pset_RenovationAndPhasing - Renovation Status: Existing

# IfcFurnishingElement: Model Element 28, FU - 006
In: 1 KORRUS
Type - ElementType: Element type FU - 006
Classification: 1.10 IfcFurnitureType (mööbel) (_RKAS BIM + ARCHICAD Classification)
AC_Pset_RenovationAndPhasing - Renovation Status: Existing

# IfcFurnishingElement: Model Element 29, FU - 002
In: 2 KORRUS
Type - ElementType: Element type FU - 002
Classification: 1.10 IfcFurnitureType (mööbel) (_RKAS BIM + ARCHICAD Classification)
AC_Pset_RenovationAndPhasing - Renovation Status: Existing

# IfcFurnishingElement: Model Element 29, FU - 017
In: 1 KORRUS
Type - ElementType: Element type FU - 017
Classification: 1.10 IfcFurnitureType (mööbel) (_RKAS BIM + ARCHICAD Classification)
AC_Pset_RenovationAndPhasing - Renovation Status: Existing

# IfcFurnishingElement: Model Element 30 (3)
In: 2 KORRUS
Type - ElementType: Element type FU - 001
Classification: 1.10 IfcFurnitureType (mööbel) (_RKAS BIM + ARCHICAD Classification)
AC_Pset_RenovationAndPhasing - Renovation Status: Existing

# IfcFurnishingElement: Model Element 30 (6)
Type - ElementType: Element type FU - 020
Classification: 1.10 IfcFurnitureType (mööbel) (_RKAS BIM + ARCHICAD Classification)
AC_Pset_RenovationAndPhasing - Renovation Status: Existing
Name | In
5 x FU - 020 | 1 KORRUS
FU - 020 | 2 KORRUS

# IfcFurnishingElement: Model Element 31, FU - 001
In: 2 KORRUS
Type - ElementType: Element type FU - 001
Classification: 1.10 IfcFurnitureType (mööbel) (_RKAS BIM + ARCHICAD Classification)
AC_Pset_RenovationAndPhasing - Renovation Status: Existing

# IfcFurnishingElement: Model Element 31, FU - 022
In: 1 KORRUS
Type - ElementType: Element type FU - 022
Classification: 1.10 IfcFurnitureType (mööbel) (_RKAS BIM + ARCHICAD Classification)
AC_Pset_RenovationAndPhasing - Renovation Status: Existing

# IfcFurnishingElement: Model Element 32, FU - 002
In: 2 KORRUS
Type - ElementType: Element type FU - 002
Classification: 1.10 IfcFurnitureType (mööbel) (_RKAS BIM + ARCHICAD Classification)
AC_Pset_RenovationAndPhasing - Renovation Status: Existing

# IfcFurnishingElement: Model Element 32, FU - 003
In: 1 KORRUS
Type - ElementType: Element type FU - 003
Classification: 1.10 IfcFurnitureType (mööbel) (_RKAS BIM + ARCHICAD Classification)
AC_Pset_RenovationAndPhasing - Renovation Status: Existing

# IfcFurnishingElement: Model Element 33, FU - 002
In: 2 KORRUS
Type - ElementType: Element type FU - 002
Classification: 1.10 IfcFurnitureType (mööbel) (_RKAS BIM + ARCHICAD Classification)
AC_Pset_RenovationAndPhasing - Renovation Status: Existing

# IfcFurnishingElement: Model Element 33, FU - 022
In: 1 KORRUS
Type - ElementType: Element type FU - 022
Classification: 1.10 IfcFurnitureType (mööbel) (_RKAS BIM + ARCHICAD Classification)
AC_Pset_RenovationAndPhasing - Renovation Status: Existing

# IfcFurnishingElement: Model Element 34 (2)
In: 2 KORRUS
Type - ElementType: Element type FU - 001
Classification: 1.10 IfcFurnitureType (mööbel) (_RKAS BIM + ARCHICAD Classification)
AC_Pset_RenovationAndPhasing - Renovation Status: Existing

# IfcFurnishingElement: Model Element 34, FU - 022
In: 1 KORRUS
Type - ElementType: Element type FU - 022
Classification: 1.10 IfcFurnitureType (mööbel) (_RKAS BIM + ARCHICAD Classification)
AC_Pset_RenovationAndPhasing - Renovation Status: Existing

# IfcFurnishingElement: Model Element 35 (5)
In: 2 KORRUS
Type - ElementType: Element type FU - 001
Classification: 1.10 IfcFurnitureType (mööbel) (_RKAS BIM + ARCHICAD Classification)
AC_Pset_RenovationAndPhasing - Renovation Status: Existing

# IfcFurnishingElement: Model Element 35, FU - 022
In: 1 KORRUS
Type - ElementType: Element type FU - 022
Classification: 1.10 IfcFurnitureType (mööbel) (_RKAS BIM + ARCHICAD Classification)
AC_Pset_RenovationAndPhasing - Renovation Status: Existing

# IfcFurnishingElement: Model Element 36, FU - 002
In: 2 KORRUS
Type - ElementType: Element type FU - 002
Classification: 1.10 IfcFurnitureType (mööbel) (_RKAS BIM + ARCHICAD Classification)
AC_Pset_RenovationAndPhasing - Renovation Status: Existing

# IfcFurnishingElement: Model Element 36, FU - 003
In: 1 KORRUS
Type - ElementType: Element type FU - 003
Classification: 1.10 IfcFurnitureType (mööbel) (_RKAS BIM + ARCHICAD Classification)
AC_Pset_RenovationAndPhasing - Renovation Status: Existing

# IfcFurnishingElement: Model Element 37, FU - 001
In: 2 KORRUS
Type - ElementType: Element type FU - 001
Classification: 1.10 IfcFurnitureType (mööbel) (_RKAS BIM + ARCHICAD Classification)
AC_Pset_RenovationAndPhasing - Renovation Status: Existing

# IfcFurnishingElement: Model Element 37, FU - 003
In: 1 KORRUS
Type - ElementType: Element type FU - 003
Classification: 1.10 IfcFurnitureType (mööbel) (_RKAS BIM + ARCHICAD Classification)
AC_Pset_RenovationAndPhasing - Renovation Status: Existing

# IfcFurnishingElement: Model Element 38, FU - 002
In: 2 KORRUS
Type - ElementType: Element type FU - 002
Classification: 1.10 IfcFurnitureType (mööbel) (_RKAS BIM + ARCHICAD Classification)
AC_Pset_RenovationAndPhasing - Renovation Status: Existing

# IfcFurnishingElement: Model Element 38 (2)
In: 1 KORRUS
Type - ElementType: Element type FU - 003
Classification: 1.10 IfcFurnitureType (mööbel) (_RKAS BIM + ARCHICAD Classification)
AC_Pset_RenovationAndPhasing - Renovation Status: Existing

# IfcFurnishingElement: Model Element 39, FU - 002
In: 2 KORRUS
Type - ElementType: Element type FU - 002
Classification: 1.10 IfcFurnitureType (mööbel) (_RKAS BIM + ARCHICAD Classification)
AC_Pset_RenovationAndPhasing - Renovation Status: Existing

# IfcFurnishingElement: Model Element 39, FU - 003
In: 1 KORRUS
Type - ElementType: Element type FU - 003
Classification: 1.10 IfcFurnitureType (mööbel) (_RKAS BIM + ARCHICAD Classification)
AC_Pset_RenovationAndPhasing - Renovation Status: Existing

# IfcFurnishingElement: Model Element 4, FU - 003
In: 1 KORRUS
Type - ElementType: Element type FU - 003
Classification: 1.10 IfcFurnitureType (mööbel) (_RKAS BIM + ARCHICAD Classification)
AC_Pset_RenovationAndPhasing - Renovation Status: Existing

# IfcFurnishingElement: Model Element 4, FU - 013
In: 2 KORRUS
Type - ElementType: Element type FU - 013
Classification: 1.10 IfcFurnitureType (mööbel) (_RKAS BIM + ARCHICAD Classification)
AC_Pset_RenovationAndPhasing - Renovation Status: Existing

# IfcFurnishingElement: Model Element 40, FU - 001
In: 2 KORRUS
Type - ElementType: Element type FU - 001
Classification: 1.10 IfcFurnitureType (mööbel) (_RKAS BIM + ARCHICAD Classification)
AC_Pset_RenovationAndPhasing - Renovation Status: Existing

# IfcFurnishingElement: Model Element 40, FU - 003
In: 1 KORRUS
Type - ElementType: Element type FU - 003
Classification: 1.10 IfcFurnitureType (mööbel) (_RKAS BIM + ARCHICAD Classification)
AC_Pset_RenovationAndPhasing - Renovation Status: Existing

# IfcFurnishingElement: Model Element 41 (2)
In: 2 KORRUS
Type - ElementType: Element type FU - 001
Classification: 1.10 IfcFurnitureType (mööbel) (_RKAS BIM + ARCHICAD Classification)
AC_Pset_RenovationAndPhasing - Renovation Status: Existing

# IfcFurnishingElement: Model Element 41 (5)
In: 1 KORRUS
Type - ElementType: Element type FU - 003
Classification: 1.10 IfcFurnitureType (mööbel) (_RKAS BIM + ARCHICAD Classification)
AC_Pset_RenovationAndPhasing - Renovation Status: Existing

# IfcFurnishingElement: Model Element 42, FU - 001
In: 2 KORRUS
Type - ElementType: Element type FU - 001
Classification: 1.10 IfcFurnitureType (mööbel) (_RKAS BIM + ARCHICAD Classification)
AC_Pset_RenovationAndPhasing - Renovation Status: Existing

# IfcFurnishingElement: Model Element 43, FU - 001
In: 2 KORRUS
Type - ElementType: Element type FU - 001
Classification: 1.10 IfcFurnitureType (mööbel) (_RKAS BIM + ARCHICAD Classification)
AC_Pset_RenovationAndPhasing - Renovation Status: Existing

# IfcFurnishingElement: Model Element 44, FU - 002
In: 2 KORRUS
Type - ElementType: Element type FU - 002
Classification: 1.10 IfcFurnitureType (mööbel) (_RKAS BIM + ARCHICAD Classification)
AC_Pset_RenovationAndPhasing - Renovation Status: Existing

# IfcFurnishingElement: Model Element 45 (3)
In: 2 KORRUS
Type - ElementType: Element type FU - 002
Classification: 1.10 IfcFurnitureType (mööbel) (_RKAS BIM + ARCHICAD Classification)
AC_Pset_RenovationAndPhasing - Renovation Status: Existing

# IfcFurnishingElement: Model Element 47, FU - 002
In: 2 KORRUS
Type - ElementType: Element type FU - 002
Classification: 1.10 IfcFurnitureType (mööbel) (_RKAS BIM + ARCHICAD Classification)
AC_Pset_RenovationAndPhasing - Renovation Status: Existing

# IfcFurnishingElement: Model Element 47, FU - 003
In: 1 KORRUS
Type - ElementType: Element type FU - 003
Classification: 1.10 IfcFurnitureType (mööbel) (_RKAS BIM + ARCHICAD Classification)
AC_Pset_RenovationAndPhasing - Renovation Status: Existing

# IfcFurnishingElement: Model Element 48, FU - 001
In: 2 KORRUS
Type - ElementType: Element type FU - 001
Classification: 1.10 IfcFurnitureType (mööbel) (_RKAS BIM + ARCHICAD Classification)
AC_Pset_RenovationAndPhasing - Renovation Status: Existing

# IfcFurnishingElement: Model Element 48, FU - 022
In: 1 KORRUS
Type - ElementType: Element type FU - 022
Classification: 1.10 IfcFurnitureType (mööbel) (_RKAS BIM + ARCHICAD Classification)
AC_Pset_RenovationAndPhasing - Renovation Status: Existing

# IfcFurnishingElement: Model Element 49, FU - 002
In: 2 KORRUS
Type - ElementType: Element type FU - 002
Classification: 1.10 IfcFurnitureType (mööbel) (_RKAS BIM + ARCHICAD Classification)
AC_Pset_RenovationAndPhasing - Renovation Status: Existing

# IfcFurnishingElement: Model Element 49, FU - 013
In: 1 KORRUS
Type - ElementType: Element type FU - 013
Classification: 1.10 IfcFurnitureType (mööbel) (_RKAS BIM + ARCHICAD Classification)
AC_Pset_RenovationAndPhasing - Renovation Status: Existing

# IfcFurnishingElement: Model Element 5, FU - 002
In: 2 KORRUS
Type - ElementType: Element type FU - 002
Classification: 1.10 IfcFurnitureType (mööbel) (_RKAS BIM + ARCHICAD Classification)
AC_Pset_RenovationAndPhasing - Renovation Status: Existing

# IfcFurnishingElement: Model Element 5, FU - 005
In: 1 KORRUS
Type - ElementType: Element type FU - 005
Classification: 713 Sanitaartehnika seadmed (EHITUSKULUDE LIIGITAMINE EVS 885:2005); 1.10 IfcFurnitureType (mööbel) (_RKAS BIM + ARCHICAD Classification)
AC_Pset_RenovationAndPhasing - Renovation Status: Existing

# IfcFurnishingElement: Model Element 5, FU - 013
In: 2 KORRUS
Type - ElementType: Element type FU - 013
Classification: 1.10 IfcFurnitureType (mööbel) (_RKAS BIM + ARCHICAD Classification)
AC_Pset_RenovationAndPhasing - Renovation Status: Existing

# IfcFurnishingElement: Model Element 50, FU - 002
In: 2 KORRUS
Type - ElementType: Element type FU - 002
Classification: 1.10 IfcFurnitureType (mööbel) (_RKAS BIM + ARCHICAD Classification)
AC_Pset_RenovationAndPhasing - Renovation Status: Existing

# IfcFurnishingElement: Model Element 50, FU - 013
In: 1 KORRUS
Type - ElementType: Element type FU - 013
Classification: 1.10 IfcFurnitureType (mööbel) (_RKAS BIM + ARCHICAD Classification)
AC_Pset_RenovationAndPhasing - Renovation Status: Existing

# IfcFurnishingElement: Model Element 51, FU - 002
In: 2 KORRUS
Type - ElementType: Element type FU - 002
Classification: 1.10 IfcFurnitureType (mööbel) (_RKAS BIM + ARCHICAD Classification)
AC_Pset_RenovationAndPhasing - Renovation Status: Existing

# IfcFurnishingElement: Model Element 51, FU - 013
In: 1 KORRUS
Type - ElementType: Element type FU - 013
Classification: 1.10 IfcFurnitureType (mööbel) (_RKAS BIM + ARCHICAD Classification)
AC_Pset_RenovationAndPhasing - Renovation Status: Existing

# IfcFurnishingElement: Model Element 52 (6)
In: 2 KORRUS
Type - ElementType: Element type FU - 001
Classification: 1.10 IfcFurnitureType (mööbel) (_RKAS BIM + ARCHICAD Classification)
AC_Pset_RenovationAndPhasing - Renovation Status: Existing

# IfcFurnishingElement: Model Element 52, FU - 003
In: 1 KORRUS
Type - ElementType: Element type FU - 003
Classification: 1.10 IfcFurnitureType (mööbel) (_RKAS BIM + ARCHICAD Classification)
AC_Pset_RenovationAndPhasing - Renovation Status: Existing

# IfcFurnishingElement: Model Element 53, FU - 001
In: 2 KORRUS
Type - ElementType: Element type FU - 001
Classification: 1.10 IfcFurnitureType (mööbel) (_RKAS BIM + ARCHICAD Classification)
AC_Pset_RenovationAndPhasing - Renovation Status: Existing

# IfcFurnishingElement: Model Element 53, FU - 003
In: 1 KORRUS
Type - ElementType: Element type FU - 003
Classification: 1.10 IfcFurnitureType (mööbel) (_RKAS BIM + ARCHICAD Classification)
AC_Pset_RenovationAndPhasing - Renovation Status: Existing

# IfcFurnishingElement: Model Element 54 (2)
In: 2 KORRUS
Type - ElementType: Element type FU - 007
Classification: 1.10 IfcFurnitureType (mööbel) (_RKAS BIM + ARCHICAD Classification)
AC_Pset_RenovationAndPhasing - Renovation Status: Existing

# IfcFurnishingElement: Model Element 55, FU - 002
In: 2 KORRUS
Type - ElementType: Element type FU - 002
Classification: 1.10 IfcFurnitureType (mööbel) (_RKAS BIM + ARCHICAD Classification)
AC_Pset_RenovationAndPhasing - Renovation Status: Existing

# IfcFurnishingElement: Model Element 56, FU - 002
In: 2 KORRUS
Type - ElementType: Element type FU - 002
Classification: 1.10 IfcFurnitureType (mööbel) (_RKAS BIM + ARCHICAD Classification)
AC_Pset_RenovationAndPhasing - Renovation Status: Existing

# IfcFurnishingElement: Model Element 57, FU - 016
In: 2 KORRUS
Type - ElementType: Element type FU - 016
Classification: 1.10 IfcFurnitureType (mööbel) (_RKAS BIM + ARCHICAD Classification)
AC_Pset_RenovationAndPhasing - Renovation Status: Existing

# IfcFurnishingElement: Model Element 57 (2)
In: 2 KORRUS
Type - ElementType: Element type FU - 022
Classification: 1.10 IfcFurnitureType (mööbel) (_RKAS BIM + ARCHICAD Classification)
AC_Pset_RenovationAndPhasing - Renovation Status: Existing

# IfcFurnishingElement: Model Element 58, FU - 017
In: 2 KORRUS
Type - ElementType: Element type FU - 017
Classification: 1.10 IfcFurnitureType (mööbel) (_RKAS BIM + ARCHICAD Classification)
AC_Pset_RenovationAndPhasing - Renovation Status: Existing

# IfcFurnishingElement: Model Element 59 (3)
In: 2 KORRUS
Type - ElementType: Element type FU - 001
Classification: 1.10 IfcFurnitureType (mööbel) (_RKAS BIM + ARCHICAD Classification)
AC_Pset_RenovationAndPhasing - Renovation Status: Existing

# IfcFurnishingElement: Model Element 6, FU - 001
In: 2 KORRUS
Type - ElementType: Element type FU - 001
Classification: 1.10 IfcFurnitureType (mööbel) (_RKAS BIM + ARCHICAD Classification)
AC_Pset_RenovationAndPhasing - Renovation Status: Existing

# IfcFurnishingElement: Model Element 60, FU - 002
In: 2 KORRUS
Type - ElementType: Element type FU - 002
Classification: 1.10 IfcFurnitureType (mööbel) (_RKAS BIM + ARCHICAD Classification)
AC_Pset_RenovationAndPhasing - Renovation Status: Existing

# IfcFurnishingElement: Model Element 61 (3)
In: 2 KORRUS
Type - ElementType: Element type FU - 001
Classification: 1.10 IfcFurnitureType (mööbel) (_RKAS BIM + ARCHICAD Classification)
AC_Pset_RenovationAndPhasing - Renovation Status: Existing

# IfcFurnishingElement: Model Element 62 (2)
In: 2 KORRUS
Type - ElementType: Element type FU - 002
Classification: 1.10 IfcFurnitureType (mööbel) (_RKAS BIM + ARCHICAD Classification)
AC_Pset_RenovationAndPhasing - Renovation Status: Existing

# IfcFurnishingElement: Model Element 63, FU - 001
In: 2 KORRUS
Type - ElementType: Element type FU - 001
Classification: 1.10 IfcFurnitureType (mööbel) (_RKAS BIM + ARCHICAD Classification)
AC_Pset_RenovationAndPhasing - Renovation Status: Existing

# IfcFurnishingElement: Model Element 64, FU - 002
In: 2 KORRUS
Type - ElementType: Element type FU - 002
Classification: 1.10 IfcFurnitureType (mööbel) (_RKAS BIM + ARCHICAD Classification)
AC_Pset_RenovationAndPhasing - Renovation Status: Existing

# IfcFurnishingElement: Model Element 65, FU - 018
In: 2 KORRUS
Type - ElementType: Element type FU - 018
Classification: 1.10 IfcFurnitureType (mööbel) (_RKAS BIM + ARCHICAD Classification)
AC_Pset_RenovationAndPhasing - Renovation Status: Existing

# IfcFurnishingElement: Model Element 66, FU - 011
In: 2 KORRUS
Type - ElementType: Element type FU - 011
Classification: 1.10 IfcFurnitureType (mööbel) (_RKAS BIM + ARCHICAD Classification)
AC_Pset_RenovationAndPhasing - Renovation Status: Existing

# IfcFurnishingElement: Model Element 68, FU - 002
In: 2 KORRUS
Type - ElementType: Element type FU - 002
Classification: 1.10 IfcFurnitureType (mööbel) (_RKAS BIM + ARCHICAD Classification)
AC_Pset_RenovationAndPhasing - Renovation Status: Existing

# IfcFurnishingElement: Model Element 69, FU - 002
In: 2 KORRUS
Type - ElementType: Element type FU - 002
Classification: 1.10 IfcFurnitureType (mööbel) (_RKAS BIM + ARCHICAD Classification)
AC_Pset_RenovationAndPhasing - Renovation Status: Existing

# IfcFurnishingElement: Model Element 7 (2)
In: 2 KORRUS
Type - ElementType: Element type FU - 002
Classification: 1.10 IfcFurnitureType (mööbel) (_RKAS BIM + ARCHICAD Classification)
AC_Pset_RenovationAndPhasing - Renovation Status: Existing

# IfcFurnishingElement: Model Element 70, FU - 001
In: 2 KORRUS
Type - ElementType: Element type FU - 001
Classification: 1.10 IfcFurnitureType (mööbel) (_RKAS BIM + ARCHICAD Classification)
AC_Pset_RenovationAndPhasing - Renovation Status: Existing

# IfcFurnishingElement: Model Element 71, FU - 001
In: 2 KORRUS
Type - ElementType: Element type FU - 001
Classification: 1.10 IfcFurnitureType (mööbel) (_RKAS BIM + ARCHICAD Classification)
AC_Pset_RenovationAndPhasing - Renovation Status: Existing

# IfcFurnishingElement: Model Element 72, FU - 002
In: 2 KORRUS
Type - ElementType: Element type FU - 002
Classification: 1.10 IfcFurnitureType (mööbel) (_RKAS BIM + ARCHICAD Classification)
AC_Pset_RenovationAndPhasing - Renovation Status: Existing

# IfcFurnishingElement: Model Element 73, FU - 019
In: 2 KORRUS
Type - ElementType: Element type FU - 019
Classification: 1.10 IfcFurnitureType (mööbel) (_RKAS BIM + ARCHICAD Classification)
AC_Pset_RenovationAndPhasing - Renovation Status: Existing

# IfcFurnishingElement: Model Element 74 (3)
In: 2 KORRUS
Type - ElementType: Element type FU - 001
Classification: 1.10 IfcFurnitureType (mööbel) (_RKAS BIM + ARCHICAD Classification)
AC_Pset_RenovationAndPhasing - Renovation Status: Existing

# IfcFurnishingElement: Model Element 75, FU - 002
In: 2 KORRUS
Type - ElementType: Element type FU - 002
Classification: 1.10 IfcFurnitureType (mööbel) (_RKAS BIM + ARCHICAD Classification)
AC_Pset_RenovationAndPhasing - Renovation Status: Existing

# IfcFurnishingElement: Model Element 76, FU - 002
In: 2 KORRUS
Type - ElementType: Element type FU - 002
Classification: 1.10 IfcFurnitureType (mööbel) (_RKAS BIM + ARCHICAD Classification)
AC_Pset_RenovationAndPhasing - Renovation Status: Existing

# IfcFurnishingElement: Model Element 77, FU - 001
In: 2 KORRUS
Type - ElementType: Element type FU - 001
Classification: 1.10 IfcFurnitureType (mööbel) (_RKAS BIM + ARCHICAD Classification)
AC_Pset_RenovationAndPhasing - Renovation Status: Existing

# IfcFurnishingElement: Model Element 78, FU - 001
In: 2 KORRUS
Type - ElementType: Element type FU - 001
Classification: 1.10 IfcFurnitureType (mööbel) (_RKAS BIM + ARCHICAD Classification)
AC_Pset_RenovationAndPhasing - Renovation Status: Existing

# IfcFurnishingElement: Model Element 79, FU - 012
In: 2 KORRUS
Type - ElementType: Element type FU - 012
Classification: 1.10 IfcFurnitureType (mööbel) (_RKAS BIM + ARCHICAD Classification)
AC_Pset_RenovationAndPhasing - Renovation Status: Existing

# IfcFurnishingElement: Model Element 8 (4)
In: 2 KORRUS
Type - ElementType: Element type FU - 001
Classification: 1.10 IfcFurnitureType (mööbel) (_RKAS BIM + ARCHICAD Classification)
AC_Pset_RenovationAndPhasing - Renovation Status: Existing

# IfcFurnishingElement: Model Element 80, FU - 007
In: 2 KORRUS
Type - ElementType: Element type FU - 007
Classification: 1.10 IfcFurnitureType (mööbel) (_RKAS BIM + ARCHICAD Classification)
AC_Pset_RenovationAndPhasing - Renovation Status: Existing

# IfcFurnishingElement: Model Element 81, FU - 001
In: 2 KORRUS
Type - ElementType: Element type FU - 001
Classification: 1.10 IfcFurnitureType (mööbel) (_RKAS BIM + ARCHICAD Classification)
AC_Pset_RenovationAndPhasing - Renovation Status: Existing

# IfcFurnishingElement: Model Element 83, FU - 018
In: 2 KORRUS
Type - ElementType: Element type FU - 018
Classification: 1.10 IfcFurnitureType (mööbel) (_RKAS BIM + ARCHICAD Classification)
AC_Pset_RenovationAndPhasing - Renovation Status: Existing

# IfcFurnishingElement: Model Element 84 (2)
In: 2 KORRUS
Type - ElementType: Element type FU - 018
Classification: 1.10 IfcFurnitureType (mööbel) (_RKAS BIM + ARCHICAD Classification)
AC_Pset_RenovationAndPhasing - Renovation Status: Existing

# IfcFurnishingElement: Model Element 85, FU - 007
In: 2 KORRUS
Type - ElementType: Element type FU - 007
Classification: 1.10 IfcFurnitureType (mööbel) (_RKAS BIM + ARCHICAD Classification)
AC_Pset_RenovationAndPhasing - Renovation Status: Existing

# IfcFurnishingElement: Model Element 86, FU - 002
In: 2 KORRUS
Type - ElementType: Element type FU - 002
Classification: 1.10 IfcFurnitureType (mööbel) (_RKAS BIM + ARCHICAD Classification)
AC_Pset_RenovationAndPhasing - Renovation Status: Existing

# IfcFurnishingElement: Model Element 87, FU - 002
In: 2 KORRUS
Type - ElementType: Element type FU - 002
Classification: 1.10 IfcFurnitureType (mööbel) (_RKAS BIM + ARCHICAD Classification)
AC_Pset_RenovationAndPhasing - Renovation Status: Existing

# IfcFurnishingElement: Model Element 88, FU - 001
In: 2 KORRUS
Type - ElementType: Element type FU - 001
Classification: 1.10 IfcFurnitureType (mööbel) (_RKAS BIM + ARCHICAD Classification)
AC_Pset_RenovationAndPhasing - Renovation Status: Existing

# IfcFurnishingElement: Model Element 89, FU - 002
In: 2 KORRUS
Type - ElementType: Element type FU - 002
Classification: 1.10 IfcFurnitureType (mööbel) (_RKAS BIM + ARCHICAD Classification)
AC_Pset_RenovationAndPhasing - Renovation Status: Existing

# IfcFurnishingElement: Model Element 9, FU - 001
In: 2 KORRUS
Type - ElementType: Element type FU - 001
Classification: 1.10 IfcFurnitureType (mööbel) (_RKAS BIM + ARCHICAD Classification)
AC_Pset_RenovationAndPhasing - Renovation Status: Existing

# IfcFurnishingElement: Model Element 9, FU - 006
In: 1 KORRUS
Type - ElementType: Element type FU - 006
Classification: 1.10 IfcFurnitureType (mööbel) (_RKAS BIM + ARCHICAD Classification)
AC_Pset_RenovationAndPhasing - Renovation Status: Existing

# IfcFurnishingElement: Model Element 9 (4)
In: 1 KORRUS
Type - ElementType: Element type FU - 007
Classification: 1.10 IfcFurnitureType (mööbel) (_RKAS BIM + ARCHICAD Classification)
AC_Pset_RenovationAndPhasing - Renovation Status: Existing

# IfcFurnishingElement: Model Element 90, FU - 001
In: 2 KORRUS
Type - ElementType: Element type FU - 001
Classification: 1.10 IfcFurnitureType (mööbel) (_RKAS BIM + ARCHICAD Classification)
AC_Pset_RenovationAndPhasing - Renovation Status: Existing

# IfcFurnishingElement: Model Element 91, FU - 002
In: 2 KORRUS
Type - ElementType: Element type FU - 002
Classification: 1.10 IfcFurnitureType (mööbel) (_RKAS BIM + ARCHICAD Classification)
AC_Pset_RenovationAndPhasing - Renovation Status: Existing

# IfcFurnishingElement: Model Element 92, FU - 001
In: 2 KORRUS
Type - ElementType: Element type FU - 001
Classification: 1.10 IfcFurnitureType (mööbel) (_RKAS BIM + ARCHICAD Classification)
AC_Pset_RenovationAndPhasing - Renovation Status: Existing

# IfcFurnishingElement: Model Element 93, FU - 001
In: 2 KORRUS
Type - ElementType: Element type FU - 001
Classification: 1.10 IfcFurnitureType (mööbel) (_RKAS BIM + ARCHICAD Classification)
AC_Pset_RenovationAndPhasing - Renovation Status: Existing

# IfcFurnishingElement: Model Element 94, FU - 002
In: 2 KORRUS
Type - ElementType: Element type FU - 002
Classification: 1.10 IfcFurnitureType (mööbel) (_RKAS BIM + ARCHICAD Classification)
AC_Pset_RenovationAndPhasing - Renovation Status: Existing

# IfcFurnishingElement: Model Element 95, FU - 002
In: 2 KORRUS
Type - ElementType: Element type FU - 002
Classification: 1.10 IfcFurnitureType (mööbel) (_RKAS BIM + ARCHICAD Classification)
AC_Pset_RenovationAndPhasing - Renovation Status: Existing

# IfcFurnishingElement: Model Element 96, FU - 002
In: 2 KORRUS
Type - ElementType: Element type FU - 002
Classification: 1.10 IfcFurnitureType (mööbel) (_RKAS BIM + ARCHICAD Classification)
AC_Pset_RenovationAndPhasing - Renovation Status: Existing

# IfcFurnishingElement: Model Element 97, FU - 001
In: 2 KORRUS
Type - ElementType: Element type FU - 001
Classification: 1.10 IfcFurnitureType (mööbel) (_RKAS BIM + ARCHICAD Classification)
AC_Pset_RenovationAndPhasing - Renovation Status: Existing

# IfcFurnishingElement: Model Element 98, FU - 001
In: 2 KORRUS
Type - ElementType: Element type FU - 001
Classification: 1.10 IfcFurnitureType (mööbel) (_RKAS BIM + ARCHICAD Classification)
AC_Pset_RenovationAndPhasing - Renovation Status: Existing

# IfcFurnishingElement: Model Element 99, FU - 001
In: 2 KORRUS
Type - ElementType: Element type FU - 001
Classification: 1.10 IfcFurnitureType (mööbel) (_RKAS BIM + ARCHICAD Classification)
AC_Pset_RenovationAndPhasing - Renovation Status: Existing

# IfcFurnishingElement: Office Workstation Solo 22, FU - 017
In: 1 KORRUS
Type - ElementType: Element type FU - 017
Classification: 1.10 IfcFurnitureType (mööbel) (_RKAS BIM + ARCHICAD Classification)
AC_Pset_RenovationAndPhasing - Renovation Status: Existing

# IfcFurnishingElement: Projector 22 (2)
In: 2 KORRUS
Type - ElementType: Element type FU - 002
Classification: 1.10 IfcFurnitureType (mööbel) (_RKAS BIM + ARCHICAD Classification)
AC_Pset_RenovationAndPhasing - Renovation Status: Existing

# IfcFurnishingElement: Projector Screen 22 (2)
In: 2 KORRUS
Type - ElementType: Element type FU - 003
Classification: 1.10 IfcFurnitureType (mööbel) (_RKAS BIM + ARCHICAD Classification)
AC_Pset_RenovationAndPhasing - Renovation Status: Existing

# IfcFurnishingElement: Washer 22, FU - 002
In: 1 KORRUS
Type - ElementType: Element type Pesumasin
Classification: 1.10 IfcFurnitureType (mööbel) (_RKAS BIM + ARCHICAD Classification)
AC_Pset_RenovationAndPhasing - Renovation Status: New

# IfcMember: SLA - 003, Betoon - Ol.Olev konstruktsioon
In: KATUSEPLAAN
Type - ElementType: Element type SLA - 003
Classification: 2.7 IfcMember (kandev element) (_RKAS BIM + ARCHICAD Classification); Material: Betoon - Ol.Olev konstruktsioon
Ehituskonstruktsioonid - 01 Nimetus: Betoon - Ol.Olev konstruktsioon; 02 Materjal: Betoon - Ol.Olev konstruktsioon; 03 Tähistus või ristlõige: SLA - 003; 04 Materjali peamine tugevusnäitaja: Undefined; 05 Keskkonnaklass: Undefined; 06 Maht (kubatuur): 7,17; 07 Monteeritava elemendi mass: Undefined; 08 Monteeritava elemendi pikkus: ; Undefined; 09 Monteeritava elemendi positisioon/mark: Undefined; 10 Elemendi valmistamise tehnoloogia: Undefined; 11 Ülemine kõrgusmärk: 5 567; Kõrgus: 180; 3D pikkus:; 12 Alumine kõrgusmärk: 5 567
AC_Pset_RenovationAndPhasing - Renovation Status: Existing

# IfcMember: SW - 002, Kivi - Ol.Olev Konstruktsioon
In: VUNDAMENT
Type - ElementType: Element type SW - 002
Classification: 2.7 IfcMember (kandev element) (_RKAS BIM + ARCHICAD Classification); Material: Kivi - Ol.Olev Konstruktsioon
Ehituskonstruktsioonid - 01 Nimetus: Kivi - Ol.Olev Konstruktsioon; 02 Materjal: Kivi - Ol.Olev Konstruktsioon; 03 Tähistus või ristlõige: SW - 002; 04 Materjali peamine tugevusnäitaja: Undefined; 05 Keskkonnaklass: Undefined; 06 Maht (kubatuur): 1,14; 07 Monteeritava elemendi mass: Undefined; 08 Monteeritava elemendi pikkus: 5 847; Undefined; 09 Monteeritava elemendi positisioon/mark: Undefined; 10 Elemendi valmistamise tehnoloogia: Undefined; 11 Ülemine kõrgusmärk: -1 000; Kõrgus: 650; 3D pikkus: 5 847; 12 Alumine kõrgusmärk: -1 000
AC_Pset_RenovationAndPhasing - Renovation Status: Existing
Pset_MemberCommon - LoadBearing: no; IsExternal: yes

# IfcMember: SW - 003, Kivi - Ol.Olev Konstruktsioon
In: VUNDAMENT
Type - ElementType: Element type SW - 003
Classification: 2.7 IfcMember (kandev element) (_RKAS BIM + ARCHICAD Classification); Material: Kivi - Ol.Olev Konstruktsioon
Ehituskonstruktsioonid - 01 Nimetus: Kivi - Ol.Olev Konstruktsioon; 02 Materjal: Kivi - Ol.Olev Konstruktsioon; 03 Tähistus või ristlõige: SW - 003; 04 Materjali peamine tugevusnäitaja: Undefined; 05 Keskkonnaklass: Undefined; 06 Maht (kubatuur): 2,27; 07 Monteeritava elemendi mass: Undefined; 08 Monteeritava elemendi pikkus: 11 656; Undefined; 09 Monteeritava elemendi positisioon/mark: Undefined; 10 Elemendi valmistamise tehnoloogia: Undefined; 11 Ülemine kõrgusmärk: -1 000; Kõrgus: 650; 3D pikkus: 11 656; 12 Alumine kõrgusmärk: -1 000
AC_Pset_RenovationAndPhasing - Renovation Status: Existing
Pset_MemberCommon - LoadBearing: no; IsExternal: yes

# IfcMember: SW - 004, Kivi - Ol.Olev Konstruktsioon
In: VUNDAMENT
Type - ElementType: Element type SW - 004
Classification: 2.7 IfcMember (kandev element) (_RKAS BIM + ARCHICAD Classification); Material: Kivi - Ol.Olev Konstruktsioon
Ehituskonstruktsioonid - 01 Nimetus: Kivi - Ol.Olev Konstruktsioon; 02 Materjal: Kivi - Ol.Olev Konstruktsioon; 03 Tähistus või ristlõige: SW - 004; 04 Materjali peamine tugevusnäitaja: Undefined; 05 Keskkonnaklass: Undefined; 06 Maht (kubatuur): 1,08; 07 Monteeritava elemendi mass: Undefined; 08 Monteeritava elemendi pikkus: 5 550; Undefined; 09 Monteeritava elemendi positisioon/mark: Undefined; 10 Elemendi valmistamise tehnoloogia: Undefined; 11 Ülemine kõrgusmärk: -1 000; Kõrgus: 650; 3D pikkus: 5 550; 12 Alumine kõrgusmärk: -1 000
AC_Pset_RenovationAndPhasing - Renovation Status: Existing
Pset_MemberCommon - LoadBearing: no; IsExternal: yes

# IfcMember: SW - 018, PAEKIVISEIN
In: VUNDAMENT
Type - ElementType: Element type SW - 018
Classification: 2.7 IfcMember (kandev element) (_RKAS BIM + ARCHICAD Classification); Material: PAEKIVISEIN
Ehituskonstruktsioonid - 01 Nimetus: PAEKIVISEIN; 02 Materjal: PAEKIVISEIN; 03 Tähistus või ristlõige: SW - 018; 04 Materjali peamine tugevusnäitaja: Undefined; 05 Keskkonnaklass: Undefined; 06 Maht (kubatuur): 1,69; 07 Monteeritava elemendi mass: Undefined; 08 Monteeritava elemendi pikkus: 3 177; Undefined; 09 Monteeritava elemendi positisioon/mark: Undefined; 10 Elemendi valmistamise tehnoloogia: Undefined; 11 Ülemine kõrgusmärk: -1 000; Kõrgus: 650; 3D pikkus: 3 177; 12 Alumine kõrgusmärk: -1 000
AC_Pset_RenovationAndPhasing - Renovation Status: Existing

# IfcMember: SW - 020 (3)
Type - ElementType: Element type SW - 020
Ehituskonstruktsioonid - 03 Tähistus või ristlõige: SW - 020; 04 Materjali peamine tugevusnäitaja: Undefined; 05 Keskkonnaklass: Undefined; 07 Monteeritava elemendi mass: Undefined; 09 Monteeritava elemendi positisioon/mark: Undefined; 10 Elemendi valmistamise tehnoloogia: Undefined
Name | In | Classification | Material = 01 Nimetus = 02 Materjal | 06 Maht (kubatuur) | 08 Monteeritava elemendi pikkus | 11 Ülemine kõrgusmärk | 12 Alumine kõrgusmärk | Renovation Status
PAEKIVISEIN | VUNDAMENT | 2.7 IfcMember (kandev element) (_RKAS BIM + ARCHICAD Classification) | PAEKIVISEIN | 0,76 | 1 788; Undefined | -1 000; Kõrgus: 650; 3D pikkus: 1 788 | -1 000 | Existing
PAEKIVISEIN | VUNDAMENT | 2.7 IfcMember (kandev element) (_RKAS BIM + ARCHICAD Classification) | PAEKIVISEIN | 1,26 | 2 973; Undefined | -1 000; Kõrgus: 650; 3D pikkus: 2 973 | -1 000 | Existing
Kivi - Ol.Olev Konstruktsioon | 1 KORRUS | 2.7 IfcMember (kandev element) (_RKAS BIM + ARCHICAD Classification); 32 Kandvad ja välisseinad (EHITUSKULUDE LIIGITAMINE EVS 885:2005) | Kivi - Ol.Olev Konstruktsioon | 0,73 | 672; Undefined | 0; Kõrgus: 2 600; 3D pikkus: 672 | 0 | New | Pset_MemberCommon - LoadBearing: no; IsExternal: yes

# IfcMember: SW - 022 (3)
In: VUNDAMENT
Type - ElementType: Element type SW - 022
Classification: 2.7 IfcMember (kandev element) (_RKAS BIM + ARCHICAD Classification)
Ehituskonstruktsioonid - 03 Tähistus või ristlõige: SW - 022; 04 Materjali peamine tugevusnäitaja: Undefined; 05 Keskkonnaklass: Undefined; 07 Monteeritava elemendi mass: Undefined; 09 Monteeritava elemendi positisioon/mark: Undefined; 10 Elemendi valmistamise tehnoloogia: Undefined; 12 Alumine kõrgusmärk: -1 000
AC_Pset_RenovationAndPhasing - Renovation Status: Existing
Name | Material = 01 Nimetus = 02 Materjal | 06 Maht (kubatuur) | 08 Monteeritava elemendi pikkus | 11 Ülemine kõrgusmärk
PAEKIVISEIN | PAEKIVISEIN | 1,96 | 3 687; Undefined | -1 000; Kõrgus: 650; 3D pikkus: 3 687
TELLIS | TELLIS | 0,75 | 3 858; Undefined | -1 000; Kõrgus: 650; 3D pikkus: 3 858
PAEKIVISEIN | PAEKIVISEIN | 0,73 | 2 803; Undefined | -1 000; Kõrgus: 650; 3D pikkus: 2 803 | Pset_MemberCommon - LoadBearing: yes; IsExternal: yes

# IfcMember: SW - 023 (2)
In: VUNDAMENT
Type - ElementType: Element type SW - 023
Classification: 2.7 IfcMember (kandev element) (_RKAS BIM + ARCHICAD Classification); Material: PAEKIVISEIN
Ehituskonstruktsioonid - 01 Nimetus: PAEKIVISEIN; 02 Materjal: PAEKIVISEIN; 03 Tähistus või ristlõige: SW - 023; 04 Materjali peamine tugevusnäitaja: Undefined; 05 Keskkonnaklass: Undefined; 07 Monteeritava elemendi mass: Undefined; 09 Monteeritava elemendi positisioon/mark: Undefined; 10 Elemendi valmistamise tehnoloogia: Undefined; 12 Alumine kõrgusmärk: -1 000
AC_Pset_RenovationAndPhasing - Renovation Status: Existing
Name | 06 Maht (kubatuur) | 08 Monteeritava elemendi pikkus | 11 Ülemine kõrgusmärk
PAEKIVISEIN | 6,34 | 13 032; Undefined | -1 000; Kõrgus: 650; 3D pikkus: 13 032
PAEKIVISEIN | 0,80 | 3 094; Undefined | -1 000; Kõrgus: 650; 3D pikkus: 3 094 | Pset_MemberCommon - LoadBearing: yes; IsExternal: yes

# IfcMember: SW - 024, PAEKIVISEIN
In: VUNDAMENT
Type - ElementType: Element type SW - 024
Classification: 2.7 IfcMember (kandev element) (_RKAS BIM + ARCHICAD Classification); Material: PAEKIVISEIN
Ehituskonstruktsioonid - 01 Nimetus: PAEKIVISEIN; 02 Materjal: PAEKIVISEIN; 03 Tähistus või ristlõige: SW - 024; 04 Materjali peamine tugevusnäitaja: Undefined; 05 Keskkonnaklass: Undefined; 06 Maht (kubatuur): 0,63; 07 Monteeritava elemendi mass: Undefined; 08 Monteeritava elemendi pikkus: 2 439; Undefined; 09 Monteeritava elemendi positisioon/mark: Undefined; 10 Elemendi valmistamise tehnoloogia: Undefined; 11 Ülemine kõrgusmärk: -1 000; Kõrgus: 650; 3D pikkus: 2 439; 12 Alumine kõrgusmärk: -1 000
AC_Pset_RenovationAndPhasing - Renovation Status: Existing
Pset_MemberCommon - LoadBearing: yes; IsExternal: yes

# IfcMember: SW - 032, PAEKIVISEIN
In: VUNDAMENT
Type - ElementType: Element type SW - 032
Classification: 2.7 IfcMember (kandev element) (_RKAS BIM + ARCHICAD Classification); Material: PAEKIVISEIN
Ehituskonstruktsioonid - 01 Nimetus: PAEKIVISEIN; 02 Materjal: PAEKIVISEIN; 03 Tähistus või ristlõige: SW - 032; 04 Materjali peamine tugevusnäitaja: Undefined; 05 Keskkonnaklass: Undefined; 06 Maht (kubatuur): 0,58; 07 Monteeritava elemendi mass: Undefined; 08 Monteeritava elemendi pikkus: 1 793; Undefined; 09 Monteeritava elemendi positisioon/mark: Undefined; 10 Elemendi valmistamise tehnoloogia: Undefined; 11 Ülemine kõrgusmärk: -1 000; Kõrgus: 650; 3D pikkus: 1 793; 12 Alumine kõrgusmärk: -1 000
AC_Pset_RenovationAndPhasing - Renovation Status: Existing

# IfcMember: SW - 036, Sise kivisein
In: VUNDAMENT
Type - ElementType: Element type SW - 036
Classification: 2.7 IfcMember (kandev element) (_RKAS BIM + ARCHICAD Classification); Material: Sise kivisein
Ehituskonstruktsioonid - 01 Nimetus: Sise kivisein; 02 Materjal: Sise kivisein; 03 Tähistus või ristlõige: SW - 036; 04 Materjali peamine tugevusnäitaja: Undefined; 05 Keskkonnaklass: Undefined; 06 Maht (kubatuur): 0,36; 07 Monteeritava elemendi mass: Undefined; 08 Monteeritava elemendi pikkus: 872; Undefined; 09 Monteeritava elemendi positisioon/mark: Undefined; 10 Elemendi valmistamise tehnoloogia: Undefined; 11 Ülemine kõrgusmärk: -1 000; Kõrgus: 650; 3D pikkus: 872; 12 Alumine kõrgusmärk: -1 000
AC_Pset_RenovationAndPhasing - Renovation Status: Existing

# IfcMember: VS1 (3)
In: 1 KORRUS
Type - ElementType: Element type VS1
Classification: 2.7 IfcMember (kandev element) (_RKAS BIM + ARCHICAD Classification); 32 Kandvad ja välisseinad (EHITUSKULUDE LIIGITAMINE EVS 885:2005); Material: Kivi - Ol.Olev Konstruktsioon
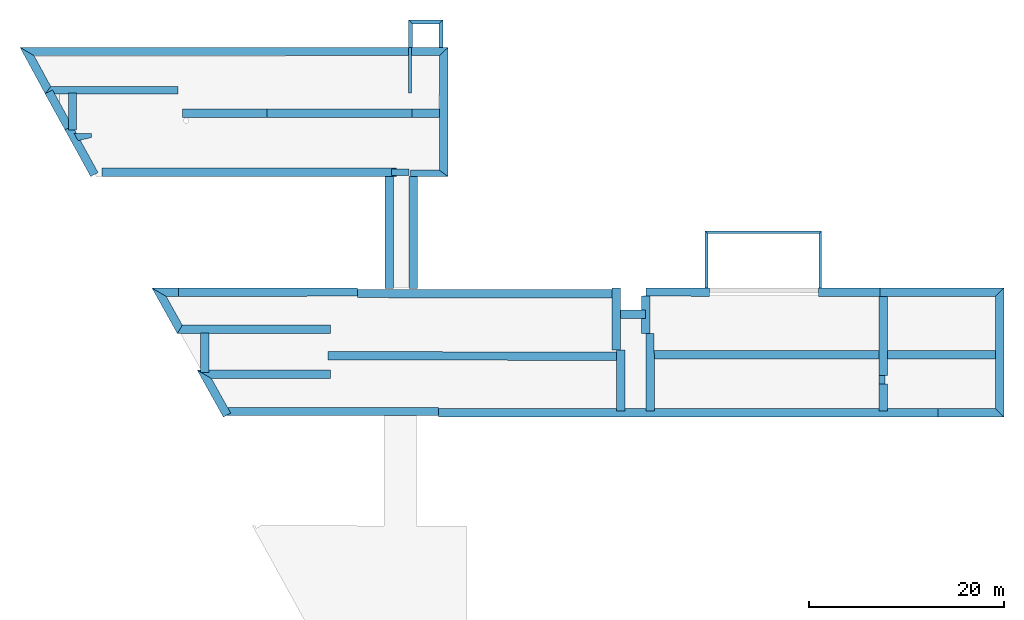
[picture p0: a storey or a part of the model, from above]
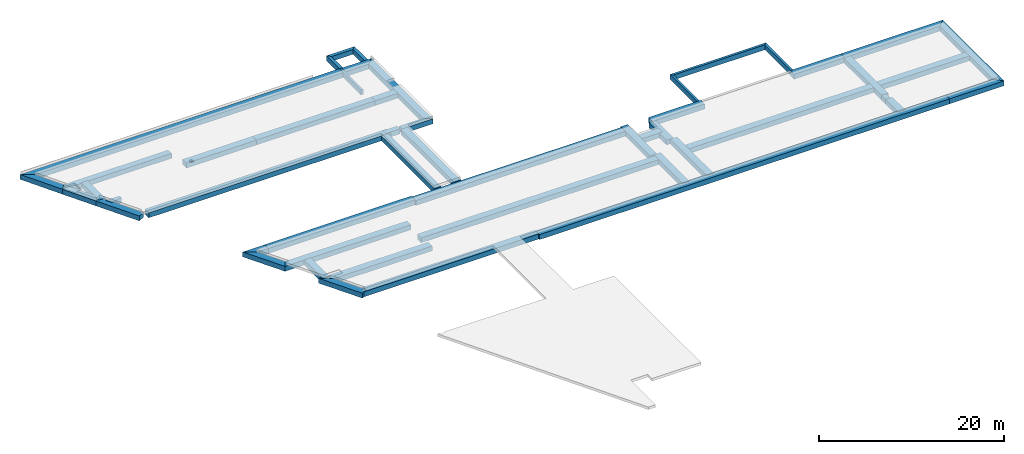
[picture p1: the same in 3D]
Properties of the parts of a building model (IFC2X3), part 11 of 14

# IfcMember: VS1 (3)
Ehituskonstruktsioonid - 01 Nimetus: Ol.olve tugimüür 500; 02 Materjal: Kivi - Ol.Olev Konstruktsioon; 03 Tähistus või ristlõige: VS1; 04 Materjali peamine tugevusnäitaja: Undefined; 05 Keskkonnaklass: Undefined; 07 Monteeritava elemendi mass: Undefined; 09 Monteeritava elemendi positisioon/mark: Undefined; 10 Elemendi valmistamise tehnoloogia: Undefined; 12 Alumine kõrgusmärk: -1 000
AC_Pset_RenovationAndPhasing - Renovation Status: Existing
Pset_MemberCommon - LoadBearing: yes; IsExternal: yes
Name | 06 Maht (kubatuur) | 08 Monteeritava elemendi pikkus | 11 Ülemine kõrgusmärk
Ol.olve tugimüür 500 | 15,68 | 8 471; Undefined | -1 000; Kõrgus: 3 703; 3D pikkus: 8 471
Ol.olve tugimüür 500 | 18,95 | 10 363; Undefined | -1 000; Kõrgus: 3 703; 3D pikkus: 10 363
Ol.olve tugimüür 500 | 25,76 | 13 673; Undefined | -1 000; Kõrgus: 3 798; 3D pikkus: 13 673

# IfcMember: VS4 (2)
In: 2 KORRUS
Type - ElementType: Element type VS4
Classification: 2.7 IfcMember (kandev element) (_RKAS BIM + ARCHICAD Classification); 32 Kandvad ja välisseinad (EHITUSKULUDE LIIGITAMINE EVS 885:2005); Material: Kivi -Ol.Olev Konstruktsioon
Ehituskonstruktsioonid - 01 Nimetus: ol.olev ss 150; 02 Materjal: Kivi -Ol.Olev Konstruktsioon; 03 Tähistus või ristlõige: VS4; 04 Materjali peamine tugevusnäitaja: Undefined; 05 Keskkonnaklass: Undefined; 07 Monteeritava elemendi mass: Undefined; 09 Monteeritava elemendi positisioon/mark: Undefined; 10 Elemendi valmistamise tehnoloogia: Undefined
AC_Pset_RenovationAndPhasing - Renovation Status: Existing
Pset_MemberCommon - LoadBearing: no; IsExternal: no
Name | 06 Maht (kubatuur) | 08 Monteeritava elemendi pikkus | 11 Ülemine kõrgusmärk | 12 Alumine kõrgusmärk
ol.olev ss 150 | 0,82 | 11 179; Undefined | 5 505; Kõrgus: 491; 3D pikkus: 11 179 | 5 505
ol.olev ss 150 | 0,66 | 11 125; Undefined | 5 550; Kõrgus: 396; 3D pikkus: 11 125 | 5 550

# IfcMember: ol.ol postid (159)
Type - ElementType: Element type ol.ol postid
Classification: 2.7 IfcMember (kandev element) (_RKAS BIM + ARCHICAD Classification); 32 Kandvad ja välisseinad (EHITUSKULUDE LIIGITAMINE EVS 885:2005); Material: Kivi - Ol.Olev Konstruktsioon
Ehituskonstruktsioonid - 01 Nimetus: Kivi - Ol.Olev Konstruktsioon; 02 Materjal: Kivi - Ol.Olev Konstruktsioon; 03 Tähistus või ristlõige: ol.ol postid; 04 Materjali peamine tugevusnäitaja: Undefined; 05 Keskkonnaklass: Undefined; 07 Monteeritava elemendi mass: Undefined; 09 Monteeritava elemendi positisioon/mark: Undefined; 10 Elemendi valmistamise tehnoloogia: Undefined
AC_Pset_RenovationAndPhasing - Renovation Status: Existing
Pset_MemberCommon - LoadBearing: no; IsExternal: yes
Name | In | 06 Maht (kubatuur) | 08 Monteeritava elemendi pikkus | 11 Ülemine kõrgusmärk | 12 Alumine kõrgusmärk
66 x Kivi - Ol.Olev Konstruktsioon | 1 KORRUS | 0,46 | 2 600; Undefined | 0; Kõrgus: 2 600; 3D pikkus: 2 600 | 0
Kivi - Ol.Olev Konstruktsioon | 1 KORRUS | 26,21 | 2 600; Undefined | 0; Kõrgus: 2 600; 3D pikkus: 2 600 | 0
3 x Kivi - Ol.Olev Konstruktsioon | 1 KORRUS | 0,45 | 2 600; Undefined | 0; Kõrgus: 2 600; 3D pikkus: 2 600 | 0
53 x Kivi - Ol.Olev Konstruktsioon | 2 KORRUS | 0,55 | 3 250; Undefined | 3 000; Kõrgus: 3 250; 3D pikkus: 3 250 | 3 000
Kivi - Ol.Olev Konstruktsioon | 2 KORRUS | 0,58 | 3 250; Undefined | 3 000; Kõrgus: 3 250; 3D pikkus: 3 250 | 3 000
31 x Kivi - Ol.Olev Konstruktsioon | 2 KORRUS | 0,54 | 3 250; Undefined | 3 000; Kõrgus: 3 250; 3D pikkus: 3 250 | 3 000
Kivi - Ol.Olev Konstruktsioon | 2 KORRUS | 0,34 | 3 250; Undefined | 3 000; Kõrgus: 3 250; 3D pikkus: 3 250 | 3 000
Kivi - Ol.Olev Konstruktsioon | 2 KORRUS | 0,53 | 3 250; Undefined | 3 000; Kõrgus: 3 250; 3D pikkus: 3 250 | 3 000
Kivi - Ol.Olev Konstruktsioon | 2 KORRUS | 0,44 | 3 250; Undefined | 3 000; Kõrgus: 3 250; 3D pikkus: 3 250 | 3 000
Kivi - Ol.Olev Konstruktsioon | 2 KORRUS | 0,36 | 3 250; Undefined | 3 000; Kõrgus: 3 250; 3D pikkus: 3 250 | 3 000

# IfcRailing: Piire (12)
Type - ElementType: Element type Piire
Name | In | Classification | Material | Renovation Status | IsExternal
2 x Piire | 1 KORRUS | 1.11 IfcRailing (piire) (_RKAS BIM + ARCHICAD Classification); 181 Piirded (EHITUSKULUDE LIIGITAMINE EVS 885:2005) | Teras - Konstruktsioon (1) (12) | New | yes
4 x Piire | 1 KORRUS | 1.11 IfcRailing (piire) (_RKAS BIM + ARCHICAD Classification) | Teras - Konstruktsioon (1) (11) | Existing
4 x Piire | 2 KORRUS | 1.11 IfcRailing (piire) (_RKAS BIM + ARCHICAD Classification); 181 Piirded (EHITUSKULUDE LIIGITAMINE EVS 885:2005) | Teras - Konstruktsioon (1) (8) | New | yes
Piire | 2 KORRUS | 1.11 IfcRailing (piire) (_RKAS BIM + ARCHICAD Classification); 181 Piirded (EHITUSKULUDE LIIGITAMINE EVS 885:2005) | Puit - Konstruktsioon (1) (5) | New | yes
Piire | KATUSEPLAAN | 1.11 IfcRailing (piire) (_RKAS BIM + ARCHICAD Classification); 472 Klaasist piirded (EHITUSKULUDE LIIGITAMINE EVS 885:2005) | Teras - Roostevaba (1) (3), Teras - Konstruktsioon (1) (116) | New

# IfcRailing: Piire 1
In: 1 KORRUS
Type - ElementType: Element type Piire 1
Classification: 1.11 IfcRailing (piire) (_RKAS BIM + ARCHICAD Classification); 181 Piirded (EHITUSKULUDE LIIGITAMINE EVS 885:2005); Material: Teras - Konstruktsioon (1) (34)
AC_Pset_RenovationAndPhasing - Renovation Status: New
Pset_RailingCommon - IsExternal: yes

# IfcRailing: RAILING - 010 (2)
In: 2 KORRUS
Type - ElementType: Element type RAILING - 010
Classification: 1.11 IfcRailing (piire) (_RKAS BIM + ARCHICAD Classification)
AC_Pset_RenovationAndPhasing - Renovation Status: Existing
Name | Material
RAILING - 010 | Teras - Konstruktsioon (1) (133)
RAILING - 010 | Teras - Konstruktsioon (1) (128)

# IfcRailing: TR 7 käepiire (2)
In: 2 KORRUS
Type - ElementType: Element type TR 7 käepiire
Description: Käepiire; Classification: 1.11 IfcRailing (piire) (_RKAS BIM + ARCHICAD Classification)
AC_Pset_RenovationAndPhasing - Renovation Status: New
Pset_RailingCommon - IsExternal: yes

# IfcRamp (6)
Arhitektuur - 05 Asukoht: Exterior; 06 Kandevelementide eristatus: Load-Bearing Element
Pset_RampCommon - IsExternal: yes
Name | In | Description | Classification | Material | 01 Nimetus | 02 Materjal | 04 Tulepüsivus | 07 Helipidavus = 08 Soojusläbivus (U-arv) | 03 Tähistus | Renovation Status
Pandus 1 | 1 KORRUS | betoon | 1.12 IfcRamp (ramp) (_RKAS BIM + ARCHICAD Classification); 141 Estakaadid, kaldteed ja pandused (EHITUSKULUDE LIIGITAMINE EVS 885:2005) | Kivi - Uus Konstruktsioon | Pandus 1 | Betoon | - | - | PANDUS 1 | New
2 x PAEKIVISEIN | 2 KORRUS | teras | 1.12 IfcRamp (ramp) (_RKAS BIM + ARCHICAD Classification) | PAEKIVISEIN | PAEKIVISEIN | PAEKIVISEIN | Undefined | Undefined | RELS | New
Betoon - Ol.Olev konstruktsioon | 2 KORRUS |  | 1.12 IfcRamp (ramp) (_RKAS BIM + ARCHICAD Classification); 141 Estakaadid, kaldteed ja pandused (EHITUSKULUDE LIIGITAMINE EVS 885:2005) | Betoon - Ol.Olev konstruktsioon | Pandus olemas olev | -1,6mm PVCkatusekate (Näiteks Protan SE keevisliitega) -220mm Soojustus PIR (näiteks Recticel Powedeck) soojajuhtivustegur λDW/mK =0,031 -Aurutõke (SBS 3mm ) -265mm Ol.olev R/B paneel -siseviimistlus | REI-60 |  | PANDUS 4 | Existing
Betoon - Ol.Olev konstruktsioon | 2 KORRUS |  | 1.12 IfcRamp (ramp) (_RKAS BIM + ARCHICAD Classification); 141 Estakaadid, kaldteed ja pandused (EHITUSKULUDE LIIGITAMINE EVS 885:2005) | Betoon - Ol.Olev konstruktsioon | Betoon - Ol.Olev konstruktsioon | Betoon - Ol.Olev konstruktsioon | - | - | Pandus 4 | Existing
Pandus 3 | 2 KORRUS | betoon | 1.12 IfcRamp (ramp) (_RKAS BIM + ARCHICAD Classification); 141 Estakaadid, kaldteed ja pandused (EHITUSKULUDE LIIGITAMINE EVS 885:2005) | Kivi - Uus Konstruktsioon | Pandus 3 | Betoon | - | - | PANDUS 3 | New

# IfcRoof (35)
Arhitektuur - 05 Asukoht: Exterior
Pset_RoofCommon - IsExternal: yes
Name | In | Classification | Material | 04 Tulepüsivus | Arhitektuur, 01 Nimetus | Arhitektuur, 02 Materjal | 03 Tähistus = 03 Tähistus või ristlõige | 06 Kandevelementide eristatus | 07 Helipidavus | 08 Soojusläbivus (U-arv) | Ehituskonstruktsioonid, 01 Nimetus | Ehituskonstruktsioonid, 02 Materjal | 06 Maht (kubatuur) | 12 Alumine kõrgusmärk | Renovation Status | Description
Ol.Olev konsool 300 | 2 KORRUS | 1.13 IfcRoof (katus) (_RKAS BIM + ARCHICAD Classification); 4 FASSAADIELEMENDID JA KATUSED (EHITUSKULUDE LIIGITAMINE EVS 885:2005) | Kivi -Ol.Olev Konstruktsioon | REI-60 | Ol.Olev konsool 300 | Kivi -Ol.Olev Konstruktsioon | KL-3 | Load-Bearing Element | - | 0,16W/m2K | Ol.Olev konsool 300 | Kivi -Ol.Olev Konstruktsioon | 25,28 | 2 618 | Existing
Konsooli soojustus 50 | 2 KORRUS | 1.13 IfcRoof (katus) (_RKAS BIM + ARCHICAD Classification); 4 FASSAADIELEMENDID JA KATUSED (EHITUSKULUDE LIIGITAMINE EVS 885:2005) | Soojustus - Plastik Kõva | - | Konsooli soojustus 50 | Soojustus - Plastik Kõva | KL-3 | Non-Load-Bearing Element | - | 0,16W/m2K | Konsooli soojustus 50 | Soojustus - Plastik Kõva | 2,37 | 2 168 | New
Ol.Olev konsool 300 | 2 KORRUS | 1.13 IfcRoof (katus) (_RKAS BIM + ARCHICAD Classification); 4 FASSAADIELEMENDID JA KATUSED (EHITUSKULUDE LIIGITAMINE EVS 885:2005) | Kivi -Ol.Olev Konstruktsioon | REI-60 | Ol.Olev konsool 300 | Kivi -Ol.Olev Konstruktsioon | KL-3 | Load-Bearing Element | - | 0,16W/m2K | Ol.Olev konsool 300 | Kivi -Ol.Olev Konstruktsioon | 23,88 | 2 618 | Existing
Konsooli soojustus 50 | 2 KORRUS | 1.13 IfcRoof (katus) (_RKAS BIM + ARCHICAD Classification); 4 FASSAADIELEMENDID JA KATUSED (EHITUSKULUDE LIIGITAMINE EVS 885:2005) | Soojustus - Plastik Kõva | - | Konsooli soojustus 50 | Soojustus - Plastik Kõva | KL-3 | Non-Load-Bearing Element | - | 0,16W/m2K | Konsooli soojustus 50 | Soojustus - Plastik Kõva | 2,32 | 2 168 | New
Soojustus - Plastik Kõva | KATUSEPLAAN | 1.13 IfcRoof (katus) (_RKAS BIM + ARCHICAD Classification); 4 FASSAADIELEMENDID JA KATUSED (EHITUSKULUDE LIIGITAMINE EVS 885:2005) | Soojustus - Plastik Kõva | REI-60 | Katus | -1,6mm PVCkatusekate (Näiteks Protan SE keevisliitega) -220mm Soojustus PIR (näiteks Recticel Powedeck) soojajuhtivustegur λDW/mK =0,031 -Aurutõke (SBS 3mm ) -265mm Ol.olev R/B paneel -siseviimistlus | KL-1 | Load-Bearing Element | - | 0,10W/m2K | Soojustus - Plastik Kõva | Soojustus - Plastik Kõva | 12,71 | 6 515 | New | Katuse soojustus
Soojustus - Plastik Kõva | KATUSEPLAAN | 1.13 IfcRoof (katus) (_RKAS BIM + ARCHICAD Classification); 4 FASSAADIELEMENDID JA KATUSED (EHITUSKULUDE LIIGITAMINE EVS 885:2005) | Soojustus - Plastik Kõva | REI-60 | Katus | -1,6mm PVCkatusekate (Näiteks Protan SE keevisliitega) -220mm Soojustus PIR (näiteks Recticel Powedeck) soojajuhtivustegur λDW/mK =0,031 -Aurutõke (SBS 3mm ) -265mm Ol.olev R/B paneel -siseviimistlus | KL-1 | Load-Bearing Element | - | 0,10W/m2K | Soojustus - Plastik Kõva | Soojustus - Plastik Kõva | 26,06 | 6 515 | New | Katuse soojustus
Soojustus - Plastik Kõva | KATUSEPLAAN | 1.13 IfcRoof (katus) (_RKAS BIM + ARCHICAD Classification); 4 FASSAADIELEMENDID JA KATUSED (EHITUSKULUDE LIIGITAMINE EVS 885:2005) | Soojustus - Plastik Kõva | REI-60 | Katus | -1,6mm PVCkatusekate (Näiteks Protan SE keevisliitega) -220mm Soojustus PIR (näiteks Recticel Powedeck) soojajuhtivustegur λDW/mK =0,031 -Aurutõke (SBS 3mm ) -265mm Ol.olev R/B paneel -siseviimistlus | KL-1 | Load-Bearing Element | - | 0,10W/m2K | Soojustus - Plastik Kõva | Soojustus - Plastik Kõva | 20,88 | 6 515 | New | Katuse soojustus
Soojustus - Plastik Kõva | KATUSEPLAAN | 1.13 IfcRoof (katus) (_RKAS BIM + ARCHICAD Classification); 4 FASSAADIELEMENDID JA KATUSED (EHITUSKULUDE LIIGITAMINE EVS 885:2005) | Soojustus - Plastik Kõva | REI-60 | Katus | -1,6mm PVCkatusekate (Näiteks Protan SE keevisliitega) -220mm Soojustus PIR (näiteks Recticel Powedeck) soojajuhtivustegur λDW/mK =0,031 -Aurutõke (SBS 3mm ) -265mm Ol.olev R/B paneel -siseviimistlus | KL-1 | Load-Bearing Element | - | 0,10W/m2K | Soojustus - Plastik Kõva | Soojustus - Plastik Kõva | 30,19 | 6 515 | New | Katuse soojustus
Soojustus - Plastik Kõva | KATUSEPLAAN | 1.13 IfcRoof (katus) (_RKAS BIM + ARCHICAD Classification); 4 FASSAADIELEMENDID JA KATUSED (EHITUSKULUDE LIIGITAMINE EVS 885:2005) | Soojustus - Plastik Kõva | REI-60 | Katus | -1,6mm PVCkatusekate (Näiteks Protan SE keevisliitega) -220mm Soojustus PIR (näiteks Recticel Powedeck) soojajuhtivustegur λDW/mK =0,031 -Aurutõke (SBS 3mm ) -265mm Ol.olev R/B paneel -siseviimistlus | KL-1 | Load-Bearing Element | - | 0,10W/m2K | Soojustus - Plastik Kõva | Soojustus - Plastik Kõva | 28,04 | 6 515 | New | Katuse soojustus
Soojustus - Plastik Kõva | KATUSEPLAAN | 1.13 IfcRoof (katus) (_RKAS BIM + ARCHICAD Classification); 4 FASSAADIELEMENDID JA KATUSED (EHITUSKULUDE LIIGITAMINE EVS 885:2005) | Soojustus - Plastik Kõva | REI-60 | Katus | -1,6mm PVCkatusekate (Näiteks Protan SE keevisliitega) -220mm Soojustus PIR (näiteks Recticel Powedeck) soojajuhtivustegur λDW/mK =0,031 -Aurutõke (SBS 3mm ) -265mm Ol.olev R/B paneel -siseviimistlus | KL-1 | Load-Bearing Element | - | 0,10W/m2K | Soojustus - Plastik Kõva | Soojustus - Plastik Kõva | 29,86 | 6 515 | New | Katuse soojustus
Soojustus - Plastik Kõva | KATUSEPLAAN | 1.13 IfcRoof (katus) (_RKAS BIM + ARCHICAD Classification); 4 FASSAADIELEMENDID JA KATUSED (EHITUSKULUDE LIIGITAMINE EVS 885:2005) | Soojustus - Plastik Kõva | REI-60 | Katus | -1,6mm PVCkatusekate (Näiteks Protan SE keevisliitega) -220mm Soojustus PIR (näiteks Recticel Powedeck) soojajuhtivustegur λDW/mK =0,031 -Aurutõke (SBS 3mm ) -265mm Ol.olev R/B paneel -siseviimistlus | KL-1 | Load-Bearing Element | - | 0,10W/m2K | Soojustus - Plastik Kõva | Soojustus - Plastik Kõva | 15,43 | 6 515 | New | Katuse soojustus
K2 | KATUSEPLAAN | 1.13 IfcRoof (katus) (_RKAS BIM + ARCHICAD Classification); 4 FASSAADIELEMENDID JA KATUSED (EHITUSKULUDE LIIGITAMINE EVS 885:2005) |  | REI-60 | Katus | -1,6mm PVCkatusekate (Näiteks Protan) -220mm Soojustus PIR (näiteks Recticel Powedeck) soojajuhtivustegur λDW/mK =0,031 -Aurutõke (SBS 3mm) -190mm ol.olev mullkukermiitplaat -70mm ol.olev R/B mon.betoon -siseviimistlus | KL-2 | Load-Bearing Element | - | 0,10W/m2K | K2 | Soojustus - Mineraal Pehme; Soojustus - Plastik Kõva | 9,64 | 5 883 | New | Katuse soojustus
Soojustus - Plastik Kõva | KATUSEPLAAN | 1.13 IfcRoof (katus) (_RKAS BIM + ARCHICAD Classification); 4 FASSAADIELEMENDID JA KATUSED (EHITUSKULUDE LIIGITAMINE EVS 885:2005) | Soojustus - Plastik Kõva | REI-60 | Katus | -1,6mm PVCkatusekate (Näiteks Protan SE keevisliitega) -220mm Soojustus PIR (näiteks Recticel Powedeck) soojajuhtivustegur λDW/mK =0,031 -Aurutõke (SBS 3mm ) -265mm Ol.olev R/B paneel -siseviimistlus | KL-1 | Load-Bearing Element | - | 0,10W/m2K | Soojustus - Plastik Kõva | Soojustus - Plastik Kõva | 18,37 | 6 515 | New | Katuse soojustus
Soojustus - Plastik Kõva | KATUSEPLAAN | 1.13 IfcRoof (katus) (_RKAS BIM + ARCHICAD Classification); 4 FASSAADIELEMENDID JA KATUSED (EHITUSKULUDE LIIGITAMINE EVS 885:2005) | Soojustus - Plastik Kõva | REI-60 | Katus | -1,6mm PVCkatusekate (Näiteks Protan SE keevisliitega) -220mm Soojustus PIR (näiteks Recticel Powedeck) soojajuhtivustegur λDW/mK =0,031 -Aurutõke (SBS 3mm ) -265mm Ol.olev R/B paneel -siseviimistlus | KL-1 | Load-Bearing Element | - | 0,10W/m2K | Soojustus - Plastik Kõva | Soojustus - Plastik Kõva | 27,16 | 6 515 | New | Katuse soojustus
Soojustus - Plastik Kõva | KATUSEPLAAN | 1.13 IfcRoof (katus) (_RKAS BIM + ARCHICAD Classification); 4 FASSAADIELEMENDID JA KATUSED (EHITUSKULUDE LIIGITAMINE EVS 885:2005) | Soojustus - Plastik Kõva | REI-60 | Katus | -1,6mm PVCkatusekate (Näiteks Protan SE keevisliitega) -220mm Soojustus PIR (näiteks Recticel Powedeck) soojajuhtivustegur λDW/mK =0,031 -Aurutõke (SBS 3mm ) -265mm Ol.olev R/B paneel -siseviimistlus | KL-1 | Load-Bearing Element | - | 0,10W/m2K | Soojustus - Plastik Kõva | Soojustus - Plastik Kõva | 34,96 | 6 515 | New | Katuse soojustus
Soojustus - Plastik Kõva | KATUSEPLAAN | 1.13 IfcRoof (katus) (_RKAS BIM + ARCHICAD Classification); 4 FASSAADIELEMENDID JA KATUSED (EHITUSKULUDE LIIGITAMINE EVS 885:2005) | Soojustus - Plastik Kõva | REI-60 | Katus | -1,6mm PVCkatusekate (Näiteks Protan SE keevisliitega) -220mm Soojustus PIR (näiteks Recticel Powedeck) soojajuhtivustegur λDW/mK =0,031 -Aurutõke (SBS 3mm ) -265mm Ol.olev R/B paneel -siseviimistlus | KL-1 | Load-Bearing Element | - | 0,10W/m2K | Soojustus - Plastik Kõva | Soojustus - Plastik Kõva | 30,43 | 6 515 | New | Katuse soojustus
Soojustus - Plastik Kõva | KATUSEPLAAN | 1.13 IfcRoof (katus) (_RKAS BIM + ARCHICAD Classification); 4 FASSAADIELEMENDID JA KATUSED (EHITUSKULUDE LIIGITAMINE EVS 885:2005) | Soojustus - Plastik Kõva | REI-60 | Katus | -1,6mm PVCkatusekate (Näiteks Protan SE keevisliitega) -220mm Soojustus PIR (näiteks Recticel Powedeck) soojajuhtivustegur λDW/mK =0,031 -Aurutõke (SBS 3mm ) -265mm Ol.olev R/B paneel -siseviimistlus | KL-1 | Load-Bearing Element | - | 0,10W/m2K | Soojustus - Plastik Kõva | Soojustus - Plastik Kõva | 31,49 | 6 515 | New | Katuse soojustus
Soojustus - Plastik Kõva | KATUSEPLAAN | 1.13 IfcRoof (katus) (_RKAS BIM + ARCHICAD Classification); 4 FASSAADIELEMENDID JA KATUSED (EHITUSKULUDE LIIGITAMINE EVS 885:2005) | Soojustus - Plastik Kõva | REI-60 | Katus | -1,6mm PVCkatusekate (Näiteks Protan SE keevisliitega) -220mm Soojustus PIR (näiteks Recticel Powedeck) soojajuhtivustegur λDW/mK =0,031 -Aurutõke (SBS 3mm ) -265mm Ol.olev R/B paneel -siseviimistlus | KL-1 | Load-Bearing Element | - | 0,10W/m2K | Soojustus - Plastik Kõva | Soojustus - Plastik Kõva | 18,23 | 6 515 | New | Katuse soojustus
Soojustus - Plastik Kõva | KATUSEPLAAN | 1.13 IfcRoof (katus) (_RKAS BIM + ARCHICAD Classification); 4 FASSAADIELEMENDID JA KATUSED (EHITUSKULUDE LIIGITAMINE EVS 885:2005) | Soojustus - Plastik Kõva | REI-60 | Katus | -1,6mm PVCkatusekate (Näiteks Protan SE keevisliitega) -220mm Soojustus PIR (näiteks Recticel Powedeck) soojajuhtivustegur λDW/mK =0,031 -Aurutõke (SBS 3mm ) -265mm Ol.olev R/B paneel -siseviimistlus | KL-1 | Load-Bearing Element | - | 0,10W/m2K | Soojustus - Plastik Kõva | Soojustus - Plastik Kõva | 21,23 | 6 515 | New | Katuse soojustus
Soojustus - Plastik Kõva | KATUSEPLAAN | 1.13 IfcRoof (katus) (_RKAS BIM + ARCHICAD Classification); 4 FASSAADIELEMENDID JA KATUSED (EHITUSKULUDE LIIGITAMINE EVS 885:2005) | Soojustus - Plastik Kõva | REI-60 | Katus | -1,6mm PVCkatusekate (Näiteks Protan SE keevisliitega) -220mm Soojustus PIR (näiteks Recticel Powedeck) soojajuhtivustegur λDW/mK =0,031 -Aurutõke (SBS 3mm ) -265mm Ol.olev R/B paneel -siseviimistlus | KL-1 | Load-Bearing Element | - | 0,10W/m2K | Soojustus - Plastik Kõva | Soojustus - Plastik Kõva | 12,52 | 6 515 | New | Katuse soojustus
Soojustus - Plastik Kõva | KATUSEPLAAN | 1.13 IfcRoof (katus) (_RKAS BIM + ARCHICAD Classification); 4 FASSAADIELEMENDID JA KATUSED (EHITUSKULUDE LIIGITAMINE EVS 885:2005) | Soojustus - Plastik Kõva | REI-60 | Katus | -1,6mm PVCkatusekate (Näiteks Protan SE keevisliitega) -220mm Soojustus PIR (näiteks Recticel Powedeck) soojajuhtivustegur λDW/mK =0,031 -Aurutõke (SBS 3mm ) -265mm Ol.olev R/B paneel -siseviimistlus | KL-1 | Load-Bearing Element | - | 0,10W/m2K | Soojustus - Plastik Kõva | Soojustus - Plastik Kõva | 17,48 | 6 515 | New | Katuse soojustus
K2 | KATUSEPLAAN | 1.13 IfcRoof (katus) (_RKAS BIM + ARCHICAD Classification); 4 FASSAADIELEMENDID JA KATUSED (EHITUSKULUDE LIIGITAMINE EVS 885:2005) |  | REI-60 | Katus | -1,6mm PVCkatusekate (Näiteks Protan) -220mm Soojustus PIR (näiteks Recticel Powedeck) soojajuhtivustegur λDW/mK =0,031 -Aurutõke (SBS 3mm) -190mm ol.olev mullkukermiitplaat -70mm ol.olev R/B mon.betoon -siseviimistlus | KL-2 | Load-Bearing Element | - | 0,10W/m2K | K2 | Soojustus - Mineraal Pehme; Soojustus - Plastik Kõva | 9,16 | 5 837 | New | Katuse soojustus
Soojustus - Plastik Kõva | KATUSEPLAAN | 1.13 IfcRoof (katus) (_RKAS BIM + ARCHICAD Classification); 4 FASSAADIELEMENDID JA KATUSED (EHITUSKULUDE LIIGITAMINE EVS 885:2005) | Soojustus - Plastik Kõva | REI-60 | Katus | -1,6mm PVCkatusekate (Näiteks Protan SE keevisliitega) -220mm Soojustus PIR (näiteks Recticel Powedeck) soojajuhtivustegur λDW/mK =0,031 -Aurutõke (SBS 3mm ) -265mm Ol.olev R/B paneel -siseviimistlus | KL-1 | Load-Bearing Element | - | 0,10W/m2K | Soojustus - Plastik Kõva | Soojustus - Plastik Kõva | 29,09 | 6 515 | New | Katuse soojustus
Soojustus - Plastik Kõva | KATUSEPLAAN | 1.13 IfcRoof (katus) (_RKAS BIM + ARCHICAD Classification); 4 FASSAADIELEMENDID JA KATUSED (EHITUSKULUDE LIIGITAMINE EVS 885:2005) | Soojustus - Plastik Kõva | REI-60 | Katus | -1,6mm PVCkatusekate (Näiteks Protan SE keevisliitega) -220mm Soojustus PIR (näiteks Recticel Powedeck) soojajuhtivustegur λDW/mK =0,031 -Aurutõke (SBS 3mm ) -265mm Ol.olev R/B paneel -siseviimistlus | KL-1 | Load-Bearing Element | - | 0,10W/m2K | Soojustus - Plastik Kõva | Soojustus - Plastik Kõva | 23,23 | 6 515 | New | Katuse soojustus
Soojustus - Plastik Kõva | KATUSEPLAAN | 1.13 IfcRoof (katus) (_RKAS BIM + ARCHICAD Classification); 4 FASSAADIELEMENDID JA KATUSED (EHITUSKULUDE LIIGITAMINE EVS 885:2005) | Soojustus - Plastik Kõva | REI-60 | Katus | -1,6mm PVCkatusekate (Näiteks Protan SE keevisliitega) -220mm Soojustus PIR (näiteks Recticel Powedeck) soojajuhtivustegur λDW/mK =0,031 -Aurutõke (SBS 3mm ) -265mm Ol.olev R/B paneel -siseviimistlus | KL-1 | Load-Bearing Element | - | 0,10W/m2K | Soojustus - Plastik Kõva | Soojustus - Plastik Kõva | 19,32 | 6 515 | New | Katuse soojustus
Soojustus - Plastik Kõva | KATUSEPLAAN | 1.13 IfcRoof (katus) (_RKAS BIM + ARCHICAD Classification); 4 FASSAADIELEMENDID JA KATUSED (EHITUSKULUDE LIIGITAMINE EVS 885:2005) | Soojustus - Plastik Kõva | REI-60 | Katus | -1,6mm PVCkatusekate (Näiteks Protan SE keevisliitega) -220mm Soojustus PIR (näiteks Recticel Powedeck) soojajuhtivustegur λDW/mK =0,031 -Aurutõke (SBS 3mm ) -265mm Ol.olev R/B paneel -siseviimistlus | KL-1 | Load-Bearing Element | - | 0,10W/m2K | Soojustus - Plastik Kõva | Soojustus - Plastik Kõva | 11,26 | 6 515 | New | Katuse soojustus
Soojustus - Plastik Kõva | KATUSEPLAAN | 1.13 IfcRoof (katus) (_RKAS BIM + ARCHICAD Classification); 4 FASSAADIELEMENDID JA KATUSED (EHITUSKULUDE LIIGITAMINE EVS 885:2005) | Soojustus - Plastik Kõva | REI-60 | Katus | -1,6mm PVCkatusekate (Näiteks Protan SE keevisliitega) -220mm Soojustus PIR (näiteks Recticel Powedeck) soojajuhtivustegur λDW/mK =0,031 -Aurutõke (SBS 3mm ) -265mm Ol.olev R/B paneel -siseviimistlus | KL-1 | Load-Bearing Element | - | 0,10W/m2K | Soojustus - Plastik Kõva | Soojustus - Plastik Kõva | 19,51 | 6 515 | New | Katuse soojustus
Soojustus - Plastik Kõva | KATUSEPLAAN | 1.13 IfcRoof (katus) (_RKAS BIM + ARCHICAD Classification); 4 FASSAADIELEMENDID JA KATUSED (EHITUSKULUDE LIIGITAMINE EVS 885:2005) | Soojustus - Plastik Kõva | REI-60 | Katus | -1,6mm PVCkatusekate (Näiteks Protan SE keevisliitega) -220mm Soojustus PIR (näiteks Recticel Powedeck) soojajuhtivustegur λDW/mK =0,031 -Aurutõke (SBS 3mm ) -265mm Ol.olev R/B paneel -siseviimistlus | KL-1 | Load-Bearing Element | - | 0,10W/m2K | Soojustus - Plastik Kõva | Soojustus - Plastik Kõva | 39,04 | 6 515 | New | Katuse soojustus
Soojustus - Plastik Kõva | KATUSEPLAAN | 1.13 IfcRoof (katus) (_RKAS BIM + ARCHICAD Classification); 4 FASSAADIELEMENDID JA KATUSED (EHITUSKULUDE LIIGITAMINE EVS 885:2005) | Soojustus - Plastik Kõva | REI-60 | Katus | -1,6mm PVCkatusekate (Näiteks Protan SE keevisliitega) -220mm Soojustus PIR (näiteks Recticel Powedeck) soojajuhtivustegur λDW/mK =0,031 -Aurutõke (SBS 3mm ) -265mm Ol.olev R/B paneel -siseviimistlus | KL-1 | Load-Bearing Element | - | 0,10W/m2K | Soojustus - Plastik Kõva | Soojustus - Plastik Kõva | 30,91 | 6 515 | New | Katuse soojustus
Soojustus - Plastik Kõva | KATUSEPLAAN | 1.13 IfcRoof (katus) (_RKAS BIM + ARCHICAD Classification); 4 FASSAADIELEMENDID JA KATUSED (EHITUSKULUDE LIIGITAMINE EVS 885:2005) | Soojustus - Plastik Kõva | REI-60 | Katus | -1,6mm PVCkatusekate (Näiteks Protan SE keevisliitega) -220mm Soojustus PIR (näiteks Recticel Powedeck) soojajuhtivustegur λDW/mK =0,031 -Aurutõke (SBS 3mm ) -265mm Ol.olev R/B paneel -siseviimistlus | KL-1 | Load-Bearing Element | - | 0,10W/m2K | Soojustus - Plastik Kõva | Soojustus - Plastik Kõva | 32,84 | 6 515 | New | Katuse soojustus
Betoon - Ol.Olev konstruktsioon | KATUSEPLAAN | 33 Vahe- ja katuslaed (EHITUSKULUDE LIIGITAMINE EVS 885:2005); 1.13 IfcRoof (katus) (_RKAS BIM + ARCHICAD Classification) | Betoon - Ol.Olev konstruktsioon |  | Betoon - Ol.Olev konstruktsioon | Betoon - Ol.Olev konstruktsioon | Ol.Olev katus | Load-Bearing Element |  |  | Betoon - Ol.Olev konstruktsioon | Betoon - Ol.Olev konstruktsioon | 6,61 | 5 960 | Existing
Betoon - Ol.Olev konstruktsioon | KATUSEPLAAN | 33 Vahe- ja katuslaed (EHITUSKULUDE LIIGITAMINE EVS 885:2005); 1.13 IfcRoof (katus) (_RKAS BIM + ARCHICAD Classification) | Betoon - Ol.Olev konstruktsioon |  | Betoon - Ol.Olev konstruktsioon | Betoon - Ol.Olev konstruktsioon | Ol.Olev katus | Load-Bearing Element |  |  | Betoon - Ol.Olev konstruktsioon | Betoon - Ol.Olev konstruktsioon | 133,92 | 6 515 | Existing
Betoon - Ol.Olev konstruktsioon | KATUSEPLAAN | 33 Vahe- ja katuslaed (EHITUSKULUDE LIIGITAMINE EVS 885:2005); 1.13 IfcRoof (katus) (_RKAS BIM + ARCHICAD Classification) | Betoon - Ol.Olev konstruktsioon |  | Betoon - Ol.Olev konstruktsioon | Betoon - Ol.Olev konstruktsioon | Ol.Olev katus | Load-Bearing Element |  |  | Betoon - Ol.Olev konstruktsioon | Betoon - Ol.Olev konstruktsioon | 6,88 | 5 946 | Existing
Betoon - Ol.Olev konstruktsioon | KATUSEPLAAN | 33 Vahe- ja katuslaed (EHITUSKULUDE LIIGITAMINE EVS 885:2005); 1.13 IfcRoof (katus) (_RKAS BIM + ARCHICAD Classification) | Betoon - Ol.Olev konstruktsioon | REI-60 | Betoon - Ol.Olev konstruktsioon | Betoon - Ol.Olev konstruktsioon | Ol.Olev katus | Load-Bearing Element | - | 0,10 W/m2K | Betoon - Ol.Olev konstruktsioon | Betoon - Ol.Olev konstruktsioon | 233,54 | 6 515 | Existing
Betoon - Ol.Olev konstruktsioon | KATUSEPLAAN | 33 Vahe- ja katuslaed (EHITUSKULUDE LIIGITAMINE EVS 885:2005); 1.13 IfcRoof (katus) (_RKAS BIM + ARCHICAD Classification) | Betoon - Ol.Olev konstruktsioon |  | Betoon - Ol.Olev konstruktsioon | Betoon - Ol.Olev konstruktsioon | Ol.Olev katus | Load-Bearing Element |  |  | Betoon - Ol.Olev konstruktsioon | Betoon - Ol.Olev konstruktsioon | 71,21 | 6 515 | Existing

# IfcSlab: P-1, Betoon - Ol.Olev konstruktsioon
In: VUNDAMENT
Type - ElementType: Element type P-1; PredefinedType: FLOOR
Classification: 1.14 IfcSlab (vahelagi) (_RKAS BIM + ARCHICAD Classification); 23 Aluspõrandad (EHITUSKULUDE LIIGITAMINE EVS 885:2005); Material: Betoon - Ol.Olev konstruktsioon 350 mm
Arhitektuur - 04 Tulepüsivus: REI-60; 01 Nimetus: Betoon - Ol.Olev konstruktsioon; 02 Materjal: Betoon - Ol.Olev konstruktsioon; 03 Tähistus: P-1; 05 Asukoht: Exterior; 06 Kandevelementide eristatus: Load-Bearing Element; 07 Helipidavus: -; 08 Soojusläbivus (U-arv): 1W/m2K
Ehituskonstruktsioonid - 01 Nimetus: Betoon - Ol.Olev konstruktsioon; 02 Materjal: Betoon - Ol.Olev konstruktsioon; 03 Tähistus või ristlõige: P-1; 06 Maht (kubatuur): 659,11; 12 Alumine kõrgusmärk: 0
AC_Pset_RenovationAndPhasing - Renovation Status: Existing
Pset_SlabCommon - LoadBearing: yes; IsExternal: yes

# IfcSlab: P-4 (2)
In: 2 KORRUS
Type - ElementType: Element type P-4; PredefinedType: FLOOR
Classification: 33 Vahe- ja katuslaed (EHITUSKULUDE LIIGITAMINE EVS 885:2005); 2.13 IfcSlab (vahelagi) (_RKAS BIM + ARCHICAD Classification)
Arhitektuur - 01 Nimetus: Kivi - Uus Konstruktsioon; 02 Materjal: Kivi - Uus Konstruktsioon; 03 Tähistus: P-4; 05 Asukoht: Exterior; 06 Kandevelementide eristatus: Non-Load-Bearing Element
Ehituskonstruktsioonid - 01 Nimetus: Kivi - Uus Konstruktsioon; 02 Materjal: Kivi - Uus Konstruktsioon; 03 Tähistus või ristlõige: P-4; 04 Materjali peamine tugevusnäitaja: -; 05 Keskkonnaklass: -; 06 Maht (kubatuur): 2,51; 07 Monteeritava elemendi mass: Undefined; 08 Monteeritava elemendi pikkus: ; Undefined; 09 Monteeritava elemendi positisioon/mark: Undefined; 10 Elemendi valmistamise tehnoloogia: Undefined
AC_Pset_RenovationAndPhasing - Renovation Status: New
Pset_SlabCommon - LoadBearing: no; IsExternal: yes
Name | Material | 11 Ülemine kõrgusmärk | 12 Alumine kõrgusmärk
Kivi - Uus Konstruktsioon | Kivi - Uus Konstruktsioon 80 mm | 3 000; Kõrgus: 80; Täpsustus: Undefined | 3 000
Kivi - Uus Konstruktsioon | Kivi - Uus Konstruktsioon 150 mm | 2 545; Kõrgus: 150; Täpsustus: Undefined | 2 545

# IfcSlab: SLA - 003 (3)
In: 2 KORRUS
Type - ElementType: Element type SLA - 003; PredefinedType: FLOOR
Classification: 33 Vahe- ja katuslaed (EHITUSKULUDE LIIGITAMINE EVS 885:2005); 2.13 IfcSlab (vahelagi) (_RKAS BIM + ARCHICAD Classification); Material: Betoon - Ol.Olev konstruktsioon 400 mm
Arhitektuur - 01 Nimetus: Betoon - Ol.Olev konstruktsioon; 02 Materjal: Betoon - Ol.Olev konstruktsioon; 03 Tähistus: SLA - 003; 05 Asukoht: Interior; 06 Kandevelementide eristatus: Load-Bearing Element
Ehituskonstruktsioonid - 01 Nimetus: Betoon - Ol.Olev konstruktsioon; 02 Materjal: Betoon - Ol.Olev konstruktsioon; 03 Tähistus või ristlõige: SLA - 003; 04 Materjali peamine tugevusnäitaja: Undefined; 05 Keskkonnaklass: Undefined; 07 Monteeritava elemendi mass: Undefined; 08 Monteeritava elemendi pikkus: ; Undefined; 09 Monteeritava elemendi positisioon/mark: Undefined; 10 Elemendi valmistamise tehnoloogia: Undefined; 11 Ülemine kõrgusmärk: 3 000; Kõrgus: 400; Täpsustus: Undefined; 12 Alumine kõrgusmärk: 3 000
AC_Pset_RenovationAndPhasing - Renovation Status: Existing
Pset_SlabCommon - LoadBearing: yes; IsExternal: no
Name | 06 Maht (kubatuur)
Betoon - Ol.Olev konstruktsioon | 104,64
Betoon - Ol.Olev konstruktsioon | 6,94
Betoon - Ol.Olev konstruktsioon | 404,86

# IfcSlab: VL-1, Betoon - Ol.Olev konstruktsioon
In: 2 KORRUS
Type - ElementType: Element type VL-1; PredefinedType: FLOOR
Classification: 33 Vahe- ja katuslaed (EHITUSKULUDE LIIGITAMINE EVS 885:2005); 2.13 IfcSlab (vahelagi) (_RKAS BIM + ARCHICAD Classification); Material: Betoon - Ol.Olev konstruktsioon 400 mm
Arhitektuur - 01 Nimetus: Betoon - Ol.Olev konstruktsioon; 02 Materjal: Betoon - Ol.Olev konstruktsioon; 03 Tähistus: VL-1; 05 Asukoht: Interior; 06 Kandevelementide eristatus: Load-Bearing Element
Ehituskonstruktsioonid - 01 Nimetus: Betoon - Ol.Olev konstruktsioon; 02 Materjal: Betoon - Ol.Olev konstruktsioon; 03 Tähistus või ristlõige: VL-1; 04 Materjali peamine tugevusnäitaja: Undefined; 05 Keskkonnaklass: Undefined; 06 Maht (kubatuur): 199,24; 07 Monteeritava elemendi mass: Undefined; 08 Monteeritava elemendi pikkus: ; Undefined; 09 Monteeritava elemendi positisioon/mark: Undefined; 10 Elemendi valmistamise tehnoloogia: Undefined; 11 Ülemine kõrgusmärk: 3 000; Kõrgus: 400; Täpsustus: Undefined; 12 Alumine kõrgusmärk: 3 000
AC_Pset_RenovationAndPhasing - Renovation Status: Existing
Pset_SlabCommon - LoadBearing: yes; IsExternal: no

# IfcStair (20)
Name | In | Description | Classification | IsExternal | 02 Materjal | 03 Tähistus või ristlõige | 06 Maht (kubatuur) | 12 Alumine kõrgusmärk | Renovation Status
TR 7 | 1 KORRUS | raudbetoon | 1.16 IfcStair (trepp) (_RKAS BIM + ARCHICAD Classification) | yes | Betoon - Ol.Olev konstruktsioon | TR 7 | 4,98 | 0 | New | ShapeType: STRAIGHT_RUN_STAIR; Pset_StairCommon - NumberOfRiser: 13; NumberOfTreads: 13; RiserHeight: 169.231 mm; RequiredHeadroom: 2200 mm
Betoon - Ol.Olev konstruktsioon | 1 KORRUS |  | 1.16 IfcStair (trepp) (_RKAS BIM + ARCHICAD Classification) |  | Betoon - Ol.Olev konstruktsioon | SLA - 002 | 0,15 | -90 | Existing | Material: Betoon - Ol.Olev konstruktsioon
FU - 001 | 1 KORRUS | teras | 1.16 IfcStair (trepp) (_RKAS BIM + ARCHICAD Classification); 143 Välistrepid (EHITUSKULUDE LIIGITAMINE EVS 885:2005) | yes |  | Redel | 0,01 | 0 | Existing
Betoon - Ol.Olev konstruktsioon | 1 KORRUS |  | 1.16 IfcStair (trepp) (_RKAS BIM + ARCHICAD Classification) | yes | Betoon - Ol.Olev konstruktsioon | SLA - 002 | 1,69 | 0 | Existing | Material: Betoon - Ol.Olev konstruktsioon
STAIR - 003 | 1 KORRUS |  | 1.16 IfcStair (trepp) (_RKAS BIM + ARCHICAD Classification) |  | Betoon - Ol.Olev konstruktsioon | STAIR - 003 | 3,70 | 0 | Existing | Pset_StairCommon - NumberOfRiser: 16; NumberOfTreads: 16; RiserHeight: 187.5 mm; RequiredHeadroom: 2200 mm
2 x STAIR - 001 | 1 KORRUS |  | 1.16 IfcStair (trepp) (_RKAS BIM + ARCHICAD Classification) |  | Betoon - Ol.Olev konstruktsioon | STAIR - 001 | 2,25 | 0 | Existing | Pset_StairCommon - NumberOfRiser: 17; NumberOfTreads: 17; RiserHeight: 176.471 mm; RequiredHeadroom: 2200 mm
Air Space | 1 KORRUS |  | 1.16 IfcStair (trepp) (_RKAS BIM + ARCHICAD Classification) | yes |  | OO TR3 | 0,60 | 0 | Existing | Pset_StairCommon - NumberOfRiser: 15; NumberOfTreads: 0; RiserHeight: 160 mm; RequiredHeadroom: 0 mm; TreadLength: 300 mm
Betoon - Ol.Olev konstruktsioon | 1 KORRUS |  | 1.16 IfcStair (trepp) (_RKAS BIM + ARCHICAD Classification) | yes | Betoon - Ol.Olev konstruktsioon | SLA - 002 | 5,13 | 0 | Existing | Material: Betoon - Ol.Olev konstruktsioon
FU - 001 | 2 KORRUS | teras | 1.16 IfcStair (trepp) (_RKAS BIM + ARCHICAD Classification); 143 Välistrepid (EHITUSKULUDE LIIGITAMINE EVS 885:2005) | yes |  | Redel | 0,03 | 3 000 | New
STAIR - 001 | 2 KORRUS |  | 1.16 IfcStair (trepp) (_RKAS BIM + ARCHICAD Classification) |  | Betoon - Ol.Olev konstruktsioon | STAIR - 001 | 2,93 | 3 000 | Existing | Pset_StairCommon - NumberOfRiser: 15; NumberOfTreads: 14; RiserHeight: 171.8 mm; RequiredHeadroom: 2200 mm
Betoon - Ol.Olev konstruktsioon | 2 KORRUS | Raudbetoon | 1.16 IfcStair (trepp) (_RKAS BIM + ARCHICAD Classification) | yes | Betoon - Ol.Olev konstruktsioon | MADE TR5 | 0,26 | 3 000 | New | Material: Betoon - Ol.Olev konstruktsioon
Air Space | 2 KORRUS | raudbetoon | 1.16 IfcStair (trepp) (_RKAS BIM + ARCHICAD Classification) | yes |  | TR 3 | 0,17 | 2 221 | Existing | Pset_StairCommon - NumberOfRiser: 5; NumberOfTreads: 0; RiserHeight: 155.838 mm; RequiredHeadroom: 0 mm; TreadLength: 308.324 mm
Betoon - Ol.Olev konstruktsioon | 2 KORRUS | Raudbetoon | 1.16 IfcStair (trepp) (_RKAS BIM + ARCHICAD Classification) | yes | Betoon - Ol.Olev konstruktsioon | MADE TR6 | 0,26 | 3 000 | New | Material: Betoon - Ol.Olev konstruktsioon
Air Space | 2 KORRUS | raudbetoon | 1.16 IfcStair (trepp) (_RKAS BIM + ARCHICAD Classification) | yes |  | TR 6 | 0,13 | 2 400 | Existing | Pset_StairCommon - NumberOfRiser: 4; NumberOfTreads: 0; RiserHeight: 150 mm; RequiredHeadroom: 0 mm; TreadLength: 320 mm
STAIR - 002 | 2 KORRUS |  | 1.16 IfcStair (trepp) (_RKAS BIM + ARCHICAD Classification) |  | Betoon - Ol.Olev konstruktsioon | STAIR - 002 | 0,90 | 2 130 | Existing | Pset_StairCommon - NumberOfRiser: 4; NumberOfTreads: 4; RiserHeight: 217.5 mm; RequiredHeadroom: 2200 mm
4 x FU - 001 | KATUSEPLAAN | teras | 1.16 IfcStair (trepp) (_RKAS BIM + ARCHICAD Classification); 143 Välistrepid (EHITUSKULUDE LIIGITAMINE EVS 885:2005) | yes |  | Redel | 0,02 | 6 084 | New

# IfcWall: P-4, VS3 krohv
In: 1 KORRUS
Type - ElementType: Element type P-4
Classification: 1.18 IfcWall (sein) (_RKAS BIM + ARCHICAD Classification); 32 Kandvad ja välisseinad (EHITUSKULUDE LIIGITAMINE EVS 885:2005)
Arhitektuur - 04 Tulepüsivus: REI-60; 01 Nimetus: VS3 krohv; 02 Materjal: Krohv - Õhekrohv; Soojustus - Plastik Kõva; Kivi - Ol.Olev Konstruktsioon; 03 Tähistus: P-4; 05 Asukoht: Exterior; 06 Kandevelementide eristatus: Load-Bearing Element; 07 Helipidavus: 35dB; 08 Soojusläbivus (U-arv): 0,15 W/m2K
Ehituskonstruktsioonid - 01 Nimetus: VS3 krohv; 02 Materjal: Krohv - Õhekrohv; Soojustus - Plastik Kõva; Kivi - Ol.Olev Konstruktsioon; 03 Tähistus või ristlõige: P-4; 06 Maht (kubatuur): 17,67; 11 Ülemine kõrgusmärk: 1 000; Kõrgus: 1 920; 3D pikkus: 11 541; 12 Alumine kõrgusmärk: 1 000
AC_Pset_RenovationAndPhasing - Renovation Status: New
Pset_WallCommon - LoadBearing: yes; IsExternal: yes

# IfcWall: SS-1 (2)
In: 2 KORRUS
Type - ElementType: Element type SS-1
Classification: 2.15 IfcWall (sein) (_RKAS BIM + ARCHICAD Classification); 51 Vaheseinad (EHITUSKULUDE LIIGITAMINE EVS 885:2005); Material: Kivi - Uus Konstruktsioon
Arhitektuur - 02 Materjal: 2xkipsplaat (Gyproc GKF15) -66mm Karkasspostid XR66 (s-600mm)+mineraalvill 70mm -plekiribad; 01 Nimetus: sahti sein; 03 Tähistus: SS-1; 05 Asukoht: Interior; 06 Kandevelementide eristatus: Non-Load-Bearing Element
Ehituskonstruktsioonid - 01 Nimetus: sahti sein; 02 Materjal: 2xkipsplaat (Gyproc GKF15) -66mm Karkasspostid XR66 (s-600mm)+mineraalvill 70mm -plekiribad; 03 Tähistus või ristlõige: SS-1; 04 Materjali peamine tugevusnäitaja: Undefined; 05 Keskkonnaklass: Undefined; 07 Monteeritava elemendi mass: Undefined; 09 Monteeritava elemendi positisioon/mark: Undefined; 10 Elemendi valmistamise tehnoloogia: Undefined; 12 Alumine kõrgusmärk: 3 000
AC_Pset_RenovationAndPhasing - Renovation Status: New
Pset_WallCommon - LoadBearing: no; IsExternal: no
Name | 06 Maht (kubatuur) | 08 Monteeritava elemendi pikkus | 11 Ülemine kõrgusmärk
sahti sein | 1,76 | 2 515; Undefined | 3 000; Kõrgus: 5 403; 3D pikkus: 2 515
sahti sein | 1,31 | 2 132; Undefined | 3 000; Kõrgus: 4 109; 3D pikkus: 2 132

# IfcWall: SS-3 (5)
In: 1 KORRUS
Type - ElementType: Element type SS-3
Classification: 2.15 IfcWall (sein) (_RKAS BIM + ARCHICAD Classification); 51 Vaheseinad (EHITUSKULUDE LIIGITAMINE EVS 885:2005)
Arhitektuur - 01 Nimetus: SS-3; 02 Materjal: Puitplaat; Air Space; Puitplaat; 03 Tähistus: SS-3; 05 Asukoht: Interior; 06 Kandevelementide eristatus: Non-Load-Bearing Element
Ehituskonstruktsioonid - 01 Nimetus: SS-3; 02 Materjal: Puitplaat; Air Space; Puitplaat; 03 Tähistus või ristlõige: SS-3; 04 Materjali peamine tugevusnäitaja: -; 05 Keskkonnaklass: -; 07 Monteeritava elemendi mass: -; 09 Monteeritava elemendi positisioon/mark: -; 10 Elemendi valmistamise tehnoloogia: Undefined; 12 Alumine kõrgusmärk: 0
AC_Pset_RenovationAndPhasing - Renovation Status: New
Pset_WallCommon - LoadBearing: no; IsExternal: no
Name | 06 Maht (kubatuur) | 08 Monteeritava elemendi pikkus | 11 Ülemine kõrgusmärk
SS-3 | 0,44 | 1 985; - | 0; Kõrgus: 2 600; 3D pikkus: 1 985
SS-3 | 0,60 | 2 697; - | 0; Kõrgus: 2 600; 3D pikkus: 2 697
SS-3 | 0,43 | 1 935; - | 0; Kõrgus: 2 600; 3D pikkus: 1 935
SS-3 | 0,19 | 837; - | 0; Kõrgus: 2 600; 3D pikkus: 837
SS-3 | 0,22 | 1 010; - | 0; Kõrgus: 2 600; 3D pikkus: 1 010

# IfcWall: SW - 022 (7)
Type - ElementType: Element type SW - 022
Material: Kivi -Ol.Olev Konstruktsioon
Arhitektuur - 07 Helipidavus: -; 08 Soojusläbivus (U-arv): -; 04 Tulepüsivus: -; 01 Nimetus: ol.olev ss 420; 02 Materjal: Kivi -Ol.Olev Konstruktsioon; 03 Tähistus: SW - 022; 05 Asukoht: Interior; 06 Kandevelementide eristatus: Load-Bearing Element
Ehituskonstruktsioonid - 01 Nimetus: ol.olev ss 420; 02 Materjal: Kivi -Ol.Olev Konstruktsioon; 03 Tähistus või ristlõige: SW - 022
AC_Pset_RenovationAndPhasing - Renovation Status: Existing
Pset_WallCommon - LoadBearing: yes; IsExternal: no
Name | In | Classification | 04 Materjali peamine tugevusnäitaja = 05 Keskkonnaklass = 07 Monteeritava elemendi mass = 09 Monteeritava elemendi positisioon/mark = 10 Elemendi valmistamise tehnoloogia | 06 Maht (kubatuur) | 08 Monteeritava elemendi pikkus | 11 Ülemine kõrgusmärk | 12 Alumine kõrgusmärk
ol.olev ss 420 | 1 KORRUS | 32 Kandvad ja välisseinad (EHITUSKULUDE LIIGITAMINE EVS 885:2005); 2.15 IfcWall (sein) (_RKAS BIM + ARCHICAD Classification) | Undefined | 7,80 | 8 756; Undefined | 0; Kõrgus: 2 600; 3D pikkus: 8 756 | 0
ol.olev ss 420 | 1 KORRUS | 32 Kandvad ja välisseinad (EHITUSKULUDE LIIGITAMINE EVS 885:2005); 2.15 IfcWall (sein) (_RKAS BIM + ARCHICAD Classification) | Undefined | 1,56 | 2 923; Undefined | 0; Kõrgus: 2 600; 3D pikkus: 2 923 | 0
ol.olev ss 420 | 1 KORRUS | 32 Kandvad ja välisseinad (EHITUSKULUDE LIIGITAMINE EVS 885:2005); 2.15 IfcWall (sein) (_RKAS BIM + ARCHICAD Classification) | Undefined | 33,56 | 36 428; Undefined | 0; Kõrgus: 2 600; 3D pikkus: 36 428 | 0
ol.olev ss 420 | 2 KORRUS | 32 Kandvad ja välisseinad (EHITUSKULUDE LIIGITAMINE EVS 885:2005); 2.15 IfcWall (sein) (_RKAS BIM + ARCHICAD Classification) | Undefined | 24,38 | 21 323; Undefined | 3 000; Kõrgus: 3 250; 3D pikkus: 21 323 | 3 000
ol.olev ss 420 | 2 KORRUS | 32 Kandvad ja välisseinad (EHITUSKULUDE LIIGITAMINE EVS 885:2005); 2.15 IfcWall (sein) (_RKAS BIM + ARCHICAD Classification) | Undefined | 28,63 | 24 152; Undefined | 3 000; Kõrgus: 3 250; 3D pikkus: 24 152 | 3 000
ol.olev ss 420 | 2 KORRUS | 1.18 IfcWall (sein) (_RKAS BIM + ARCHICAD Classification); 32 Kandvad ja välisseinad (EHITUSKULUDE LIIGITAMINE EVS 885:2005) |  | 0,96 |  | 3 000; Kõrgus: 4 000; 3D pikkus: 650 | 3 000
ol.olev ss 420 | 2 KORRUS | 1.18 IfcWall (sein) (_RKAS BIM + ARCHICAD Classification); 32 Kandvad ja välisseinad (EHITUSKULUDE LIIGITAMINE EVS 885:2005) |  | 0,97 |  | 3 000; Kõrgus: 4 000; 3D pikkus: 1 080 | 3 000

# IfcWall: SW - 036 (2)
In: 1 KORRUS
Type - ElementType: Element type SW - 036
Classification: 2.15 IfcWall (sein) (_RKAS BIM + ARCHICAD Classification); 51 Vaheseinad (EHITUSKULUDE LIIGITAMINE EVS 885:2005); Material: Kivi -Ol.Olev Konstruktsioon
Arhitektuur - 01 Nimetus: ol.olev ss 150; 02 Materjal: Kivi -Ol.Olev Konstruktsioon; 03 Tähistus: SW - 036; 05 Asukoht: Interior; 06 Kandevelementide eristatus: Non-Load-Bearing Element
Ehituskonstruktsioonid - 01 Nimetus: ol.olev ss 150; 02 Materjal: Kivi -Ol.Olev Konstruktsioon; 03 Tähistus või ristlõige: SW - 036; 04 Materjali peamine tugevusnäitaja: Undefined; 05 Keskkonnaklass: Undefined; 07 Monteeritava elemendi mass: Undefined; 09 Monteeritava elemendi positisioon/mark: Undefined; 10 Elemendi valmistamise tehnoloogia: Undefined; 12 Alumine kõrgusmärk: 0
AC_Pset_RenovationAndPhasing - Renovation Status: Existing
Pset_WallCommon - LoadBearing: no; IsExternal: no
Name | 06 Maht (kubatuur) | 08 Monteeritava elemendi pikkus | 11 Ülemine kõrgusmärk
ol.olev ss 150 | 0,56 | 2 149; Undefined | 0; Kõrgus: 2 298; 3D pikkus: 2 149
ol.olev ss 150 | 0,68 | 2 511; Undefined | 0; Kõrgus: 2 600; 3D pikkus: 2 511

# IfcWall: SW - 037, ol.olev ss 150
In: 1 KORRUS
Type - ElementType: Element type SW - 037
Classification: 2.15 IfcWall (sein) (_RKAS BIM + ARCHICAD Classification); 51 Vaheseinad (EHITUSKULUDE LIIGITAMINE EVS 885:2005); Material: Kivi -Ol.Olev Konstruktsioon
Arhitektuur - 01 Nimetus: ol.olev ss 150; 02 Materjal: Kivi -Ol.Olev Konstruktsioon; 03 Tähistus: SW - 037; 05 Asukoht: Interior; 06 Kandevelementide eristatus: Non-Load-Bearing Element
Ehituskonstruktsioonid - 01 Nimetus: ol.olev ss 150; 02 Materjal: Kivi -Ol.Olev Konstruktsioon; 03 Tähistus või ristlõige: SW - 037; 04 Materjali peamine tugevusnäitaja: Undefined; 05 Keskkonnaklass: Undefined; 06 Maht (kubatuur): 1,19; 07 Monteeritava elemendi mass: Undefined; 08 Monteeritava elemendi pikkus: 2 150; Undefined; 09 Monteeritava elemendi positisioon/mark: Undefined; 10 Elemendi valmistamise tehnoloogia: Undefined; 11 Ülemine kõrgusmärk: 0; Kõrgus: 4 200; 3D pikkus: 2 150; 12 Alumine kõrgusmärk: 0
AC_Pset_RenovationAndPhasing - Renovation Status: Existing
Pset_WallCommon - LoadBearing: no; IsExternal: no

# IfcWall: TR4 soojusus
In: 2 KORRUS
Type - ElementType: Element type TR4 soojusus
Description: Soojustus; Classification: 1.18 IfcWall (sein) (_RKAS BIM + ARCHICAD Classification); 32 Kandvad ja välisseinad (EHITUSKULUDE LIIGITAMINE EVS 885:2005); Material: Soojustus - Plastik Kõva
Arhitektuur - 04 Tulepüsivus: REI-60; 08 Soojusläbivus (U-arv): 0,15 w/m2K; 07 Helipidavus: 35dB; 03 Tähistus: TR4 soojusus; 01 Nimetus: TR4 soojusus; 02 Materjal: Soojustus - Plastik Kõva; 05 Asukoht: Exterior; 06 Kandevelementide eristatus: Non-Load-Bearing Element
Ehituskonstruktsioonid - 01 Nimetus: TR4 soojusus; 02 Materjal: Soojustus - Plastik Kõva; 03 Tähistus või ristlõige: TR4 soojusus; 06 Maht (kubatuur): 0,48; 11 Ülemine kõrgusmärk: 2 602; Kõrgus: 4 378; 3D pikkus: 1 299; 12 Alumine kõrgusmärk: 2 602
AC_Pset_RenovationAndPhasing - Renovation Status: New
Pset_WallCommon - LoadBearing: no; IsExternal: yes

# IfcWall: VS-2 (6)
In: 1 KORRUS
Type - ElementType: Element type VS-2
Classification: 1.18 IfcWall (sein) (_RKAS BIM + ARCHICAD Classification); 32 Kandvad ja välisseinad (EHITUSKULUDE LIIGITAMINE EVS 885:2005)
Arhitektuur - 04 Tulepüsivus: REI-60; 01 Nimetus: VS2 paekivi; 02 Materjal: Kivi - Viimistlus; Soojustus - Plastik Kõva; Kivi - Ol.Olev Konstruktsioon; 03 Tähistus: VS-2; 05 Asukoht: Exterior; 06 Kandevelementide eristatus: Load-Bearing Element; 07 Helipidavus: 35dB
Ehituskonstruktsioonid - 01 Nimetus: VS2 paekivi; 02 Materjal: Kivi - Viimistlus; Soojustus - Plastik Kõva; Kivi - Ol.Olev Konstruktsioon; 03 Tähistus või ristlõige: VS-2
AC_Pset_RenovationAndPhasing - Renovation Status: Existing
Pset_WallCommon - LoadBearing: yes; IsExternal: yes
Name | 08 Soojusläbivus (U-arv) | 06 Maht (kubatuur) | 11 Ülemine kõrgusmärk | 12 Alumine kõrgusmärk
VS2 paekivi | 0,15w/m2K | 0,37 | 0; Kõrgus: 2 600; 3D pikkus: 531 | 0
VS2 paekivi | 0,15w/m2K | 5,28 | 0; Kõrgus: 2 600; 3D pikkus: 2 515 | 0
VS2 paekivi | 0,15w/m2K | 38,03 | 0; Kõrgus: 2 600; 3D pikkus: 18 624 | 0
VS2 paekivi | 0,15w/m2K | 11,55 | 0; Kõrgus: 2 600; 3D pikkus: 5 981 | 0
VS2 paekivi | 0,15w/m2K | 11,16 | 0; Kõrgus: 2 600; 3D pikkus: 5 545 | 0
VS2 paekivi | 0,15W/m2K | 97,38 | -1 000; Kõrgus: 3 600; 3D pikkus: 43 841 | -1 000

# IfcWall: VS-3 (12)
In: 1 KORRUS
Type - ElementType: Element type VS-3
Classification: 1.18 IfcWall (sein) (_RKAS BIM + ARCHICAD Classification); 32 Kandvad ja välisseinad (EHITUSKULUDE LIIGITAMINE EVS 885:2005)
Arhitektuur - 04 Tulepüsivus: REI-60; 01 Nimetus: VS3 krohv; 02 Materjal: Krohv - Õhekrohv; Soojustus - Plastik Kõva; Kivi - Ol.Olev Konstruktsioon; 03 Tähistus: VS-3; 05 Asukoht: Exterior; 06 Kandevelementide eristatus: Load-Bearing Element; 07 Helipidavus: 35dB; 08 Soojusläbivus (U-arv): 0,15 W/m2K
Ehituskonstruktsioonid - 01 Nimetus: VS3 krohv; 02 Materjal: Krohv - Õhekrohv; Soojustus - Plastik Kõva; Kivi - Ol.Olev Konstruktsioon; 03 Tähistus või ristlõige: VS-3
AC_Pset_RenovationAndPhasing - Renovation Status: Existing
Pset_WallCommon - LoadBearing: yes; IsExternal: yes
Name | 06 Maht (kubatuur) | 11 Ülemine kõrgusmärk | 12 Alumine kõrgusmärk
VS3 krohv | 194,29 | -1 000; Kõrgus: 3 600; 3D pikkus: 86 892 | -1 000
VS3 krohv | 44,08 | 0; Kõrgus: 2 600; 3D pikkus: 30 248 | 0
VS3 krohv | 26,45 | 0; Kõrgus: 2 600; 3D pikkus: 13 212 | 0
VS3 krohv | 28,62 | 0; Kõrgus: 3 000; 3D pikkus: 12 366 | 0
VS3 krohv | 28,89 | 0; Kõrgus: 3 000; 3D pikkus: 12 376 | 0
VS3 krohv | 25,77 | 0; Kõrgus: 2 600; 3D pikkus: 12 889 | 0
VS3 krohv | 17,76 | 1 000; Kõrgus: 2 000; 3D pikkus: 11 533 | 1 000
VS3 krohv | 0,26 | 1 000; Kõrgus: 1 600; 3D pikkus: 701 | 1 000
VS3 krohv | 24,93 | 659; Kõrgus: 2 341; 3D pikkus: 13 455 | 659
VS3 krohv | 5,63 | 0; Kõrgus: 2 600; 3D pikkus: 3 463 | 0
VS3 krohv | 134,51 | 0; Kõrgus: 2 600; 3D pikkus: 79 725 | 0
VS3 krohv | 10,32 | 1 000; Kõrgus: 2 000; 3D pikkus: 7 396 | 1 000

# IfcWall: VS-4 (4)
Type - ElementType: Element type VS-4
Classification: 1.18 IfcWall (sein) (_RKAS BIM + ARCHICAD Classification); 32 Kandvad ja välisseinad (EHITUSKULUDE LIIGITAMINE EVS 885:2005)
Arhitektuur - 04 Tulepüsivus: REI-60; 02 Materjal: Siseviimistlus vt. SK osast -250mm silikaat telliskivi -180mm keraamiline telliskivi -200mm Vahtpolüstüreen (näiteks EPS 60 Silver Fassaad) ΛDW/MK=0,023 -12mm Lamelltelliskivi fassaad toon 4569/1 ASM zementgrau (Meldofer-Caparol)+armeering+paigaldussegu; 01 Nimetus: VS4; 03 Tähistus: VS-4; 05 Asukoht: Exterior; 06 Kandevelementide eristatus: Load-Bearing Element; 08 Soojusläbivus (U-arv): 0,15W/m2K
Ehituskonstruktsioonid - 01 Nimetus: VS4; 02 Materjal: Tellis - Viimistlus; Soojustus - Plastik Kõva; Tellis - Konstuktsioon; 03 Tähistus või ristlõige: VS-4
AC_Pset_RenovationAndPhasing - Renovation Status: Existing
Pset_WallCommon - LoadBearing: yes; IsExternal: yes
Name | In | 07 Helipidavus | 06 Maht (kubatuur) | 11 Ülemine kõrgusmärk | 12 Alumine kõrgusmärk
VS4 | 2 KORRUS | - | 2,25 | 2 600; Kõrgus: 4 400; 3D pikkus: 1 883 | 2 600
VS4 | KATUSEPLAAN | 35dB | 6,86 | 6 515; Kõrgus: 2 372; 3D pikkus: 7 137 | 6 515
VS4 | KATUSEPLAAN | 35dB | 38,41 | 6 496; Kõrgus: 2 391; 3D pikkus: 25 018 | 6 496
VS4 | KATUSEPLAAN | 35dB | 6,21 | 6 250; Kõrgus: 2 637; 3D pikkus: 6 399 | 6 250

# IfcWall: VS-4 parapett (20)
In: KATUSEPLAAN
Type - ElementType: Element type VS-4 parapett
Classification: 1.18 IfcWall (sein) (_RKAS BIM + ARCHICAD Classification); 32 Kandvad ja välisseinad (EHITUSKULUDE LIIGITAMINE EVS 885:2005)
Arhitektuur - 04 Tulepüsivus: REI-60; 01 Nimetus: VS4 parapett; 03 Tähistus: VS-4 parapett; 05 Asukoht: Exterior; 06 Kandevelementide eristatus: Load-Bearing Element; 07 Helipidavus: -; 08 Soojusläbivus (U-arv): 0,15W/m2K
Ehituskonstruktsioonid - 01 Nimetus: VS4 parapett; 02 Materjal: Tellis - Viimistlus; Soojustus - Plastik Kõva; Kivi - Ol.Olev Konstruktsioon ; Soojustus - Plastik Kõva; 03 Tähistus või ristlõige: VS-4 parapett
AC_Pset_RenovationAndPhasing - Renovation Status: Existing
Pset_WallCommon - LoadBearing: yes; IsExternal: yes
Name | 02 Materjal | 06 Maht (kubatuur) | 11 Ülemine kõrgusmärk | 12 Alumine kõrgusmärk | Description
VS4 parapett | Tellis - Viimistlus; Soojustus - Plastik Kõva; Kivi - Ol.Olev Konstruktsioon ; Soojustus - Plastik Kõva | 9,25 | 6 100; Kõrgus: 500; 3D pikkus: 24 799 | 6 100
VS4 parapett | Siseviimistlus vt. SK osast -250mm silikaat telliskivi -180mm keraamiline telliskivi -200mm Vahtpolüstüreen (näiteks EPS 60 Silver Fassaad) ΛDW/MK=0,023 -12mm Lamelltelliskivi fassaad toon 4569/1 ASM zementgrau (Meldofer-Caparol)+armeering+paigaldussegu | 2,99 | 6 980; Kõrgus: 320; 3D pikkus: 12 996 | 6 980 | Soojustus
VS4 parapett | Siseviimistlus vt. SK osast -250mm silikaat telliskivi -180mm keraamiline telliskivi -200mm Vahtpolüstüreen (näiteks EPS 60 Silver Fassaad) ΛDW/MK=0,023 -12mm Lamelltelliskivi fassaad toon 4569/1 ASM zementgrau (Meldofer-Caparol)+armeering+paigaldussegu | 11,15 | 6 980; Kõrgus: 320; 3D pikkus: 47 150 | 6 980 | Soojustus
VS4 parapett | Siseviimistlus vt. SK osast -250mm silikaat telliskivi -180mm keraamiline telliskivi -200mm Vahtpolüstüreen (näiteks EPS 60 Silver Fassaad) ΛDW/MK=0,023 -12mm Lamelltelliskivi fassaad toon 4569/1 ASM zementgrau (Meldofer-Caparol)+armeering+paigaldussegu | 3,04 | 6 980; Kõrgus: 320; 3D pikkus: 13 433 | 6 980 | Soojustus
VS4 parapett | Siseviimistlus vt. SK osast -250mm silikaat telliskivi -180mm keraamiline telliskivi -200mm Vahtpolüstüreen (näiteks EPS 60 Silver Fassaad) ΛDW/MK=0,023 -12mm Lamelltelliskivi fassaad toon 4569/1 ASM zementgrau (Meldofer-Caparol)+armeering+paigaldussegu | 9,40 | 6 980; Kõrgus: 320; 3D pikkus: 39 845 | 6 980 | Soojustus
VS4 parapett | Siseviimistlus vt. SK osast -250mm silikaat telliskivi -180mm keraamiline telliskivi -200mm Vahtpolüstüreen (näiteks EPS 60 Silver Fassaad) ΛDW/MK=0,023 -12mm Lamelltelliskivi fassaad toon 4569/1 ASM zementgrau (Meldofer-Caparol)+armeering+paigaldussegu | 3,33 | 6 980; Kõrgus: 320; 3D pikkus: 15 296 | 6 980 | Soojustus
VS4 parapett | Siseviimistlus vt. SK osast -250mm silikaat telliskivi -180mm keraamiline telliskivi -200mm Vahtpolüstüreen (näiteks EPS 60 Silver Fassaad) ΛDW/MK=0,023 -12mm Lamelltelliskivi fassaad toon 4569/1 ASM zementgrau (Meldofer-Caparol)+armeering+paigaldussegu | 12,21 | 6 980; Kõrgus: 320; 3D pikkus: 51 529 | 6 980 | Soojustus
VS4 parapett | Tellis - Viimistlus; Soojustus - Plastik Kõva; Kivi - Ol.Olev Konstruktsioon ; Soojustus - Plastik Kõva | 0,62 | 6 980; Kõrgus: 320; 3D pikkus: 3 516 | 6 980 | Soojustus
VS4 parapett | Tellis - Viimistlus; Soojustus - Plastik Kõva; Kivi - Ol.Olev Konstruktsioon ; Soojustus - Plastik Kõva | 0,51 | 6 980; Kõrgus: 320; 3D pikkus: 2 651 | 6 980 | Soojustus
VS4 parapett | Siseviimistlus vt. SK osast -250mm silikaat telliskivi -180mm keraamiline telliskivi -200mm Vahtpolüstüreen (näiteks EPS 60 Silver Fassaad) ΛDW/MK=0,023 -12mm Lamelltelliskivi fassaad toon 4569/1 ASM zementgrau (Meldofer-Caparol)+armeering+paigaldussegu | 3,11 | 6 980; Kõrgus: 320; 3D pikkus: 13 386 | 6 980 | Soojustus
VS4 parapett | Siseviimistlus vt. SK osast -250mm silikaat telliskivi -180mm keraamiline telliskivi -200mm Vahtpolüstüreen (näiteks EPS 60 Silver Fassaad) ΛDW/MK=0,023 -12mm Lamelltelliskivi fassaad toon 4569/1 ASM zementgrau (Meldofer-Caparol)+armeering+paigaldussegu | 19,36 | 6 980; Kõrgus: 320; 3D pikkus: 83 471 | 6 980 | Soojustus
VS4 parapett | Siseviimistlus vt. SK osast -250mm silikaat telliskivi -180mm keraamiline telliskivi -200mm Vahtpolüstüreen (näiteks EPS 60 Silver Fassaad) ΛDW/MK=0,023 -12mm Lamelltelliskivi fassaad toon 4569/1 ASM zementgrau (Meldofer-Caparol)+armeering+paigaldussegu | 3,30 | 6 980; Kõrgus: 320; 3D pikkus: 15 180 | 6 980 | Soojustus
VS4 parapett | Siseviimistlus vt. SK osast -250mm silikaat telliskivi -180mm keraamiline telliskivi -200mm Vahtpolüstüreen (näiteks EPS 60 Silver Fassaad) ΛDW/MK=0,023 -12mm Lamelltelliskivi fassaad toon 4569/1 ASM zementgrau (Meldofer-Caparol)+armeering+paigaldussegu | 5,10 | 6 980; Kõrgus: 320; 3D pikkus: 21 952 | 6 980 | Soojustus
VS4 parapett | Siseviimistlus vt. SK osast -250mm silikaat telliskivi -180mm keraamiline telliskivi -200mm Vahtpolüstüreen (näiteks EPS 60 Silver Fassaad) ΛDW/MK=0,023 -12mm Lamelltelliskivi fassaad toon 4569/1 ASM zementgrau (Meldofer-Caparol)+armeering+paigaldussegu | 4,18 | 6 980; Kõrgus: 320; 3D pikkus: 18 779 | 6 980 | Soojustus
VS4 parapett | Siseviimistlus vt. SK osast -250mm silikaat telliskivi -180mm keraamiline telliskivi -200mm Vahtpolüstüreen (näiteks EPS 60 Silver Fassaad) ΛDW/MK=0,023 -12mm Lamelltelliskivi fassaad toon 4569/1 ASM zementgrau (Meldofer-Caparol)+armeering+paigaldussegu | 1,28 | 6 980; Kõrgus: 320; 3D pikkus: 6 075 | 6 980 | Soojustus
VS4 parapett | Tellis - Viimistlus; Soojustus - Plastik Kõva; Kivi - Ol.Olev Konstruktsioon ; Soojustus - Plastik Kõva | 0,26 | 6 980; Kõrgus: 320; 3D pikkus: 1 862 | 6 980 | Soojustus
VS4 parapett | Siseviimistlus vt. SK osast -250mm silikaat telliskivi -180mm keraamiline telliskivi -200mm Vahtpolüstüreen (näiteks EPS 60 Silver Fassaad) ΛDW/MK=0,023 -12mm Lamelltelliskivi fassaad toon 4569/1 ASM zementgrau (Meldofer-Caparol)+armeering+paigaldussegu | 0,69 | 6 980; Kõrgus: 320; 3D pikkus: 3 527 | 6 980 | Soojustus
VS4 parapett | Siseviimistlus vt. SK osast -250mm silikaat telliskivi -180mm keraamiline telliskivi -200mm Vahtpolüstüreen (näiteks EPS 60 Silver Fassaad) ΛDW/MK=0,023 -12mm Lamelltelliskivi fassaad toon 4569/1 ASM zementgrau (Meldofer-Caparol)+armeering+paigaldussegu | 1,30 | 6 980; Kõrgus: 320; 3D pikkus: 6 233 | 6 980 | Soojustus
VS4 parapett | Tellis - Viimistlus; Soojustus - Plastik Kõva; Kivi - Ol.Olev Konstruktsioon ; Soojustus - Plastik Kõva | 0,08 | 6 980; Kõrgus: 320; 3D pikkus: 902 | 6 980 | Soojustus
VS4 parapett | Siseviimistlus vt. SK osast -250mm silikaat telliskivi -180mm keraamiline telliskivi -200mm Vahtpolüstüreen (näiteks EPS 60 Silver Fassaad) ΛDW/MK=0,023 -12mm Lamelltelliskivi fassaad toon 4569/1 ASM zementgrau (Meldofer-Caparol)+armeering+paigaldussegu | 6,05 | 6 980; Kõrgus: 320; 3D pikkus: 26 575 | 6 980 | Soojustus

# IfcWall: VS4 (26)
In: 2 KORRUS
Type - ElementType: Element type VS4
Classification: 1.18 IfcWall (sein) (_RKAS BIM + ARCHICAD Classification); 32 Kandvad ja välisseinad (EHITUSKULUDE LIIGITAMINE EVS 885:2005)
Arhitektuur - 04 Tulepüsivus: REI-60; 02 Materjal: Siseviimistlus vt. SK osast -250mm silikaat telliskivi -180mm keraamiline telliskivi -200mm Vahtpolüstüreen (näiteks EPS 60 Silver Fassaad) ΛDW/MK=0,023 -12mm Lamelltelliskivi fassaad toon 4569/1 ASM zementgrau (Meldofer-Caparol)+armeering+paigaldussegu; 01 Nimetus: VS4; 03 Tähistus: VS4; 05 Asukoht: Exterior; 06 Kandevelementide eristatus: Load-Bearing Element; 07 Helipidavus: 35dB; 08 Soojusläbivus (U-arv): 0,15W/m2K
Ehituskonstruktsioonid - 01 Nimetus: VS4; 02 Materjal: Tellis - Viimistlus; Soojustus - Plastik Kõva; Tellis - Konstuktsioon; 03 Tähistus või ristlõige: VS4
AC_Pset_RenovationAndPhasing - Renovation Status: Existing
Pset_WallCommon - LoadBearing: yes; IsExternal: yes
Name | 06 Maht (kubatuur) | 11 Ülemine kõrgusmärk | 12 Alumine kõrgusmärk
VS4 | 41,56 | 2 250; Kõrgus: 4 730; 3D pikkus: 15 437 | 2 250
VS4 | 12,86 | 2 250; Kõrgus: 4 730; 3D pikkus: 4 726 | 2 250
VS4 | 60,56 | 2 250; Kõrgus: 4 730; 3D pikkus: 33 897 | 2 250
VS4 | 54,57 | 2 250; Kõrgus: 4 730; 3D pikkus: 27 790 | 2 250
VS4 | 41,16 | 2 250; Kõrgus: 4 730; 3D pikkus: 15 294 | 2 250
VS4 | 40,12 | 2 250; Kõrgus: 4 730; 3D pikkus: 20 512 | 2 250
VS4 | 71,14 | 2 580; Kõrgus: 4 400; 3D pikkus: 26 597 | 2 580
VS4 | 23,19 | 2 580; Kõrgus: 4 400; 3D pikkus: 13 999 | 2 580
VS4 | 15,47 | 2 580; Kõrgus: 4 400; 3D pikkus: 5 803 | 2 580
VS4 | 4,53 | 2 580; Kõrgus: 4 400; 3D pikkus: 3 427 | 2 580
VS4 | 30,93 | 2 580; Kõrgus: 4 420; 3D pikkus: 18 800 | 2 580
VS4 | 26,00 | 2 600; Kõrgus: 3 300; 3D pikkus: 12 448 | 2 600
VS4 | 27,54 | 2 600; Kõrgus: 4 400; 3D pikkus: 13 386 | 2 600
VS4 | 7,88 | 2 600; Kõrgus: 4 400; 3D pikkus: 3 035 | 2 600
VS4 | 20,98 | 2 600; Kõrgus: 4 380; 3D pikkus: 12 996 | 2 600
VS4 | 14,01 | 2 580; Kõrgus: 4 400; 3D pikkus: 5 429 | 2 580
VS4 | 53,13 | 2 600; Kõrgus: 3 500; 3D pikkus: 24 306 | 2 600
VS4 | 26,99 | 2 231; Kõrgus: 3 669; 3D pikkus: 11 373 | 2 231
VS4 | 15,57 | 2 580; Kõrgus: 4 400; 3D pikkus: 6 075 | 2 580
VS4 | 1,12 | 2 580; Kõrgus: 4 400; 3D pikkus: 902 | 2 580
VS4 | 100,99 | 2 600; Kõrgus: 4 400; 3D pikkus: 60 663 | 2 600
VS4 | 7,69 | 2 231; Kõrgus: 4 749; 3D pikkus: 4 026 | 2 231
VS4 | 35,76 | 2 600; Kõrgus: 4 400; 3D pikkus: 21 988 | 2 600
VS4 | 20,75 | 2 231; Kõrgus: 4 749; 3D pikkus: 6 941 | 2 231
VS4 | 6,27 | 2 600; Kõrgus: 3 915; 3D pikkus: 2 623 | 2 600
VS4 | 87,51 | 2 250; Kõrgus: 4 730; 3D pikkus: 47 150 | 2 250

# IfcWall: ss-2 (2)
In: KATUSEPLAAN
Type - ElementType: Element type ss-2
Classification: 2.15 IfcWall (sein) (_RKAS BIM + ARCHICAD Classification); 51 Vaheseinad (EHITUSKULUDE LIIGITAMINE EVS 885:2005); Material: Kivi -Ol.Olev Konstruktsioon
Arhitektuur - 02 Materjal: 2xkipsplaat (Gyproc GKF15) -66mm Karkasspostid XR66 (s-600mm)+mineraalvill 70mm -plekiribad; 01 Nimetus: sahti sein; 03 Tähistus: ss-1; 05 Asukoht: Interior; 06 Kandevelementide eristatus: Non-Load-Bearing Element
Ehituskonstruktsioonid - 01 Nimetus: sahti sein; 02 Materjal: 2xkipsplaat (Gyproc GKF15) -66mm Karkasspostid XR66 (s-600mm)+mineraalvill 70mm -plekiribad; 03 Tähistus või ristlõige: ss-1; 04 Materjali peamine tugevusnäitaja: Undefined; 05 Keskkonnaklass: Undefined; 07 Monteeritava elemendi mass: Undefined; 09 Monteeritava elemendi positisioon/mark: Undefined; 10 Elemendi valmistamise tehnoloogia: Undefined; 12 Alumine kõrgusmärk: 5 567
AC_Pset_RenovationAndPhasing - Renovation Status: New
Pset_WallCommon - LoadBearing: no; IsExternal: no
Name | 06 Maht (kubatuur) | 08 Monteeritava elemendi pikkus | 11 Ülemine kõrgusmärk
sahti sein | 2,14 | 5 927; Undefined | 5 567; Kõrgus: 2 409; 3D pikkus: 5 927
sahti sein | 0,62 | 1 868; Undefined | 5 567; Kõrgus: 3 295; 3D pikkus: 1 868

# IfcWallStandardCase: FIBO (5)
In: 1 KORRUS
Type - ElementType: Element type FIBO
Description: kivi.väikeplokk
Arhitektuur - 02 Materjal: Kivi - Uus Konstruktsioon; 03 Tähistus: FIBO; 05 Asukoht: Interior
Ehituskonstruktsioonid - 02 Materjal: Kivi - Uus Konstruktsioon; 03 Tähistus või ristlõige: FIBO; 12 Alumine kõrgusmärk: 0
AC_Pset_RenovationAndPhasing - Renovation Status: New
Pset_WallCommon - IsExternal: no
Name | Classification | Material | Arhitektuur, 01 Nimetus = Ehituskonstruktsioonid, 01 Nimetus | 06 Kandevelementide eristatus | 06 Maht (kubatuur) | 11 Ülemine kõrgusmärk | LoadBearing | 04 Materjali peamine tugevusnäitaja = 05 Keskkonnaklass = 07 Monteeritava elemendi mass = 09 Monteeritava elemendi positisioon/mark = 10 Elemendi valmistamise tehnoloogia | 08 Monteeritava elemendi pikkus
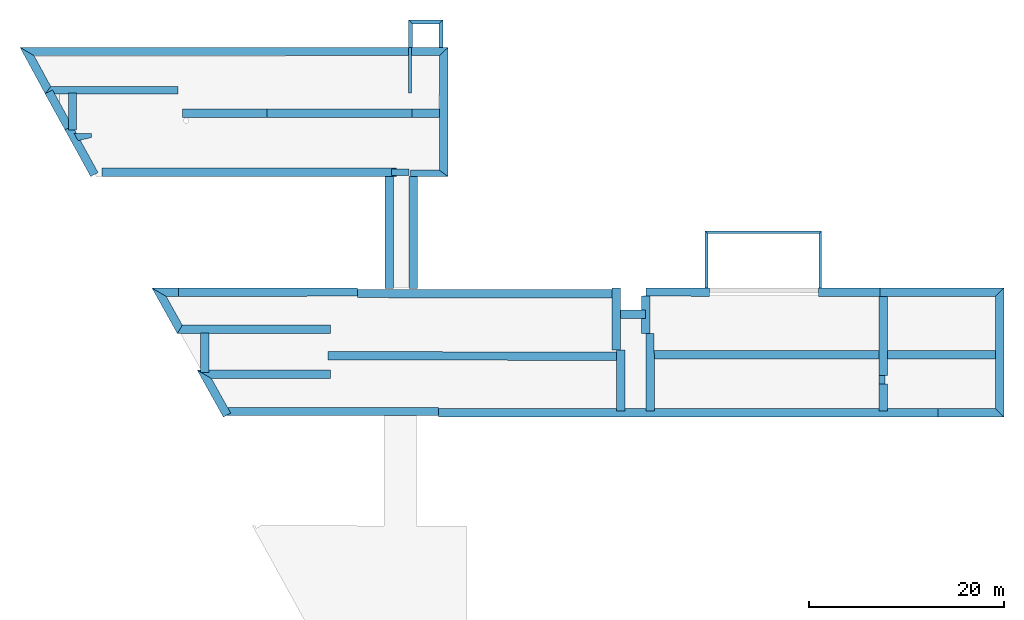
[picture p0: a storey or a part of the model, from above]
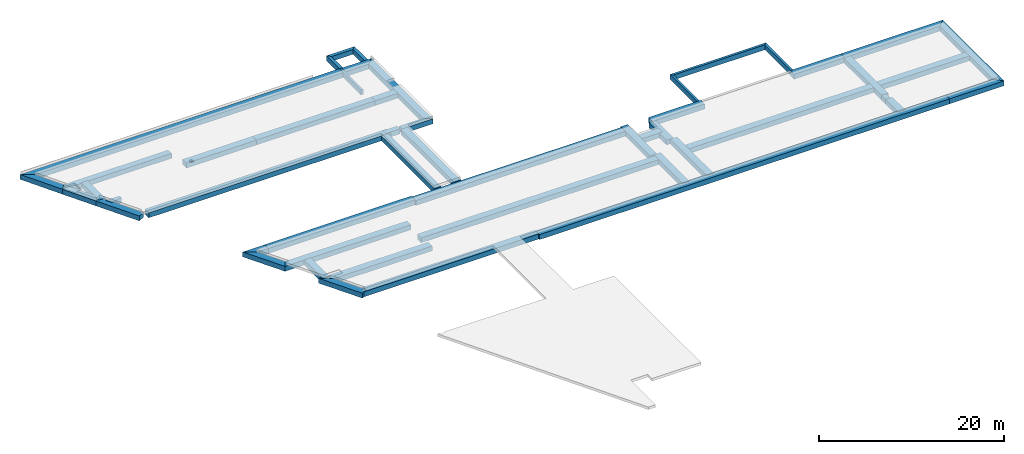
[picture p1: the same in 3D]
Properties of the parts of a building model (IFC2X3), part 12 of 14

# IfcWallStandardCase: FIBO (5)
Name | Classification | Material | Arhitektuur, 01 Nimetus = Ehituskonstruktsioonid, 01 Nimetus | 06 Kandevelementide eristatus | 06 Maht (kubatuur) | 11 Ülemine kõrgusmärk | LoadBearing | 04 Materjali peamine tugevusnäitaja = 05 Keskkonnaklass = 07 Monteeritava elemendi mass = 09 Monteeritava elemendi positisioon/mark = 10 Elemendi valmistamise tehnoloogia | 08 Monteeritava elemendi pikkus
uus kinni ehitav sein 630 | 1.18 IfcWall (sein) (_RKAS BIM + ARCHICAD Classification); 325 Seinte elemendid (EHITUSKULUDE LIIGITAMINE EVS 885:2005) | Kivi - Uus Konstruktsioon 630 mm | uus kinni ehitav sein 630 | Non-Load-Bearing Element | 1,25 | 0; Kõrgus: 2 200; 3D pikkus: 900 | no | Arhitektuur - 04 Tulepüsivus: REI-60; 07 Helipidavus: 35dB; 08 Soojusläbivus (U-arv): 0,15 w/m2K
uus kinni ehitav sein 420 | 1.18 IfcWall (sein) (_RKAS BIM + ARCHICAD Classification); 32 Kandvad ja välisseinad (EHITUSKULUDE LIIGITAMINE EVS 885:2005) | Kivi - Uus Konstruktsioon 420 mm | uus kinni ehitav sein 420 | Load-Bearing Element | 0,83 | 0; Kõrgus: 2 200; 3D pikkus: 900 | yes | Arhitektuur - 04 Tulepüsivus: -; 07 Helipidavus: -; 08 Soojusläbivus (U-arv): -
uus kinni ehitav sein 420 | 32 Kandvad ja välisseinad (EHITUSKULUDE LIIGITAMINE EVS 885:2005); 2.15 IfcWall (sein) (_RKAS BIM + ARCHICAD Classification) | Kivi - Uus Konstruktsioon 420 mm | uus kinni ehitav sein 420 | Load-Bearing Element | 0,83 | 0; Kõrgus: 2 200; 3D pikkus: 900 | yes | Undefined | 900; Undefined
uus kinni ehitav sein 420 | 32 Kandvad ja välisseinad (EHITUSKULUDE LIIGITAMINE EVS 885:2005); 2.15 IfcWall (sein) (_RKAS BIM + ARCHICAD Classification) | Kivi - Uus Konstruktsioon 420 mm | uus kinni ehitav sein 420 | Load-Bearing Element | 0,92 | 0; Kõrgus: 2 200; 3D pikkus: 1 000 | yes | Undefined | 1 000; Undefined
uus kinni ehitav sein 420 | 32 Kandvad ja välisseinad (EHITUSKULUDE LIIGITAMINE EVS 885:2005); 2.15 IfcWall (sein) (_RKAS BIM + ARCHICAD Classification) | Kivi - Uus Konstruktsioon 420 mm | uus kinni ehitav sein 420 | Load-Bearing Element | 0,88 | 0; Kõrgus: 2 200; 3D pikkus: 950 | yes | Undefined | 950; Undefined

# IfcWallStandardCase: Kinniehitavad restid (2)
In: 2 KORRUS
Type - ElementType: Element type Kinniehitavad restid
Classification: 2.15 IfcWall (sein) (_RKAS BIM + ARCHICAD Classification); 51 Vaheseinad (EHITUSKULUDE LIIGITAMINE EVS 885:2005); Material: Kivi - Uus Konstruktsioon 430 mm
Arhitektuur - 01 Nimetus: uus kinni ehitav sein 430; 02 Materjal: Kivi - Uus Konstruktsioon; 03 Tähistus: Kinniehitavad restid; 05 Asukoht: Exterior; 06 Kandevelementide eristatus: Non-Load-Bearing Element
Ehituskonstruktsioonid - 01 Nimetus: uus kinni ehitav sein 430; 02 Materjal: Kivi - Uus Konstruktsioon; 03 Tähistus või ristlõige: Kinniehitavad restid; 04 Materjali peamine tugevusnäitaja: Undefined; 05 Keskkonnaklass: Undefined; 06 Maht (kubatuur): 0,21; 07 Monteeritava elemendi mass: Undefined; 08 Monteeritava elemendi pikkus: 700; Undefined; 09 Monteeritava elemendi positisioon/mark: Undefined; 10 Elemendi valmistamise tehnoloogia: Undefined; 11 Ülemine kõrgusmärk: 5 100; Kõrgus: 700; 3D pikkus: 700; 12 Alumine kõrgusmärk: 5 100
AC_Pset_RenovationAndPhasing - Renovation Status: New
Pset_WallCommon - LoadBearing: no; IsExternal: yes

# IfcWallStandardCase: P-1 (42)
Type - ElementType: Element type P-1
Classification: 1.18 IfcWall (sein) (_RKAS BIM + ARCHICAD Classification); 33 Vahe- ja katuslaed (EHITUSKULUDE LIIGITAMINE EVS 885:2005); Material: Kivi - Ol.Olev Konstruktsioon 860 mm
Arhitektuur - 01 Nimetus: VUND; 02 Materjal: Kivi - Ol.Olev Konstruktsioon; 03 Tähistus: P-1; 04 Tulepüsivus: nõudeid ei esitata; 05 Asukoht: Exterior; 06 Kandevelementide eristatus: Load-Bearing Element; 07 Helipidavus: -; 08 Soojusläbivus (U-arv): 1 W/m2K
Ehituskonstruktsioonid - 01 Nimetus: VUND; 02 Materjal: Kivi - Ol.Olev Konstruktsioon; 03 Tähistus või ristlõige: P-1
AC_Pset_RenovationAndPhasing - Renovation Status: Existing
Pset_WallCommon - LoadBearing: yes; IsExternal: yes
Name | In | 06 Maht (kubatuur) | 11 Ülemine kõrgusmärk | 12 Alumine kõrgusmärk
VUND | VUNDAMENT | 2,48 | -1 000; Kõrgus: 650; 3D pikkus: 4 911 | -1 000
VUND | VUNDAMENT | 4,43 | -1 000; Kõrgus: 650; 3D pikkus: 7 923 | -1 000
VUND | VUNDAMENT | 1,06 | -1 000; Kõrgus: 650; 3D pikkus: 2 336 | -1 000
VUND | VUNDAMENT | 7,38 | -1 000; Kõrgus: 650; 3D pikkus: 13 207 | -1 000
VUND | VUNDAMENT | 22,36 | -1 000; Kõrgus: 650; 3D pikkus: 40 240 | -1 000
VUND | VUNDAMENT | 15,08 | -1 000; Kõrgus: 650; 3D pikkus: 26 976 | -1 000
2 x VUND | VUNDAMENT | 6,42 | -1 000; Kõrgus: 650; 3D pikkus: 11 483 | -1 000
VUND | VUNDAMENT | 1,88 | -1 000; Kõrgus: 650; 3D pikkus: 3 845 | -1 000
VUND | VUNDAMENT | 1,28 | -1 000; Kõrgus: 650; 3D pikkus: 5 474 | -1 000
VUND | VUNDAMENT | 6,97 | -1 000; Kõrgus: 650; 3D pikkus: 12 700 | -1 000
VUND | VUNDAMENT | 2,95 | -1 000; Kõrgus: 650; 3D pikkus: 5 515 | -1 000
VUND | VUNDAMENT | 28,61 | -1 000; Kõrgus: 650; 3D pikkus: 51 187 | -1 000
VUND | VUNDAMENT | 12,33 | -1 000; Kõrgus: 650; 3D pikkus: 22 055 | -1 000
VUND | VUNDAMENT | 6,69 | -1 000; Kõrgus: 650; 3D pikkus: 11 966 | -1 000
VUND | VUNDAMENT | 10,24 | -1 000; Kõrgus: 650; 3D pikkus: 18 327 | -1 000
VUND | VUNDAMENT | 3,55 | -1 000; Kõrgus: 650; 3D pikkus: 6 343 | -1 000
VUND | VUNDAMENT | 2,23 | -1 000; Kõrgus: 650; 3D pikkus: 3 997 | -1 000
VUND | VUNDAMENT | 3,30 | -1 000; Kõrgus: 650; 3D pikkus: 5 912 | -1 000
VUND | VUNDAMENT | 2,14 | -1 000; Kõrgus: 650; 3D pikkus: 3 824 | -1 000
VUND | VUNDAMENT | 1,44 | -1 000; Kõrgus: 650; 3D pikkus: 2 571 | -1 000
VUND | VUNDAMENT | 4,54 | -1 000; Kõrgus: 650; 3D pikkus: 8 118 | -1 000
VUND | VUNDAMENT | 1,54 | -1 000; Kõrgus: 650; 3D pikkus: 2 753 | -1 000
VUND | VUNDAMENT | 19,42 | -1 000; Kõrgus: 650; 3D pikkus: 34 750 | -1 000
VUND | VUNDAMENT | 3,08 | -1 000; Kõrgus: 650; 3D pikkus: 5 511 | -1 000
VUND | VUNDAMENT | 16,87 | -1 000; Kõrgus: 650; 3D pikkus: 30 185 | -1 000
VUND | VUNDAMENT | 1,59 | -1 000; Kõrgus: 650; 3D pikkus: 2 841 | -1 000
VUND | VUNDAMENT | 3,49 | -1 000; Kõrgus: 650; 3D pikkus: 6 238 | -1 000
VUND | VUNDAMENT | 8,28 | -1 000; Kõrgus: 650; 3D pikkus: 14 814 | -1 000
VUND | VUNDAMENT | 4,87 | -1 000; Kõrgus: 650; 3D pikkus: 8 703 | -1 000
VUND | VUNDAMENT | 16,53 | -1 000; Kõrgus: 650; 3D pikkus: 29 577 | -1 000
VUND | VUNDAMENT | 7,40 | -1 000; Kõrgus: 650; 3D pikkus: 13 240 | -1 000
VUND | VUNDAMENT | 8,92 | -1 000; Kõrgus: 650; 3D pikkus: 16 196 | -1 000
VUND | VUNDAMENT | 3,66 | -1 000; Kõrgus: 650; 3D pikkus: 6 544 | -1 000
VUND | VUNDAMENT | 2,35 | -1 000; Kõrgus: 650; 3D pikkus: 4 208 | -1 000
VUND | 1 KORRUS | 1,28 | 0; Kõrgus: 3 000; 3D pikkus: 955 | 0
VUND | 1 KORRUS | 0,27 | -1 000; Kõrgus: 650; 3D pikkus: 13 318 | -1 000
VUND | 1 KORRUS | 15,27 | 0; Kõrgus: 2 600; 3D pikkus: 7 597 | 0
VUND | 1 KORRUS | 8,88 | 0; Kõrgus: 2 600; 3D pikkus: 4 739 | 0
VUND | 1 KORRUS | 37,33 | 0; Kõrgus: 2 600; 3D pikkus: 16 695 | 0
VUND | 1 KORRUS | 8,44 | 1 000; Kõrgus: 1 600; 3D pikkus: 6 131 | 1 000
VUND | 1 KORRUS | 15,73 | 1 000; Kõrgus: 1 600; 3D pikkus: 11 431 | 1 000

# IfcWallStandardCase: P-4 (3)
Type - ElementType: Element type P-4
Classification: 2.15 IfcWall (sein) (_RKAS BIM + ARCHICAD Classification); 51 Vaheseinad (EHITUSKULUDE LIIGITAMINE EVS 885:2005); Material: Kivi - Uus Konstruktsioon 150 mm
Arhitektuur - 01 Nimetus: uus kinni ehitav sein 150; 02 Materjal: Kivi - Uus Konstruktsioon; 03 Tähistus: P-4; 05 Asukoht: Interior
Ehituskonstruktsioonid - 01 Nimetus: uus kinni ehitav sein 150; 02 Materjal: Kivi - Uus Konstruktsioon; 03 Tähistus või ristlõige: P-4; 04 Materjali peamine tugevusnäitaja: -; 05 Keskkonnaklass: -; 07 Monteeritava elemendi mass: Undefined; 09 Monteeritava elemendi positisioon/mark: Undefined; 10 Elemendi valmistamise tehnoloogia: Undefined
AC_Pset_RenovationAndPhasing - Renovation Status: New
Pset_WallCommon - IsExternal: no
Name | In | 06 Kandevelementide eristatus | 06 Maht (kubatuur) | 08 Monteeritava elemendi pikkus | 11 Ülemine kõrgusmärk | 12 Alumine kõrgusmärk
sahti sein | 1 KORRUS | Undefined | 0,05 | 1 000; Undefined | 2 558; Kõrgus: 375; 3D pikkus: 1 000 | 2 558
sahti sein | 1 KORRUS | Undefined | 0,05 | 1 150; Undefined | 2 545; Kõrgus: 375; 3D pikkus: 1 150 | 2 545
sahti sein | 2 KORRUS | - | 0,67 | 11 870; Undefined | 2 545; Kõrgus: 375; 3D pikkus: 11 870 | 2 545

# IfcWallStandardCase: SS (2)
In: 1 KORRUS
Type - ElementType: Element type SS
Arhitektuur - 03 Tähistus: SS; 05 Asukoht: Interior
Ehituskonstruktsioonid - 03 Tähistus või ristlõige: SS; 12 Alumine kõrgusmärk: 0
Pset_WallCommon - IsExternal: no
Name | Classification | Material | Arhitektuur, 01 Nimetus = Ehituskonstruktsioonid, 01 Nimetus | Arhitektuur, 02 Materjal = Ehituskonstruktsioonid, 02 Materjal | 06 Kandevelementide eristatus | 06 Maht (kubatuur) | 11 Ülemine kõrgusmärk | Renovation Status | LoadBearing
uus kinni ehitav sein 150 | 2.15 IfcWall (sein) (_RKAS BIM + ARCHICAD Classification); 51 Vaheseinad (EHITUSKULUDE LIIGITAMINE EVS 885:2005) | Kivi - Uus Konstruktsioon 150 mm | uus kinni ehitav sein 150 | Kivi - Uus Konstruktsioon | Non-Load-Bearing Element | 0,30 | 0; Kõrgus: 2 200; 3D pikkus: 900 | New | no | Description: kivi.väikeplokk; Ehituskonstruktsioonid - 04 Materjali peamine tugevusnäitaja: Undefined; 05 Keskkonnaklass: Undefined; 07 Monteeritava elemendi mass: Undefined; 08 Monteeritava elemendi pikkus: 900; Undefined; 09 Monteeritava elemendi positisioon/mark: Undefined; 10 Elemendi valmistamise tehnoloogia: Undefined
ol.olev ss 630 | 1.18 IfcWall (sein) (_RKAS BIM + ARCHICAD Classification); 32 Kandvad ja välisseinad (EHITUSKULUDE LIIGITAMINE EVS 885:2005) | Kivi -Ol.Olev Konstruktsioon 630 mm | ol.olev ss 630 | Kivi -Ol.Olev Konstruktsioon | Load-Bearing Element | 1,55 | 0; Kõrgus: 3 000; 3D pikkus: 1 519 | Existing | yes | Arhitektuur - 04 Tulepüsivus: -; 07 Helipidavus: -; 08 Soojusläbivus (U-arv): -

# IfcWallStandardCase: SS-1 (26)
Type - ElementType: Element type SS-1
Classification: 2.15 IfcWall (sein) (_RKAS BIM + ARCHICAD Classification); 51 Vaheseinad (EHITUSKULUDE LIIGITAMINE EVS 885:2005); Material: Kivi - Uus Konstruktsioon 150 mm
Arhitektuur - 03 Tähistus: SS-1; 05 Asukoht: Interior; 06 Kandevelementide eristatus: Non-Load-Bearing Element
Ehituskonstruktsioonid - 03 Tähistus või ristlõige: SS-1; 07 Monteeritava elemendi mass: Undefined; 09 Monteeritava elemendi positisioon/mark: Undefined; 10 Elemendi valmistamise tehnoloogia: Undefined
AC_Pset_RenovationAndPhasing - Renovation Status: New
Pset_WallCommon - LoadBearing: no; IsExternal: no
Name | In | Arhitektuur, 02 Materjal = Ehituskonstruktsioonid, 02 Materjal | Arhitektuur, 01 Nimetus = Ehituskonstruktsioonid, 01 Nimetus | 04 Materjali peamine tugevusnäitaja = 05 Keskkonnaklass | 06 Maht (kubatuur) | 08 Monteeritava elemendi pikkus | 11 Ülemine kõrgusmärk | 12 Alumine kõrgusmärk
sahti sein | 1 KORRUS | 2xkipsplaat (Gyproc GKF15) -66mm Karkasspostid XR66 (s-600mm)+mineraalvill 70mm -plekiribad | sahti sein | Undefined | 0,12 | 315; Undefined | 0; Kõrgus: 2 600; 3D pikkus: 315 | 0
sahti sein | 1 KORRUS | 2xkipsplaat (Gyproc GKF15) -66mm Karkasspostid XR66 (s-600mm)+mineraalvill 70mm -plekiribad | sahti sein | Undefined | 0,44 | 1 117; Undefined | 0; Kõrgus: 2 600; 3D pikkus: 1 117 | 0
sahti sein | 1 KORRUS | 2xkipsplaat (Gyproc GKF15) -66mm Karkasspostid XR66 (s-600mm)+mineraalvill 70mm -plekiribad | sahti sein | Undefined | 0,67 | 2 200; Undefined | 0; Kõrgus: 2 600; 3D pikkus: 2 200 | 0
sahti sein | 1 KORRUS | 2xkipsplaat (Gyproc GKF15) -66mm Karkasspostid XR66 (s-600mm)+mineraalvill 70mm -plekiribad | sahti sein | Undefined | 0,28 | 764; Undefined | 0; Kõrgus: 2 600; 3D pikkus: 764 | 0
sahti sein | 1 KORRUS | 2xkipsplaat (Gyproc GKF15) -66mm Karkasspostid XR66 (s-600mm)+mineraalvill 70mm -plekiribad | sahti sein | Undefined | 0,14 | 364; Undefined | 0; Kõrgus: 2 600; 3D pikkus: 364 | 0
sahti sein | 1 KORRUS | 2xkipsplaat (Gyproc GKF15) -66mm Karkasspostid XR66 (s-600mm)+mineraalvill 70mm -plekiribad | sahti sein | Undefined | 0,20 | 505; Undefined | 0; Kõrgus: 2 600; 3D pikkus: 505 | 0
uus ss 150 | 1 KORRUS | Kivi - Uus Konstruktsioon | uus ss 150 | - | 0,23 | 590; Undefined | 0; Kõrgus: 2 600; 3D pikkus: 590 | 0 | Description: kivi.väikeplokk
uus ss 150 | 1 KORRUS | Kivi - Uus Konstruktsioon | uus ss 150 | - | 0,12 | 300; Undefined | 0; Kõrgus: 2 600; 3D pikkus: 300 | 0 | Description: kivi.väikeplokk
sahti sein | 2 KORRUS | 2xkipsplaat (Gyproc GKF15) -66mm Karkasspostid XR66 (s-600mm)+mineraalvill 70mm -plekiribad | sahti sein | Undefined | 1,04 | 2 101; Undefined | 3 000; Kõrgus: 3 295; 3D pikkus: 2 101 | 3 000
sahti sein | 2 KORRUS | 2xkipsplaat (Gyproc GKF15) -66mm Karkasspostid XR66 (s-600mm)+mineraalvill 70mm -plekiribad | sahti sein | Undefined | 0,54 | 1 231; Undefined | 3 000; Kõrgus: 3 295; 3D pikkus: 1 231 | 3 000
sahti sein | 2 KORRUS | Kivi - Uus Konstruktsioon | uus ss 150 | Undefined | 1,16 | 2 378; Undefined | 3 000; Kõrgus: 3 250; 3D pikkus: 2 378 | 3 000
sahti sein | 2 KORRUS | Kivi - Uus Konstruktsioon | uus ss 150 | Undefined | 0,39 | 802; Undefined | 3 000; Kõrgus: 3 250; 3D pikkus: 802 | 3 000
sahti sein | 2 KORRUS | 2xkipsplaat (Gyproc GKF15) -66mm Karkasspostid XR66 (s-600mm)+mineraalvill 70mm -plekiribad | sahti sein | - | 0,24 | 477; Undefined | 3 000; Kõrgus: 3 295; 3D pikkus: 477 | 3 000
sahti sein | 2 KORRUS | 2xkipsplaat (Gyproc GKF15) -66mm Karkasspostid XR66 (s-600mm)+mineraalvill 70mm -plekiribad | sahti sein | - | 0,10 | 613; Undefined | 3 000; Kõrgus: 3 295; 3D pikkus: 613 | 3 000
sahti sein | 2 KORRUS | 2xkipsplaat (Gyproc GKF15) -66mm Karkasspostid XR66 (s-600mm)+mineraalvill 70mm -plekiribad | sahti sein | Undefined | 0,24 | 898; Undefined | 3 000; Kõrgus: 3 295; 3D pikkus: 898 | 3 000
2 x sahti sein | 2 KORRUS | 2xkipsplaat (Gyproc GKF15) -66mm Karkasspostid XR66 (s-600mm)+mineraalvill 70mm -plekiribad | sahti sein | Undefined | 0,19 | 537; Undefined | 3 000; Kõrgus: 3 295; 3D pikkus: 537 | 3 000
sahti sein | 2 KORRUS | 2xkipsplaat (Gyproc GKF15) -66mm Karkasspostid XR66 (s-600mm)+mineraalvill 70mm -plekiribad | sahti sein | Undefined | 0,26 | 933; Undefined | 3 000; Kõrgus: 3 295; 3D pikkus: 933 | 3 000
sahti sein | 2 KORRUS | 2xkipsplaat (Gyproc GKF15) -66mm Karkasspostid XR66 (s-600mm)+mineraalvill 70mm -plekiribad | sahti sein | Undefined | 0,10 | 615; Undefined | 3 000; Kõrgus: 3 295; 3D pikkus: 615 | 3 000
sahti sein | 2 KORRUS | 2xkipsplaat (Gyproc GKF15) -66mm Karkasspostid XR66 (s-600mm)+mineraalvill 70mm -plekiribad | sahti sein | Undefined | 0,18 | 787; Undefined | 3 000; Kõrgus: 3 295; 3D pikkus: 787 | 3 000
sahti sein | 2 KORRUS | 2xkipsplaat (Gyproc GKF15) -66mm Karkasspostid XR66 (s-600mm)+mineraalvill 70mm -plekiribad | sahti sein | Undefined | 0,25 | 924; Undefined | 3 000; Kõrgus: 3 295; 3D pikkus: 924 | 3 000
sahti sein | 2 KORRUS | 2xkipsplaat (Gyproc GKF15) -66mm Karkasspostid XR66 (s-600mm)+mineraalvill 70mm -plekiribad | sahti sein | Undefined | 0,15 | 723; Undefined | 3 000; Kõrgus: 3 295; 3D pikkus: 723 | 3 000
sahti sein | 2 KORRUS | 2xkipsplaat (Gyproc GKF15) -66mm Karkasspostid XR66 (s-600mm)+mineraalvill 70mm -plekiribad | sahti sein | Undefined | 0,36 | 880; Undefined | 3 000; Kõrgus: 3 295; 3D pikkus: 880 | 3 000
sahti sein | 2 KORRUS | 2xkipsplaat (Gyproc GKF15) -66mm Karkasspostid XR66 (s-600mm)+mineraalvill 70mm -plekiribad | sahti sein | Undefined | 0,66 | 1 327; Undefined | 3 000; Kõrgus: 3 295; 3D pikkus: 1 327 | 3 000
sahti sein | 2 KORRUS | 2xkipsplaat (Gyproc GKF15) -66mm Karkasspostid XR66 (s-600mm)+mineraalvill 70mm -plekiribad | sahti sein | Undefined | 0,29 | 730; Undefined | 3 000; Kõrgus: 3 295; 3D pikkus: 730 | 3 000
sahti sein | 2 KORRUS | 2xkipsplaat (Gyproc GKF15) -66mm Karkasspostid XR66 (s-600mm)+mineraalvill 70mm -plekiribad | sahti sein | Undefined | 1,07 | 3 000; Undefined | 3 000; Kõrgus: 3 295; 3D pikkus: 3 000 | 3 000

# IfcWallStandardCase: SS-1* (14)
Type - ElementType: Element type SS-1*
Classification: 2.15 IfcWall (sein) (_RKAS BIM + ARCHICAD Classification); 51 Vaheseinad (EHITUSKULUDE LIIGITAMINE EVS 885:2005); Material: Kivi - Uus Konstruktsioon 150 mm
Arhitektuur - 03 Tähistus: SS-1*; 05 Asukoht: Interior; 06 Kandevelementide eristatus: Non-Load-Bearing Element
Ehituskonstruktsioonid - 03 Tähistus või ristlõige: SS-1*; 07 Monteeritava elemendi mass: Undefined; 09 Monteeritava elemendi positisioon/mark: Undefined; 10 Elemendi valmistamise tehnoloogia: Undefined
AC_Pset_RenovationAndPhasing - Renovation Status: New
Pset_WallCommon - LoadBearing: no; IsExternal: no
Name | In | Arhitektuur, 01 Nimetus = Ehituskonstruktsioonid, 01 Nimetus | Arhitektuur, 02 Materjal = Ehituskonstruktsioonid, 02 Materjal | 04 Materjali peamine tugevusnäitaja = 05 Keskkonnaklass | 06 Maht (kubatuur) | 08 Monteeritava elemendi pikkus | 11 Ülemine kõrgusmärk | 12 Alumine kõrgusmärk
2 x uus ss 150 | 1 KORRUS | uus ss 150 | Kivi - Uus Konstruktsioon | - | 0,30 | 920; Undefined | 0; Kõrgus: 2 170; 3D pikkus: 920 | 0 | Description: kivi.väikeplokk
sahti sein | 1 KORRUS | sahti sein | 2xkipsplaat (Gyproc GKF15) -66mm Karkasspostid XR66 (s-600mm)+mineraalvill 70mm -plekiribad | Undefined | 0,09 | 303; Undefined | 0; Kõrgus: 2 080; 3D pikkus: 303 | 0
sahti sein | 1 KORRUS | sahti sein | 2xkipsplaat (Gyproc GKF15) -66mm Karkasspostid XR66 (s-600mm)+mineraalvill 70mm -plekiribad | Undefined | 0,21 | 679; Undefined | 0; Kõrgus: 2 080; 3D pikkus: 679 | 0
sahti sein | 2 KORRUS | sahti sein | 2xkipsplaat (Gyproc GKF15) -66mm Karkasspostid XR66 (s-600mm)+mineraalvill 70mm -plekiribad | Undefined | 0,59 | 1 455; Undefined | 3 000; Kõrgus: 2 700; 3D pikkus: 1 455 | 3 000
sahti sein | 2 KORRUS | sahti sein | 2xkipsplaat (Gyproc GKF15) -66mm Karkasspostid XR66 (s-600mm)+mineraalvill 70mm -plekiribad | Undefined | 0,19 | 422; Undefined | 3 000; Kõrgus: 2 950; 3D pikkus: 422 | 3 000
sahti sein | 2 KORRUS | sahti sein | 2xkipsplaat (Gyproc GKF15) -66mm Karkasspostid XR66 (s-600mm)+mineraalvill 70mm -plekiribad | Undefined | 0,29 | 699; Undefined | 3 000; Kõrgus: 2 950; 3D pikkus: 699 | 3 000
sahti sein | 2 KORRUS | sahti sein | 2xkipsplaat (Gyproc GKF15) -66mm Karkasspostid XR66 (s-600mm)+mineraalvill 70mm -plekiribad | Undefined | 0,21 | 617; Undefined | 3 000; Kõrgus: 2 970; 3D pikkus: 617 | 3 000
sahti sein | 2 KORRUS | sahti sein | 2xkipsplaat (Gyproc GKF15) -66mm Karkasspostid XR66 (s-600mm)+mineraalvill 70mm -plekiribad | Undefined | 0,19 | 440; Undefined | 3 000; Kõrgus: 2 806; 3D pikkus: 440 | 3 000
sahti sein | 2 KORRUS | sahti sein | 2xkipsplaat (Gyproc GKF15) -66mm Karkasspostid XR66 (s-600mm)+mineraalvill 70mm -plekiribad | Undefined | 0,15 | 358; Undefined | 3 000; Kõrgus: 2 806; 3D pikkus: 358 | 3 000
sahti sein | 2 KORRUS | sahti sein | 2xkipsplaat (Gyproc GKF15) -66mm Karkasspostid XR66 (s-600mm)+mineraalvill 70mm -plekiribad | Undefined | 0,13 | 349; Undefined | 3 000; Kõrgus: 2 500; 3D pikkus: 349 | 3 000
sahti sein | 2 KORRUS | sahti sein | 2xkipsplaat (Gyproc GKF15) -66mm Karkasspostid XR66 (s-600mm)+mineraalvill 70mm -plekiribad | Undefined | 0,19 | 500; Undefined | 3 000; Kõrgus: 2 500; 3D pikkus: 500 | 3 000
sahti sein | 2 KORRUS | sahti sein | 2xkipsplaat (Gyproc GKF15) -66mm Karkasspostid XR66 (s-600mm)+mineraalvill 70mm -plekiribad | Undefined | 0,31 | 714; Undefined | 3 000; Kõrgus: 2 918; 3D pikkus: 714 | 3 000
sahti sein | 2 KORRUS | sahti sein | 2xkipsplaat (Gyproc GKF15) -66mm Karkasspostid XR66 (s-600mm)+mineraalvill 70mm -plekiribad | - | 0,17 | 395; Undefined | 3 000; Kõrgus: 2 970; 3D pikkus: 395 | 3 000

# IfcWallStandardCase: SS-2 (6)
Type - ElementType: Element type SS-2
Classification: 2.15 IfcWall (sein) (_RKAS BIM + ARCHICAD Classification); 51 Vaheseinad (EHITUSKULUDE LIIGITAMINE EVS 885:2005); Material: Kivi - Uus Konstruktsioon 150 mm
Arhitektuur - 01 Nimetus: uus ss 150; 02 Materjal: Kivi - Uus Konstruktsioon; 03 Tähistus: SS-2; 05 Asukoht: Interior; 06 Kandevelementide eristatus: Non-Load-Bearing Element
Ehituskonstruktsioonid - 01 Nimetus: uus ss 150; 02 Materjal: Kivi - Uus Konstruktsioon; 03 Tähistus või ristlõige: SS-2; 07 Monteeritava elemendi mass: Undefined; 09 Monteeritava elemendi positisioon/mark: Undefined; 10 Elemendi valmistamise tehnoloogia: Undefined
AC_Pset_RenovationAndPhasing - Renovation Status: New
Pset_WallCommon - LoadBearing: no; IsExternal: no
Name | In | Description | 04 Materjali peamine tugevusnäitaja = 05 Keskkonnaklass | 06 Maht (kubatuur) | 08 Monteeritava elemendi pikkus | 11 Ülemine kõrgusmärk | 12 Alumine kõrgusmärk
uus ss 150 | 1 KORRUS | Kipskarkassein | - | 0,16 | 1 703; Undefined | 0; Kõrgus: 2 600; 3D pikkus: 1 703 | 0
uus ss 150 | 2 KORRUS | sisesein | - | 0,39 | 3 872; Undefined | 3 000; Kõrgus: 700; 3D pikkus: 3 872 | 3 000
uus ss 150 | 2 KORRUS | sisesein | Undefined | 2,34 | 5 473; Undefined | 3 000; Kõrgus: 3 250; 3D pikkus: 5 473 | 3 000
uus ss 150 | 2 KORRUS | sisesein | Undefined | 0,93 | 2 577; Undefined | 3 000; Kõrgus: 3 250; 3D pikkus: 2 577 | 3 000
uus ss 150 | 2 KORRUS | sisesein | Undefined | 0,99 | 2 040; Undefined | 3 000; Kõrgus: 3 250; 3D pikkus: 2 040 | 3 000
uus ss 150 | 2 KORRUS | sisesein | Undefined | 1,37 | 3 506; Undefined | 3 000; Kõrgus: 3 250; 3D pikkus: 3 506 | 3 000

# IfcWallStandardCase: SS-3 (2)
Type - ElementType: Element type SS-3
Classification: 2.15 IfcWall (sein) (_RKAS BIM + ARCHICAD Classification); 51 Vaheseinad (EHITUSKULUDE LIIGITAMINE EVS 885:2005); Material: Kivi - Uus Konstruktsioon 150 mm
Arhitektuur - 02 Materjal: Kivi - Uus Konstruktsioon; 03 Tähistus: SS-3; 05 Asukoht: Interior
Ehituskonstruktsioonid - 02 Materjal: Kivi - Uus Konstruktsioon; 03 Tähistus või ristlõige: SS-3; 07 Monteeritava elemendi mass: Undefined; 09 Monteeritava elemendi positisioon/mark: Undefined; 10 Elemendi valmistamise tehnoloogia: Undefined
Pset_WallCommon - IsExternal: no
Name | In | Arhitektuur, 01 Nimetus = Ehituskonstruktsioonid, 01 Nimetus | 06 Kandevelementide eristatus | 04 Materjali peamine tugevusnäitaja = 05 Keskkonnaklass | 06 Maht (kubatuur) | 08 Monteeritava elemendi pikkus | 11 Ülemine kõrgusmärk | 12 Alumine kõrgusmärk | Renovation Status
uus ss 150 | 1 KORRUS | uus ss 150 | Non-Load-Bearing Element | - | 0,15 | 1 605; Undefined | 0; Kõrgus: 2 600; 3D pikkus: 1 605 | 0 | New | Pset_WallCommon - LoadBearing: no
sahti sein | 2 KORRUS | uus kinni ehitav sein 150 | - | Undefined | 0,70 | 12 500; Undefined | 2 545; Kõrgus: 375; 3D pikkus: 12 500 | 2 545 | Existing

# IfcWallStandardCase: SW - 002, Kivi - Ol.Olev Konstruktsioon
In: 1 KORRUS
Type - ElementType: Element type SW - 002
Classification: 1.18 IfcWall (sein) (_RKAS BIM + ARCHICAD Classification); 32 Kandvad ja välisseinad (EHITUSKULUDE LIIGITAMINE EVS 885:2005); Material: Kivi - Ol.Olev Konstruktsioon 300 mm
Arhitektuur - 01 Nimetus: Kivi - Ol.Olev Konstruktsioon; 02 Materjal: Kivi - Ol.Olev Konstruktsioon; 03 Tähistus: SW - 002; 04 Tulepüsivus: Undefined; 05 Asukoht: Exterior; 06 Kandevelementide eristatus: Non-Load-Bearing Element; 07 Helipidavus: Undefined; 08 Soojusläbivus (U-arv): Undefined
Ehituskonstruktsioonid - 01 Nimetus: Kivi - Ol.Olev Konstruktsioon; 02 Materjal: Kivi - Ol.Olev Konstruktsioon; 03 Tähistus või ristlõige: SW - 002; 06 Maht (kubatuur): 3,60; 11 Ülemine kõrgusmärk: 0; Kõrgus: 2 000; 3D pikkus: 5 999; 12 Alumine kõrgusmärk: 0
AC_Pset_RenovationAndPhasing - Renovation Status: Existing
Pset_WallCommon - LoadBearing: no; IsExternal: yes

# IfcWallStandardCase: SW - 003, Kivi - Ol.Olev Konstruktsioon
In: 1 KORRUS
Type - ElementType: Element type SW - 003
Classification: 1.18 IfcWall (sein) (_RKAS BIM + ARCHICAD Classification); 32 Kandvad ja välisseinad (EHITUSKULUDE LIIGITAMINE EVS 885:2005); Material: Kivi - Ol.Olev Konstruktsioon 300 mm
Arhitektuur - 01 Nimetus: Kivi - Ol.Olev Konstruktsioon; 02 Materjal: Kivi - Ol.Olev Konstruktsioon; 03 Tähistus: SW - 003; 04 Tulepüsivus: Undefined; 05 Asukoht: Exterior; 06 Kandevelementide eristatus: Non-Load-Bearing Element; 07 Helipidavus: Undefined; 08 Soojusläbivus (U-arv): Undefined
Ehituskonstruktsioonid - 01 Nimetus: Kivi - Ol.Olev Konstruktsioon; 02 Materjal: Kivi - Ol.Olev Konstruktsioon; 03 Tähistus või ristlõige: SW - 003; 06 Maht (kubatuur): 6,99; 11 Ülemine kõrgusmärk: 0; Kõrgus: 2 000; 3D pikkus: 11 656; 12 Alumine kõrgusmärk: 0
AC_Pset_RenovationAndPhasing - Renovation Status: Existing
Pset_WallCommon - LoadBearing: no; IsExternal: yes

# IfcWallStandardCase: SW - 004, Kivi - Ol.Olev Konstruktsioon
In: 1 KORRUS
Type - ElementType: Element type SW - 004
Classification: 1.18 IfcWall (sein) (_RKAS BIM + ARCHICAD Classification); 32 Kandvad ja välisseinad (EHITUSKULUDE LIIGITAMINE EVS 885:2005); Material: Kivi - Ol.Olev Konstruktsioon 300 mm
Arhitektuur - 01 Nimetus: Kivi - Ol.Olev Konstruktsioon; 02 Materjal: Kivi - Ol.Olev Konstruktsioon; 03 Tähistus: SW - 004; 04 Tulepüsivus: Undefined; 05 Asukoht: Exterior; 06 Kandevelementide eristatus: Non-Load-Bearing Element; 07 Helipidavus: Undefined; 08 Soojusläbivus (U-arv): Undefined
Ehituskonstruktsioonid - 01 Nimetus: Kivi - Ol.Olev Konstruktsioon; 02 Materjal: Kivi - Ol.Olev Konstruktsioon; 03 Tähistus või ristlõige: SW - 004; 06 Maht (kubatuur): 3,42; 11 Ülemine kõrgusmärk: 0; Kõrgus: 2 000; 3D pikkus: 5 702; 12 Alumine kõrgusmärk: 0
AC_Pset_RenovationAndPhasing - Renovation Status: Existing
Pset_WallCommon - LoadBearing: no; IsExternal: yes

# IfcWallStandardCase: SW - 022 (114)
Type - ElementType: Element type SW - 022
Arhitektuur - 03 Tähistus: SW - 022; 05 Asukoht: Interior
Ehituskonstruktsioonid - 03 Tähistus või ristlõige: SW - 022
Pset_WallCommon - IsExternal: no
Name | In | Classification | Material | Arhitektuur, 01 Nimetus = Ehituskonstruktsioonid, 01 Nimetus | Arhitektuur, 02 Materjal = Ehituskonstruktsioonid, 02 Materjal | 06 Kandevelementide eristatus | 04 Materjali peamine tugevusnäitaja = 05 Keskkonnaklass = 07 Monteeritava elemendi mass = 09 Monteeritava elemendi positisioon/mark = 10 Elemendi valmistamise tehnoloogia | 06 Maht (kubatuur) | 08 Monteeritava elemendi pikkus | 11 Ülemine kõrgusmärk | 12 Alumine kõrgusmärk | Renovation Status | LoadBearing
ol.olev ss 150 | 1 KORRUS | 2.15 IfcWall (sein) (_RKAS BIM + ARCHICAD Classification); 51 Vaheseinad (EHITUSKULUDE LIIGITAMINE EVS 885:2005) | Kivi -Ol.Olev Konstruktsioon 150 mm | ol.olev ss 150 | Kivi -Ol.Olev Konstruktsioon | Non-Load-Bearing Element | Undefined | 0,22 | 1 663; Undefined | 0; Kõrgus: 2 600; 3D pikkus: 1 663 | 0 | Existing | no
ol.olev ss 200 | 1 KORRUS | 2.15 IfcWall (sein) (_RKAS BIM + ARCHICAD Classification); 51 Vaheseinad (EHITUSKULUDE LIIGITAMINE EVS 885:2005) | Kivi -Ol.Olev Konstruktsioon 200 mm | ol.olev ss 200 | Kivi -Ol.Olev Konstruktsioon | Non-Load-Bearing Element | Undefined | 0,66 | 1 268; Undefined | 0; Kõrgus: 2 600; 3D pikkus: 1 268 | 0 | Existing | no
ol.olev ss 420 | 1 KORRUS | 32 Kandvad ja välisseinad (EHITUSKULUDE LIIGITAMINE EVS 885:2005); 2.15 IfcWall (sein) (_RKAS BIM + ARCHICAD Classification) | Kivi -Ol.Olev Konstruktsioon 420 mm | ol.olev ss 420 | Kivi -Ol.Olev Konstruktsioon | Load-Bearing Element | Undefined | 26,63 | 30 001; Undefined | 0; Kõrgus: 2 600; 3D pikkus: 30 001 | 0 | Existing | yes | Arhitektuur - 07 Helipidavus: -; 08 Soojusläbivus (U-arv): -; 04 Tulepüsivus: -
ol.olev ss 150 | 1 KORRUS | 2.15 IfcWall (sein) (_RKAS BIM + ARCHICAD Classification); 51 Vaheseinad (EHITUSKULUDE LIIGITAMINE EVS 885:2005) | Kivi -Ol.Olev Konstruktsioon 150 mm | ol.olev ss 150 | Kivi -Ol.Olev Konstruktsioon | Non-Load-Bearing Element | Undefined | 1,42 | 3 639; Undefined | 0; Kõrgus: 2 600; 3D pikkus: 3 639 | 0 | Existing | no
ol.olev ss 420 | 1 KORRUS | 32 Kandvad ja välisseinad (EHITUSKULUDE LIIGITAMINE EVS 885:2005); 2.15 IfcWall (sein) (_RKAS BIM + ARCHICAD Classification) | Kivi -Ol.Olev Konstruktsioon 420 mm | ol.olev ss 420 | Kivi -Ol.Olev Konstruktsioon | Load-Bearing Element | Undefined | 22,88 | 23 856; Undefined | 0; Kõrgus: 2 600; 3D pikkus: 23 856 | 0 | Existing | yes | Arhitektuur - 07 Helipidavus: -; 08 Soojusläbivus (U-arv): -; 04 Tulepüsivus: -
ol.olev ss 250 | 1 KORRUS | 2.15 IfcWall (sein) (_RKAS BIM + ARCHICAD Classification); 51 Vaheseinad (EHITUSKULUDE LIIGITAMINE EVS 885:2005) | Kivi -Ol.Olev Konstruktsioon 250 mm | ol.olev ss 250 | Kivi -Ol.Olev Konstruktsioon | Non-Load-Bearing Element | Undefined | 2,53 | 3 897; Undefined | 0; Kõrgus: 2 600; 3D pikkus: 3 897 | 0 | Existing | no
ol.olev ss 150 | 1 KORRUS | 2.15 IfcWall (sein) (_RKAS BIM + ARCHICAD Classification); 51 Vaheseinad (EHITUSKULUDE LIIGITAMINE EVS 885:2005) | Kivi -Ol.Olev Konstruktsioon 150 mm | ol.olev ss 150 | Kivi -Ol.Olev Konstruktsioon | Non-Load-Bearing Element | Undefined | 7,82 | 23 195; Undefined | 0; Kõrgus: 2 600; 3D pikkus: 23 195 | 0 | Existing | no
ol.olev ss 420 | 1 KORRUS | 32 Kandvad ja välisseinad (EHITUSKULUDE LIIGITAMINE EVS 885:2005); 2.15 IfcWall (sein) (_RKAS BIM + ARCHICAD Classification) | Kivi -Ol.Olev Konstruktsioon 420 mm | ol.olev ss 420 | Kivi -Ol.Olev Konstruktsioon | Load-Bearing Element | Undefined | 7,67 | 7 863; Undefined | 0; Kõrgus: 2 600; 3D pikkus: 7 863 | 0 | Existing | yes | Arhitektuur - 07 Helipidavus: -; 08 Soojusläbivus (U-arv): -; 04 Tulepüsivus: -
ol.olev ss 420 | 1 KORRUS | 32 Kandvad ja välisseinad (EHITUSKULUDE LIIGITAMINE EVS 885:2005); 2.15 IfcWall (sein) (_RKAS BIM + ARCHICAD Classification) | Kivi -Ol.Olev Konstruktsioon 420 mm | ol.olev ss 420 | Kivi -Ol.Olev Konstruktsioon | Load-Bearing Element | Undefined | 4,14 | 3 868; Undefined | 0; Kõrgus: 2 600; 3D pikkus: 3 868 | 0 | Existing | yes | Arhitektuur - 07 Helipidavus: -; 08 Soojusläbivus (U-arv): -; 04 Tulepüsivus: -
ol.olev ss 420 | 1 KORRUS | 32 Kandvad ja välisseinad (EHITUSKULUDE LIIGITAMINE EVS 885:2005); 2.15 IfcWall (sein) (_RKAS BIM + ARCHICAD Classification) | Kivi -Ol.Olev Konstruktsioon 420 mm | ol.olev ss 420 | Kivi -Ol.Olev Konstruktsioon | Load-Bearing Element | Undefined | 4,81 | 6 425; Undefined | 0; Kõrgus: 2 761; 3D pikkus: 6 425 | 0 | Existing | yes | Arhitektuur - 07 Helipidavus: -; 08 Soojusläbivus (U-arv): -; 04 Tulepüsivus: -
ol.olev ss 100 | 1 KORRUS | 2.15 IfcWall (sein) (_RKAS BIM + ARCHICAD Classification); 51 Vaheseinad (EHITUSKULUDE LIIGITAMINE EVS 885:2005) | Kivi -Ol.Olev Konstruktsioon 100 mm | ol.olev ss 100 | Kivi -Ol.Olev Konstruktsioon | Non-Load-Bearing Element | Undefined | 0,71 | 3 444; Undefined | 0; Kõrgus: 2 600; 3D pikkus: 3 444 | 0 | Existing | no | Arhitektuur - 07 Helipidavus: -; 08 Soojusläbivus (U-arv): -; 04 Tulepüsivus: -
ol.olev ss 420 | 1 KORRUS | 32 Kandvad ja välisseinad (EHITUSKULUDE LIIGITAMINE EVS 885:2005); 2.15 IfcWall (sein) (_RKAS BIM + ARCHICAD Classification) | Kivi -Ol.Olev Konstruktsioon 420 mm | ol.olev ss 420 | Kivi -Ol.Olev Konstruktsioon | Load-Bearing Element | Undefined | 4,44 | 5 993; Undefined | 0; Kõrgus: 2 600; 3D pikkus: 5 993 | 0 | Existing | yes | Arhitektuur - 07 Helipidavus: -; 08 Soojusläbivus (U-arv): -; 04 Tulepüsivus: -
ol.olev ss 300 | 1 KORRUS | 32 Kandvad ja välisseinad (EHITUSKULUDE LIIGITAMINE EVS 885:2005); 2.15 IfcWall (sein) (_RKAS BIM + ARCHICAD Classification) | Kivi -Ol.Olev Konstruktsioon 300 mm | ol.olev ss 300 | Kivi -Ol.Olev Konstruktsioon | Load-Bearing Element | Undefined | 4,08 | 5 927; Undefined | 0; Kõrgus: 2 600; 3D pikkus: 5 927 | 0 | Existing | yes | Arhitektuur - 08 Soojusläbivus (U-arv): -
ol.olev ss 200 | 1 KORRUS | 2.15 IfcWall (sein) (_RKAS BIM + ARCHICAD Classification); 51 Vaheseinad (EHITUSKULUDE LIIGITAMINE EVS 885:2005) | Kivi -Ol.Olev Konstruktsioon 200 mm | ol.olev ss 200 | Kivi -Ol.Olev Konstruktsioon | Non-Load-Bearing Element | Undefined | 4,24 | 9 154; Undefined | 0; Kõrgus: 2 600; 3D pikkus: 9 154 | 0 | Existing | no
ol.olev ss 420 | 1 KORRUS | 32 Kandvad ja välisseinad (EHITUSKULUDE LIIGITAMINE EVS 885:2005); 2.15 IfcWall (sein) (_RKAS BIM + ARCHICAD Classification) | Kivi -Ol.Olev Konstruktsioon 420 mm | ol.olev ss 420 | Kivi -Ol.Olev Konstruktsioon | Load-Bearing Element | Undefined | 6,26 | 5 730; Undefined | 0; Kõrgus: 2 600; 3D pikkus: 5 730 | 0 | Existing | yes | Arhitektuur - 07 Helipidavus: -; 08 Soojusläbivus (U-arv): -; 04 Tulepüsivus: -
ol.olev ss 200 | 1 KORRUS | 2.15 IfcWall (sein) (_RKAS BIM + ARCHICAD Classification); 51 Vaheseinad (EHITUSKULUDE LIIGITAMINE EVS 885:2005) | Kivi -Ol.Olev Konstruktsioon 200 mm | ol.olev ss 200 | Kivi -Ol.Olev Konstruktsioon | Non-Load-Bearing Element | Undefined | 0,77 | 1 486; Undefined | 0; Kõrgus: 2 600; 3D pikkus: 1 486 | 0 | Existing | no
ol.olev ss 150 | 2 KORRUS | 2.15 IfcWall (sein) (_RKAS BIM + ARCHICAD Classification); 51 Vaheseinad (EHITUSKULUDE LIIGITAMINE EVS 885:2005) | Kivi -Ol.Olev Konstruktsioon 150 mm | ol.olev ss 150 | Kivi -Ol.Olev Konstruktsioon | Non-Load-Bearing Element | Undefined | 2,76 | 6 321; Undefined | 3 000; Kõrgus: 3 250; 3D pikkus: 6 321 | 3 000 | Existing | no
ol.olev ss 150 | 2 KORRUS | 2.15 IfcWall (sein) (_RKAS BIM + ARCHICAD Classification); 51 Vaheseinad (EHITUSKULUDE LIIGITAMINE EVS 885:2005) | Kivi -Ol.Olev Konstruktsioon 150 mm | ol.olev ss 150 | Kivi -Ol.Olev Konstruktsioon | Non-Load-Bearing Element | Undefined | 3,07 | 6 722; Undefined | 3 000; Kõrgus: 3 250; 3D pikkus: 6 722 | 3 000 | Existing | no
ol.olev ss 560 | 2 KORRUS | 32 Kandvad ja välisseinad (EHITUSKULUDE LIIGITAMINE EVS 885:2005); 2.15 IfcWall (sein) (_RKAS BIM + ARCHICAD Classification) | Kivi -Ol.Olev Konstruktsioon 560 mm | ol.olev ss 560 | Kivi -Ol.Olev Konstruktsioon | Load-Bearing Element | Undefined | 20,51 | 13 363; Undefined | 3 000; Kõrgus: 3 250; 3D pikkus: 13 363 | 3 000 | Existing | yes
ol.olev ss 420 | 2 KORRUS | 32 Kandvad ja välisseinad (EHITUSKULUDE LIIGITAMINE EVS 885:2005); 2.15 IfcWall (sein) (_RKAS BIM + ARCHICAD Classification) | Kivi -Ol.Olev Konstruktsioon 420 mm | ol.olev ss 420 | Kivi -Ol.Olev Konstruktsioon | Load-Bearing Element | Undefined | 18,87 | 15 877; Undefined | 3 000; Kõrgus: 3 250; 3D pikkus: 15 877 | 3 000 | Existing | yes | Arhitektuur - 07 Helipidavus: -; 08 Soojusläbivus (U-arv): -; 04 Tulepüsivus: -
ol.olev ss 420 | 2 KORRUS | 32 Kandvad ja välisseinad (EHITUSKULUDE LIIGITAMINE EVS 885:2005); 2.15 IfcWall (sein) (_RKAS BIM + ARCHICAD Classification) | Kivi -Ol.Olev Konstruktsioon 420 mm | ol.olev ss 420 | Kivi -Ol.Olev Konstruktsioon | Load-Bearing Element | Undefined | 15,15 | 12 581; Undefined | 3 000; Kõrgus: 3 250; 3D pikkus: 12 581 | 3 000 | Existing | yes | Arhitektuur - 07 Helipidavus: -; 08 Soojusläbivus (U-arv): -; 04 Tulepüsivus: -
ol.olev ss 420 | 2 KORRUS | 32 Kandvad ja välisseinad (EHITUSKULUDE LIIGITAMINE EVS 885:2005); 2.15 IfcWall (sein) (_RKAS BIM + ARCHICAD Classification) | Kivi -Ol.Olev Konstruktsioon 420 mm | ol.olev ss 420 | Kivi -Ol.Olev Konstruktsioon | Load-Bearing Element | Undefined | 24,41 | 21 245; Undefined | 3 000; Kõrgus: 3 250; 3D pikkus: 21 245 | 3 000 | Existing | yes | Arhitektuur - 07 Helipidavus: -; 08 Soojusläbivus (U-arv): -; 04 Tulepüsivus: -
ol.olev ss 150 | 2 KORRUS | 2.15 IfcWall (sein) (_RKAS BIM + ARCHICAD Classification); 51 Vaheseinad (EHITUSKULUDE LIIGITAMINE EVS 885:2005) | Kivi -Ol.Olev Konstruktsioon 150 mm | ol.olev ss 150 | Kivi -Ol.Olev Konstruktsioon | Non-Load-Bearing Element | Undefined | 9,20 | 23 576; Undefined | 3 000; Kõrgus: 3 250; 3D pikkus: 23 576 | 3 000 | Existing | no
2 x ol.olev ss 150 | 2 KORRUS | 2.15 IfcWall (sein) (_RKAS BIM + ARCHICAD Classification); 51 Vaheseinad (EHITUSKULUDE LIIGITAMINE EVS 885:2005) | Kivi -Ol.Olev Konstruktsioon 150 mm | ol.olev ss 150 | Kivi -Ol.Olev Konstruktsioon | Non-Load-Bearing Element | Undefined | 1,77 | 3 624; Undefined | 3 000; Kõrgus: 3 250; 3D pikkus: 3 624 | 3 000 | Existing | no
ol.olev ss 150 | 2 KORRUS | 2.15 IfcWall (sein) (_RKAS BIM + ARCHICAD Classification); 51 Vaheseinad (EHITUSKULUDE LIIGITAMINE EVS 885:2005) | Kivi -Ol.Olev Konstruktsioon 150 mm | ol.olev ss 150 | Kivi -Ol.Olev Konstruktsioon | Non-Load-Bearing Element | Undefined | 1,77 | 3 625; Undefined | 3 000; Kõrgus: 3 250; 3D pikkus: 3 625 | 3 000 | Existing | no
2 x ol.olev ss 150 | 2 KORRUS | 2.15 IfcWall (sein) (_RKAS BIM + ARCHICAD Classification); 51 Vaheseinad (EHITUSKULUDE LIIGITAMINE EVS 885:2005) | Kivi -Ol.Olev Konstruktsioon 150 mm | ol.olev ss 150 | Kivi -Ol.Olev Konstruktsioon | Non-Load-Bearing Element | Undefined | 1,77 | 3 628; Undefined | 3 000; Kõrgus: 3 250; 3D pikkus: 3 628 | 3 000 | Existing | no
2 x ol.olev ss 150 | 2 KORRUS | 2.15 IfcWall (sein) (_RKAS BIM + ARCHICAD Classification); 51 Vaheseinad (EHITUSKULUDE LIIGITAMINE EVS 885:2005) | Kivi -Ol.Olev Konstruktsioon 150 mm | ol.olev ss 150 | Kivi -Ol.Olev Konstruktsioon | Non-Load-Bearing Element | Undefined | 1,77 | 3 629; Undefined | 3 000; Kõrgus: 3 250; 3D pikkus: 3 629 | 3 000 | Existing | no
ol.olev ss 100 | 2 KORRUS | 1.18 IfcWall (sein) (_RKAS BIM + ARCHICAD Classification); 51 Vaheseinad (EHITUSKULUDE LIIGITAMINE EVS 885:2005) | Kivi -Ol.Olev Konstruktsioon 100 mm | ol.olev ss 100 | Kivi -Ol.Olev Konstruktsioon | Non-Load-Bearing Element |  | 0,96 |  | 3 000; Kõrgus: 3 250; 3D pikkus: 3 629 | 3 000 | Existing | no | Arhitektuur - 07 Helipidavus: -; 08 Soojusläbivus (U-arv): -; 04 Tulepüsivus: -
ol.olev ss 150 | 2 KORRUS | 2.15 IfcWall (sein) (_RKAS BIM + ARCHICAD Classification); 51 Vaheseinad (EHITUSKULUDE LIIGITAMINE EVS 885:2005) | Kivi -Ol.Olev Konstruktsioon 150 mm | ol.olev ss 150 | Kivi -Ol.Olev Konstruktsioon | Non-Load-Bearing Element | Undefined | 1,64 | 3 361; Undefined | 3 000; Kõrgus: 3 250; 3D pikkus: 3 361 | 3 000 | Existing | no
ol.olev ss 150 | 2 KORRUS | 2.15 IfcWall (sein) (_RKAS BIM + ARCHICAD Classification); 51 Vaheseinad (EHITUSKULUDE LIIGITAMINE EVS 885:2005) | Kivi -Ol.Olev Konstruktsioon 150 mm | ol.olev ss 150 | Kivi -Ol.Olev Konstruktsioon | Non-Load-Bearing Element | Undefined | 1,64 | 3 362; Undefined | 3 000; Kõrgus: 3 250; 3D pikkus: 3 362 | 3 000 | Existing | no
ol.olev ss 200 | 2 KORRUS | 2.15 IfcWall (sein) (_RKAS BIM + ARCHICAD Classification); 51 Vaheseinad (EHITUSKULUDE LIIGITAMINE EVS 885:2005) | Kivi -Ol.Olev Konstruktsioon 200 mm | ol.olev ss 200 | Kivi -Ol.Olev Konstruktsioon | Non-Load-Bearing Element | Undefined | 2,52 | 3 870; Undefined | 3 000; Kõrgus: 3 250; 3D pikkus: 3 870 | 3 000 | Existing | no
ol.olev ss 200 | 2 KORRUS | 2.15 IfcWall (sein) (_RKAS BIM + ARCHICAD Classification); 51 Vaheseinad (EHITUSKULUDE LIIGITAMINE EVS 885:2005) | Kivi -Ol.Olev Konstruktsioon 200 mm | ol.olev ss 200 | Kivi -Ol.Olev Konstruktsioon | Non-Load-Bearing Element | Undefined | 2,52 | 4 270; Undefined | 3 000; Kõrgus: 3 250; 3D pikkus: 4 270 | 3 000 | Existing | no
ol.olev ss 150 | 2 KORRUS | 2.15 IfcWall (sein) (_RKAS BIM + ARCHICAD Classification); 51 Vaheseinad (EHITUSKULUDE LIIGITAMINE EVS 885:2005) | Kivi -Ol.Olev Konstruktsioon 150 mm | ol.olev ss 150 | Kivi -Ol.Olev Konstruktsioon | Non-Load-Bearing Element | Undefined | 2,53 | 5 871; Undefined | 3 000; Kõrgus: 3 250; 3D pikkus: 5 871 | 3 000 | Existing | no
ol.olev ss 150 | 2 KORRUS | 2.15 IfcWall (sein) (_RKAS BIM + ARCHICAD Classification); 51 Vaheseinad (EHITUSKULUDE LIIGITAMINE EVS 885:2005) | Kivi -Ol.Olev Konstruktsioon 150 mm | ol.olev ss 150 | Kivi -Ol.Olev Konstruktsioon | Non-Load-Bearing Element | Undefined | 3,04 | 7 986; Undefined | 3 000; Kõrgus: 3 250; 3D pikkus: 7 986 | 3 000 | Existing | no
ol.olev ss 150 | 2 KORRUS | 2.15 IfcWall (sein) (_RKAS BIM + ARCHICAD Classification); 51 Vaheseinad (EHITUSKULUDE LIIGITAMINE EVS 885:2005) | Kivi -Ol.Olev Konstruktsioon 150 mm | ol.olev ss 150 | Kivi -Ol.Olev Konstruktsioon | Non-Load-Bearing Element | Undefined | 2,67 | 5 472; Undefined | 3 000; Kõrgus: 3 250; 3D pikkus: 5 472 | 3 000 | Existing | no
ol.olev ss 150 | 2 KORRUS | 2.15 IfcWall (sein) (_RKAS BIM + ARCHICAD Classification); 51 Vaheseinad (EHITUSKULUDE LIIGITAMINE EVS 885:2005) | Kivi -Ol.Olev Konstruktsioon 150 mm | ol.olev ss 150 | Kivi -Ol.Olev Konstruktsioon | Non-Load-Bearing Element | Undefined | 3,07 | 6 723; Undefined | 3 000; Kõrgus: 3 250; 3D pikkus: 6 723 | 3 000 | Existing | no
ol.olev ss 150 | 2 KORRUS | 2.15 IfcWall (sein) (_RKAS BIM + ARCHICAD Classification); 51 Vaheseinad (EHITUSKULUDE LIIGITAMINE EVS 885:2005) | Kivi -Ol.Olev Konstruktsioon 150 mm | ol.olev ss 150 | Kivi -Ol.Olev Konstruktsioon | Non-Load-Bearing Element | Undefined | 3,08 | 6 723; Undefined | 3 000; Kõrgus: 3 250; 3D pikkus: 6 723 | 3 000 | Existing | no
ol.olev ss 420 | 2 KORRUS | 32 Kandvad ja välisseinad (EHITUSKULUDE LIIGITAMINE EVS 885:2005); 2.15 IfcWall (sein) (_RKAS BIM + ARCHICAD Classification) | Kivi -Ol.Olev Konstruktsioon 420 mm | ol.olev ss 420 | Kivi -Ol.Olev Konstruktsioon | Load-Bearing Element | Undefined | 17,77 | 15 191; Undefined | 3 000; Kõrgus: 3 250; 3D pikkus: 15 191 | 3 000 | Existing | yes | Arhitektuur - 07 Helipidavus: -; 08 Soojusläbivus (U-arv): -; 04 Tulepüsivus: -
ol.olev ss 420 | 2 KORRUS | 32 Kandvad ja välisseinad (EHITUSKULUDE LIIGITAMINE EVS 885:2005); 2.15 IfcWall (sein) (_RKAS BIM + ARCHICAD Classification) | Kivi -Ol.Olev Konstruktsioon 420 mm | ol.olev ss 420 | Kivi -Ol.Olev Konstruktsioon | Load-Bearing Element | Undefined | 21,15 | 17 669; Undefined | 3 000; Kõrgus: 3 250; 3D pikkus: 17 669 | 3 000 | Existing | yes | Arhitektuur - 07 Helipidavus: -; 08 Soojusläbivus (U-arv): -; 04 Tulepüsivus: -
ol.olev ss 420 | 2 KORRUS | 32 Kandvad ja välisseinad (EHITUSKULUDE LIIGITAMINE EVS 885:2005); 2.15 IfcWall (sein) (_RKAS BIM + ARCHICAD Classification) | Kivi -Ol.Olev Konstruktsioon 420 mm | ol.olev ss 420 | Kivi -Ol.Olev Konstruktsioon | Load-Bearing Element | Undefined | 9,34 | 7 890; Undefined | 3 000; Kõrgus: 3 250; 3D pikkus: 7 890 | 3 000 | Existing | yes | Arhitektuur - 07 Helipidavus: -; 08 Soojusläbivus (U-arv): -; 04 Tulepüsivus: -
ol.olev ss 420 | 2 KORRUS | 32 Kandvad ja välisseinad (EHITUSKULUDE LIIGITAMINE EVS 885:2005); 2.15 IfcWall (sein) (_RKAS BIM + ARCHICAD Classification) | Kivi -Ol.Olev Konstruktsioon 420 mm | ol.olev ss 420 | Kivi -Ol.Olev Konstruktsioon | Load-Bearing Element | Undefined | 7,49 | 6 828; Undefined | 3 000; Kõrgus: 3 250; 3D pikkus: 6 828 | 3 000 | Existing | yes | Arhitektuur - 07 Helipidavus: -; 08 Soojusläbivus (U-arv): -; 04 Tulepüsivus: -
ol.olev ss 150 | 2 KORRUS | 2.15 IfcWall (sein) (_RKAS BIM + ARCHICAD Classification); 51 Vaheseinad (EHITUSKULUDE LIIGITAMINE EVS 885:2005) | Kivi -Ol.Olev Konstruktsioon 150 mm | ol.olev ss 150 | Kivi -Ol.Olev Konstruktsioon | Non-Load-Bearing Element | Undefined | 1,35 | 3 391; Undefined | 3 000; Kõrgus: 3 250; 3D pikkus: 3 391 | 3 000 | Existing | no
ol.olev ss 150 | 2 KORRUS | 2.15 IfcWall (sein) (_RKAS BIM + ARCHICAD Classification); 51 Vaheseinad (EHITUSKULUDE LIIGITAMINE EVS 885:2005) | Kivi -Ol.Olev Konstruktsioon 150 mm | ol.olev ss 150 | Kivi -Ol.Olev Konstruktsioon | Non-Load-Bearing Element | Undefined | 1,65 | 3 783; Undefined | 3 000; Kõrgus: 3 250; 3D pikkus: 3 783 | 3 000 | Existing | no
ol.olev ss 150 | 2 KORRUS | 2.15 IfcWall (sein) (_RKAS BIM + ARCHICAD Classification); 51 Vaheseinad (EHITUSKULUDE LIIGITAMINE EVS 885:2005) | Kivi -Ol.Olev Konstruktsioon 150 mm | ol.olev ss 150 | Kivi -Ol.Olev Konstruktsioon | Non-Load-Bearing Element | Undefined | 1,51 | 3 893; Undefined | 3 000; Kõrgus: 3 250; 3D pikkus: 3 893 | 3 000 | Existing | no
ol.olev ss 150 | 2 KORRUS | 2.15 IfcWall (sein) (_RKAS BIM + ARCHICAD Classification); 51 Vaheseinad (EHITUSKULUDE LIIGITAMINE EVS 885:2005) | Kivi -Ol.Olev Konstruktsioon 150 mm | ol.olev ss 150 | Kivi -Ol.Olev Konstruktsioon | Non-Load-Bearing Element | Undefined | 1,34 | 3 388; Undefined | 3 000; Kõrgus: 3 250; 3D pikkus: 3 388 | 3 000 | Existing | no
ol.olev ss 150 | 2 KORRUS | 2.15 IfcWall (sein) (_RKAS BIM + ARCHICAD Classification); 51 Vaheseinad (EHITUSKULUDE LIIGITAMINE EVS 885:2005) | Kivi -Ol.Olev Konstruktsioon 150 mm | ol.olev ss 150 | Kivi -Ol.Olev Konstruktsioon | Non-Load-Bearing Element | Undefined | 1,77 | 3 715; Undefined | 3 000; Kõrgus: 3 250; 3D pikkus: 3 715 | 3 000 | Existing | no
ol.olev ss 150 | 2 KORRUS | 2.15 IfcWall (sein) (_RKAS BIM + ARCHICAD Classification); 51 Vaheseinad (EHITUSKULUDE LIIGITAMINE EVS 885:2005) | Kivi -Ol.Olev Konstruktsioon 150 mm | ol.olev ss 150 | Kivi -Ol.Olev Konstruktsioon | Non-Load-Bearing Element | Undefined | 1,49 | 3 741; Undefined | 3 000; Kõrgus: 3 250; 3D pikkus: 3 741 | 3 000 | Existing | no
ol.olev ss 150 | 2 KORRUS | 2.15 IfcWall (sein) (_RKAS BIM + ARCHICAD Classification); 51 Vaheseinad (EHITUSKULUDE LIIGITAMINE EVS 885:2005) | Kivi -Ol.Olev Konstruktsioon 150 mm | ol.olev ss 150 | Kivi -Ol.Olev Konstruktsioon | Non-Load-Bearing Element | Undefined | 2,68 | 5 899; Undefined | 3 000; Kõrgus: 3 250; 3D pikkus: 5 899 | 3 000 | Existing | no
3 x ol.olev ss 150 | 2 KORRUS | 2.15 IfcWall (sein) (_RKAS BIM + ARCHICAD Classification); 51 Vaheseinad (EHITUSKULUDE LIIGITAMINE EVS 885:2005) | Kivi -Ol.Olev Konstruktsioon 150 mm | ol.olev ss 150 | Kivi -Ol.Olev Konstruktsioon | Non-Load-Bearing Element | Undefined | 2,68 | 5 500; Undefined | 3 000; Kõrgus: 3 250; 3D pikkus: 5 500 | 3 000 | Existing | no
ol.olev ss 150 | 2 KORRUS | 2.15 IfcWall (sein) (_RKAS BIM + ARCHICAD Classification); 51 Vaheseinad (EHITUSKULUDE LIIGITAMINE EVS 885:2005) | Kivi -Ol.Olev Konstruktsioon 150 mm | ol.olev ss 150 | Kivi -Ol.Olev Konstruktsioon | Non-Load-Bearing Element | Undefined | 2,68 | 5 900; Undefined | 3 000; Kõrgus: 3 250; 3D pikkus: 5 900 | 3 000 | Existing | no
ol.olev ss 120 | 2 KORRUS | 2.15 IfcWall (sein) (_RKAS BIM + ARCHICAD Classification); 51 Vaheseinad (EHITUSKULUDE LIIGITAMINE EVS 885:2005) | Kivi -Ol.Olev Konstruktsioon 120 mm | ol.olev ss 120 | Kivi -Ol.Olev Konstruktsioon | Non-Load-Bearing Element | Undefined | 2,31 | 5 910; Undefined | 3 000; Kõrgus: 3 250; 3D pikkus: 5 910 | 3 000 | Existing | no
ol.olev ss 150 | 2 KORRUS | 2.15 IfcWall (sein) (_RKAS BIM + ARCHICAD Classification); 51 Vaheseinad (EHITUSKULUDE LIIGITAMINE EVS 885:2005) | Kivi -Ol.Olev Konstruktsioon 150 mm | ol.olev ss 150 | Kivi -Ol.Olev Konstruktsioon | Non-Load-Bearing Element | Undefined | 2,88 | 5 900; Undefined | 3 000; Kõrgus: 3 250; 3D pikkus: 5 900 | 3 000 | Existing | no
ol.olev ss 150 | 2 KORRUS | 2.15 IfcWall (sein) (_RKAS BIM + ARCHICAD Classification); 51 Vaheseinad (EHITUSKULUDE LIIGITAMINE EVS 885:2005) | Kivi -Ol.Olev Konstruktsioon 150 mm | ol.olev ss 150 | Kivi -Ol.Olev Konstruktsioon | Non-Load-Bearing Element | Undefined | 1,66 | 3 814; Undefined | 3 000; Kõrgus: 3 250; 3D pikkus: 3 814 | 3 000 | Existing | no
ol.olev ss 150 | 2 KORRUS | 2.15 IfcWall (sein) (_RKAS BIM + ARCHICAD Classification); 51 Vaheseinad (EHITUSKULUDE LIIGITAMINE EVS 885:2005) | Kivi -Ol.Olev Konstruktsioon 150 mm | ol.olev ss 150 | Kivi -Ol.Olev Konstruktsioon | Non-Load-Bearing Element | Undefined | 1,66 | 3 413; Undefined | 3 000; Kõrgus: 3 250; 3D pikkus: 3 413 | 3 000 | Existing | no
ol.olev ss 150 | 2 KORRUS | 2.15 IfcWall (sein) (_RKAS BIM + ARCHICAD Classification); 51 Vaheseinad (EHITUSKULUDE LIIGITAMINE EVS 885:2005) | Kivi -Ol.Olev Konstruktsioon 150 mm | ol.olev ss 150 | Kivi -Ol.Olev Konstruktsioon | Non-Load-Bearing Element | Undefined | 1,40 | 3 413; Undefined | 3 000; Kõrgus: 3 250; 3D pikkus: 3 413 | 3 000 | Existing | no
ol.olev ss 150 | 2 KORRUS | 2.15 IfcWall (sein) (_RKAS BIM + ARCHICAD Classification); 51 Vaheseinad (EHITUSKULUDE LIIGITAMINE EVS 885:2005) | Kivi -Ol.Olev Konstruktsioon 150 mm | ol.olev ss 150 | Kivi -Ol.Olev Konstruktsioon | Non-Load-Bearing Element | Undefined | 2,88 | 6 578; Undefined | 3 000; Kõrgus: 3 250; 3D pikkus: 6 578 | 3 000 | Existing | no
ol.olev ss 150 | 2 KORRUS | 2.15 IfcWall (sein) (_RKAS BIM + ARCHICAD Classification); 51 Vaheseinad (EHITUSKULUDE LIIGITAMINE EVS 885:2005) | Kivi -Ol.Olev Konstruktsioon 150 mm | ol.olev ss 150 | Kivi -Ol.Olev Konstruktsioon | Non-Load-Bearing Element | Undefined | 8,63 | 21 204; Undefined | 3 000; Kõrgus: 3 250; 3D pikkus: 21 204 | 3 000 | Existing | no
ol.olev ss 420 | 2 KORRUS | 32 Kandvad ja välisseinad (EHITUSKULUDE LIIGITAMINE EVS 885:2005); 2.15 IfcWall (sein) (_RKAS BIM + ARCHICAD Classification) | Kivi -Ol.Olev Konstruktsioon 420 mm | ol.olev ss 420 | Kivi -Ol.Olev Konstruktsioon | Load-Bearing Element | Undefined | 7,51 | 5 500; Undefined | 3 000; Kõrgus: 3 250; 3D pikkus: 5 500 | 3 000 | Existing | yes | Arhitektuur - 07 Helipidavus: -; 08 Soojusläbivus (U-arv): -; 04 Tulepüsivus: -
ol.olev ss 420 | 2 KORRUS | 32 Kandvad ja välisseinad (EHITUSKULUDE LIIGITAMINE EVS 885:2005); 2.15 IfcWall (sein) (_RKAS BIM + ARCHICAD Classification) | Kivi -Ol.Olev Konstruktsioon 420 mm | ol.olev ss 420 | Kivi -Ol.Olev Konstruktsioon | Load-Bearing Element | Undefined | 7,95 | 5 821; Undefined | 3 000; Kõrgus: 3 250; 3D pikkus: 5 821 | 3 000 | Existing | yes | Arhitektuur - 07 Helipidavus: -; 08 Soojusläbivus (U-arv): -; 04 Tulepüsivus: -
ol.olev ss 300 | 2 KORRUS | 1.18 IfcWall (sein) (_RKAS BIM + ARCHICAD Classification); 51 Vaheseinad (EHITUSKULUDE LIIGITAMINE EVS 885:2005) | Kivi -Ol.Olev Konstruktsioon 300 mm | ol.olev ss 300 | Kivi -Ol.Olev Konstruktsioon | Load-Bearing Element |  | 4,07 |  | 3 000; Kõrgus: 2 567; 3D pikkus: 6 048 | 3 000 | Existing | yes | Arhitektuur - 07 Helipidavus: Undefined; 08 Soojusläbivus (U-arv): -; 04 Tulepüsivus: Undefined
ol.olev ss 300 | 2 KORRUS | 1.18 IfcWall (sein) (_RKAS BIM + ARCHICAD Classification); 51 Vaheseinad (EHITUSKULUDE LIIGITAMINE EVS 885:2005) | Kivi -Ol.Olev Konstruktsioon 300 mm | ol.olev ss 300 | Kivi -Ol.Olev Konstruktsioon | Load-Bearing Element |  | 0,69 |  | 3 000; Kõrgus: 2 287; 3D pikkus: 1 721 | 3 000 | Existing | yes | Arhitektuur - 07 Helipidavus: -; 08 Soojusläbivus (U-arv): -; 04 Tulepüsivus: -
ol.olev ss 420 | 2 KORRUS | 2.15 IfcWall (sein) (_RKAS BIM + ARCHICAD Classification); 51 Vaheseinad (EHITUSKULUDE LIIGITAMINE EVS 885:2005) | Kivi -Ol.Olev Konstruktsioon 420 mm | ol.olev ss 420 | Kivi -Ol.Olev Konstruktsioon | Load-Bearing Element | Undefined | 2,00 | 2 482; Undefined | 3 000; Kõrgus: 4 000; 3D pikkus: 2 482 | 3 000 | Existing | yes | Arhitektuur - 07 Helipidavus: -; 08 Soojusläbivus (U-arv): -; 04 Tulepüsivus: -
ol.olev ss 300 | 2 KORRUS | 32 Kandvad ja välisseinad (EHITUSKULUDE LIIGITAMINE EVS 885:2005); 2.15 IfcWall (sein) (_RKAS BIM + ARCHICAD Classification) | Kivi -Ol.Olev Konstruktsioon 300 mm | ol.olev ss 300 | Kivi -Ol.Olev Konstruktsioon | Load-Bearing Element | Undefined | 3,91 | 6 300; Undefined | 3 000; Kõrgus: 2 387; 3D pikkus: 6 300 | 3 000 | Existing | yes | Arhitektuur - 08 Soojusläbivus (U-arv): -
ol.olev ss 150 | 2 KORRUS | 2.15 IfcWall (sein) (_RKAS BIM + ARCHICAD Classification); 51 Vaheseinad (EHITUSKULUDE LIIGITAMINE EVS 885:2005) | Kivi -Ol.Olev Konstruktsioon 150 mm | ol.olev ss 150 | Kivi -Ol.Olev Konstruktsioon | Non-Load-Bearing Element | Undefined | 1,22 | 3 134; Undefined | 3 000; Kõrgus: 3 250; 3D pikkus: 3 134 | 3 000 | Existing | no
ol.olev ss 150 | 2 KORRUS | 2.15 IfcWall (sein) (_RKAS BIM + ARCHICAD Classification); 51 Vaheseinad (EHITUSKULUDE LIIGITAMINE EVS 885:2005) | Kivi -Ol.Olev Konstruktsioon 150 mm | ol.olev ss 150 | Kivi -Ol.Olev Konstruktsioon | Non-Load-Bearing Element | Undefined | 0,42 | 1 848; Undefined | 3 000; Kõrgus: 3 250; 3D pikkus: 1 848 | 3 000 | Existing | no
ol.olev ss 300 | 2 KORRUS | 32 Kandvad ja välisseinad (EHITUSKULUDE LIIGITAMINE EVS 885:2005); 2.15 IfcWall (sein) (_RKAS BIM + ARCHICAD Classification) | Kivi -Ol.Olev Konstruktsioon 300 mm | ol.olev ss 300 | Kivi -Ol.Olev Konstruktsioon | Load-Bearing Element | Undefined | 1,02 | 2 727; Undefined | 3 000; Kõrgus: 3 250; 3D pikkus: 2 727 | 3 000 | Existing | yes | Arhitektuur - 08 Soojusläbivus (U-arv): -
ol.olev ss 150 | 2 KORRUS | 2.15 IfcWall (sein) (_RKAS BIM + ARCHICAD Classification); 51 Vaheseinad (EHITUSKULUDE LIIGITAMINE EVS 885:2005) | Kivi -Ol.Olev Konstruktsioon 150 mm | ol.olev ss 150 | Kivi -Ol.Olev Konstruktsioon | Non-Load-Bearing Element | Undefined | 2,63 | 5 534; Undefined | 3 000; Kõrgus: 3 250; 3D pikkus: 5 534 | 3 000 | Existing | no
ol.olev ss 150 | 2 KORRUS | 2.15 IfcWall (sein) (_RKAS BIM + ARCHICAD Classification); 51 Vaheseinad (EHITUSKULUDE LIIGITAMINE EVS 885:2005) | Kivi -Ol.Olev Konstruktsioon 150 mm | ol.olev ss 150 | Kivi -Ol.Olev Konstruktsioon | Non-Load-Bearing Element | Undefined | 2,79 | 6 111; Undefined | 3 000; Kõrgus: 3 250; 3D pikkus: 6 111 | 3 000 | Existing | no
ol.olev ss 150 | 2 KORRUS | 2.15 IfcWall (sein) (_RKAS BIM + ARCHICAD Classification); 51 Vaheseinad (EHITUSKULUDE LIIGITAMINE EVS 885:2005) | Kivi -Ol.Olev Konstruktsioon 150 mm | ol.olev ss 150 | Kivi -Ol.Olev Konstruktsioon | Non-Load-Bearing Element | Undefined | 2,64 | 5 421; Undefined | 3 000; Kõrgus: 3 250; 3D pikkus: 5 421 | 3 000 | Existing | no
ol.olev ss 150 | 2 KORRUS | 2.15 IfcWall (sein) (_RKAS BIM + ARCHICAD Classification); 51 Vaheseinad (EHITUSKULUDE LIIGITAMINE EVS 885:2005) | Kivi -Ol.Olev Konstruktsioon 150 mm | ol.olev ss 150 | Kivi -Ol.Olev Konstruktsioon | Non-Load-Bearing Element | Undefined | 2,63 | 5 798; Undefined | 3 000; Kõrgus: 3 250; 3D pikkus: 5 798 | 3 000 | Existing | no
ol.olev ss 150 | 2 KORRUS | 2.15 IfcWall (sein) (_RKAS BIM + ARCHICAD Classification); 51 Vaheseinad (EHITUSKULUDE LIIGITAMINE EVS 885:2005) | Kivi -Ol.Olev Konstruktsioon 150 mm | ol.olev ss 150 | Kivi -Ol.Olev Konstruktsioon | Non-Load-Bearing Element | Undefined | 2,56 | 5 252; Undefined | 3 000; Kõrgus: 3 250; 3D pikkus: 5 252 | 3 000 | Existing | no
ol.olev ss 150 | 2 KORRUS | 2.15 IfcWall (sein) (_RKAS BIM + ARCHICAD Classification); 51 Vaheseinad (EHITUSKULUDE LIIGITAMINE EVS 885:2005) | Kivi -Ol.Olev Konstruktsioon 150 mm | ol.olev ss 150 | Kivi -Ol.Olev Konstruktsioon | Non-Load-Bearing Element | Undefined | 2,28 | 5 746; Undefined | 3 000; Kõrgus: 3 250; 3D pikkus: 5 746 | 3 000 | Existing | no
ol.olev ss 150 | 2 KORRUS | 2.15 IfcWall (sein) (_RKAS BIM + ARCHICAD Classification); 51 Vaheseinad (EHITUSKULUDE LIIGITAMINE EVS 885:2005) | Kivi -Ol.Olev Konstruktsioon 150 mm | ol.olev ss 150 | Kivi -Ol.Olev Konstruktsioon | Non-Load-Bearing Element | Undefined | 2,38 | 6 217; Undefined | 3 000; Kõrgus: 3 250; 3D pikkus: 6 217 | 3 000 | Existing | no
ol.olev ss 150 | 2 KORRUS | 2.15 IfcWall (sein) (_RKAS BIM + ARCHICAD Classification); 51 Vaheseinad (EHITUSKULUDE LIIGITAMINE EVS 885:2005) | Kivi -Ol.Olev Konstruktsioon 150 mm | ol.olev ss 150 | Kivi -Ol.Olev Konstruktsioon | Non-Load-Bearing Element | Undefined | 2,64 | 5 821; Undefined | 3 000; Kõrgus: 3 250; 3D pikkus: 5 821 | 3 000 | Existing | no
ol.olev ss 150 | 2 KORRUS | 2.15 IfcWall (sein) (_RKAS BIM + ARCHICAD Classification); 51 Vaheseinad (EHITUSKULUDE LIIGITAMINE EVS 885:2005) | Kivi -Ol.Olev Konstruktsioon 150 mm | ol.olev ss 150 | Kivi -Ol.Olev Konstruktsioon | Non-Load-Bearing Element | Undefined | 2,03 | 4 159; Undefined | 3 000; Kõrgus: 3 250; 3D pikkus: 4 159 | 3 000 | Existing | no
ol.olev ss 420 | 2 KORRUS | 32 Kandvad ja välisseinad (EHITUSKULUDE LIIGITAMINE EVS 885:2005); 2.15 IfcWall (sein) (_RKAS BIM + ARCHICAD Classification) | Kivi -Ol.Olev Konstruktsioon 420 mm | ol.olev ss 420 | Kivi -Ol.Olev Konstruktsioon | Load-Bearing Element | Undefined | 10,08 | 7 717; Undefined | 2 914; Kõrgus: 3 336; 3D pikkus: 7 717 | 2 914 | Existing | yes | Arhitektuur - 07 Helipidavus: -; 08 Soojusläbivus (U-arv): -; 04 Tulepüsivus: -
ol.olev ss 420 | 2 KORRUS | 32 Kandvad ja välisseinad (EHITUSKULUDE LIIGITAMINE EVS 885:2005); 2.15 IfcWall (sein) (_RKAS BIM + ARCHICAD Classification) | Kivi -Ol.Olev Konstruktsioon 420 mm | ol.olev ss 420 | Kivi -Ol.Olev Konstruktsioon | Load-Bearing Element | Undefined | 5,91 | 4 448; Undefined | 3 000; Kõrgus: 3 250; 3D pikkus: 4 448 | 3 000 | Existing | yes | Arhitektuur - 07 Helipidavus: -; 08 Soojusläbivus (U-arv): -; 04 Tulepüsivus: -
ol.olev ss 150 | 2 KORRUS | 2.15 IfcWall (sein) (_RKAS BIM + ARCHICAD Classification); 51 Vaheseinad (EHITUSKULUDE LIIGITAMINE EVS 885:2005) | Kivi -Ol.Olev Konstruktsioon 150 mm | ol.olev ss 150 | Kivi -Ol.Olev Konstruktsioon | Non-Load-Bearing Element | Undefined | 2,35 | 4 819; Undefined | 3 000; Kõrgus: 3 250; 3D pikkus: 4 819 | 3 000 | Existing | no
ol.olev ss 150 | 2 KORRUS | 2.15 IfcWall (sein) (_RKAS BIM + ARCHICAD Classification); 51 Vaheseinad (EHITUSKULUDE LIIGITAMINE EVS 885:2005) | Kivi -Ol.Olev Konstruktsioon 150 mm | ol.olev ss 150 | Kivi -Ol.Olev Konstruktsioon | Non-Load-Bearing Element | Undefined | 2,35 | 4 817; Undefined | 3 000; Kõrgus: 3 250; 3D pikkus: 4 817 | 3 000 | Existing | no
ol.olev ss 150 | 2 KORRUS | 2.15 IfcWall (sein) (_RKAS BIM + ARCHICAD Classification); 51 Vaheseinad (EHITUSKULUDE LIIGITAMINE EVS 885:2005) | Kivi -Ol.Olev Konstruktsioon 150 mm | ol.olev ss 150 | Kivi -Ol.Olev Konstruktsioon | Non-Load-Bearing Element | Undefined | 2,15 | 4 406; Undefined | 3 000; Kõrgus: 3 250; 3D pikkus: 4 406 | 3 000 | Existing | no
ol.olev ss 150 | 2 KORRUS | 2.15 IfcWall (sein) (_RKAS BIM + ARCHICAD Classification); 51 Vaheseinad (EHITUSKULUDE LIIGITAMINE EVS 885:2005) | Kivi -Ol.Olev Konstruktsioon 150 mm | ol.olev ss 150 | Kivi -Ol.Olev Konstruktsioon | Non-Load-Bearing Element | Undefined | 1,83 | 4 402; Undefined | 3 000; Kõrgus: 3 250; 3D pikkus: 4 402 | 3 000 | Existing | no
ol.olev ss 300 | 2 KORRUS | 1.18 IfcWall (sein) (_RKAS BIM + ARCHICAD Classification); 32 Kandvad ja välisseinad (EHITUSKULUDE LIIGITAMINE EVS 885:2005) | Kivi -Ol.Olev Konstruktsioon 300 mm | ol.olev ss 300 | Kivi -Ol.Olev Konstruktsioon | Load-Bearing Element |  | 3,56 |  | 3 000; Kõrgus: 3 250; 3D pikkus: 4 760 | 3 000 | Existing | yes | Arhitektuur - 07 Helipidavus: Undefined; 08 Soojusläbivus (U-arv): -; 04 Tulepüsivus: Undefined
ol.olev ss 200 | 2 KORRUS | 2.15 IfcWall (sein) (_RKAS BIM + ARCHICAD Classification); 51 Vaheseinad (EHITUSKULUDE LIIGITAMINE EVS 885:2005) | Kivi -Ol.Olev Konstruktsioon 200 mm | ol.olev ss 200 | Kivi -Ol.Olev Konstruktsioon | Non-Load-Bearing Element | Undefined | 1,00 | 2 032; Undefined | 3 000; Kõrgus: 3 250; 3D pikkus: 2 032 | 3 000 | Existing | no
ol.olev ss 200 | 2 KORRUS | 2.15 IfcWall (sein) (_RKAS BIM + ARCHICAD Classification); 51 Vaheseinad (EHITUSKULUDE LIIGITAMINE EVS 885:2005) | Kivi -Ol.Olev Konstruktsioon 200 mm | ol.olev ss 200 | Kivi -Ol.Olev Konstruktsioon | Non-Load-Bearing Element | Undefined | 1,85 | 2 904; Undefined | 3 000; Kõrgus: 3 250; 3D pikkus: 2 904 | 3 000 | Existing | no
ol.olev ss 300 | 2 KORRUS | 1.18 IfcWall (sein) (_RKAS BIM + ARCHICAD Classification); 32 Kandvad ja välisseinad (EHITUSKULUDE LIIGITAMINE EVS 885:2005) | Kivi -Ol.Olev Konstruktsioon 300 mm | ol.olev ss 300 | Kivi -Ol.Olev Konstruktsioon | Load-Bearing Element |  | 2,33 |  | 3 000; Kõrgus: 3 250; 3D pikkus: 2 391 | 3 000 | Existing | yes | Arhitektuur - 07 Helipidavus: Undefined; 08 Soojusläbivus (U-arv): -; 04 Tulepüsivus: Undefined
ol.olev ss 420 | 2 KORRUS | 1.18 IfcWall (sein) (_RKAS BIM + ARCHICAD Classification); 32 Kandvad ja välisseinad (EHITUSKULUDE LIIGITAMINE EVS 885:2005) | Kivi -Ol.Olev Konstruktsioon 420 mm | ol.olev ss 420 | Kivi -Ol.Olev Konstruktsioon | Load-Bearing Element |  | 1,41 |  | 3 000; Kõrgus: 3 250; 3D pikkus: 2 605 | 3 000 | Existing | yes | Arhitektuur - 07 Helipidavus: -; 08 Soojusläbivus (U-arv): -; 04 Tulepüsivus: -
ol.olev ss 100 | 2 KORRUS | 1.18 IfcWall (sein) (_RKAS BIM + ARCHICAD Classification); 51 Vaheseinad (EHITUSKULUDE LIIGITAMINE EVS 885:2005) | Kivi -Ol.Olev Konstruktsioon 100 mm | ol.olev ss 100 | Kivi -Ol.Olev Konstruktsioon | Non-Load-Bearing Element |  | 0,76 |  | 3 000; Kõrgus: 3 250; 3D pikkus: 2 852 | 3 000 | Existing | no | Arhitektuur - 07 Helipidavus: -; 08 Soojusläbivus (U-arv): -; 04 Tulepüsivus: -
ol.olev ss 150 | 2 KORRUS | 2.15 IfcWall (sein) (_RKAS BIM + ARCHICAD Classification); 51 Vaheseinad (EHITUSKULUDE LIIGITAMINE EVS 885:2005) | Kivi -Ol.Olev Konstruktsioon 150 mm | ol.olev ss 150 | Kivi -Ol.Olev Konstruktsioon | Non-Load-Bearing Element | Undefined | 1,34 | 3 258; Undefined | 3 000; Kõrgus: 3 250; 3D pikkus: 3 258 | 3 000 | Existing | no
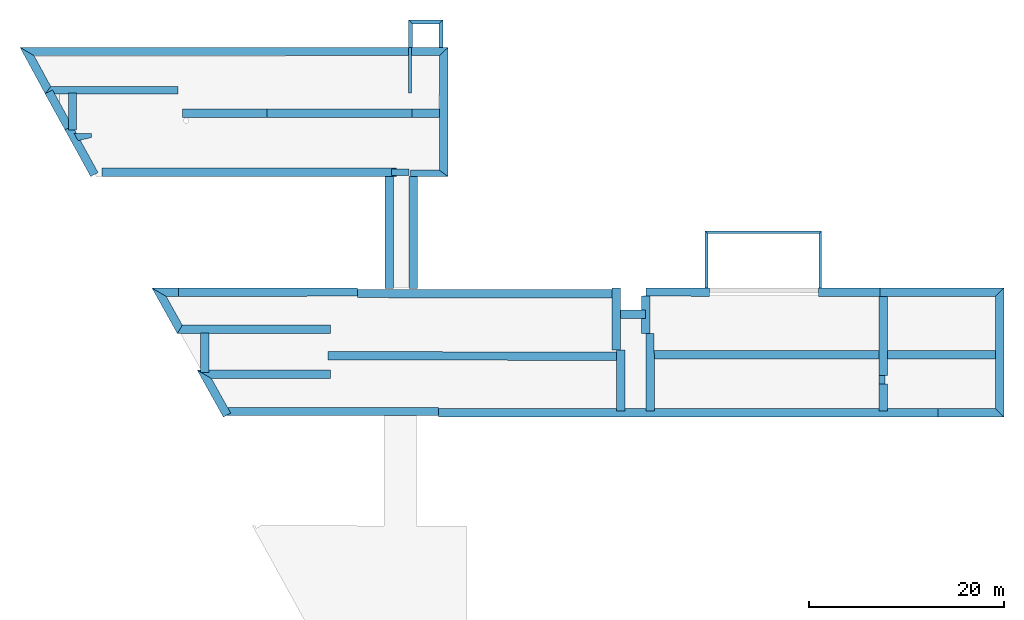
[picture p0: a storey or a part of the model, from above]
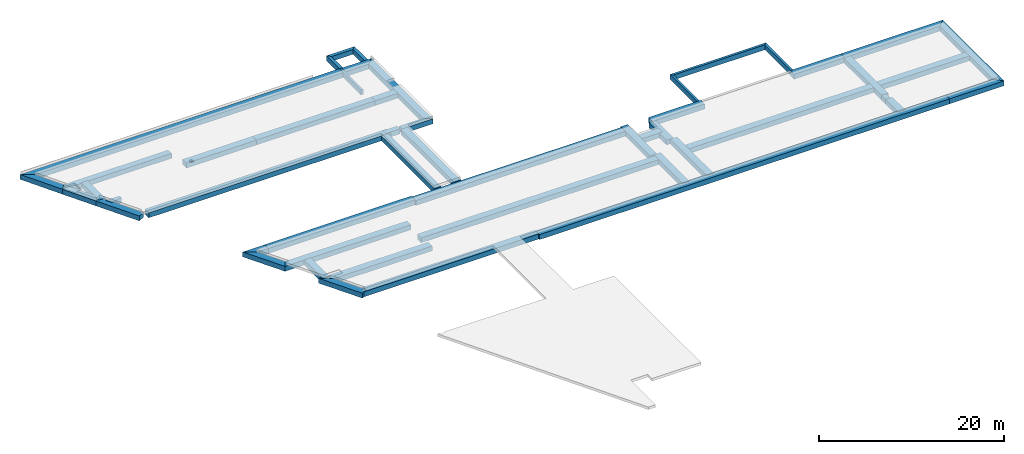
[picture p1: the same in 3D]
Properties of the parts of a building model (IFC2X3), part 13 of 14

# IfcWallStandardCase: SW - 022 (114)
Name | In | Classification | Material | Arhitektuur, 01 Nimetus = Ehituskonstruktsioonid, 01 Nimetus | Arhitektuur, 02 Materjal = Ehituskonstruktsioonid, 02 Materjal | 06 Kandevelementide eristatus | 04 Materjali peamine tugevusnäitaja = 05 Keskkonnaklass = 07 Monteeritava elemendi mass = 09 Monteeritava elemendi positisioon/mark = 10 Elemendi valmistamise tehnoloogia | 06 Maht (kubatuur) | 08 Monteeritava elemendi pikkus | 11 Ülemine kõrgusmärk | 12 Alumine kõrgusmärk | Renovation Status | LoadBearing
ol.olev ss 100 | 2 KORRUS | 1.18 IfcWall (sein) (_RKAS BIM + ARCHICAD Classification); 51 Vaheseinad (EHITUSKULUDE LIIGITAMINE EVS 885:2005) | Kivi -Ol.Olev Konstruktsioon 100 mm | ol.olev ss 100 | Kivi -Ol.Olev Konstruktsioon | Non-Load-Bearing Element |  | 0,72 |  | 3 000; Kõrgus: 3 250; 3D pikkus: 2 748 | 3 000 | Existing | no | Arhitektuur - 07 Helipidavus: -; 08 Soojusläbivus (U-arv): -; 04 Tulepüsivus: -
ol.olev ss 100 | 2 KORRUS | 1.18 IfcWall (sein) (_RKAS BIM + ARCHICAD Classification); 51 Vaheseinad (EHITUSKULUDE LIIGITAMINE EVS 885:2005) | Kivi -Ol.Olev Konstruktsioon 100 mm | ol.olev ss 100 | Kivi -Ol.Olev Konstruktsioon | Non-Load-Bearing Element |  | 0,20 |  | 3 000; Kõrgus: 3 250; 3D pikkus: 609 | 3 000 | Existing | no | Arhitektuur - 07 Helipidavus: -; 08 Soojusläbivus (U-arv): -; 04 Tulepüsivus: -
sahti sein | 2 KORRUS | 2.15 IfcWall (sein) (_RKAS BIM + ARCHICAD Classification); 51 Vaheseinad (EHITUSKULUDE LIIGITAMINE EVS 885:2005) | Kivi - Uus Konstruktsioon 150 mm | sahti sein | 2xkipsplaat (Gyproc GKF15) -66mm Karkasspostid XR66 (s-600mm)+mineraalvill 70mm -plekiribad | Non-Load-Bearing Element | Undefined | 0,82 | 2 084; Undefined | 3 000; Kõrgus: 3 295; 3D pikkus: 2 084 | 3 000 | New | no
ol.olev ss 100 | 2 KORRUS | 1.18 IfcWall (sein) (_RKAS BIM + ARCHICAD Classification); 51 Vaheseinad (EHITUSKULUDE LIIGITAMINE EVS 885:2005) | Kivi -Ol.Olev Konstruktsioon 100 mm | ol.olev ss 100 | Kivi -Ol.Olev Konstruktsioon | Non-Load-Bearing Element |  | 0,01 |  | 3 000; Kõrgus: 3 250; 3D pikkus: 41 | 3 000 | Existing | no | Arhitektuur - 07 Helipidavus: -; 08 Soojusläbivus (U-arv): -; 04 Tulepüsivus: -
ol.olev ss 100 | 2 KORRUS | 1.18 IfcWall (sein) (_RKAS BIM + ARCHICAD Classification); 51 Vaheseinad (EHITUSKULUDE LIIGITAMINE EVS 885:2005) | Kivi -Ol.Olev Konstruktsioon 100 mm | ol.olev ss 100 | Kivi -Ol.Olev Konstruktsioon | Non-Load-Bearing Element |  | 0,27 |  | 3 000; Kõrgus: 3 250; 3D pikkus: 842 | 3 000 | Existing | no | Arhitektuur - 07 Helipidavus: -; 08 Soojusläbivus (U-arv): -; 04 Tulepüsivus: -
ol.olev ss 100 | 2 KORRUS | 1.18 IfcWall (sein) (_RKAS BIM + ARCHICAD Classification); 51 Vaheseinad (EHITUSKULUDE LIIGITAMINE EVS 885:2005) | Kivi -Ol.Olev Konstruktsioon 100 mm | ol.olev ss 100 | Kivi -Ol.Olev Konstruktsioon | Non-Load-Bearing Element |  | 0,36 |  | 3 000; Kõrgus: 3 250; 3D pikkus: 1 119 | 3 000 | Existing | no | Arhitektuur - 07 Helipidavus: -; 08 Soojusläbivus (U-arv): -; 04 Tulepüsivus: -
ol.olev ss 100 | 2 KORRUS | 1.18 IfcWall (sein) (_RKAS BIM + ARCHICAD Classification); 51 Vaheseinad (EHITUSKULUDE LIIGITAMINE EVS 885:2005) | Kivi -Ol.Olev Konstruktsioon 100 mm | ol.olev ss 100 | Kivi -Ol.Olev Konstruktsioon | Non-Load-Bearing Element |  | 0,83 |  | 3 000; Kõrgus: 3 250; 3D pikkus: 2 560 | 3 000 | Existing | no | Arhitektuur - 07 Helipidavus: -; 08 Soojusläbivus (U-arv): -; 04 Tulepüsivus: -
ol.olev ss 100 | 2 KORRUS | 1.18 IfcWall (sein) (_RKAS BIM + ARCHICAD Classification); 51 Vaheseinad (EHITUSKULUDE LIIGITAMINE EVS 885:2005) | Kivi -Ol.Olev Konstruktsioon 100 mm | ol.olev ss 100 | Kivi -Ol.Olev Konstruktsioon | Non-Load-Bearing Element |  | 0,17 |  | 3 000; Kõrgus: 3 250; 3D pikkus: 967 | 3 000 | Existing | no | Arhitektuur - 07 Helipidavus: -; 08 Soojusläbivus (U-arv): -; 04 Tulepüsivus: -
3 x ol.olev ss 100 | 2 KORRUS | 1.18 IfcWall (sein) (_RKAS BIM + ARCHICAD Classification); 51 Vaheseinad (EHITUSKULUDE LIIGITAMINE EVS 885:2005) | Kivi -Ol.Olev Konstruktsioon 100 mm | ol.olev ss 100 | Kivi -Ol.Olev Konstruktsioon | Non-Load-Bearing Element |  | 0,44 |  | 3 000; Kõrgus: 3 250; 3D pikkus: 1 350 | 3 000 | Existing | no | Arhitektuur - 07 Helipidavus: -; 08 Soojusläbivus (U-arv): -; 04 Tulepüsivus: -
ol.olev ss 100 | 2 KORRUS | 1.18 IfcWall (sein) (_RKAS BIM + ARCHICAD Classification); 51 Vaheseinad (EHITUSKULUDE LIIGITAMINE EVS 885:2005) | Kivi -Ol.Olev Konstruktsioon 100 mm | ol.olev ss 100 | Kivi -Ol.Olev Konstruktsioon | Non-Load-Bearing Element |  | 0,12 |  | 3 000; Kõrgus: 3 250; 3D pikkus: 817 | 3 000 | Existing | no | Arhitektuur - 07 Helipidavus: -; 08 Soojusläbivus (U-arv): -; 04 Tulepüsivus: -
ol.olev ss 100 | 2 KORRUS | 1.18 IfcWall (sein) (_RKAS BIM + ARCHICAD Classification); 51 Vaheseinad (EHITUSKULUDE LIIGITAMINE EVS 885:2005) | Kivi -Ol.Olev Konstruktsioon 100 mm | ol.olev ss 100 | Kivi -Ol.Olev Konstruktsioon | Non-Load-Bearing Element |  | 0,17 |  | 3 000; Kõrgus: 3 250; 3D pikkus: 972 | 3 000 | Existing | no | Arhitektuur - 07 Helipidavus: -; 08 Soojusläbivus (U-arv): -; 04 Tulepüsivus: -
ol.olev ss 120 | 2 KORRUS | 2.15 IfcWall (sein) (_RKAS BIM + ARCHICAD Classification); 51 Vaheseinad (EHITUSKULUDE LIIGITAMINE EVS 885:2005) | Kivi -Ol.Olev Konstruktsioon 120 mm | ol.olev ss 120 | Kivi -Ol.Olev Konstruktsioon | Non-Load-Bearing Element | Undefined | 1,63 | 5 370; Undefined | 3 000; Kõrgus: 3 250; 3D pikkus: 5 370 | 3 000 | Existing | no
ol.olev ss 420 | 2 KORRUS | 2.15 IfcWall (sein) (_RKAS BIM + ARCHICAD Classification); 51 Vaheseinad (EHITUSKULUDE LIIGITAMINE EVS 885:2005) | Kivi -Ol.Olev Konstruktsioon 420 mm | ol.olev ss 420 | Kivi -Ol.Olev Konstruktsioon | Load-Bearing Element | Undefined | 2,12 | 2 181; Undefined | 3 000; Kõrgus: 4 000; 3D pikkus: 2 181 | 3 000 | Existing | yes | Arhitektuur - 07 Helipidavus: -; 08 Soojusläbivus (U-arv): -; 04 Tulepüsivus: -
ol.olev ss 420 | 2 KORRUS | 32 Kandvad ja välisseinad (EHITUSKULUDE LIIGITAMINE EVS 885:2005); 2.15 IfcWall (sein) (_RKAS BIM + ARCHICAD Classification) | Kivi -Ol.Olev Konstruktsioon 420 mm | ol.olev ss 420 | Kivi -Ol.Olev Konstruktsioon | Load-Bearing Element | Undefined | 3,06 | 2 240; Undefined | 3 000; Kõrgus: 3 250; 3D pikkus: 2 240 | 3 000 | Existing | yes | Arhitektuur - 07 Helipidavus: -; 08 Soojusläbivus (U-arv): -; 04 Tulepüsivus: -
ol.olev ss 420 | 2 KORRUS | 2.15 IfcWall (sein) (_RKAS BIM + ARCHICAD Classification); 51 Vaheseinad (EHITUSKULUDE LIIGITAMINE EVS 885:2005) | Kivi -Ol.Olev Konstruktsioon 420 mm | ol.olev ss 420 | Kivi -Ol.Olev Konstruktsioon | Load-Bearing Element | Undefined | 2,22 | 2 379; Undefined | 3 000; Kõrgus: 4 000; 3D pikkus: 2 379 | 3 000 | Existing | yes | Arhitektuur - 07 Helipidavus: -; 08 Soojusläbivus (U-arv): -; 04 Tulepüsivus: -
ol.olev ss 150 | 2 KORRUS | 2.15 IfcWall (sein) (_RKAS BIM + ARCHICAD Classification); 51 Vaheseinad (EHITUSKULUDE LIIGITAMINE EVS 885:2005) | Kivi -Ol.Olev Konstruktsioon 150 mm | ol.olev ss 150 | Kivi -Ol.Olev Konstruktsioon | Non-Load-Bearing Element | Undefined | 0,29 | 1 698; Undefined | 3 000; Kõrgus: 3 250; 3D pikkus: 1 698 | 3 000 | Existing | no
ol.olev ss 420 | 2 KORRUS | 32 Kandvad ja välisseinad (EHITUSKULUDE LIIGITAMINE EVS 885:2005); 2.15 IfcWall (sein) (_RKAS BIM + ARCHICAD Classification) | Kivi -Ol.Olev Konstruktsioon 420 mm | ol.olev ss 420 | Kivi -Ol.Olev Konstruktsioon | Load-Bearing Element | Undefined | 15,74 | 12 301; Undefined | 3 000; Kõrgus: 3 200; 3D pikkus: 12 301 | 3 000 | Existing | yes | Arhitektuur - 07 Helipidavus: -; 08 Soojusläbivus (U-arv): -; 04 Tulepüsivus: -
ol.olev ss 420 | 2 KORRUS | 32 Kandvad ja välisseinad (EHITUSKULUDE LIIGITAMINE EVS 885:2005); 2.15 IfcWall (sein) (_RKAS BIM + ARCHICAD Classification) | Kivi -Ol.Olev Konstruktsioon 420 mm | ol.olev ss 420 | Kivi -Ol.Olev Konstruktsioon | Load-Bearing Element | Undefined | 2,33 | 1 780; Undefined | 3 000; Kõrgus: 3 327; 3D pikkus: 1 780 | 3 000 | Existing | yes | Arhitektuur - 07 Helipidavus: -; 08 Soojusläbivus (U-arv): -; 04 Tulepüsivus: -
ol.olev ss 420 | 2 KORRUS | 2.15 IfcWall (sein) (_RKAS BIM + ARCHICAD Classification); 51 Vaheseinad (EHITUSKULUDE LIIGITAMINE EVS 885:2005) | Kivi -Ol.Olev Konstruktsioon 420 mm | ol.olev ss 420 | Kivi -Ol.Olev Konstruktsioon | Load-Bearing Element | Undefined | 1,82 | 2 400; Undefined | 3 000; Kõrgus: 4 000; 3D pikkus: 2 400 | 3 000 | Existing | yes | Arhitektuur - 07 Helipidavus: -; 08 Soojusläbivus (U-arv): -; 04 Tulepüsivus: -

# IfcWallStandardCase: SW - 023 (9)
Type - ElementType: Element type SW - 023
Arhitektuur - 02 Materjal: Kivi -Ol.Olev Konstruktsioon; 03 Tähistus: SW - 023; 05 Asukoht: Interior
Ehituskonstruktsioonid - 02 Materjal: Kivi -Ol.Olev Konstruktsioon; 03 Tähistus või ristlõige: SW - 023; 04 Materjali peamine tugevusnäitaja: Undefined; 05 Keskkonnaklass: Undefined; 07 Monteeritava elemendi mass: Undefined; 09 Monteeritava elemendi positisioon/mark: Undefined; 10 Elemendi valmistamise tehnoloogia: Undefined
AC_Pset_RenovationAndPhasing - Renovation Status: Existing
Pset_WallCommon - IsExternal: no
Name | In | Classification | Material | Arhitektuur, 01 Nimetus = Ehituskonstruktsioonid, 01 Nimetus | 06 Kandevelementide eristatus | 06 Maht (kubatuur) | 08 Monteeritava elemendi pikkus | 11 Ülemine kõrgusmärk | 12 Alumine kõrgusmärk | LoadBearing
ol.olev ss 150 | 1 KORRUS | 2.15 IfcWall (sein) (_RKAS BIM + ARCHICAD Classification); 51 Vaheseinad (EHITUSKULUDE LIIGITAMINE EVS 885:2005) | Kivi -Ol.Olev Konstruktsioon 150 mm | ol.olev ss 150 | Non-Load-Bearing Element | 1,42 | 3 639; Undefined | 0; Kõrgus: 2 600; 3D pikkus: 3 639 | 0 | no
ol.olev ss 200 | 1 KORRUS | 2.15 IfcWall (sein) (_RKAS BIM + ARCHICAD Classification); 51 Vaheseinad (EHITUSKULUDE LIIGITAMINE EVS 885:2005) | Kivi -Ol.Olev Konstruktsioon 200 mm | ol.olev ss 200 | Non-Load-Bearing Element | 0,71 | 1 374; Undefined | 0; Kõrgus: 2 600; 3D pikkus: 1 374 | 0 | no
ol.olev ss 200 | 1 KORRUS | 2.15 IfcWall (sein) (_RKAS BIM + ARCHICAD Classification); 51 Vaheseinad (EHITUSKULUDE LIIGITAMINE EVS 885:2005) | Kivi -Ol.Olev Konstruktsioon 200 mm | ol.olev ss 200 | Non-Load-Bearing Element | 1,02 | 1 957; Undefined | 0; Kõrgus: 2 600; 3D pikkus: 1 957 | 0 | no
ol.olev ss 200 | 1 KORRUS | 2.15 IfcWall (sein) (_RKAS BIM + ARCHICAD Classification); 51 Vaheseinad (EHITUSKULUDE LIIGITAMINE EVS 885:2005) | Kivi -Ol.Olev Konstruktsioon 200 mm | ol.olev ss 200 | Non-Load-Bearing Element | 2,76 | 6 080; Undefined | 0; Kõrgus: 2 600; 3D pikkus: 6 080 | 0 | no
ol.olev ss 150 | 2 KORRUS | 2.15 IfcWall (sein) (_RKAS BIM + ARCHICAD Classification); 51 Vaheseinad (EHITUSKULUDE LIIGITAMINE EVS 885:2005) | Kivi -Ol.Olev Konstruktsioon 150 mm | ol.olev ss 150 | Non-Load-Bearing Element | 0,13 | 269; Undefined | 3 000; Kõrgus: 3 250; 3D pikkus: 269 | 3 000 | no
ol.olev ss 420 | 2 KORRUS | 32 Kandvad ja välisseinad (EHITUSKULUDE LIIGITAMINE EVS 885:2005); 2.15 IfcWall (sein) (_RKAS BIM + ARCHICAD Classification) | Kivi -Ol.Olev Konstruktsioon 420 mm | ol.olev ss 420 | Load-Bearing Element | 10,47 | 11 060; Undefined | 3 000; Kõrgus: 3 250; 3D pikkus: 11 060 | 3 000 | yes | Arhitektuur - 07 Helipidavus: -; 08 Soojusläbivus (U-arv): -; 04 Tulepüsivus: -
ol.olev ss 200 | 2 KORRUS | 2.15 IfcWall (sein) (_RKAS BIM + ARCHICAD Classification); 51 Vaheseinad (EHITUSKULUDE LIIGITAMINE EVS 885:2005) | Kivi -Ol.Olev Konstruktsioon 200 mm | ol.olev ss 200 | Non-Load-Bearing Element | 1,23 | 1 888; Undefined | 3 000; Kõrgus: 3 250; 3D pikkus: 1 888 | 3 000 | no
ol.olev ss 200 | 2 KORRUS | 2.15 IfcWall (sein) (_RKAS BIM + ARCHICAD Classification); 51 Vaheseinad (EHITUSKULUDE LIIGITAMINE EVS 885:2005) | Kivi -Ol.Olev Konstruktsioon 200 mm | ol.olev ss 200 | Non-Load-Bearing Element | 0,63 | 971; Undefined | 3 000; Kõrgus: 3 250; 3D pikkus: 971 | 3 000 | no
ol.olev ss 420 | 2 KORRUS | 32 Kandvad ja välisseinad (EHITUSKULUDE LIIGITAMINE EVS 885:2005); 2.15 IfcWall (sein) (_RKAS BIM + ARCHICAD Classification) | Kivi -Ol.Olev Konstruktsioon 420 mm | ol.olev ss 420 | Load-Bearing Element | 2,51 | 1 794; Undefined | 3 000; Kõrgus: 3 327; 3D pikkus: 1 794 | 3 000 | yes | Arhitektuur - 07 Helipidavus: -; 08 Soojusläbivus (U-arv): -; 04 Tulepüsivus: -

# IfcWallStandardCase: SW - 024 (4)
Type - ElementType: Element type SW - 024
Arhitektuur - 02 Materjal: Kivi -Ol.Olev Konstruktsioon; 03 Tähistus: SW - 024; 05 Asukoht: Interior
Ehituskonstruktsioonid - 02 Materjal: Kivi -Ol.Olev Konstruktsioon; 03 Tähistus või ristlõige: SW - 024; 04 Materjali peamine tugevusnäitaja: Undefined; 05 Keskkonnaklass: Undefined; 07 Monteeritava elemendi mass: Undefined; 09 Monteeritava elemendi positisioon/mark: Undefined; 10 Elemendi valmistamise tehnoloogia: Undefined
AC_Pset_RenovationAndPhasing - Renovation Status: Existing
Pset_WallCommon - IsExternal: no
Name | In | Classification | Material | Arhitektuur, 01 Nimetus = Ehituskonstruktsioonid, 01 Nimetus | 06 Kandevelementide eristatus | 06 Maht (kubatuur) | 08 Monteeritava elemendi pikkus | 11 Ülemine kõrgusmärk | 12 Alumine kõrgusmärk | LoadBearing
ol.olev ss 150 | 1 KORRUS | 2.15 IfcWall (sein) (_RKAS BIM + ARCHICAD Classification); 51 Vaheseinad (EHITUSKULUDE LIIGITAMINE EVS 885:2005) | Kivi -Ol.Olev Konstruktsioon 150 mm | ol.olev ss 150 | Non-Load-Bearing Element | 1,54 | 3 942; Undefined | 0; Kõrgus: 2 600; 3D pikkus: 3 942 | 0 | no
ol.olev ss 150 | 2 KORRUS | 2.15 IfcWall (sein) (_RKAS BIM + ARCHICAD Classification); 51 Vaheseinad (EHITUSKULUDE LIIGITAMINE EVS 885:2005) | Kivi -Ol.Olev Konstruktsioon 150 mm | ol.olev ss 150 | Non-Load-Bearing Element | 1,35 | 2 775; Undefined | 3 000; Kõrgus: 3 250; 3D pikkus: 2 775 | 3 000 | no
ol.olev ss 330 | 2 KORRUS | 32 Kandvad ja välisseinad (EHITUSKULUDE LIIGITAMINE EVS 885:2005); 2.15 IfcWall (sein) (_RKAS BIM + ARCHICAD Classification) | Kivi -Ol.Olev Konstruktsioon 350 mm | ol.olev ss 330 | Load-Bearing Element | 7,03 | 6 184; Undefined | 3 000; Kõrgus: 3 250; 3D pikkus: 6 184 | 3 000 | yes
ol.olev ss 420 | 2 KORRUS | 32 Kandvad ja välisseinad (EHITUSKULUDE LIIGITAMINE EVS 885:2005); 2.15 IfcWall (sein) (_RKAS BIM + ARCHICAD Classification) | Kivi -Ol.Olev Konstruktsioon 420 mm | ol.olev ss 420 | Load-Bearing Element | 2,32 | 2 657; Undefined | 3 000; Kõrgus: 3 980; 3D pikkus: 2 657 | 3 000 | yes | Arhitektuur - 07 Helipidavus: -; 08 Soojusläbivus (U-arv): -; 04 Tulepüsivus: -

# IfcWallStandardCase: SW - 025 (2)
Type - ElementType: Element type SW - 025
Arhitektuur - 03 Tähistus: SW - 025; 06 Kandevelementide eristatus: Load-Bearing Element; 07 Helipidavus: -; 08 Soojusläbivus (U-arv): -
Ehituskonstruktsioonid - 03 Tähistus või ristlõige: SW - 025
AC_Pset_RenovationAndPhasing - Renovation Status: Existing
Pset_WallCommon - LoadBearing: yes
Name | In | Classification | Material | Arhitektuur, 01 Nimetus = Ehituskonstruktsioonid, 01 Nimetus | Arhitektuur, 02 Materjal = Ehituskonstruktsioonid, 02 Materjal | 04 Tulepüsivus | 05 Asukoht | 06 Maht (kubatuur) | 11 Ülemine kõrgusmärk | 12 Alumine kõrgusmärk | IsExternal
Ol.olve tugimüür 250 | 1 KORRUS | 1.18 IfcWall (sein) (_RKAS BIM + ARCHICAD Classification); 51 Vaheseinad (EHITUSKULUDE LIIGITAMINE EVS 885:2005) | Kivi - Ol.Olev Konstruktsioon 250 mm | Ol.olve tugimüür 250 | Kivi - Ol.Olev Konstruktsioon | nõudeid ei esitata | Exterior | 10,27 | 0; Kõrgus: 2 250; 3D pikkus: 18 250 | 0 | yes
ol.olev ss 420 | 2 KORRUS | 32 Kandvad ja välisseinad (EHITUSKULUDE LIIGITAMINE EVS 885:2005); 2.15 IfcWall (sein) (_RKAS BIM + ARCHICAD Classification) | Kivi -Ol.Olev Konstruktsioon 420 mm | ol.olev ss 420 | Kivi -Ol.Olev Konstruktsioon | - | Interior | 1,22 | 3 000; Kõrgus: 3 250; 3D pikkus: 894 | 3 000 | no | Ehituskonstruktsioonid - 04 Materjali peamine tugevusnäitaja: Undefined; 05 Keskkonnaklass: Undefined; 07 Monteeritava elemendi mass: Undefined; 08 Monteeritava elemendi pikkus: 894; Undefined; 09 Monteeritava elemendi positisioon/mark: Undefined; 10 Elemendi valmistamise tehnoloogia: Undefined

# IfcWallStandardCase: SW - 026 (2)
Type - ElementType: Element type SW - 026
Arhitektuur - 03 Tähistus: SW - 026; 06 Kandevelementide eristatus: Load-Bearing Element; 07 Helipidavus: -; 08 Soojusläbivus (U-arv): -
Ehituskonstruktsioonid - 03 Tähistus või ristlõige: SW - 026
AC_Pset_RenovationAndPhasing - Renovation Status: Existing
Pset_WallCommon - LoadBearing: yes
Name | In | Classification | Material | Arhitektuur, 01 Nimetus = Ehituskonstruktsioonid, 01 Nimetus | Arhitektuur, 02 Materjal = Ehituskonstruktsioonid, 02 Materjal | 04 Tulepüsivus | 05 Asukoht | 06 Maht (kubatuur) | 11 Ülemine kõrgusmärk | 12 Alumine kõrgusmärk | IsExternal
Ol.olve tugimüür 250 | 1 KORRUS | 1.18 IfcWall (sein) (_RKAS BIM + ARCHICAD Classification); 51 Vaheseinad (EHITUSKULUDE LIIGITAMINE EVS 885:2005) | Kivi - Ol.Olev Konstruktsioon 250 mm | Ol.olve tugimüür 250 | Kivi - Ol.Olev Konstruktsioon | nõudeid ei esitata | Exterior | 11,95 | 0; Kõrgus: 2 250; 3D pikkus: 21 250 | 0 | yes
ol.olev ss 420 | 2 KORRUS | 32 Kandvad ja välisseinad (EHITUSKULUDE LIIGITAMINE EVS 885:2005); 2.15 IfcWall (sein) (_RKAS BIM + ARCHICAD Classification) | Kivi -Ol.Olev Konstruktsioon 420 mm | ol.olev ss 420 | Kivi -Ol.Olev Konstruktsioon | - | Interior | 19,09 | 3 000; Kõrgus: 3 250; 3D pikkus: 16 817 | 3 000 | no | Ehituskonstruktsioonid - 04 Materjali peamine tugevusnäitaja: Undefined; 05 Keskkonnaklass: Undefined; 07 Monteeritava elemendi mass: Undefined; 08 Monteeritava elemendi pikkus: 16 817; Undefined; 09 Monteeritava elemendi positisioon/mark: Undefined; 10 Elemendi valmistamise tehnoloogia: Undefined

# IfcWallStandardCase: SW - 027 (3)
In: 1 KORRUS
Type - ElementType: Element type SW - 027
Classification: 1.18 IfcWall (sein) (_RKAS BIM + ARCHICAD Classification); 51 Vaheseinad (EHITUSKULUDE LIIGITAMINE EVS 885:2005); Material: Kivi - Ol.Olev Konstruktsioon 250 mm
Arhitektuur - 01 Nimetus: Ol.olve tugimüür 250; 02 Materjal: Kivi - Ol.Olev Konstruktsioon; 03 Tähistus: SW - 027; 04 Tulepüsivus: nõudeid ei esitata; 05 Asukoht: Exterior; 06 Kandevelementide eristatus: Load-Bearing Element; 07 Helipidavus: -; 08 Soojusläbivus (U-arv): -
Ehituskonstruktsioonid - 01 Nimetus: Ol.olve tugimüür 250; 02 Materjal: Kivi - Ol.Olev Konstruktsioon; 03 Tähistus või ristlõige: SW - 027; 12 Alumine kõrgusmärk: 0
AC_Pset_RenovationAndPhasing - Renovation Status: Existing
Pset_WallCommon - LoadBearing: yes; IsExternal: yes
Name | 06 Maht (kubatuur) | 11 Ülemine kõrgusmärk
2 x Ol.olve tugimüür 250 | 0,44 | 0; Kõrgus: 2 250; 3D pikkus: 781
Ol.olve tugimüür 250 | 10,05 | 0; Kõrgus: 2 250; 3D pikkus: 17 869

# IfcWallStandardCase: SW - 028 (14)
In: 1 KORRUS
Type - ElementType: Element type SW - 028
Classification: 1.18 IfcWall (sein) (_RKAS BIM + ARCHICAD Classification); 51 Vaheseinad (EHITUSKULUDE LIIGITAMINE EVS 885:2005); Material: Kivi - Ol.Olev Konstruktsioon 250 mm
Arhitektuur - 01 Nimetus: Ol.olve tugimüür 250; 02 Materjal: Kivi - Ol.Olev Konstruktsioon; 03 Tähistus: SW - 028; 04 Tulepüsivus: nõudeid ei esitata; 05 Asukoht: Exterior; 06 Kandevelementide eristatus: Load-Bearing Element; 07 Helipidavus: -; 08 Soojusläbivus (U-arv): -
Ehituskonstruktsioonid - 01 Nimetus: Ol.olve tugimüür 250; 02 Materjal: Kivi - Ol.Olev Konstruktsioon; 03 Tähistus või ristlõige: SW - 028; 12 Alumine kõrgusmärk: 0
AC_Pset_RenovationAndPhasing - Renovation Status: Existing
Pset_WallCommon - LoadBearing: yes; IsExternal: yes
Name | 06 Maht (kubatuur) | 11 Ülemine kõrgusmärk
6 x Ol.olve tugimüür 250 | 0,43 | 0; Kõrgus: 2 250; 3D pikkus: 763
2 x Ol.olve tugimüür 250 | 0,43 | 0; Kõrgus: 2 250; 3D pikkus: 762
Ol.olve tugimüür 250 | 5,05 | 0; Kõrgus: 2 250; 3D pikkus: 8 982
Ol.olve tugimüür 250 | 0,44 | 0; Kõrgus: 2 250; 3D pikkus: 776
Ol.olve tugimüür 250 | 0,43 | 0; Kõrgus: 2 250; 3D pikkus: 764
Ol.olve tugimüür 250 | 0,43 | 0; Kõrgus: 2 250; 3D pikkus: 760
Ol.olve tugimüür 250 | 0,43 | 0; Kõrgus: 2 250; 3D pikkus: 770
Ol.olve tugimüür 250 | 0,43 | 0; Kõrgus: 2 250; 3D pikkus: 759

# IfcWallStandardCase: SW - 029 (10)
In: 1 KORRUS
Type - ElementType: Element type SW - 029
Classification: 1.18 IfcWall (sein) (_RKAS BIM + ARCHICAD Classification); 51 Vaheseinad (EHITUSKULUDE LIIGITAMINE EVS 885:2005); Material: Kivi - Ol.Olev Konstruktsioon 250 mm
Arhitektuur - 01 Nimetus: Ol.olve tugimüür 250; 02 Materjal: Kivi - Ol.Olev Konstruktsioon; 03 Tähistus: SW - 029; 04 Tulepüsivus: nõudeid ei esitata; 05 Asukoht: Exterior; 06 Kandevelementide eristatus: Load-Bearing Element; 07 Helipidavus: -; 08 Soojusläbivus (U-arv): -
Ehituskonstruktsioonid - 01 Nimetus: Ol.olve tugimüür 250; 02 Materjal: Kivi - Ol.Olev Konstruktsioon; 03 Tähistus või ristlõige: SW - 029; 12 Alumine kõrgusmärk: 0
AC_Pset_RenovationAndPhasing - Renovation Status: Existing
Pset_WallCommon - LoadBearing: yes; IsExternal: yes
Name | 06 Maht (kubatuur) | 11 Ülemine kõrgusmärk
Ol.olve tugimüür 250 | 0,66 | 0; Kõrgus: 2 250; 3D pikkus: 1 173
Ol.olve tugimüür 250 | 0,43 | 0; Kõrgus: 2 250; 3D pikkus: 761
Ol.olve tugimüür 250 | 0,46 | 0; Kõrgus: 2 250; 3D pikkus: 820
3 x Ol.olve tugimüür 250 | 0,43 | 0; Kõrgus: 2 250; 3D pikkus: 771
2 x Ol.olve tugimüür 250 | 0,43 | 0; Kõrgus: 2 250; 3D pikkus: 772
2 x Ol.olve tugimüür 250 | 0,43 | 0; Kõrgus: 2 250; 3D pikkus: 770

# IfcWallStandardCase: SW - 030, Ol.olve tugimüür 250
In: 1 KORRUS
Type - ElementType: Element type SW - 030
Classification: 1.18 IfcWall (sein) (_RKAS BIM + ARCHICAD Classification); 51 Vaheseinad (EHITUSKULUDE LIIGITAMINE EVS 885:2005); Material: Kivi - Ol.Olev Konstruktsioon 250 mm
Arhitektuur - 01 Nimetus: Ol.olve tugimüür 250; 02 Materjal: Kivi - Ol.Olev Konstruktsioon; 03 Tähistus: SW - 030; 04 Tulepüsivus: nõudeid ei esitata; 05 Asukoht: Exterior; 06 Kandevelementide eristatus: Load-Bearing Element; 07 Helipidavus: -; 08 Soojusläbivus (U-arv): -
Ehituskonstruktsioonid - 01 Nimetus: Ol.olve tugimüür 250; 02 Materjal: Kivi - Ol.Olev Konstruktsioon; 03 Tähistus või ristlõige: SW - 030; 06 Maht (kubatuur): 3,28; 11 Ülemine kõrgusmärk: 0; Kõrgus: 2 250; 3D pikkus: 5 831; 12 Alumine kõrgusmärk: 0
AC_Pset_RenovationAndPhasing - Renovation Status: Existing
Pset_WallCommon - LoadBearing: yes; IsExternal: yes

# IfcWallStandardCase: SW - 031 (2)
In: 1 KORRUS
Type - ElementType: Element type SW - 031
Classification: 1.18 IfcWall (sein) (_RKAS BIM + ARCHICAD Classification); 51 Vaheseinad (EHITUSKULUDE LIIGITAMINE EVS 885:2005); Material: Kivi - Ol.Olev Konstruktsioon 250 mm
Arhitektuur - 01 Nimetus: Ol.olve tugimüür 250; 02 Materjal: Kivi - Ol.Olev Konstruktsioon; 03 Tähistus: SW - 031; 04 Tulepüsivus: nõudeid ei esitata; 05 Asukoht: Exterior; 06 Kandevelementide eristatus: Load-Bearing Element; 07 Helipidavus: -; 08 Soojusläbivus (U-arv): -
Ehituskonstruktsioonid - 01 Nimetus: Ol.olve tugimüür 250; 02 Materjal: Kivi - Ol.Olev Konstruktsioon; 03 Tähistus või ristlõige: SW - 031; 12 Alumine kõrgusmärk: 0
AC_Pset_RenovationAndPhasing - Renovation Status: Existing
Pset_WallCommon - LoadBearing: yes; IsExternal: yes
Name | 06 Maht (kubatuur) | 11 Ülemine kõrgusmärk
Ol.olve tugimüür 250 | 0,51 | 0; Kõrgus: 2 250; 3D pikkus: 914
Ol.olve tugimüür 250 | 10,29 | 0; Kõrgus: 2 250; 3D pikkus: 18 288

# IfcWallStandardCase: SW - 032 (5)
Type - ElementType: Element type SW - 032
Arhitektuur - 03 Tähistus: SW - 032; 06 Kandevelementide eristatus: Load-Bearing Element; 07 Helipidavus: -; 08 Soojusläbivus (U-arv): -
Ehituskonstruktsioonid - 03 Tähistus või ristlõige: SW - 032
AC_Pset_RenovationAndPhasing - Renovation Status: Existing
Pset_WallCommon - LoadBearing: yes
Name | In | Classification | Material | Arhitektuur, 01 Nimetus = Ehituskonstruktsioonid, 01 Nimetus | Arhitektuur, 02 Materjal = Ehituskonstruktsioonid, 02 Materjal | 04 Tulepüsivus | 05 Asukoht | 06 Maht (kubatuur) | 11 Ülemine kõrgusmärk | 12 Alumine kõrgusmärk | IsExternal
Ol.olve tugimüür 250 | 1 KORRUS | 1.18 IfcWall (sein) (_RKAS BIM + ARCHICAD Classification); 51 Vaheseinad (EHITUSKULUDE LIIGITAMINE EVS 885:2005) | Kivi - Ol.Olev Konstruktsioon 250 mm | Ol.olve tugimüür 250 | Kivi - Ol.Olev Konstruktsioon | nõudeid ei esitata | Exterior | 0,51 | 0; Kõrgus: 2 250; 3D pikkus: 914 | 0 | yes
Ol.olve tugimüür 250 | 1 KORRUS | 1.18 IfcWall (sein) (_RKAS BIM + ARCHICAD Classification); 51 Vaheseinad (EHITUSKULUDE LIIGITAMINE EVS 885:2005) | Kivi - Ol.Olev Konstruktsioon 250 mm | Ol.olve tugimüür 250 | Kivi - Ol.Olev Konstruktsioon | nõudeid ei esitata | Exterior | 0,51 | 0; Kõrgus: 2 250; 3D pikkus: 915 | 0 | yes
ol.olev ss 420 | 2 KORRUS | 32 Kandvad ja välisseinad (EHITUSKULUDE LIIGITAMINE EVS 885:2005); 2.15 IfcWall (sein) (_RKAS BIM + ARCHICAD Classification) | Kivi -Ol.Olev Konstruktsioon 420 mm | ol.olev ss 420 | Kivi -Ol.Olev Konstruktsioon | - | Interior | 12,50 | 3 000; Kõrgus: 3 250; 3D pikkus: 10 720 | 3 000 | no | Ehituskonstruktsioonid - 04 Materjali peamine tugevusnäitaja: Undefined; 05 Keskkonnaklass: Undefined; 07 Monteeritava elemendi mass: Undefined; 08 Monteeritava elemendi pikkus: 10 720; Undefined; 09 Monteeritava elemendi positisioon/mark: Undefined; 10 Elemendi valmistamise tehnoloogia: Undefined
2 x ol.olev ss 420 | 2 KORRUS | 1.18 IfcWall (sein) (_RKAS BIM + ARCHICAD Classification); 51 Vaheseinad (EHITUSKULUDE LIIGITAMINE EVS 885:2005) | Kivi -Ol.Olev Konstruktsioon 420 mm | ol.olev ss 420 | Kivi -Ol.Olev Konstruktsioon | - | Interior | 0,69 | 1 815; Kõrgus: 1 305; 3D pikkus: 1 260 | 1 815 | no

# IfcWallStandardCase: SW - 033 (6)
In: 1 KORRUS
Type - ElementType: Element type SW - 033
Classification: 1.18 IfcWall (sein) (_RKAS BIM + ARCHICAD Classification); 51 Vaheseinad (EHITUSKULUDE LIIGITAMINE EVS 885:2005); Material: Kivi - Ol.Olev Konstruktsioon 250 mm
Arhitektuur - 01 Nimetus: Ol.olve tugimüür 250; 02 Materjal: Kivi - Ol.Olev Konstruktsioon; 03 Tähistus: SW - 033; 04 Tulepüsivus: nõudeid ei esitata; 05 Asukoht: Exterior; 06 Kandevelementide eristatus: Load-Bearing Element; 07 Helipidavus: -; 08 Soojusläbivus (U-arv): -
Ehituskonstruktsioonid - 01 Nimetus: Ol.olve tugimüür 250; 02 Materjal: Kivi - Ol.Olev Konstruktsioon; 03 Tähistus või ristlõige: SW - 033; 12 Alumine kõrgusmärk: 0
AC_Pset_RenovationAndPhasing - Renovation Status: Existing
Pset_WallCommon - LoadBearing: yes; IsExternal: yes
Name | 06 Maht (kubatuur) | 11 Ülemine kõrgusmärk
4 x Ol.olve tugimüür 250 | 0,51 | 0; Kõrgus: 2 250; 3D pikkus: 914
Ol.olve tugimüür 250 | 0,51 | 0; Kõrgus: 2 250; 3D pikkus: 913
Ol.olve tugimüür 250 | 0,46 | 0; Kõrgus: 2 250; 3D pikkus: 820

# IfcWallStandardCase: SW - 036 (58)
Type - ElementType: Element type SW - 036
Arhitektuur - 02 Materjal: Kivi -Ol.Olev Konstruktsioon; 03 Tähistus: SW - 036; 05 Asukoht: Interior
Ehituskonstruktsioonid - 02 Materjal: Kivi -Ol.Olev Konstruktsioon; 03 Tähistus või ristlõige: SW - 036; 04 Materjali peamine tugevusnäitaja: Undefined; 05 Keskkonnaklass: Undefined; 07 Monteeritava elemendi mass: Undefined; 09 Monteeritava elemendi positisioon/mark: Undefined; 10 Elemendi valmistamise tehnoloogia: Undefined
AC_Pset_RenovationAndPhasing - Renovation Status: Existing
Pset_WallCommon - IsExternal: no
Name | In | Classification | Material | Arhitektuur, 01 Nimetus = Ehituskonstruktsioonid, 01 Nimetus | 06 Kandevelementide eristatus | 06 Maht (kubatuur) | 08 Monteeritava elemendi pikkus | 11 Ülemine kõrgusmärk | 12 Alumine kõrgusmärk | LoadBearing
ol.olev ss 150 | 1 KORRUS | 2.15 IfcWall (sein) (_RKAS BIM + ARCHICAD Classification); 51 Vaheseinad (EHITUSKULUDE LIIGITAMINE EVS 885:2005) | Kivi -Ol.Olev Konstruktsioon 150 mm | ol.olev ss 150 | Non-Load-Bearing Element | 2,14 | 5 500; Undefined | 0; Kõrgus: 2 600; 3D pikkus: 5 500 | 0 | no
ol.olev ss 420 | 1 KORRUS | 32 Kandvad ja välisseinad (EHITUSKULUDE LIIGITAMINE EVS 885:2005); 2.15 IfcWall (sein) (_RKAS BIM + ARCHICAD Classification) | Kivi -Ol.Olev Konstruktsioon 420 mm | ol.olev ss 420 | Load-Bearing Element | 11,21 | 11 647; Undefined | 0; Kõrgus: 2 600; 3D pikkus: 11 647 | 0 | yes | Arhitektuur - 07 Helipidavus: -; 08 Soojusläbivus (U-arv): -; 04 Tulepüsivus: -
ol.olev ss 150 | 1 KORRUS | 2.15 IfcWall (sein) (_RKAS BIM + ARCHICAD Classification); 51 Vaheseinad (EHITUSKULUDE LIIGITAMINE EVS 885:2005) | Kivi -Ol.Olev Konstruktsioon 150 mm | ol.olev ss 150 | Non-Load-Bearing Element | 1,18 | 3 020; Undefined | 0; Kõrgus: 2 600; 3D pikkus: 3 020 | 0 | no
ol.olev ss 150 | 1 KORRUS | 2.15 IfcWall (sein) (_RKAS BIM + ARCHICAD Classification); 51 Vaheseinad (EHITUSKULUDE LIIGITAMINE EVS 885:2005) | Kivi -Ol.Olev Konstruktsioon 150 mm | ol.olev ss 150 | Non-Load-Bearing Element | 2,34 | 5 997; Undefined | 0; Kõrgus: 2 600; 3D pikkus: 5 997 | 0 | no
ol.olev ss 150 | 1 KORRUS | 2.15 IfcWall (sein) (_RKAS BIM + ARCHICAD Classification); 51 Vaheseinad (EHITUSKULUDE LIIGITAMINE EVS 885:2005) | Kivi -Ol.Olev Konstruktsioon 150 mm | ol.olev ss 150 | Non-Load-Bearing Element | 1,91 | 5 627; Undefined | 0; Kõrgus: 2 600; 3D pikkus: 5 627 | 0 | no
ol.olev ss 150 | 1 KORRUS | 2.15 IfcWall (sein) (_RKAS BIM + ARCHICAD Classification); 51 Vaheseinad (EHITUSKULUDE LIIGITAMINE EVS 885:2005) | Kivi -Ol.Olev Konstruktsioon 150 mm | ol.olev ss 150 | Non-Load-Bearing Element | 2,14 | 5 477; Undefined | 0; Kõrgus: 2 600; 3D pikkus: 5 477 | 0 | no
ol.olev ss 150 | 1 KORRUS | 2.15 IfcWall (sein) (_RKAS BIM + ARCHICAD Classification); 51 Vaheseinad (EHITUSKULUDE LIIGITAMINE EVS 885:2005) | Kivi -Ol.Olev Konstruktsioon 150 mm | ol.olev ss 150 | Non-Load-Bearing Element | 2,14 | 5 628; Undefined | 0; Kõrgus: 2 600; 3D pikkus: 5 628 | 0 | no
ol.olev ss 250 | 1 KORRUS | 2.15 IfcWall (sein) (_RKAS BIM + ARCHICAD Classification); 51 Vaheseinad (EHITUSKULUDE LIIGITAMINE EVS 885:2005) | Kivi -Ol.Olev Konstruktsioon 250 mm | ol.olev ss 250 | Non-Load-Bearing Element | 3,06 | 5 478; Undefined | 0; Kõrgus: 2 600; 3D pikkus: 5 478 | 0 | no
ol.olev ss 250 | 1 KORRUS | 2.15 IfcWall (sein) (_RKAS BIM + ARCHICAD Classification); 51 Vaheseinad (EHITUSKULUDE LIIGITAMINE EVS 885:2005) | Kivi -Ol.Olev Konstruktsioon 250 mm | ol.olev ss 250 | Non-Load-Bearing Element | 3,11 | 5 479; Undefined | 0; Kõrgus: 2 600; 3D pikkus: 5 479 | 0 | no
ol.olev ss 200 | 1 KORRUS | 2.15 IfcWall (sein) (_RKAS BIM + ARCHICAD Classification); 51 Vaheseinad (EHITUSKULUDE LIIGITAMINE EVS 885:2005) | Kivi -Ol.Olev Konstruktsioon 200 mm | ol.olev ss 200 | Non-Load-Bearing Element | 1,90 | 3 800; Undefined | 0; Kõrgus: 2 600; 3D pikkus: 3 800 | 0 | no
ol.olev ss 150 | 1 KORRUS | 2.15 IfcWall (sein) (_RKAS BIM + ARCHICAD Classification); 51 Vaheseinad (EHITUSKULUDE LIIGITAMINE EVS 885:2005) | Kivi -Ol.Olev Konstruktsioon 150 mm | ol.olev ss 150 | Non-Load-Bearing Element | 1,34 | 3 449; Undefined | 0; Kõrgus: 2 600; 3D pikkus: 3 449 | 0 | no
ol.olev ss 420 | 1 KORRUS | 32 Kandvad ja välisseinad (EHITUSKULUDE LIIGITAMINE EVS 885:2005); 2.15 IfcWall (sein) (_RKAS BIM + ARCHICAD Classification) | Kivi -Ol.Olev Konstruktsioon 420 mm | ol.olev ss 420 | Load-Bearing Element | 6,01 | 5 500; Undefined | 0; Kõrgus: 2 600; 3D pikkus: 5 500 | 0 | yes | Arhitektuur - 07 Helipidavus: -; 08 Soojusläbivus (U-arv): -; 04 Tulepüsivus: -
2 x ol.olev ss 150 | 1 KORRUS | 2.15 IfcWall (sein) (_RKAS BIM + ARCHICAD Classification); 51 Vaheseinad (EHITUSKULUDE LIIGITAMINE EVS 885:2005) | Kivi -Ol.Olev Konstruktsioon 150 mm | ol.olev ss 150 | Non-Load-Bearing Element | 2,11 | 5 401; Undefined | 0; Kõrgus: 2 600; 3D pikkus: 5 401 | 0 | no
ol.olev ss 420 | 1 KORRUS | 32 Kandvad ja välisseinad (EHITUSKULUDE LIIGITAMINE EVS 885:2005); 2.15 IfcWall (sein) (_RKAS BIM + ARCHICAD Classification) | Kivi -Ol.Olev Konstruktsioon 420 mm | ol.olev ss 420 | Load-Bearing Element | 5,90 | 5 692; Undefined | 0; Kõrgus: 2 600; 3D pikkus: 5 692 | 0 | yes | Arhitektuur - 07 Helipidavus: -; 08 Soojusläbivus (U-arv): -; 04 Tulepüsivus: -
ol.olev ss 250 | 1 KORRUS | 2.15 IfcWall (sein) (_RKAS BIM + ARCHICAD Classification); 51 Vaheseinad (EHITUSKULUDE LIIGITAMINE EVS 885:2005) | Kivi -Ol.Olev Konstruktsioon 250 mm | ol.olev ss 250 | Non-Load-Bearing Element | 1,39 | 2 747; Undefined | 0; Kõrgus: 2 600; 3D pikkus: 2 747 | 0 | no
ol.olev ss 100 | 1 KORRUS | 2.15 IfcWall (sein) (_RKAS BIM + ARCHICAD Classification); 51 Vaheseinad (EHITUSKULUDE LIIGITAMINE EVS 885:2005) | Kivi -Ol.Olev Konstruktsioon 100 mm | ol.olev ss 100 | Non-Load-Bearing Element | 0,31 | 1 740; Undefined | 0; Kõrgus: 2 600; 3D pikkus: 1 740 | 0 | no | Arhitektuur - 07 Helipidavus: -; 08 Soojusläbivus (U-arv): -; 04 Tulepüsivus: -
ol.olev ss 200 | 1 KORRUS | 2.15 IfcWall (sein) (_RKAS BIM + ARCHICAD Classification); 51 Vaheseinad (EHITUSKULUDE LIIGITAMINE EVS 885:2005) | Kivi -Ol.Olev Konstruktsioon 200 mm | ol.olev ss 200 | Non-Load-Bearing Element | 0,46 | 1 400; Undefined | 0; Kõrgus: 2 600; 3D pikkus: 1 400 | 0 | no
ol.olev ss 200 | 1 KORRUS | 2.15 IfcWall (sein) (_RKAS BIM + ARCHICAD Classification); 51 Vaheseinad (EHITUSKULUDE LIIGITAMINE EVS 885:2005) | Kivi -Ol.Olev Konstruktsioon 200 mm | ol.olev ss 200 | Non-Load-Bearing Element | 1,92 | 3 702; Undefined | 0; Kõrgus: 2 600; 3D pikkus: 3 702 | 0 | no
ol.olev ss 150 | 1 KORRUS | 2.15 IfcWall (sein) (_RKAS BIM + ARCHICAD Classification); 51 Vaheseinad (EHITUSKULUDE LIIGITAMINE EVS 885:2005) | Kivi -Ol.Olev Konstruktsioon 150 mm | ol.olev ss 150 | Non-Load-Bearing Element | 2,91 | 8 855; Undefined | 0; Kõrgus: 2 600; 3D pikkus: 8 855 | 0 | no
ol.olev ss 150 | 1 KORRUS | 2.15 IfcWall (sein) (_RKAS BIM + ARCHICAD Classification); 51 Vaheseinad (EHITUSKULUDE LIIGITAMINE EVS 885:2005) | Kivi -Ol.Olev Konstruktsioon 150 mm | ol.olev ss 150 | Non-Load-Bearing Element | 0,24 | 1 159; Undefined | 0; Kõrgus: 2 600; 3D pikkus: 1 159 | 0 | no
ol.olev ss 150 | 1 KORRUS | 2.15 IfcWall (sein) (_RKAS BIM + ARCHICAD Classification); 51 Vaheseinad (EHITUSKULUDE LIIGITAMINE EVS 885:2005) | Kivi -Ol.Olev Konstruktsioon 150 mm | ol.olev ss 150 | Non-Load-Bearing Element | 0,75 | 1 921; Undefined | 0; Kõrgus: 2 600; 3D pikkus: 1 921 | 0 | no
ol.olev ss 150 | 1 KORRUS | 2.15 IfcWall (sein) (_RKAS BIM + ARCHICAD Classification); 51 Vaheseinad (EHITUSKULUDE LIIGITAMINE EVS 885:2005) | Kivi -Ol.Olev Konstruktsioon 150 mm | ol.olev ss 150 | Non-Load-Bearing Element | 1,07 | 3 361; Undefined | 0; Kõrgus: 2 600; 3D pikkus: 3 361 | 0 | no
ol.olev ss 150 | 1 KORRUS | 2.15 IfcWall (sein) (_RKAS BIM + ARCHICAD Classification); 51 Vaheseinad (EHITUSKULUDE LIIGITAMINE EVS 885:2005) | Kivi -Ol.Olev Konstruktsioon 150 mm | ol.olev ss 150 | Non-Load-Bearing Element | 1,04 | 3 809; Undefined | 0; Kõrgus: 2 600; 3D pikkus: 3 809 | 0 | no
ol.olev ss 150 | 1 KORRUS | 2.15 IfcWall (sein) (_RKAS BIM + ARCHICAD Classification); 51 Vaheseinad (EHITUSKULUDE LIIGITAMINE EVS 885:2005) | Kivi -Ol.Olev Konstruktsioon 150 mm | ol.olev ss 150 | Non-Load-Bearing Element | 1,49 | 3 826; Undefined | 0; Kõrgus: 2 600; 3D pikkus: 3 826 | 0 | no
ol.olev ss 150 | 1 KORRUS | 2.15 IfcWall (sein) (_RKAS BIM + ARCHICAD Classification); 51 Vaheseinad (EHITUSKULUDE LIIGITAMINE EVS 885:2005) | Kivi -Ol.Olev Konstruktsioon 150 mm | ol.olev ss 150 | Non-Load-Bearing Element | 1,33 | 3 409; Undefined | 0; Kõrgus: 2 600; 3D pikkus: 3 409 | 0 | no
ol.olev ss 150 | 1 KORRUS | 2.15 IfcWall (sein) (_RKAS BIM + ARCHICAD Classification); 51 Vaheseinad (EHITUSKULUDE LIIGITAMINE EVS 885:2005) | Kivi -Ol.Olev Konstruktsioon 150 mm | ol.olev ss 150 | Non-Load-Bearing Element | 5,89 | 17 581; Undefined | 0; Kõrgus: 2 600; 3D pikkus: 17 581 | 0 | no
ol.olev ss 100 | 1 KORRUS | 2.15 IfcWall (sein) (_RKAS BIM + ARCHICAD Classification); 51 Vaheseinad (EHITUSKULUDE LIIGITAMINE EVS 885:2005) | Kivi -Ol.Olev Konstruktsioon 100 mm | ol.olev ss 100 | Non-Load-Bearing Element | 0,82 | 3 870; Undefined | 0; Kõrgus: 2 600; 3D pikkus: 3 870 | 0 | no | Arhitektuur - 07 Helipidavus: -; 08 Soojusläbivus (U-arv): -; 04 Tulepüsivus: -
ol.olev ss 150 | 1 KORRUS | 2.15 IfcWall (sein) (_RKAS BIM + ARCHICAD Classification); 51 Vaheseinad (EHITUSKULUDE LIIGITAMINE EVS 885:2005) | Kivi -Ol.Olev Konstruktsioon 150 mm | ol.olev ss 150 | Non-Load-Bearing Element | 1,51 | 3 871; Undefined | 0; Kõrgus: 2 600; 3D pikkus: 3 871 | 0 | no
ol.olev ss 150 | 1 KORRUS | 2.15 IfcWall (sein) (_RKAS BIM + ARCHICAD Classification); 51 Vaheseinad (EHITUSKULUDE LIIGITAMINE EVS 885:2005) | Kivi -Ol.Olev Konstruktsioon 150 mm | ol.olev ss 150 | Non-Load-Bearing Element | 1,27 | 3 868; Undefined | 0; Kõrgus: 2 600; 3D pikkus: 3 868 | 0 | no
ol.olev ss 150 | 1 KORRUS | 2.15 IfcWall (sein) (_RKAS BIM + ARCHICAD Classification); 51 Vaheseinad (EHITUSKULUDE LIIGITAMINE EVS 885:2005) | Kivi -Ol.Olev Konstruktsioon 150 mm | ol.olev ss 150 | Non-Load-Bearing Element | 1,37 | 3 659; Undefined | 0; Kõrgus: 2 600; 3D pikkus: 3 659 | 0 | no
ol.olev ss 150 | 1 KORRUS | 2.15 IfcWall (sein) (_RKAS BIM + ARCHICAD Classification); 51 Vaheseinad (EHITUSKULUDE LIIGITAMINE EVS 885:2005) | Kivi -Ol.Olev Konstruktsioon 150 mm | ol.olev ss 150 | Non-Load-Bearing Element | 0,52 | 1 339; Undefined | 0; Kõrgus: 2 600; 3D pikkus: 1 339 | 0 | no
ol.olev ss 200 | 1 KORRUS | 2.15 IfcWall (sein) (_RKAS BIM + ARCHICAD Classification); 51 Vaheseinad (EHITUSKULUDE LIIGITAMINE EVS 885:2005) | Kivi -Ol.Olev Konstruktsioon 200 mm | ol.olev ss 200 | Non-Load-Bearing Element | 1,23 | 2 367; Undefined | 0; Kõrgus: 2 600; 3D pikkus: 2 367 | 0 | no
ol.olev ss 200 | 1 KORRUS | 2.15 IfcWall (sein) (_RKAS BIM + ARCHICAD Classification); 51 Vaheseinad (EHITUSKULUDE LIIGITAMINE EVS 885:2005) | Kivi -Ol.Olev Konstruktsioon 200 mm | ol.olev ss 200 | Non-Load-Bearing Element | 4,04 | 9 273; Undefined | 0; Kõrgus: 2 600; 3D pikkus: 9 273 | 0 | no
ol.olev ss 200 | 1 KORRUS | 2.15 IfcWall (sein) (_RKAS BIM + ARCHICAD Classification); 51 Vaheseinad (EHITUSKULUDE LIIGITAMINE EVS 885:2005) | Kivi -Ol.Olev Konstruktsioon 200 mm | ol.olev ss 200 | Non-Load-Bearing Element | 1,81 | 3 482; Undefined | 0; Kõrgus: 2 600; 3D pikkus: 3 482 | 0 | no
ol.olev ss 150 | 1 KORRUS | 2.15 IfcWall (sein) (_RKAS BIM + ARCHICAD Classification); 51 Vaheseinad (EHITUSKULUDE LIIGITAMINE EVS 885:2005) | Kivi -Ol.Olev Konstruktsioon 150 mm | ol.olev ss 150 | Non-Load-Bearing Element | 1,17 | 3 700; Undefined | 0; Kõrgus: 2 600; 3D pikkus: 3 700 | 0 | no
ol.olev ss 150 | 1 KORRUS | 2.15 IfcWall (sein) (_RKAS BIM + ARCHICAD Classification); 51 Vaheseinad (EHITUSKULUDE LIIGITAMINE EVS 885:2005) | Kivi -Ol.Olev Konstruktsioon 150 mm | ol.olev ss 150 | Non-Load-Bearing Element | 1,40 | 3 585; Undefined | 0; Kõrgus: 2 600; 3D pikkus: 3 585 | 0 | no
ol.olev ss 420 | 1 KORRUS | 32 Kandvad ja välisseinad (EHITUSKULUDE LIIGITAMINE EVS 885:2005); 2.15 IfcWall (sein) (_RKAS BIM + ARCHICAD Classification) | Kivi -Ol.Olev Konstruktsioon 420 mm | ol.olev ss 420 | Load-Bearing Element | 2,28 | 2 664; Undefined | 0; Kõrgus: 2 600; 3D pikkus: 2 664 | 0 | yes | Arhitektuur - 07 Helipidavus: -; 08 Soojusläbivus (U-arv): -; 04 Tulepüsivus: -
ol.olev ss 420 | 1 KORRUS | 32 Kandvad ja välisseinad (EHITUSKULUDE LIIGITAMINE EVS 885:2005); 2.15 IfcWall (sein) (_RKAS BIM + ARCHICAD Classification) | Kivi -Ol.Olev Konstruktsioon 420 mm | ol.olev ss 420 | Load-Bearing Element | 4,16 | 3 807; Undefined | 0; Kõrgus: 2 600; 3D pikkus: 3 807 | 0 | yes | Arhitektuur - 07 Helipidavus: -; 08 Soojusläbivus (U-arv): -; 04 Tulepüsivus: -
ol.olev ss 420 | 1 KORRUS | 32 Kandvad ja välisseinad (EHITUSKULUDE LIIGITAMINE EVS 885:2005); 2.15 IfcWall (sein) (_RKAS BIM + ARCHICAD Classification) | Kivi -Ol.Olev Konstruktsioon 420 mm | ol.olev ss 420 | Load-Bearing Element | 3,42 | 3 808; Undefined | 0; Kõrgus: 2 600; 3D pikkus: 3 808 | 0 | yes | Arhitektuur - 07 Helipidavus: -; 08 Soojusläbivus (U-arv): -; 04 Tulepüsivus: -
ol.olev ss 420 | 1 KORRUS | 32 Kandvad ja välisseinad (EHITUSKULUDE LIIGITAMINE EVS 885:2005); 2.15 IfcWall (sein) (_RKAS BIM + ARCHICAD Classification) | Kivi -Ol.Olev Konstruktsioon 420 mm | ol.olev ss 420 | Load-Bearing Element | 0,67 | 2 629; Undefined | 0; Kõrgus: 2 600; 3D pikkus: 2 629 | 0 | yes | Arhitektuur - 07 Helipidavus: -; 08 Soojusläbivus (U-arv): -; 04 Tulepüsivus: -
ol.olev ss 420 | 1 KORRUS | 32 Kandvad ja välisseinad (EHITUSKULUDE LIIGITAMINE EVS 885:2005); 2.15 IfcWall (sein) (_RKAS BIM + ARCHICAD Classification) | Kivi -Ol.Olev Konstruktsioon 420 mm | ol.olev ss 420 | Load-Bearing Element | 4,39 | 4 442; Undefined | 0; Kõrgus: 2 600; 3D pikkus: 4 442 | 0 | yes | Arhitektuur - 07 Helipidavus: -; 08 Soojusläbivus (U-arv): -; 04 Tulepüsivus: -
ol.olev ss 420 | 1 KORRUS | 32 Kandvad ja välisseinad (EHITUSKULUDE LIIGITAMINE EVS 885:2005); 2.15 IfcWall (sein) (_RKAS BIM + ARCHICAD Classification) | Kivi -Ol.Olev Konstruktsioon 420 mm | ol.olev ss 420 | Load-Bearing Element | 4,08 | 3 735; Undefined | 0; Kõrgus: 2 600; 3D pikkus: 3 735 | 0 | yes | Arhitektuur - 07 Helipidavus: -; 08 Soojusläbivus (U-arv): -; 04 Tulepüsivus: -
ol.olev ss 150 | 1 KORRUS | 2.15 IfcWall (sein) (_RKAS BIM + ARCHICAD Classification); 51 Vaheseinad (EHITUSKULUDE LIIGITAMINE EVS 885:2005) | Kivi -Ol.Olev Konstruktsioon 150 mm | ol.olev ss 150 | Non-Load-Bearing Element | 1,48 | 3 808; Undefined | 0; Kõrgus: 2 600; 3D pikkus: 3 808 | 0 | no
ol.olev ss 560 | 1 KORRUS | 2.15 IfcWall (sein) (_RKAS BIM + ARCHICAD Classification); 51 Vaheseinad (EHITUSKULUDE LIIGITAMINE EVS 885:2005) | Kivi -Ol.Olev Konstruktsioon 560 mm | ol.olev ss 560 | Load-Bearing Element | 1,27 | 872; Undefined | 0; Kõrgus: 2 600; 3D pikkus: 872 | 0 | yes
ol.olev ss 420 | 1 KORRUS | 32 Kandvad ja välisseinad (EHITUSKULUDE LIIGITAMINE EVS 885:2005); 2.15 IfcWall (sein) (_RKAS BIM + ARCHICAD Classification) | Kivi -Ol.Olev Konstruktsioon 420 mm | ol.olev ss 420 | Load-Bearing Element | 2,33 | 3 276; Undefined | 0; Kõrgus: 2 600; 3D pikkus: 3 276 | 0 | yes | Arhitektuur - 07 Helipidavus: -; 08 Soojusläbivus (U-arv): -; 04 Tulepüsivus: -
ol.olev ss 420 | 1 KORRUS | 32 Kandvad ja välisseinad (EHITUSKULUDE LIIGITAMINE EVS 885:2005); 2.15 IfcWall (sein) (_RKAS BIM + ARCHICAD Classification) | Kivi -Ol.Olev Konstruktsioon 420 mm | ol.olev ss 420 | Load-Bearing Element | 6,97 | 7 106; Undefined | 0; Kõrgus: 2 600; 3D pikkus: 7 106 | 0 | yes | Arhitektuur - 07 Helipidavus: -; 08 Soojusläbivus (U-arv): -; 04 Tulepüsivus: -
ol.olev ss 200 | 1 KORRUS | 2.15 IfcWall (sein) (_RKAS BIM + ARCHICAD Classification); 51 Vaheseinad (EHITUSKULUDE LIIGITAMINE EVS 885:2005) | Kivi -Ol.Olev Konstruktsioon 200 mm | ol.olev ss 200 | Non-Load-Bearing Element | 2,81 | 5 401; Undefined | 0; Kõrgus: 2 600; 3D pikkus: 5 401 | 0 | no
ol.olev ss 150 | 1 KORRUS | 2.15 IfcWall (sein) (_RKAS BIM + ARCHICAD Classification); 51 Vaheseinad (EHITUSKULUDE LIIGITAMINE EVS 885:2005) | Kivi -Ol.Olev Konstruktsioon 150 mm | ol.olev ss 150 | Non-Load-Bearing Element | 1,78 | 5 251; Undefined | 0; Kõrgus: 2 600; 3D pikkus: 5 251 | 0 | no
3 x ol.olev ss 150 | 1 KORRUS | 2.15 IfcWall (sein) (_RKAS BIM + ARCHICAD Classification); 51 Vaheseinad (EHITUSKULUDE LIIGITAMINE EVS 885:2005) | Kivi -Ol.Olev Konstruktsioon 150 mm | ol.olev ss 150 | Non-Load-Bearing Element | 2,34 | 6 002; Undefined | 0; Kõrgus: 2 600; 3D pikkus: 6 002 | 0 | no
ol.olev ss 150 | 1 KORRUS | 2.15 IfcWall (sein) (_RKAS BIM + ARCHICAD Classification); 51 Vaheseinad (EHITUSKULUDE LIIGITAMINE EVS 885:2005) | Kivi -Ol.Olev Konstruktsioon 150 mm | ol.olev ss 150 | Non-Load-Bearing Element | 2,35 | 6 423; Undefined | 0; Kõrgus: 2 600; 3D pikkus: 6 423 | 0 | no
ol.olev ss 150 | 1 KORRUS | 2.15 IfcWall (sein) (_RKAS BIM + ARCHICAD Classification); 51 Vaheseinad (EHITUSKULUDE LIIGITAMINE EVS 885:2005) | Kivi -Ol.Olev Konstruktsioon 150 mm | ol.olev ss 150 | Non-Load-Bearing Element | 2,26 | 5 793; Undefined | 0; Kõrgus: 2 600; 3D pikkus: 5 793 | 0 | no
ol.olev ss 150 | 1 KORRUS | 2.15 IfcWall (sein) (_RKAS BIM + ARCHICAD Classification); 51 Vaheseinad (EHITUSKULUDE LIIGITAMINE EVS 885:2005) | Kivi -Ol.Olev Konstruktsioon 150 mm | ol.olev ss 150 | Non-Load-Bearing Element | 2,15 | 5 793; Undefined | 0; Kõrgus: 2 600; 3D pikkus: 5 793 | 0 | no
ol.olev ss 420 | 1 KORRUS | 32 Kandvad ja välisseinad (EHITUSKULUDE LIIGITAMINE EVS 885:2005); 2.15 IfcWall (sein) (_RKAS BIM + ARCHICAD Classification) | Kivi -Ol.Olev Konstruktsioon 420 mm | ol.olev ss 420 | Load-Bearing Element | 2,49 | 2 280; Undefined | 0; Kõrgus: 2 600; 3D pikkus: 2 280 | 0 | yes | Arhitektuur - 07 Helipidavus: -; 08 Soojusläbivus (U-arv): -; 04 Tulepüsivus: -
ol.olev ss 200 | 1 KORRUS | 2.15 IfcWall (sein) (_RKAS BIM + ARCHICAD Classification); 51 Vaheseinad (EHITUSKULUDE LIIGITAMINE EVS 885:2005) | Kivi -Ol.Olev Konstruktsioon 200 mm | ol.olev ss 200 | Non-Load-Bearing Element | 1,38 | 2 660; Undefined | 0; Kõrgus: 2 600; 3D pikkus: 2 660 | 0 | no
ol.olev ss 250 | 2 KORRUS | 32 Kandvad ja välisseinad (EHITUSKULUDE LIIGITAMINE EVS 885:2005); 2.15 IfcWall (sein) (_RKAS BIM + ARCHICAD Classification) | Kivi -Ol.Olev Konstruktsioon 250 mm | ol.olev ss 250 | Non-Load-Bearing Element | 3,74 | 5 790; Undefined | 3 000; Kõrgus: 3 250; 3D pikkus: 5 790 | 3 000 | no

# IfcWallStandardCase: SW - 037 (7)
Type - ElementType: Element type SW - 037
Classification: 2.15 IfcWall (sein) (_RKAS BIM + ARCHICAD Classification); 51 Vaheseinad (EHITUSKULUDE LIIGITAMINE EVS 885:2005)
Arhitektuur - 02 Materjal: Kivi -Ol.Olev Konstruktsioon; 03 Tähistus: SW - 037; 05 Asukoht: Interior; 06 Kandevelementide eristatus: Non-Load-Bearing Element
Ehituskonstruktsioonid - 02 Materjal: Kivi -Ol.Olev Konstruktsioon; 03 Tähistus või ristlõige: SW - 037; 04 Materjali peamine tugevusnäitaja: Undefined; 05 Keskkonnaklass: Undefined; 07 Monteeritava elemendi mass: Undefined; 09 Monteeritava elemendi positisioon/mark: Undefined; 10 Elemendi valmistamise tehnoloogia: Undefined
AC_Pset_RenovationAndPhasing - Renovation Status: Existing
Pset_WallCommon - LoadBearing: no; IsExternal: no
Name | In | Material | Arhitektuur, 01 Nimetus = Ehituskonstruktsioonid, 01 Nimetus | 06 Maht (kubatuur) | 08 Monteeritava elemendi pikkus | 11 Ülemine kõrgusmärk | 12 Alumine kõrgusmärk
ol.olev ss 200 | 1 KORRUS | Kivi -Ol.Olev Konstruktsioon 200 mm | ol.olev ss 200 | 1,98 | 3 801; Undefined | 0; Kõrgus: 2 600; 3D pikkus: 3 801 | 0
ol.olev ss 100 | 1 KORRUS | Kivi -Ol.Olev Konstruktsioon 100 mm | ol.olev ss 100 | 0,16 | 630; Undefined | 0; Kõrgus: 2 600; 3D pikkus: 630 | 0 | Arhitektuur - 04 Tulepüsivus: -; 07 Helipidavus: -; 08 Soojusläbivus (U-arv): -
ol.olev ss 100 | 1 KORRUS | Kivi -Ol.Olev Konstruktsioon 100 mm | ol.olev ss 100 | 0,25 | 1 532; Undefined | 0; Kõrgus: 2 600; 3D pikkus: 1 532 | 0 | Arhitektuur - 04 Tulepüsivus: -; 07 Helipidavus: -; 08 Soojusläbivus (U-arv): -
ol.olev ss 100 | 1 KORRUS | Kivi -Ol.Olev Konstruktsioon 100 mm | ol.olev ss 100 | 0,09 | 359; Undefined | 0; Kõrgus: 2 600; 3D pikkus: 359 | 0 | Arhitektuur - 04 Tulepüsivus: -; 07 Helipidavus: -; 08 Soojusläbivus (U-arv): -
ol.olev ss 150 | 1 KORRUS | Kivi -Ol.Olev Konstruktsioon 150 mm | ol.olev ss 150 | 1,40 | 3 601; Undefined | 0; Kõrgus: 2 600; 3D pikkus: 3 601 | 0
ol.olev ss 150 | 1 KORRUS | Kivi -Ol.Olev Konstruktsioon 150 mm | ol.olev ss 150 | 0,52 | 1 336; Undefined | 0; Kõrgus: 2 600; 3D pikkus: 1 336 | 0
ol.olev ss 150 | 2 KORRUS | Kivi -Ol.Olev Konstruktsioon 150 mm | ol.olev ss 150 | 0,23 | 1 271; Undefined | 3 000; Kõrgus: 1 200; 3D pikkus: 1 271 | 3 000

# IfcWallStandardCase: SW - 038 (3)
In: 1 KORRUS
Type - ElementType: Element type SW - 038
Classification: 2.15 IfcWall (sein) (_RKAS BIM + ARCHICAD Classification); 51 Vaheseinad (EHITUSKULUDE LIIGITAMINE EVS 885:2005)
Arhitektuur - 02 Materjal: Kivi -Ol.Olev Konstruktsioon; 03 Tähistus: SW - 038; 05 Asukoht: Interior; 06 Kandevelementide eristatus: Non-Load-Bearing Element
Ehituskonstruktsioonid - 02 Materjal: Kivi -Ol.Olev Konstruktsioon; 03 Tähistus või ristlõige: SW - 038; 04 Materjali peamine tugevusnäitaja: Undefined; 05 Keskkonnaklass: Undefined; 07 Monteeritava elemendi mass: Undefined; 09 Monteeritava elemendi positisioon/mark: Undefined; 10 Elemendi valmistamise tehnoloogia: Undefined; 12 Alumine kõrgusmärk: 0
AC_Pset_RenovationAndPhasing - Renovation Status: Existing
Pset_WallCommon - LoadBearing: no; IsExternal: no
Name | Material | 04 Tulepüsivus = 07 Helipidavus = 08 Soojusläbivus (U-arv) | Arhitektuur, 01 Nimetus = Ehituskonstruktsioonid, 01 Nimetus | 06 Maht (kubatuur) | 08 Monteeritava elemendi pikkus | 11 Ülemine kõrgusmärk
ol.olev ss 100 | Kivi -Ol.Olev Konstruktsioon 100 mm | - | ol.olev ss 100 | 0,23 | 887; Undefined | 0; Kõrgus: 2 600; 3D pikkus: 887
ol.olev ss 100 | Kivi -Ol.Olev Konstruktsioon 100 mm | - | ol.olev ss 100 | 0,24 | 920; Undefined | 0; Kõrgus: 2 600; 3D pikkus: 920
ol.olev ss 150 | Kivi -Ol.Olev Konstruktsioon 150 mm |  | ol.olev ss 150 | 1,62 | 5 599; Undefined | 0; Kõrgus: 2 600; 3D pikkus: 5 599

# IfcWallStandardCase: SW - 040, ol.olev ss 100
In: 1 KORRUS
Type - ElementType: Element type SW - 040
Classification: 2.15 IfcWall (sein) (_RKAS BIM + ARCHICAD Classification); 51 Vaheseinad (EHITUSKULUDE LIIGITAMINE EVS 885:2005); Material: Kivi -Ol.Olev Konstruktsioon 100 mm
Arhitektuur - 04 Tulepüsivus: -; 07 Helipidavus: -; 08 Soojusläbivus (U-arv): -; 01 Nimetus: ol.olev ss 100; 02 Materjal: Kivi -Ol.Olev Konstruktsioon; 03 Tähistus: SW - 040; 05 Asukoht: Interior; 06 Kandevelementide eristatus: Non-Load-Bearing Element
Ehituskonstruktsioonid - 01 Nimetus: ol.olev ss 100; 02 Materjal: Kivi -Ol.Olev Konstruktsioon; 03 Tähistus või ristlõige: SW - 040; 04 Materjali peamine tugevusnäitaja: Undefined; 05 Keskkonnaklass: Undefined; 06 Maht (kubatuur): 0,60; 07 Monteeritava elemendi mass: Undefined; 08 Monteeritava elemendi pikkus: 2 849; Undefined; 09 Monteeritava elemendi positisioon/mark: Undefined; 10 Elemendi valmistamise tehnoloogia: Undefined; 11 Ülemine kõrgusmärk: 0; Kõrgus: 2 600; 3D pikkus: 2 849; 12 Alumine kõrgusmärk: 0
AC_Pset_RenovationAndPhasing - Renovation Status: Existing
Pset_WallCommon - LoadBearing: no; IsExternal: no

# IfcWallStandardCase: TR4 soojusus
In: 2 KORRUS
Type - ElementType: Element type TR4 soojusus
Description: Soojustus; Classification: 1.18 IfcWall (sein) (_RKAS BIM + ARCHICAD Classification); 32 Kandvad ja välisseinad (EHITUSKULUDE LIIGITAMINE EVS 885:2005); Material: Soojustus - Plastik Kõva 100 mm
Arhitektuur - 03 Tähistus: TR4 soojusus; 04 Tulepüsivus: REI-60; 08 Soojusläbivus (U-arv): 0,15 w/m2K; 07 Helipidavus: 35dB; 01 Nimetus: TR4 soojusus; 02 Materjal: Soojustus - Plastik Kõva; 05 Asukoht: Exterior; 06 Kandevelementide eristatus: Non-Load-Bearing Element
Ehituskonstruktsioonid - 01 Nimetus: TR4 soojusus; 02 Materjal: Soojustus - Plastik Kõva; 03 Tähistus või ristlõige: TR4 soojusus; 06 Maht (kubatuur): 0,53; 11 Ülemine kõrgusmärk: 2 248; Kõrgus: 4 732; 3D pikkus: 1 300; 12 Alumine kõrgusmärk: 2 248
AC_Pset_RenovationAndPhasing - Renovation Status: New
Pset_WallCommon - LoadBearing: no; IsExternal: yes

# IfcWallStandardCase: VS-1 (9)
In: 1 KORRUS
Type - ElementType: Element type VS-1
Classification: 1.18 IfcWall (sein) (_RKAS BIM + ARCHICAD Classification); 32 Kandvad ja välisseinad (EHITUSKULUDE LIIGITAMINE EVS 885:2005); Material: Kivi - Ol.Olev Konstruktsioon 740 mm
Arhitektuur - 04 Tulepüsivus: REI-60; 08 Soojusläbivus (U-arv): 1,1 W/m2K; 01 Nimetus: VS1; 02 Materjal: Kivi - Ol.Olev Konstruktsioon; 03 Tähistus: VS-1; 05 Asukoht: Exterior; 06 Kandevelementide eristatus: Load-Bearing Element; 07 Helipidavus: -
Ehituskonstruktsioonid - 01 Nimetus: VS1; 02 Materjal: Kivi - Ol.Olev Konstruktsioon; 03 Tähistus või ristlõige: VS-1
AC_Pset_RenovationAndPhasing - Renovation Status: Existing
Pset_WallCommon - LoadBearing: yes; IsExternal: yes
Name | 06 Maht (kubatuur) | 11 Ülemine kõrgusmärk | 12 Alumine kõrgusmärk
VS1 | 2,40 | 0; Kõrgus: 2 600; 3D pikkus: 1 698 | 0
VS1 | 8,80 | 0; Kõrgus: 3 000; 3D pikkus: 4 540 | 0
VS1 | 10,79 | -1 000; Kõrgus: 4 000; 3D pikkus: 5 290 | -1 000
VS1 | 9,60 | -1 000; Kõrgus: 3 364; 3D pikkus: 5 839 | -1 000
VS1 | 8,44 | -1 000; Kõrgus: 3 486; 3D pikkus: 5 207 | -1 000
VS1 | 8,98 | 0; Kõrgus: 3 000; 3D pikkus: 4 923 | 0
VS1 | 9,93 | -1 040; Kõrgus: 3 640; 3D pikkus: 5 656 | -1 040
VS1 | 2,56 | -40; Kõrgus: 2 835; 3D pikkus: 2 004 | -40
VS1 | 49,90 | 0; Kõrgus: 2 600; 3D pikkus: 26 166 | 0

# IfcWallStandardCase: VS-4 (2)
In: 2 KORRUS
Type - ElementType: Element type VS-4
Classification: 2.15 IfcWall (sein) (_RKAS BIM + ARCHICAD Classification); 51 Vaheseinad (EHITUSKULUDE LIIGITAMINE EVS 885:2005); Material: Kivi - Uus Konstruktsioon 430 mm
Arhitektuur - 01 Nimetus: uus kinni ehitav sein 430; 02 Materjal: Kivi - Uus Konstruktsioon; 03 Tähistus: VS-4; 05 Asukoht: Exterior; 06 Kandevelementide eristatus: Non-Load-Bearing Element
Ehituskonstruktsioonid - 01 Nimetus: uus kinni ehitav sein 430; 02 Materjal: Kivi - Uus Konstruktsioon; 03 Tähistus või ristlõige: VS-4; 04 Materjali peamine tugevusnäitaja: Undefined; 05 Keskkonnaklass: Undefined; 07 Monteeritava elemendi mass: Undefined; 09 Monteeritava elemendi positisioon/mark: Undefined; 10 Elemendi valmistamise tehnoloogia: Undefined; 12 Alumine kõrgusmärk: 3 000
AC_Pset_RenovationAndPhasing - Renovation Status: New
Pset_WallCommon - LoadBearing: no; IsExternal: yes
Name | 06 Maht (kubatuur) | 08 Monteeritava elemendi pikkus | 11 Ülemine kõrgusmärk
uus kinni ehitav sein 430 | 2,41 | 2 000; Undefined | 3 000; Kõrgus: 2 800; 3D pikkus: 2 000
uus kinni ehitav sein 430 | 1,08 | 1 000; Undefined | 3 000; Kõrgus: 2 500; 3D pikkus: 1 000

# IfcWallStandardCase: VS3 (5)
In: 1 KORRUS
Type - ElementType: Element type VS3
Classification: 1.18 IfcWall (sein) (_RKAS BIM + ARCHICAD Classification); 32 Kandvad ja välisseinad (EHITUSKULUDE LIIGITAMINE EVS 885:2005); Material: Kivi - Ol.Olev Konstruktsioon 500 mm
Arhitektuur - 01 Nimetus: Ol.olve tugimüür 500; 02 Materjal: Kivi - Ol.Olev Konstruktsioon; 03 Tähistus: VS3; 04 Tulepüsivus: nõudeid ei esitata; 05 Asukoht: Exterior; 06 Kandevelementide eristatus: Non-Load-Bearing Element; 07 Helipidavus: -; 08 Soojusläbivus (U-arv): -
Ehituskonstruktsioonid - 01 Nimetus: Ol.olve tugimüür 500; 02 Materjal: Kivi - Ol.Olev Konstruktsioon; 03 Tähistus või ristlõige: VS3
AC_Pset_RenovationAndPhasing - Renovation Status: Existing
Pset_WallCommon - LoadBearing: no; IsExternal: yes
Name | 06 Maht (kubatuur) | 11 Ülemine kõrgusmärk | 12 Alumine kõrgusmärk
Ol.olve tugimüür 500 | 10,80 | 0; Kõrgus: 2 600; 3D pikkus: 8 675 | 0
Ol.olve tugimüür 500 | 4,21 | 0; Kõrgus: 2 600; 3D pikkus: 3 600 | 0
Ol.olve tugimüür 500 | 4,04 | 0; Kõrgus: 2 600; 3D pikkus: 3 119 | 0
Ol.olve tugimüür 500 | 9,96 | 0; Kõrgus: 2 600; 3D pikkus: 7 658 | 0
Ol.olve tugimüür 500 | 4,15 | 905; Kõrgus: 2 600; 3D pikkus: 3 192 | 905

# IfcWallStandardCase: VS4 (2)
In: 1 KORRUS
Type - ElementType: Element type VS4
Classification: 1.18 IfcWall (sein) (_RKAS BIM + ARCHICAD Classification); 32 Kandvad ja välisseinad (EHITUSKULUDE LIIGITAMINE EVS 885:2005); Material: Kivi - Ol.Olev Konstruktsioon 500 mm
Arhitektuur - 01 Nimetus: Ol.olve tugimüür 500; 02 Materjal: Kivi - Ol.Olev Konstruktsioon; 03 Tähistus: VS4; 04 Tulepüsivus: nõudeid ei esitata; 05 Asukoht: Exterior; 06 Kandevelementide eristatus: Non-Load-Bearing Element; 07 Helipidavus: -; 08 Soojusläbivus (U-arv): -
Ehituskonstruktsioonid - 01 Nimetus: Ol.olve tugimüür 500; 02 Materjal: Kivi - Ol.Olev Konstruktsioon; 03 Tähistus või ristlõige: VS4; 12 Alumine kõrgusmärk: 0
AC_Pset_RenovationAndPhasing - Renovation Status: Existing
Pset_WallCommon - LoadBearing: no; IsExternal: yes
Name | 06 Maht (kubatuur) | 11 Ülemine kõrgusmärk
Ol.olve tugimüür 500 | 9,79 | 0; Kõrgus: 2 600; 3D pikkus: 7 531
Ol.olve tugimüür 500 | 4,15 | 0; Kõrgus: 2 600; 3D pikkus: 3 191

# IfcWallStandardCase: VS5, Ol.olve tugimüür 500
In: 1 KORRUS
Type - ElementType: Element type VS5
Classification: 1.18 IfcWall (sein) (_RKAS BIM + ARCHICAD Classification); 32 Kandvad ja välisseinad (EHITUSKULUDE LIIGITAMINE EVS 885:2005); Material: Kivi - Ol.Olev Konstruktsioon 500 mm
Arhitektuur - 01 Nimetus: Ol.olve tugimüür 500; 02 Materjal: Kivi - Ol.Olev Konstruktsioon; 03 Tähistus: VS5; 04 Tulepüsivus: nõudeid ei esitata; 05 Asukoht: Exterior; 06 Kandevelementide eristatus: Non-Load-Bearing Element; 07 Helipidavus: -; 08 Soojusläbivus (U-arv): -
Ehituskonstruktsioonid - 01 Nimetus: Ol.olve tugimüür 500; 02 Materjal: Kivi - Ol.Olev Konstruktsioon; 03 Tähistus või ristlõige: VS5; 06 Maht (kubatuur): 3,38; 11 Ülemine kõrgusmärk: 0; Kõrgus: 2 600; 3D pikkus: 2 615; 12 Alumine kõrgusmärk: 0
AC_Pset_RenovationAndPhasing - Renovation Status: Existing
Pset_WallCommon - LoadBearing: no; IsExternal: yes

# IfcWallStandardCase: loputuskasti raam (10)
Type - ElementType: Element type loputuskasti raam
Description: loputuskasti raam; Classification: 1.18 IfcWall (sein) (_RKAS BIM + ARCHICAD Classification); 516 Puit- ja kipsplaatvaheseinad (EHITUSKULUDE LIIGITAMINE EVS 885:2005); Material: Kipsplaat 13 mm
Arhitektuur - 01 Nimetus: Kipsplaat; 02 Materjal: Kipsplaat; 03 Tähistus: loputuskasti raam; 04 Tulepüsivus: nõudeid ei esitata; 05 Asukoht: Interior; 06 Kandevelementide eristatus: Non-Load-Bearing Element; 07 Helipidavus: -; 08 Soojusläbivus (U-arv): -
Ehituskonstruktsioonid - 01 Nimetus: Kipsplaat; 02 Materjal: Kipsplaat; 03 Tähistus või ristlõige: loputuskasti raam
AC_Pset_RenovationAndPhasing - Renovation Status: New
Pset_WallCommon - LoadBearing: no; IsExternal: no
Name | In | 06 Maht (kubatuur) | 11 Ülemine kõrgusmärk | 12 Alumine kõrgusmärk
Kipsplaat | 1 KORRUS | 0,03 | 0; Kõrgus: 2 300; 3D pikkus: 1 159 | 0
Kipsplaat | 1 KORRUS | 0,02 | 0; Kõrgus: 1 200; 3D pikkus: 975 | 0
Kipsplaat | 1 KORRUS | 0,00 | 0; Kõrgus: 2 300; 3D pikkus: 163 | 0
Kipsplaat | 1 KORRUS | 0,02 | 0; Kõrgus: 1 200; 3D pikkus: 1 040 | 0
Kipsplaat | 1 KORRUS | 0,02 | 0; Kõrgus: 1 200; 3D pikkus: 1 027 | 0
Kipsplaat | 1 KORRUS | 0,01 | 2 079; Kõrgus: 247; 3D pikkus: 1 638 | 2 079
Kipsplaat | 2 KORRUS | 0,01 | 3 000; Kõrgus: 1 200; 3D pikkus: 873 | 3 000
Kipsplaat | 2 KORRUS | 0,04 | 3 000; Kõrgus: 2 800; 3D pikkus: 967 | 3 000
Kipsplaat | 2 KORRUS | 0,01 | 3 000; Kõrgus: 1 200; 3D pikkus: 817 | 3 000
Kipsplaat | 2 KORRUS | 0,04 | 3 000; Kõrgus: 2 800; 3D pikkus: 971 | 3 000

# IfcWindow: A1 2 580×1 050 (21)
In: 1 KORRUS
Type - OperationType: DOUBLE_PANEL_VERTICAL; ParameterTakesPrecedence: no; Sizeable: no
Type - Window Lining Properties - LiningDepth: 70 mm; LiningThickness: 50 mm; MullionThickness: 50 mm; FirstMullionOffset: 0.49031
Type - Window Panel Properties - Panel 1 - OperationType: FIXEDCASEMENT; PanelPosition: LEFT
Type - Window Panel Properties - Panel 2 - OperationType: TILTANDTURNLEFTHAND; PanelPosition: RIGHT; FrameDepth: 50 mm; FrameThickness: 50 mm
OverallHeight: 1050 mm; OverallWidth: 2580 mm; Classification: 1.19 IfcWindow (aken) (_RKAS BIM + ARCHICAD Classification); 42 Aknad (EHITUSKULUDE LIIGITAMINE EVS 885:2005)
Pset_WindowCommon - GlazingAreaFraction: 2.15525; IsExternal: yes
Avatäited - 01 Nimetus: välisaken; 02 Materjal: PVC; 03 Tähistus: A1 2 580×1 050; 04 Avamõõdu geomeetria: 2 580×1 050; 05 Asukoha info: Exterior; 06 Soojusläbivus: 0,95; 07 Helipidavus: 45; 08 Veepidavus: 7A; 09 Õhuläbilaskvus: klass 4; 10 Tulekindlus: nõudeid ei esitata; 11 Vastupanu tulekoormusele: C5/B5; 12 Klaaspakett: Kolmekordne klaaspakett argooniga täidetud; 13 Klaasingu erisused: karastatud; 15 Avanemine: Avanemine: "L" (L - vasak; R - parem); 16 Liigendatus: 2 ruuduga; 17 Sulused, lukustus: Mikrotuulutus, lukustust vt. Lukustuse projektist; 18 Viimistlus: Leng väljast: plast. valge; Leng seest: plast. valge; Raam väljast: plast. valge; Raam seest: plast. valge; Täpsustus: RAL 9003; 19 Mudel või toote tunnus: Undefined; 20 Tootja: Undefined; 21 Tooteinfo: Undefined; 22 Kasutus- ja hooldusjuhend: Undefined; 14 Päikesekiirgus tegur (g-väärtus): 0,3
AC_Pset_RenovationAndPhasing - Renovation Status: Existing
Name | ThermalTransmittance
14 x välisaken * Double Window 22 | 0
7 x välisaken * Double Window 22 | 0.95 | Description: PVC

# IfcWindow: A1 2 580×1 050 (17)
In: 1 KORRUS
Type - OperationType: DOUBLE_PANEL_VERTICAL; ParameterTakesPrecedence: no; Sizeable: no
Type - Window Lining Properties - LiningDepth: 70 mm; LiningThickness: 50 mm; MullionThickness: 50 mm; FirstMullionOffset: 0.49031
Type - Window Panel Properties - Panel 1 - OperationType: TILTANDTURNLEFTHAND; PanelPosition: RIGHT; FrameDepth: 50 mm; FrameThickness: 50 mm
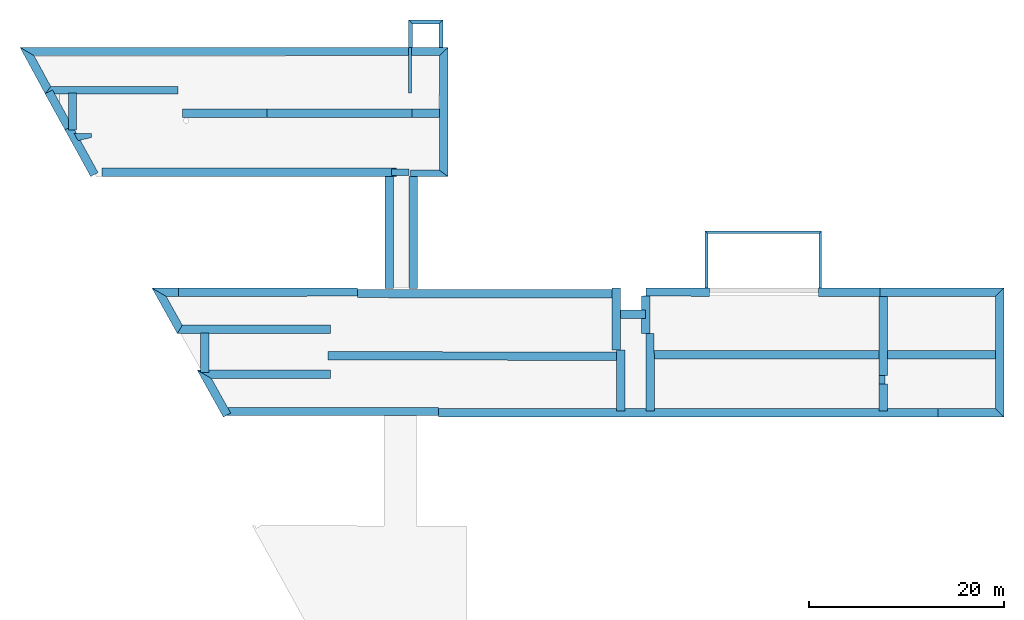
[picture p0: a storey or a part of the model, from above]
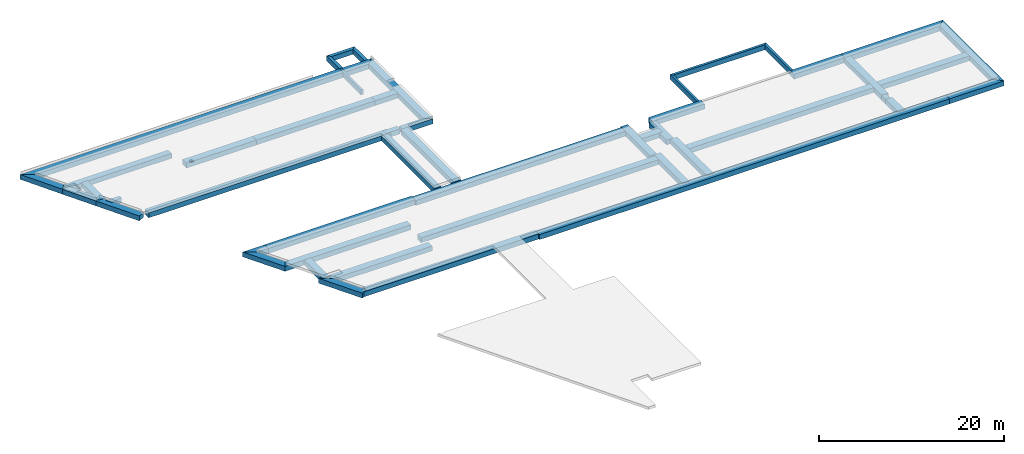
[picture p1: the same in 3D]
Properties of the parts of a building model (IFC2X3), part 14 of 14

# IfcWindow: A1 2 580×1 050 (17)
Type - Window Panel Properties - Panel 2 - OperationType: FIXEDCASEMENT; PanelPosition: LEFT
OverallHeight: 1050 mm; OverallWidth: 2580 mm; Classification: 1.19 IfcWindow (aken) (_RKAS BIM + ARCHICAD Classification); 42 Aknad (EHITUSKULUDE LIIGITAMINE EVS 885:2005)
Avatäited - 02 Materjal: PVC; 03 Tähistus: A1 2 580×1 050; 04 Avamõõdu geomeetria: 2 580×1 050; 05 Asukoha info: Exterior; 06 Soojusläbivus: 0,95; 07 Helipidavus: 45; 08 Veepidavus: 7A; 09 Õhuläbilaskvus: klass 4; 10 Tulekindlus: nõudeid ei esitata; 11 Vastupanu tulekoormusele: C5/B5; 12 Klaaspakett: Kolmekordne klaaspakett argooniga täidetud; 13 Klaasingu erisused: karastatud; 15 Avanemine: Avanemine: "L" (L - vasak; R - parem); 16 Liigendatus: 2 ruuduga; 17 Sulused, lukustus: Mikrotuulutus, lukustust vt. Lukustuse projektist; 18 Viimistlus: Leng väljast: plast. valge; Leng seest: plast. valge; Raam väljast: plast. valge; Raam seest: plast. valge; Täpsustus: RAL 9003; 19 Mudel või toote tunnus: Undefined; 20 Tootja: Undefined; 21 Tooteinfo: Undefined; 22 Kasutus- ja hooldusjuhend: Undefined; 14 Päikesekiirgus tegur (g-väärtus): 0,3
Pset_WindowCommon - GlazingAreaFraction: 2.15525; IsExternal: yes
AC_Pset_RenovationAndPhasing - Renovation Status: Existing
Name | 01 Nimetus | ThermalTransmittance
5 x välisaken * Double Window 22 | aken | 0
6 x välisaken * Double Window 22 | välisaken | 0
6 x välisaken * Double Window 22 | välisaken | 0.95 | Description: PVC

# IfcWindow: A2 2 580×2 100 (78)
In: 2 KORRUS
Type - OperationType: USERDEFINED; ParameterTakesPrecedence: no; Sizeable: no
OverallHeight: 2100 mm; OverallWidth: 2580 mm; Classification: 1.19 IfcWindow (aken) (_RKAS BIM + ARCHICAD Classification); 42 Aknad (EHITUSKULUDE LIIGITAMINE EVS 885:2005)
Pset_WindowCommon - GlazingAreaFraction: 4.445; IsExternal: yes
Avatäited - 01 Nimetus: välisaken; 02 Materjal: PVC; 03 Tähistus: A2 2 580×2 100; 04 Avamõõdu geomeetria: 2 580×2 100; 05 Asukoha info: Exterior; 06 Soojusläbivus: 0,95; 07 Helipidavus: 45; 08 Veepidavus: 7A; 09 Õhuläbilaskvus: klass 4; 10 Tulekindlus: nõudeid ei esitata; 11 Vastupanu tulekoormusele: C5/B5; 12 Klaaspakett: Kolmekordne klaaspakett argooniga täidetud; 13 Klaasingu erisused: karastatud; 15 Avanemine: Avanemine: "" (L - vasak; R - parem); 16 Liigendatus: 4 ruuduga; 17 Sulused, lukustus: Mikrotuulutus, lukustust vt. Lukustuse projektist; 18 Viimistlus: Leng väljast: Paint - Glossy White; Leng seest: Paint - Glossy White; Raam väljast: Paint - Glossy White; Raam seest: Paint - Glossy White; Täpsustus: RAL 9003; 19 Mudel või toote tunnus: Undefined; 20 Tootja: Undefined; 21 Tooteinfo: Undefined; 22 Kasutus- ja hooldusjuhend: Undefined; 14 Päikesekiirgus tegur (g-väärtus): 0,3
Name | Description | ThermalTransmittance | Renovation Status
69 x välisaken * Double Window 22 | PVC | 0.95 | New
9 x välisaken * Double Window 22 |  | 0 | Existing

# IfcWindow: A3 1 450×3 250 (3)
In: 2 KORRUS
Type - OperationType: DOUBLE_PANEL_HORIZONTAL; ParameterTakesPrecedence: no; Sizeable: no
Type - Window Lining Properties - LiningDepth: 50 mm; LiningThickness: 50 mm; TransomThickness: 50 mm; FirstTransomOffset: 0.5
Type - Window Panel Properties - Panel 1 - OperationType: FIXEDCASEMENT; PanelPosition: TOP
Type - Window Panel Properties - Panel 2 - OperationType: TILTANDTURNLEFTHAND; PanelPosition: BOTTOM; FrameDepth: 50 mm; FrameThickness: 50 mm
Description: PVC; OverallHeight: 3250 mm; OverallWidth: 1450 mm; Classification: 1.19 IfcWindow (aken) (_RKAS BIM + ARCHICAD Classification); 42 Aknad (EHITUSKULUDE LIIGITAMINE EVS 885:2005)
Pset_WindowCommon - ThermalTransmittance: 0.95; GlazingAreaFraction: 4.0425; IsExternal: yes
Avatäited - 01 Nimetus: välisaken; 02 Materjal: PVC; 03 Tähistus: A3 1 450×3 250; 04 Avamõõdu geomeetria: 1 450×3 250; 05 Asukoha info: Exterior; 06 Soojusläbivus: 0,95; 07 Helipidavus: 45; 08 Veepidavus: 7A; 09 Õhuläbilaskvus: klass 4; 10 Tulekindlus: nõudeid ei esitata; 11 Vastupanu tulekoormusele: C5/B5; 12 Klaaspakett: Kolmekordne klaaspakett argooniga täidetud; 13 Klaasingu erisused: karastatud; 15 Avanemine: Avanemine: "L" (L - vasak; R - parem); 16 Liigendatus: 2 ruuduga; 17 Sulused, lukustus: Mikrotuulutus, lukustust vt. Lukustuse projektist; 18 Viimistlus: Leng väljast: plast. valge; Leng seest: plast. valge; Raam väljast: plast. valge; Raam seest: plast. valge; Täpsustus: RAL 9003; 19 Mudel või toote tunnus: Undefined; 20 Tootja: Undefined; 21 Tooteinfo: Undefined; 22 Kasutus- ja hooldusjuhend: Undefined; 14 Päikesekiirgus tegur (g-väärtus): 0,3
AC_Pset_RenovationAndPhasing - Renovation Status: New

# IfcWindow: A4 2 117×3 200, välisaken * Double Window 22
In: 2 KORRUS
Type - OperationType: USERDEFINED; ParameterTakesPrecedence: no; Sizeable: no
Description: PVC; OverallHeight: 3200 mm; OverallWidth: 2117 mm; Classification: 1.19 IfcWindow (aken) (_RKAS BIM + ARCHICAD Classification); 42 Aknad (EHITUSKULUDE LIIGITAMINE EVS 885:2005)
Pset_WindowCommon - ThermalTransmittance: 0.95; GlazingAreaFraction: 5.21265; IsExternal: yes
Avatäited - 01 Nimetus: välisaken; 02 Materjal: PVC; 03 Tähistus: A4 2 117×3 200; 04 Avamõõdu geomeetria: 2 117×3 200; 05 Asukoha info: Exterior; 06 Soojusläbivus: 0,95; 07 Helipidavus: 45; 08 Veepidavus: 7A; 09 Õhuläbilaskvus: klass 4; 10 Tulekindlus: nõudeid ei esitata; 11 Vastupanu tulekoormusele: C5/B5; 12 Klaaspakett: Kolmekordne klaaspakett argooniga täidetud; 13 Klaasingu erisused: karastatud; 15 Avanemine: Avanemine: "" (L - vasak; R - parem); 16 Liigendatus: 4 ruuduga; 17 Sulused, lukustus: Mikrotuulutus, lukustust vt. Lukustuse projektist; 18 Viimistlus: Leng väljast: Paint - Glossy White; Leng seest: Paint - Glossy White; Raam väljast: Paint - Glossy White; Raam seest: Paint - Glossy White; Täpsustus: RAL 9003; 19 Mudel või toote tunnus: Undefined; 20 Tootja: Undefined; 21 Tooteinfo: Undefined; 22 Kasutus- ja hooldusjuhend: Undefined; 14 Päikesekiirgus tegur (g-väärtus): 0,3
AC_Pset_RenovationAndPhasing - Renovation Status: New

# IfcWindow: A5 2 200×2 100 (3)
In: 2 KORRUS
Type - OperationType: USERDEFINED; ParameterTakesPrecedence: no; Sizeable: no
Description: PVC; OverallHeight: 2100 mm; OverallWidth: 2200 mm; Classification: 1.19 IfcWindow (aken) (_RKAS BIM + ARCHICAD Classification); 42 Aknad (EHITUSKULUDE LIIGITAMINE EVS 885:2005)
Pset_WindowCommon - ThermalTransmittance: 0.95; GlazingAreaFraction: 3.7325; IsExternal: yes
Avatäited - 01 Nimetus: välisaken; 02 Materjal: PVC; 03 Tähistus: A5 2 200×2 100; 04 Avamõõdu geomeetria: 2 200×2 100; 05 Asukoha info: Exterior; 06 Soojusläbivus: 0,95; 07 Helipidavus: 45; 08 Veepidavus: 7A; 09 Õhuläbilaskvus: klass 4; 10 Tulekindlus: nõudeid ei esitata; 11 Vastupanu tulekoormusele: C5/B5; 12 Klaaspakett: Kolmekordne klaaspakett argooniga täidetud; 13 Klaasingu erisused: karastatud; 15 Avanemine: Avanemine: "" (L - vasak; R - parem); 16 Liigendatus: 4 ruuduga; 17 Sulused, lukustus: Mikrotuulutus, lukustust vt. Lukustuse projektist; 18 Viimistlus: Leng väljast: Paint - Glossy White; Leng seest: Paint - Glossy White; Raam väljast: Paint - Glossy White; Raam seest: Paint - Glossy White; Täpsustus: RAL 9003; 19 Mudel või toote tunnus: Undefined; 20 Tootja: Undefined; 21 Tooteinfo: Undefined; 22 Kasutus- ja hooldusjuhend: Undefined; 14 Päikesekiirgus tegur (g-väärtus): 0,3
AC_Pset_RenovationAndPhasing - Renovation Status: New

# IfcWindow: Curtain Wall Panel - Window 5 x 5 x 20 (4)
In: KATUSEPLAAN
Type - ParameterTakesPrecedence: no; Sizeable: no
Classification: 1.19 IfcWindow (aken) (_RKAS BIM + ARCHICAD Classification); 42 Aknad (EHITUSKULUDE LIIGITAMINE EVS 885:2005)
Avatäited - 01 Nimetus: Suitsuluuk; 02 Materjal: al50; 06 Soojusläbivus: 0,95; 07 Helipidavus: 45; 08 Veepidavus: 7A; 09 Õhuläbilaskvus: Klass 4; 10 Tulekindlus: nõudeid ei esitata; 11 Vastupanu tulekoormusele: C5/B5; 12 Klaaspakett: Kolmekordne klaaspakett; 13 Klaasingu erisused: -; 15 Avanemine: Avanemine: "R{Abbreviation of Right}" (L - vasak; R - parem); 16 Liigendatus: Undefined; 17 Sulused, lukustus: Elekriliselt avatav; 18 Viimistlus: Raam RAL 9003; 19 Mudel või toote tunnus: Undefined; 20 Tootja: Undefined; 21 Tooteinfo: Undefined; 22 Kasutus- ja hooldusjuhend: Undefined; 14 Päikesekiirgus tegur (g-väärtus): 0,3
Pset_ManufacturerOccurrence - SerialNumber: Off
AC_Pset_RenovationAndPhasing - Renovation Status: New
Name | 03 Tähistus = 04 Avamõõdu geomeetria
2 x Suitsuluuk * CW Window 22 | 930x1 200
Suitsuluuk * CW Window 22 | 936x1 200
Suitsuluuk * CW Window 22 | 943x1 200

# IfcWindow: Ventilatsiooni rest 400×400, Rest * Window 22
In: 2 KORRUS
Type - OperationType: SINGLE_PANEL; ParameterTakesPrecedence: no; Sizeable: no
Type - Window Lining Properties - LiningDepth: 50 mm; LiningThickness: 50 mm
Type - Window Panel Properties - Panel 1 - OperationType: SIDEHUNGLEFTHAND; PanelPosition: MIDDLE; FrameDepth: 50 mm; FrameThickness: 50 mm
OverallHeight: 400 mm; OverallWidth: 400 mm; Classification: 1.19 IfcWindow (aken) (_RKAS BIM + ARCHICAD Classification); 564 Põranda katteplaadid, restid, vuugid jm (EHITUSKULUDE LIIGITAMINE EVS 885:2005)
Pset_WindowCommon - ThermalTransmittance: 0; GlazingAreaFraction: 0; IsExternal: yes
Avatäited - 01 Nimetus: Rest; 02 Materjal: Metall; 03 Tähistus: Ventilatsiooni rest 400×400; 04 Avamõõdu geomeetria: 400×400; 05 Asukoha info: Exterior; 06 Soojusläbivus: -; 07 Helipidavus: -; 08 Veepidavus: -; 09 Õhuläbilaskvus: -; 10 Tulekindlus: nõudeid ei esitata; 11 Vastupanu tulekoormusele: -; 12 Klaaspakett: -; 13 Klaasingu erisused: -; 15 Avanemine: Avanemine: "L" (L - vasak; R - parem); 16 Liigendatus: -; 17 Sulused, lukustus: -; 18 Viimistlus: Leng väljast: Metal - Nickel; Leng seest: Metal - Nickel; Raam väljast: Metal - Nickel; Raam seest: Metal - Nickel; Täpsustus: -; 19 Mudel või toote tunnus: Undefined; 20 Tootja: Undefined; 21 Tooteinfo: Undefined; 22 Kasutus- ja hooldusjuhend: Undefined; 14 Päikesekiirgus tegur (g-väärtus): -
AC_Pset_RenovationAndPhasing - Renovation Status: New
